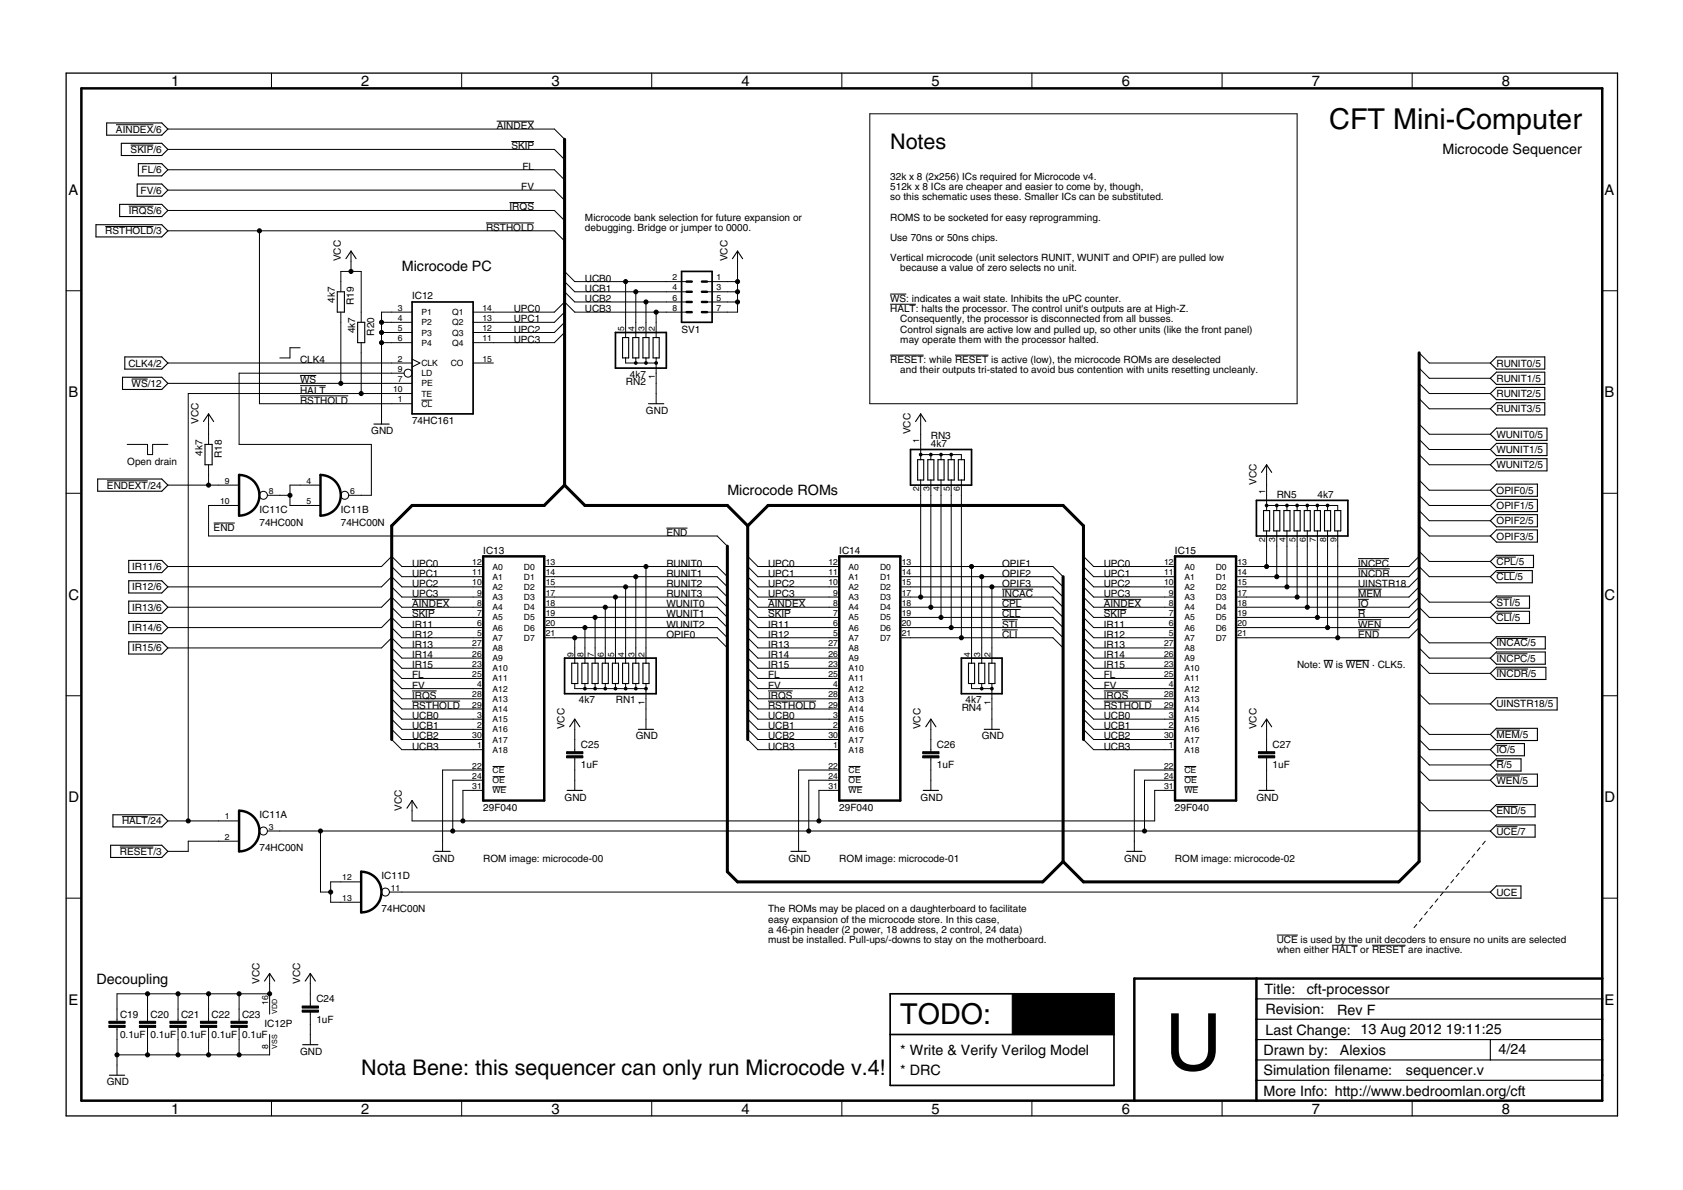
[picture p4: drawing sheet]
<svg xmlns="http://www.w3.org/2000/svg" width="420mm" height="297mm" viewBox="0 0 420 297" stroke-linecap="round" stroke-linejoin="round" font-family="sans-serif">
<defs><g id="words">
<text font-size="19.7" x="290.8" y="267.1">U</text>
<g font-size="7.2">
<text x="331.8" y="32.2">CFT Mini-Computer</text>
<text x="224.8" y="255.7">TODO:</text>
</g>
<g font-size="5.4">
<text x="222.2" y="37.3">Notes</text>
<text x="90.2" y="268.4">Nota Bene: this sequencer can only run Microcode v.4!</text>
</g>
<g font-size="3.7">
<text x="42.7" y="21.5">1</text>
<text x="90.2" y="21.5">2</text>
<text x="137.7" y="21.5">3</text>
<text x="185.1" y="21.5">4</text>
<text x="232.6" y="21.5">5</text>
<text x="280" y="21.5">6</text>
<text x="327.5" y="21.5">7</text>
<text x="375" y="21.5">8</text>
<text x="17.1" y="48.6">A</text>
<text x="400.6" y="48.6">A</text>
<text x="17.1" y="99.2">B</text>
<text x="400.6" y="99.2">B</text>
<text x="17.1" y="149.7">C</text>
<text x="400.6" y="149.7">C</text>
<text x="17.1" y="200.2">D</text>
<text x="400.6" y="200.2">D</text>
<text x="17.1" y="250.8">E</text>
<text x="400.6" y="250.8">E</text>
<text x="42.7" y="277.9">1</text>
<text x="90.2" y="277.9">2</text>
<text x="137.7" y="277.9">3</text>
<text x="185.1" y="277.9">4</text>
<text x="232.6" y="277.9">5</text>
<text x="280" y="277.9">6</text>
<text x="327.5" y="277.9">7</text>
<text x="375" y="277.9">8</text>
</g>
<g font-size="3.6">
<text x="360.1" y="38.6">Microcode Sequencer</text>
<text x="100.3" y="67.8">Microcode PC</text>
<text x="181.6" y="123.6">Microcode ROMs</text>
<text x="24.1" y="245.5">Decoupling</text>
<text x="315.7" y="248.1">Title:</text>
<text x="326.2" y="248.2">cft-processor</text>
<text x="315.9" y="253.2">Revision:</text>
<text x="333.8" y="253.3">Rev F</text>
<text x="224.8" y="263.3">* Write &amp; Verify Verilog Model</text>
<text x="315.4" y="263.3">Drawn by:</text>
<text x="315.9" y="258.2">Last Change: 13 Aug 2012</text>
<text x="334.5" y="263.3">Alexios</text>
<text x="361" y="258.1">19:11:25</text>
<text x="374.1" y="263.2">4/24</text>
<text x="224.8" y="268.4">* DRC</text>
<text x="315.4" y="268.4">Simulation filename:</text>
<text x="351" y="268.4">sequencer.v</text>
<text x="315.4" y="273.5">More Info: http://www.bedroomlan.org/cft</text>
</g>
<g font-size="2.5">
<text x="29" y="33.1">AINDEX/6</text>
<text x="124" y="32.2">AINDEX</text>
<text x="32.6" y="38.2">SKIP/6</text>
<text x="127.7" y="37.3">SKIP</text>
<text x="35.4" y="43.3">FL/6</text>
<text x="130.1" y="47.4">FV</text>
<text x="130.4" y="42.4">FL</text>
<text x="222.2" y="44.9">32k x 8 (2x256) ICs required for Microcode v4.</text>
<text x="222.2" y="47.4">512k x 8 ICs are cheaper and easier to come by, though,</text>
<text x="32.1" y="53.4">IRQS/6</text>
<text x="35.1" y="48.3">FV/6</text>
<text x="127.2" y="52.5">IRQS</text>
<text x="222.2" y="50">so this schematic uses these. Smaller ICs can be substituted.</text>
<text x="26.3" y="58.5">RSTHOLD/3</text>
<text x="121.3" y="57.6">RSTHOLD</text>
<text x="146" y="55.1">Microcode bank selection for future expansion or</text>
<text x="146" y="57.6">debugging. Bridge or jumper to 0000.</text>
<text x="222.2" y="55.1">ROMS to be socketed for easy reprogramming.</text>
<text x="85.1" y="65.2" transform="rotate(-90 85.1 65.2)">VCC</text>
<text x="181.6" y="65.2" transform="rotate(-90 181.6 65.2)">VCC</text>
<text x="222.2" y="60.1">Use 70ns or 50ns chips.</text>
<text x="222.2" y="65.2">Vertical microcode (unit selectors RUNIT, WUNIT and OPIF) are pulled low</text>
<text x="146" y="70.3">UCB0</text>
<text x="224.8" y="67.8">because a value of zero selects no unit.</text>
<text x="83.6" y="75.6" transform="rotate(-90 83.6 75.6)">4k7</text>
<text x="88.4" y="76.2" transform="rotate(-90 88.4 76.2)">R19</text>
<text x="102.9" y="74.7">IC12</text>
<text x="128.3" y="77.9">UPC0</text>
<text x="146" y="72.8">UCB1</text>
<text x="146" y="75.4">UCB2</text>
<text x="146" y="77.9">UCB3</text>
<text x="222.2" y="75.4">WS: indicates a wait state. Inhibits the uPC counter.</text>
<text x="222.2" y="77.9">HALT: halts the processor. The control unit's outputs are at High-Z.</text>
<text x="88.6" y="83.2" transform="rotate(-90 88.6 83.2)">4k7</text>
<text x="93.4" y="83.8" transform="rotate(-90 93.4 83.8)">R20</text>
<text x="128.3" y="80.5">UPC1</text>
<text x="128.3" y="83">UPC2</text>
<text x="170.2" y="83">SV1</text>
<text x="224.8" y="80.5">Consequently, the processor is disconnected from all busses.</text>
<text x="224.8" y="83">Control signals are active low and pulled up, so other units (like the front panel)</text>
<text x="128.3" y="85.5">UPC3</text>
<text x="224.8" y="85.5">may operate them with the processor halted.</text>
<text x="32" y="91.5">CLK4/2</text>
<text x="74.9" y="95.7">WS</text>
<text x="74.9" y="90.6">CLK4</text>
<text x="157.2" y="94.3">4k7</text>
<text x="222.2" y="90.6">RESET: while RESET is active (low), the microcode ROMs are deselected</text>
<text x="224.8" y="93.2">and their outputs tri-stated to avoid bus contention with units resetting uncleanly.</text>
<text x="373.6" y="91.5">RUNIT0/5</text>
<text x="373.6" y="95.3">RUNIT1/5</text>
<text x="32.9" y="96.6">WS/12</text>
<text x="74.9" y="100.8">RSTHOLD</text>
<text x="74.9" y="98.2">HALT</text>
<text x="156.3" y="96.2">RN2</text>
<text x="373.6" y="99.1">RUNIT2/5</text>
<text x="49.5" y="105.9" transform="rotate(-90 49.5 105.9)">VCC</text>
<text x="102.9" y="105.9">74HC161</text>
<text x="161.3" y="103.3">GND</text>
<text x="373.6" y="102.9">RUNIT3/5</text>
<text x="50.5" y="113.7" transform="rotate(-90 50.5 113.7)">4k7</text>
<text x="92.7" y="108.4">GND</text>
<text x="227.3" y="108.4" transform="rotate(-90 227.3 108.4)">VCC</text>
<text x="232.4" y="111.6">4k7</text>
<text x="232.4" y="109.7">RN3</text>
<text x="373.6" y="109.3">WUNIT0/5</text>
<text x="373.6" y="113.1">WUNIT1/5</text>
<text x="31.7" y="116">Open drain</text>
<text x="55.3" y="114.3" transform="rotate(-90 55.3 114.3)">R18</text>
<text x="373.6" y="116.9">WUNIT2/5</text>
<text x="26.7" y="122">ENDEXT/24</text>
<text x="313.7" y="121.1" transform="rotate(-90 313.7 121.1)">VCC</text>
<text x="318.7" y="124.3">RN5</text>
<text x="328.9" y="124.3">4k7</text>
<text x="373.6" y="123.3">OPIF0/5</text>
<text x="64.8" y="131.3">74HC00N</text>
<text x="64.8" y="128.1">IC11C</text>
<text x="85.1" y="131.3">74HC00N</text>
<text x="85.1" y="128.1">IC11B</text>
<text x="373.6" y="127.1">OPIF1/5</text>
<text x="373.6" y="130.9">OPIF2/5</text>
<text x="53.3" y="132.5">END</text>
<text x="166.4" y="133.8">END</text>
<text x="373.6" y="134.7">OPIF3/5</text>
<text x="33" y="142.3">IR11/6</text>
<text x="102.9" y="141.4">UPC0</text>
<text x="102.9" y="144">UPC1</text>
<text x="120.6" y="138.2">IC13</text>
<text x="166.4" y="141.4">RUNIT0</text>
<text x="166.4" y="144">RUNIT1</text>
<text x="191.7" y="141.4">UPC0</text>
<text x="191.7" y="144">UPC1</text>
<text x="209.5" y="138.2">IC14</text>
<text x="250.2" y="141.4">OPIF1</text>
<text x="250.2" y="144">OPIF2</text>
<text x="275.6" y="141.4">UPC0</text>
<text x="275.6" y="144">UPC1</text>
<text x="293.3" y="138.2">IC15</text>
<text x="339.1" y="144">INCDR</text>
<text x="339.1" y="141.4">INCPC</text>
<text x="373.6" y="141">CPL/5</text>
<text x="33" y="147.4">IR12/6</text>
<text x="102.9" y="146.5">UPC2</text>
<text x="102.9" y="149">UPC3</text>
<text x="166.4" y="146.5">RUNIT2</text>
<text x="166.4" y="149">RUNIT3</text>
<text x="191.7" y="146.5">UPC2</text>
<text x="191.7" y="149">UPC3</text>
<text x="250.2" y="149">INCAC</text>
<text x="250.2" y="146.5">OPIF3</text>
<text x="275.6" y="146.5">UPC2</text>
<text x="275.6" y="149">UPC3</text>
<text x="339.1" y="149">MEM</text>
<text x="339.1" y="146.5">UINSTR18</text>
<text x="373.6" y="144.8">CLL/5</text>
<text x="33" y="152.5">IR13/6</text>
<text x="102.9" y="151.6">AINDEX</text>
<text x="102.9" y="154.1">SKIP</text>
<text x="166.4" y="151.6">WUNIT0</text>
<text x="166.4" y="154.1">WUNIT1</text>
<text x="191.7" y="151.6">AINDEX</text>
<text x="191.7" y="154.1">SKIP</text>
<text x="250.2" y="154.1">CLL</text>
<text x="250.2" y="151.6">CPL</text>
<text x="275.6" y="151.6">AINDEX</text>
<text x="275.6" y="154.1">SKIP</text>
<text x="339.1" y="151.6">IO</text>
<text x="339.1" y="154.1">R</text>
<text x="373.6" y="155">CLI/5</text>
<text x="373.6" y="151.2">STI/5</text>
<text x="33" y="157.5">IR14/6</text>
<text x="102.9" y="156.6">IR11</text>
<text x="102.9" y="159.2">IR12</text>
<text x="102.9" y="161.7">IR13</text>
<text x="166.4" y="156.6">WUNIT2</text>
<text x="166.4" y="159.2">OPIF0</text>
<text x="191.7" y="156.6">IR11</text>
<text x="191.7" y="159.2">IR12</text>
<text x="191.7" y="161.7">IR13</text>
<text x="250.2" y="159.2">CLI</text>
<text x="250.2" y="156.6">STI</text>
<text x="275.6" y="156.6">IR11</text>
<text x="275.6" y="159.2">IR12</text>
<text x="275.6" y="161.7">IR13</text>
<text x="339.1" y="156.6">WEN</text>
<text x="339.1" y="159.2">END</text>
<text x="373.6" y="161.3">INCAC/5</text>
<text x="33" y="162.6">IR15/6</text>
<text x="102.9" y="164.3">IR14</text>
<text x="102.9" y="166.8">IR15</text>
<text x="191.7" y="164.3">IR14</text>
<text x="191.7" y="166.8">IR15</text>
<text x="275.6" y="164.3">IR14</text>
<text x="275.6" y="166.8">IR15</text>
<text x="323.8" y="166.8">Note: W is WEN · CLK5.</text>
<text x="373.6" y="165.2">INCPC/5</text>
<text x="102.9" y="171.9">FV</text>
<text x="102.9" y="169.3">FL</text>
<text x="191.7" y="171.9">FV</text>
<text x="191.7" y="169.3">FL</text>
<text x="275.6" y="171.9">FV</text>
<text x="275.6" y="169.3">FL</text>
<text x="373.6" y="169">INCDR/5</text>
<text x="102.9" y="177">RSTHOLD</text>
<text x="102.9" y="174.4">IRQS</text>
<text x="102.9" y="179.5">UCB0</text>
<text x="144.5" y="175.6">4k7</text>
<text x="153.7" y="175.6">RN1</text>
<text x="191.7" y="177">RSTHOLD</text>
<text x="191.7" y="174.4">IRQS</text>
<text x="191.7" y="179.5">UCB0</text>
<text x="240.1" y="177.5">RN4</text>
<text x="241" y="175.6">4k7</text>
<text x="275.6" y="177">RSTHOLD</text>
<text x="275.6" y="174.4">IRQS</text>
<text x="275.6" y="179.5">UCB0</text>
<text x="373.6" y="176.6">UINSTR18/5</text>
<text x="102.9" y="182">UCB1</text>
<text x="102.9" y="184.6">UCB2</text>
<text x="141" y="182" transform="rotate(-90 141 182)">VCC</text>
<text x="158.7" y="184.6">GND</text>
<text x="191.7" y="182">UCB1</text>
<text x="191.7" y="184.6">UCB2</text>
<text x="229.8" y="182" transform="rotate(-90 229.8 182)">VCC</text>
<text x="245.1" y="184.6">GND</text>
<text x="275.6" y="182">UCB1</text>
<text x="275.6" y="184.6">UCB2</text>
<text x="313.7" y="182" transform="rotate(-90 313.7 182)">VCC</text>
<text x="373.6" y="184.2">MEM/5</text>
<text x="102.9" y="187.1">UCB3</text>
<text x="145" y="191.8">1uF</text>
<text x="145" y="186.7">C25</text>
<text x="191.7" y="187.1">UCB3</text>
<text x="233.9" y="191.8">1uF</text>
<text x="233.9" y="186.7">C26</text>
<text x="275.6" y="187.1">UCB3</text>
<text x="317.7" y="191.8">1uF</text>
<text x="317.7" y="186.7">C27</text>
<text x="373.6" y="188">IO/5</text>
<text x="373.6" y="191.8">R/5</text>
<text x="373.6" y="195.6">WEN/5</text>
<text x="100.3" y="202.4" transform="rotate(-90 100.3 202.4)">VCC</text>
<text x="120.6" y="202.4">29F040</text>
<text x="141" y="199.8">GND</text>
<text x="209.5" y="202.4">29F040</text>
<text x="229.8" y="199.8">GND</text>
<text x="293.3" y="202.4">29F040</text>
<text x="313.7" y="199.8">GND</text>
<text x="373.6" y="203.2">END/5</text>
<text x="30.5" y="205.8">HALT/24</text>
<text x="64.8" y="204.3">IC11A</text>
<text x="373.6" y="208.3">UCE/7</text>
<text x="29.9" y="213.4">RESET/3</text>
<text x="64.8" y="212.5">74HC00N</text>
<text x="107.9" y="215.1">GND</text>
<text x="120.6" y="215.1">ROM image: microcode-00</text>
<text x="196.8" y="215.1">GND</text>
<text x="209.5" y="215.1">ROM image: microcode-01</text>
<text x="280.6" y="215.1">GND</text>
<text x="293.3" y="215.1">ROM image: microcode-02</text>
<text x="95.2" y="219.5">IC11D</text>
<text x="95.2" y="227.8">74HC00N</text>
<text x="191.7" y="227.8">The ROMs may be placed on a daughterboard to facilitate</text>
<text x="373.6" y="223.6">UCE</text>
<text x="191.7" y="230.3">easy expansion of the microcode store. In this case,</text>
<text x="191.7" y="232.8">a 46-pin header (2 power, 18 address, 2 control, 24 data)</text>
<text x="191.7" y="235.4">must be installed. Pull-ups/-downs to stay on the motherboard.</text>
<text x="318.7" y="235.4">UCE is used by the unit decoders to ensure no units are selected</text>
<text x="318.7" y="237.9">when either HALT or RESET are inactive.</text>
<text x="64.8" y="245.5" transform="rotate(-90 64.8 245.5)">VCC</text>
<text x="74.9" y="245.5" transform="rotate(-90 74.9 245.5)">VCC</text>
<text x="79" y="250.2">C24</text>
<text x="30" y="254">C19</text>
<text x="37.6" y="254">C20</text>
<text x="45.2" y="254">C21</text>
<text x="52.8" y="254">C22</text>
<text x="60.4" y="254">C23</text>
<text x="66" y="256.3">IC12P</text>
<text x="79" y="255.3">1uF</text>
<text x="30" y="259.1">0.1uF</text>
<text x="37.6" y="259.1">0.1uF</text>
<text x="45.2" y="259.1">0.1uF</text>
<text x="52.8" y="259.1">0.1uF</text>
<text x="60.4" y="259.1">0.1uF</text>
<text x="74.9" y="263.3">GND</text>
<text x="26.7" y="270.9">GND</text>
</g>
<g font-size="2.1">
<text x="167.9" y="69.9">2</text>
<text x="178.8" y="69.9">1</text>
<text x="99.3" y="77.6">3</text>
<text x="120.4" y="77.6">14</text>
<text x="167.9" y="72.5">4</text>
<text x="167.9" y="75">6</text>
<text x="167.9" y="77.6">8</text>
<text x="178.8" y="72.5">3</text>
<text x="178.8" y="75">5</text>
<text x="178.8" y="77.6">7</text>
<text x="99.3" y="80.1">4</text>
<text x="99.3" y="82.6">5</text>
<text x="105.2" y="78.7">P1</text>
<text x="105.2" y="81.2">P2</text>
<text x="105.2" y="83.8">P3</text>
<text x="112.9" y="83.8">Q3</text>
<text x="112.9" y="81.2">Q2</text>
<text x="112.9" y="78.7">Q1</text>
<text x="120.4" y="82.6">12</text>
<text x="120.4" y="80.1">13</text>
<text x="155.8" y="82.6" transform="rotate(-90 155.8 82.6)">5</text>
<text x="158.4" y="82.6" transform="rotate(-90 158.4 82.6)">4</text>
<text x="160.9" y="82.6" transform="rotate(-90 160.9 82.6)">3</text>
<text x="163.5" y="82.6" transform="rotate(-90 163.5 82.6)">2</text>
<text x="99.3" y="85.2">6</text>
<text x="105.2" y="86.3">P4</text>
<text x="112.9" y="86.3">Q4</text>
<text x="120.4" y="85.2">11</text>
<text x="99.3" y="90.3">2</text>
<text x="99.3" y="95.3">7</text>
<text x="99.3" y="92.8">9</text>
<text x="105.2" y="91.4">CLK</text>
<text x="105.2" y="93.9">LD</text>
<text x="112.6" y="91.4">CO</text>
<text x="120.4" y="90.3">15</text>
<text x="163.5" y="94.7" transform="rotate(-90 163.5 94.7)">1</text>
<text x="98.2" y="97.9">10</text>
<text x="99.3" y="100.4">1</text>
<text x="105.2" y="101.5">CL</text>
<text x="105.2" y="96.5">PE</text>
<text x="105.2" y="99">TE</text>
<text x="229.5" y="110.6" transform="rotate(-90 229.5 110.6)">1</text>
<text x="55" y="125.8">10</text>
<text x="56.2" y="120.7">9</text>
<text x="67.1" y="123.3">8</text>
<text x="76.5" y="120.7">4</text>
<text x="76.5" y="125.8">5</text>
<text x="87.4" y="123.3">6</text>
<text x="229.5" y="122.6" transform="rotate(-90 229.5 122.6)">2</text>
<text x="232" y="122.6" transform="rotate(-90 232 122.6)">3</text>
<text x="234.6" y="122.6" transform="rotate(-90 234.6 122.6)">4</text>
<text x="237.1" y="122.6" transform="rotate(-90 237.1 122.6)">5</text>
<text x="239.6" y="122.6" transform="rotate(-90 239.6 122.6)">6</text>
<text x="315.8" y="123.3" transform="rotate(-90 315.8 123.3)">1</text>
<text x="315.8" y="135.3" transform="rotate(-90 315.8 135.3)">2</text>
<text x="318.4" y="135.3" transform="rotate(-90 318.4 135.3)">3</text>
<text x="320.9" y="135.3" transform="rotate(-90 320.9 135.3)">4</text>
<text x="323.5" y="135.3" transform="rotate(-90 323.5 135.3)">5</text>
<text x="326" y="135.3" transform="rotate(-90 326 135.3)">6</text>
<text x="328.5" y="135.3" transform="rotate(-90 328.5 135.3)">7</text>
<text x="331.1" y="135.3" transform="rotate(-90 331.1 135.3)">8</text>
<text x="333.6" y="135.3" transform="rotate(-90 333.6 135.3)">9</text>
<text x="117.9" y="143.6">11</text>
<text x="117.9" y="141.1">12</text>
<text x="123" y="142.2">A0</text>
<text x="130.8" y="142.2">D0</text>
<text x="136.2" y="141.1">13</text>
<text x="136.2" y="143.6">14</text>
<text x="206.8" y="143.6">11</text>
<text x="206.8" y="141.1">12</text>
<text x="211.9" y="142.2">A0</text>
<text x="219.7" y="142.2">D0</text>
<text x="225.1" y="141.1">13</text>
<text x="225.1" y="143.6">14</text>
<text x="290.6" y="143.6">11</text>
<text x="290.6" y="141.1">12</text>
<text x="295.7" y="142.2">A0</text>
<text x="303.5" y="142.2">D0</text>
<text x="308.9" y="141.1">13</text>
<text x="308.9" y="143.6">14</text>
<text x="117.9" y="146.1">10</text>
<text x="119.1" y="148.7">9</text>
<text x="123" y="149.8">A3</text>
<text x="123" y="147.3">A2</text>
<text x="123" y="144.7">A1</text>
<text x="130.8" y="144.7">D1</text>
<text x="130.8" y="147.3">D2</text>
<text x="130.8" y="149.8">D3</text>
<text x="136.2" y="146.1">15</text>
<text x="136.2" y="148.7">17</text>
<text x="206.8" y="146.1">10</text>
<text x="208" y="148.7">9</text>
<text x="211.9" y="149.8">A3</text>
<text x="211.9" y="147.3">A2</text>
<text x="211.9" y="144.7">A1</text>
<text x="219.7" y="144.7">D1</text>
<text x="219.7" y="147.3">D2</text>
<text x="219.7" y="149.8">D3</text>
<text x="225.1" y="146.1">15</text>
<text x="225.1" y="148.7">17</text>
<text x="290.6" y="146.1">10</text>
<text x="291.8" y="148.7">9</text>
<text x="295.7" y="149.8">A3</text>
<text x="295.7" y="147.3">A2</text>
<text x="295.7" y="144.7">A1</text>
<text x="303.5" y="144.7">D1</text>
<text x="303.5" y="147.3">D2</text>
<text x="303.5" y="149.8">D3</text>
<text x="308.9" y="146.1">15</text>
<text x="308.9" y="148.7">17</text>
<text x="119.1" y="153.8">7</text>
<text x="119.1" y="151.2">8</text>
<text x="123" y="154.9">A5</text>
<text x="123" y="152.3">A4</text>
<text x="130.8" y="152.3">D4</text>
<text x="130.8" y="154.9">D5</text>
<text x="136.2" y="151.2">18</text>
<text x="136.2" y="153.8">19</text>
<text x="208" y="153.8">7</text>
<text x="208" y="151.2">8</text>
<text x="211.9" y="154.9">A5</text>
<text x="211.9" y="152.3">A4</text>
<text x="219.7" y="152.3">D4</text>
<text x="219.7" y="154.9">D5</text>
<text x="225.1" y="151.2">18</text>
<text x="225.1" y="153.8">19</text>
<text x="291.8" y="153.8">7</text>
<text x="291.8" y="151.2">8</text>
<text x="295.7" y="154.9">A5</text>
<text x="295.7" y="152.3">A4</text>
<text x="303.5" y="152.3">D4</text>
<text x="303.5" y="154.9">D5</text>
<text x="308.9" y="151.2">18</text>
<text x="308.9" y="153.8">19</text>
<text x="117.9" y="161.4">27</text>
<text x="119.1" y="158.8">5</text>
<text x="119.1" y="156.3">6</text>
<text x="123" y="159.9">A7</text>
<text x="123" y="157.4">A6</text>
<text x="130.8" y="157.4">D6</text>
<text x="130.8" y="160">D7</text>
<text x="136.2" y="156.3">20</text>
<text x="136.2" y="158.8">21</text>
<text x="206.8" y="161.4">27</text>
<text x="208" y="158.8">5</text>
<text x="208" y="156.3">6</text>
<text x="211.9" y="159.9">A7</text>
<text x="211.9" y="157.4">A6</text>
<text x="219.7" y="157.4">D6</text>
<text x="219.7" y="160">D7</text>
<text x="225.1" y="156.3">20</text>
<text x="225.1" y="158.8">21</text>
<text x="290.6" y="161.4">27</text>
<text x="291.8" y="158.8">5</text>
<text x="291.8" y="156.3">6</text>
<text x="295.7" y="159.9">A7</text>
<text x="295.7" y="157.4">A6</text>
<text x="303.5" y="157.4">D6</text>
<text x="303.5" y="160">D7</text>
<text x="308.9" y="156.3">20</text>
<text x="308.9" y="158.8">21</text>
<text x="117.9" y="166.5">23</text>
<text x="117.9" y="163.9">26</text>
<text x="123" y="167.6">A10</text>
<text x="123" y="165">A9</text>
<text x="123" y="162.5">A8</text>
<text x="143.1" y="163.9" transform="rotate(-90 143.1 163.9)">9</text>
<text x="145.7" y="163.9" transform="rotate(-90 145.7 163.9)">8</text>
<text x="148.2" y="163.9" transform="rotate(-90 148.2 163.9)">7</text>
<text x="150.8" y="163.9" transform="rotate(-90 150.8 163.9)">6</text>
<text x="153.3" y="163.9" transform="rotate(-90 153.3 163.9)">5</text>
<text x="155.8" y="163.9" transform="rotate(-90 155.8 163.9)">4</text>
<text x="158.4" y="163.9" transform="rotate(-90 158.4 163.9)">3</text>
<text x="160.9" y="163.9" transform="rotate(-90 160.9 163.9)">2</text>
<text x="206.8" y="166.5">23</text>
<text x="206.8" y="163.9">26</text>
<text x="211.9" y="167.6">A10</text>
<text x="211.9" y="165">A9</text>
<text x="211.9" y="162.5">A8</text>
<text x="242.2" y="163.9" transform="rotate(-90 242.2 163.9)">4</text>
<text x="244.7" y="163.9" transform="rotate(-90 244.7 163.9)">3</text>
<text x="247.3" y="163.9" transform="rotate(-90 247.3 163.9)">2</text>
<text x="290.6" y="166.5">23</text>
<text x="290.6" y="163.9">26</text>
<text x="295.7" y="167.6">A10</text>
<text x="295.7" y="165">A9</text>
<text x="295.7" y="162.5">A8</text>
<text x="117.9" y="169">25</text>
<text x="119.1" y="171.5">4</text>
<text x="123" y="172.6">A12</text>
<text x="123" y="170.1">A11</text>
<text x="206.8" y="169">25</text>
<text x="208" y="171.5">4</text>
<text x="211.9" y="172.6">A12</text>
<text x="211.9" y="170.1">A11</text>
<text x="290.6" y="169">25</text>
<text x="291.8" y="171.5">4</text>
<text x="295.7" y="172.6">A12</text>
<text x="295.7" y="170.1">A11</text>
<text x="117.9" y="174.1">28</text>
<text x="117.9" y="176.6">29</text>
<text x="119.1" y="179.1">3</text>
<text x="123" y="175.2">A13</text>
<text x="123" y="177.7">A14</text>
<text x="160.9" y="176" transform="rotate(-90 160.9 176)">1</text>
<text x="206.8" y="174.1">28</text>
<text x="206.8" y="176.6">29</text>
<text x="208" y="179.1">3</text>
<text x="211.9" y="175.2">A13</text>
<text x="211.9" y="177.7">A14</text>
<text x="247.3" y="176" transform="rotate(-90 247.3 176)">1</text>
<text x="290.6" y="174.1">28</text>
<text x="290.6" y="176.6">29</text>
<text x="291.8" y="179.1">3</text>
<text x="295.7" y="175.2">A13</text>
<text x="295.7" y="177.7">A14</text>
<text x="117.9" y="184.2">30</text>
<text x="119.1" y="181.7">2</text>
<text x="123" y="180.3">A15</text>
<text x="123" y="182.8">A16</text>
<text x="123" y="185.3">A17</text>
<text x="206.8" y="184.2">30</text>
<text x="208" y="181.7">2</text>
<text x="211.9" y="180.3">A15</text>
<text x="211.9" y="182.8">A16</text>
<text x="211.9" y="185.3">A17</text>
<text x="290.6" y="184.2">30</text>
<text x="291.8" y="181.7">2</text>
<text x="295.7" y="180.3">A15</text>
<text x="295.7" y="182.8">A16</text>
<text x="295.7" y="185.3">A17</text>
<text x="117.9" y="191.8">22</text>
<text x="119.1" y="186.8">1</text>
<text x="123" y="187.9">A18</text>
<text x="206.8" y="191.8">22</text>
<text x="208" y="186.8">1</text>
<text x="211.9" y="187.9">A18</text>
<text x="290.6" y="191.8">22</text>
<text x="291.8" y="186.8">1</text>
<text x="295.7" y="187.9">A18</text>
<text x="117.9" y="196.9">31</text>
<text x="117.9" y="194.4">24</text>
<text x="123" y="193">CE</text>
<text x="123" y="195.5">OE</text>
<text x="206.8" y="196.9">31</text>
<text x="206.8" y="194.4">24</text>
<text x="211.9" y="193">CE</text>
<text x="211.9" y="195.5">OE</text>
<text x="290.6" y="196.9">31</text>
<text x="290.6" y="194.4">24</text>
<text x="295.7" y="193">CE</text>
<text x="295.7" y="195.5">OE</text>
<text x="123" y="198">WE</text>
<text x="211.9" y="198">WE</text>
<text x="295.7" y="198">WE</text>
<text x="56.2" y="204.5">1</text>
<text x="56.2" y="209.6">2</text>
<text x="67.1" y="207.1">3</text>
<text x="85.5" y="219.8">12</text>
<text x="85.5" y="224.9">13</text>
<text x="97.6" y="222.3">11</text>
<text x="66.9" y="250.8" transform="rotate(-90 66.9 250.8)">16</text>
<text x="66.9" y="261.8" transform="rotate(-90 66.9 261.8)">8</text>
</g>
<g font-size="1.8">
<text x="69.2" y="253.2" transform="rotate(-90 69.2 253.2)">VDD</text>
<text x="69.2" y="261.8" transform="rotate(-90 69.2 261.8)">VSS</text>
</g>
</g></defs>
<g fill="#000" stroke="#000" stroke-width=".25">
<path d="M67.8 18.2v3.9zM115.3 18.2v3.9zM162.7 18.2v3.9zM210.2 18.2v3.9zM257.6 18.2v3.9zM305.1 18.2v3.9zM352.5 18.2v3.9zM20.3 22.1v252.6zM29 31.1h9.3zM32.6 36.2h5.7zM124 30.2h9.3zM127.7 35.3h5.6z"/>
<path d="M41.9 32.2h96.5zM41.9 37.3h96.5zM138.4 32.2l2.5 2.6zM138.4 37.3l2.5 2.5zM217.1 28.4v72.4zM217.1 28.4h106.7zM20.3 22.1h379.7zM26.3 56.5h12zM32.2 51.5h6.1zM41.9 57.6h22.9zM64.8 57.6v43.2zM121.3 55.6h12z"/>
<path d="M127.2 50.6h6.1zM64.8 57.6h73.6zM41.9 52.5h96.5zM41.9 47.5h96.5zM41.9 42.4h96.5zM138.4 52.5l2.5 2.6zM138.4 47.5l2.5 2.5zM138.4 42.4l2.5 2.5zM16.5 72.6h3.8zM85.1 70.3v2.5zM85.1 67.8v2.5zM85.1 67.8h2.5z"/>
<path d="M87.6 62.7v2.5zM87.6 67.8h2.6zM87.6 65.2v2.6zM90.2 77.9v2.6zM90.2 67.8v10.1zM95.2 77.9v2.6zM97.8 77.9h5.1zM95.2 77.9h2.6zM118.1 77.9h5.1zM123.2 77.9h15.2zM140.9 75.4l-2.5 2.5zM138.4 57.6l2.5 2.6z"/>
<path d="M140.9 67.8l2.6 2.5zM140.9 70.3l2.6 2.5zM140.9 72.8l2.6 2.6zM140.9 75.4l2.6 2.5zM143.5 70.3h12.7zM143.5 72.8h15.2zM143.5 75.4h17.8zM143.5 77.9h20.3zM156.2 70.3h10.1zM158.7 72.8h7.6zM161.3 75.4h5zM163.8 77.9h2.5z"/>
<path d="M166.3 70.3h5.1zM166.3 72.8h5.1zM166.3 75.4h5.1zM166.3 77.9h5.1zM176.5 70.3h5.1zM176.5 72.8h5.1zM176.5 75.4h5.1zM176.5 77.9h5.1zM181.6 70.3h2.5zM181.6 72.8h2.5zM181.6 75.4h2.5zM181.6 77.9h2.5z"/>
<path d="M184.1 62.7v2.5zM184.1 70.3v2.5zM184.1 72.8v2.6zM184.1 75.4v2.5zM184.1 65.2v5.1zM222.2 73.4h4zM222.2 75.9h6.4zM400 72.6h3.8zM32.9 94.6h4zM47 98.2v106.7zM69.8 89.3h2.6zM72.4 86.8v2.5z"/>
<path d="M72.4 86.8h2.5zM74.9 98.8h12zM74.9 96.3h6.4zM74.9 93.7h4.1zM85.1 77.9v2.6zM85.1 80.5v15.2zM41.9 95.7h43.2zM90.2 85.5v2.6zM90.2 88.1v10.1zM47 98.2h43.2zM95.2 80.5v2.5zM95.2 83v2.5z"/>
<path d="M95.2 85.5v17.8zM97.8 90.6h5.1zM97.8 80.5h5.1zM97.8 83h5.1zM97.8 85.5h5.1zM97.8 95.7h5.1zM97.8 93.2h3.1zM97.8 98.2h5.1zM95.2 80.5h2.6zM95.2 83h2.6zM95.2 85.5h2.6zM90.2 98.2h7.6z"/>
<path d="M85.1 95.7h12.7zM59.7 93.2h38.1zM41.9 90.6h55.9zM102.9 89.6l1.9 1zM102.9 91.6l1.9-1zM105.2 99.9h2.7zM118.1 85.5h5.1zM118.1 83h5.1zM118.1 80.5h5.1zM118.1 90.6h5.1zM123.2 80.5h15.2zM123.2 83h15.2z"/>
<path d="M123.2 85.5h15.2zM138.4 80.5l2.5-2.6zM138.4 83l2.5-2.5zM140.9 83l-2.5 2.5zM156.2 80.5v2.5zM156.2 89.3v1.3zM156.2 83v1.3zM156.2 70.3v10.2zM158.7 80.5v2.5zM158.7 89.3v1.3zM156.2 90.6h2.5zM158.7 83v1.3z"/>
<path d="M158.7 72.8v7.7zM161.3 80.5v2.5zM161.3 89.3v1.3zM158.7 90.6h2.6zM161.3 83v1.3zM161.3 75.4v5.1zM163.8 93.2v2.5zM163.8 80.5v2.5zM163.8 83v1.3zM163.8 89.3v1.3zM161.3 90.6h2.5zM163.8 90.6v2.6z"/>
<path d="M163.8 98.2v2.6zM163.8 95.7v2.5zM163.8 77.9v2.6zM222.2 88.6h8.4zM238.4 88.6h8.4zM354.3 88.1l2.5 2.5zM354.3 91.9l2.5 2.5zM354.3 95.7l2.5 2.5zM354.3 99.5l2.5 2.5zM356.8 90.6h15.3zM356.8 94.4h15.3zM356.8 98.2h15.3z"/>
<path d="M31.7 110.9h5.1zM36.8 110.9v2.6zM36.8 113.5h1.3zM38.1 110.9v2.6zM38.1 110.9h3.8zM52.1 103.3v2.6zM52.1 116v2.6zM52.1 108.4v2.5zM52.1 105.9v2.5zM52.1 118.6v2.5zM59.7 93.2v17.7zM59.7 110.9h33z"/>
<path d="M95.2 103.3v2.6zM97.8 100.8h5.1zM64.8 100.8h33zM217.1 100.8h106.7zM229.8 108.4v2.5zM229.8 119.8v1.3zM229.8 113.5v1.2zM229.8 113.5h2.6zM229.8 110.9v2.6zM229.8 103.3v2.6zM229.8 105.9v2.5zM232.4 113.5v1.2z"/>
<path d="M232.4 113.5h2.5zM234.9 113.5v1.2zM234.9 113.5h2.6zM237.5 113.5v1.2zM237.5 113.5h2.5zM240 113.5v1.2zM316.2 116v2.6zM316.2 118.6v2.5zM323.8 28.4v72.4zM354.3 105.9l2.5 2.5zM354.3 109.7l2.5 2.5zM354.3 113.5l2.5 2.5z"/>
<path d="M354.3 119.8l2.5 2.6zM356.8 102h15.3zM356.8 108.4h15.3zM356.8 112.2h15.3zM356.8 116h15.3zM16.5 123.1h3.8zM26.7 120h10.2zM52.1 133.8h126.9zM52.1 126.2v7.6zM52.1 126.2h2.5zM41.9 121.1h10.2zM53.3 130.6h5.3z"/>
<path d="M54.6 121.1h5.1zM54.6 126.2h5.1zM52.1 121.1h2.5zM66.7 123.6h3.1zM69.8 123.6h2.6zM72.4 121.1v2.5zM72.4 123.6v2.6zM72.4 126.2h2.5zM74.9 121.1h5.1zM74.9 126.2h5.1zM72.4 121.1h2.5zM87.1 123.6h3.1z"/>
<path d="M90.2 123.6h2.5zM92.7 110.9v12.7zM97.8 138.9l-2.6 2.5zM97.8 138.9l2.5 2.5zM166.3 131.8h5.3zM179 133.8l2.6 2.5zM186.7 138.9l2.5 2.5zM229.8 121.1v2.5zM229.8 123.6v25.4zM232.4 121.1v2.5zM232.4 119.8v1.3zM232.4 123.6v28z"/>
<path d="M234.9 121.1v2.5zM234.9 119.8v1.3zM234.9 123.6v30.5zM237.5 121.1v2.5zM237.5 119.8v1.3zM237.5 123.6v33.1zM240 121.1v2.5zM240 119.8v1.3zM240 123.6v35.6zM270.5 138.9l2.5 2.5zM316.2 121.1v2.5zM316.2 133.8v2.5z"/>
<path d="M316.2 132.5v1.3zM316.2 126.2v1.2zM316.2 126.2h2.5zM316.2 123.6v2.6zM316.2 136.3v5.1zM318.7 133.8v2.5zM318.7 126.2v1.2zM318.7 126.2h2.6zM318.7 132.5v1.3zM318.7 136.3v7.7zM321.3 133.8v2.5zM321.3 126.2v1.2z"/>
<path d="M321.3 126.2h2.5zM321.3 132.5v1.3zM321.3 136.3v10.2zM323.8 133.8v2.5zM323.8 126.2v1.2zM323.8 126.2h2.6zM323.8 132.5v1.3zM323.8 136.3v12.7zM326.4 133.8v2.5zM326.4 126.2v1.2zM326.4 132.5v1.3zM326.4 126.2h2.5z"/>
<path d="M326.4 136.3v15.3zM328.9 133.8v2.5zM328.9 132.5v1.3zM328.9 126.2v1.2zM328.9 126.2h2.5zM328.9 136.3v17.8zM331.4 133.8v2.5zM331.4 126.2v1.2zM331.4 126.2h2.6zM331.4 132.5v1.3zM331.4 136.3v20.4zM334 133.8v2.5z"/>
<path d="M334 126.2v1.2zM334 132.5v1.3zM334 136.3v22.9zM339 139.4h7.8zM354.3 138.9l-2.6 2.5zM354.3 137.6l2.5 2.5zM354.3 123.6l2.5 2.6zM354.3 127.4l2.5 2.6zM354.3 131.3l2.5 2.5zM356.8 122.4h15.3zM356.8 126.2h15.3zM356.8 130h15.3z"/>
<path d="M356.8 133.8h15.3zM373.6 139.1h4.8zM400 123.1h3.8zM41.9 146.5h53.3zM41.9 151.6h53.3zM41.9 156.7h53.3zM41.9 141.4h53.3zM95.2 146.5l2.6-2.5zM95.2 151.6l2.6-2.6zM97.8 154.1l-2.6 2.6zM97.8 149l2.5 2.6zM97.8 151.6l2.5 2.5z"/>
<path d="M97.8 154.1l2.5 2.6zM97.8 156.7l2.5 2.5zM97.8 159.2l2.5 2.5zM97.8 141.4l2.5 2.6zM97.8 144l2.5 2.5zM97.8 146.5l2.5 2.5zM100.3 151.6h17.8zM100.3 154.1h17.8zM100.3 156.7h17.8zM100.3 159.2h17.8zM100.3 141.4h17.8zM100.3 144h17.8z"/>
<path d="M100.3 146.5h17.8zM100.3 149h17.8zM102.9 149.6h9.3zM102.9 152.1h5.6zM118.1 159.2h2.5zM118.1 156.7h2.5zM118.1 154.1h2.5zM118.1 151.6h2.5zM118.1 149h2.5zM118.1 146.5h2.5zM118.1 144h2.5zM118.1 141.4h2.5z"/>
<path d="M135.9 141.4h2.5zM135.9 144h2.5zM135.9 146.5h2.5zM135.9 149h2.5zM135.9 151.6h2.5zM135.9 154.1h2.5zM135.9 156.7h2.5zM135.9 159.2h2.5zM138.4 141.4h22.9zM138.4 144h20.3zM138.4 146.5h17.8zM138.4 149h15.2z"/>
<path d="M138.4 151.6h12.7zM138.4 154.1h10.2zM138.4 156.7h7.6zM138.4 159.2h5.1zM143.5 159.2h35.5zM146 156.7h33zM148.6 154.1h30.4zM151.1 151.6h27.9zM158.7 144h20.3zM161.3 141.4h17.7zM156.2 146.5h22.8zM153.6 149h25.4z"/>
<path d="M179 141.4l2.6 2.6zM179 144l2.6 2.5zM179 146.5l2.6 2.5zM179 149l2.6 2.6zM179 151.6l2.6 2.5zM179 154.1l2.6 2.6zM179 156.7l2.6 2.5zM186.7 149l2.5 2.6zM186.7 151.6l2.5 2.5zM186.7 154.1l2.5 2.6zM186.7 156.7l2.5 2.5zM186.7 159.2l2.5 2.5z"/>
<path d="M186.7 141.4l2.5 2.6zM186.7 144l2.5 2.5zM186.7 146.5l2.5 2.5zM189.2 151.6h17.8zM189.2 154.1h17.8zM189.2 156.7h17.8zM189.2 159.2h17.8zM189.2 141.4h17.8zM189.2 144h17.8zM189.2 146.5h17.8zM189.2 149h17.8zM191.7 149.6h9.4z"/>
<path d="M191.7 152.1h5.7zM207 159.2h2.5zM207 156.7h2.5zM207 154.1h2.5zM207 151.6h2.5zM207 149h2.5zM207 146.5h2.5zM207 144h2.5zM207 141.4h2.5zM224.8 141.4h2.5zM224.8 144h2.5zM224.8 146.5h2.5z"/>
<path d="M224.8 149h2.5zM224.8 151.6h2.5zM224.8 154.1h2.5zM224.8 156.7h2.5zM224.8 159.2h2.5zM227.3 159.2h12.7zM227.3 149h2.5zM227.3 151.6h5.1zM227.3 154.1h7.6zM227.3 156.7h10.2zM240 159.2h22.9zM227.3 141.4h15.2z"/>
<path d="M227.3 144h17.8zM227.3 146.5h20.3zM250.2 157.2h3.9zM250.2 154.7h3.9zM250.2 152.1h4.6zM250.2 149.6h4.8zM250.2 147.1h7.7zM237.5 156.7h25.4zM234.9 154.1h28zM232.4 151.6h30.5zM229.8 149h33.1zM242.5 141.4h20.4z"/>
<path d="M245.1 144h17.8zM247.6 146.5h15.3zM262.9 156.7l2.5 2.5zM262.9 154.1l2.5 2.6zM262.9 151.6l2.5 2.5zM262.9 149l2.5 2.6zM262.9 141.4l2.5 2.6zM262.9 144l2.5 2.5zM262.9 146.5l2.5 2.5zM270.5 149l2.5 2.6zM270.5 151.6l2.5 2.5zM270.5 154.1l2.5 2.6z"/>
<path d="M270.5 156.7l2.5 2.5zM270.5 159.2l2.5 2.5zM270.5 141.4l2.5 2.6zM270.5 144l2.5 2.5zM270.5 146.5l2.5 2.5zM273 151.6h17.8zM273 154.1h17.8zM273 156.7h17.8zM273 159.2h17.8zM273 141.4h17.8zM273 144h17.8zM273 146.5h17.8z"/>
<path d="M273 149h17.8zM275.6 149.6h9.3zM275.6 152.1h5.6zM290.8 159.2h2.5zM290.8 156.7h2.5zM290.8 154.1h2.5zM290.8 151.6h2.5zM290.8 149h2.5zM290.8 146.5h2.5zM290.8 144h2.5zM290.8 141.4h2.5zM308.6 141.4h2.5z"/>
<path d="M308.6 144h2.5zM308.6 146.5h2.5zM308.6 149h2.5zM308.6 151.6h2.5zM308.6 154.1h2.5zM308.6 156.7h2.5zM308.6 159.2h2.5zM311.1 149h12.7zM311.1 151.6h15.3zM311.1 154.1h17.8zM311.1 156.7h20.3zM311.1 144h7.6z"/>
<path d="M311.1 141.4h5.1zM311.1 146.5h10.2zM311.1 159.2h22.9zM316.2 141.4h35.5zM318.7 144h33zM321.3 146.5h30.4zM339 147.1h5.9zM339 149.6h2.7zM339 152.1h1.8zM339 154.7h5.9zM339 142h8zM339 157.2h5.3z"/>
<path d="M323.8 149h27.9zM326.4 151.6h25.3zM328.9 154.1h22.8zM331.4 156.7h20.3zM334 159.2h17.7zM354.3 146.5l-2.6 2.5zM354.3 149l-2.6 2.6zM351.7 154.1l2.6-2.5zM354.3 154.1l-2.6 2.6zM354.3 141.4l-2.6 2.6zM354.3 151.6l2.5 2.5zM354.3 147.8l2.5 2.5z"/>
<path d="M354.3 141.4l2.5 2.6zM354.3 157.9l2.5 2.6zM351.7 146.5l2.6-2.5zM354.3 156.7l-2.6 2.5zM356.8 154.1h15.3zM356.8 150.3h15.3zM356.8 144h15.3zM356.8 140.1h15.3zM373.6 153h3.9zM373.6 149.2h3.9zM373.6 142.9h4.6zM373.6 159.4h7.8z"/>
<path d="M16.5 173.7h3.8zM41.9 161.7h53.3zM95.2 161.7l2.6-2.5zM97.8 174.4l2.5 2.6zM97.8 171.9l2.5 2.5zM97.8 161.7l2.5 2.6zM97.8 164.3l2.5 2.5zM97.8 169.4l2.5 2.5zM97.8 166.8l2.5 2.6zM97.8 177l2.5 2.5zM97.8 179.5l2.5 2.6zM100.3 177h17.8z"/>
<path d="M100.3 174.4h17.8zM100.3 161.7h17.8zM100.3 164.3h17.8zM100.3 166.8h17.8zM100.3 171.9h17.8zM100.3 169.4h17.8zM100.3 179.5h17.8zM102.9 175h12zM102.9 172.5h6.1zM118.1 171.9h2.5zM118.1 166.8h2.5zM118.1 169.4h2.5z"/>
<path d="M118.1 164.3h2.5zM118.1 161.7h2.5zM118.1 174.4h2.5zM118.1 177h2.5zM118.1 179.5h2.5zM143.5 161.7v2.6zM143.5 170.6v1.3zM143.5 164.3v1.2zM143.5 159.2v2.5zM146 161.7v2.6zM146 170.6v1.3zM143.5 171.9h2.5z"/>
<path d="M146 164.3v1.2zM146 156.7v5zM148.6 161.7v2.6zM148.6 164.3v1.2zM148.6 170.6v1.3zM146 171.9h2.6zM148.6 154.1v7.6zM151.1 161.7v2.6zM151.1 170.6v1.3zM151.1 164.3v1.2zM148.6 171.9h2.5zM151.1 151.6v10.1z"/>
<path d="M153.6 161.7v2.6zM153.6 170.6v1.3zM151.1 171.9h2.5zM153.6 164.3v1.2zM153.6 149v12.7zM156.2 161.7v2.6zM156.2 170.6v1.3zM153.6 171.9h2.6zM156.2 164.3v1.2zM156.2 146.5v15.2zM158.7 161.7v2.6zM158.7 170.6v1.3z"/>
<path d="M156.2 171.9h2.5zM158.7 164.3v1.2zM158.7 144v17.7zM161.3 174.4v2.6zM161.3 161.7v2.6zM161.3 164.3v1.2zM161.3 170.6v1.3zM158.7 171.9h2.6zM161.3 171.9v2.5zM161.3 179.5v2.6zM161.3 177v2.5zM161.3 141.4v20.3z"/>
<path d="M179 159.2l2.6 2.5zM186.7 174.4l2.5 2.6zM186.7 171.9l2.5 2.5zM186.7 161.7l2.5 2.6zM186.7 164.3l2.5 2.5zM186.7 169.4l2.5 2.5zM186.7 166.8l2.5 2.6zM186.7 177l2.5 2.5zM186.7 179.5l2.5 2.6zM189.2 177h17.8zM189.2 174.4h17.8zM189.2 161.7h17.8z"/>
<path d="M189.2 164.3h17.8zM189.2 166.8h17.8zM189.2 171.9h17.8zM189.2 169.4h17.8zM189.2 179.5h17.8zM191.7 175h12zM191.7 172.5h6.2zM207 171.9h2.5zM207 166.8h2.5zM207 169.4h2.5zM207 164.3h2.5zM207 161.7h2.5z"/>
<path d="M207 174.4h2.5zM207 177h2.5zM207 179.5h2.5zM242.5 161.7v2.6zM242.5 170.6v1.3zM242.5 164.3v1.2zM242.5 141.4v20.3zM245.1 161.7v2.6zM245.1 170.6v1.3zM242.5 171.9h2.6zM245.1 164.3v1.2zM245.1 144v17.7z"/>
<path d="M247.6 179.5v2.6zM247.6 174.4v2.6zM247.6 161.7v2.6zM247.6 164.3v1.2zM247.6 170.6v1.3zM245.1 171.9h2.5zM247.6 171.9v2.5zM247.6 177v2.5zM247.6 146.5v15.2zM262.9 159.2l2.5 2.5zM270.5 174.4l2.5 2.6zM270.5 171.9l2.5 2.5z"/>
<path d="M270.5 161.7l2.5 2.6zM270.5 164.3l2.5 2.5zM270.5 169.4l2.5 2.5zM270.5 166.8l2.5 2.6zM270.5 177l2.5 2.5zM270.5 179.5l2.5 2.6zM273 177h17.8zM273 174.4h17.8zM273 161.7h17.8zM273 164.3h17.8zM273 166.8h17.8zM273 171.9h17.8z"/>
<path d="M273 169.4h17.8zM273 179.5h17.8zM275.6 175h12zM275.6 172.5h6.1zM290.8 171.9h2.5zM290.8 166.8h2.5zM290.8 169.4h2.5zM290.8 164.3h2.5zM290.8 161.7h2.5zM290.8 174.4h2.5zM290.8 177h2.5zM290.8 179.5h2.5z"/>
<path d="M330.5 164.8h2.3zM336 164.8h5.9zM354.3 165.5l2.5 2.6zM354.3 161.7l2.5 2.6zM354.3 173.2l2.5 2.5zM356.8 168.1h15.3zM356.8 164.3h15.3zM356.8 160.5h15.3zM356.8 175.7h15.3zM373.6 167h7.9zM373.6 163.2h7.7zM400 173.7h3.8z"/>
<path d="M97.8 182.1l2.5 2.5zM97.8 184.6l2.5 2.5zM100.3 182.1h17.8zM100.3 184.6h17.8zM100.3 187.1h17.8zM110.5 192.2v17.8zM113 194.8v12.6zM115.6 197.3v7.6zM118.1 197.3h2.5zM118.1 192.2h2.5zM118.1 194.8h2.5zM118.1 182.1h2.5z"/>
<path d="M118.1 184.6h2.5zM118.1 187.1h2.5zM110.5 192.2h7.6zM115.6 197.3h2.5zM113 194.8h5.1zM123 196.4h3.4zM123 191.3h2.9zM123 193.9h3.1zM143.5 179.5v2.6zM143.5 184.6v2.5zM143.5 189.7v2.5zM143.5 187.1v.5z"/>
<path d="M143.5 189.2v.5zM143.5 194.8v2.5zM143.5 192.2v2.6zM143.5 182.1v2.5zM186.7 182.1l2.5 2.5zM186.7 184.6l2.5 2.5zM189.2 182.1h17.8zM189.2 184.6h17.8zM189.2 187.1h17.8zM199.4 192.2v17.8zM201.9 194.8v12.6zM204.4 197.3v7.6z"/>
<path d="M207 197.3h2.5zM207 192.2h2.5zM207 194.8h2.5zM207 182.1h2.5zM207 184.6h2.5zM207 187.1h2.5zM199.4 192.2h7.6zM204.4 197.3h2.6zM201.9 194.8h5.1zM211.9 196.4h3.4zM211.9 191.3h2.9zM211.9 193.9h3.1z"/>
<path d="M232.4 179.5v2.6zM232.4 184.6v2.5zM232.4 189.7v2.5zM232.4 187.1v.5zM232.4 189.2v.5zM232.4 194.8v2.5zM232.4 192.2v2.6zM232.4 182.1v2.5zM270.5 182.1l2.5 2.5zM270.5 184.6l2.5 2.5zM273 182.1h17.8zM273 184.6h17.8z"/>
<path d="M273 187.1h17.8zM283.2 192.2v17.8zM285.7 194.8h5.1zM288.3 197.3h2.5zM290.8 197.3h2.5zM290.8 192.2h2.5zM290.8 194.8h2.5zM290.8 182.1h2.5zM290.8 184.6h2.5zM290.8 187.1h2.5zM283.2 192.2h7.6zM295.7 196.4h3.4z"/>
<path d="M295.7 191.3h2.9zM295.7 193.9h3.1zM316.2 179.5v2.6zM316.2 184.6v2.5zM316.2 189.7v2.5zM316.2 187.1v.5zM316.2 189.2v.5zM316.2 194.8v2.5zM316.2 192.2v2.6zM316.2 182.1v2.5zM354.3 180.8l2.5 2.5zM354.3 184.6l2.5 2.5z"/>
<path d="M354.3 188.4l2.5 2.5zM354.3 192.2l2.5 2.6zM354.3 199.8l2.5 2.6zM356.8 183.3h15.3zM356.8 187.1h15.3zM356.8 190.9h15.3zM356.8 194.8h15.3zM373.6 182.2h5.8zM373.6 186.1h2.7zM373.6 189.9h1.8zM373.6 193.7h5.8zM29.9 211.4h8.4z"/>
<path d="M30.5 203.8h6.4zM47 210v2.5zM41.9 212.5h5.1zM41.9 204.9h5.1zM54.6 204.9h5.1zM54.6 210h5.1zM47 210h7.6zM47 204.9h7.6zM66.7 207.4h3.1zM69.8 207.4h10.2zM80 207.4h33zM80 207.4v15.3z"/>
<path d="M102.9 199.8v2.6zM102.9 202.4v2.5zM102.9 204.9h12.7zM110.5 210v2.5zM113 207.4h88.9zM115.6 204.9h88.8zM199.4 210v2.5zM201.9 207.4h83.8zM204.4 204.9h83.9zM283.2 210v2.5zM285.7 194.8v12.6zM285.7 207.4h86.4z"/>
<path d="M288.3 197.3v7.6zM356.8 202.4h15.3zM364.2 218l-.7 .8zM365.5 216.4l-.6 .8zM366.9 214.8l-.7 .8zM368.2 213.2l-.7 .8zM369.5 211.6l-.7 .8zM370.8 210l-.7 .8zM373.6 201.3h5.3zM373.6 206.4h5.2zM16.5 224.2h3.8zM80 222.7h2.5z"/>
<path d="M82.5 220.1v2.6zM82.5 220.1h2.6zM82.5 222.7v2.5zM82.5 225.2h2.6zM85.1 220.1h5.1zM85.1 225.2h5.1zM97.2 222.7h3.1zM100.3 222.7h271.8zM318.7 233.4h5.3zM332.5 235.9h6.4zM342.5 235.9h8.4zM353.7 230.7l-.7 .9z"/>
<path d="M355 229.1l-.7 .9zM356.3 227.5l-.6 .9zM357.6 226l-.6 .8zM359 224.4l-.7 .8zM360.3 222.8l-.7 .8zM361.6 221.2l-.7 .8zM362.9 219.6l-.7 .8zM400 224.2h3.8zM29.2 257v2.5zM29.2 251.9v2.5zM29.2 256.5v.5zM29.2 254.4v.5z"/>
<path d="M29.2 259.5v3.8zM29.2 248.1v3.8zM36.8 257v2.5zM36.8 251.9v2.5zM36.8 256.5v.5zM36.8 254.4v.5zM36.8 248.1v3.8zM29.2 248.1h7.6zM44.4 257v2.5zM44.4 251.9v2.5zM44.4 256.5v.5zM44.4 254.4v.5z"/>
<path d="M36.8 248.1h7.6zM44.4 248.1v3.8zM52.1 257v2.5zM52.1 251.9v2.5zM52.1 256.5v.5zM52.1 254.4v.5zM44.4 248.1h7.7zM52.1 248.1v3.8zM59.7 257v2.5zM59.7 251.9v2.5zM59.7 256.5v.5zM59.7 254.4v.5z"/>
<path d="M52.1 248.1h7.6zM59.7 248.1v3.8zM67.3 248.1v5zM67.3 243v2.5zM59.7 248.1h7.6zM67.3 245.5v2.6zM77.5 243v2.5zM77.5 248.1v2.5zM77.5 253.1v2.6zM77.5 250.6v.5zM77.5 252.6v.5zM77.5 258.2v2.6z"/>
<path d="M77.5 255.7v2.5zM77.5 245.5v2.6zM20.3 274.7h379.7zM29.2 265.8v2.6zM29.2 263.3h7.6zM29.2 263.3v2.5zM36.8 259.5v3.8zM36.8 263.3h7.6zM44.4 259.5v3.8zM44.4 263.3h7.7zM52.1 259.5v3.8zM52.1 263.3h7.6z"/>
<path d="M59.7 259.5v3.8zM67.3 258.2v5.1zM59.7 263.3h7.6zM67.8 274.7v3.8zM115.3 274.7v3.8zM162.7 274.7v3.8zM210.2 274.7v3.8zM257.6 274.7v3.8zM305.1 274.7v3.8zM352.5 274.7v3.8zM400 264.5v.1zM400 268.4v6.2z"/>
<path d="M400 274.6h.1zM400 22.1v252.6z"/>
<circle cx="64.8" cy="57.6" r=".51"/>
<circle cx="87.6" cy="67.8" r=".51"/>
<circle cx="156.2" cy="70.3" r=".51"/>
<circle cx="158.7" cy="72.8" r=".51"/>
<circle cx="161.3" cy="75.4" r=".51"/>
<circle cx="163.8" cy="77.9" r=".51"/>
<circle cx="184.1" cy="75.4" r=".51"/>
<circle cx="184.1" cy="72.8" r=".51"/>
<circle cx="184.1" cy="70.3" r=".51"/>
<circle cx="85.1" cy="95.7" r=".51"/>
<circle cx="90.2" cy="98.2" r=".51"/>
<circle cx="95.2" cy="83" r=".51"/>
<circle cx="95.2" cy="80.5" r=".51"/>
<circle cx="95.2" cy="85.5" r=".51"/>
<circle cx="52.1" cy="121.1" r=".51"/>
<circle cx="72.4" cy="123.6" r=".51"/>
<circle cx="143.5" cy="159.2" r=".51"/>
<circle cx="146" cy="156.7" r=".51"/>
<circle cx="148.6" cy="154.1" r=".51"/>
<circle cx="151.1" cy="151.6" r=".51"/>
<circle cx="153.6" cy="149" r=".51"/>
<circle cx="156.2" cy="146.5" r=".51"/>
<circle cx="158.7" cy="144" r=".51"/>
<circle cx="161.3" cy="141.4" r=".51"/>
<circle cx="229.8" cy="149" r=".51"/>
<circle cx="232.4" cy="151.6" r=".51"/>
<circle cx="234.9" cy="154.1" r=".51"/>
<circle cx="237.5" cy="156.7" r=".51"/>
<circle cx="240" cy="159.2" r=".51"/>
<circle cx="242.5" cy="141.4" r=".51"/>
<circle cx="245.1" cy="144" r=".51"/>
<circle cx="247.6" cy="146.5" r=".51"/>
<circle cx="316.2" cy="141.4" r=".51"/>
<circle cx="318.7" cy="144" r=".51"/>
<circle cx="321.3" cy="146.5" r=".51"/>
<circle cx="323.8" cy="149" r=".51"/>
<circle cx="326.4" cy="151.6" r=".51"/>
<circle cx="328.9" cy="154.1" r=".51"/>
<circle cx="331.4" cy="156.7" r=".51"/>
<circle cx="334" cy="159.2" r=".51"/>
<circle cx="47" cy="204.9" r=".51"/>
<circle cx="80" cy="207.4" r=".51"/>
<circle cx="113" cy="207.4" r=".51"/>
<circle cx="115.6" cy="204.9" r=".51"/>
<circle cx="201.9" cy="207.4" r=".51"/>
<circle cx="204.4" cy="204.9" r=".51"/>
<circle cx="285.7" cy="207.4" r=".51"/>
<circle cx="82.5" cy="222.7" r=".51"/>
<circle cx="36.8" cy="248.1" r=".51"/>
<circle cx="44.4" cy="248.1" r=".51"/>
<circle cx="52.1" cy="248.1" r=".51"/>
<circle cx="59.7" cy="248.1" r=".51"/>
<circle cx="67.3" cy="248.1" r=".51"/>
<circle cx="29.2" cy="263.3" r=".51"/>
<circle cx="36.8" cy="263.3" r=".51"/>
<circle cx="44.4" cy="263.3" r=".51"/>
<circle cx="52.1" cy="263.3" r=".51"/>
<circle cx="59.7" cy="263.3" r=".51"/>
</g>
<g fill="#000" stroke="#000" stroke-width=".28">
<path d="M26.6 30.7v3zM30.3 35.8v3zM26.6 30.7h13.8zM26.6 33.7h13.8zM30.3 35.8h10.1zM30.3 38.8h10.1zM40.4 30.7l1.5 1.5zM41.9 32.2l-1.5 1.5zM40.4 35.8l1.5 1.5zM41.9 37.3l-1.5 1.5zM24 56.1v3zM29.9 51v3.1z"/>
<path d="M34.2 45.9v3.1zM34.5 40.9v3zM24 56.1h16.4zM24 59.1h16.4zM29.9 51h10.5zM29.9 54.1h10.5zM34.2 45.9h6.2zM34.2 49h6.2zM34.5 40.9h5.9zM34.5 43.9h5.9zM40.4 56.1l1.5 1.5zM41.9 57.6l-1.5 1.5z"/>
<path d="M40.4 51l1.5 1.5zM41.9 52.5l-1.5 1.6zM40.4 45.9l1.5 1.6zM41.9 47.5l-1.5 1.5zM40.4 40.9l1.5 1.5zM41.9 42.4l-1.5 1.5zM84.2 72.8v5.1zM84.2 77.9h1.8zM84.2 72.8h1.8zM86 72.8v5.1zM87.6 62.7l-1.2 1.9zM87.6 62.7l1.3 1.9z"/>
<path d="M184.1 62.7l-1.2 1.9zM184.1 62.7l1.3 1.9zM30.6 94.2v3zM31.2 89.1v3zM30.6 94.2h9.8zM30.6 97.2h9.8zM31.2 89.1h9.2zM31.2 92.1h9.2zM40.4 94.2l1.5 1.5zM41.9 95.7l-1.5 1.5zM40.4 89.1l1.5 1.5zM41.9 90.6l-1.5 1.5z"/>
<path d="M89.3 80.5v5zM89.3 85.5h1.8zM89.3 80.5h1.8zM91.1 80.5v5zM155.4 84.3v5zM155.4 89.3h.8zM156.2 89.3h.7zM155.4 84.3h.8zM156.9 84.3v5zM156.2 84.3h.7zM158 84.3v5zM158 89.3h.7z"/>
<path d="M158.7 89.3h.8zM158 84.3h.7zM159.5 84.3v5zM158.7 84.3h.8zM160.5 89.3h.8zM160.5 84.3v5zM160.5 84.3h.8zM161.3 89.3h.7zM161.3 84.3h.7zM162 84.3v5zM163 84.3v5zM163 89.3h.8z"/>
<path d="M163 84.3h.8zM163.8 89.3h.8zM164.6 84.3v5zM163.8 84.3h.8zM372.1 90.6l1.5-1.5zM372.1 90.6l1.5 1.5zM372.1 94.4l1.5-1.5zM372.1 94.4l1.5 1.5zM372.1 98.2l1.5-1.5zM372.1 98.2l1.5 1.6zM373.6 89.1h12.1zM373.6 92.1h12.1z"/>
<path d="M373.6 92.9h12.1zM373.6 95.9h12.1zM373.6 96.7h12.1zM373.6 99.8h12.1zM385.7 89.1v3zM385.7 92.9v3zM385.7 96.7v3.1zM24.4 119.6h16zM51.2 110.9v5.1zM51.2 116h1.8zM51.2 110.9h1.8zM52.1 103.3l-1.3 1.9z"/>
<path d="M53 110.9v5.1zM52.1 103.3l1.2 1.9zM93.3 105.9h3.9zM161.9 100.8h3.8zM229.1 114.7v5.1zM229.1 119.8h.7zM229.8 119.8h.8zM229.1 114.7h.7zM229.8 103.3l-1.2 1.9zM230.6 114.7v5.1zM229.8 114.7h.8zM229.8 103.3l1.3 1.9z"/>
<path d="M231.6 119.8h.8zM231.6 114.7v5.1zM232.4 119.8h.7zM231.6 114.7h.8zM232.4 114.7h.7zM233.1 114.7v5.1zM234.2 114.7v5.1zM234.2 119.8h.7zM234.2 114.7h.7zM234.9 119.8h.8zM235.7 114.7v5.1zM234.9 114.7h.8z"/>
<path d="M236.7 114.7v5.1zM236.7 119.8h.8zM236.7 114.7h.8zM237.5 119.8h.7zM238.2 114.7v5.1zM237.5 114.7h.7zM239.2 114.7v5.1zM239.2 119.8h.8zM239.2 114.7h.8zM240 119.8h.8zM240.8 114.7v5.1zM240 114.7h.8z"/>
<path d="M316.2 116l-1.3 1.9zM316.2 116l1.3 1.9zM372.1 102l1.5-1.5zM372.1 102l1.5 1.6zM373.6 106.9l-1.5 1.5zM372.1 108.4l1.5 1.5zM373.6 110.7l-1.5 1.5zM372.1 112.2l1.5 1.5zM373.6 114.5l-1.5 1.5zM372.1 116l1.5 1.5zM373.6 100.5h12.1zM373.6 103.6h12.1z"/>
<path d="M373.6 106.9h12.6zM373.6 109.9h12.6zM373.6 110.7h12.6zM373.6 113.7h12.6zM373.6 114.5h12.6zM373.6 117.5h12.6zM385.7 100.5v3.1zM386.2 106.9v3zM386.2 110.7v3zM386.2 114.5v3zM24.4 119.6v3zM32.1 139.9v3z"/>
<path d="M32.1 139.9h8.3zM24.4 122.6h16zM41.9 121.1l-1.5 1.5zM40.4 119.6l1.5 1.5zM315.4 127.4v5.1zM315.4 132.5h.8zM316.2 132.5h.8zM315.4 127.4h.8zM317 127.4v5.1zM316.2 127.4h.8zM318 132.5h.7zM318 127.4v5.1z"/>
<path d="M318.7 132.5h.8zM318 127.4h.7zM318.7 127.4h.8zM319.5 127.4v5.1zM320.5 127.4v5.1zM320.5 132.5h.8zM320.5 127.4h.8zM321.3 132.5h.7zM322 127.4v5.1zM321.3 127.4h.7zM323.1 127.4v5.1zM323.1 132.5h.7z"/>
<path d="M323.1 127.4h.7zM323.8 132.5h.8zM324.6 127.4v5.1zM323.8 127.4h.8zM325.6 127.4v5.1zM325.6 132.5h.8zM325.6 127.4h.8zM326.4 132.5h.7zM327.1 127.4v5.1zM326.4 127.4h.7zM328.1 127.4v5.1zM328.1 132.5h.8z"/>
<path d="M328.9 132.5h.7zM328.1 127.4h.8zM329.6 127.4v5.1zM328.9 127.4h.7zM330.7 132.5h.7zM330.7 127.4v5.1zM331.4 132.5h.8zM330.7 127.4h.7zM331.4 127.4h.8zM332.2 127.4v5.1zM333.2 127.4v5.1zM333.2 132.5h.8z"/>
<path d="M333.2 127.4h.8zM334 132.5h.7zM334.7 127.4v5.1zM334 127.4h.7zM372.1 122.4l1.5-1.6zM372.1 122.4l1.5 1.5zM372.1 126.2l1.5-1.6zM372.1 126.2l1.5 1.5zM373.6 128.5l-1.5 1.5zM372.1 130l1.5 1.5zM373.6 132.3l-1.5 1.5zM372.1 133.8l1.5 1.5z"/>
<path d="M373.6 138.6h9.2zM373.6 120.8h10.2zM373.6 123.9h10.2zM373.6 124.6h10.2zM373.6 127.7h10.2zM373.6 128.5h10.2zM373.6 131.5h10.2zM373.6 132.3h10.2zM373.6 135.3h10.2zM382.8 138.6v3.1zM383.8 120.8v3.1zM383.8 124.6v3.1z"/>
<path d="M383.8 128.5v3zM383.8 132.3v3zM32.1 145v3zM32.1 150v3.1zM32.1 155.1v3.1zM32.1 142.9h8.3zM32.1 145h8.3zM32.1 148h8.3zM32.1 150h8.3zM32.1 153.1h8.3zM32.1 155.1h8.3zM32.1 158.2h8.3z"/>
<path d="M40.4 139.9l1.5 1.5zM41.9 141.4l-1.5 1.5zM40.4 145l1.5 1.5zM41.9 146.5l-1.5 1.5zM40.4 150l1.5 1.6zM41.9 151.6l-1.5 1.5zM40.4 155.1l1.5 1.6zM41.9 156.7l-1.5 1.5zM372.1 154.1l1.5-1.5zM372.1 154.1l1.5 1.5zM372.1 150.3l1.5-1.5zM372.1 150.3l1.5 1.5z"/>
<path d="M372.1 144l1.5-1.6zM372.1 144l1.5 1.5zM372.1 140.1l1.5-1.5zM372.1 140.1l1.5 1.6zM373.6 152.6h8.2zM373.6 155.6h8.2zM373.6 148.8h8.2zM373.6 151.8h8.2zM373.6 142.4h8.9zM373.6 145.5h8.9zM373.6 141.7h9.2zM373.6 158.9h12.2z"/>
<path d="M381.8 152.6v3zM381.8 148.8v3zM382.5 142.4v3.1zM385.8 158.9v3.1zM32.1 160.2v3.1zM32.1 160.2h8.3zM32.1 163.3h8.3zM40.4 160.2l1.5 1.5zM41.9 161.7l-1.5 1.6zM142.7 165.5v5.1zM142.7 170.6h.8zM143.5 179.5l-1.3 1.9z"/>
<path d="M143.5 170.6h.7zM142.7 165.5h.8zM144.2 165.5v5.1zM143.5 165.5h.7zM145.3 170.6h.7zM145.3 165.5v5.1zM145.3 165.5h.7zM146 170.6h.8zM146 165.5h.8zM146.8 165.5v5.1zM147.8 165.5v5.1zM147.8 170.6h.8z"/>
<path d="M147.8 165.5h.8zM148.6 170.6h.7zM149.3 165.5v5.1zM148.6 165.5h.7zM150.3 165.5v5.1zM150.3 170.6h.8zM151.1 170.6h.8zM150.3 165.5h.8zM151.9 165.5v5.1zM151.1 165.5h.8zM152.9 165.5v5.1zM152.9 170.6h.7z"/>
<path d="M153.6 170.6h.8zM152.9 165.5h.7zM154.4 165.5v5.1zM153.6 165.5h.8zM155.4 165.5v5.1zM155.4 170.6h.8zM156.2 170.6h.7zM155.4 165.5h.8zM156.9 165.5v5.1zM156.2 165.5h.7zM158 170.6h.7zM158 165.5v5.1z"/>
<path d="M158 165.5h.7zM158.7 170.6h.8zM158.7 165.5h.8zM159.5 165.5v5.1zM160.5 165.5v5.1zM160.5 170.6h.8zM160.5 165.5h.8zM161.3 170.6h.7zM162 165.5v5.1zM161.3 165.5h.7zM232.4 179.5l-1.3 1.9zM241.8 165.5v5.1z"/>
<path d="M241.8 170.6h.7zM242.5 170.6h.8zM241.8 165.5h.7zM243.3 165.5v5.1zM242.5 165.5h.8zM244.3 170.6h.8zM244.3 165.5v5.1zM244.3 165.5h.8zM245.1 170.6h.7zM245.1 165.5h.7zM245.8 165.5v5.1zM246.9 165.5v5.1z"/>
<path d="M246.9 170.6h.7zM246.9 165.5h.7zM247.6 170.6h.8zM248.4 165.5v5.1zM247.6 165.5h.8zM316.2 179.5l-1.3 1.9zM373.6 166.6l-1.5 1.5zM372.1 168.1l1.5 1.5zM373.6 162.7l-1.5 1.6zM372.1 164.3l1.5 1.5zM373.6 158.9l-1.5 1.6zM372.1 160.5l1.5 1.5z"/>
<path d="M373.6 174.2l-1.5 1.5zM372.1 175.7l1.5 1.5zM373.6 166.6h12.3zM373.6 169.6h12.3zM373.6 162.7h12.2zM373.6 165.8h12.2zM373.6 162h12.2zM373.6 174.2h15.1zM373.6 177.2h15.1zM385.8 162.7v3.1zM385.9 166.6v3zM388.7 174.2v3z"/>
<path d="M102.9 199.8l-1.3 1.9zM141.6 197.3h3.8zM143.5 179.5l1.3 1.9zM159.4 182.1h3.8zM230.5 197.3h3.8zM232.4 179.5l1.3 1.9zM245.7 182.1h3.8zM314.3 197.3h3.8zM316.2 179.5l1.3 1.9zM372.1 183.3l1.5-1.5zM372.1 183.3l1.5 1.5zM372.1 187.1l1.5-1.5z"/>
<path d="M372.1 187.1l1.5 1.6zM372.1 190.9l1.5-1.5zM372.1 190.9l1.5 1.6zM372.1 194.8l1.5-1.6zM372.1 194.8l1.5 1.5zM373.6 181.8h10.2zM373.6 184.8h10.2zM373.6 185.6h7zM373.6 188.7h7zM373.6 189.4h6.1zM373.6 192.5h6.1zM373.6 193.2h10.2z"/>
<path d="M373.6 196.3h10.2zM379.7 189.4v3.1zM380.6 185.6v3.1zM383.8 181.8v3zM383.8 193.2v3.1zM27.6 211v3zM28.2 203.4v3zM27.6 211h12.8zM27.6 214h12.8zM28.2 203.4h12.2zM28.2 206.4h12.2zM40.4 211l1.5 1.5z"/>
<path d="M41.9 212.5l-1.5 1.5zM40.4 203.4l1.5 1.5zM40.4 206.4l1.5-1.5zM102.9 199.8l1.2 1.9zM108.6 212.5h3.8zM197.5 212.5h3.8zM281.3 212.5h3.8zM372.1 202.4l1.5-1.6zM372.1 202.4l1.5 1.5zM372.1 207.4l1.5-1.5zM372.1 207.4l1.5 1.6zM373.6 200.8h9.6z"/>
<path d="M373.6 203.9h9.6zM373.6 205.9h9.6zM373.6 209h9.6zM383.2 200.8v3.1zM383.2 205.9v3.1zM372.1 222.7l1.5-1.6zM372.1 222.7l1.5 1.5zM373.6 221.1h6.1zM373.6 224.2h6.1zM379.7 221.1v3.1zM67.3 243l-1.3 1.9zM67.3 243l1.3 1.9z"/>
<path d="M77.5 243l-1.3 1.9zM77.5 243l1.2 1.9zM313.7 249.3h86.3zM313.7 254.4h86.3zM313.7 259.5h58.4zM372.1 259.5h27.9zM372.1 259.5v5.1zM27.3 268.4h3.8zM75.6 260.8h3.8zM313.7 264.6h58.4zM313.7 269.7h86.3zM372.1 264.6h27.9z"/>
<path d="M400 268.4v1.3z"/>
</g>
<g fill="#000" stroke="#000" stroke-width=".61">
<path d="M20.3 22.1v252.6zM20.3 22.1h379.7zM171.4 75.4h1.3zM171.4 72.8h1.3zM171.4 70.3h1.3zM171.4 77.9h1.3zM175.2 75.4h1.3zM175.2 72.8h1.3zM175.2 70.3h1.3zM175.2 77.9h1.3zM59.7 118.6v10.1zM80 118.6v10.1z"/>
<path d="M120.6 138.9v60.9zM120.6 138.9h15.3zM209.5 138.9v60.9zM209.5 138.9h15.3zM293.3 138.9v60.9zM293.3 138.9h15.3zM120.6 199.8h15.3zM135.9 138.9v60.9zM209.5 199.8h15.3zM224.8 138.9v60.9zM293.3 199.8h15.3zM308.6 138.9v60.9z"/>
<path d="M59.7 202.4v10.1zM90.2 217.6v10.1zM283.2 244.3v30.4zM313.7 254.4v5.1zM313.7 249.3v5.1zM313.7 244.3v5zM313.7 244.3h86.3zM283.2 244.3h30.5zM400 254.4v5.1zM400 249.3v5.1zM400 244.3v5zM400 22.1v222.2z"/>
<path d="M20.3 274.7h262.9zM283.2 274.7h30.5zM313.7 274.7h86.3zM313.7 269.7v5zM313.7 264.6v5.1zM313.7 259.5v5.1zM400 268.4v6.3zM400 264.6v3.8zM400 259.5v5.1z"/>
</g>
<g fill="none" stroke="#000" stroke-width=".25">
<circle cx="101.9" cy="93.2" r=".99"/>
<circle cx="65.8" cy="123.6" r=".99"/>
<circle cx="86.1" cy="123.6" r=".99"/>
<circle cx="65.8" cy="207.4" r=".99"/>
<circle cx="96.2" cy="222.7" r=".99"/>
</g>
<g fill="#000" stroke="#000" stroke-width=".42">
<path d="M102.9 75.4v27.9zM102.9 75.4h15.2zM170.2 67.8h7.6zM177.8 67.8v12.7zM153.6 83v8.9zM166.3 83v8.9zM153.6 91.9h12.7zM153.6 83h12.7zM170.2 67.8v12.7zM170.2 80.5h7.6zM102.9 103.3h15.2zM118.1 75.4v27.9z"/>
<path d="M227.3 112.2h15.2zM242.5 112.2v8.9zM227.3 112.2v8.9zM227.3 121.1h15.2zM313.7 124.9v8.9zM313.7 124.9h22.8zM313.7 133.8h22.8zM336.5 124.9v8.9zM140.9 164.3v8.9zM163.8 164.3v8.9zM140.9 173.2h22.9zM140.9 164.3h22.9z"/>
<path d="M240 164.3v8.9zM250.2 164.3v8.9zM240 173.2h10.2zM240 164.3h10.2zM222.2 248.1v10.1zM222.2 258.2v12.7zM222.2 258.2h55.9zM278.1 248.1v10.1zM222.2 248.1h55.9zM222.2 270.9h55.9zM278.1 258.2v12.7z"/>
</g>
<g fill="#000" stroke="#000" stroke-width=".25">
<path d="M141.5 188.7h4v.5h-4zM141.5 187.6h4v.5h-4zM230.4 188.7h4v.5h-4zM230.4 187.6h4v.5h-4zM314.2 188.7h4v.5h-4zM314.2 187.6h4v.5h-4zM27.2 254.9h4v.5h-4zM27.2 255.9h4v.6h-4zM34.8 254.9h4.1v.5h-4.1zM34.8 255.9h4.1v.6h-4.1zM42.4 254.9h4.1v.5h-4.1zM42.4 255.9h4.1v.6h-4.1z"/>
<path d="M50 254.9h4.1v.5h-4.1zM50 255.9h4.1v.6h-4.1zM57.7 254.9h4v.5h-4zM57.7 255.9h4v.6h-4zM75.4 252.1h4.1v.5h-4.1zM75.4 251.1h4.1v.5h-4.1zM252.7 248.1h25.4v10.1h-25.4z"/>
</g>
<path d="M59.7 118.6a5.1 5.1 0 0 1 5.1 5 5.1 5.1 0 0 1-5.1 5.1M80 118.6a5.1 5.1 0 0 1 5.1 5 5.1 5.1 0 0 1-5.1 5.1M59.7 202.4a5.1 5.1 0 0 1 5.1 5 5.1 5.1 0 0 1-5.1 5.1M90.2 217.6a5.1 5.1 0 0 1 5 5.1 5.1 5.1 0 0 1-5 5" fill="none" stroke="#000" stroke-width=".61"/>
<g fill="none" stroke="#000" stroke-width=".42">
<circle cx="158.7" cy="90.6" r=".25"/>
<circle cx="161.3" cy="90.6" r=".25"/>
<circle cx="163.8" cy="90.6" r=".25"/>
<circle cx="229.8" cy="113.5" r=".25"/>
<circle cx="232.4" cy="113.5" r=".25"/>
<circle cx="234.9" cy="113.5" r=".25"/>
<circle cx="237.5" cy="113.5" r=".25"/>
<circle cx="316.2" cy="126.2" r=".25"/>
<circle cx="318.7" cy="126.2" r=".25"/>
<circle cx="321.3" cy="126.2" r=".25"/>
<circle cx="323.8" cy="126.2" r=".25"/>
<circle cx="326.4" cy="126.2" r=".25"/>
<circle cx="328.9" cy="126.2" r=".25"/>
<circle cx="331.4" cy="126.2" r=".25"/>
<circle cx="146" cy="171.9" r=".25"/>
<circle cx="148.6" cy="171.9" r=".25"/>
<circle cx="151.1" cy="171.9" r=".25"/>
<circle cx="153.6" cy="171.9" r=".25"/>
<circle cx="156.2" cy="171.9" r=".25"/>
<circle cx="158.7" cy="171.9" r=".25"/>
<circle cx="161.3" cy="171.9" r=".25"/>
<circle cx="245.1" cy="171.9" r=".25"/>
<circle cx="247.6" cy="171.9" r=".25"/>
</g>
<path d="M16.5 18.2v260.3zM16.5 18.2h387.3zM16.5 278.5h387.3zM403.8 18.2v260.3z" fill="#000" stroke="#000" stroke-width=".32"/>
<g fill="#000" stroke="#000" stroke-width=".76">
<path d="M354.3 88.1v126.9zM97.8 131.3l5.1-5.1zM102.9 126.2h33zM135.9 126.2l5-5.1zM140.9 34.8v86.3zM140.9 121.1l5.1 5.1zM181.6 136.3v81.3zM146 126.2h35.6zM181.6 126.2l5.1 5.1zM191.7 126.2l-5 5.1zM191.7 126.2h73.7zM265.4 126.2l5.1 5.1z"/>
<path d="M265.4 144v71zM97.8 131.3v53.3zM186.7 131.3v53.3zM270.5 131.3v53.3zM181.6 217.6l2.5 2.5zM265.4 215l5.1 5.1zM184.1 220.1h76.2zM260.3 220.1l5.1-5.1zM270.5 220.1h78.7zM349.2 220.1l5.1-5.1z"/>
</g>
<use href="#words"/>
</svg>
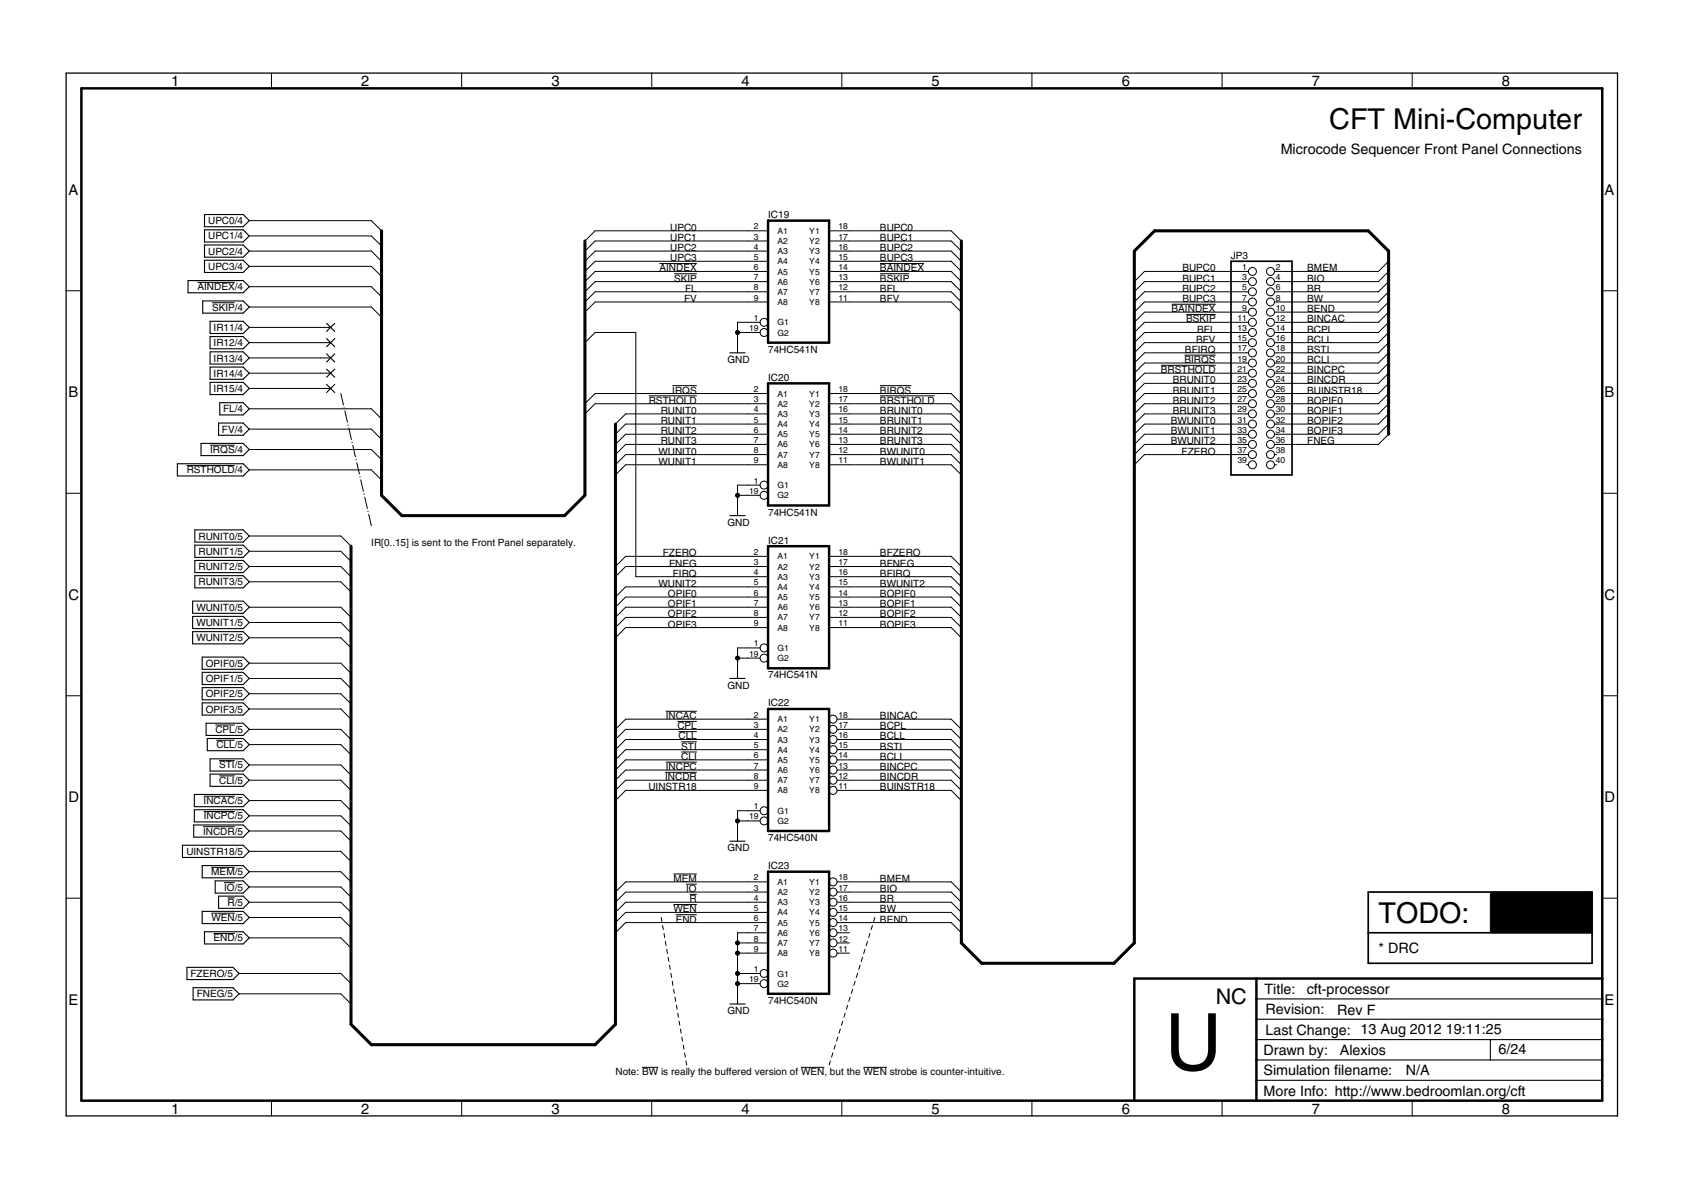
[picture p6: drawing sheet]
<svg xmlns="http://www.w3.org/2000/svg" width="420mm" height="297mm" viewBox="0 0 420 297" stroke-linecap="round" stroke-linejoin="round" font-family="sans-serif">
<defs><g id="words">
<text font-size="19.7" x="290.8" y="267.1">U</text>
<g font-size="7.2">
<text x="331.8" y="32.2">CFT Mini-Computer</text>
<text x="344.1" y="230.3">TODO:</text>
</g>
<text font-size="5.4" x="303.5" y="250.6">NC</text>
<g font-size="3.7">
<text x="42.7" y="21.5">1</text>
<text x="90.2" y="21.5">2</text>
<text x="137.7" y="21.5">3</text>
<text x="185.1" y="21.5">4</text>
<text x="232.6" y="21.5">5</text>
<text x="280" y="21.5">6</text>
<text x="327.5" y="21.5">7</text>
<text x="375" y="21.5">8</text>
<text x="17.1" y="48.6">A</text>
<text x="400.6" y="48.6">A</text>
<text x="17.1" y="99.2">B</text>
<text x="400.6" y="99.2">B</text>
<text x="17.1" y="149.7">C</text>
<text x="400.6" y="149.7">C</text>
<text x="17.1" y="200.2">D</text>
<text x="400.6" y="200.2">D</text>
<text x="17.1" y="250.8">E</text>
<text x="400.6" y="250.8">E</text>
<text x="42.7" y="277.9">1</text>
<text x="90.2" y="277.9">2</text>
<text x="137.7" y="277.9">3</text>
<text x="185.1" y="277.9">4</text>
<text x="232.6" y="277.9">5</text>
<text x="280" y="277.9">6</text>
<text x="327.5" y="277.9">7</text>
<text x="375" y="277.9">8</text>
</g>
<g font-size="3.6">
<text x="319.7" y="38.6">Microcode Sequencer Front Panel Connections</text>
<text x="344.1" y="237.9">* DRC</text>
<text x="315.7" y="248.1">Title:</text>
<text x="326.2" y="248.2">cft-processor</text>
<text x="315.9" y="253.2">Revision:</text>
<text x="333.8" y="253.3">Rev F</text>
<text x="315.4" y="263.3">Drawn by:</text>
<text x="315.9" y="258.2">Last Change: 13 Aug 2012</text>
<text x="334.5" y="263.3">Alexios</text>
<text x="361" y="258.1">19:11:25</text>
<text x="374.1" y="263.2">6/24</text>
<text x="315.4" y="268.4">Simulation filename:</text>
<text x="351" y="268.4">N/A</text>
<text x="315.4" y="273.5">More Info: http://www.bedroomlan.org/cft</text>
</g>
<g font-size="2.5">
<text x="52" y="56">UPC0/4</text>
<text x="52" y="59.8">UPC1/4</text>
<text x="167.3" y="57.6">UPC0</text>
<text x="191.7" y="54.4">IC19</text>
<text x="219.7" y="57.6">BUPC0</text>
<text x="52" y="63.6">UPC2/4</text>
<text x="167.3" y="60.1">UPC1</text>
<text x="167.3" y="62.7">UPC2</text>
<text x="167.3" y="65.2">UPC3</text>
<text x="219.7" y="60.1">BUPC1</text>
<text x="219.7" y="62.7">BUPC2</text>
<text x="219.7" y="65.2">BUPC3</text>
<text x="307.3" y="64.6">JP3</text>
<text x="52" y="67.4">UPC3/4</text>
<text x="164.6" y="67.8">AINDEX</text>
<text x="168.3" y="70.3">SKIP</text>
<text x="219.7" y="67.8">BAINDEX</text>
<text x="219.7" y="70.3">BSKIP</text>
<text x="295.2" y="67.8">BUPC0</text>
<text x="295.2" y="70.3">BUPC1</text>
<text x="326.4" y="70.3">BIO</text>
<text x="326.4" y="67.8">BMEM</text>
<text x="49.3" y="72.5">AINDEX/4</text>
<text x="52.9" y="77.5">SKIP/4</text>
<text x="170.8" y="75.4">FV</text>
<text x="171" y="72.8">FL</text>
<text x="219.7" y="72.8">BFL</text>
<text x="219.7" y="75.4">BFV</text>
<text x="292.5" y="77.9">BAINDEX</text>
<text x="295.2" y="72.8">BUPC2</text>
<text x="295.2" y="75.4">BUPC3</text>
<text x="326.4" y="72.8">BR</text>
<text x="326.4" y="75.4">BW</text>
<text x="326.4" y="77.9">BEND</text>
<text x="53.3" y="82.6">IR11/4</text>
<text x="296.2" y="80.5">BSKIP</text>
<text x="298.9" y="83">BFL</text>
<text x="326.4" y="80.5">BINCAC</text>
<text x="326.4" y="83">BCPL</text>
<text x="53.3" y="86.4">IR12/4</text>
<text x="191.7" y="88.1">74HC541N</text>
<text x="295.8" y="88.1">BFIRQ</text>
<text x="298.6" y="85.5">BFV</text>
<text x="326.4" y="85.5">BCLL</text>
<text x="326.4" y="88.1">BSTI</text>
<text x="53.3" y="90.2">IR13/4</text>
<text x="53.3" y="94">IR14/4</text>
<text x="181.6" y="90.6">GND</text>
<text x="191.7" y="95.1">IC20</text>
<text x="289.8" y="93.2">BRSTHOLD</text>
<text x="292.8" y="95.7">BRUNIT0</text>
<text x="295.7" y="90.6">BIRQS</text>
<text x="326.4" y="90.6">BCLI</text>
<text x="326.4" y="93.2">BINCPC</text>
<text x="326.4" y="95.7">BINCDR</text>
<text x="53.3" y="97.9">IR15/4</text>
<text x="162" y="100.8">RSTHOLD</text>
<text x="167.8" y="98.2">IRQS</text>
<text x="219.7" y="98.2">BIRQS</text>
<text x="219.7" y="100.8">BRSTHOLD</text>
<text x="292.8" y="98.2">BRUNIT1</text>
<text x="292.8" y="100.8">BRUNIT2</text>
<text x="326.4" y="100.8">BOPIF0</text>
<text x="326.4" y="98.2">BUINSTR18</text>
<text x="55.7" y="102.9">FL/4</text>
<text x="165" y="103.3">RUNIT0</text>
<text x="165" y="105.9">RUNIT1</text>
<text x="219.7" y="103.3">BRUNIT0</text>
<text x="219.7" y="105.9">BRUNIT1</text>
<text x="292.3" y="105.9">BWUNIT0</text>
<text x="292.8" y="103.3">BRUNIT3</text>
<text x="326.4" y="103.3">BOPIF1</text>
<text x="326.4" y="105.9">BOPIF2</text>
<text x="52.5" y="113.1">IRQS/4</text>
<text x="55.4" y="108">FV/4</text>
<text x="164.4" y="113.5">WUNIT0</text>
<text x="165" y="108.4">RUNIT2</text>
<text x="165" y="110.9">RUNIT3</text>
<text x="219.7" y="108.4">BRUNIT2</text>
<text x="219.7" y="110.9">BRUNIT3</text>
<text x="219.7" y="113.5">BWUNIT0</text>
<text x="292.3" y="108.4">BWUNIT1</text>
<text x="292.3" y="110.9">BWUNIT2</text>
<text x="295" y="113.5">FZERO</text>
<text x="326.4" y="108.4">BOPIF3</text>
<text x="326.4" y="110.9">FNEG</text>
<text x="46.6" y="118.2">RSTHOLD/4</text>
<text x="164.4" y="116">WUNIT1</text>
<text x="219.7" y="116">BWUNIT1</text>
<text x="181.6" y="131.3">GND</text>
<text x="191.7" y="128.7">74HC541N</text>
<text x="49.6" y="134.7">RUNIT0/5</text>
<text x="92.7" y="136.3">IR[0..15] is sent to the Front Panel separately.</text>
<text x="191.7" y="135.7">IC21</text>
<text x="49.6" y="138.5">RUNIT1/5</text>
<text x="49.6" y="142.3">RUNIT2/5</text>
<text x="165.5" y="138.9">FZERO</text>
<text x="167" y="141.4">FNEG</text>
<text x="168" y="144">FIRQ</text>
<text x="219.7" y="138.9">BFZERO</text>
<text x="219.7" y="141.4">BFNEG</text>
<text x="219.7" y="144">BFIRQ</text>
<text x="49.6" y="146.1">RUNIT3/5</text>
<text x="164.4" y="146.5">WUNIT2</text>
<text x="166.7" y="149">OPIF0</text>
<text x="219.7" y="146.5">BWUNIT2</text>
<text x="219.7" y="149">BOPIF0</text>
<text x="49" y="152.5">WUNIT0/5</text>
<text x="166.7" y="151.6">OPIF1</text>
<text x="166.7" y="154.1">OPIF2</text>
<text x="219.7" y="151.6">BOPIF1</text>
<text x="219.7" y="154.1">BOPIF2</text>
<text x="49" y="156.3">WUNIT1/5</text>
<text x="49" y="160.1">WUNIT2/5</text>
<text x="166.7" y="156.6">OPIF3</text>
<text x="219.7" y="156.6">BOPIF3</text>
<text x="51.4" y="166.4">OPIF0/5</text>
<text x="51.4" y="170.2">OPIF1/5</text>
<text x="181.6" y="171.9">GND</text>
<text x="191.7" y="169.3">74HC541N</text>
<text x="51.4" y="174">OPIF2/5</text>
<text x="51.4" y="177.9">OPIF3/5</text>
<text x="166.2" y="179.5">INCAC</text>
<text x="191.7" y="176.3">IC22</text>
<text x="219.7" y="179.5">BINCAC</text>
<text x="53.8" y="182.9">CPL/5</text>
<text x="169.1" y="182">CPL</text>
<text x="169.4" y="184.6">CLL</text>
<text x="219.7" y="182">BCPL</text>
<text x="219.7" y="184.6">BCLL</text>
<text x="54" y="186.7">CLL/5</text>
<text x="54.7" y="191.8">STI/5</text>
<text x="170.1" y="187.1">STI</text>
<text x="170.1" y="189.7">CLI</text>
<text x="219.7" y="187.1">BSTI</text>
<text x="219.7" y="189.7">BCLI</text>
<text x="54.7" y="195.6">CLI/5</text>
<text x="161.9" y="197.3">UINSTR18</text>
<text x="166.1" y="194.7">INCDR</text>
<text x="166.2" y="192.2">INCPC</text>
<text x="219.7" y="192.2">BINCPC</text>
<text x="219.7" y="194.7">BINCDR</text>
<text x="219.7" y="197.3">BUINSTR18</text>
<text x="50.8" y="200.7">INCAC/5</text>
<text x="50.7" y="208.3">INCDR/5</text>
<text x="50.9" y="204.5">INCPC/5</text>
<text x="191.7" y="210">74HC540N</text>
<text x="46.5" y="213.4">UINSTR18/5</text>
<text x="181.6" y="212.5">GND</text>
<text x="52.7" y="218.5">MEM/5</text>
<text x="168.1" y="220.1">MEM</text>
<text x="191.7" y="217">IC23</text>
<text x="219.7" y="220.1">BMEM</text>
<text x="55.9" y="222.3">IO/5</text>
<text x="56.8" y="226.1">R/5</text>
<text x="168.2" y="227.8">WEN</text>
<text x="171.3" y="222.7">IO</text>
<text x="172.2" y="225.2">R</text>
<text x="219.7" y="222.7">BIO</text>
<text x="219.7" y="225.2">BR</text>
<text x="219.7" y="227.8">BW</text>
<text x="52.8" y="229.9">WEN/5</text>
<text x="168.7" y="230.3">END</text>
<text x="219.7" y="230.3">BEND</text>
<text x="53.3" y="235">END/5</text>
<text x="47.6" y="243.9">FZERO/5</text>
<text x="49.1" y="249">FNEG/5</text>
<text x="191.7" y="250.6">74HC540N</text>
<text x="181.6" y="253.2">GND</text>
<text x="153.7" y="268.4">Note: BW is really the buffered version of WEN, but the WEN strobe is counter-intuitive.</text>
</g>
<g font-size="2.1">
<text x="188.2" y="57.2">2</text>
<text x="188.2" y="59.8">3</text>
<text x="194.1" y="58.4">A1</text>
<text x="202" y="58.4">Y1</text>
<text x="209.3" y="59.8">17</text>
<text x="209.3" y="57.2">18</text>
<text x="188.2" y="62.3">4</text>
<text x="188.2" y="64.9">5</text>
<text x="194.1" y="60.9">A2</text>
<text x="194.1" y="63.4">A3</text>
<text x="194.1" y="66">A4</text>
<text x="202" y="66">Y4</text>
<text x="202" y="63.4">Y3</text>
<text x="202" y="60.9">Y2</text>
<text x="209.3" y="64.9">15</text>
<text x="209.3" y="62.3">16</text>
<text x="188.2" y="67.4">6</text>
<text x="188.2" y="69.9">7</text>
<text x="194.1" y="68.5">A5</text>
<text x="194.1" y="71.1">A6</text>
<text x="202" y="71.1">Y6</text>
<text x="202" y="68.5">Y5</text>
<text x="209.3" y="69.9">13</text>
<text x="209.3" y="67.4">14</text>
<text x="310.1" y="67.4">1</text>
<text x="310.1" y="69.9">3</text>
<text x="318.5" y="67.4">2</text>
<text x="318.5" y="69.9">4</text>
<text x="188.2" y="72.5">8</text>
<text x="188.2" y="75">9</text>
<text x="194.1" y="73.6">A7</text>
<text x="194.1" y="76.1">A8</text>
<text x="202" y="76.1">Y8</text>
<text x="202" y="73.6">Y7</text>
<text x="209.3" y="75">11</text>
<text x="209.3" y="72.5">12</text>
<text x="310.1" y="72.5">5</text>
<text x="310.1" y="75">7</text>
<text x="310.1" y="77.6">9</text>
<text x="318.5" y="72.5">6</text>
<text x="318.5" y="75">8</text>
<text x="318.5" y="77.6">10</text>
<text x="187" y="82.6">19</text>
<text x="188.2" y="80.1">1</text>
<text x="194.1" y="81.2">G1</text>
<text x="194.1" y="83.8">G2</text>
<text x="308.9" y="80.1">11</text>
<text x="308.9" y="82.6">13</text>
<text x="318.5" y="80.1">12</text>
<text x="318.5" y="82.6">14</text>
<text x="308.9" y="85.2">15</text>
<text x="308.9" y="87.7">17</text>
<text x="318.5" y="85.2">16</text>
<text x="318.5" y="87.7">18</text>
<text x="308.9" y="90.3">19</text>
<text x="308.9" y="92.8">21</text>
<text x="308.9" y="95.3">23</text>
<text x="318.5" y="90.3">20</text>
<text x="318.5" y="92.8">22</text>
<text x="318.5" y="95.3">24</text>
<text x="188.2" y="97.9">2</text>
<text x="188.2" y="100.4">3</text>
<text x="194.1" y="99">A1</text>
<text x="194.1" y="101.5">A2</text>
<text x="202" y="101.5">Y2</text>
<text x="202" y="99">Y1</text>
<text x="209.3" y="100.4">17</text>
<text x="209.3" y="97.9">18</text>
<text x="308.9" y="97.9">25</text>
<text x="308.9" y="100.4">27</text>
<text x="318.5" y="97.9">26</text>
<text x="318.5" y="100.4">28</text>
<text x="188.2" y="103">4</text>
<text x="188.2" y="105.5">5</text>
<text x="194.1" y="104.1">A3</text>
<text x="194.1" y="106.6">A4</text>
<text x="202" y="106.6">Y4</text>
<text x="202" y="104.1">Y3</text>
<text x="209.3" y="105.5">15</text>
<text x="209.3" y="103">16</text>
<text x="308.9" y="103">29</text>
<text x="308.9" y="105.5">31</text>
<text x="318.5" y="103">30</text>
<text x="318.5" y="105.5">32</text>
<text x="188.2" y="108">6</text>
<text x="188.2" y="110.6">7</text>
<text x="188.2" y="113.1">8</text>
<text x="194.1" y="109.2">A5</text>
<text x="194.1" y="111.7">A6</text>
<text x="202" y="111.7">Y6</text>
<text x="202" y="109.2">Y5</text>
<text x="209.3" y="113.1">12</text>
<text x="209.3" y="110.6">13</text>
<text x="209.3" y="108">14</text>
<text x="308.9" y="108">33</text>
<text x="308.9" y="110.6">35</text>
<text x="308.9" y="113.1">37</text>
<text x="318.5" y="108">34</text>
<text x="318.5" y="110.6">36</text>
<text x="318.5" y="113.1">38</text>
<text x="188.2" y="115.7">9</text>
<text x="194.1" y="114.2">A7</text>
<text x="194.1" y="116.8">A8</text>
<text x="202" y="116.8">Y8</text>
<text x="202" y="114.2">Y7</text>
<text x="209.3" y="115.7">11</text>
<text x="308.9" y="115.7">39</text>
<text x="318.5" y="115.7">40</text>
<text x="187" y="123.3">19</text>
<text x="188.2" y="120.7">1</text>
<text x="194.1" y="121.9">G1</text>
<text x="194.1" y="124.4">G2</text>
<text x="188.2" y="138.5">2</text>
<text x="188.2" y="141.1">3</text>
<text x="188.2" y="143.6">4</text>
<text x="194.1" y="139.6">A1</text>
<text x="194.1" y="142.2">A2</text>
<text x="202" y="142.2">Y2</text>
<text x="202" y="139.6">Y1</text>
<text x="209.3" y="143.6">16</text>
<text x="209.3" y="141.1">17</text>
<text x="209.3" y="138.5">18</text>
<text x="188.2" y="146.1">5</text>
<text x="188.2" y="148.7">6</text>
<text x="194.1" y="144.7">A3</text>
<text x="194.1" y="147.3">A4</text>
<text x="194.1" y="149.8">A5</text>
<text x="202" y="149.8">Y5</text>
<text x="202" y="147.3">Y4</text>
<text x="202" y="144.7">Y3</text>
<text x="209.3" y="148.7">14</text>
<text x="209.3" y="146.1">15</text>
<text x="188.2" y="151.2">7</text>
<text x="188.2" y="153.8">8</text>
<text x="194.1" y="152.3">A6</text>
<text x="194.1" y="154.9">A7</text>
<text x="202" y="154.9">Y7</text>
<text x="202" y="152.3">Y6</text>
<text x="209.3" y="153.8">12</text>
<text x="209.3" y="151.2">13</text>
<text x="188.2" y="161.4">1</text>
<text x="188.2" y="156.3">9</text>
<text x="194.1" y="157.4">A8</text>
<text x="202" y="157.4">Y8</text>
<text x="209.3" y="156.3">11</text>
<text x="187" y="163.9">19</text>
<text x="194.1" y="162.5">G1</text>
<text x="194.1" y="165">G2</text>
<text x="188.2" y="179.1">2</text>
<text x="209.3" y="179.1">18</text>
<text x="188.2" y="181.7">3</text>
<text x="188.2" y="184.2">4</text>
<text x="194.1" y="180.3">A1</text>
<text x="194.1" y="182.8">A2</text>
<text x="194.1" y="185.3">A3</text>
<text x="202" y="185.3">Y3</text>
<text x="202" y="182.8">Y2</text>
<text x="202" y="180.3">Y1</text>
<text x="209.3" y="184.2">16</text>
<text x="209.3" y="181.7">17</text>
<text x="188.2" y="186.8">5</text>
<text x="188.2" y="189.3">6</text>
<text x="188.2" y="191.8">7</text>
<text x="194.1" y="187.9">A4</text>
<text x="194.1" y="190.4">A5</text>
<text x="202" y="190.4">Y5</text>
<text x="202" y="187.9">Y4</text>
<text x="209.3" y="191.8">13</text>
<text x="209.3" y="189.3">14</text>
<text x="209.3" y="186.8">15</text>
<text x="188.2" y="194.4">8</text>
<text x="188.2" y="196.9">9</text>
<text x="194.1" y="193">A6</text>
<text x="194.1" y="195.5">A7</text>
<text x="202" y="195.5">Y7</text>
<text x="202" y="193">Y6</text>
<text x="209.3" y="196.9">11</text>
<text x="209.3" y="194.4">12</text>
<text x="188.2" y="202">1</text>
<text x="194.1" y="203.1">G1</text>
<text x="194.1" y="198">A8</text>
<text x="202" y="198">Y8</text>
<text x="187" y="204.5">19</text>
<text x="194.1" y="205.7">G2</text>
<text x="188.2" y="219.8">2</text>
<text x="194.1" y="220.9">A1</text>
<text x="202" y="220.9">Y1</text>
<text x="209.3" y="219.8">18</text>
<text x="188.2" y="222.3">3</text>
<text x="188.2" y="224.9">4</text>
<text x="188.2" y="227.4">5</text>
<text x="194.1" y="223.4">A2</text>
<text x="194.1" y="226">A3</text>
<text x="202" y="226">Y3</text>
<text x="202" y="223.4">Y2</text>
<text x="209.3" y="227.4">15</text>
<text x="209.3" y="224.9">16</text>
<text x="209.3" y="222.3">17</text>
<text x="188.2" y="229.9">6</text>
<text x="188.2" y="232.5">7</text>
<text x="194.1" y="228.5">A4</text>
<text x="194.1" y="231.1">A5</text>
<text x="194.1" y="233.6">A6</text>
<text x="202" y="233.6">Y6</text>
<text x="202" y="231.1">Y5</text>
<text x="202" y="228.5">Y4</text>
<text x="209.3" y="232.5">13</text>
<text x="209.3" y="229.9">14</text>
<text x="188.2" y="235">8</text>
<text x="188.2" y="237.6">9</text>
<text x="194.1" y="236.1">A7</text>
<text x="194.1" y="238.7">A8</text>
<text x="202" y="238.7">Y8</text>
<text x="202" y="236.1">Y7</text>
<text x="209.3" y="237.6">11</text>
<text x="209.3" y="235">12</text>
<text x="187" y="245.2">19</text>
<text x="188.2" y="242.6">1</text>
<text x="194.1" y="243.8">G1</text>
<text x="194.1" y="246.3">G2</text>
</g>
</g></defs>
<g fill="#000" stroke="#000" stroke-width=".25">
<path d="M67.8 18.2v3.9zM115.3 18.2v3.9zM162.7 18.2v3.9zM210.2 18.2v3.9zM257.6 18.2v3.9zM305.1 18.2v3.9zM352.5 18.2v3.9zM20.3 22.1v252.6zM20.3 22.1h379.7zM62.2 55.1h30.5zM62.2 58.9h30.5zM92.7 55.1l2.5 2.5z"/>
<path d="M92.7 58.9l2.5 2.5zM148.6 57.6h38.1zM186.7 57.6h5zM207 57.6h5.1zM212.1 57.6h25.4zM16.5 72.6h3.8zM49.3 70.5h9.3zM52.9 75.6h5.7zM62.2 62.7h30.5zM62.2 66.5h30.5zM62.2 71.6h30.5zM92.7 71.6l2.5 2.5z"/>
<path d="M62.2 76.6h30.5zM92.7 76.6l2.5 2.6zM92.7 62.7l2.5 2.5zM92.7 66.5l2.5 2.5zM148.6 67.8l-2.6 2.5zM148.6 70.3l-2.6 2.5zM148.6 75.4l-2.6 2.5zM146 75.4l2.6-2.6zM148.6 57.6l-2.6 2.6zM146 62.7l2.6-2.5zM148.6 62.7l-2.6 2.5zM146 67.8l2.6-2.6z"/>
<path d="M148.6 67.8h38.1zM148.6 70.3h38.1zM148.6 75.4h38.1zM148.6 72.8h38.1zM148.6 60.2h38.1zM148.6 62.7h38.1zM148.6 65.2h38.1zM164.6 65.8h9.4zM168.3 68.3h5.7zM186.7 60.2h5zM186.7 62.7h5zM186.7 65.2h5z"/>
<path d="M186.7 67.8h5zM186.7 70.3h5zM186.7 72.8h5zM186.7 75.4h5zM207 75.4h5.1zM207 72.8h5.1zM207 70.3h5.1zM207 67.8h5.1zM207 65.2h5.1zM207 62.7h5.1zM207 60.2h5.1zM219.7 65.8h11z"/>
<path d="M219.7 68.3h7.3zM212.1 60.2h25.4zM212.1 62.7h25.4zM212.1 65.2h25.4zM212.1 67.8h25.4zM212.1 70.3h25.4zM212.1 72.8h25.4zM212.1 75.4h25.4zM237.5 57.6l2.5 2.6zM237.5 60.2l2.5 2.5zM237.5 62.7l2.5 2.5zM237.5 65.2l2.5 2.6z"/>
<path d="M237.5 67.8l2.5 2.5zM237.5 70.3l2.5 2.5zM237.5 72.8l2.5 2.6zM237.5 75.4l2.5 2.5zM285.7 67.8l-2.5 2.5zM283.2 72.8l2.5-2.5zM285.7 72.8l-2.5 2.6zM285.7 75.4l-2.5 2.5zM285.7 67.8h25.4zM285.7 70.3h25.4zM285.7 72.8h25.4zM285.7 75.4h25.4z"/>
<path d="M285.7 77.9h25.4zM292.5 75.9h11zM296.2 78.5h7.3zM311.1 67.8h.6zM311.1 70.3h.6zM311.1 72.8h.6zM311.1 75.4h.6zM311.1 77.9h.6zM318.2 67.8h.5zM318.2 70.3h.5zM318.2 72.8h.5zM318.2 75.4h.5z"/>
<path d="M318.2 77.9h.5zM318.7 70.3h25.4zM318.7 67.8h25.4zM318.7 72.8h25.4zM318.7 75.4h25.4zM318.7 77.9h25.4zM344.1 80.5l2.6-2.6zM346.7 67.8l-2.6 2.5zM346.7 65.2l-2.6 2.6zM346.7 70.3l-2.6 2.5zM346.7 72.8l-2.6 2.6zM346.7 75.4l-2.6 2.5z"/>
<path d="M400 72.6h3.8zM62.2 81.7h17.8zM62.2 85.5h17.8zM62.2 89.3h17.8zM62.2 93.2h17.8zM62.2 97h17.8zM80 81.7h2.5zM80 85.5h2.5zM80 89.3h2.5zM80 93.2h2.5zM80 97h2.5zM148.6 83l-2.6 2.5z"/>
<path d="M148.6 98.2h38.1zM148.6 83h10.1zM162 98.8h12zM167.8 96.3h6.2zM184.1 85.5v2.6zM184.1 83v2.5zM184.1 80.5v2.5zM186.7 80.5h3.1zM186.7 83h3.1zM186.7 98.2h5zM184.1 83h2.6zM184.1 80.5h2.6z"/>
<path d="M207 98.2h5.1zM219.7 96.3h7.8zM219.7 98.8h13.7zM212.1 98.2h25.4zM283.2 80.5l2.5-2.6zM285.7 80.5l-2.5 2.5zM285.7 83l-2.5 2.5zM283.2 88.1l2.5-2.6zM285.7 90.6l-2.5 2.6zM283.2 95.7l2.5-2.5zM285.7 95.7l-2.5 2.5zM285.7 80.5h25.4z"/>
<path d="M285.7 83h25.4zM285.7 85.5h25.4zM285.7 90.6h25.4zM285.7 93.2h25.4zM285.7 95.7h25.4zM285.7 98.2h25.4zM285.7 88.1l-2.5 2.5zM289.8 91.2h13.7zM295.7 88.6h7.8zM311.1 80.5h.6zM311.1 83h.6zM311.1 85.5h.6z"/>
<path d="M311.1 88.1h.6zM311.1 90.6h.6zM311.1 93.2h.6zM311.1 95.7h.6zM311.1 98.2h.6zM285.7 88.1h25.4zM318.2 80.5h.5zM318.2 83h.5zM318.2 85.5h.5zM318.2 88.1h.5zM318.2 90.6h.5zM318.2 93.2h.5z"/>
<path d="M318.2 95.7h.5zM318.2 98.2h.5zM318.7 80.5h25.4zM318.7 83h25.4zM318.7 85.5h25.4zM318.7 88.1h25.4zM318.7 90.6h25.4zM318.7 93.2h25.4zM318.7 95.7h25.4zM318.7 98.2h25.4zM346.7 98.2l-2.6 2.6zM346.7 80.5l-2.6 2.5z"/>
<path d="M346.7 83l-2.6 2.5zM344.1 88.1l2.6-2.6zM346.7 88.1l-2.6 2.5zM346.7 90.6l-2.6 2.6zM344.1 95.7l2.6-2.5zM346.7 95.7l-2.6 2.5zM46.6 116.2h12zM52.5 111.1h6.1zM85.1 98.2l.6 2.9zM85.9 101.7v.2zM86.1 102.6l.6 2.8zM86.9 106.1v.1z"/>
<path d="M87.1 106.8l.6 2.9zM87.9 110.4v.1zM88.1 111.2l.6 2.8zM88.9 114.7v.1zM89.1 115.5l.6 2.8zM89.9 119v.1zM62.2 117.3h30.5zM92.7 117.3l2.5 2.5zM62.2 112.2h30.5zM92.7 112.2l2.5 2.5zM62.2 107.1h30.5zM92.7 107.1l2.5 2.6z"/>
<path d="M62.2 102h30.5zM92.7 102l2.5 2.6zM146 103.3l2.6-2.5zM148.6 98.2l-2.6 2.6zM148.6 100.8h38.1zM153.6 105.9l2.6-2.6zM153.6 108.4l2.6-2.5zM153.6 110.9l2.6-2.5zM153.6 113.5l2.6-2.6zM153.6 116l2.6-2.5zM153.6 118.6l2.6-2.6zM156.2 103.3h30.5z"/>
<path d="M156.2 105.9h30.5zM156.2 108.4h30.5zM156.2 110.9h30.5zM156.2 113.5h30.5zM156.2 116h30.5zM186.7 100.8h5zM186.7 103.3h5zM186.7 105.9h5zM186.7 108.4h5zM186.7 110.9h5zM186.7 113.5h5zM186.7 116h5z"/>
<path d="M207 116h5.1zM207 113.5h5.1zM207 110.9h5.1zM207 108.4h5.1zM207 105.9h5.1zM207 103.3h5.1zM207 100.8h5.1zM212.1 100.8h25.4zM212.1 103.3h25.4zM212.1 105.9h25.4zM212.1 108.4h25.4zM212.1 110.9h25.4z"/>
<path d="M212.1 113.5h25.4zM212.1 116h25.4zM237.5 98.2l2.5 2.6zM237.5 100.8l2.5 2.5zM237.5 103.3l2.5 2.6zM237.5 105.9l2.5 2.5zM237.5 108.4l2.5 2.5zM237.5 110.9l2.5 2.6zM237.5 113.5l2.5 2.5zM237.5 116l2.5 2.6zM285.7 98.2l-2.5 2.6zM283.2 103.3l2.5-2.5z"/>
<path d="M285.7 103.3l-2.5 2.6zM285.7 105.9l-2.5 2.5zM283.2 110.9l2.5-2.5zM285.7 110.9l-2.5 2.6zM285.7 100.8h25.4zM285.7 103.3h25.4zM285.7 105.9h25.4zM285.7 108.4h25.4zM285.7 110.9h25.4zM285.7 113.5l-2.5 2.5zM311.1 100.8h.6zM311.1 103.3h.6z"/>
<path d="M311.1 105.9h.6zM311.1 108.4h.6zM311.1 110.9h.6zM311.1 113.5h.6zM311.1 116h.6zM285.7 113.5h25.4zM318.2 100.8h.5zM318.2 103.3h.5zM318.2 105.9h.5zM318.2 108.4h.5zM318.2 110.9h.5zM318.2 113.5h.5z"/>
<path d="M318.2 116h.5zM318.7 110.9h25.4zM318.7 100.8h25.4zM318.7 103.3h25.4zM318.7 105.9h25.4zM318.7 108.4h25.4zM344.1 110.9l2.6-2.5zM344.1 103.3l2.6-2.5zM346.7 103.3l-2.6 2.6zM346.7 105.9l-2.6 2.5zM16.5 123.1h3.8zM62.2 137.6h22.9z"/>
<path d="M62.2 133.8h22.9zM85.1 133.8l2.5 2.5zM85.1 137.6l2.5 2.5zM90.1 119.8l.6 2.8zM90.9 123.3v.1zM91.1 124.1l.6 2.8zM91.9 127.6v.1zM92.1 128.4l.6 2.9zM156.2 138.9l-2.6 2.5zM184.1 126.2v2.5zM184.1 123.6v2.6zM184.1 121.1v2.5z"/>
<path d="M186.7 121.1h3.1zM186.7 123.6h3.1zM186.7 138.9h5zM184.1 123.6h2.6zM184.1 121.1h2.6zM156.2 138.9h30.5zM207 138.9h5.1zM212.1 138.9h25.4zM237.5 138.9l2.5 2.5zM400 123.1h3.8zM62.2 151.6h22.9zM62.2 141.4h22.9z"/>
<path d="M85.1 141.4l2.5 2.6zM62.2 145.2h22.9zM85.1 145.2l2.5 2.6zM85.1 151.6l2.5 2.5zM62.2 155.4h22.9zM85.1 155.4l2.5 2.5zM62.2 159.2h22.9zM85.1 159.2l2.5 2.5zM153.6 149l2.6-2.5zM153.6 151.6l2.6-2.6zM153.6 154.1l2.6-2.5zM153.6 156.7l2.6-2.6z"/>
<path d="M153.6 159.2l2.6-2.5zM156.2 146.5h30.5zM156.2 149h30.5zM156.2 151.6h30.5zM156.2 154.1h30.5zM156.2 156.7h30.5zM156.2 141.4l-2.6 2.6zM158.7 83v61zM186.7 141.4h5zM186.7 144h5zM186.7 146.5h5zM186.7 149h5z"/>
<path d="M186.7 151.6h5zM186.7 154.1h5zM186.7 156.7h5zM156.2 141.4h30.5zM158.7 144h28zM207 156.7h5.1zM207 154.1h5.1zM207 151.6h5.1zM207 149h5.1zM207 146.5h5.1zM207 144h5.1zM207 141.4h5.1z"/>
<path d="M212.1 141.4h25.4zM212.1 144h25.4zM212.1 146.5h25.4zM212.1 149h25.4zM212.1 151.6h25.4zM212.1 154.1h25.4zM212.1 156.7h25.4zM237.5 141.4l2.5 2.6zM237.5 144l2.5 2.5zM237.5 146.5l2.5 2.5zM237.5 149l2.5 2.6zM237.5 151.6l2.5 2.5z"/>
<path d="M237.5 154.1l2.5 2.6zM237.5 156.7l2.5 2.5zM16.5 173.7h3.8zM62.2 165.5h22.9zM62.2 169.4h22.9zM62.2 173.2h22.9zM62.2 177h22.9zM85.1 165.5l2.5 2.6zM85.1 169.4l2.5 2.5zM85.1 173.2l2.5 2.5zM85.1 177l2.5 2.5zM156.2 179.5h30.5z"/>
<path d="M166.2 177.5h7.8zM184.1 166.8v2.6zM184.1 164.3v2.5zM184.1 161.7v2.6zM186.7 161.7h3.1zM186.7 164.3h3.1zM186.7 179.5h5zM184.1 164.3h2.6zM184.1 161.7h2.6zM209 179.5h3.1zM212.1 179.5h25.4zM400 173.7h3.8z"/>
<path d="M50.8 198.8h7.8zM53.8 181h4.8zM54 184.8h4.6zM54.7 189.9h3.9zM54.7 193.7h3.9zM62.2 194.8h22.9zM85.1 194.8l2.5 2.5zM62.2 190.9h22.9zM85.1 190.9l2.5 2.6zM62.2 185.9h22.9zM85.1 185.9l2.5 2.5zM62.2 182.1h22.9z"/>
<path d="M85.1 182.1l2.5 2.5zM62.2 199.8h22.9zM85.1 199.8l2.5 2.6zM156.2 194.8l-2.6 2.5zM153.6 194.8l2.6-2.6zM153.6 192.2l2.6-2.5zM156.2 187.1l-2.6 2.6zM153.6 187.1l2.6-2.5zM153.6 184.6l2.6-2.5zM156.2 179.5l-2.6 2.6zM153.6 199.8l2.6-2.5zM156.2 194.8h30.5z"/>
<path d="M156.2 192.2h30.5zM156.2 189.7h30.5zM156.2 187.1h30.5zM156.2 184.6h30.5zM156.2 182.1h30.5zM156.2 197.3h30.5zM166 192.8h8zM166.2 190.2h7.8zM169.1 180.1h4.9zM169.4 182.6h4.6zM170.1 185.2h3.9zM170.1 187.7h3.9z"/>
<path d="M186.7 182.1h5zM186.7 184.6h5zM186.7 187.1h5zM186.7 189.7h5zM186.7 192.2h5zM186.7 194.8h5zM186.7 197.3h5zM209 197.3h3.1zM209 194.8h3.1zM209 192.2h3.1zM209 189.7h3.1zM209 187.1h3.1z"/>
<path d="M209 184.6h3.1zM209 182.1h3.1zM212.1 182.1h25.4zM212.1 184.6h25.4zM212.1 187.1h25.4zM212.1 189.7h25.4zM212.1 192.2h25.4zM212.1 194.8h25.4zM212.1 197.3h25.4zM237.5 179.5l2.5 2.6zM237.5 182.1l2.5 2.5zM237.5 184.6l2.5 2.5z"/>
<path d="M237.5 187.1l2.5 2.6zM237.5 189.7l2.5 2.5zM237.5 192.2l2.5 2.6zM237.5 194.8l2.5 2.5zM237.5 197.3l2.5 2.5zM50.7 206.4h7.9zM50.9 202.6h7.7zM52.7 216.5h5.9zM62.2 217.6h22.9zM85.1 217.6l2.5 2.5zM62.2 207.4h22.9zM85.1 207.4l2.5 2.6z"/>
<path d="M62.2 203.6h22.9zM85.1 203.6l2.5 2.6zM62.2 212.5h22.9zM85.1 212.5l2.5 2.5zM168.1 218.2h5.9zM184.1 207.4v2.6zM184.1 204.9v2.5zM184.1 204.9h2.6zM184.1 202.4v2.5zM186.7 202.4h3.1zM186.7 204.9h3.1zM184.1 202.4h2.6z"/>
<path d="M16.5 224.2h3.8zM52.8 227.9h5.8zM53.3 233h5.3zM55.9 220.3h2.7zM56.8 224.1h1.8zM62.2 221.4h22.9zM85.1 221.4l2.5 2.5zM62.2 225.2h22.9zM85.1 225.2l2.5 2.5zM62.2 229h22.9zM85.1 229l2.5 2.6zM62.2 234.1h22.9z"/>
<path d="M85.1 234.1l2.5 2.5zM153.6 222.7l2.6-2.6zM153.6 225.2l2.6-2.5zM153.6 227.7l2.6-2.5zM153.6 230.3l2.6-2.6zM153.6 232.8l2.6-2.5zM156.2 220.1h30.5zM156.2 222.7h30.5zM156.2 225.2h30.5zM156.2 227.7h30.5zM156.2 230.3h30.5zM165.1 229l.1 1z"/>
<path d="M165.4 231l.2 1zM165.8 233l.1 1zM166.1 235l.2 1zM166.5 237l.1 1zM166.8 239l.2 1zM168.1 225.8h5.9zM168.7 228.3h5.3zM171.3 220.7h2.7zM172.2 223.2h1.8zM184.1 232.8v2.6zM184.1 235.4v2.5zM184.1 237.9v5.1z"/>
<path d="M186.7 220.1h5zM186.7 222.7h5zM186.7 225.2h5zM186.7 227.7h5zM186.7 230.3h5zM186.7 232.8h5zM186.7 235.4h5zM186.7 237.9h5zM184.1 232.8h2.6zM184.1 235.4h2.6zM184.1 237.9h2.6zM209 237.9h3.1z"/>
<path d="M209 235.4h3.1zM209 232.8h3.1zM209 230.3h3.1zM209 227.7h3.1zM209 225.2h3.1zM209 222.7h3.1zM209 220.1h3.1zM215.3 239l-.3 1zM215.9 237l-.3 1zM216.6 235l-.4 1zM217.2 233l-.3 1zM217.8 231l-.3 1z"/>
<path d="M218.4 229l-.3 1.1zM212.1 222.7h25.4zM212.1 220.1h25.4zM212.1 225.2h25.4zM212.1 227.7h25.4zM212.1 230.3h25.4zM237.5 222.7l2.5 2.5zM237.5 220.1l2.5 2.6zM237.5 225.2l2.5 2.5zM237.5 227.7l2.5 2.6zM237.5 230.3l2.5 2.5zM400 224.2h3.8z"/>
<path d="M59.7 243h25.4zM59.7 248.1h25.4zM85.1 243l2.5 2.5zM85.1 248.1l2.5 2.5zM167.2 241l.1 1zM167.5 242.9l.2 1.1zM167.8 244.9l.2 1.1zM168.2 246.9l.1 1zM168.5 248.9l.2 1zM168.9 250.9l.1 1zM169.2 252.9l.2 1zM169.5 254.9l.2 1z"/>
<path d="M169.9 256.9l.2 1zM170.2 258.9l.2 1zM184.1 248.1v2.5zM184.1 243v2.5zM184.1 245.5v2.6zM186.7 243h3.1zM186.7 245.5h3.1zM184.1 245.5h2.6zM184.1 243h2.6zM209.2 258.8l-.4 1.1zM209.8 256.9l-.3 1zM210.4 254.9l-.3 1z"/>
<path d="M211 252.9l-.3 1zM211.6 250.9l-.3 1zM212.2 248.9l-.3 1.1zM212.9 246.9l-.4 1.1zM213.5 244.9l-.3 1.1zM214.1 242.9l-.3 1.1zM214.7 241l-.3 1zM20.3 274.7h379.7zM67.8 274.7v3.8zM115.3 274.7v3.8zM160.3 266.4h4zM162.7 274.7v3.8z"/>
<path d="M170.6 260.9l.1 1zM170.9 262.9l.2 1zM171.3 264.9l.1 .9zM200 266.4h5.8zM207.3 264.8l-.3 1zM207.9 262.8l-.3 1.1zM208.6 260.8l-.4 1.1zM210.2 274.7v3.8zM215.6 266.4h5.8zM257.6 274.7v3.8zM305.1 274.7v3.8zM352.5 274.7v3.8z"/>
<path d="M400 264.5v.1zM400 268.4v6.2zM400 274.6h.1zM400 22.1v252.6z"/>
<circle cx="184.1" cy="83" r=".51"/>
<circle cx="184.1" cy="123.6" r=".51"/>
<circle cx="184.1" cy="164.3" r=".51"/>
<circle cx="184.1" cy="204.9" r=".51"/>
<circle cx="184.1" cy="237.9" r=".51"/>
<circle cx="184.1" cy="235.4" r=".51"/>
<circle cx="184.1" cy="243" r=".51"/>
<circle cx="184.1" cy="245.5" r=".51"/>
</g>
<g fill="#000" stroke="#000" stroke-width=".28">
<path d="M51.1 53.6v3zM51.1 57.4v3zM51.1 53.6h9.6zM51.1 56.6h9.6zM51.1 57.4h9.6zM60.7 53.6l1.5 1.5zM60.7 56.6l1.5-1.5zM60.7 57.4l1.5 1.5zM60.7 60.4l1.5-1.5zM46.9 70v3.1zM50.6 75.1v3.1zM51.1 61.1v3.1z"/>
<path d="M51.1 65v3zM46.9 70h13.8zM46.9 73.1h13.8zM50.6 75.1h10.1zM50.6 78.2h10.1zM51.1 60.4h9.6zM51.1 61.1h9.6zM51.1 64.2h9.6zM51.1 65h9.6zM51.1 68h9.6zM60.7 70l1.5 1.6zM62.2 71.6l-1.5 1.5z"/>
<path d="M60.7 75.1l1.5 1.5zM62.2 76.6l-1.5 1.6zM60.7 61.1l1.5 1.6zM62.2 62.7l-1.5 1.5zM60.7 65l1.5 1.5zM62.2 66.5l-1.5 1.5zM52.5 80.2v3zM52.5 84v3.1zM52.5 87.8v3.1zM52.5 91.6v3.1zM52.5 95.4v3.1zM52.5 80.2h8.2z"/>
<path d="M52.5 83.2h8.2zM52.5 84h8.2zM52.5 87.1h8.2zM52.5 87.8h8.2zM52.5 90.9h8.2zM52.5 91.6h8.2zM52.5 94.7h8.2zM52.5 95.4h8.2zM52.5 98.5h8.2zM60.7 80.2l1.5 1.5zM62.2 81.7l-1.5 1.5zM60.7 84l1.5 1.5z"/>
<path d="M62.2 85.5l-1.5 1.6zM60.7 87.8l1.5 1.5zM62.2 89.3l-1.5 1.6zM60.7 91.6l1.5 1.6zM62.2 93.2l-1.5 1.5zM60.7 95.4l1.5 1.6zM62.2 97l-1.5 1.5zM81.5 80.7l2.1 2zM81.5 82.7l2.1-2zM81.5 84.5l2.1 2zM81.5 86.5l2.1-2zM81.5 88.3l2.1 2.1z"/>
<path d="M81.5 90.4l2.1-2.1zM81.5 92.1l2.1 2.1zM83.6 92.1l-2.1 2.1zM81.5 95.9l2.1 2.1zM83.6 95.9l-2.1 2.1zM182.2 88.1h3.8zM44.3 115.8v3zM50.2 110.7v3zM54.6 105.6v3zM54.9 100.5v3.1zM44.3 115.8h16.4zM44.3 118.8h16.4z"/>
<path d="M50.2 110.7h10.5zM50.2 113.7h10.5zM54.6 105.6h6.1zM54.6 108.6h6.1zM54.9 100.5h5.8zM54.9 103.6h5.8zM60.7 115.8l1.5 1.5zM62.2 117.3l-1.5 1.5zM60.7 110.7l1.5 1.5zM62.2 112.2l-1.5 1.5zM60.7 105.6l1.5 1.5zM62.2 107.1l-1.5 1.5z"/>
<path d="M60.7 100.5l1.5 1.5zM62.2 102l-1.5 1.6zM48.6 132.3v3zM48.6 136.1v3zM48.6 139.9v3zM48.6 132.3h12.1zM48.6 135.3h12.1zM48.6 136.1h12.1zM48.6 139.1h12.1zM48.6 139.9h12.1zM60.7 132.3l1.5 1.5zM60.7 135.3l1.5-1.5z"/>
<path d="M60.7 136.1l1.5 1.5zM60.7 139.1l1.5-1.5zM182.2 128.7h3.8zM48.1 150v3.1zM48.1 153.9v3zM48.1 157.7v3zM48.6 143.7v3zM48.6 142.9h12.1zM48.6 143.7h12.1zM48.6 146.7h12.1zM48.1 150h12.6zM48.1 153.1h12.6z"/>
<path d="M48.1 153.9h12.6zM48.1 156.9h12.6zM48.1 157.7h12.6zM60.7 139.9l1.5 1.5zM60.7 142.9l1.5-1.5zM60.7 143.7l1.5 1.5zM60.7 146.7l1.5-1.5zM60.7 150l1.5 1.6zM62.2 151.6l-1.5 1.5zM60.7 153.9l1.5 1.5zM62.2 155.4l-1.5 1.5zM60.7 157.7l1.5 1.5z"/>
<path d="M62.2 159.2l-1.5 1.5zM50.5 164v3.1zM50.5 167.8v3.1zM50.5 171.6v3.1zM50.5 175.4v3.1zM48.1 160.7h12.6zM50.5 164h10.2zM50.5 167.1h10.2zM50.5 167.8h10.2zM50.5 170.9h10.2zM50.5 171.6h10.2zM50.5 174.7h10.2z"/>
<path d="M50.5 175.4h10.2zM50.5 178.5h10.2zM60.7 164l1.5 1.5zM60.7 167.1l1.5-1.6zM60.7 167.8l1.5 1.6zM60.7 170.9l1.5-1.5zM60.7 171.6l1.5 1.6zM60.7 174.7l1.5-1.5zM60.7 175.4l1.5 1.6zM60.7 178.5l1.5-1.5zM182.2 169.4h3.8zM48.5 198.3v3.1z"/>
<path d="M51.5 180.5v3.1zM51.8 184.3v3.1zM52.5 193.2v3.1zM52.5 189.4v3.1zM52.5 193.2h8.2zM52.5 196.3h8.2zM52.5 189.4h8.2zM52.5 192.5h8.2zM51.8 184.3h8.9zM51.8 187.4h8.9zM51.5 180.5h9.2zM51.5 183.6h9.2z"/>
<path d="M48.5 198.3h12.2zM60.7 193.2l1.5 1.6zM62.2 194.8l-1.5 1.5zM60.7 189.4l1.5 1.5zM62.2 190.9l-1.5 1.6zM60.7 184.3l1.5 1.6zM62.2 185.9l-1.5 1.5zM60.7 180.5l1.5 1.6zM62.2 182.1l-1.5 1.5zM60.7 198.3l1.5 1.5zM62.2 199.8l-1.5 1.6zM45.5 211v3z"/>
<path d="M48.4 205.9v3.1zM48.5 202.1v3.1zM50.5 216.1v3zM53.7 219.9v3zM50.5 216.1h10.2zM50.5 219.1h10.2zM53.7 219.9h7zM48.4 205.9h12.3zM48.4 209h12.3zM48.5 202.1h12.2zM48.5 205.2h12.2zM48.5 201.4h12.2z"/>
<path d="M45.5 211h15.2zM45.5 214h15.2zM60.7 216.1l1.5 1.5zM62.2 217.6l-1.5 1.5zM60.7 205.9l1.5 1.5zM62.2 207.4l-1.5 1.6zM60.7 202.1l1.5 1.5zM62.2 203.6l-1.5 1.6zM60.7 211l1.5 1.5zM62.2 212.5l-1.5 1.5zM182.2 210h3.8zM50.5 227.5v3z"/>
<path d="M51.1 232.6v3zM54.6 223.7v3zM53.7 222.9h7zM54.6 223.7h6.1zM54.6 226.7h6.1zM50.5 227.5h10.2zM50.5 230.5h10.2zM51.1 232.6h9.6zM51.1 235.6h9.6zM60.7 219.9l1.5 1.5zM62.2 221.4l-1.5 1.5zM60.7 223.7l1.5 1.5z"/>
<path d="M62.2 225.2l-1.5 1.5zM60.7 227.5l1.5 1.5zM62.2 229l-1.5 1.5zM60.7 232.6l1.5 1.5zM62.2 234.1l-1.5 1.5zM46.7 241.5v3zM48.2 246.5v3.1zM48.2 246.5h10zM48.2 249.6h10zM46.7 241.5h11.5zM46.7 244.5h11.5zM58.2 246.5l1.5 1.6z"/>
<path d="M59.7 248.1l-1.5 1.5zM58.2 241.5l1.5 1.5zM59.7 243l-1.5 1.5zM182.2 250.6h3.8zM313.7 249.3h86.3zM313.7 254.4h86.3zM313.7 259.5h58.4zM372.1 259.5h27.9zM372.1 259.5v5.1zM313.7 264.6h58.4zM313.7 269.7h86.3zM372.1 264.6h27.9z"/>
<path d="M400 268.4v1.3z"/>
</g>
<path d="M16.5 18.2v260.3zM16.5 18.2h387.3zM16.5 278.5h387.3zM403.8 18.2v260.3z" fill="#000" stroke="#000" stroke-width=".32"/>
<g fill="#000" stroke="#000" stroke-width=".61">
<path d="M20.3 22.1v252.6zM20.3 22.1h379.7zM191.7 55.1v30.4zM191.7 55.1h15.3zM191.7 85.5h15.3zM191.7 95.7v30.5zM207 55.1v30.4zM191.7 95.7h15.3zM191.7 126.2h15.3zM191.7 136.3v30.5zM207 95.7v30.5zM191.7 136.3h15.3z"/>
<path d="M191.7 166.8h15.3zM191.7 177v30.4zM207 136.3v30.5zM191.7 177h15.3zM191.7 207.4h15.3zM191.7 217.6v30.5zM207 177v30.4zM191.7 217.6h15.3zM191.7 248.1h15.3zM207 217.6v30.5zM283.2 244.3v30.4zM313.7 254.4v5.1z"/>
<path d="M313.7 249.3v5.1zM313.7 244.3v5zM313.7 244.3h86.3zM283.2 244.3h30.5zM400 254.4v5.1zM400 249.3v5.1zM400 244.3v5zM400 22.1v222.2zM20.3 274.7h262.9zM283.2 274.7h30.5zM313.7 274.7h86.3zM313.7 269.7v5z"/>
<path d="M313.7 264.6v5.1zM313.7 259.5v5.1zM400 268.4v6.3zM400 264.6v3.8zM400 259.5v5.1z"/>
</g>
<g fill="none" stroke="#000" stroke-width=".25">
<circle cx="312.7" cy="75.4" r="1"/>
<circle cx="312.7" cy="77.9" r="1"/>
<circle cx="312.7" cy="67.8" r="1"/>
<circle cx="312.7" cy="70.3" r="1"/>
<circle cx="312.7" cy="72.8" r="1"/>
<circle cx="317.2" cy="77.9" r="1"/>
<circle cx="317.2" cy="70.3" r="1"/>
<circle cx="317.2" cy="67.8" r="1"/>
<circle cx="317.2" cy="72.8" r="1"/>
<circle cx="317.2" cy="75.4" r="1"/>
<circle cx="190.8" cy="83" r=".99"/>
<circle cx="190.8" cy="80.5" r=".99"/>
<circle cx="312.7" cy="98.2" r="1"/>
<circle cx="312.7" cy="95.7" r="1"/>
<circle cx="312.7" cy="88.1" r="1"/>
<circle cx="312.7" cy="90.6" r="1"/>
<circle cx="312.7" cy="93.2" r="1"/>
<circle cx="312.7" cy="83" r="1"/>
<circle cx="312.7" cy="85.5" r="1"/>
<circle cx="312.7" cy="80.5" r="1"/>
<circle cx="317.2" cy="88.1" r="1"/>
<circle cx="317.2" cy="93.2" r="1"/>
<circle cx="317.2" cy="95.7" r="1"/>
<circle cx="317.2" cy="90.6" r="1"/>
<circle cx="317.2" cy="98.2" r="1"/>
<circle cx="317.2" cy="80.5" r="1"/>
<circle cx="317.2" cy="85.5" r="1"/>
<circle cx="317.2" cy="83" r="1"/>
<circle cx="312.7" cy="105.9" r="1"/>
<circle cx="312.7" cy="110.9" r="1"/>
<circle cx="312.7" cy="113.5" r="1"/>
<circle cx="312.7" cy="100.8" r="1"/>
<circle cx="312.7" cy="103.3" r="1"/>
<circle cx="312.7" cy="116" r="1"/>
<circle cx="312.7" cy="108.4" r="1"/>
<circle cx="317.2" cy="100.8" r="1"/>
<circle cx="317.2" cy="108.4" r="1"/>
<circle cx="317.2" cy="105.9" r="1"/>
<circle cx="317.2" cy="110.9" r="1"/>
<circle cx="317.2" cy="113.5" r="1"/>
<circle cx="317.2" cy="103.3" r="1"/>
<circle cx="317.2" cy="116" r="1"/>
<circle cx="190.8" cy="123.6" r=".99"/>
<circle cx="190.8" cy="121.1" r=".99"/>
<circle cx="190.8" cy="164.3" r=".99"/>
<circle cx="190.8" cy="161.7" r=".99"/>
<circle cx="208" cy="179.5" r=".99"/>
<circle cx="208" cy="182.1" r=".99"/>
<circle cx="208" cy="192.2" r=".99"/>
<circle cx="208" cy="197.3" r=".99"/>
<circle cx="208" cy="189.7" r=".99"/>
<circle cx="208" cy="184.6" r=".99"/>
<circle cx="208" cy="194.8" r=".99"/>
<circle cx="208" cy="187.1" r=".99"/>
<circle cx="190.8" cy="204.9" r=".99"/>
<circle cx="190.8" cy="202.4" r=".99"/>
<circle cx="208" cy="225.2" r=".99"/>
<circle cx="208" cy="222.7" r=".99"/>
<circle cx="208" cy="237.9" r=".99"/>
<circle cx="208" cy="232.8" r=".99"/>
<circle cx="208" cy="230.3" r=".99"/>
<circle cx="208" cy="235.4" r=".99"/>
<circle cx="208" cy="220.1" r=".99"/>
<circle cx="208" cy="227.7" r=".99"/>
<circle cx="190.8" cy="243" r=".99"/>
<circle cx="190.8" cy="245.5" r=".99"/>
</g>
<path d="M307.3 65.2v53.4zM307.3 65.2h15.3zM307.3 118.6h15.3zM322.6 65.2v53.4zM341.6 222.7v10.1zM341.6 232.8v7.6zM341.6 232.8h55.9zM397.5 222.7v10.1zM341.6 222.7h55.9zM341.6 240.4h55.9zM397.5 232.8v7.6z" fill="#000" stroke="#000" stroke-width=".42"/>
<g fill="#000" stroke="#000" stroke-width=".76">
<path d="M288.3 57.6h53.3zM341.6 57.6l5.1 5.1zM146 60.2v63.4zM240 60.2v175.2zM283.2 62.7l5.1-5.1zM346.7 62.7v45.7zM87.6 136.3v119.4zM95.2 57.6v66zM95.2 123.6l5.1 5.1zM100.3 128.7h40.6zM146 123.6l-5.1 5.1zM240 235.4l5.1 5z"/>
<path d="M283.2 62.7v172.7zM87.6 255.7l5.1 5.1zM153.6 105.9v149.8zM245.1 240.4h33zM278.1 240.4l5.1-5zM92.7 260.8h55.9zM148.6 260.8l5-5.1z"/>
</g>
<path d="M372.1 222.7h25.4v10.1h-25.4z" fill="#000" stroke="#000" stroke-width=".25"/>
<use href="#words"/>
</svg>
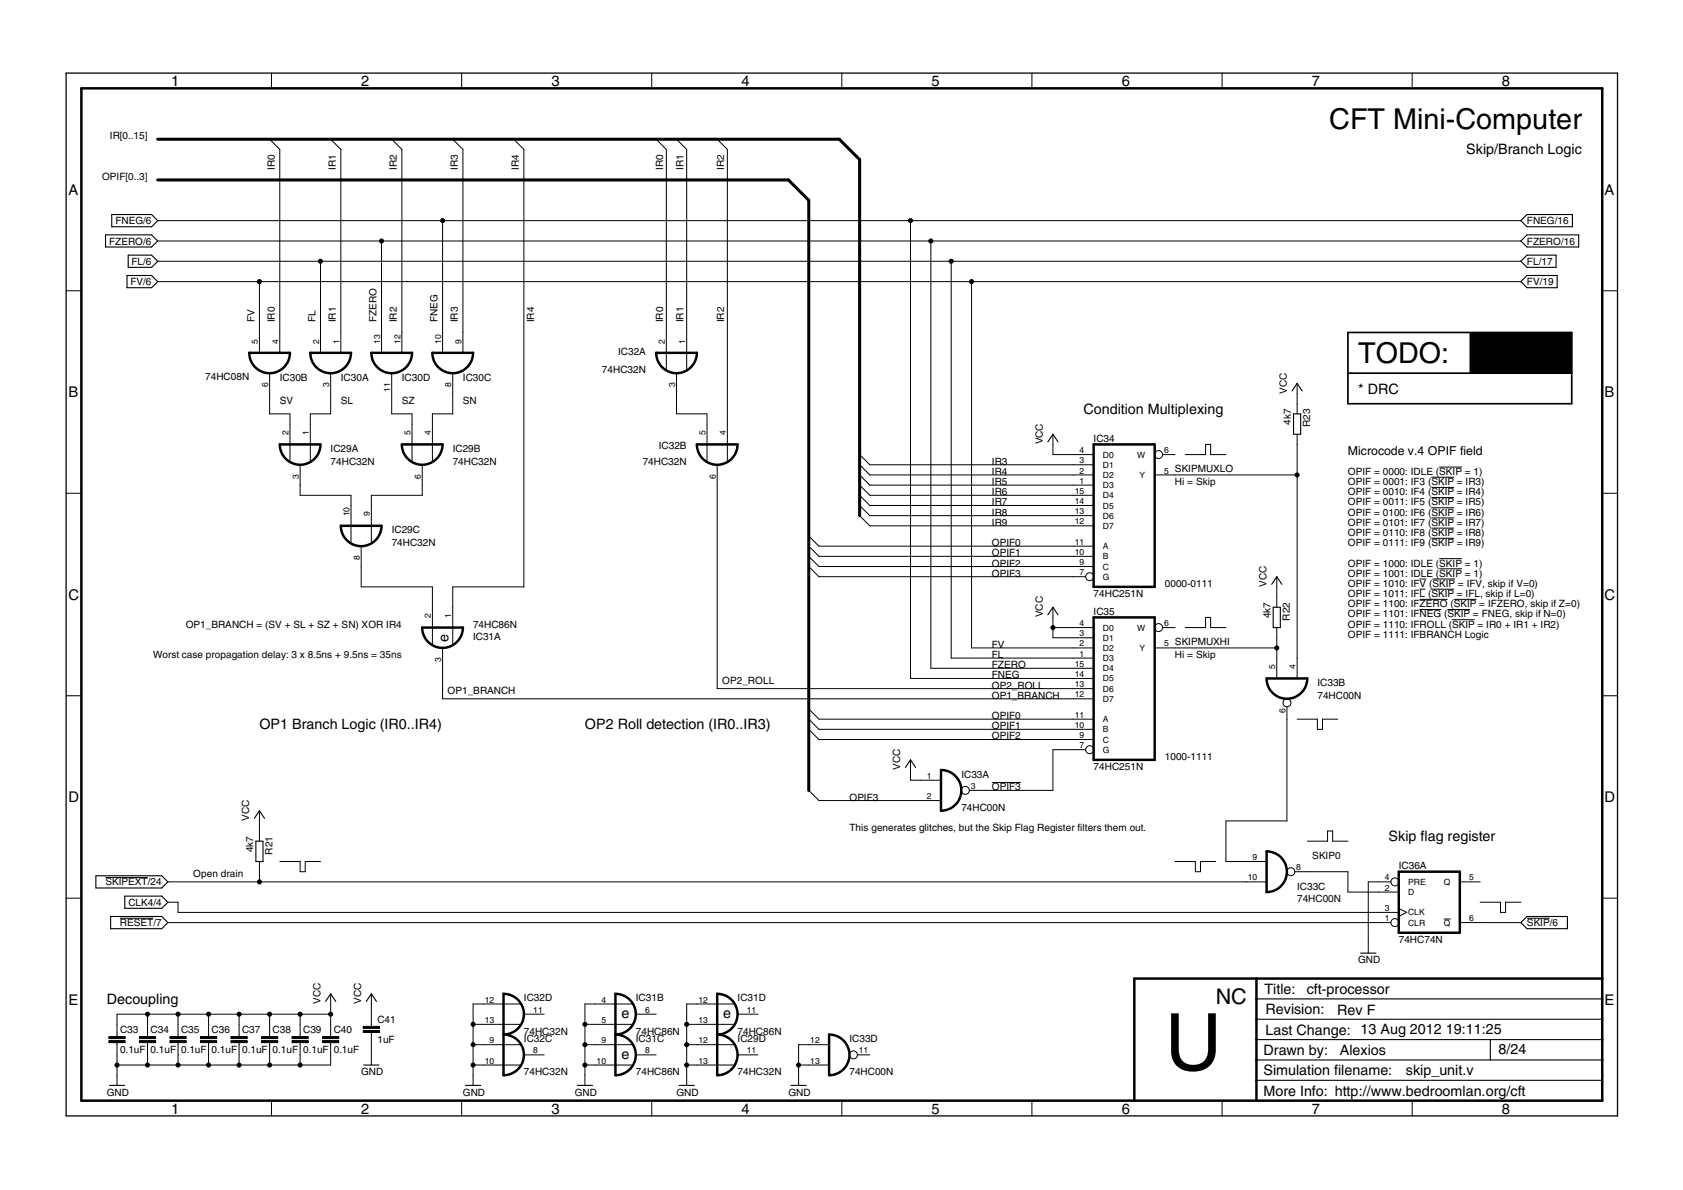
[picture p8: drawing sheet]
<svg xmlns="http://www.w3.org/2000/svg" width="420mm" height="297mm" viewBox="0 0 420 297" stroke-linecap="round" stroke-linejoin="round" font-family="sans-serif">
<defs><g id="words">
<text font-size="19.7" x="290.8" y="267.1">U</text>
<g font-size="7.2">
<text x="331.8" y="32.2">CFT Mini-Computer</text>
<text x="339.1" y="90.6">TODO:</text>
</g>
<text font-size="5.4" x="303.5" y="250.6">NC</text>
<g font-size="3.7">
<text x="42.7" y="21.5">1</text>
<text x="90.2" y="21.5">2</text>
<text x="137.7" y="21.5">3</text>
<text x="185.1" y="21.5">4</text>
<text x="232.6" y="21.5">5</text>
<text x="280" y="21.5">6</text>
<text x="327.5" y="21.5">7</text>
<text x="375" y="21.5">8</text>
<text x="17.1" y="48.6">A</text>
<text x="400.6" y="48.6">A</text>
<text x="17.1" y="99.2">B</text>
<text x="400.6" y="99.2">B</text>
<text x="17.1" y="149.7">C</text>
<text x="400.6" y="149.7">C</text>
<text x="17.1" y="200.2">D</text>
<text x="400.6" y="200.2">D</text>
<text x="17.1" y="250.8">E</text>
<text x="400.6" y="250.8">E</text>
<text x="42.7" y="277.9">1</text>
<text x="90.2" y="277.9">2</text>
<text x="137.7" y="277.9">3</text>
<text x="185.1" y="277.9">4</text>
<text x="232.6" y="277.9">5</text>
<text x="280" y="277.9">6</text>
<text x="327.5" y="277.9">7</text>
<text x="375" y="277.9">8</text>
</g>
<g font-size="3.6">
<text x="366.1" y="38.6">Skip/Branch Logic</text>
<text x="339.1" y="98.2">* DRC</text>
<text x="270.5" y="103.3">Condition Multiplexing</text>
<text x="112" y="160.2" transform="rotate(-90 112 160.2)">e</text>
<text x="64.8" y="182">OP1 Branch Logic (IR0..IR4)</text>
<text x="146" y="182">OP2 Roll detection (IR0..IR3)</text>
<text x="346.7" y="210">Skip flag register</text>
<text x="26.7" y="250.6">Decoupling</text>
<text x="315.7" y="248.1">Title:</text>
<text x="326.2" y="248.2">cft-processor</text>
<text x="155.2" y="254.2">e</text>
<text x="180.6" y="254.2">e</text>
<text x="315.9" y="253.2">Revision:</text>
<text x="333.8" y="253.3">Rev F</text>
<text x="315.4" y="263.3">Drawn by:</text>
<text x="315.9" y="258.2">Last Change: 13 Aug 2012</text>
<text x="334.5" y="263.3">Alexios</text>
<text x="361" y="258.1">19:11:25</text>
<text x="374.1" y="263.2">8/24</text>
<text x="155.2" y="264.3">e</text>
<text x="315.4" y="268.4">Simulation filename:</text>
<text x="351" y="268.4">skip_unit.v</text>
<text x="315.4" y="273.5">More Info: http://www.bedroomlan.org/cft</text>
</g>
<text font-size="3.1" x="336.5" y="113.5">Microcode v.4 OPIF field</text>
<g font-size="2.5">
<text x="27.4" y="34.7">IR[0..15]</text>
<text x="25.5" y="44.9">OPIF[0..3]</text>
<text x="68.6" y="42.4" transform="rotate(-90 68.6 42.4)">IR0</text>
<text x="83.8" y="42.4" transform="rotate(-90 83.8 42.4)">IR1</text>
<text x="99" y="42.4" transform="rotate(-90 99 42.4)">IR2</text>
<text x="114.3" y="42.4" transform="rotate(-90 114.3 42.4)">IR3</text>
<text x="129.5" y="42.4" transform="rotate(-90 129.5 42.4)">IR4</text>
<text x="165.6" y="42.4" transform="rotate(-90 165.6 42.4)">IR0</text>
<text x="170.7" y="42.4" transform="rotate(-90 170.7 42.4)">IR1</text>
<text x="180.8" y="42.4" transform="rotate(-90 180.8 42.4)">IR2</text>
<text x="28.8" y="56">FNEG/6</text>
<text x="381.2" y="56">FNEG/16</text>
<text x="27.2" y="61">FZERO/6</text>
<text x="381.2" y="61">FZERO/16</text>
<text x="32.6" y="71.2">FV/6</text>
<text x="32.8" y="66.1">FL/6</text>
<text x="381.2" y="66.1">FL/17</text>
<text x="381.2" y="71.2">FV/19</text>
<text x="63.5" y="80.5" transform="rotate(-90 63.5 80.5)">FV</text>
<text x="68.6" y="80.5" transform="rotate(-90 68.6 80.5)">IR0</text>
<text x="78.7" y="80.5" transform="rotate(-90 78.7 80.5)">FL</text>
<text x="83.8" y="80.5" transform="rotate(-90 83.8 80.5)">IR1</text>
<text x="94" y="80.5" transform="rotate(-90 94 80.5)">FZERO</text>
<text x="99" y="80.5" transform="rotate(-90 99 80.5)">IR2</text>
<text x="109.2" y="80.5" transform="rotate(-90 109.2 80.5)">FNEG</text>
<text x="114.3" y="80.5" transform="rotate(-90 114.3 80.5)">IR3</text>
<text x="133.3" y="80.5" transform="rotate(-90 133.3 80.5)">IR4</text>
<text x="165.6" y="80.5" transform="rotate(-90 165.6 80.5)">IR0</text>
<text x="170.7" y="80.5" transform="rotate(-90 170.7 80.5)">IR1</text>
<text x="180.8" y="80.5" transform="rotate(-90 180.8 80.5)">IR2</text>
<text x="154.3" y="88.7">IC32A</text>
<text x="51.2" y="94.9">74HC08N</text>
<text x="69.8" y="95.1">IC30B</text>
<text x="85.1" y="95.1">IC30A</text>
<text x="100.3" y="95.1">IC30D</text>
<text x="115.6" y="95.1">IC30C</text>
<text x="150.3" y="93.2">74HC32N</text>
<text x="69.8" y="100.8">SV</text>
<text x="85.1" y="100.8">SL</text>
<text x="100.3" y="100.8">SZ</text>
<text x="115.6" y="100.8">SN</text>
<text x="321.3" y="98.2" transform="rotate(-90 321.3 98.2)">VCC</text>
<text x="322.3" y="106.1" transform="rotate(-90 322.3 106.1)">4k7</text>
<text x="327.1" y="106.6" transform="rotate(-90 327.1 106.6)">R23</text>
<text x="82.5" y="112.8">IC29A</text>
<text x="113" y="112.8">IC29B</text>
<text x="164.5" y="112.1">IC32B</text>
<text x="260.3" y="110.9" transform="rotate(-90 260.3 110.9)">VCC</text>
<text x="273" y="110.3">IC34</text>
<text x="82.5" y="116">74HC32N</text>
<text x="113" y="116">74HC32N</text>
<text x="160.4" y="116">74HC32N</text>
<text x="247.6" y="116">IR3</text>
<text x="247.6" y="118.6">IR4</text>
<text x="293.3" y="117.8">SKIPMUXLO</text>
<text x="336.5" y="118.6">OPIF = 0000: IDLE (SKIP = 1)</text>
<text x="247.6" y="123.6">IR6</text>
<text x="247.6" y="121.1">IR5</text>
<text x="293.3" y="121.1">Hi = Skip</text>
<text x="336.5" y="121.1">OPIF = 0001: IF3 (SKIP = IR3)</text>
<text x="336.5" y="123.6">OPIF = 0010: IF4 (SKIP = IR4)</text>
<text x="247.6" y="126.2">IR7</text>
<text x="247.6" y="128.7">IR8</text>
<text x="247.6" y="131.3">IR9</text>
<text x="336.5" y="126.2">OPIF = 0011: IF5 (SKIP = IR5)</text>
<text x="336.5" y="128.7">OPIF = 0100: IF6 (SKIP = IR6)</text>
<text x="336.5" y="131.3">OPIF = 0101: IF7 (SKIP = IR7)</text>
<text x="97.8" y="136.3">74HC32N</text>
<text x="97.8" y="133.2">IC29C</text>
<text x="247.6" y="136.3">OPIF0</text>
<text x="336.5" y="133.8">OPIF = 0110: IF8 (SKIP = IR8)</text>
<text x="336.5" y="136.3">OPIF = 0111: IF9 (SKIP = IR9)</text>
<text x="247.6" y="138.9">OPIF1</text>
<text x="247.6" y="141.4">OPIF2</text>
<text x="247.6" y="144">OPIF3</text>
<text x="336.5" y="141.4">OPIF = 1000: IDLE (SKIP = 1)</text>
<text x="336.5" y="144">OPIF = 1001: IDLE (SKIP = 1)</text>
<text x="273" y="149">74HC251N</text>
<text x="290.8" y="146.5">0000-0111</text>
<text x="316.2" y="146.5" transform="rotate(-90 316.2 146.5)">VCC</text>
<text x="336.5" y="146.5">OPIF = 1010: IFV (SKIP = IFV, skip if V=0)</text>
<text x="336.5" y="149">OPIF = 1011: IFL (SKIP = IFL, skip if L=0)</text>
<text x="260.3" y="154.1" transform="rotate(-90 260.3 154.1)">VCC</text>
<text x="273" y="153.5">IC35</text>
<text x="317.2" y="154.3" transform="rotate(-90 317.2 154.3)">4k7</text>
<text x="322" y="154.9" transform="rotate(-90 322 154.9)">R22</text>
<text x="336.5" y="151.6">OPIF = 1100: IFZERO (SKIP = IFZERO, skip if Z=0)</text>
<text x="336.5" y="154.1">OPIF = 1101: IFNEG (SKIP = FNEG, skip if N=0)</text>
<text x="46.4" y="156.6">OP1_BRANCH = (SV + SL + SZ + SN) XOR IR4</text>
<text x="118.1" y="156.6">74HC86N</text>
<text x="118.1" y="159.8">IC31A</text>
<text x="247.6" y="161.7">FV</text>
<text x="293.3" y="161">SKIPMUXHI</text>
<text x="336.5" y="156.6">OPIF = 1110: IFROLL (SKIP = IR0 + IR1 + IR2)</text>
<text x="336.5" y="159.2">OPIF = 1111: IFBRANCH Logic</text>
<text x="38.2" y="164.3">Worst case propagation delay: 3 x 8.5ns + 9.5ns = 35ns</text>
<text x="247.6" y="166.8">FZERO</text>
<text x="247.6" y="164.3">FL</text>
<text x="293.3" y="164.3">Hi = Skip</text>
<text x="111.7" y="173.2">OP1_BRANCH</text>
<text x="180.3" y="170.6">OP2_ROLL</text>
<text x="247.6" y="171.9">OP2_ROLL</text>
<text x="247.6" y="169.3">FNEG</text>
<text x="328.9" y="171.3">IC33B</text>
<text x="247.6" y="179.5">OPIF0</text>
<text x="247.6" y="174.4">OP1_BRANCH</text>
<text x="328.9" y="174.4">74HC00N</text>
<text x="247.6" y="182">OPIF1</text>
<text x="247.6" y="184.6">OPIF2</text>
<text x="290.8" y="189.7">1000-1111</text>
<text x="224.8" y="192.2" transform="rotate(-90 224.8 192.2)">VCC</text>
<text x="240" y="194.1">IC33A</text>
<text x="247.6" y="197.3">OPIF3</text>
<text x="273" y="192.2">74HC251N</text>
<text x="212.1" y="199.8">OPIF3</text>
<text x="240" y="202.4">74HC00N</text>
<text x="62.2" y="204.9" transform="rotate(-90 62.2 204.9)">VCC</text>
<text x="212.1" y="207.4">This generates glitches, but the Skip Flag Register filters them out.</text>
<text x="63.2" y="212.8" transform="rotate(-90 63.2 212.8)">4k7</text>
<text x="68" y="213.3" transform="rotate(-90 68 213.3)">R21</text>
<text x="327.6" y="214.3">SKIP0</text>
<text x="26.3" y="221">SKIPEXT/24</text>
<text x="48.3" y="218.9">Open drain</text>
<text x="349.2" y="217">IC36A</text>
<text x="32" y="226.1">CLK4/4</text>
<text x="323.8" y="225.2">74HC00N</text>
<text x="323.8" y="222">IC33C</text>
<text x="29.9" y="231.2">RESET/7</text>
<text x="381.2" y="231.2">SKIP/6</text>
<text x="349.2" y="235.4">74HC74N</text>
<text x="339.1" y="240.5">GND</text>
<text x="80" y="250.6" transform="rotate(-90 80 250.6)">VCC</text>
<text x="90.2" y="250.6" transform="rotate(-90 90.2 250.6)">VCC</text>
<text x="130.8" y="250">IC32D</text>
<text x="158.7" y="250">IC31B</text>
<text x="184.1" y="250">IC31D</text>
<text x="30" y="257.9">C33</text>
<text x="37.6" y="257.9">C34</text>
<text x="45.2" y="257.9">C35</text>
<text x="52.8" y="257.9">C36</text>
<text x="60.4" y="257.9">C37</text>
<text x="68.1" y="257.9">C38</text>
<text x="75.7" y="257.9">C39</text>
<text x="83.3" y="257.9">C40</text>
<text x="94.2" y="255.3">C41</text>
<text x="30" y="262.9">0.1uF</text>
<text x="37.6" y="262.9">0.1uF</text>
<text x="45.2" y="262.9">0.1uF</text>
<text x="52.8" y="262.9">0.1uF</text>
<text x="60.4" y="262.9">0.1uF</text>
<text x="68.1" y="262.9">0.1uF</text>
<text x="75.7" y="262.9">0.1uF</text>
<text x="83.3" y="262.9">0.1uF</text>
<text x="94.2" y="260.4">1uF</text>
<text x="130.8" y="258.2">74HC32N</text>
<text x="130.8" y="260.1">IC32C</text>
<text x="158.7" y="258.2">74HC86N</text>
<text x="158.7" y="260.1">IC31C</text>
<text x="184.1" y="258.2">74HC86N</text>
<text x="184.1" y="260.1">IC29D</text>
<text x="212.1" y="260.1">IC33D</text>
<text x="90.2" y="268.4">GND</text>
<text x="130.8" y="268.4">74HC32N</text>
<text x="158.7" y="268.4">74HC86N</text>
<text x="184.1" y="268.4">74HC32N</text>
<text x="212.1" y="268.4">74HC00N</text>
<text x="26.7" y="273.5">GND</text>
<text x="115.6" y="273.5">GND</text>
<text x="143.5" y="273.5">GND</text>
<text x="168.9" y="273.5">GND</text>
<text x="196.8" y="273.5">GND</text>
</g>
<g font-size="2.1">
<text x="64.4" y="85.7" transform="rotate(-90 64.4 85.7)">5</text>
<text x="69.5" y="85.7" transform="rotate(-90 69.5 85.7)">4</text>
<text x="79.6" y="85.7" transform="rotate(-90 79.6 85.7)">2</text>
<text x="84.7" y="85.7" transform="rotate(-90 84.7 85.7)">1</text>
<text x="94.9" y="85.7" transform="rotate(-90 94.9 85.7)">13</text>
<text x="100" y="85.7" transform="rotate(-90 100 85.7)">12</text>
<text x="110.1" y="85.7" transform="rotate(-90 110.1 85.7)">10</text>
<text x="115.2" y="85.7" transform="rotate(-90 115.2 85.7)">9</text>
<text x="166" y="85.7" transform="rotate(-90 166 85.7)">2</text>
<text x="171.1" y="85.7" transform="rotate(-90 171.1 85.7)">1</text>
<text x="66.9" y="96.7" transform="rotate(-90 66.9 96.7)">6</text>
<text x="82.2" y="96.7" transform="rotate(-90 82.2 96.7)">3</text>
<text x="97.4" y="97.9" transform="rotate(-90 97.4 97.9)">11</text>
<text x="112.7" y="96.7" transform="rotate(-90 112.7 96.7)">8</text>
<text x="168.5" y="96.7" transform="rotate(-90 168.5 96.7)">3</text>
<text x="72" y="108.6" transform="rotate(-90 72 108.6)">2</text>
<text x="77.1" y="108.6" transform="rotate(-90 77.1 108.6)">1</text>
<text x="102.5" y="108.6" transform="rotate(-90 102.5 108.6)">5</text>
<text x="107.6" y="108.6" transform="rotate(-90 107.6 108.6)">4</text>
<text x="176.2" y="108.6" transform="rotate(-90 176.2 108.6)">5</text>
<text x="181.2" y="108.6" transform="rotate(-90 181.2 108.6)">4</text>
<text x="269.5" y="113.1">4</text>
<text x="290.6" y="113.1">6</text>
<text x="74.6" y="119.5" transform="rotate(-90 74.6 119.5)">3</text>
<text x="105" y="119.5" transform="rotate(-90 105 119.5)">6</text>
<text x="178.7" y="119.5" transform="rotate(-90 178.7 119.5)">6</text>
<text x="269.5" y="118.2">2</text>
<text x="269.5" y="115.7">3</text>
<text x="275.4" y="119.3">D2</text>
<text x="275.4" y="116.8">D1</text>
<text x="275.4" y="114.2">D0</text>
<text x="283.9" y="114.2">W</text>
<text x="284.5" y="119.3">Y</text>
<text x="290.6" y="118.2">5</text>
<text x="268.3" y="125.8">14</text>
<text x="268.3" y="123.3">15</text>
<text x="269.5" y="120.7">1</text>
<text x="275.4" y="121.9">D3</text>
<text x="275.4" y="124.4">D4</text>
<text x="87.3" y="128.9" transform="rotate(-90 87.3 128.9)">10</text>
<text x="92.3" y="128.9" transform="rotate(-90 92.3 128.9)">9</text>
<text x="268.3" y="130.9">12</text>
<text x="268.3" y="128.4">13</text>
<text x="275.4" y="129.5">D6</text>
<text x="275.4" y="126.9">D5</text>
<text x="268.3" y="136">11</text>
<text x="275.4" y="137.1">A</text>
<text x="275.4" y="132">D7</text>
<text x="89.8" y="139.9" transform="rotate(-90 89.8 139.9)">8</text>
<text x="268.3" y="138.5">10</text>
<text x="269.5" y="143.6">7</text>
<text x="269.5" y="141.1">9</text>
<text x="275.4" y="142.2">C</text>
<text x="275.4" y="139.6">B</text>
<text x="275.4" y="144.7">G</text>
<text x="107.6" y="154.3" transform="rotate(-90 107.6 154.3)">2</text>
<text x="112.7" y="154.3" transform="rotate(-90 112.7 154.3)">1</text>
<text x="269.5" y="161.4">2</text>
<text x="269.5" y="158.8">3</text>
<text x="269.5" y="156.3">4</text>
<text x="275.4" y="159.9">D1</text>
<text x="275.4" y="157.4">D0</text>
<text x="283.9" y="157.4">W</text>
<text x="290.6" y="161.4">5</text>
<text x="290.6" y="156.3">6</text>
<text x="110.1" y="165.2" transform="rotate(-90 110.1 165.2)">3</text>
<text x="268.3" y="166.5">15</text>
<text x="269.5" y="163.9">1</text>
<text x="275.4" y="165">D3</text>
<text x="275.4" y="162.5">D2</text>
<text x="275.4" y="167.6">D4</text>
<text x="284.5" y="162.5">Y</text>
<text x="318.4" y="167" transform="rotate(-90 318.4 167)">5</text>
<text x="323.5" y="167" transform="rotate(-90 323.5 167)">4</text>
<text x="268.3" y="171.5">13</text>
<text x="268.3" y="169">14</text>
<text x="275.4" y="172.6">D6</text>
<text x="275.4" y="170.1">D5</text>
<text x="268.3" y="179.1">11</text>
<text x="268.3" y="174.1">12</text>
<text x="275.4" y="175.2">D7</text>
<text x="320.9" y="177.9" transform="rotate(-90 320.9 177.9)">6</text>
<text x="268.3" y="181.7">10</text>
<text x="269.5" y="184.2">9</text>
<text x="275.4" y="185.3">C</text>
<text x="275.4" y="182.8">B</text>
<text x="275.4" y="180.3">A</text>
<text x="269.5" y="186.8">7</text>
<text x="275.4" y="187.9">G</text>
<text x="231.4" y="194.4">1</text>
<text x="242.3" y="196.9">3</text>
<text x="231.4" y="199.5">2</text>
<text x="312.7" y="214.7">9</text>
<text x="311.5" y="219.8">10</text>
<text x="323.6" y="217.2">8</text>
<text x="345.7" y="219.8">4</text>
<text x="351.5" y="220.9">PRE</text>
<text x="360.4" y="220.9">Q</text>
<text x="366.8" y="219.8">5</text>
<text x="345.7" y="222.3">2</text>
<text x="345.7" y="227.4">3</text>
<text x="351.5" y="223.4">D</text>
<text x="345.7" y="229.9">1</text>
<text x="351.5" y="231.1">CLR</text>
<text x="351.5" y="228.5">CLK</text>
<text x="360.4" y="231.1">Q</text>
<text x="366.8" y="229.9">6</text>
<text x="121" y="250.3">12</text>
<text x="150.1" y="250.3">4</text>
<text x="174.3" y="250.3">12</text>
<text x="121" y="255.3">13</text>
<text x="133.1" y="252.8">11</text>
<text x="150.1" y="255.3">5</text>
<text x="161.1" y="252.8">6</text>
<text x="174.3" y="255.3">13</text>
<text x="186.5" y="252.8">11</text>
<text x="122.2" y="260.4">9</text>
<text x="133.1" y="263">8</text>
<text x="150.1" y="260.4">9</text>
<text x="161.1" y="263">8</text>
<text x="174.3" y="260.4">12</text>
<text x="186.5" y="263">11</text>
<text x="202.3" y="260.4">12</text>
<text x="214.4" y="263">11</text>
<text x="121" y="265.5">10</text>
<text x="148.9" y="265.5">10</text>
<text x="174.3" y="265.5">13</text>
<text x="202.3" y="265.5">13</text>
</g>
</g></defs>
<g fill="#000" stroke="#000" stroke-width=".25">
<path d="M67.8 18.2v3.9zM115.3 18.2v3.9zM162.7 18.2v3.9zM210.2 18.2v3.9zM257.6 18.2v3.9zM305.1 18.2v3.9zM352.5 18.2v3.9zM20.3 22.1v252.6zM67.3 34.8l2.5 2.5zM69.8 37.3v45.7zM82.5 34.8l2.6 2.5zM85.1 37.3v45.7z"/>
<path d="M97.8 34.8l2.5 2.5zM100.3 37.3v45.7zM113 34.8l2.6 2.5zM115.6 37.3v45.7zM128.2 34.8l2.6 2.5zM130.8 37.3v109.2zM163.8 34.8l2.5 2.5zM166.3 37.3v45.7zM168.9 34.8l2.5 2.5zM179 34.8l2.6 2.5zM181.6 37.3v68.6zM20.3 22.1h379.7z"/>
<path d="M39.4 55.1h71.1zM110.5 55.1h116.8zM227.3 55.1h152.4zM16.5 72.6h3.8zM39.4 65.2h40.6zM39.4 70.3h25.4zM64.8 70.3h177.7zM80 65.2h157.5zM39.4 60.2h55.8zM95.2 60.2v22.8zM95.2 60.2h137.2zM232.4 60.2v106.6z"/>
<path d="M232.4 60.2h147.3zM237.5 65.2h142.2zM242.5 70.3h137.2zM400 72.6h3.8zM64.8 83v5.1zM64.8 70.3v12.7zM67.3 93.2v5zM67.3 98.2v5.1zM69.8 83v5.1zM80 83v5.1zM80 65.2v17.8zM82.5 93.2v5z"/>
<path d="M82.5 98.2v5.1zM85.1 83v5.1zM95.2 83v5.1zM97.8 93.2v5zM97.8 98.2v5.1zM100.3 83v5.1zM110.5 83v5.1zM110.5 55.1v27.9zM113 93.2v5zM113 98.2v5.1zM115.6 83v5.1zM166.3 83v5.1z"/>
<path d="M166.3 88.1v4.3zM168.9 93.2v5zM168.9 98.2v5.1zM171.4 83v5.1zM171.4 88.1v4.3zM171.4 37.3v45.7zM323.8 95.7v2.5zM323.8 98.2v2.6zM67.3 103.3h5.1zM72.4 105.9v5zM72.4 110.9v4.4zM72.4 103.3v2.6z"/>
<path d="M77.5 105.9v5zM77.5 110.9v4.4zM77.5 103.3v2.6zM77.5 103.3h5zM97.8 103.3h5.1zM102.9 105.9v5zM102.9 110.9v4.4zM102.9 103.3v2.6zM107.9 105.9v5zM107.9 110.9v4.4zM107.9 103.3v2.6zM107.9 103.3h5.1z"/>
<path d="M168.9 103.3h7.6zM176.5 105.9v5zM176.5 110.9v4.4zM176.5 103.3v2.6zM181.6 105.9v5zM181.6 110.9v4.4zM214.6 113.5l2.5 2.5zM214.6 116l2.5 2.6zM214.6 118.6l2.5 2.5zM262.9 108.4v2.5zM262.9 110.9v2.6zM267.9 118.6h5.1z"/>
<path d="M267.9 116h5.1zM267.9 113.5h5.1zM262.9 113.5h5zM217.1 116h50.8zM217.1 118.6h50.8zM288.3 118.6h5zM290.2 113.5h3.1zM293.3 118.6h30.5zM295.9 113.5h5.1zM301 110.9v2.6zM301 110.9h1.2zM302.2 110.9v2.6z"/>
<path d="M302.2 113.5h3.8zM323.8 108.4v2.5zM323.8 100.8v2.5zM323.8 110.9v7.7zM323.8 118.6v45.7zM357.3 119.1h5.7zM359.3 116.6h5.7zM16.5 123.1h3.8zM74.9 116v5.1zM74.9 121.1v2.5zM74.9 123.6h12.7zM87.6 126.2v5.1z"/>
<path d="M87.6 131.3v4.3zM87.6 123.6v2.6zM92.7 126.2v5.1zM92.7 131.3v4.3zM92.7 123.6v2.6zM92.7 123.6h12.7zM105.4 116v5.1zM105.4 121.1v2.5zM179 116v5.1zM201.9 133.8l2.5 2.5zM201.9 136.3l2.5 2.6zM201.9 138.9l2.5 2.5z"/>
<path d="M204.4 136.3h63.5zM214.6 121.1l2.5 2.5zM214.6 123.6l2.5 2.6zM214.6 126.2l2.5 2.5zM214.6 128.7l2.5 2.6zM217.1 123.6h50.8zM217.1 128.7h50.8zM267.9 121.1h5.1zM267.9 138.9h5.1zM267.9 136.3h5.1zM267.9 131.3h5.1zM267.9 128.7h5.1z"/>
<path d="M267.9 126.2h5.1zM267.9 123.6h5.1zM204.4 138.9h63.5zM217.1 126.2h50.8zM217.1 131.3h50.8zM217.1 121.1h50.8zM357.3 121.7h5.7zM357.3 124.2h5.7zM357.3 126.7h5.7zM357.3 129.3h5.7zM357.3 131.8h5.7zM357.3 134.4h5.7z"/>
<path d="M359.3 139.4h5.7zM400 123.1h3.8zM90.2 136.3v5.1zM90.2 141.4v5.1zM90.2 146.5h17.7zM107.9 151.6v5.1zM107.9 146.5v5.1zM113 151.6v5.1zM113 146.5v5.1zM113 146.5h17.8zM201.9 141.4l2.5 2.6zM204.4 141.4h63.5z"/>
<path d="M204.4 144h63.5zM262.9 151.6v2.5zM262.9 154.1v2.6zM262.9 156.7v2.5zM262.9 159.2h5zM267.9 144h3.1zM267.9 141.4h5.1zM267.9 159.2h5.1zM267.9 156.7h5.1zM262.9 156.7h5zM290.2 156.7h3.1zM295.9 156.7h5.1z"/>
<path d="M301 154.1v2.6zM301 154.1h1.2zM302.2 154.1v2.6zM302.2 156.7h3.8zM318.7 144v2.5zM318.7 156.7v2.5zM318.7 149v2.6zM318.7 146.5v2.5zM354.4 144.5h1.7zM354.4 147.1h1.4zM354.4 149.6h7zM354.4 152.1h5.4z"/>
<path d="M357.3 147.1h5.7zM357.6 144.5h5.7zM359.3 142h5.7zM361.4 152.1h5.6zM362.5 154.7h5.7zM362.9 149.6h5.7zM16.5 173.7h3.8zM107.9 156.7v4.3zM110.5 161.7v5.1zM110.5 166.8v7.6zM113 156.7v4.3zM179 121.1v50.8z"/>
<path d="M201.9 177l2.5 2.5zM201.9 179.5l2.5 2.6zM204.4 179.5h63.5zM227.3 169.4h40.6zM227.3 55.1v114.3zM237.5 65.2v99.1zM242.5 70.3v91.4zM267.9 164.3h5.1zM267.9 161.7h5.1zM267.9 179.5h5.1zM267.9 174.4h5.1zM267.9 171.9h5.1z"/>
<path d="M267.9 169.4h5.1zM267.9 166.8h5.1zM179 171.9h88.9zM232.4 166.8h35.5zM237.5 164.3h30.4zM110.5 174.4h157.4zM242.5 161.7h25.4zM288.3 161.7h5zM293.3 161.7h25.4zM318.7 164.3v5.1zM318.7 159.2v2.5zM318.7 161.7v2.6z"/>
<path d="M321.3 176.4v3.1zM321.3 179.5v25.4zM323.8 179.5h5.1zM323.8 164.3v5.1zM328.9 179.5v2.6zM330.2 179.5h3.8zM400 173.7h3.8zM201.9 182.1l2.5 2.5zM201.9 197.3l2.5 2.5zM204.4 184.6h63.5zM204.4 199.8h25.4zM227.3 189.7v2.5z"/>
<path d="M227.3 192.2v2.6zM229.8 194.8h5.1zM229.8 199.8h5.1zM227.3 194.8h2.5zM242 197.3h3.1zM245.1 197.3h17.8zM247.6 195.3h7.3zM262.9 187.1v10.2zM262.9 187.1h5zM267.9 187.1h3.1zM267.9 184.6h5.1zM267.9 182.1h5.1z"/>
<path d="M204.4 182.1h63.5zM328.9 182.1h1.3zM330.2 179.5v2.6zM26.3 219.1h10.6zM64.8 202.4v2.5zM64.8 215v2.6zM64.8 207.4v2.6zM64.8 204.9v2.5zM64.8 217.6v2.5zM69.8 215h5.1zM74.9 215v2.6zM74.9 217.6h1.3z"/>
<path d="M76.2 215v2.6zM76.2 215h3.8zM293.3 215h5.1zM298.4 215v2.6zM298.4 217.6h1.3zM299.7 215v2.6zM299.7 215h3.8zM306 204.9v10.1zM306 215h5.1zM311.1 215h5.1zM306 204.9h15.3zM326.4 210h5z"/>
<path d="M323.3 217.6h3.1zM326.4 217.6h10.1zM331.4 207.4v2.6zM331.4 207.4h1.3zM332.7 207.4v2.6zM332.7 210h3.8zM336.5 217.6v5.1zM16.5 224.2h3.8zM29.9 229.2h8.4zM41.9 220.1h22.9zM44.4 225.2v2.5zM41.9 225.2h2.5z"/>
<path d="M64.8 220.1h246.3zM311.1 220.1h5.1zM336.5 222.7h7.6zM341.6 235.4v2.5zM341.6 220.1v15.3zM344.1 230.3h3.1zM344.1 222.7h5.1zM344.1 227.7h5.1zM344.1 220.1h3.1zM341.6 220.1h2.5zM41.9 230.3h302.2zM44.4 227.7h299.7z"/>
<path d="M349.2 226.8l2 .9zM349.2 228.7l2-1zM360.4 229.4h1.7zM369.5 225.2h5.1zM364.4 220.1h5.1zM364.4 230.3h5.1zM369.5 230.3h10.2zM374.6 225.2v2.5zM374.6 227.7h1.3zM375.9 225.2v2.5zM375.9 225.2h3.8zM381.2 229.2h5.7z"/>
<path d="M400 224.2h3.8zM29.2 255.7v2.5zM29.2 258.2v.5zM29.2 253.1v2.6zM36.8 255.7v2.5zM36.8 258.2v.5zM36.8 253.1v2.6zM29.2 253.1h7.6zM44.4 255.7v2.5zM44.4 258.2v.5zM36.8 253.1h7.6zM44.4 253.1v2.6z"/>
<path d="M52.1 255.7v2.5zM52.1 258.2v.5zM44.4 253.1h7.7zM52.1 253.1v2.6zM59.7 255.7v2.5zM59.7 258.2v.5zM52.1 253.1h7.6zM59.7 253.1v2.6zM67.3 255.7v2.5zM67.3 258.2v.5zM59.7 253.1h7.6zM67.3 253.1v2.6z"/>
<path d="M74.9 255.7v2.5zM74.9 258.2v.5zM67.3 253.1h7.6zM74.9 253.1v2.6zM82.5 248.1v2.5zM82.5 255.7v2.5zM82.5 258.2v.5zM74.9 253.1h7.6zM82.5 250.6v2.5zM82.5 253.1v2.6zM92.7 248.1v2.5zM92.7 253.1v2.6z"/>
<path d="M92.7 255.7v.5zM92.7 257.7v.5zM92.7 250.6v2.5zM118.1 250.6v5.1zM118.1 255.7v5.1zM120.6 250.6h5.1zM120.6 255.7h5.1zM118.1 250.6h2.5zM118.1 255.7h2.5zM125.7 250.6h4.3zM125.7 255.7h4.3zM130.8 253.1h5.1z"/>
<path d="M146 250.6v5.1zM146 255.7v5.1zM148.6 250.6h5zM148.6 255.7h5zM146 250.6h2.6zM146 255.7h2.6zM153.6 250.6h4.4zM153.6 255.7h4.4zM158.7 253.1h5.1zM171.4 250.6v5.1zM171.4 255.7v5.1zM174 250.6h5z"/>
<path d="M174 255.7h5zM171.4 250.6h2.6zM171.4 255.7h2.6zM179 250.6h4.4zM179 255.7h4.4zM184.1 253.1h5.1zM20.3 274.7h379.7zM29.2 268.4v2.5zM29.2 260.8v2.5zM29.2 260.3v.5zM29.2 263.3v2.5zM29.2 265.8h7.6z"/>
<path d="M29.2 265.8v2.6zM36.8 260.8v2.5zM36.8 260.3v.5zM36.8 263.3v2.5zM44.4 260.8v2.5zM44.4 260.3v.5zM36.8 265.8h7.6zM44.4 263.3v2.5zM52.1 260.8v2.5zM52.1 260.3v.5zM44.4 265.8h7.7zM52.1 263.3v2.5z"/>
<path d="M59.7 260.8v2.5zM59.7 260.3v.5zM52.1 265.8h7.6zM59.7 263.3v2.5zM67.3 260.8v2.5zM67.3 260.3v.5zM59.7 265.8h7.6zM67.3 263.3v2.5zM67.8 274.7v3.8zM74.9 260.8v2.5zM74.9 260.3v.5zM67.3 265.8h7.6z"/>
<path d="M74.9 263.3v2.5zM82.5 260.8v2.5zM82.5 260.3v.5zM74.9 265.8h7.6zM82.5 263.3v2.5zM92.7 258.2v2.6zM92.7 263.3v2.5zM92.7 260.8v2.5zM115.3 274.7v3.8zM118.1 268.4v2.5zM118.1 260.8v5zM118.1 265.8v2.6z"/>
<path d="M120.6 260.8h5.1zM120.6 265.8h5.1zM118.1 265.8h2.5zM118.1 260.8h2.5zM125.7 260.8h4.3zM125.7 265.8h4.3zM130.8 263.3h5.1zM146 268.4v2.5zM146 260.8v5zM146 265.8v2.6zM148.6 260.8h5zM148.6 265.8h5z"/>
<path d="M146 260.8h2.6zM146 265.8h2.6zM153.6 260.8h4.4zM153.6 265.8h4.4zM162.7 274.7v3.8zM158.7 263.3h5.1zM171.4 268.4v2.5zM171.4 260.8v5zM171.4 265.8v2.6zM174 260.8h5zM174 265.8h5zM171.4 265.8h2.6z"/>
<path d="M171.4 260.8h2.6zM179 260.8h4.4zM179 265.8h4.4zM184.1 263.3h5.1zM199.4 268.4v2.5zM199.4 265.8v2.6zM199.4 260.8v5zM199.4 260.8h2.5zM201.9 260.8h5.1zM201.9 265.8h5.1zM199.4 265.8h2.5zM210.2 274.7v3.8z"/>
<path d="M214.1 263.3h3zM257.6 274.7v3.8zM305.1 274.7v3.8zM352.5 274.7v3.8zM400 264.5v.1zM400 268.4v6.2zM400 274.6h.1zM400 22.1v252.6z"/>
<circle cx="110.5" cy="55.1" r=".51"/>
<circle cx="227.3" cy="55.1" r=".51"/>
<circle cx="64.8" cy="70.3" r=".51"/>
<circle cx="80" cy="65.2" r=".51"/>
<circle cx="95.2" cy="60.2" r=".51"/>
<circle cx="232.4" cy="60.2" r=".51"/>
<circle cx="237.5" cy="65.2" r=".51"/>
<circle cx="242.5" cy="70.3" r=".51"/>
<circle cx="323.8" cy="118.6" r=".51"/>
<circle cx="262.9" cy="156.7" r=".51"/>
<circle cx="318.7" cy="161.7" r=".51"/>
<circle cx="64.8" cy="220.1" r=".51"/>
<circle cx="36.8" cy="253.1" r=".51"/>
<circle cx="44.4" cy="253.1" r=".51"/>
<circle cx="52.1" cy="253.1" r=".51"/>
<circle cx="59.7" cy="253.1" r=".51"/>
<circle cx="67.3" cy="253.1" r=".51"/>
<circle cx="74.9" cy="253.1" r=".51"/>
<circle cx="82.5" cy="253.1" r=".51"/>
<circle cx="118.1" cy="255.7" r=".51"/>
<circle cx="146" cy="255.7" r=".51"/>
<circle cx="171.4" cy="255.7" r=".51"/>
<circle cx="29.2" cy="265.8" r=".51"/>
<circle cx="36.8" cy="265.8" r=".51"/>
<circle cx="44.4" cy="265.8" r=".51"/>
<circle cx="52.1" cy="265.8" r=".51"/>
<circle cx="59.7" cy="265.8" r=".51"/>
<circle cx="67.3" cy="265.8" r=".51"/>
<circle cx="74.9" cy="265.8" r=".51"/>
<circle cx="118.1" cy="260.8" r=".51"/>
<circle cx="118.1" cy="265.8" r=".51"/>
<circle cx="146" cy="260.8" r=".51"/>
<circle cx="146" cy="265.8" r=".51"/>
<circle cx="171.4" cy="265.8" r=".51"/>
<circle cx="171.4" cy="260.8" r=".51"/>
<circle cx="199.4" cy="265.8" r=".51"/>
</g>
<g fill="#000" stroke="#000" stroke-width=".28">
<path d="M26.4 58.6v3.1zM27.9 53.6v3zM27.9 53.6h9.9zM27.9 56.6h9.9zM26.4 58.6h11.4zM37.8 53.6l1.6 1.5zM37.8 56.6l1.6-1.5zM379.7 55.1l1.5-1.5zM379.7 55.1l1.5 1.5zM381.2 53.6h11.4zM381.2 56.6h11.4zM381.2 58.6h12.9z"/>
<path d="M392.6 53.6v3zM394.1 58.6v3.1zM31.7 68.8v3zM32 63.7v3zM26.4 61.7h11.4zM32 63.7h5.8zM32 66.7h5.8zM31.7 68.8h6.1zM31.7 71.8h6.1zM37.8 58.6l1.6 1.6zM37.8 61.7l1.6-1.5zM37.8 63.7l1.6 1.5z"/>
<path d="M37.8 66.7l1.6-1.5zM37.8 68.8l1.6 1.5zM39.4 70.3l-1.6 1.5zM379.7 60.2l1.5-1.6zM379.7 60.2l1.5 1.5zM379.7 65.2l1.5-1.5zM379.7 65.2l1.5 1.5zM379.7 70.3l1.5-1.5zM379.7 70.3l1.5 1.5zM381.2 61.7h12.9zM381.2 63.7h7.3zM381.2 66.7h7.3z"/>
<path d="M381.2 68.8h7.5zM381.2 71.8h7.5zM388.5 63.7v3zM388.7 68.8v3zM323.8 95.7l-1.2 1.9zM323.8 95.7l1.3 1.9zM262.9 108.4l-1.3 1.9zM262.9 108.4l1.2 1.9zM322.9 103.3v5.1zM322.9 108.4h1.8zM322.9 103.3h1.8zM324.7 103.3v5.1z"/>
<path d="M262.9 151.6l-1.3 1.9zM262.9 151.6l1.2 1.9zM317.9 151.6v5.1zM317.9 156.7h1.7zM317.9 151.6h1.7zM318.7 144l-1.2 1.9zM319.6 151.6v5.1zM318.7 144l1.3 1.9zM227.3 189.7l-1.3 1.9zM227.3 189.7l1.3 1.9zM23.9 218.6h16.5zM63.9 210v5z"/>
<path d="M63.9 215h1.8zM63.9 210h1.8zM64.8 202.4l-1.3 1.9zM65.7 210v5zM64.8 202.4l1.2 1.9zM23.9 218.6v3.1zM27.6 228.8v3zM31.2 223.7v3zM27.6 228.8h12.8zM27.6 231.8h12.8zM23.9 221.7h16.5zM31.2 223.7h9.2z"/>
<path d="M31.2 226.7h9.2zM40.4 228.8l1.5 1.5zM41.9 230.3l-1.5 1.5zM40.4 221.7l1.5-1.6zM40.4 218.6l1.5 1.5zM40.4 223.7l1.5 1.5zM41.9 225.2l-1.5 1.5zM339.7 237.9h3.8zM379.7 230.3l1.5-1.5zM379.7 230.3l1.5 1.5zM381.2 228.8h10.1zM381.2 231.8h10.1z"/>
<path d="M391.3 228.8v3zM82.5 248.1l-1.2 1.9zM82.5 248.1l1.3 1.9zM92.7 248.1l-1.3 1.9zM92.7 248.1l1.3 1.9zM313.7 249.3h86.3zM313.7 254.4h86.3zM313.7 259.5h58.4zM372.1 259.5h27.9zM372.1 259.5v5.1zM27.3 270.9h3.8zM90.8 265.8h3.8z"/>
<path d="M116.2 270.9h3.8zM144.1 270.9h3.8zM169.5 270.9h3.8zM197.5 270.9h3.8zM313.7 264.6h58.4zM313.7 269.7h86.3zM372.1 264.6h27.9zM400 268.4v1.3z"/>
</g>
<g fill="none" stroke="#000" stroke-width=".61">
<path d="M62.2 88.1a5.1 5.1 0 0 0 5.1 5.1 5.1 5.1 0 0 0 5.1-5.1M77.5 88.1a5.1 5.1 0 0 0 5 5.1 5.1 5.1 0 0 0 5.1-5.1M92.7 88.1a5.1 5.1 0 0 0 5.1 5.1 5.1 5.1 0 0 0 5.1-5.1M107.9 88.1a5.1 5.1 0 0 0 5.1 5.1 5.1 5.1 0 0 0 5.1-5.1M163.8 88.1a5.1 5.1 0 0 0 5.1 5.1 5.1 5.1 0 0 0 5.1-5.1M69.8 110.9a5.1 5.1 0 0 0 5.1 5.1 5.1 5.1 0 0 0 5.1-5.1M100.3 110.9a5.1 5.1 0 0 0 5.1 5.1 5.1 5.1 0 0 0 5.1-5.1M174 110.9a5.1 5.1 0 0 0 5 5.1 5.1 5.1 0 0 0 5.1-5.1M85.1 131.3a5.1 5.1 0 0 0 5.1 5 5.1 5.1 0 0 0 5-5M105.4 156.7a5.1 5.1 0 0 0 5.1 5 5.1 5.1 0 0 0 5.1-5M316.2 169.4a5.1 5.1 0 0 0 5.1 5 5.1 5.1 0 0 0 5.1-5M234.9 192.2a5.1 5.1 0 0 1 5.1 5.1 5.1 5.1 0 0 1-5.1 5.1"/>
<path d="M316.2 212.5a5.1 5.1 0 0 1 5.1 5.1 5.1 5.1 0 0 1-5.1 5.1M125.7 248.1a5.1 5.1 0 0 1 5.1 5 5.1 5.1 0 0 1-5.1 5.1 5.1 5.1 0 0 1 5.1 5.1 5.1 5.1 0 0 1-5.1 5.1M153.6 248.1a5.1 5.1 0 0 1 5.1 5 5.1 5.1 0 0 1-5.1 5.1 5.1 5.1 0 0 1 5.1 5.1 5.1 5.1 0 0 1-5.1 5.1M179 248.1a5.1 5.1 0 0 1 5.1 5 5.1 5.1 0 0 1-5.1 5.1 5.1 5.1 0 0 1 5.1 5.1 5.1 5.1 0 0 1-5.1 5.1M207 258.2a5.1 5.1 0 0 1 5.1 5.1 5.1 5.1 0 0 1-5.1 5.1"/>
</g>
<g fill="#000" stroke="#000" stroke-width=".61">
<path d="M20.3 22.1v252.6zM20.3 22.1h379.7zM62.2 88.1h10.2zM77.5 88.1h10.1zM92.7 88.1h10.2zM107.9 88.1h10.2zM163.8 88.1h10.2zM69.8 110.9h10.2zM100.3 110.9h10.2zM174 110.9h10.1zM273 110.9v35.6zM273 110.9h15.3z"/>
<path d="M85.1 131.3h10.1zM105.4 156.7h10.2zM273 146.5h15.3zM273 154.1v35.6zM288.3 110.9v35.6zM273 154.1h15.3zM316.2 169.4h10.2zM234.9 192.2v10.2zM273 189.7h15.3zM288.3 154.1v35.6zM316.2 212.5v10.2zM349.2 217.6v15.2z"/>
<path d="M349.2 217.6h15.2zM349.2 232.8h15.2zM364.4 217.6v15.2zM125.7 258.2v10.2zM125.7 248.1v10.1zM153.6 248.1v10.1zM153.6 258.2v10.2zM179 248.1v10.1zM179 258.2v10.2zM207 258.2v10.2zM283.2 244.3v30.4zM313.7 254.4v5.1z"/>
<path d="M313.7 249.3v5.1zM313.7 244.3v5zM313.7 244.3h86.3zM283.2 244.3h30.5zM400 254.4v5.1zM400 249.3v5.1zM400 244.3v5zM400 22.1v222.2zM20.3 274.7h262.9zM283.2 274.7h30.5zM313.7 274.7h86.3zM313.7 269.7v5z"/>
<path d="M313.7 264.6v5.1zM313.7 259.5v5.1zM400 268.4v6.3zM400 264.6v3.8zM400 259.5v5.1z"/>
</g>
<g fill="none" stroke="#000" stroke-width=".25">
<circle cx="289.2" cy="113.5" r="1"/>
<circle cx="272" cy="144" r="1"/>
<circle cx="289.2" cy="156.7" r="1"/>
<circle cx="321.3" cy="175.4" r="1"/>
<circle cx="241" cy="197.3" r="1"/>
<circle cx="272" cy="187.1" r="1"/>
<circle cx="322.3" cy="217.6" r="1"/>
<circle cx="348.2" cy="230.3" r="1"/>
<circle cx="348.2" cy="220.1" r="1"/>
<circle cx="213.1" cy="263.3" r="1"/>
</g>
<g fill="#000" stroke="#000" stroke-width=".25">
<path d="M367 83h25.4v10.2h-25.4zM27.2 258.7h4v.5h-4zM27.2 259.8h4v.5h-4zM34.8 258.7h4.1v.5h-4.1zM34.8 259.8h4.1v.5h-4.1zM42.4 258.7h4.1v.5h-4.1zM42.4 259.8h4.1v.5h-4.1zM50 258.7h4.1v.5h-4.1zM50 259.8h4.1v.5h-4.1zM57.7 258.7h4v.5h-4zM57.7 259.8h4v.5h-4zM65.3 258.7h4v.5h-4z"/>
<path d="M65.3 259.8h4v.5h-4zM72.9 258.7h4.1v.5h-4.1zM72.9 259.8h4.1v.5h-4.1zM80.5 258.7h4.1v.5h-4.1zM80.5 259.8h4.1v.5h-4.1zM90.7 257.2h4v.5h-4zM90.7 256.2h4v.5h-4z"/>
</g>
<path d="M16.5 18.2v260.3zM16.5 18.2h387.3zM16.5 278.5h387.3zM403.8 18.2v260.3z" fill="#000" stroke="#000" stroke-width=".32"/>
<path d="M39.4 34.8h170.1zM209.5 34.8l5.1 5zM214.6 39.8v88.9zM39.4 44.9h157.4zM196.8 44.9l5.1 5.1zM201.9 50v147.3z" fill="#000" stroke="#000" stroke-width=".76"/>
<path d="M336.5 83v10.2zM336.5 93.2v7.6zM336.5 93.2h55.9zM392.4 83v10.2zM336.5 83h55.9zM336.5 100.8h55.9zM392.4 93.2v7.6z" fill="#000" stroke="#000" stroke-width=".42"/>
<use href="#words"/>
</svg>
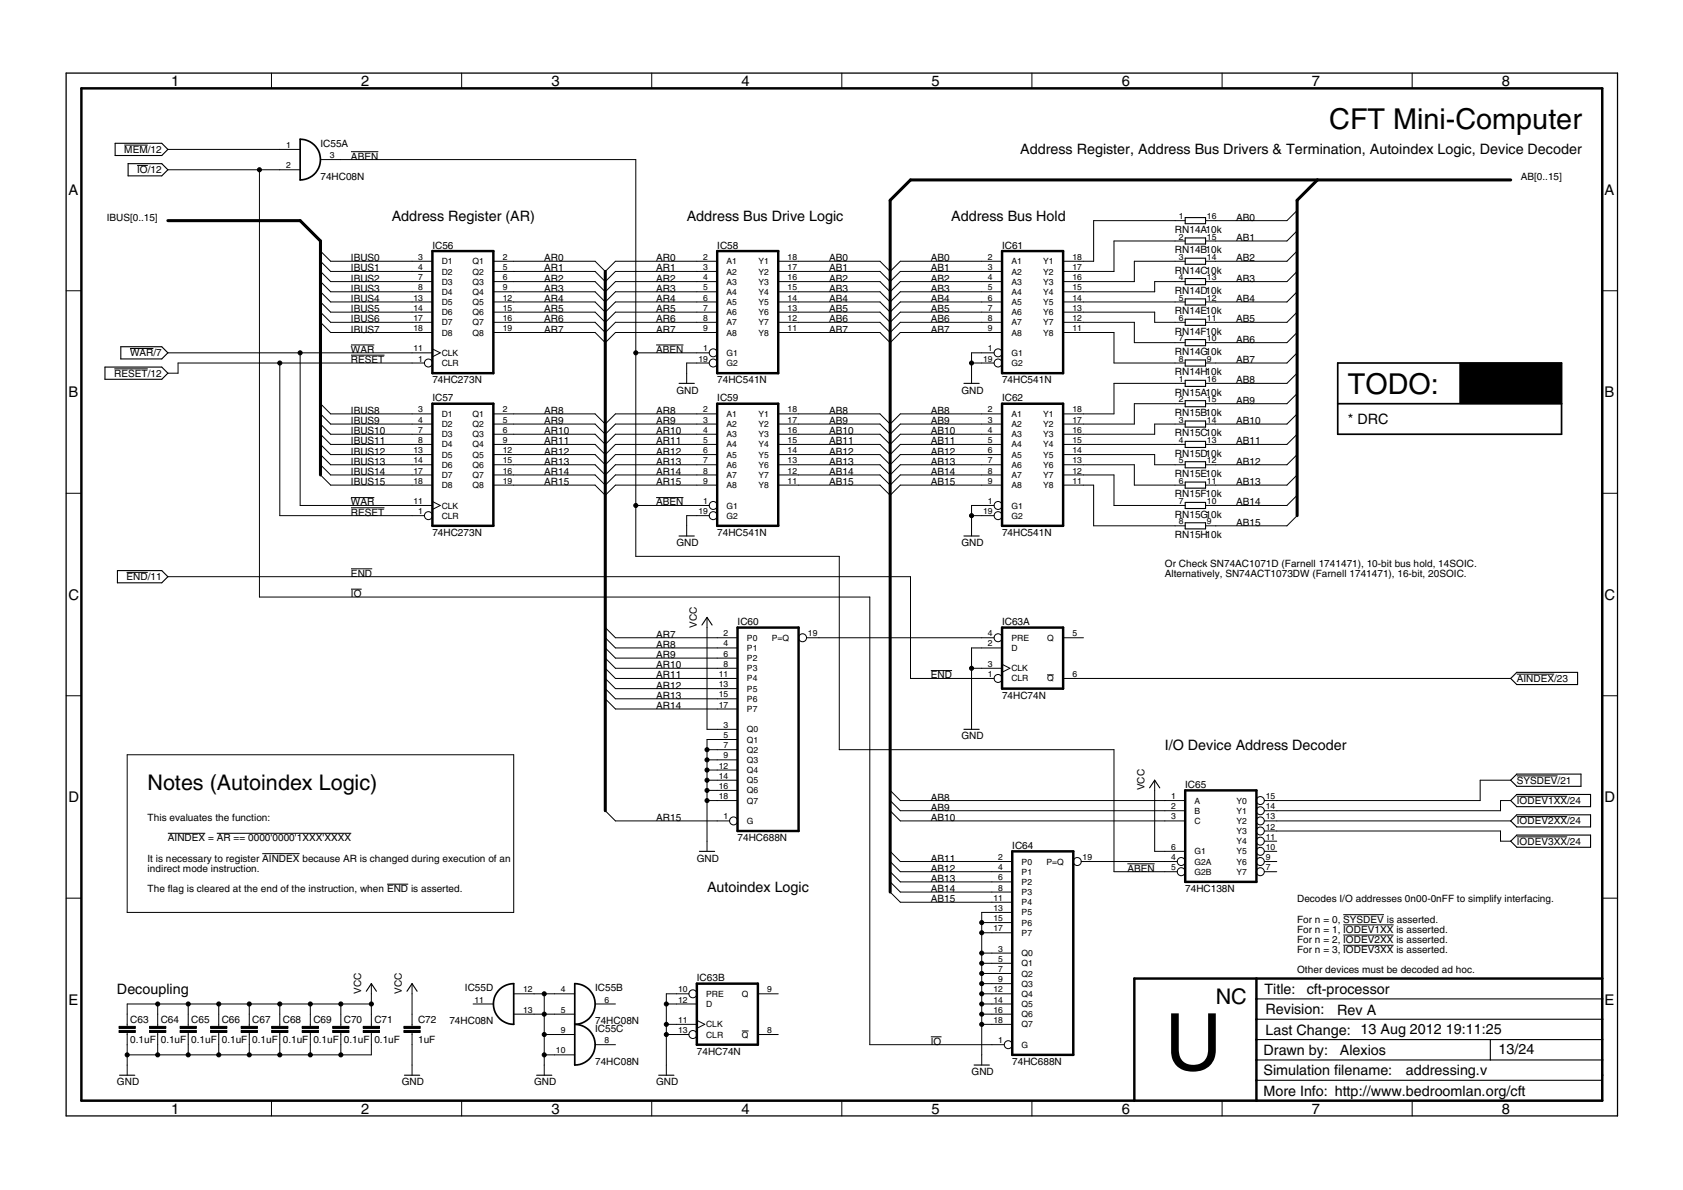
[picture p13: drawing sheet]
<svg xmlns="http://www.w3.org/2000/svg" width="420mm" height="297mm" viewBox="0 0 420 297" stroke-linecap="round" stroke-linejoin="round" font-family="sans-serif">
<defs><g id="words">
<text font-size="19.7" x="290.8" y="267.1">U</text>
<g font-size="7.2">
<text x="331.8" y="32.2">CFT Mini-Computer</text>
<text x="336.5" y="98.2">TODO:</text>
</g>
<g font-size="5.4">
<text x="36.8" y="197.3">Notes (Autoindex Logic)</text>
<text x="303.5" y="250.6">NC</text>
</g>
<g font-size="3.7">
<text x="42.7" y="21.5">1</text>
<text x="90.2" y="21.5">2</text>
<text x="137.7" y="21.5">3</text>
<text x="185.1" y="21.5">4</text>
<text x="232.6" y="21.5">5</text>
<text x="280" y="21.5">6</text>
<text x="327.5" y="21.5">7</text>
<text x="375" y="21.5">8</text>
<text x="17.1" y="48.6">A</text>
<text x="400.6" y="48.6">A</text>
<text x="17.1" y="99.2">B</text>
<text x="400.6" y="99.2">B</text>
<text x="17.1" y="149.7">C</text>
<text x="400.6" y="149.7">C</text>
<text x="17.1" y="200.2">D</text>
<text x="400.6" y="200.2">D</text>
<text x="17.1" y="250.8">E</text>
<text x="400.6" y="250.8">E</text>
<text x="42.7" y="277.9">1</text>
<text x="90.2" y="277.9">2</text>
<text x="137.7" y="277.9">3</text>
<text x="185.1" y="277.9">4</text>
<text x="232.6" y="277.9">5</text>
<text x="280" y="277.9">6</text>
<text x="327.5" y="277.9">7</text>
<text x="375" y="277.9">8</text>
</g>
<g font-size="3.6">
<text x="254.7" y="38.6">Address Register, Address Bus Drivers &amp; Termination, Autoindex Logic, Device Decoder</text>
<text x="97.8" y="55.1">Address Register (AR)</text>
<text x="171.4" y="55.1">Address Bus Drive Logic</text>
<text x="237.5" y="55.1">Address Bus Hold</text>
<text x="336.5" y="105.9">* DRC</text>
<text x="290.8" y="187.1">I/O Device Address Decoder</text>
<text x="176.5" y="222.7">Autoindex Logic</text>
<text x="29.2" y="248.1">Decoupling</text>
<text x="315.7" y="248.1">Title:</text>
<text x="326.2" y="248.2">cft-processor</text>
<text x="315.9" y="253.2">Revision:</text>
<text x="333.8" y="253.3">Rev A</text>
<text x="315.4" y="263.3">Drawn by:</text>
<text x="315.9" y="258.2">Last Change: 13 Aug 2012</text>
<text x="334.5" y="263.3">Alexios</text>
<text x="361" y="258.1">19:11:25</text>
<text x="374.1" y="263.2">13/24</text>
<text x="315.4" y="268.4">Simulation filename:</text>
<text x="351" y="268.4">addressing.v</text>
<text x="315.4" y="273.5">More Info: http://www.bedroomlan.org/cft</text>
</g>
<g font-size="2.5">
<text x="31" y="38.2">MEM/12</text>
<text x="80" y="36.7">IC55A</text>
<text x="87.6" y="39.8">ABEN</text>
<text x="34.2" y="43.3">IO/12</text>
<text x="80" y="44.9">74HC08N</text>
<text x="379.7" y="44.9">AB[0..15]</text>
<text x="26.6" y="55.1">IBUS[0..15]</text>
<text x="293.3" y="58.1">RN14A10k</text>
<text x="308.6" y="55.1">AB0</text>
<text x="87.6" y="65.2">IBUS0</text>
<text x="107.9" y="62">IC56</text>
<text x="135.9" y="65.2">AR0</text>
<text x="163.8" y="65.2">AR0</text>
<text x="179.1" y="62">IC58</text>
<text x="207" y="65.2">AB0</text>
<text x="232.4" y="65.2">AB0</text>
<text x="250.2" y="62">IC61</text>
<text x="293.3" y="63.2">RN14B10k</text>
<text x="308.6" y="60.1">AB1</text>
<text x="308.6" y="65.2">AB2</text>
<text x="87.6" y="67.8">IBUS1</text>
<text x="87.6" y="70.3">IBUS2</text>
<text x="135.9" y="70.3">AR2</text>
<text x="135.9" y="67.8">AR1</text>
<text x="163.8" y="70.3">AR2</text>
<text x="163.8" y="67.8">AR1</text>
<text x="207" y="67.8">AB1</text>
<text x="207" y="70.3">AB2</text>
<text x="232.4" y="67.8">AB1</text>
<text x="232.4" y="70.3">AB2</text>
<text x="293.3" y="68.3">RN14C10k</text>
<text x="308.6" y="70.3">AB3</text>
<text x="87.6" y="72.8">IBUS3</text>
<text x="87.6" y="75.4">IBUS4</text>
<text x="87.6" y="77.9">IBUS5</text>
<text x="135.9" y="75.4">AR4</text>
<text x="135.9" y="72.8">AR3</text>
<text x="135.9" y="77.9">AR5</text>
<text x="163.8" y="75.4">AR4</text>
<text x="163.8" y="72.8">AR3</text>
<text x="163.8" y="77.9">AR5</text>
<text x="207" y="72.8">AB3</text>
<text x="207" y="75.4">AB4</text>
<text x="207" y="77.9">AB5</text>
<text x="232.4" y="72.8">AB3</text>
<text x="232.4" y="75.4">AB4</text>
<text x="232.4" y="77.9">AB5</text>
<text x="293.3" y="73.3">RN14D10k</text>
<text x="308.6" y="75.4">AB4</text>
<text x="87.6" y="80.5">IBUS6</text>
<text x="87.6" y="83">IBUS7</text>
<text x="135.9" y="83">AR7</text>
<text x="135.9" y="80.5">AR6</text>
<text x="163.8" y="83">AR7</text>
<text x="163.8" y="80.5">AR6</text>
<text x="207" y="80.5">AB6</text>
<text x="207" y="83">AB7</text>
<text x="232.4" y="80.5">AB6</text>
<text x="232.4" y="83">AB7</text>
<text x="293.3" y="78.4">RN14E10k</text>
<text x="293.3" y="83.5">RN14F10k</text>
<text x="308.6" y="80.5">AB5</text>
<text x="32.5" y="89">WAR/7</text>
<text x="87.6" y="88.1">WAR</text>
<text x="163.8" y="88.1">ABEN</text>
<text x="293.3" y="88.6">RN14G10k</text>
<text x="308.6" y="85.5">AB6</text>
<text x="28.5" y="94">RESET/12</text>
<text x="87.6" y="90.6">RESET</text>
<text x="107.9" y="95.7">74HC273N</text>
<text x="179.1" y="95.7">74HC541N</text>
<text x="250.2" y="95.7">74HC541N</text>
<text x="293.3" y="93.7">RN14H10k</text>
<text x="308.6" y="90.6">AB7</text>
<text x="308.6" y="95.7">AB8</text>
<text x="107.9" y="100.1">IC57</text>
<text x="168.9" y="98.2">GND</text>
<text x="179.1" y="100.1">IC59</text>
<text x="240" y="98.2">GND</text>
<text x="250.2" y="100.1">IC62</text>
<text x="293.3" y="98.7">RN15A10k</text>
<text x="308.6" y="100.8">AB9</text>
<text x="87.6" y="103.3">IBUS8</text>
<text x="87.6" y="105.9">IBUS9</text>
<text x="135.9" y="103.3">AR8</text>
<text x="135.9" y="105.9">AR9</text>
<text x="163.8" y="103.3">AR8</text>
<text x="163.8" y="105.9">AR9</text>
<text x="207" y="103.3">AB8</text>
<text x="207" y="105.9">AB9</text>
<text x="232.4" y="103.3">AB8</text>
<text x="232.4" y="105.9">AB9</text>
<text x="293.3" y="103.8">RN15B10k</text>
<text x="308.6" y="105.9">AB10</text>
<text x="87.6" y="108.4">IBUS10</text>
<text x="87.6" y="110.9">IBUS11</text>
<text x="87.6" y="113.5">IBUS12</text>
<text x="135.9" y="108.4">AR10</text>
<text x="135.9" y="110.9">AR11</text>
<text x="135.9" y="113.5">AR12</text>
<text x="163.8" y="108.4">AR10</text>
<text x="163.8" y="110.9">AR11</text>
<text x="163.8" y="113.5">AR12</text>
<text x="207" y="108.4">AB10</text>
<text x="207" y="110.9">AB11</text>
<text x="207" y="113.5">AB12</text>
<text x="232.4" y="108.4">AB10</text>
<text x="232.4" y="110.9">AB11</text>
<text x="232.4" y="113.5">AB12</text>
<text x="293.3" y="108.9">RN15C10k</text>
<text x="293.3" y="114">RN15D10k</text>
<text x="308.6" y="110.9">AB11</text>
<text x="87.6" y="116">IBUS13</text>
<text x="87.6" y="118.6">IBUS14</text>
<text x="135.9" y="116">AR13</text>
<text x="135.9" y="118.6">AR14</text>
<text x="163.8" y="116">AR13</text>
<text x="163.8" y="118.6">AR14</text>
<text x="207" y="116">AB13</text>
<text x="207" y="118.6">AB14</text>
<text x="232.4" y="116">AB13</text>
<text x="232.4" y="118.6">AB14</text>
<text x="293.3" y="119.1">RN15E10k</text>
<text x="308.6" y="116">AB12</text>
<text x="87.6" y="121.1">IBUS15</text>
<text x="135.9" y="121.1">AR15</text>
<text x="163.8" y="121.1">AR15</text>
<text x="207" y="121.1">AB15</text>
<text x="232.4" y="121.1">AB15</text>
<text x="293.3" y="124.1">RN15F10k</text>
<text x="308.6" y="121.1">AB13</text>
<text x="87.6" y="128.7">RESET</text>
<text x="87.6" y="126.2">WAR</text>
<text x="163.8" y="126.2">ABEN</text>
<text x="293.3" y="129.2">RN15G10k</text>
<text x="308.6" y="126.2">AB14</text>
<text x="308.6" y="131.3">AB15</text>
<text x="107.9" y="133.8">74HC273N</text>
<text x="168.9" y="136.3">GND</text>
<text x="179.1" y="133.8">74HC541N</text>
<text x="240" y="136.3">GND</text>
<text x="250.2" y="133.8">74HC541N</text>
<text x="293.3" y="134.3">RN15H10k</text>
<text x="87.6" y="144">END</text>
<text x="290.8" y="141.4">Or Check SN74AC1071D (Farnell 1741471), 10-bit bus hold, 14SOIC.</text>
<text x="290.8" y="144">Alternatively, SN74ACT1073DW (Farnell 1741471), 16-bit, 20SOIC.</text>
<text x="31.6" y="144.8">END/11</text>
<text x="87.6" y="149">IO</text>
<text x="163.8" y="161.7">AR8</text>
<text x="163.8" y="159.2">AR7</text>
<text x="174" y="156.6" transform="rotate(-90 174 156.6)">VCC</text>
<text x="184.1" y="156">IC60</text>
<text x="250.2" y="156">IC63A</text>
<text x="163.8" y="164.3">AR9</text>
<text x="163.8" y="166.8">AR10</text>
<text x="163.8" y="169.3">AR11</text>
<text x="163.8" y="171.9">AR12</text>
<text x="232.4" y="169.3">END</text>
<text x="378.7" y="170.2">AINDEX/23</text>
<text x="163.8" y="174.4">AR13</text>
<text x="163.8" y="177">AR14</text>
<text x="250.2" y="174.4">74HC74N</text>
<text x="240" y="184.6">GND</text>
<text x="285.7" y="197.3" transform="rotate(-90 285.7 197.3)">VCC</text>
<text x="295.9" y="196.6">IC65</text>
<text x="378.7" y="195.6">SYSDEV/21</text>
<text x="232.4" y="199.8">AB8</text>
<text x="232.4" y="202.4">AB9</text>
<text x="378.7" y="200.7">IODEV1XX/24</text>
<text x="36.8" y="204.9">This evaluates the function:</text>
<text x="41.9" y="210">AINDEX = AR == 0000'0000'1XXX'XXXX</text>
<text x="163.8" y="204.9">AR15</text>
<text x="184.1" y="210">74HC688N</text>
<text x="232.4" y="204.9">AB10</text>
<text x="378.7" y="205.8">IODEV2XX/24</text>
<text x="36.8" y="215.1">It is necessary to register AINDEX because AR is changed during execution of an</text>
<text x="174" y="215.1">GND</text>
<text x="232.4" y="215.1">AB11</text>
<text x="252.7" y="211.9">IC64</text>
<text x="378.7" y="210.9">IODEV3XX/24</text>
<text x="36.8" y="217.6">indirect mode instruction.</text>
<text x="232.4" y="217.6">AB12</text>
<text x="232.4" y="220.1">AB13</text>
<text x="281.4" y="217.6">ABEN</text>
<text x="36.8" y="222.7">The flag is cleared at the end of the instruction, when END is asserted.</text>
<text x="232.4" y="222.7">AB14</text>
<text x="232.4" y="225.2">AB15</text>
<text x="295.9" y="222.7">74HC138N</text>
<text x="323.8" y="225.2">Decodes I/O addresses 0n00-0nFF to simplify interfacing.</text>
<text x="323.8" y="230.3">For n = 0, SYSDEV is asserted.</text>
<text x="323.8" y="232.8">For n = 1, IODEV1XX is asserted.</text>
<text x="323.8" y="235.4">For n = 2, IODEV2XX is asserted.</text>
<text x="323.8" y="237.9">For n = 3, IODEV3XX is asserted.</text>
<text x="174" y="244.9">IC63B</text>
<text x="323.8" y="243">Other devices must be decoded ad hoc.</text>
<text x="90.2" y="248.1" transform="rotate(-90 90.2 248.1)">VCC</text>
<text x="100.3" y="248.1" transform="rotate(-90 100.3 248.1)">VCC</text>
<text x="116.1" y="247.4">IC55D</text>
<text x="148.6" y="247.4">IC55B</text>
<text x="32.5" y="255.3">C63</text>
<text x="40.1" y="255.3">C64</text>
<text x="47.7" y="255.3">C65</text>
<text x="55.4" y="255.3">C66</text>
<text x="63" y="255.3">C67</text>
<text x="70.6" y="255.3">C68</text>
<text x="78.2" y="255.3">C69</text>
<text x="85.8" y="255.3">C70</text>
<text x="93.5" y="255.3">C71</text>
<text x="104.4" y="255.3">C72</text>
<text x="112.2" y="255.7">74HC08N</text>
<text x="148.6" y="255.7">74HC08N</text>
<text x="148.6" y="257.6">IC55C</text>
<text x="32.5" y="260.4">0.1uF</text>
<text x="40.1" y="260.4">0.1uF</text>
<text x="47.7" y="260.4">0.1uF</text>
<text x="55.4" y="260.4">0.1uF</text>
<text x="63" y="260.4">0.1uF</text>
<text x="70.6" y="260.4">0.1uF</text>
<text x="78.2" y="260.4">0.1uF</text>
<text x="85.8" y="260.4">0.1uF</text>
<text x="93.5" y="260.4">0.1uF</text>
<text x="104.4" y="260.4">1uF</text>
<text x="174" y="263.3">74HC74N</text>
<text x="232.4" y="260.8">IO</text>
<text x="148.6" y="265.8">74HC08N</text>
<text x="242.5" y="268.4">GND</text>
<text x="252.7" y="265.8">74HC688N</text>
<text x="29.2" y="270.9">GND</text>
<text x="100.3" y="270.9">GND</text>
<text x="133.3" y="270.9">GND</text>
<text x="163.8" y="270.9">GND</text>
</g>
<g font-size="2.1">
<text x="71.4" y="36.9">1</text>
<text x="82.3" y="39.5">3</text>
<text x="71.4" y="42">2</text>
<text x="294.3" y="54.7">1</text>
<text x="294.3" y="59.8">2</text>
<text x="301.3" y="54.7">16</text>
<text x="301.3" y="59.8">15</text>
<text x="104.4" y="64.9">3</text>
<text x="110.3" y="66">D1</text>
<text x="118" y="66">Q1</text>
<text x="125.5" y="64.9">2</text>
<text x="175.5" y="64.9">2</text>
<text x="181.4" y="66">A1</text>
<text x="189.3" y="66">Y1</text>
<text x="196.6" y="64.9">18</text>
<text x="246.6" y="64.9">2</text>
<text x="252.5" y="66">A1</text>
<text x="260.4" y="66">Y1</text>
<text x="267.7" y="64.9">18</text>
<text x="294.3" y="64.9">3</text>
<text x="301.3" y="64.9">14</text>
<text x="104.4" y="67.4">4</text>
<text x="104.4" y="69.9">7</text>
<text x="110.3" y="68.5">D2</text>
<text x="110.3" y="71.1">D3</text>
<text x="118" y="68.5">Q2</text>
<text x="118" y="71.1">Q3</text>
<text x="125.5" y="67.4">5</text>
<text x="125.5" y="69.9">6</text>
<text x="175.5" y="67.4">3</text>
<text x="175.5" y="69.9">4</text>
<text x="181.4" y="68.5">A2</text>
<text x="181.4" y="71.1">A3</text>
<text x="189.3" y="71.1">Y3</text>
<text x="189.3" y="68.5">Y2</text>
<text x="196.6" y="69.9">16</text>
<text x="196.6" y="67.4">17</text>
<text x="246.6" y="67.4">3</text>
<text x="246.6" y="69.9">4</text>
<text x="252.5" y="68.5">A2</text>
<text x="252.5" y="71.1">A3</text>
<text x="260.4" y="71.1">Y3</text>
<text x="260.4" y="68.5">Y2</text>
<text x="267.7" y="69.9">16</text>
<text x="267.7" y="67.4">17</text>
<text x="294.3" y="69.9">4</text>
<text x="301.3" y="69.9">13</text>
<text x="103.2" y="75">13</text>
<text x="103.2" y="77.6">14</text>
<text x="104.4" y="72.5">8</text>
<text x="110.3" y="73.6">D4</text>
<text x="110.3" y="76.1">D5</text>
<text x="118" y="73.6">Q4</text>
<text x="118" y="76.1">Q5</text>
<text x="125.5" y="72.5">9</text>
<text x="125.5" y="75">12</text>
<text x="125.5" y="77.6">15</text>
<text x="175.5" y="72.5">5</text>
<text x="175.5" y="75">6</text>
<text x="175.5" y="77.6">7</text>
<text x="181.4" y="73.6">A4</text>
<text x="181.4" y="76.1">A5</text>
<text x="189.3" y="76.1">Y5</text>
<text x="189.3" y="73.6">Y4</text>
<text x="196.6" y="77.6">13</text>
<text x="196.6" y="75">14</text>
<text x="196.6" y="72.5">15</text>
<text x="246.6" y="72.5">5</text>
<text x="246.6" y="75">6</text>
<text x="246.6" y="77.6">7</text>
<text x="252.5" y="73.6">A4</text>
<text x="252.5" y="76.1">A5</text>
<text x="260.4" y="76.1">Y5</text>
<text x="260.4" y="73.6">Y4</text>
<text x="267.7" y="77.6">13</text>
<text x="267.7" y="75">14</text>
<text x="267.7" y="72.5">15</text>
<text x="294.3" y="75">5</text>
<text x="301.3" y="75">12</text>
<text x="103.2" y="80.1">17</text>
<text x="103.2" y="82.6">18</text>
<text x="110.3" y="78.7">D6</text>
<text x="110.3" y="81.2">D7</text>
<text x="110.3" y="83.8">D8</text>
<text x="118" y="78.7">Q6</text>
<text x="118" y="81.2">Q7</text>
<text x="118" y="83.8">Q8</text>
<text x="125.5" y="80.1">16</text>
<text x="125.5" y="82.6">19</text>
<text x="175.5" y="80.1">8</text>
<text x="175.5" y="82.6">9</text>
<text x="181.4" y="78.7">A6</text>
<text x="181.4" y="81.2">A7</text>
<text x="181.4" y="83.8">A8</text>
<text x="189.3" y="83.8">Y8</text>
<text x="189.3" y="81.2">Y7</text>
<text x="189.3" y="78.7">Y6</text>
<text x="196.6" y="82.6">11</text>
<text x="196.6" y="80.1">12</text>
<text x="246.6" y="80.1">8</text>
<text x="246.6" y="82.6">9</text>
<text x="252.5" y="78.7">A6</text>
<text x="252.5" y="81.2">A7</text>
<text x="252.5" y="83.8">A8</text>
<text x="260.4" y="83.8">Y8</text>
<text x="260.4" y="81.2">Y7</text>
<text x="260.4" y="78.7">Y6</text>
<text x="267.7" y="82.6">11</text>
<text x="267.7" y="80.1">12</text>
<text x="294.3" y="80.1">6</text>
<text x="301.3" y="80.1">11</text>
<text x="103.2" y="87.7">11</text>
<text x="110.3" y="88.8">CLK</text>
<text x="175.5" y="87.7">1</text>
<text x="181.4" y="88.8">G1</text>
<text x="246.6" y="87.7">1</text>
<text x="252.5" y="88.8">G1</text>
<text x="294.3" y="85.2">7</text>
<text x="301.3" y="85.2">10</text>
<text x="104.4" y="90.3">1</text>
<text x="110.3" y="91.4">CLR</text>
<text x="174.3" y="90.3">19</text>
<text x="181.4" y="91.4">G2</text>
<text x="245.5" y="90.3">19</text>
<text x="252.5" y="91.4">G2</text>
<text x="294.3" y="90.3">8</text>
<text x="294.3" y="95.3">1</text>
<text x="301.3" y="90.3">9</text>
<text x="301.3" y="95.3">16</text>
<text x="294.3" y="100.4">2</text>
<text x="301.3" y="100.4">15</text>
<text x="104.4" y="103">3</text>
<text x="104.4" y="105.5">4</text>
<text x="110.3" y="104.1">D1</text>
<text x="110.3" y="106.6">D2</text>
<text x="118" y="104.1">Q1</text>
<text x="118" y="106.6">Q2</text>
<text x="125.5" y="103">2</text>
<text x="125.5" y="105.5">5</text>
<text x="175.5" y="103">2</text>
<text x="175.5" y="105.5">3</text>
<text x="181.4" y="104.1">A1</text>
<text x="181.4" y="106.6">A2</text>
<text x="189.3" y="106.6">Y2</text>
<text x="189.3" y="104.1">Y1</text>
<text x="196.6" y="105.5">17</text>
<text x="196.6" y="103">18</text>
<text x="246.6" y="103">2</text>
<text x="246.6" y="105.5">3</text>
<text x="252.5" y="104.1">A1</text>
<text x="252.5" y="106.6">A2</text>
<text x="260.4" y="106.6">Y2</text>
<text x="260.4" y="104.1">Y1</text>
<text x="267.7" y="105.5">17</text>
<text x="267.7" y="103">18</text>
<text x="294.3" y="105.5">3</text>
<text x="301.3" y="105.5">14</text>
<text x="103.2" y="113.1">13</text>
<text x="104.4" y="108">7</text>
<text x="104.4" y="110.6">8</text>
<text x="110.3" y="109.2">D3</text>
<text x="110.3" y="111.7">D4</text>
<text x="118" y="109.2">Q3</text>
<text x="118" y="111.7">Q4</text>
<text x="125.5" y="108">6</text>
<text x="125.5" y="110.6">9</text>
<text x="125.5" y="113.1">12</text>
<text x="175.5" y="108">4</text>
<text x="175.5" y="110.6">5</text>
<text x="175.5" y="113.1">6</text>
<text x="181.4" y="109.2">A3</text>
<text x="181.4" y="111.7">A4</text>
<text x="189.3" y="111.7">Y4</text>
<text x="189.3" y="109.2">Y3</text>
<text x="196.6" y="113.1">14</text>
<text x="196.6" y="110.6">15</text>
<text x="196.6" y="108">16</text>
<text x="246.6" y="108">4</text>
<text x="246.6" y="110.6">5</text>
<text x="246.6" y="113.1">6</text>
<text x="252.5" y="109.2">A3</text>
<text x="252.5" y="111.7">A4</text>
<text x="260.4" y="111.7">Y4</text>
<text x="260.4" y="109.2">Y3</text>
<text x="267.7" y="113.1">14</text>
<text x="267.7" y="110.6">15</text>
<text x="267.7" y="108">16</text>
<text x="294.3" y="110.6">4</text>
<text x="301.3" y="110.6">13</text>
<text x="103.2" y="115.7">14</text>
<text x="103.2" y="118.2">17</text>
<text x="110.3" y="114.2">D5</text>
<text x="110.3" y="116.8">D6</text>
<text x="110.3" y="119.3">D7</text>
<text x="118" y="114.2">Q5</text>
<text x="118" y="116.8">Q6</text>
<text x="118" y="119.3">Q7</text>
<text x="125.5" y="115.7">15</text>
<text x="125.5" y="118.2">16</text>
<text x="175.5" y="115.7">7</text>
<text x="175.5" y="118.2">8</text>
<text x="181.4" y="114.2">A5</text>
<text x="181.4" y="116.8">A6</text>
<text x="181.4" y="119.3">A7</text>
<text x="189.3" y="119.3">Y7</text>
<text x="189.3" y="116.8">Y6</text>
<text x="189.3" y="114.2">Y5</text>
<text x="196.6" y="118.2">12</text>
<text x="196.6" y="115.7">13</text>
<text x="246.6" y="115.7">7</text>
<text x="246.6" y="118.2">8</text>
<text x="252.5" y="114.2">A5</text>
<text x="252.5" y="116.8">A6</text>
<text x="252.5" y="119.3">A7</text>
<text x="260.4" y="119.3">Y7</text>
<text x="260.4" y="116.8">Y6</text>
<text x="260.4" y="114.2">Y5</text>
<text x="267.7" y="118.2">12</text>
<text x="267.7" y="115.7">13</text>
<text x="294.3" y="115.7">5</text>
<text x="301.3" y="115.7">12</text>
<text x="103.2" y="125.8">11</text>
<text x="103.2" y="120.7">18</text>
<text x="110.3" y="121.9">D8</text>
<text x="118" y="121.9">Q8</text>
<text x="125.5" y="120.7">19</text>
<text x="175.5" y="125.8">1</text>
<text x="175.5" y="120.7">9</text>
<text x="181.4" y="121.9">A8</text>
<text x="189.3" y="121.9">Y8</text>
<text x="196.6" y="120.7">11</text>
<text x="246.6" y="125.8">1</text>
<text x="246.6" y="120.7">9</text>
<text x="252.5" y="121.9">A8</text>
<text x="260.4" y="121.9">Y8</text>
<text x="267.7" y="120.7">11</text>
<text x="294.3" y="120.7">6</text>
<text x="294.3" y="125.8">7</text>
<text x="301.3" y="120.7">11</text>
<text x="301.3" y="125.8">10</text>
<text x="104.4" y="128.4">1</text>
<text x="110.3" y="129.5">CLR</text>
<text x="110.3" y="126.9">CLK</text>
<text x="174.3" y="128.4">19</text>
<text x="181.4" y="126.9">G1</text>
<text x="181.4" y="129.5">G2</text>
<text x="245.5" y="128.4">19</text>
<text x="252.5" y="126.9">G1</text>
<text x="252.5" y="129.5">G2</text>
<text x="294.3" y="130.9">8</text>
<text x="301.3" y="130.9">9</text>
<text x="180.6" y="158.8">2</text>
<text x="180.6" y="161.4">4</text>
<text x="186.5" y="159.9">P0</text>
<text x="192.7" y="160">P=Q</text>
<text x="201.7" y="158.8">19</text>
<text x="246.6" y="161.4">2</text>
<text x="246.6" y="158.8">4</text>
<text x="252.5" y="159.9">PRE</text>
<text x="261.4" y="160">Q</text>
<text x="267.7" y="158.8">5</text>
<text x="180.6" y="163.9">6</text>
<text x="180.6" y="166.5">8</text>
<text x="186.5" y="162.5">P1</text>
<text x="186.5" y="165">P2</text>
<text x="186.5" y="167.6">P3</text>
<text x="246.6" y="166.5">3</text>
<text x="252.5" y="162.5">D</text>
<text x="252.5" y="167.6">CLK</text>
<text x="179.4" y="169">11</text>
<text x="179.4" y="171.5">13</text>
<text x="186.5" y="170.1">P4</text>
<text x="186.5" y="172.6">P5</text>
<text x="246.6" y="169">1</text>
<text x="252.5" y="170.1">CLR</text>
<text x="261.4" y="170.1">Q</text>
<text x="267.7" y="169">6</text>
<text x="179.4" y="174.1">15</text>
<text x="179.4" y="176.6">17</text>
<text x="186.5" y="175.2">P6</text>
<text x="186.5" y="177.7">P7</text>
<text x="180.6" y="181.7">3</text>
<text x="180.6" y="184.2">5</text>
<text x="186.5" y="182.8">Q0</text>
<text x="186.5" y="185.3">Q1</text>
<text x="179.4" y="191.8">12</text>
<text x="180.6" y="186.8">7</text>
<text x="180.6" y="189.3">9</text>
<text x="186.5" y="187.9">Q2</text>
<text x="186.5" y="190.4">Q3</text>
<text x="179.4" y="194.4">14</text>
<text x="179.4" y="196.9">16</text>
<text x="186.5" y="193">Q4</text>
<text x="186.5" y="195.5">Q5</text>
<text x="179.4" y="199.5">18</text>
<text x="186.5" y="198">Q6</text>
<text x="186.5" y="200.6">Q7</text>
<text x="292.4" y="199.5">1</text>
<text x="292.4" y="202">2</text>
<text x="298.2" y="200.6">A</text>
<text x="298.2" y="203.1">B</text>
<text x="308.7" y="203.1">Y1</text>
<text x="308.7" y="200.6">Y0</text>
<text x="316" y="202">14</text>
<text x="316" y="199.5">15</text>
<text x="180.6" y="204.5">1</text>
<text x="186.5" y="205.7">G</text>
<text x="292.4" y="204.5">3</text>
<text x="298.2" y="205.7">C</text>
<text x="308.7" y="208.2">Y3</text>
<text x="308.7" y="205.7">Y2</text>
<text x="316" y="209.6">11</text>
<text x="316" y="207.1">12</text>
<text x="316" y="204.5">13</text>
<text x="249.2" y="214.7">2</text>
<text x="255" y="215.8">P0</text>
<text x="261.2" y="215.8">P=Q</text>
<text x="270.3" y="214.7">19</text>
<text x="292.4" y="214.7">4</text>
<text x="292.4" y="212.2">6</text>
<text x="298.2" y="215.8">G2A</text>
<text x="298.2" y="213.3">G1</text>
<text x="308.7" y="215.8">Y6</text>
<text x="308.7" y="213.3">Y5</text>
<text x="308.7" y="210.7">Y4</text>
<text x="316" y="214.7">9</text>
<text x="316" y="212.2">10</text>
<text x="249.2" y="217.2">4</text>
<text x="249.2" y="219.8">6</text>
<text x="255" y="218.4">P1</text>
<text x="255" y="220.9">P2</text>
<text x="292.4" y="217.2">5</text>
<text x="298.2" y="218.4">G2B</text>
<text x="308.7" y="218.4">Y7</text>
<text x="316" y="217.2">7</text>
<text x="248" y="224.9">11</text>
<text x="248" y="227.4">13</text>
<text x="249.2" y="222.3">8</text>
<text x="255" y="223.4">P3</text>
<text x="255" y="226">P4</text>
<text x="248" y="229.9">15</text>
<text x="248" y="232.5">17</text>
<text x="255" y="228.5">P5</text>
<text x="255" y="231.1">P6</text>
<text x="255" y="233.6">P7</text>
<text x="249.2" y="237.6">3</text>
<text x="255" y="238.7">Q0</text>
<text x="249.2" y="240.1">5</text>
<text x="249.2" y="242.6">7</text>
<text x="249.2" y="245.2">9</text>
<text x="255" y="241.2">Q1</text>
<text x="255" y="243.8">Q2</text>
<text x="118.5" y="250.3">11</text>
<text x="130.6" y="247.7">12</text>
<text x="140" y="247.7">4</text>
<text x="150.9" y="250.3">6</text>
<text x="169.3" y="250.3">12</text>
<text x="169.3" y="247.7">10</text>
<text x="176.3" y="251.4">D</text>
<text x="176.3" y="248.8">PRE</text>
<text x="185.2" y="248.8">Q</text>
<text x="191.5" y="247.7">9</text>
<text x="248" y="247.7">12</text>
<text x="248" y="250.3">14</text>
<text x="255" y="246.3">Q3</text>
<text x="255" y="248.8">Q4</text>
<text x="255" y="251.4">Q5</text>
<text x="130.6" y="252.8">13</text>
<text x="140" y="252.8">5</text>
<text x="140" y="257.9">9</text>
<text x="169.3" y="257.9">13</text>
<text x="169.3" y="255.3">11</text>
<text x="176.3" y="256.5">CLK</text>
<text x="191.5" y="257.9">8</text>
<text x="248" y="252.8">16</text>
<text x="248" y="255.3">18</text>
<text x="255" y="253.9">Q6</text>
<text x="255" y="256.5">Q7</text>
<text x="138.8" y="263">10</text>
<text x="150.9" y="260.4">8</text>
<text x="176.3" y="259">CLR</text>
<text x="185.2" y="259">Q</text>
<text x="249.2" y="260.4">1</text>
<text x="255" y="261.5">G</text>
</g>
</g></defs>
<g fill="#000" stroke="#000" stroke-width=".25">
<path d="M67.8 18.2v3.9zM115.3 18.2v3.9zM162.7 18.2v3.9zM210.2 18.2v3.9zM257.6 18.2v3.9zM305.1 18.2v3.9zM352.5 18.2v3.9zM20.3 22.1v252.6zM31 36.2h5.9zM69.8 37.3h5.1zM41.9 37.3h27.9zM80 39.8h5.1z"/>
<path d="M85.1 39.8h73.6zM87.6 37.9h6.8zM158.7 39.8v48.3zM20.3 22.1h379.7zM34.2 41.3h2.7zM41.9 42.4h22.9zM64.8 42.4v106.6zM69.8 42.4h5.1zM64.8 42.4h5zM273 55.1h20.3zM293.3 55.1h2.6zM301 55.1h2.5z"/>
<path d="M303.5 55.1h17.8zM323.8 52.5l-2.5 2.6zM16.5 72.6h3.8zM80 72.8l2.5 2.6zM80 75.4l2.5 2.5zM80 77.9l2.5 2.6zM82.5 65.2h20.4zM80 62.7l2.5 2.5zM82.5 67.8h20.4zM80 65.2l2.5 2.6zM82.5 70.3h20.4zM80 67.8l2.5 2.5z"/>
<path d="M82.5 72.8h20.4zM80 70.3l2.5 2.5zM82.5 75.4h20.4zM82.5 77.9h20.4zM102.9 65.2h5zM102.9 67.8h5zM102.9 70.3h5zM102.9 72.8h5zM102.9 75.4h5zM102.9 77.9h5zM123.2 65.2h5zM123.2 67.8h5z"/>
<path d="M123.2 70.3h5zM123.2 72.8h5zM123.2 75.4h5zM123.2 77.9h5zM128.2 65.2h20.4zM128.2 70.3h20.4zM128.2 75.4h20.4zM128.2 67.8h20.4zM128.2 72.8h20.4zM128.2 77.9h20.4zM148.6 65.2l2.5 2.6zM148.6 70.3l2.5 2.5z"/>
<path d="M148.6 75.4l2.5 2.5zM148.6 67.8l2.5 2.5zM148.6 72.8l2.5 2.6zM148.6 77.9l2.5 2.6zM151.1 67.8l2.5-2.6zM151.1 72.8l2.5-2.5zM153.6 75.4l-2.5 2.5zM153.6 67.8l-2.5 2.5zM151.1 75.4l2.5-2.6zM151.1 80.5l2.5-2.6zM174 65.2h5zM174 67.8h5z"/>
<path d="M174 70.3h5zM174 72.8h5zM174 75.4h5zM174 77.9h5zM153.6 65.2h20.4zM153.6 70.3h20.4zM153.6 75.4h20.4zM153.6 67.8h20.4zM153.6 72.8h20.4zM153.6 77.9h20.4zM194.3 77.9h5.1zM194.3 75.4h5.1z"/>
<path d="M194.3 72.8h5.1zM194.3 70.3h5.1zM194.3 67.8h5.1zM194.3 65.2h5.1zM199.4 65.2h20.3zM199.4 67.8h20.3zM199.4 70.3h20.3zM199.4 72.8h20.3zM199.4 75.4h20.3zM199.4 77.9h20.3zM219.7 65.2l2.5 2.6zM219.7 67.8l2.5 2.5z"/>
<path d="M219.7 70.3l2.5 2.5zM219.7 72.8l2.5 2.6zM219.7 75.4l2.5 2.5zM219.7 77.9l2.5 2.6zM222.2 67.8l2.6-2.6zM222.2 70.3l2.6-2.5zM224.8 70.3l-2.6 2.5zM222.2 75.4l2.6-2.6zM222.2 77.9l2.6-2.5zM224.8 77.9l-2.6 2.6zM245.1 65.2h5.1zM245.1 67.8h5.1z"/>
<path d="M245.1 70.3h5.1zM245.1 72.8h5.1zM245.1 75.4h5.1zM245.1 77.9h5.1zM224.8 65.2h20.3zM224.8 67.8h20.3zM224.8 70.3h20.3zM224.8 72.8h20.3zM224.8 75.4h20.3zM224.8 77.9h20.3zM265.4 77.9h5.1zM265.4 75.4h5.1z"/>
<path d="M265.4 72.8h5.1zM265.4 70.3h5.1zM265.4 67.8h5.1zM265.4 65.2h5.1zM270.5 72.8h17.8zM270.5 75.4h22.8zM270.5 77.9h17.8zM270.5 70.3h12.7zM270.5 67.8h7.6zM270.5 65.2h2.5zM273 55.1v10.1zM278.1 60.2v7.6z"/>
<path d="M278.1 60.2h15.2zM283.2 65.2v5.1zM283.2 65.2h10.1zM288.3 70.3v2.5zM288.3 70.3h5zM288.3 77.9v2.6zM293.3 60.2h2.6zM293.3 65.2h2.6zM293.3 70.3h2.6zM293.3 75.4h2.6zM301 60.2h2.5zM301 65.2h2.5z"/>
<path d="M301 70.3h2.5zM301 75.4h2.5zM303.5 60.2h17.8zM303.5 65.2h17.8zM303.5 70.3h17.8zM303.5 75.4h17.8zM321.3 60.2l2.5-2.6zM321.3 65.2l2.5-2.5zM323.8 67.8l-2.5 2.5zM323.8 72.8l-2.5 2.6zM400 72.6h3.8zM28.5 92.1h8.4z"/>
<path d="M32.5 87h5.8zM44.4 90.6v2.6zM41.9 93.2h2.5zM44.4 90.6h25.4zM41.9 88.1h33zM74.9 88.1v38.1zM80 80.5l2.5 2.5zM82.5 80.5h20.4zM82.5 83h20.4zM87.6 88.6h8.4zM87.6 86.1h5.8zM102.9 90.6h3.1z"/>
<path d="M102.9 88.1h5zM102.9 80.5h5zM102.9 83h5zM69.8 90.6h33.1zM74.9 88.1h28zM107.9 87.1l2 1zM107.9 89.1l2-1zM123.2 80.5h5zM123.2 83h5zM128.2 83h20.4zM128.2 80.5h20.4zM148.6 83l2.5 2.5z"/>
<path d="M148.6 80.5l2.5 2.5zM153.6 83l-2.5 2.5zM153.6 80.5l-2.5 2.5zM158.7 88.1h15.3zM158.7 88.1v38.1zM163.8 86.1h6.8zM171.4 93.2v2.5zM171.4 90.6v2.6zM174 88.1h3.1zM174 80.5h5zM174 83h5zM174 90.6h3.1z"/>
<path d="M171.4 90.6h2.6zM153.6 83h20.4zM153.6 80.5h20.4zM194.3 83h5.1zM194.3 80.5h5.1zM199.4 80.5h20.3zM199.4 83h20.3zM219.7 80.5l2.5 2.5zM219.7 83l2.5 2.5zM222.2 83l2.6-2.5zM222.2 85.5l2.6-2.5zM242.5 93.2v2.5z"/>
<path d="M242.5 88.1v2.5zM242.5 90.6v2.6zM245.1 88.1h3.1zM245.1 80.5h5.1zM245.1 83h5.1zM245.1 90.6h3.1zM242.5 88.1h2.6zM242.5 90.6h2.6zM224.8 80.5h20.3zM224.8 83h20.3zM265.4 83h5.1zM265.4 80.5h5.1z"/>
<path d="M270.5 80.5h12.7zM270.5 83h7.6zM278.1 83v7.6zM278.1 90.6h15.2zM278.1 95.7h15.2zM283.2 80.5v5zM283.2 85.5h10.1zM288.3 80.5h5zM293.3 80.5h2.6zM293.3 85.5h2.6zM293.3 90.6h2.6zM293.3 95.7h2.6z"/>
<path d="M301 80.5h2.5zM301 85.5h2.5zM301 90.6h2.5zM301 95.7h2.5zM303.5 80.5h17.8zM303.5 85.5h17.8zM303.5 90.6h17.8zM303.5 95.7h17.8zM321.3 80.5l2.5-2.6zM323.8 83l-2.5 2.5zM323.8 88.1l-2.5 2.5zM321.3 95.7l2.5-2.5z"/>
<path d="M80 100.8l2.5 2.5zM80 103.3l2.5 2.6zM80 105.9l2.5 2.5zM80 108.4l2.5 2.5zM80 110.9l2.5 2.6zM80 113.5l2.5 2.5zM80 116l2.5 2.6zM80 118.6l2.5 2.5zM82.5 103.3h20.4zM82.5 105.9h20.4zM82.5 108.4h20.4zM82.5 110.9h20.4z"/>
<path d="M82.5 113.5h20.4zM82.5 116h20.4zM82.5 118.6h20.4zM102.9 103.3h5zM102.9 105.9h5zM102.9 108.4h5zM102.9 110.9h5zM102.9 113.5h5zM102.9 116h5zM102.9 118.6h5zM123.2 103.3h5zM123.2 105.9h5z"/>
<path d="M123.2 108.4h5zM123.2 110.9h5zM123.2 113.5h5zM123.2 116h5zM123.2 118.6h5zM128.2 103.3h20.4zM128.2 105.9h20.4zM128.2 108.4h20.4zM128.2 110.9h20.4zM128.2 113.5h20.4zM128.2 116h20.4zM128.2 118.6h20.4z"/>
<path d="M148.6 103.3l2.5 2.6zM148.6 105.9l2.5 2.5zM148.6 108.4l2.5 2.5zM148.6 110.9l2.5 2.6zM148.6 113.5l2.5 2.5zM148.6 116l2.5 2.6zM148.6 118.6l2.5 2.5zM153.6 103.3l-2.5 2.6zM153.6 105.9l-2.5 2.5zM151.1 110.9l2.5-2.5zM153.6 110.9l-2.5 2.6zM153.6 113.5l-2.5 2.5z"/>
<path d="M151.1 118.6l2.5-2.6zM153.6 118.6l-2.5 2.5zM174 103.3h5zM174 105.9h5zM174 108.4h5zM174 110.9h5zM174 113.5h5zM174 116h5zM174 118.6h5zM153.6 103.3h20.4zM153.6 105.9h20.4zM153.6 108.4h20.4z"/>
<path d="M153.6 110.9h20.4zM153.6 113.5h20.4zM153.6 116h20.4zM153.6 118.6h20.4zM194.3 118.6h5.1zM194.3 116h5.1zM194.3 113.5h5.1zM194.3 110.9h5.1zM194.3 108.4h5.1zM194.3 105.9h5.1zM194.3 103.3h5.1zM199.4 103.3h20.3z"/>
<path d="M199.4 105.9h20.3zM199.4 108.4h20.3zM199.4 110.9h20.3zM199.4 113.5h20.3zM199.4 116h20.3zM199.4 118.6h20.3zM219.7 103.3l2.5 2.6zM219.7 105.9l2.5 2.5zM219.7 108.4l2.5 2.5zM219.7 110.9l2.5 2.6zM219.7 113.5l2.5 2.5zM219.7 116l2.5 2.6z"/>
<path d="M219.7 118.6l2.5 2.5zM222.2 105.9l2.6-2.6zM222.2 108.4l2.6-2.5zM224.8 108.4l-2.6 2.5zM222.2 113.5l2.6-2.6zM222.2 116l2.6-2.5zM224.8 116l-2.6 2.6zM222.2 121.1l2.6-2.5zM245.1 103.3h5.1zM245.1 105.9h5.1zM245.1 108.4h5.1zM245.1 110.9h5.1z"/>
<path d="M245.1 113.5h5.1zM245.1 116h5.1zM245.1 118.6h5.1zM224.8 103.3h20.3zM224.8 105.9h20.3zM224.8 108.4h20.3zM224.8 110.9h20.3zM224.8 113.5h20.3zM224.8 116h20.3zM224.8 118.6h20.3zM265.4 118.6h5.1zM265.4 116h5.1z"/>
<path d="M265.4 113.5h5.1zM265.4 110.9h5.1zM265.4 108.4h5.1zM265.4 105.9h5.1zM265.4 103.3h5.1zM270.5 110.9h22.8zM270.5 108.4h17.8zM270.5 105.9h12.7zM270.5 103.3h7.6zM270.5 113.5h17.8zM270.5 116h12.7zM270.5 118.6h7.6z"/>
<path d="M278.1 95.7v7.6zM278.1 118.6v7.6zM283.2 100.8v5.1zM283.2 100.8h10.1zM283.2 116v5.1zM288.3 105.9v2.5zM288.3 105.9h5zM288.3 113.5v2.5zM288.3 116h5zM293.3 100.8h2.6zM293.3 105.9h2.6zM293.3 110.9h2.6z"/>
<path d="M293.3 116h2.6zM301 100.8h2.5zM301 105.9h2.5zM301 110.9h2.5zM301 116h2.5zM303.5 100.8h17.8zM303.5 105.9h17.8zM303.5 110.9h17.8zM303.5 116h17.8zM323.8 98.2l-2.5 2.6zM323.8 103.3l-2.5 2.6zM321.3 110.9l2.5-2.5z"/>
<path d="M323.8 113.5l-2.5 2.5zM16.5 123.1h3.8zM69.8 90.6v38.1zM74.9 126.2h28zM82.5 121.1h20.4zM87.6 126.7h8.4zM87.6 124.2h5.8zM102.9 128.7h3.1zM102.9 126.2h5zM102.9 121.1h5zM69.8 128.7h33.1zM107.9 125.2l2 1z"/>
<path d="M107.9 127.2l2-1zM123.2 121.1h5zM128.2 121.1h20.4zM148.6 121.1l2.5 2.5zM153.6 121.1l-2.5 2.5zM158.7 126.2v12.7zM163.8 124.2h6.8zM171.4 131.3v2.5zM171.4 128.7v2.6zM174 126.2h3.1zM174 121.1h5zM174 128.7h3.1z"/>
<path d="M171.4 128.7h2.6zM153.6 121.1h20.4zM158.7 126.2h15.3zM194.3 121.1h5.1zM199.4 121.1h20.3zM158.7 138.9h50.8zM219.7 121.1l2.5 2.5zM222.2 123.6l2.6-2.5zM242.5 131.3v2.5zM242.5 126.2v2.5zM242.5 128.7v2.6zM245.1 126.2h3.1z"/>
<path d="M245.1 121.1h5.1zM245.1 128.7h3.1zM242.5 126.2h2.6zM242.5 128.7h2.6zM224.8 121.1h20.3zM265.4 121.1h5.1zM270.5 121.1h2.5zM273 121.1v10.2zM273 131.3h20.3zM278.1 126.2h15.2zM283.2 121.1h10.1zM293.3 121.1h2.6z"/>
<path d="M293.3 126.2h2.6zM293.3 131.3h2.6zM301 121.1h2.5zM301 126.2h2.5zM301 131.3h2.5zM303.5 121.1h17.8zM303.5 126.2h17.8zM303.5 131.3h17.8zM323.8 118.6l-2.5 2.5zM321.3 126.2l2.5-2.6zM323.8 128.7l-2.5 2.6zM400 123.1h3.8z"/>
<path d="M31.6 142.9h5.3zM87.6 147.1h2.7zM87.6 142h5.3zM151.1 159.2l2.5 2.5zM151.1 156.7l2.5 2.5zM153.6 159.2h25.4zM176.5 154.1v2.6zM179 159.2h5.1zM201.4 159.2h3zM204.4 159.2h40.7zM64.8 149h152.3zM41.9 144h185.4z"/>
<path d="M245.1 159.2h3.1zM265.4 159.2h5.1zM16.5 173.7h3.8zM151.1 161.7l2.5 2.6zM151.1 164.3l2.5 2.5zM151.1 166.8l2.5 2.6zM151.1 169.4l2.5 2.5zM151.1 171.9l2.5 2.5zM151.1 174.4l2.5 2.6zM153.6 161.7h25.4zM153.6 164.3h25.4zM153.6 166.8h25.4z"/>
<path d="M153.6 169.4h25.4zM153.6 171.9h25.4zM153.6 174.4h25.4zM153.6 177h25.4zM179 161.7h5.1zM179 164.3h5.1zM179 166.8h5.1zM179 169.4h5.1zM179 171.9h5.1zM179 174.4h5.1zM179 177h5.1zM227.3 169.4h17.8z"/>
<path d="M227.3 144v25.4zM232.4 167.4h5.3zM242.5 179.5v2.6zM242.5 166.8v12.7zM242.5 161.7v5.1zM245.1 169.4h3.1zM245.1 161.7h5.1zM245.1 166.8h5.1zM242.5 166.8h2.6zM242.5 161.7h2.6zM250.2 165.8l1.9 1zM250.2 167.8l1.9-1z"/>
<path d="M261.4 168.5h1.7zM265.4 169.4h5.1zM270.5 169.4h106.6zM378.7 168.3h9.3zM400 173.7h3.8zM31.7 188.4v39.3zM31.7 188.4h96.5zM176.5 184.6v2.5zM176.5 187.1v2.6zM176.5 189.7v2.5zM176.5 192.2v2.6zM176.5 194.8v2.5z"/>
<path d="M176.5 197.3v2.5zM176.5 199.8v10.2zM176.5 156.7v25.4zM179 182.1h5.1zM179 184.6h5.1zM179 187.1h5.1zM179 189.7h5.1zM179 192.2h5.1zM179 194.8h5.1zM179 197.3h5.1zM179 199.8h5.1zM176.5 184.6h2.5z"/>
<path d="M176.5 187.1h2.5zM176.5 189.7h2.5zM176.5 192.2h2.5zM176.5 194.8h2.5zM176.5 197.3h2.5zM176.5 199.8h2.5zM176.5 182.1h2.5zM209.5 138.9v48.2zM222.2 197.3l2.6 2.5zM209.5 187.1h68.6zM288.3 194.8v2.5zM290.8 199.8h5.1z"/>
<path d="M224.8 199.8h66zM315.6 199.8h3.1zM318.7 199.8h50.8zM369.5 194.8v5zM369.5 194.8h7.6zM374.6 199.8h2.5zM378.7 193.7h10.1zM378.7 198.8h12.5zM41.9 208h9.3zM54.1 208h33.6zM65.5 213.1h9.3zM151.1 202.4l2.5 2.5z"/>
<path d="M153.6 204.9h25.4zM176.5 210v2.5zM179 204.9h3.2zM222.2 199.8l2.6 2.6zM222.2 202.4l2.6 2.5zM222.2 212.5l2.6 2.5zM222.2 215l2.6 2.6zM247.6 215h5.1zM247.6 217.6h5.1zM224.8 215h22.8zM224.8 217.6h22.8zM269.9 215h3.1z"/>
<path d="M273 215h17.8zM278.1 187.1v30.5zM281.4 215.6h6.9zM288.3 197.3v15.2zM290.8 202.4h5.1zM290.8 204.9h5.1zM290.8 215h3.1zM290.8 217.6h3.1zM290.8 212.5h5.1zM278.1 217.6h12.7zM224.8 202.4h66zM224.8 204.9h66z"/>
<path d="M288.3 212.5h2.5zM315.6 217.6h3.1zM315.6 215h3.1zM315.6 212.5h3.1zM315.6 210h3.1zM315.6 207.4h3.1zM315.6 204.9h3.1zM315.6 202.4h3.1zM318.7 202.4h55.9zM318.7 204.9h58.4zM318.7 207.4h55.9zM374.6 199.8v2.6z"/>
<path d="M374.6 207.4v2.6zM374.6 210h2.5zM378.7 203.8h12.5zM378.7 208.9h12.5zM16.5 224.2h3.8zM31.7 227.7h96.5zM96.6 220.7h5.3zM128.2 188.4v39.3zM222.2 217.6l2.6 2.5zM222.2 220.1l2.6 2.6zM222.2 222.7l2.6 2.5zM245.1 237.9v2.5z"/>
<path d="M245.1 227.7v2.6zM245.1 230.3v2.5zM245.1 232.8v5.1zM247.6 237.9h5.1zM247.6 220.1h5.1zM247.6 222.7h5.1zM247.6 225.2h5.1zM247.6 227.7h5.1zM247.6 230.3h5.1zM247.6 232.8h5.1zM245.1 237.9h2.5zM245.1 227.7h2.5z"/>
<path d="M245.1 230.3h2.5zM245.1 232.8h2.5zM224.8 220.1h22.8zM224.8 222.7h22.8zM224.8 225.2h22.8zM335.3 228.3h10.2zM335.3 230.9h12.6zM335.3 233.4h12.6zM335.3 235.9h12.6zM400 224.2h3.8zM31.7 253.1v2.6zM31.7 257.7v.5z"/>
<path d="M31.7 255.7v.5zM31.7 250.6v2.5zM39.4 253.1v2.6zM39.4 257.7v.5zM39.4 255.7v.5zM39.4 250.6v2.5zM31.7 250.6h7.7zM47 253.1v2.6zM47 257.7v.5zM47 255.7v.5zM47 250.6v2.5zM39.4 250.6h7.6z"/>
<path d="M54.6 253.1v2.6zM54.6 257.7v.5zM54.6 255.7v.5zM54.6 250.6v2.5zM47 250.6h7.6zM62.2 253.1v2.6zM62.2 257.7v.5zM62.2 255.7v.5zM62.2 250.6v2.5zM54.6 250.6h7.6zM69.8 253.1v2.6zM69.8 257.7v.5z"/>
<path d="M69.8 255.7v.5zM69.8 250.6v2.5zM62.2 250.6h7.6zM69.8 250.6h7.7zM77.5 253.1v2.6zM77.5 257.7v.5zM77.5 255.7v.5zM77.5 250.6h7.6zM77.5 250.6v2.5zM85.1 253.1v2.6zM85.1 257.7v.5zM85.1 255.7v.5z"/>
<path d="M85.1 250.6h7.6zM85.1 250.6v2.5zM92.7 245.5v2.6zM92.7 253.1v2.6zM92.7 257.7v.5zM92.7 255.7v.5zM92.7 248.1v2.5zM92.7 250.6v2.5zM102.9 245.5v2.6zM102.9 253.1v2.6zM102.9 255.7v.5zM102.9 257.7v.5z"/>
<path d="M102.9 248.1v5zM118.1 250.6h5.1zM128.2 248.1h5.1zM128.2 253.1h5.1zM133.3 253.1h2.6zM133.3 248.1h2.6zM135.9 253.1h2.5zM135.9 248.1h2.5zM135.9 248.1v5zM135.9 253.1v5.1zM135.9 258.2v5.1zM138.4 248.1h5.1z"/>
<path d="M138.4 253.1h5.1zM138.4 258.2h5.1zM135.9 258.2h2.5zM148.6 250.6h5zM166.3 248.1v2.5zM166.3 250.6v5.1zM166.3 255.7v2.5zM166.3 258.2v7.6zM168.9 258.2h3.1zM168.9 250.6h5.1zM168.9 255.7h5.1zM168.9 248.1h3.1z"/>
<path d="M166.3 248.1h2.6zM166.3 250.6h2.6zM166.3 255.7h2.6zM166.3 258.2h2.6zM174 254.7l2 1zM174 256.7l2-1zM185.2 257.3h1.7zM189.2 248.1h5.1zM189.2 258.2h5.1zM232.4 258.8h2.7zM245.1 240.4v2.6zM245.1 243v2.5z"/>
<path d="M245.1 245.5v2.6zM245.1 248.1v2.5zM245.1 250.6v2.5zM245.1 253.1v2.6zM245.1 255.7v7.6zM247.6 240.4h5.1zM247.6 243h5.1zM247.6 245.5h5.1zM247.6 248.1h5.1zM247.6 250.6h5.1zM247.6 253.1h5.1zM247.6 255.7h5.1z"/>
<path d="M245.1 240.4h2.5zM245.1 243h2.5zM245.1 245.5h2.5zM245.1 248.1h2.5zM245.1 250.6h2.5zM245.1 253.1h2.5zM245.1 255.7h2.5zM20.3 274.7h379.7zM31.7 265.8v2.6zM31.7 258.2v2.6zM31.7 260.8v2.5zM31.7 263.3h7.7z"/>
<path d="M31.7 263.3v2.5zM39.4 258.2v2.6zM39.4 260.8v2.5zM47 258.2v2.6zM39.4 263.3h7.6zM47 260.8v2.5zM54.6 258.2v2.6zM47 263.3h7.6zM54.6 260.8v2.5zM62.2 258.2v2.6zM54.6 263.3h7.6zM62.2 260.8v2.5z"/>
<path d="M67.8 274.7v3.8zM69.8 258.2v2.6zM62.2 263.3h7.6zM69.8 260.8v2.5zM77.5 258.2v2.6zM69.8 263.3h7.7zM77.5 260.8v2.5zM85.1 258.2v2.6zM77.5 263.3h7.6zM85.1 260.8v2.5zM92.7 258.2v2.6zM85.1 263.3h7.6z"/>
<path d="M92.7 260.8v2.5zM102.9 258.2v2.6zM102.9 265.8v2.6zM102.9 260.8v5zM115.3 274.7v3.8zM135.9 265.8v2.6zM135.9 263.3v2.5zM138.4 263.3h5.1zM135.9 263.3h2.5zM148.6 260.8h5zM162.7 274.7v3.8zM166.3 265.8v2.6z"/>
<path d="M210.2 274.7v3.8zM217.1 149v111.8zM245.1 263.3v2.5zM247.6 260.8h3.1zM217.1 260.8h30.5zM257.6 274.7v3.8zM305.1 274.7v3.8zM352.5 274.7v3.8zM400 264.5v.1zM400 268.4v6.2zM400 274.6h.1zM400 22.1v252.6z"/>
<circle cx="64.8" cy="42.4" r=".51"/>
<circle cx="69.8" cy="90.6" r=".51"/>
<circle cx="74.9" cy="88.1" r=".51"/>
<circle cx="158.7" cy="88.1" r=".51"/>
<circle cx="242.5" cy="90.6" r=".51"/>
<circle cx="158.7" cy="126.2" r=".51"/>
<circle cx="242.5" cy="128.7" r=".51"/>
<circle cx="242.5" cy="166.8" r=".51"/>
<circle cx="176.5" cy="194.8" r=".51"/>
<circle cx="176.5" cy="192.2" r=".51"/>
<circle cx="176.5" cy="187.1" r=".51"/>
<circle cx="176.5" cy="197.3" r=".51"/>
<circle cx="176.5" cy="199.8" r=".51"/>
<circle cx="176.5" cy="189.7" r=".51"/>
<circle cx="245.1" cy="230.3" r=".51"/>
<circle cx="245.1" cy="232.8" r=".51"/>
<circle cx="245.1" cy="237.9" r=".51"/>
<circle cx="39.4" cy="250.6" r=".51"/>
<circle cx="47" cy="250.6" r=".51"/>
<circle cx="54.6" cy="250.6" r=".51"/>
<circle cx="62.2" cy="250.6" r=".51"/>
<circle cx="69.8" cy="250.6" r=".51"/>
<circle cx="77.5" cy="250.6" r=".51"/>
<circle cx="85.1" cy="250.6" r=".51"/>
<circle cx="92.7" cy="250.6" r=".51"/>
<circle cx="135.9" cy="258.2" r=".51"/>
<circle cx="135.9" cy="253.1" r=".51"/>
<circle cx="135.9" cy="248.1" r=".51"/>
<circle cx="166.3" cy="255.7" r=".51"/>
<circle cx="166.3" cy="250.6" r=".51"/>
<circle cx="166.3" cy="258.2" r=".51"/>
<circle cx="245.1" cy="255.7" r=".51"/>
<circle cx="245.1" cy="248.1" r=".51"/>
<circle cx="245.1" cy="243" r=".51"/>
<circle cx="245.1" cy="245.5" r=".51"/>
<circle cx="245.1" cy="250.6" r=".51"/>
<circle cx="245.1" cy="253.1" r=".51"/>
<circle cx="245.1" cy="240.4" r=".51"/>
<circle cx="31.7" cy="263.3" r=".51"/>
<circle cx="39.4" cy="263.3" r=".51"/>
<circle cx="47" cy="263.3" r=".51"/>
<circle cx="54.6" cy="263.3" r=".51"/>
<circle cx="62.2" cy="263.3" r=".51"/>
<circle cx="69.8" cy="263.3" r=".51"/>
<circle cx="77.5" cy="263.3" r=".51"/>
<circle cx="85.1" cy="263.3" r=".51"/>
<circle cx="135.9" cy="263.3" r=".51"/>
</g>
<g fill="#000" stroke="#000" stroke-width=".28">
<path d="M28.7 35.8v3zM28.7 35.8h11.7zM28.7 38.8h11.7zM40.4 35.8l1.5 1.5zM41.9 37.3l-1.5 1.5zM32 40.9v3zM32 40.9h8.4zM32 43.9h8.4zM40.4 40.9l1.5 1.5zM41.9 42.4l-1.5 1.5zM295.9 55.8h5.1zM295.9 54.3v1.5z"/>
<path d="M295.9 59.4v1.5zM295.9 54.3h5.1zM301 54.3v1.5zM295.9 59.4h5.1zM295.9 60.9h5.1zM295.9 66h5.1zM295.9 64.5v1.5zM295.9 71.1h5.1zM295.9 69.5v1.6zM295.9 76.1h5.1zM295.9 74.6v1.5zM295.9 79.7v1.5z"/>
<path d="M301 59.4v1.5zM295.9 64.5h5.1zM301 64.5v1.5zM295.9 69.5h5.1zM301 69.5v1.6zM295.9 74.6h5.1zM301 74.6v1.5zM295.9 79.7h5.1zM26.2 91.6v3.1zM30.2 86.5v3.1zM26.2 91.6h14.2zM26.2 94.7h14.2z"/>
<path d="M30.2 86.5h10.2zM30.2 89.6h10.2zM40.4 91.6l1.5 1.6zM40.4 94.7l1.5-1.5zM40.4 86.5l1.5 1.6zM41.9 88.1l-1.5 1.5zM169.5 95.7h3.8zM240.6 95.7h3.8zM295.9 81.2h5.1zM295.9 86.3h5.1zM295.9 84.8v1.5zM295.9 91.4h5.1z"/>
<path d="M295.9 89.9v1.5zM295.9 96.5h5.1zM295.9 94.9v1.6zM301 79.7v1.5zM295.9 84.8h5.1zM301 84.8v1.5zM295.9 89.9h5.1zM301 89.9v1.5zM295.9 94.9h5.1zM301 94.9v1.6zM295.9 101.5h5.1zM295.9 100v1.5z"/>
<path d="M295.9 106.6h5.1zM295.9 105.1v1.5zM295.9 111.7h5.1zM295.9 110.2v1.5zM295.9 116.8h5.1zM295.9 115.3v1.5zM295.9 100h5.1zM301 100v1.5zM295.9 105.1h5.1zM301 105.1v1.5zM295.9 110.2h5.1zM301 110.2v1.5z"/>
<path d="M295.9 115.3h5.1zM301 115.3v1.5zM169.5 133.8h3.8zM240.6 133.8h3.8zM295.9 121.9h5.1zM295.9 120.3v1.6zM295.9 126.9h5.1zM295.9 125.4v1.5zM295.9 132h5.1zM295.9 130.5v1.5zM295.9 120.3h5.1zM301 120.3v1.6z"/>
<path d="M295.9 125.4h5.1zM301 125.4v1.5zM295.9 130.5h5.1zM301 130.5v1.5zM29.3 142.4v3.1zM29.3 142.4h11.1zM29.3 145.5h11.1zM40.4 142.4l1.5 1.6zM41.9 144l-1.5 1.5zM176.5 154.1l-1.3 1.9zM176.5 154.1l1.3 1.9zM377.1 169.4l1.6-1.6z"/>
<path d="M377.1 169.4l1.6 1.5zM378.7 167.8h15.1zM378.7 170.9h15.1zM393.8 167.8v3.1zM240.6 182.1h3.8zM288.3 194.8l-1.3 1.9zM288.3 194.8l1.2 1.9zM377.1 194.8l1.6-1.6zM377.1 194.8l1.6 1.5zM377.1 199.8l1.6-1.5zM377.1 199.8l1.6 1.6zM378.7 193.2h16z"/>
<path d="M378.7 196.3h16zM378.7 198.3h18.4zM394.7 193.2v3.1zM397.1 198.3v3.1zM174.6 212.5h3.8zM377.1 204.9l1.6-1.5zM377.1 204.9l1.6 1.5zM377.1 210l1.6-1.6zM377.1 210l1.6 1.5zM378.7 201.4h18.4zM378.7 203.4h18.4zM378.7 206.4h18.4z"/>
<path d="M378.7 208.4h18.4zM378.7 211.5h18.4zM397.1 203.4v3zM397.1 208.4v3.1zM92.7 245.5l-1.3 1.9zM92.7 245.5l1.3 1.9zM102.9 245.5l-1.3 1.9zM102.9 245.5l1.2 1.9zM313.7 249.3h86.3zM313.7 254.4h86.3zM313.7 259.5h58.4zM372.1 259.5h27.9z"/>
<path d="M372.1 259.5v5.1zM29.8 268.4h3.9zM101 268.4h3.8zM134 268.4h3.8zM164.4 268.4h3.9zM243.2 265.8h3.8zM313.7 264.6h58.4zM313.7 269.7h86.3zM372.1 264.6h27.9zM400 268.4v1.3z"/>
</g>
<g fill="none" stroke="#000" stroke-width=".25">
<circle cx="107" cy="90.6" r=".99"/>
<circle cx="178.1" cy="88.1" r=".99"/>
<circle cx="178.1" cy="90.6" r=".99"/>
<circle cx="249.2" cy="88.1" r="1"/>
<circle cx="249.2" cy="90.6" r="1"/>
<circle cx="107" cy="128.7" r=".99"/>
<circle cx="178.1" cy="126.2" r=".99"/>
<circle cx="178.1" cy="128.7" r=".99"/>
<circle cx="249.2" cy="128.7" r="1"/>
<circle cx="249.2" cy="126.2" r="1"/>
<circle cx="200.4" cy="159.2" r=".99"/>
<circle cx="249.2" cy="159.2" r="1"/>
<circle cx="249.2" cy="169.4" r="1"/>
<circle cx="314.6" cy="199.8" r="1"/>
<circle cx="183.1" cy="204.9" r=".99"/>
<circle cx="268.9" cy="215" r="1"/>
<circle cx="294.9" cy="215" r="1"/>
<circle cx="294.9" cy="217.6" r="1"/>
<circle cx="314.6" cy="217.6" r="1"/>
<circle cx="314.6" cy="215" r="1"/>
<circle cx="314.6" cy="212.5" r="1"/>
<circle cx="314.6" cy="204.9" r="1"/>
<circle cx="314.6" cy="202.4" r="1"/>
<circle cx="314.6" cy="210" r="1"/>
<circle cx="314.6" cy="207.4" r="1"/>
<circle cx="173" cy="248.1" r=".99"/>
<circle cx="173" cy="258.2" r=".99"/>
<circle cx="251.7" cy="260.8" r="1"/>
</g>
<g fill="#000" stroke="#000" stroke-width=".61">
<path d="M20.3 22.1v252.6zM20.3 22.1h379.7zM107.9 62.7v30.5zM107.9 62.7h15.3zM179 62.7v30.5zM179 62.7h15.3zM250.2 62.7v30.5zM250.2 62.7h15.2zM107.9 93.2h15.3zM123.2 62.7v30.5zM179 93.2h15.3zM194.3 62.7v30.5z"/>
<path d="M250.2 93.2h15.2zM265.4 62.7v30.5zM107.9 100.8v30.5zM107.9 100.8h15.3zM179 100.8v30.5zM179 100.8h15.3zM250.2 100.8v30.5zM250.2 100.8h15.2zM107.9 131.3h15.3zM123.2 100.8v30.5zM179 131.3h15.3zM194.3 100.8v30.5z"/>
<path d="M250.2 131.3h15.2zM265.4 100.8v30.5zM184.1 156.7v50.7zM184.1 156.7h15.3zM250.2 156.7v15.2zM250.2 156.7h15.2zM250.2 171.9h15.2zM265.4 156.7v15.2zM295.9 197.3v22.8zM295.9 197.3h17.8zM184.1 207.4h15.3zM199.4 156.7v50.7z"/>
<path d="M252.7 212.5v50.8zM252.7 212.5h15.2zM295.9 220.1h17.8zM313.7 197.3v22.8zM174 245.5v15.3zM174 245.5h15.2zM283.2 244.3v30.4zM313.7 254.4v5.1zM313.7 249.3v5.1zM313.7 244.3v5zM313.7 244.3h86.3zM283.2 244.3h30.5z"/>
<path d="M400 254.4v5.1zM400 249.3v5.1zM400 244.3v5zM400 22.1v222.2zM20.3 274.7h262.9zM174 260.8h15.2zM189.2 245.5v15.3zM252.7 263.3h15.2zM267.9 212.5v50.8zM283.2 274.7h30.5zM313.7 274.7h86.3zM313.7 269.7v5z"/>
<path d="M313.7 264.6v5.1zM313.7 259.5v5.1zM400 268.4v6.3zM400 264.6v3.8zM400 259.5v5.1z"/>
</g>
<path d="M74.9 34.8v10.1zM334 90.6v10.2zM334 90.6h55.8zM334 100.8v7.6zM334 108.4h55.8zM334 100.8h55.8zM389.8 100.8v7.6zM389.8 90.6v10.2zM128.2 245.5v10.2zM143.5 245.5v10.2zM143.5 255.7v10.1z" fill="#000" stroke="#000" stroke-width=".42"/>
<path d="M74.9 34.8a5.1 5.1 0 0 1 5.1 5 5.1 5.1 0 0 1-5.1 5.1M128.2 245.5a5.1 5.1 0 0 0-5 5.1 5.1 5.1 0 0 0 5 5.1M143.5 245.5a5.1 5.1 0 0 1 5.1 5.1 5.1 5.1 0 0 1-5.1 5.1 5.1 5.1 0 0 1 5.1 5.1 5.1 5.1 0 0 1-5.1 5" fill="none" stroke="#000" stroke-width=".42"/>
<g fill="#000" stroke="#000" stroke-width=".25">
<path d="M364.4 90.6h25.4v10.2h-25.4zM29.7 256.2h4.1v.5h-4.1zM29.7 257.2h4.1v.5h-4.1zM37.3 256.2h4.1v.5h-4.1zM37.3 257.2h4.1v.5h-4.1zM45 256.2h4v.5h-4zM45 257.2h4v.5h-4zM52.6 256.2h4v.5h-4zM52.6 257.2h4v.5h-4zM60.2 256.2h4.1v.5h-4.1zM60.2 257.2h4.1v.5h-4.1zM67.8 256.2h4.1v.5h-4.1z"/>
<path d="M67.8 257.2h4.1v.5h-4.1zM75.4 256.2h4.1v.5h-4.1zM75.4 257.2h4.1v.5h-4.1zM83.1 256.2h4v.5h-4zM83.1 257.2h4v.5h-4zM90.7 256.2h4v.5h-4zM90.7 257.2h4v.5h-4zM100.8 257.2h4.1v.5h-4.1zM100.8 256.2h4.1v.5h-4.1z"/>
</g>
<path d="M16.5 18.2v260.3zM16.5 18.2h387.3zM16.5 278.5h387.3zM403.8 18.2v260.3z" fill="#000" stroke="#000" stroke-width=".32"/>
<path d="M41.9 55.1h33zM74.9 55.1l5.1 5.1zM222.2 50v172.7zM222.2 50l5.1-5.1zM227.3 44.9h101.6zM323.8 50v78.7zM328.9 44.9l-5.1 5.1zM328.9 44.9h48.2zM80 60.2v58.4zM151.1 67.8v134.6z" fill="#000" stroke="#000" stroke-width=".76"/>
<use href="#words"/>
</svg>
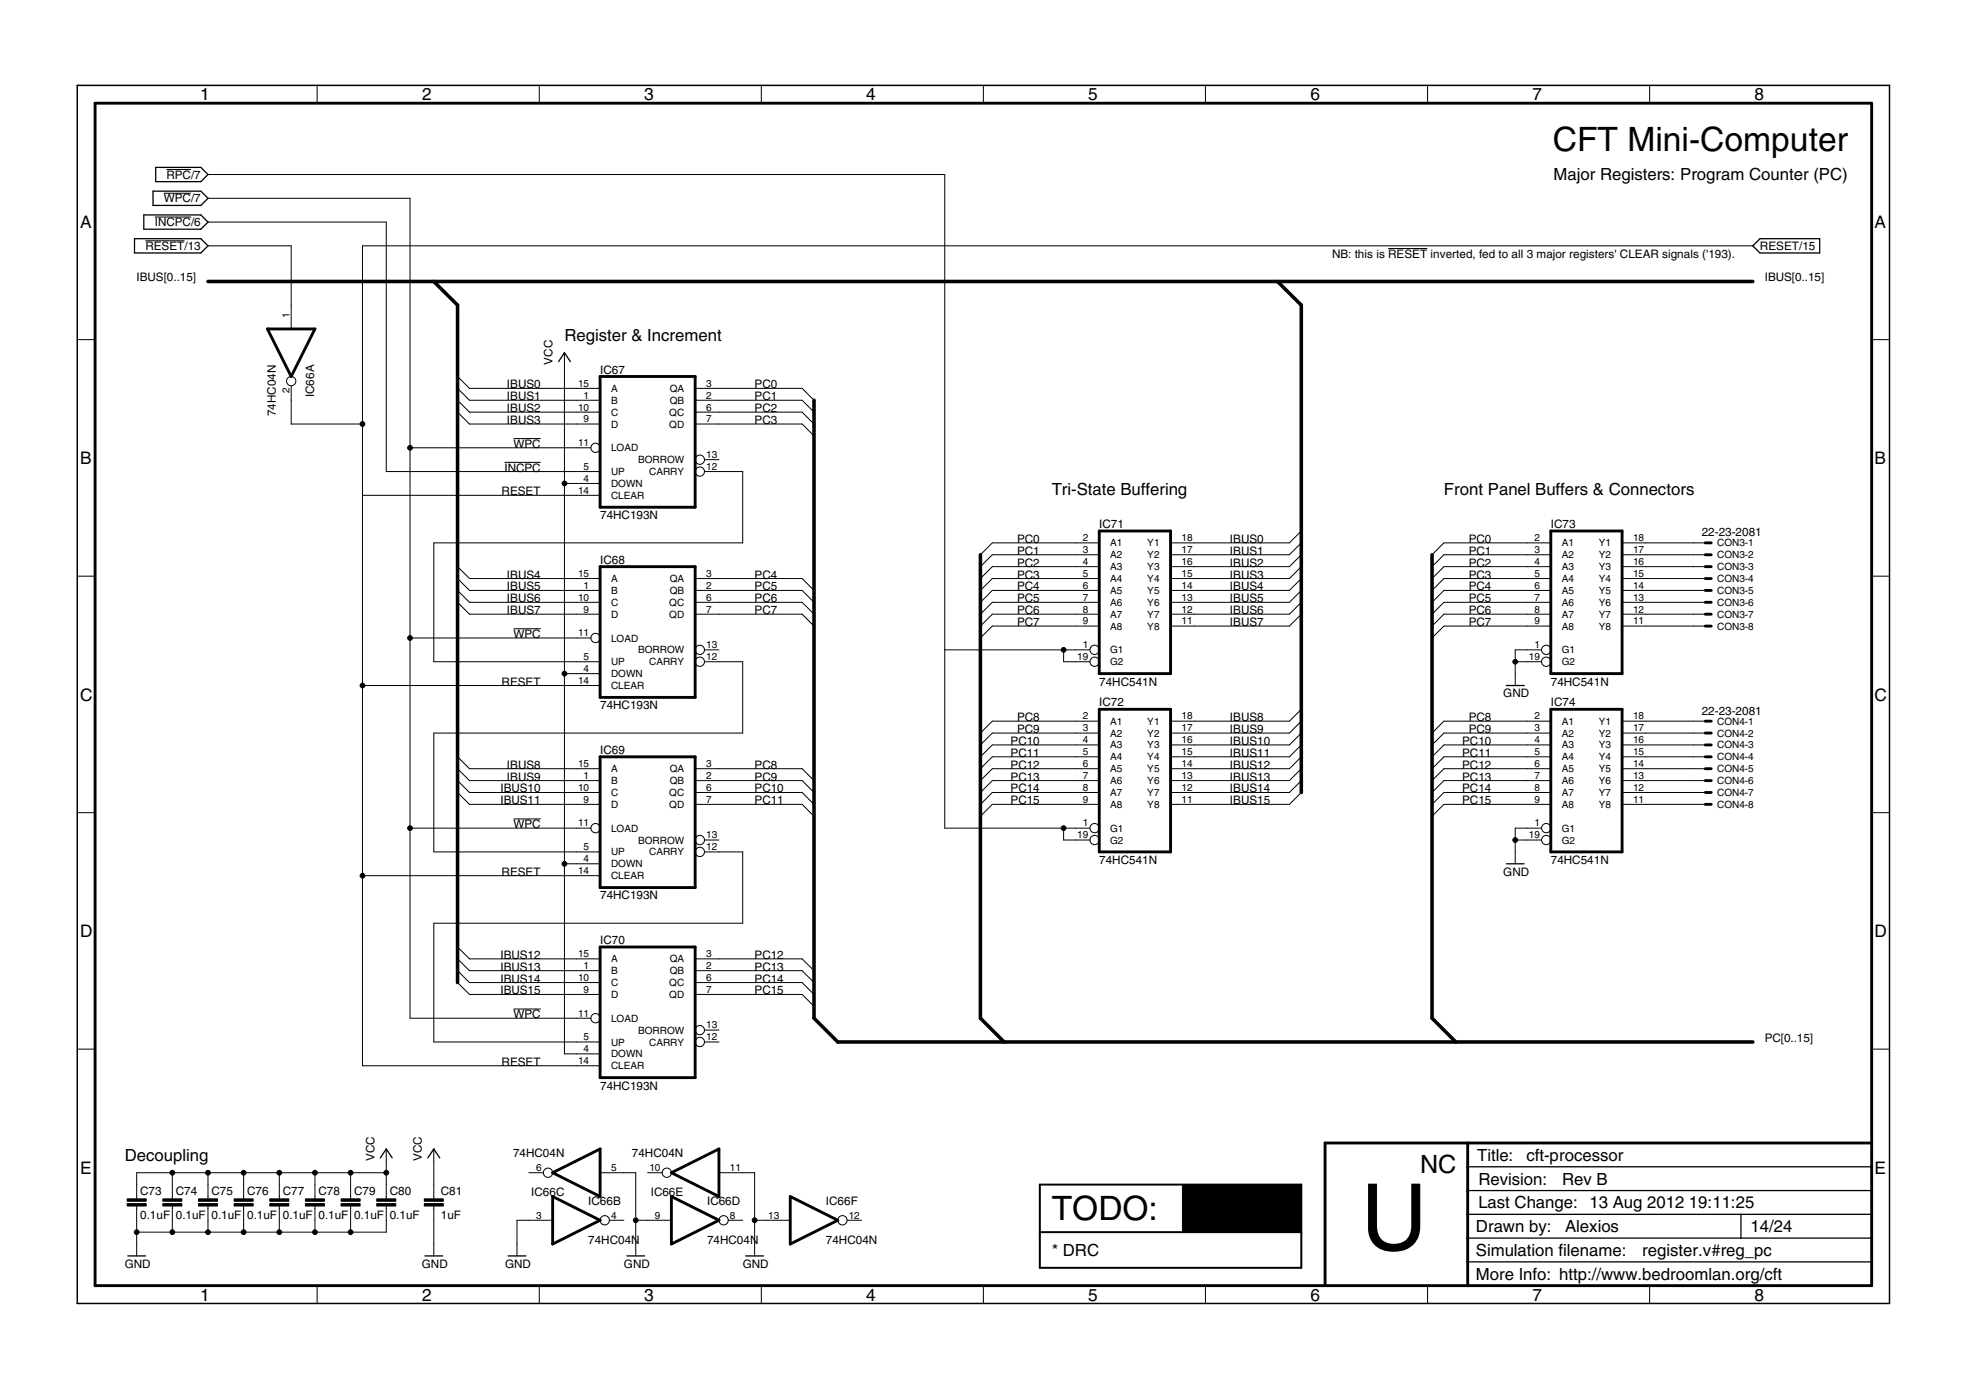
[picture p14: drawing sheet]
<svg xmlns="http://www.w3.org/2000/svg" width="420mm" height="297mm" viewBox="0 0 420 297" stroke-linecap="round" stroke-linejoin="round" font-family="sans-serif">
<defs><g id="words">
<text font-size="19.7" x="290.8" y="267.1">U</text>
<g font-size="7.2">
<text x="331.8" y="32.2">CFT Mini-Computer</text>
<text x="224.8" y="260.8">TODO:</text>
</g>
<text font-size="5.4" x="303.5" y="250.6">NC</text>
<g font-size="3.7">
<text x="42.7" y="21.5">1</text>
<text x="90.2" y="21.5">2</text>
<text x="137.7" y="21.5">3</text>
<text x="185.1" y="21.5">4</text>
<text x="232.6" y="21.5">5</text>
<text x="280" y="21.5">6</text>
<text x="327.5" y="21.5">7</text>
<text x="375" y="21.5">8</text>
<text x="17.1" y="48.6">A</text>
<text x="400.6" y="48.6">A</text>
<text x="17.1" y="99.2">B</text>
<text x="400.6" y="99.2">B</text>
<text x="17.1" y="149.7">C</text>
<text x="400.6" y="149.7">C</text>
<text x="17.1" y="200.2">D</text>
<text x="400.6" y="200.2">D</text>
<text x="17.1" y="250.8">E</text>
<text x="400.6" y="250.8">E</text>
<text x="42.7" y="277.9">1</text>
<text x="90.2" y="277.9">2</text>
<text x="137.7" y="277.9">3</text>
<text x="185.1" y="277.9">4</text>
<text x="232.6" y="277.9">5</text>
<text x="280" y="277.9">6</text>
<text x="327.5" y="277.9">7</text>
<text x="375" y="277.9">8</text>
</g>
<g font-size="3.6">
<text x="332" y="38.6">Major Registers: Program Counter (PC)</text>
<text x="120.6" y="72.8">Register &amp; Increment</text>
<text x="224.8" y="105.9">Tri-State Buffering</text>
<text x="308.6" y="105.9">Front Panel Buffers &amp; Connectors</text>
<text x="26.7" y="248.1">Decoupling</text>
<text x="315.7" y="248.1">Title:</text>
<text x="326.2" y="248.2">cft-processor</text>
<text x="315.9" y="253.2">Revision:</text>
<text x="333.8" y="253.3">Rev B</text>
<text x="315.4" y="263.3">Drawn by:</text>
<text x="315.9" y="258.2">Last Change: 13 Aug 2012</text>
<text x="334.5" y="263.3">Alexios</text>
<text x="361" y="258.1">19:11:25</text>
<text x="374.1" y="263.2">14/24</text>
<text x="224.8" y="268.4">* DRC</text>
<text x="315.4" y="268.4">Simulation filename:</text>
<text x="351" y="268.4">register.v#reg_pc</text>
<text x="315.4" y="273.5">More Info: http://www.bedroomlan.org/cft</text>
</g>
<g font-size="2.5">
<text x="35.6" y="38.2">RPC/7</text>
<text x="35" y="43.3">WPC/7</text>
<text x="31.1" y="53.4">RESET/13</text>
<text x="33.1" y="48.3">INCPC/6</text>
<text x="376.1" y="53.4">RESET/15</text>
<text x="284.7" y="55.1">NB: this is RESET inverted, fed to all 3 major registers' CLEAR signals ('193).</text>
<text x="29.2" y="60.1">IBUS[0..15]</text>
<text x="377.1" y="60.1">IBUS[0..15]</text>
<text x="118.1" y="77.9" transform="rotate(-90 118.1 77.9)">VCC</text>
<text x="108.3" y="83">IBUS0</text>
<text x="128.3" y="79.8">IC67</text>
<text x="161.3" y="83">PC0</text>
<text x="58.9" y="88.9" transform="rotate(-90 58.9 88.9)">74HC04N</text>
<text x="67.2" y="84.9" transform="rotate(-90 67.2 84.9)">IC66A</text>
<text x="108.3" y="85.5">IBUS1</text>
<text x="108.3" y="88.1">IBUS2</text>
<text x="161.3" y="85.5">PC1</text>
<text x="161.3" y="88.1">PC2</text>
<text x="108.3" y="90.6">IBUS3</text>
<text x="109.8" y="95.7">WPC</text>
<text x="161.3" y="90.6">PC3</text>
<text x="107.8" y="100.8">INCPC</text>
<text x="107.2" y="105.9">RESET</text>
<text x="128.3" y="110.9">74HC193N</text>
<text x="234.9" y="112.8">IC71</text>
<text x="331.4" y="112.8">IC73</text>
<text x="217.4" y="116">PC0</text>
<text x="217.4" y="118.6">PC1</text>
<text x="262.9" y="116">IBUS0</text>
<text x="262.9" y="118.6">IBUS1</text>
<text x="313.9" y="116">PC0</text>
<text x="313.9" y="118.6">PC1</text>
<text x="363.7" y="114.6">22-23-2081</text>
<text x="108.3" y="123.6">IBUS4</text>
<text x="128.3" y="120.5">IC68</text>
<text x="161.3" y="123.6">PC4</text>
<text x="217.4" y="121.1">PC2</text>
<text x="217.4" y="123.6">PC3</text>
<text x="262.9" y="121.1">IBUS2</text>
<text x="262.9" y="123.6">IBUS3</text>
<text x="313.9" y="121.1">PC2</text>
<text x="313.9" y="123.6">PC3</text>
<text x="108.3" y="126.2">IBUS5</text>
<text x="108.3" y="128.7">IBUS6</text>
<text x="108.3" y="131.3">IBUS7</text>
<text x="161.3" y="126.2">PC5</text>
<text x="161.3" y="128.7">PC6</text>
<text x="161.3" y="131.3">PC7</text>
<text x="217.4" y="126.2">PC4</text>
<text x="217.4" y="128.7">PC5</text>
<text x="217.4" y="131.3">PC6</text>
<text x="262.9" y="126.2">IBUS4</text>
<text x="262.9" y="128.7">IBUS5</text>
<text x="262.9" y="131.3">IBUS6</text>
<text x="313.9" y="126.2">PC4</text>
<text x="313.9" y="128.7">PC5</text>
<text x="313.9" y="131.3">PC6</text>
<text x="109.8" y="136.3">WPC</text>
<text x="217.4" y="133.8">PC7</text>
<text x="262.9" y="133.8">IBUS7</text>
<text x="313.9" y="133.8">PC7</text>
<text x="107.2" y="146.5">RESET</text>
<text x="234.9" y="146.5">74HC541N</text>
<text x="321.3" y="149">GND</text>
<text x="331.4" y="146.5">74HC541N</text>
<text x="128.3" y="151.6">74HC193N</text>
<text x="217.4" y="154.1">PC8</text>
<text x="234.9" y="150.9">IC72</text>
<text x="262.9" y="154.1">IBUS8</text>
<text x="313.9" y="154.1">PC8</text>
<text x="331.4" y="150.9">IC74</text>
<text x="363.7" y="152.7">22-23-2081</text>
<text x="128.3" y="161.1">IC69</text>
<text x="216" y="159.2">PC10</text>
<text x="216" y="161.7">PC11</text>
<text x="217.4" y="156.6">PC9</text>
<text x="262.9" y="156.6">IBUS9</text>
<text x="262.9" y="159.2">IBUS10</text>
<text x="262.9" y="161.7">IBUS11</text>
<text x="312.5" y="159.2">PC10</text>
<text x="312.5" y="161.7">PC11</text>
<text x="313.9" y="156.6">PC9</text>
<text x="108.3" y="164.3">IBUS8</text>
<text x="108.3" y="166.8">IBUS9</text>
<text x="161.3" y="164.3">PC8</text>
<text x="161.3" y="166.8">PC9</text>
<text x="216" y="164.3">PC12</text>
<text x="216" y="166.8">PC13</text>
<text x="262.9" y="164.3">IBUS12</text>
<text x="262.9" y="166.8">IBUS13</text>
<text x="312.5" y="164.3">PC12</text>
<text x="312.5" y="166.8">PC13</text>
<text x="106.9" y="169.3">IBUS10</text>
<text x="106.9" y="171.9">IBUS11</text>
<text x="161.3" y="169.3">PC10</text>
<text x="161.3" y="171.9">PC11</text>
<text x="216" y="169.3">PC14</text>
<text x="216" y="171.9">PC15</text>
<text x="262.9" y="169.3">IBUS14</text>
<text x="262.9" y="171.9">IBUS15</text>
<text x="312.5" y="169.3">PC14</text>
<text x="312.5" y="171.9">PC15</text>
<text x="109.8" y="177">WPC</text>
<text x="234.9" y="184.6">74HC541N</text>
<text x="331.4" y="184.6">74HC541N</text>
<text x="107.2" y="187.1">RESET</text>
<text x="321.3" y="187.1">GND</text>
<text x="128.3" y="192.2">74HC193N</text>
<text x="128.3" y="201.7">IC70</text>
<text x="106.9" y="204.9">IBUS12</text>
<text x="106.9" y="207.4">IBUS13</text>
<text x="106.9" y="210">IBUS14</text>
<text x="161.3" y="204.9">PC12</text>
<text x="161.3" y="207.4">PC13</text>
<text x="161.3" y="210">PC14</text>
<text x="106.9" y="212.5">IBUS15</text>
<text x="161.3" y="212.5">PC15</text>
<text x="109.8" y="217.6">WPC</text>
<text x="107.2" y="227.8">RESET</text>
<text x="377.1" y="222.7">PC[0..15]</text>
<text x="128.3" y="232.8">74HC193N</text>
<text x="80" y="248.1" transform="rotate(-90 80 248.1)">VCC</text>
<text x="90.2" y="248.1" transform="rotate(-90 90.2 248.1)">VCC</text>
<text x="109.7" y="247.3">74HC04N</text>
<text x="135" y="247.3">74HC04N</text>
<text x="30" y="255.3">C73</text>
<text x="37.6" y="255.3">C74</text>
<text x="45.2" y="255.3">C75</text>
<text x="52.8" y="255.3">C76</text>
<text x="60.4" y="255.3">C77</text>
<text x="68.1" y="255.3">C78</text>
<text x="75.7" y="255.3">C79</text>
<text x="83.3" y="255.3">C80</text>
<text x="94.2" y="255.3">C81</text>
<text x="113.5" y="255.6">IC66C</text>
<text x="125.7" y="257.6">IC66B</text>
<text x="139.1" y="255.6">IC66E</text>
<text x="151.1" y="257.6">IC66D</text>
<text x="176.5" y="257.6">IC66F</text>
<text x="30" y="260.4">0.1uF</text>
<text x="37.6" y="260.4">0.1uF</text>
<text x="45.2" y="260.4">0.1uF</text>
<text x="52.8" y="260.4">0.1uF</text>
<text x="60.4" y="260.4">0.1uF</text>
<text x="68.1" y="260.4">0.1uF</text>
<text x="75.7" y="260.4">0.1uF</text>
<text x="83.3" y="260.4">0.1uF</text>
<text x="94.2" y="260.4">1uF</text>
<text x="125.7" y="265.8">74HC04N</text>
<text x="151.1" y="265.8">74HC04N</text>
<text x="176.5" y="265.8">74HC04N</text>
<text x="26.7" y="270.9">GND</text>
<text x="90.2" y="270.9">GND</text>
<text x="107.9" y="270.9">GND</text>
<text x="133.3" y="270.9">GND</text>
<text x="158.7" y="270.9">GND</text>
</g>
<g font-size="2.1">
<text x="61.9" y="68" transform="rotate(-90 61.9 68)">1</text>
<text x="61.9" y="84" transform="rotate(-90 61.9 84)">2</text>
<text x="123.5" y="82.6">15</text>
<text x="130.6" y="83.8">A</text>
<text x="143.1" y="83.8">QA</text>
<text x="150.9" y="82.6">3</text>
<text x="123.5" y="87.7">10</text>
<text x="124.7" y="85.2">1</text>
<text x="130.6" y="86.3">B</text>
<text x="130.6" y="88.8">C</text>
<text x="143" y="88.8">QC</text>
<text x="143.1" y="86.3">QB</text>
<text x="150.9" y="87.7">6</text>
<text x="150.9" y="85.2">2</text>
<text x="123.5" y="95.3">11</text>
<text x="124.7" y="90.3">9</text>
<text x="130.6" y="91.4">D</text>
<text x="143" y="91.4">QD</text>
<text x="150.9" y="90.3">7</text>
<text x="124.7" y="100.4">5</text>
<text x="130.6" y="101.5">UP</text>
<text x="130.6" y="96.5">LOAD</text>
<text x="136.4" y="99">BORROW</text>
<text x="138.8" y="101.5">CARRY</text>
<text x="150.9" y="97.9">13</text>
<text x="150.9" y="100.4">12</text>
<text x="123.5" y="105.5">14</text>
<text x="124.7" y="103">4</text>
<text x="130.6" y="104.1">DOWN</text>
<text x="130.6" y="106.6">CLEAR</text>
<text x="231.4" y="115.7">2</text>
<text x="231.4" y="118.2">3</text>
<text x="237.3" y="116.8">A1</text>
<text x="237.3" y="119.3">A2</text>
<text x="245.2" y="119.3">Y2</text>
<text x="245.2" y="116.8">Y1</text>
<text x="252.5" y="118.2">17</text>
<text x="252.5" y="115.7">18</text>
<text x="327.9" y="115.7">2</text>
<text x="327.9" y="118.2">3</text>
<text x="333.8" y="116.8">A1</text>
<text x="333.8" y="119.3">A2</text>
<text x="341.7" y="119.3">Y2</text>
<text x="341.7" y="116.8">Y1</text>
<text x="349" y="118.2">17</text>
<text x="349" y="115.7">18</text>
<text x="367" y="116.8">CON3-1</text>
<text x="367" y="119.3">CON3-2</text>
<text x="123.5" y="123.3">15</text>
<text x="124.7" y="125.8">1</text>
<text x="130.6" y="124.4">A</text>
<text x="143.1" y="124.4">QA</text>
<text x="150.9" y="125.8">2</text>
<text x="150.9" y="123.3">3</text>
<text x="231.4" y="120.7">4</text>
<text x="231.4" y="123.3">5</text>
<text x="231.4" y="125.8">6</text>
<text x="237.3" y="121.9">A3</text>
<text x="237.3" y="124.4">A4</text>
<text x="245.2" y="124.4">Y4</text>
<text x="245.2" y="121.9">Y3</text>
<text x="252.5" y="125.8">14</text>
<text x="252.5" y="123.3">15</text>
<text x="252.5" y="120.7">16</text>
<text x="327.9" y="120.7">4</text>
<text x="327.9" y="123.3">5</text>
<text x="327.9" y="125.8">6</text>
<text x="333.8" y="121.9">A3</text>
<text x="333.8" y="124.4">A4</text>
<text x="341.7" y="124.4">Y4</text>
<text x="341.7" y="121.9">Y3</text>
<text x="349" y="125.8">14</text>
<text x="349" y="123.3">15</text>
<text x="349" y="120.7">16</text>
<text x="367" y="121.9">CON3-3</text>
<text x="367" y="124.4">CON3-4</text>
<text x="123.5" y="128.4">10</text>
<text x="124.7" y="130.9">9</text>
<text x="130.6" y="126.9">B</text>
<text x="130.6" y="129.5">C</text>
<text x="143" y="129.5">QC</text>
<text x="143.1" y="126.9">QB</text>
<text x="150.9" y="130.9">7</text>
<text x="150.9" y="128.4">6</text>
<text x="231.4" y="128.4">7</text>
<text x="231.4" y="130.9">8</text>
<text x="237.3" y="126.9">A5</text>
<text x="237.3" y="129.5">A6</text>
<text x="245.2" y="129.5">Y6</text>
<text x="245.2" y="126.9">Y5</text>
<text x="252.5" y="130.9">12</text>
<text x="252.5" y="128.4">13</text>
<text x="327.9" y="128.4">7</text>
<text x="327.9" y="130.9">8</text>
<text x="333.8" y="126.9">A5</text>
<text x="333.8" y="129.5">A6</text>
<text x="341.7" y="129.5">Y6</text>
<text x="341.7" y="126.9">Y5</text>
<text x="349" y="130.9">12</text>
<text x="349" y="128.4">13</text>
<text x="367" y="126.9">CON3-5</text>
<text x="367" y="129.5">CON3-6</text>
<text x="123.5" y="136">11</text>
<text x="130.6" y="132">D</text>
<text x="130.6" y="137.1">LOAD</text>
<text x="143" y="132">QD</text>
<text x="231.4" y="133.4">9</text>
<text x="237.3" y="132">A7</text>
<text x="237.3" y="134.6">A8</text>
<text x="245.2" y="134.6">Y8</text>
<text x="245.2" y="132">Y7</text>
<text x="252.5" y="133.4">11</text>
<text x="327.9" y="133.4">9</text>
<text x="333.8" y="132">A7</text>
<text x="333.8" y="134.6">A8</text>
<text x="341.7" y="134.6">Y8</text>
<text x="341.7" y="132">Y7</text>
<text x="349" y="133.4">11</text>
<text x="367" y="132">CON3-7</text>
<text x="367" y="134.6">CON3-8</text>
<text x="124.7" y="141.1">5</text>
<text x="124.7" y="143.6">4</text>
<text x="130.6" y="142.2">UP</text>
<text x="136.4" y="139.6">BORROW</text>
<text x="138.8" y="142.2">CARRY</text>
<text x="150.9" y="138.5">13</text>
<text x="150.9" y="141.1">12</text>
<text x="230.2" y="141.1">19</text>
<text x="231.4" y="138.5">1</text>
<text x="237.3" y="139.6">G1</text>
<text x="237.3" y="142.2">G2</text>
<text x="326.7" y="141.1">19</text>
<text x="327.9" y="138.5">1</text>
<text x="333.8" y="139.6">G1</text>
<text x="333.8" y="142.2">G2</text>
<text x="123.5" y="146.1">14</text>
<text x="130.6" y="144.7">DOWN</text>
<text x="130.6" y="147.3">CLEAR</text>
<text x="231.4" y="153.8">2</text>
<text x="237.3" y="154.9">A1</text>
<text x="245.2" y="154.9">Y1</text>
<text x="252.5" y="153.8">18</text>
<text x="327.9" y="153.8">2</text>
<text x="333.8" y="154.9">A1</text>
<text x="341.7" y="154.9">Y1</text>
<text x="349" y="153.8">18</text>
<text x="367" y="154.9">CON4-1</text>
<text x="231.4" y="156.3">3</text>
<text x="231.4" y="158.8">4</text>
<text x="231.4" y="161.4">5</text>
<text x="237.3" y="157.4">A2</text>
<text x="237.3" y="159.9">A3</text>
<text x="245.2" y="160">Y3</text>
<text x="245.2" y="157.4">Y2</text>
<text x="252.5" y="161.4">15</text>
<text x="252.5" y="158.8">16</text>
<text x="252.5" y="156.3">17</text>
<text x="327.9" y="156.3">3</text>
<text x="327.9" y="158.8">4</text>
<text x="327.9" y="161.4">5</text>
<text x="333.8" y="157.4">A2</text>
<text x="333.8" y="159.9">A3</text>
<text x="341.7" y="160">Y3</text>
<text x="341.7" y="157.4">Y2</text>
<text x="349" y="161.4">15</text>
<text x="349" y="158.8">16</text>
<text x="349" y="156.3">17</text>
<text x="367" y="157.4">CON4-2</text>
<text x="367" y="159.9">CON4-3</text>
<text x="123.5" y="163.9">15</text>
<text x="124.7" y="166.5">1</text>
<text x="130.6" y="165">A</text>
<text x="130.6" y="167.6">B</text>
<text x="143.1" y="167.6">QB</text>
<text x="143.1" y="165">QA</text>
<text x="150.9" y="166.5">2</text>
<text x="150.9" y="163.9">3</text>
<text x="231.4" y="163.9">6</text>
<text x="231.4" y="166.5">7</text>
<text x="237.3" y="162.5">A4</text>
<text x="237.3" y="165">A5</text>
<text x="237.3" y="167.6">A6</text>
<text x="245.2" y="167.6">Y6</text>
<text x="245.2" y="165">Y5</text>
<text x="245.2" y="162.5">Y4</text>
<text x="252.5" y="166.5">13</text>
<text x="252.5" y="163.9">14</text>
<text x="327.9" y="163.9">6</text>
<text x="327.9" y="166.5">7</text>
<text x="333.8" y="162.5">A4</text>
<text x="333.8" y="165">A5</text>
<text x="333.8" y="167.6">A6</text>
<text x="341.7" y="167.6">Y6</text>
<text x="341.7" y="165">Y5</text>
<text x="341.7" y="162.5">Y4</text>
<text x="349" y="166.5">13</text>
<text x="349" y="163.9">14</text>
<text x="367" y="162.5">CON4-4</text>
<text x="367" y="165">CON4-5</text>
<text x="367" y="167.6">CON4-6</text>
<text x="123.5" y="169">10</text>
<text x="124.7" y="171.5">9</text>
<text x="130.6" y="170.1">C</text>
<text x="130.6" y="172.6">D</text>
<text x="143" y="172.6">QD</text>
<text x="143" y="170.1">QC</text>
<text x="150.9" y="171.5">7</text>
<text x="150.9" y="169">6</text>
<text x="231.4" y="169">8</text>
<text x="231.4" y="171.5">9</text>
<text x="237.3" y="170.1">A7</text>
<text x="237.3" y="172.6">A8</text>
<text x="245.2" y="172.6">Y8</text>
<text x="245.2" y="170.1">Y7</text>
<text x="252.5" y="171.5">11</text>
<text x="252.5" y="169">12</text>
<text x="327.9" y="169">8</text>
<text x="327.9" y="171.5">9</text>
<text x="333.8" y="170.1">A7</text>
<text x="333.8" y="172.6">A8</text>
<text x="341.7" y="172.6">Y8</text>
<text x="341.7" y="170.1">Y7</text>
<text x="349" y="171.5">11</text>
<text x="349" y="169">12</text>
<text x="367" y="170.1">CON4-7</text>
<text x="367" y="172.6">CON4-8</text>
<text x="123.5" y="176.6">11</text>
<text x="130.6" y="177.7">LOAD</text>
<text x="150.9" y="179.1">13</text>
<text x="230.2" y="179.1">19</text>
<text x="231.4" y="176.6">1</text>
<text x="237.3" y="177.7">G1</text>
<text x="326.7" y="179.1">19</text>
<text x="327.9" y="176.6">1</text>
<text x="333.8" y="177.7">G1</text>
<text x="124.7" y="181.7">5</text>
<text x="124.7" y="184.2">4</text>
<text x="130.6" y="182.8">UP</text>
<text x="130.6" y="185.3">DOWN</text>
<text x="136.4" y="180.3">BORROW</text>
<text x="138.8" y="182.8">CARRY</text>
<text x="150.9" y="181.7">12</text>
<text x="237.3" y="180.3">G2</text>
<text x="333.8" y="180.3">G2</text>
<text x="123.5" y="186.8">14</text>
<text x="130.6" y="187.9">CLEAR</text>
<text x="123.5" y="204.5">15</text>
<text x="123.5" y="209.6">10</text>
<text x="124.7" y="207.1">1</text>
<text x="130.6" y="205.7">A</text>
<text x="130.6" y="208.2">B</text>
<text x="143.1" y="208.2">QB</text>
<text x="143.1" y="205.7">QA</text>
<text x="150.9" y="209.6">6</text>
<text x="150.9" y="207.1">2</text>
<text x="150.9" y="204.5">3</text>
<text x="124.7" y="212.2">9</text>
<text x="130.6" y="210.7">C</text>
<text x="130.6" y="213.3">D</text>
<text x="143" y="213.3">QD</text>
<text x="143" y="210.7">QC</text>
<text x="150.9" y="212.2">7</text>
<text x="123.5" y="217.2">11</text>
<text x="130.6" y="218.4">LOAD</text>
<text x="136.4" y="220.9">BORROW</text>
<text x="150.9" y="219.8">13</text>
<text x="123.5" y="227.4">14</text>
<text x="124.7" y="222.3">5</text>
<text x="124.7" y="224.9">4</text>
<text x="130.6" y="223.4">UP</text>
<text x="130.6" y="226">DOWN</text>
<text x="138.8" y="223.4">CARRY</text>
<text x="150.9" y="222.3">12</text>
<text x="130.6" y="228.5">CLEAR</text>
<text x="114.6" y="250.3">6</text>
<text x="130.6" y="250.3">5</text>
<text x="138.8" y="250.3">10</text>
<text x="156" y="250.3">11</text>
<text x="114.6" y="260.4">3</text>
<text x="130.6" y="260.4">4</text>
<text x="140" y="260.4">9</text>
<text x="156" y="260.4">8</text>
<text x="164.2" y="260.4">13</text>
<text x="181.4" y="260.4">12</text>
</g>
</g></defs>
<g fill="#000" stroke="#000" stroke-width=".21">
<path d="M67.8 18.2v3.9zM115.3 18.2v3.9zM162.7 18.2v3.9zM210.2 18.2v3.9zM257.6 18.2v3.9zM305.1 18.2v3.9zM352.5 18.2v3.9zM20.3 22.1v252.6zM35.6 36.2h5.2zM44.4 37.3h157.5zM20.3 22.1h379.7zM31.1 51.5h8.3z"/>
<path d="M33.1 46.4h7.7zM35 41.3h5.8zM44.4 42.4h43.2zM44.4 52.5h17.8zM77.5 52.5h297.1zM44.4 47.5h38.1zM82.5 47.5v53.3zM296.7 53.1h8.3zM16.5 72.6h3.8zM62.2 65.2v5.1zM62.2 52.5v12.7zM120.6 75.4v2.5z"/>
<path d="M400 72.6h3.8zM62.2 82.4v3.1zM62.2 85.5v5.1zM62.2 90.6h15.3zM77.5 52.5v38.1zM87.6 42.4v53.3zM87.6 95.7v40.6zM97.8 80.5l2.5 2.5zM97.8 83l2.5 2.5zM97.8 85.5l2.5 2.6zM97.8 88.1l2.5 2.5zM100.3 83h22.9z"/>
<path d="M100.3 85.5h22.9zM100.3 88.1h22.9zM100.3 90.6h22.9zM107.8 98.8h7.8zM109.8 93.7h5.8zM123.2 83h5zM123.2 85.5h5zM123.2 88.1h5zM123.2 90.6h5zM123.2 95.7h3.1zM87.6 95.7h35.6zM148.6 90.6h5z"/>
<path d="M148.6 88.1h5zM148.6 85.5h5zM148.6 83h5zM150.6 98.2h3zM153.6 83h17.8zM153.6 85.5h17.8zM153.6 88.1h17.8zM153.6 90.6h17.8zM171.4 83l2.6 2.5zM171.4 85.5l2.6 2.6zM171.4 88.1l2.6 2.5zM171.4 90.6l2.6 2.6z"/>
<path d="M77.5 105.9v40.6zM77.5 105.9h45.7zM77.5 90.6v15.3zM82.5 100.8h40.7zM92.7 116v25.4zM120.6 77.9v25.4zM120.6 103.3v40.7zM123.2 100.8h5zM123.2 103.3h5zM123.2 105.9h5zM120.6 103.3h2.6zM150.6 100.8h3z"/>
<path d="M153.6 100.8h5.1zM158.7 100.8v15.2zM92.7 116h66zM212.1 116l-2.6 2.6zM212.1 118.6l-2.6 2.5zM229.8 116h5.1zM229.8 118.6h5.1zM212.1 116h17.7zM212.1 118.6h17.7zM250.2 118.6h5zM250.2 116h5zM255.2 116h20.4z"/>
<path d="M278.1 113.5l-2.5 2.5zM255.2 118.6h20.4zM275.6 118.6l2.5-2.6zM308.6 116l-2.6 2.6zM308.6 118.6l-2.6 2.5zM326.4 116h5zM326.4 118.6h5zM308.6 116h17.8zM308.6 118.6h17.8zM346.7 118.6h5zM346.7 116h5zM361.9 116h2.5z"/>
<path d="M361.9 118.6h2.5zM351.7 116h10.2zM351.7 118.6h10.2zM16.5 123.1h3.8zM87.6 136.3h35.6zM87.6 136.3v40.7zM97.8 121.1l2.5 2.5zM97.8 123.6l2.5 2.6zM97.8 126.2l2.5 2.5zM97.8 128.7l2.5 2.6zM100.3 123.6h22.9zM100.3 126.2h22.9z"/>
<path d="M100.3 128.7h22.9zM100.3 131.3h22.9zM109.8 134.4h5.8zM123.2 123.6h5zM123.2 126.2h5zM123.2 128.7h5zM123.2 131.3h5zM123.2 136.3h3.1zM148.6 131.3h5zM148.6 128.7h5zM148.6 126.2h5zM148.6 123.6h5z"/>
<path d="M150.6 138.9h3zM153.6 123.6h17.8zM153.6 126.2h17.8zM153.6 128.7h17.8zM153.6 131.3h17.8zM171.4 123.6l2.6 2.6zM171.4 126.2l2.6 2.5zM171.4 128.7l2.6 2.6zM171.4 131.3l2.6 2.5zM201.9 37.3v101.6zM201.9 138.9v38.1zM212.1 121.1l-2.6 2.5z"/>
<path d="M212.1 123.6l-2.6 2.6zM212.1 126.2l-2.6 2.5zM212.1 128.7l-2.6 2.6zM212.1 131.3l-2.6 2.5zM212.1 133.8l-2.6 2.5zM201.9 138.9h25.4zM229.8 138.9h3.1zM229.8 121.1h5.1zM229.8 123.6h5.1zM229.8 126.2h5.1zM229.8 128.7h5.1zM229.8 131.3h5.1z"/>
<path d="M229.8 133.8h5.1zM227.3 138.9h2.5zM212.1 121.1h17.7zM212.1 123.6h17.7zM212.1 126.2h17.7zM212.1 128.7h17.7zM212.1 131.3h17.7zM212.1 133.8h17.7zM250.2 133.8h5zM250.2 131.3h5zM250.2 128.7h5zM250.2 126.2h5z"/>
<path d="M250.2 123.6h5zM250.2 121.1h5zM255.2 121.1h20.4zM278.1 118.6l-2.5 2.5zM255.2 123.6h20.4zM278.1 121.1l-2.5 2.5zM255.2 126.2h20.4zM255.2 128.7h20.4zM255.2 131.3h20.4zM255.2 133.8h20.4zM278.1 123.6l-2.5 2.6zM278.1 126.2l-2.5 2.5z"/>
<path d="M278.1 128.7l-2.5 2.6zM278.1 131.3l-2.5 2.5zM308.6 121.1l-2.6 2.5zM308.6 123.6l-2.6 2.6zM308.6 126.2l-2.6 2.5zM308.6 128.7l-2.6 2.6zM308.6 131.3l-2.6 2.5zM308.6 133.8l-2.6 2.5zM326.4 138.9h3.1zM326.4 121.1h5zM326.4 123.6h5zM326.4 126.2h5z"/>
<path d="M326.4 128.7h5zM326.4 131.3h5zM326.4 133.8h5zM323.8 138.9h2.6zM308.6 121.1h17.8zM308.6 123.6h17.8zM308.6 126.2h17.8zM308.6 128.7h17.8zM308.6 131.3h17.8zM308.6 133.8h17.8zM346.7 133.8h5zM346.7 131.3h5z"/>
<path d="M346.7 128.7h5zM346.7 126.2h5zM346.7 123.6h5zM346.7 121.1h5zM361.9 121.1h2.5zM361.9 123.6h2.5zM361.9 126.2h2.5zM361.9 128.7h2.5zM361.9 131.3h2.5zM361.9 133.8h2.5zM351.7 121.1h10.2zM351.7 123.6h10.2z"/>
<path d="M351.7 126.2h10.2zM351.7 128.7h10.2zM351.7 131.3h10.2zM351.7 133.8h10.2zM400 123.1h3.8zM77.5 146.5h45.7zM77.5 146.5v40.6zM92.7 141.4h30.5zM92.7 156.7v25.4zM120.6 144h2.6zM120.6 144v40.6zM123.2 141.4h5z"/>
<path d="M123.2 144h5zM123.2 146.5h5zM123.2 146.5h2.5zM150.6 141.4h3zM153.6 141.4h5.1zM158.7 141.4v15.3zM92.7 156.7h66zM212.1 154.1l-2.6 2.6zM212.1 156.7l-2.6 2.5zM212.1 159.2l-2.6 2.5zM227.3 138.9v2.5zM229.8 141.4h3.1z"/>
<path d="M229.8 154.1h5.1zM229.8 156.7h5.1zM229.8 159.2h5.1zM227.3 141.4h2.5zM212.1 154.1h17.7zM212.1 156.7h17.7zM212.1 159.2h17.7zM250.2 159.2h5zM250.2 156.7h5zM250.2 154.1h5zM255.2 154.1h20.4zM255.2 156.7h20.4z"/>
<path d="M255.2 159.2h20.4zM278.1 151.6l-2.5 2.5zM278.1 154.1l-2.5 2.6zM278.1 156.7l-2.5 2.5zM278.1 159.2l-2.5 2.5zM308.6 154.1l-2.6 2.6zM308.6 156.7l-2.6 2.5zM308.6 159.2l-2.6 2.5zM323.8 144v2.5zM323.8 138.9v2.5zM323.8 141.4v2.6zM326.4 141.4h3.1z"/>
<path d="M326.4 154.1h5zM326.4 156.7h5zM326.4 159.2h5zM323.8 141.4h2.6zM308.6 154.1h17.8zM308.6 156.7h17.8zM308.6 159.2h17.8zM346.7 159.2h5zM346.7 156.7h5zM346.7 154.1h5zM361.9 154.1h2.5zM361.9 156.7h2.5z"/>
<path d="M361.9 159.2h2.5zM351.7 154.1h10.2zM351.7 156.7h10.2zM351.7 159.2h10.2zM16.5 173.7h3.8zM87.6 177h35.6zM87.6 177v40.6zM97.8 161.7l2.5 2.6zM97.8 164.3l2.5 2.5zM97.8 166.8l2.5 2.6zM97.8 169.4l2.5 2.5zM100.3 164.3h22.9z"/>
<path d="M100.3 166.8h22.9zM100.3 169.4h22.9zM100.3 171.9h22.9zM109.8 175h5.8zM123.2 164.3h5zM123.2 166.8h5zM123.2 169.4h5zM123.2 171.9h5zM123.2 177h3.1zM148.6 171.9h5zM148.6 169.4h5zM148.6 166.8h5z"/>
<path d="M148.6 164.3h5zM150.6 179.5h3zM153.6 164.3h17.8zM153.6 166.8h17.8zM153.6 169.4h17.8zM153.6 171.9h17.8zM171.4 164.3l2.6 2.5zM171.4 166.8l2.6 2.6zM171.4 169.4l2.6 2.5zM171.4 171.9l2.6 2.5zM201.9 177h25.4zM212.1 161.7l-2.6 2.6z"/>
<path d="M212.1 164.3l-2.6 2.5zM212.1 166.8l-2.6 2.6zM212.1 169.4l-2.6 2.5zM212.1 171.9l-2.6 2.5zM227.3 177h2.5zM227.3 177v2.5zM229.8 177h3.1zM229.8 161.7h5.1zM229.8 164.3h5.1zM229.8 166.8h5.1zM229.8 169.4h5.1zM229.8 171.9h5.1z"/>
<path d="M229.8 179.5h3.1zM227.3 179.5h2.5zM212.1 161.7h17.7zM212.1 164.3h17.7zM212.1 166.8h17.7zM212.1 169.4h17.7zM212.1 171.9h17.7zM250.2 171.9h5zM250.2 169.4h5zM250.2 166.8h5zM250.2 164.3h5zM250.2 161.7h5z"/>
<path d="M255.2 161.7h20.4zM255.2 164.3h20.4zM255.2 166.8h20.4zM255.2 169.4h20.4zM255.2 171.9h20.4zM278.1 161.7l-2.5 2.6zM278.1 164.3l-2.5 2.5zM278.1 166.8l-2.5 2.6zM278.1 169.4l-2.5 2.5zM308.6 161.7l-2.6 2.6zM308.6 164.3l-2.6 2.5zM308.6 166.8l-2.6 2.6z"/>
<path d="M308.6 169.4l-2.6 2.5zM308.6 171.9l-2.6 2.5zM323.8 177h2.6zM323.8 177v2.5zM323.8 179.5v2.6zM326.4 177h3.1zM326.4 161.7h5zM326.4 164.3h5zM326.4 166.8h5zM326.4 169.4h5zM326.4 171.9h5zM326.4 179.5h3.1z"/>
<path d="M323.8 179.5h2.6zM308.6 161.7h17.8zM308.6 164.3h17.8zM308.6 166.8h17.8zM308.6 169.4h17.8zM308.6 171.9h17.8zM346.7 171.9h5zM346.7 169.4h5zM346.7 166.8h5zM346.7 164.3h5zM346.7 161.7h5zM361.9 161.7h2.5z"/>
<path d="M361.9 164.3h2.5zM361.9 166.8h2.5zM361.9 169.4h2.5zM361.9 171.9h2.5zM351.7 161.7h10.2zM351.7 164.3h10.2zM351.7 166.8h10.2zM351.7 169.4h10.2zM351.7 171.9h10.2zM400 173.7h3.8zM77.5 187.1h45.7zM77.5 187.1v40.6z"/>
<path d="M92.7 182.1h30.5zM92.7 197.3v25.4zM120.6 184.6v40.6zM123.2 182.1h5zM123.2 184.6h5zM123.2 187.1h5zM120.6 184.6h2.6zM150.6 182.1h3zM153.6 182.1h5.1zM158.7 182.1v15.2zM92.7 197.3h66zM323.8 182.1v2.5z"/>
<path d="M87.6 217.6h35.6zM97.8 202.4l2.5 2.5zM97.8 204.9l2.5 2.5zM97.8 207.4l2.5 2.6zM97.8 210l2.5 2.5zM100.3 204.9h22.9zM100.3 207.4h22.9zM100.3 210h22.9zM100.3 212.5h22.9zM109.8 215.6h5.8zM123.2 204.9h5zM123.2 207.4h5z"/>
<path d="M123.2 210h5zM123.2 212.5h5zM123.2 217.6h3.1zM148.6 212.5h5zM148.6 210h5zM148.6 207.4h5zM148.6 204.9h5zM153.6 204.9h17.8zM153.6 207.4h17.8zM153.6 210h17.8zM153.6 212.5h17.8zM171.4 204.9l2.6 2.5z"/>
<path d="M171.4 207.4l2.6 2.6zM171.4 210l2.6 2.5zM171.4 212.5l2.6 2.5zM16.5 224.2h3.8zM77.5 227.7h45.7zM92.7 222.7h30.5zM123.2 222.7h5zM123.2 225.2h5zM123.2 227.7h5zM120.6 225.2h2.6zM150.6 220.1h3zM150.6 222.7h3z"/>
<path d="M400 224.2h3.8zM29.2 253.1v2.6zM29.2 257.7v.5zM29.2 255.7v.5zM29.2 250.6v2.5zM36.8 253.1v2.6zM36.8 257.7v.5zM36.8 255.7v.5zM36.8 250.6v2.5zM29.2 250.6h7.6zM44.4 253.1v2.6zM44.4 257.7v.5z"/>
<path d="M44.4 255.7v.5zM36.8 250.6h7.6zM44.4 250.6v2.5zM52.1 253.1v2.6zM52.1 257.7v.5zM52.1 255.7v.5zM44.4 250.6h7.7zM52.1 250.6v2.5zM59.7 253.1v2.6zM59.7 257.7v.5zM59.7 255.7v.5zM52.1 250.6h7.6z"/>
<path d="M59.7 250.6v2.5zM67.3 253.1v2.6zM67.3 257.7v.5zM67.3 255.7v.5zM59.7 250.6h7.6zM67.3 250.6v2.5zM74.9 253.1v2.6zM74.9 257.7v.5zM74.9 255.7v.5zM67.3 250.6h7.6zM74.9 250.6v2.5zM82.5 245.5v2.6z"/>
<path d="M82.5 253.1v2.6zM82.5 257.7v.5zM82.5 255.7v.5zM74.9 250.6h7.6zM82.5 248.1v2.5zM82.5 250.6v2.5zM92.7 245.5v2.6zM92.7 253.1v2.6zM92.7 255.7v.5zM92.7 257.7v.5zM92.7 248.1v5zM113 250.6h3.1z"/>
<path d="M128.2 250.6h5.1zM133.3 250.6h2.6zM135.9 250.6v10.2zM138.4 250.6h3.1zM153.6 250.6h5.1zM158.7 250.6h2.6zM161.3 250.6v10.2zM20.3 274.7h379.7zM29.2 265.8v2.6zM29.2 258.2v2.6zM29.2 260.8v2.5zM29.2 263.3h7.6z"/>
<path d="M29.2 263.3v2.5zM36.8 258.2v2.6zM36.8 260.8v2.5zM44.4 258.2v2.6zM36.8 263.3h7.6zM44.4 260.8v2.5zM52.1 258.2v2.6zM44.4 263.3h7.7zM52.1 260.8v2.5zM59.7 258.2v2.6zM52.1 263.3h7.6zM59.7 260.8v2.5z"/>
<path d="M67.3 258.2v2.6zM59.7 263.3h7.6zM67.3 260.8v2.5zM67.8 274.7v3.8zM74.9 258.2v2.6zM67.3 263.3h7.6zM74.9 260.8v2.5zM82.5 258.2v2.6zM74.9 263.3h7.6zM82.5 260.8v2.5zM92.7 258.2v2.6zM92.7 265.8v2.6z"/>
<path d="M92.7 260.8v5zM110.5 265.8v2.6zM110.5 260.8v5zM113 260.8h5.1zM110.5 260.8h2.5zM115.3 274.7v3.8zM130.2 260.8h3.1zM135.9 265.8v2.6zM135.9 260.8v5zM138.4 260.8h5.1zM135.9 260.8h2.5zM155.6 260.8h3.1z"/>
<path d="M161.3 265.8v2.6zM161.3 260.8v5zM162.7 274.7v3.8zM163.8 260.8h5.1zM161.3 260.8h2.5zM181 260.8h3.1zM210.2 274.7v3.8zM257.6 274.7v3.8zM305.1 274.7v3.8zM352.5 274.7v3.8zM400 264.5v.1zM400 268.4v6.2z"/>
<path d="M400 274.6h.1zM400 22.1v252.6z"/>
<circle cx="77.5" cy="90.6" r=".51"/>
<circle cx="87.6" cy="95.7" r=".51"/>
<circle cx="120.6" cy="103.3" r=".51"/>
<circle cx="87.6" cy="136.3" r=".51"/>
<circle cx="227.3" cy="138.9" r=".51"/>
<circle cx="77.5" cy="146.5" r=".51"/>
<circle cx="120.6" cy="144" r=".51"/>
<circle cx="323.8" cy="141.4" r=".51"/>
<circle cx="87.6" cy="177" r=".51"/>
<circle cx="227.3" cy="177" r=".51"/>
<circle cx="323.8" cy="179.5" r=".51"/>
<circle cx="77.5" cy="187.1" r=".51"/>
<circle cx="120.6" cy="184.6" r=".51"/>
<circle cx="36.8" cy="250.6" r=".51"/>
<circle cx="44.4" cy="250.6" r=".51"/>
<circle cx="52.1" cy="250.6" r=".51"/>
<circle cx="59.7" cy="250.6" r=".51"/>
<circle cx="67.3" cy="250.6" r=".51"/>
<circle cx="74.9" cy="250.6" r=".51"/>
<circle cx="82.5" cy="250.6" r=".51"/>
<circle cx="29.2" cy="263.3" r=".51"/>
<circle cx="36.8" cy="263.3" r=".51"/>
<circle cx="44.4" cy="263.3" r=".51"/>
<circle cx="52.1" cy="263.3" r=".51"/>
<circle cx="59.7" cy="263.3" r=".51"/>
<circle cx="67.3" cy="263.3" r=".51"/>
<circle cx="74.9" cy="263.3" r=".51"/>
<circle cx="135.9" cy="260.8" r=".51"/>
<circle cx="161.3" cy="260.8" r=".51"/>
</g>
<g fill="#000" stroke="#000" stroke-width=".28">
<path d="M33.3 35.8v3zM33.3 35.8h9.6zM33.3 38.8h9.6zM42.9 35.8l1.5 1.5zM44.4 37.3l-1.5 1.5zM28.7 51v3.1zM30.7 45.9v3.1zM32.7 40.9v3zM30.7 45.9h12.2zM30.7 49h12.2zM32.7 40.9h10.2zM32.7 43.9h10.2z"/>
<path d="M28.7 51h14.2zM28.7 54.1h14.2zM42.9 45.9l1.5 1.6zM44.4 47.5l-1.5 1.5zM42.9 40.9l1.5 1.5zM44.4 42.4l-1.5 1.5zM42.9 51l1.5 1.5zM44.4 52.5l-1.5 1.6zM374.6 52.5l1.5-1.5zM374.6 52.5l1.5 1.6zM376.1 51h12.8zM376.1 54.1h12.8z"/>
<path d="M388.9 51v3.1zM120.6 75.4l-1.2 1.9zM120.6 75.4l1.3 1.9zM321.9 146.5h3.8zM321.9 184.6h3.8zM82.5 245.5l-1.2 1.9zM82.5 245.5l1.3 1.9zM92.7 245.5l-1.3 1.9zM92.7 245.5l1.3 1.9zM313.7 249.3h86.3zM313.7 254.4h86.3zM313.7 259.5h58.4z"/>
<path d="M372.1 259.5h27.9zM372.1 259.5v5.1zM27.3 268.4h3.8zM90.8 268.4h3.8zM108.6 268.4h3.8zM134 268.4h3.8zM159.4 268.4h3.8zM313.7 264.6h58.4zM313.7 269.7h86.3zM372.1 264.6h27.9zM400 268.4v1.3z"/>
</g>
<g fill="none" stroke="#000" stroke-width=".21">
<circle cx="62.2" cy="81.4" r=".99"/>
<circle cx="127.3" cy="95.7" r=".99"/>
<circle cx="149.6" cy="98.2" r=".99"/>
<circle cx="149.6" cy="100.8" r=".99"/>
<circle cx="127.3" cy="136.3" r=".99"/>
<circle cx="149.6" cy="138.9" r=".99"/>
<circle cx="233.9" cy="138.9" r="1"/>
<circle cx="330.4" cy="138.9" r="1"/>
<circle cx="149.6" cy="141.4" r=".99"/>
<circle cx="233.9" cy="141.4" r="1"/>
<circle cx="330.4" cy="141.4" r="1"/>
<circle cx="127.3" cy="177" r=".99"/>
<circle cx="149.6" cy="179.5" r=".99"/>
<circle cx="233.9" cy="177" r="1"/>
<circle cx="233.9" cy="179.5" r="1"/>
<circle cx="330.4" cy="179.5" r="1"/>
<circle cx="330.4" cy="177" r="1"/>
<circle cx="149.6" cy="182.1" r=".99"/>
<circle cx="127.3" cy="217.6" r=".99"/>
<circle cx="149.6" cy="222.7" r=".99"/>
<circle cx="149.6" cy="220.1" r=".99"/>
<circle cx="117.1" cy="250.6" r=".99"/>
<circle cx="142.5" cy="250.6" r=".99"/>
<circle cx="129.2" cy="260.8" r=".99"/>
<circle cx="154.6" cy="260.8" r=".99"/>
<circle cx="180" cy="260.8" r=".99"/>
</g>
<g fill="#000" stroke="#000" stroke-width=".61">
<path d="M20.3 22.1v252.6zM20.3 22.1h379.7zM57.1 70.3h10.2zM67.3 70.3l-5.1 10.2zM57.1 70.3l5.1 10.2zM128.2 80.5v27.9zM128.2 80.5h20.4zM128.2 108.4h20.4zM148.6 80.5v27.9zM234.9 113.5v30.5zM234.9 113.5h15.3zM331.4 113.5v30.5z"/>
<path d="M331.4 113.5h15.3zM364.4 116h1.3zM364.4 118.6h1.3zM128.2 121.1v27.9zM128.2 121.1h20.4zM364.4 121.1h1.3zM364.4 123.6h1.3zM364.4 126.2h1.3zM364.4 128.7h1.3zM364.4 131.3h1.3zM364.4 133.8h1.3zM128.2 149h20.4z"/>
<path d="M148.6 121.1v27.9zM234.9 144h15.3zM234.9 151.6v30.5zM250.2 113.5v30.5zM234.9 151.6h15.3zM331.4 144h15.3zM331.4 151.6v30.5zM346.7 113.5v30.5zM331.4 151.6h15.3zM364.4 154.1h1.3zM364.4 156.7h1.3zM364.4 159.2h1.3z"/>
<path d="M128.2 161.7v28zM128.2 161.7h20.4zM364.4 161.7h1.3zM364.4 164.3h1.3zM364.4 166.8h1.3zM364.4 169.4h1.3zM364.4 171.9h1.3zM128.2 189.7h20.4zM148.6 161.7v28zM234.9 182.1h15.3zM250.2 151.6v30.5zM331.4 182.1h15.3z"/>
<path d="M346.7 151.6v30.5zM128.2 202.4v27.9zM128.2 202.4h20.4zM128.2 230.3h20.4zM148.6 202.4v27.9zM118.1 255.7l10.1 5.1zM118.1 250.6l10.1-5.1zM118.1 250.6l10.1 5.1zM128.2 245.5v10.2zM143.5 255.7l10.1 5.1zM143.5 250.6l10.1-5.1zM143.5 250.6l10.1 5.1z"/>
<path d="M153.6 245.5v10.2zM168.9 255.7l10.1 5.1zM283.2 244.3v30.4zM313.7 254.4v5.1zM313.7 249.3v5.1zM313.7 244.3v5zM313.7 244.3h86.3zM283.2 244.3h30.5zM400 254.4v5.1zM400 249.3v5.1zM400 244.3v5zM400 22.1v222.2z"/>
<path d="M20.3 274.7h262.9zM118.1 255.7v10.1zM118.1 265.8l10.1-5zM143.5 255.7v10.1zM143.5 265.8l10.1-5zM168.9 255.7v10.1zM168.9 265.8l10.1-5zM283.2 274.7h30.5zM313.7 274.7h86.3zM313.7 269.7v5zM313.7 264.6v5.1zM313.7 259.5v5.1z"/>
<path d="M400 268.4v6.3zM400 264.6v3.8zM400 259.5v5.1z"/>
</g>
<g fill="#000" stroke="#000" stroke-width=".21">
<path d="M27.2 256.2h4v.5h-4zM27.2 257.2h4v.5h-4zM34.8 256.2h4.1v.5h-4.1zM34.8 257.2h4.1v.5h-4.1zM42.4 256.2h4.1v.5h-4.1zM42.4 257.2h4.1v.5h-4.1zM50 256.2h4.1v.5h-4.1zM50 257.2h4.1v.5h-4.1zM57.7 256.2h4v.5h-4zM57.7 257.2h4v.5h-4zM65.3 256.2h4v.5h-4zM65.3 257.2h4v.5h-4z"/>
<path d="M72.9 256.2h4.1v.5h-4.1zM72.9 257.2h4.1v.5h-4.1zM80.5 256.2h4.1v.5h-4.1zM80.5 257.2h4.1v.5h-4.1zM90.7 257.2h4v.5h-4zM90.7 256.2h4v.5h-4zM252.7 253.1h25.4v10.2h-25.4z"/>
</g>
<path d="M16.5 18.2v260.3zM16.5 18.2h387.3zM16.5 278.5h387.3zM403.8 18.2v260.3z" fill="#000" stroke="#000" stroke-width=".32"/>
<g fill="#000" stroke="#000" stroke-width=".76">
<path d="M44.4 60.2h48.3zM92.7 60.2h281.9zM92.7 60.2l5.1 5zM273 60.2l5.1 5zM278.1 65.2v104.2zM97.8 65.2v144.8zM174 85.5v132.1zM209.5 118.6v99zM306 118.6v99zM179 222.7h195.6zM174 217.6l5 5.1zM209.5 217.6l5.1 5.1z"/>
<path d="M306 217.6l5.1 5.1z"/>
</g>
<path d="M222.2 253.1v10.2zM222.2 253.1h55.9zM222.2 263.3v7.6zM222.2 270.9h55.9zM222.2 263.3h55.9zM278.1 263.3v7.6zM278.1 253.1v10.2z" fill="#000" stroke="#000" stroke-width=".42"/>
<use href="#words"/>
</svg>
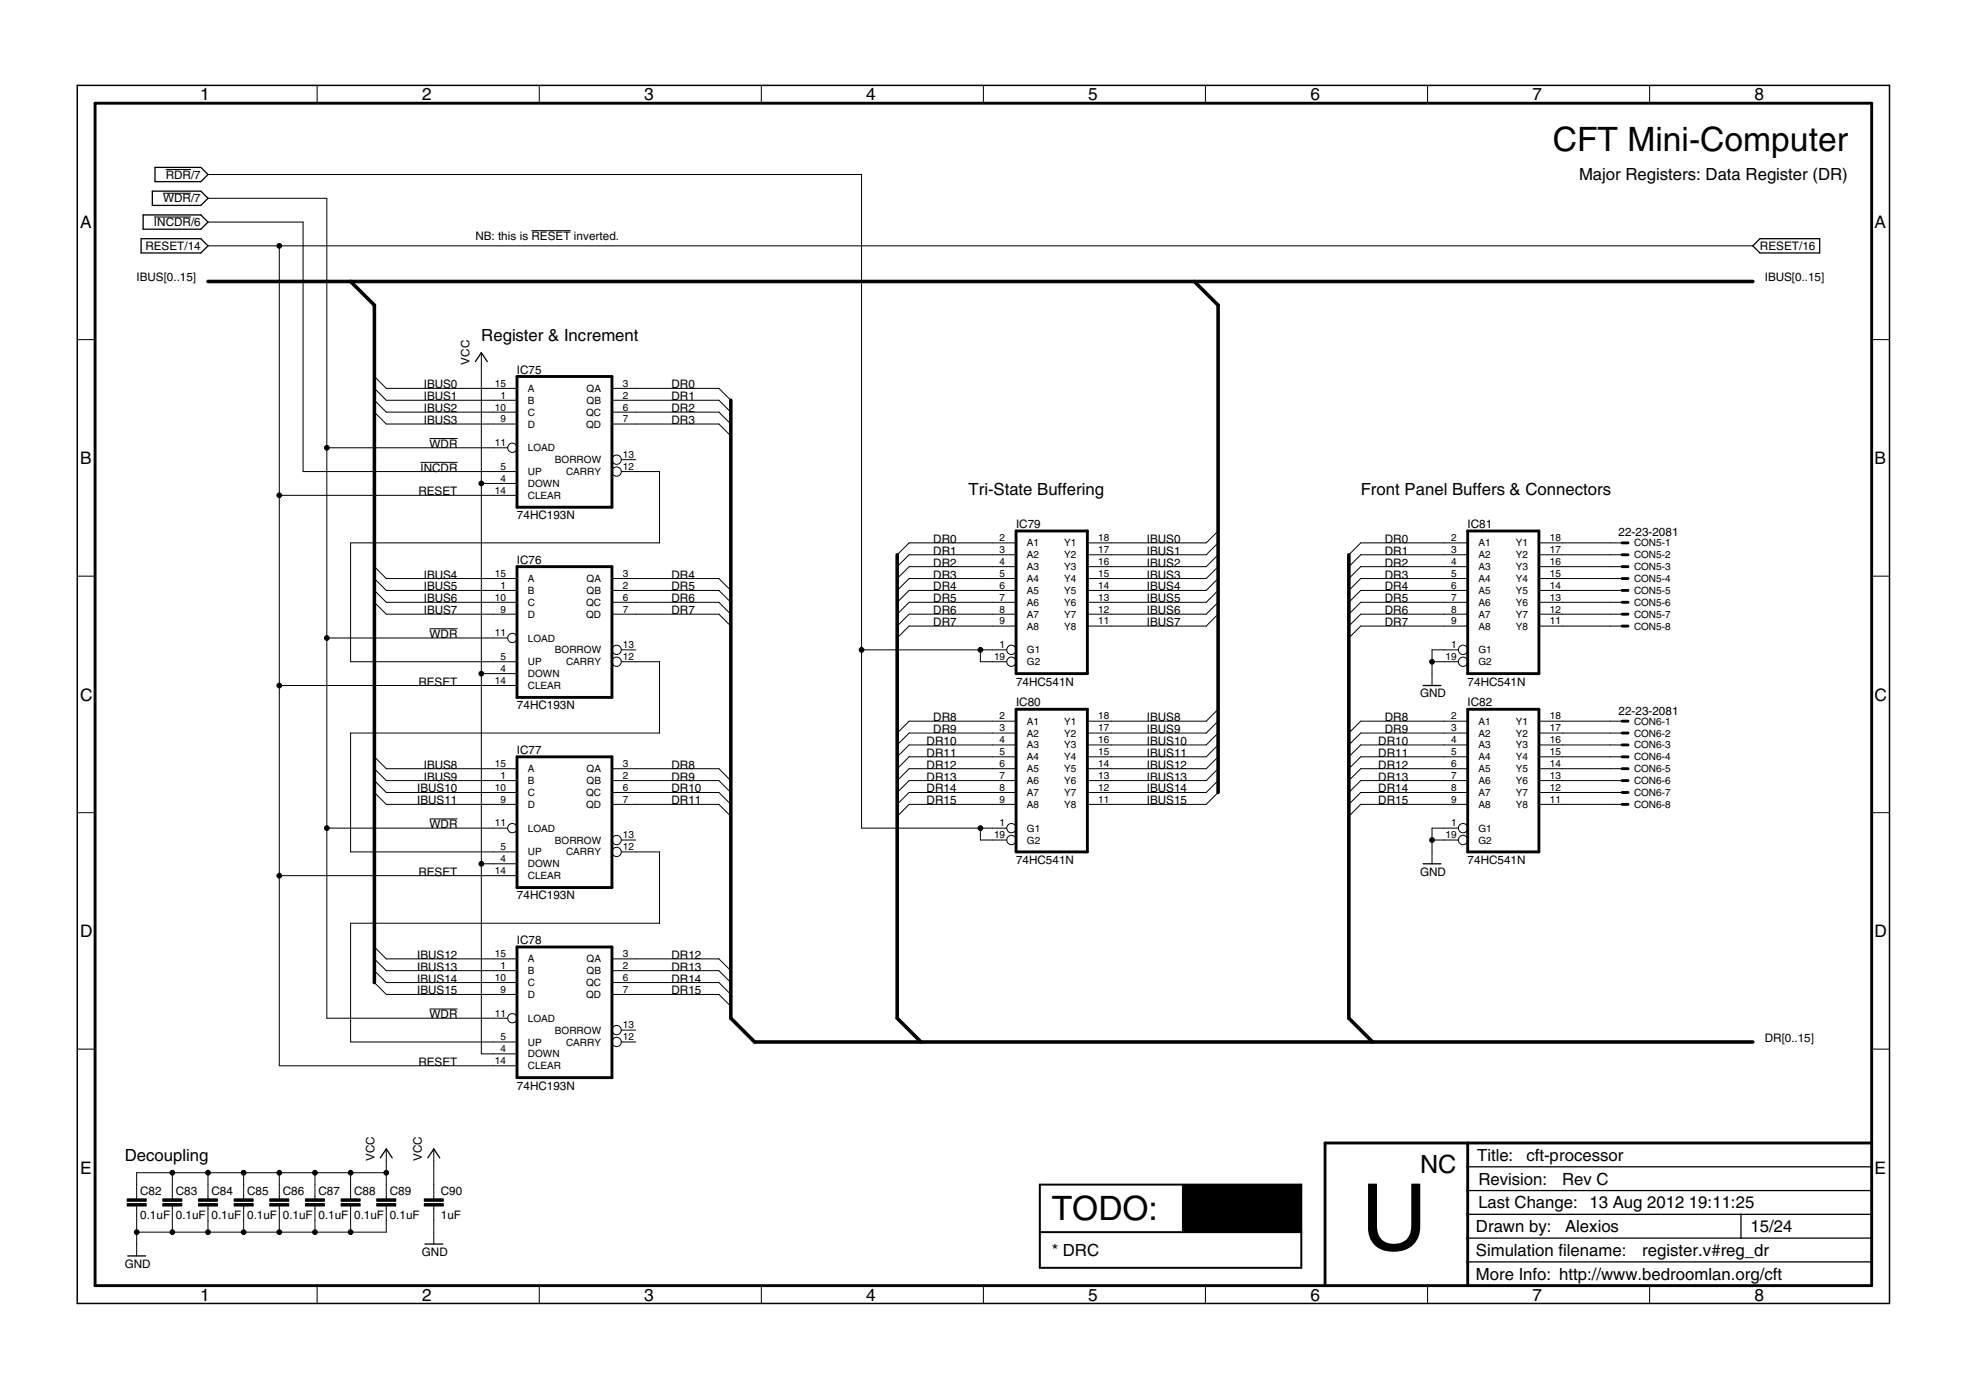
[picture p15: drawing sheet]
<svg xmlns="http://www.w3.org/2000/svg" width="420mm" height="297mm" viewBox="0 0 420 297" stroke-linecap="round" stroke-linejoin="round" font-family="sans-serif">
<defs><g id="words">
<text font-size="19.7" x="290.8" y="267.1">U</text>
<g font-size="7.2">
<text x="331.8" y="32.2">CFT Mini-Computer</text>
<text x="224.8" y="260.8">TODO:</text>
</g>
<text font-size="5.4" x="303.5" y="250.6">NC</text>
<g font-size="3.7">
<text x="42.7" y="21.5">1</text>
<text x="90.2" y="21.5">2</text>
<text x="137.7" y="21.5">3</text>
<text x="185.1" y="21.5">4</text>
<text x="232.6" y="21.5">5</text>
<text x="280" y="21.5">6</text>
<text x="327.5" y="21.5">7</text>
<text x="375" y="21.5">8</text>
<text x="17.1" y="48.6">A</text>
<text x="400.6" y="48.6">A</text>
<text x="17.1" y="99.2">B</text>
<text x="400.6" y="99.2">B</text>
<text x="17.1" y="149.7">C</text>
<text x="400.6" y="149.7">C</text>
<text x="17.1" y="200.2">D</text>
<text x="400.6" y="200.2">D</text>
<text x="17.1" y="250.8">E</text>
<text x="400.6" y="250.8">E</text>
<text x="42.7" y="277.9">1</text>
<text x="90.2" y="277.9">2</text>
<text x="137.7" y="277.9">3</text>
<text x="185.1" y="277.9">4</text>
<text x="232.6" y="277.9">5</text>
<text x="280" y="277.9">6</text>
<text x="327.5" y="277.9">7</text>
<text x="375" y="277.9">8</text>
</g>
<g font-size="3.6">
<text x="337.5" y="38.6">Major Registers: Data Register (DR)</text>
<text x="102.9" y="72.8">Register &amp; Increment</text>
<text x="207" y="105.9">Tri-State Buffering</text>
<text x="290.8" y="105.9">Front Panel Buffers &amp; Connectors</text>
<text x="26.7" y="248.1">Decoupling</text>
<text x="315.7" y="248.1">Title:</text>
<text x="326.2" y="248.2">cft-processor</text>
<text x="315.9" y="253.2">Revision:</text>
<text x="333.8" y="253.3">Rev C</text>
<text x="315.4" y="263.3">Drawn by:</text>
<text x="315.9" y="258.2">Last Change: 13 Aug 2012</text>
<text x="334.5" y="263.3">Alexios</text>
<text x="361" y="258.1">19:11:25</text>
<text x="374.1" y="263.2">15/24</text>
<text x="224.8" y="268.4">* DRC</text>
<text x="315.4" y="268.4">Simulation filename:</text>
<text x="351" y="268.4">register.v#reg_dr</text>
<text x="315.4" y="273.5">More Info: http://www.bedroomlan.org/cft</text>
</g>
<g font-size="2.5">
<text x="35.4" y="38.2">RDR/7</text>
<text x="34.9" y="43.3">WDR/7</text>
<text x="31.1" y="53.4">RESET/14</text>
<text x="32.9" y="48.3">INCDR/6</text>
<text x="101.6" y="51.3">NB: this is RESET inverted.</text>
<text x="376.1" y="53.4">RESET/16</text>
<text x="29.2" y="60.1">IBUS[0..15]</text>
<text x="377.1" y="60.1">IBUS[0..15]</text>
<text x="100.3" y="77.9" transform="rotate(-90 100.3 77.9)">VCC</text>
<text x="90.6" y="83">IBUS0</text>
<text x="110.5" y="79.8">IC75</text>
<text x="143.5" y="83">DR0</text>
<text x="90.6" y="85.5">IBUS1</text>
<text x="90.6" y="88.1">IBUS2</text>
<text x="143.5" y="85.5">DR1</text>
<text x="143.5" y="88.1">DR2</text>
<text x="90.6" y="90.6">IBUS3</text>
<text x="91.8" y="95.7">WDR</text>
<text x="143.5" y="90.6">DR3</text>
<text x="89.9" y="100.8">INCDR</text>
<text x="89.4" y="105.9">RESET</text>
<text x="110.5" y="110.9">74HC193N</text>
<text x="217.1" y="112.8">IC79</text>
<text x="313.7" y="112.8">IC81</text>
<text x="199.4" y="116">DR0</text>
<text x="199.4" y="118.6">DR1</text>
<text x="245.1" y="116">IBUS0</text>
<text x="245.1" y="118.6">IBUS1</text>
<text x="295.9" y="116">DR0</text>
<text x="295.9" y="118.6">DR1</text>
<text x="345.9" y="114.6">22-23-2081</text>
<text x="90.6" y="123.6">IBUS4</text>
<text x="110.5" y="120.5">IC76</text>
<text x="143.5" y="123.6">DR4</text>
<text x="199.4" y="121.1">DR2</text>
<text x="199.4" y="123.6">DR3</text>
<text x="245.1" y="121.1">IBUS2</text>
<text x="245.1" y="123.6">IBUS3</text>
<text x="295.9" y="121.1">DR2</text>
<text x="295.9" y="123.6">DR3</text>
<text x="90.6" y="126.2">IBUS5</text>
<text x="90.6" y="128.7">IBUS6</text>
<text x="90.6" y="131.3">IBUS7</text>
<text x="143.5" y="126.2">DR5</text>
<text x="143.5" y="128.7">DR6</text>
<text x="143.5" y="131.3">DR7</text>
<text x="199.4" y="126.2">DR4</text>
<text x="199.4" y="128.7">DR5</text>
<text x="199.4" y="131.3">DR6</text>
<text x="245.1" y="126.2">IBUS4</text>
<text x="245.1" y="128.7">IBUS5</text>
<text x="245.1" y="131.3">IBUS6</text>
<text x="295.9" y="126.2">DR4</text>
<text x="295.9" y="128.7">DR5</text>
<text x="295.9" y="131.3">DR6</text>
<text x="91.8" y="136.3">WDR</text>
<text x="199.4" y="133.8">DR7</text>
<text x="245.1" y="133.8">IBUS7</text>
<text x="295.9" y="133.8">DR7</text>
<text x="89.4" y="146.5">RESET</text>
<text x="217.1" y="146.5">74HC541N</text>
<text x="303.5" y="149">GND</text>
<text x="313.7" y="146.5">74HC541N</text>
<text x="110.5" y="151.6">74HC193N</text>
<text x="199.4" y="154.1">DR8</text>
<text x="217.1" y="150.9">IC80</text>
<text x="245.1" y="154.1">IBUS8</text>
<text x="295.9" y="154.1">DR8</text>
<text x="313.7" y="150.9">IC82</text>
<text x="345.9" y="152.7">22-23-2081</text>
<text x="110.5" y="161.1">IC77</text>
<text x="198" y="159.2">DR10</text>
<text x="198" y="161.7">DR11</text>
<text x="199.4" y="156.6">DR9</text>
<text x="245.1" y="156.6">IBUS9</text>
<text x="245.1" y="159.2">IBUS10</text>
<text x="245.1" y="161.7">IBUS11</text>
<text x="294.5" y="159.2">DR10</text>
<text x="294.5" y="161.7">DR11</text>
<text x="295.9" y="156.6">DR9</text>
<text x="90.6" y="164.3">IBUS8</text>
<text x="90.6" y="166.8">IBUS9</text>
<text x="143.5" y="164.3">DR8</text>
<text x="143.5" y="166.8">DR9</text>
<text x="198" y="164.3">DR12</text>
<text x="198" y="166.8">DR13</text>
<text x="245.1" y="164.3">IBUS12</text>
<text x="245.1" y="166.8">IBUS13</text>
<text x="294.5" y="164.3">DR12</text>
<text x="294.5" y="166.8">DR13</text>
<text x="89.2" y="169.3">IBUS10</text>
<text x="89.2" y="171.9">IBUS11</text>
<text x="143.5" y="169.3">DR10</text>
<text x="143.5" y="171.9">DR11</text>
<text x="198" y="169.3">DR14</text>
<text x="198" y="171.9">DR15</text>
<text x="245.1" y="169.3">IBUS14</text>
<text x="245.1" y="171.9">IBUS15</text>
<text x="294.5" y="169.3">DR14</text>
<text x="294.5" y="171.9">DR15</text>
<text x="91.8" y="177">WDR</text>
<text x="217.1" y="184.6">74HC541N</text>
<text x="313.7" y="184.6">74HC541N</text>
<text x="89.4" y="187.1">RESET</text>
<text x="303.5" y="187.1">GND</text>
<text x="110.5" y="192.2">74HC193N</text>
<text x="110.5" y="201.7">IC78</text>
<text x="89.2" y="204.9">IBUS12</text>
<text x="89.2" y="207.4">IBUS13</text>
<text x="89.2" y="210">IBUS14</text>
<text x="143.5" y="204.9">DR12</text>
<text x="143.5" y="207.4">DR13</text>
<text x="143.5" y="210">DR14</text>
<text x="89.2" y="212.5">IBUS15</text>
<text x="143.5" y="212.5">DR15</text>
<text x="91.8" y="217.6">WDR</text>
<text x="89.4" y="227.8">RESET</text>
<text x="377.1" y="222.7">DR[0..15]</text>
<text x="110.5" y="232.8">74HC193N</text>
<text x="80" y="248.1" transform="rotate(-90 80 248.1)">VCC</text>
<text x="90.2" y="248.1" transform="rotate(-90 90.2 248.1)">VCC</text>
<text x="30" y="255.3">C82</text>
<text x="37.6" y="255.3">C83</text>
<text x="45.2" y="255.3">C84</text>
<text x="52.8" y="255.3">C85</text>
<text x="60.4" y="255.3">C86</text>
<text x="68.1" y="255.3">C87</text>
<text x="75.7" y="255.3">C88</text>
<text x="83.3" y="255.3">C89</text>
<text x="94.2" y="255.3">C90</text>
<text x="30" y="260.4">0.1uF</text>
<text x="37.6" y="260.4">0.1uF</text>
<text x="45.2" y="260.4">0.1uF</text>
<text x="52.8" y="260.4">0.1uF</text>
<text x="60.4" y="260.4">0.1uF</text>
<text x="68.1" y="260.4">0.1uF</text>
<text x="75.7" y="260.4">0.1uF</text>
<text x="83.3" y="260.4">0.1uF</text>
<text x="94.2" y="260.4">1uF</text>
<text x="90.2" y="268.4">GND</text>
<text x="26.7" y="270.9">GND</text>
</g>
<g font-size="2.1">
<text x="105.8" y="82.6">15</text>
<text x="112.8" y="83.8">A</text>
<text x="125.4" y="83.8">QA</text>
<text x="133.1" y="82.6">3</text>
<text x="105.8" y="87.7">10</text>
<text x="107" y="85.2">1</text>
<text x="112.8" y="86.3">B</text>
<text x="112.8" y="88.8">C</text>
<text x="125.3" y="88.8">QC</text>
<text x="125.4" y="86.3">QB</text>
<text x="133.1" y="87.7">6</text>
<text x="133.1" y="85.2">2</text>
<text x="105.8" y="95.3">11</text>
<text x="107" y="90.3">9</text>
<text x="112.8" y="91.4">D</text>
<text x="125.2" y="91.4">QD</text>
<text x="133.1" y="90.3">7</text>
<text x="107" y="100.4">5</text>
<text x="112.8" y="101.5">UP</text>
<text x="112.8" y="96.5">LOAD</text>
<text x="118.6" y="99">BORROW</text>
<text x="121" y="101.5">CARRY</text>
<text x="133.1" y="97.9">13</text>
<text x="133.1" y="100.4">12</text>
<text x="105.8" y="105.5">14</text>
<text x="107" y="103">4</text>
<text x="112.8" y="104.1">DOWN</text>
<text x="112.8" y="106.6">CLEAR</text>
<text x="213.6" y="115.7">2</text>
<text x="213.6" y="118.2">3</text>
<text x="219.5" y="116.8">A1</text>
<text x="219.5" y="119.3">A2</text>
<text x="227.4" y="119.3">Y2</text>
<text x="227.4" y="116.8">Y1</text>
<text x="234.7" y="118.2">17</text>
<text x="234.7" y="115.7">18</text>
<text x="310.1" y="115.7">2</text>
<text x="310.1" y="118.2">3</text>
<text x="316" y="116.8">A1</text>
<text x="316" y="119.3">A2</text>
<text x="323.9" y="119.3">Y2</text>
<text x="323.9" y="116.8">Y1</text>
<text x="331.2" y="118.2">17</text>
<text x="331.2" y="115.7">18</text>
<text x="349.2" y="116.8">CON5-1</text>
<text x="349.2" y="119.3">CON5-2</text>
<text x="105.8" y="123.3">15</text>
<text x="107" y="125.8">1</text>
<text x="112.8" y="124.4">A</text>
<text x="125.4" y="124.4">QA</text>
<text x="133.1" y="125.8">2</text>
<text x="133.1" y="123.3">3</text>
<text x="213.6" y="120.7">4</text>
<text x="213.6" y="123.3">5</text>
<text x="213.6" y="125.8">6</text>
<text x="219.5" y="121.9">A3</text>
<text x="219.5" y="124.4">A4</text>
<text x="227.4" y="124.4">Y4</text>
<text x="227.4" y="121.9">Y3</text>
<text x="234.7" y="125.8">14</text>
<text x="234.7" y="123.3">15</text>
<text x="234.7" y="120.7">16</text>
<text x="310.1" y="120.7">4</text>
<text x="310.1" y="123.3">5</text>
<text x="310.1" y="125.8">6</text>
<text x="316" y="121.9">A3</text>
<text x="316" y="124.4">A4</text>
<text x="323.9" y="124.4">Y4</text>
<text x="323.9" y="121.9">Y3</text>
<text x="331.2" y="125.8">14</text>
<text x="331.2" y="123.3">15</text>
<text x="331.2" y="120.7">16</text>
<text x="349.2" y="121.9">CON5-3</text>
<text x="349.2" y="124.4">CON5-4</text>
<text x="105.8" y="128.4">10</text>
<text x="107" y="130.9">9</text>
<text x="112.8" y="126.9">B</text>
<text x="112.8" y="129.5">C</text>
<text x="125.3" y="129.5">QC</text>
<text x="125.4" y="126.9">QB</text>
<text x="133.1" y="130.9">7</text>
<text x="133.1" y="128.4">6</text>
<text x="213.6" y="128.4">7</text>
<text x="213.6" y="130.9">8</text>
<text x="219.5" y="126.9">A5</text>
<text x="219.5" y="129.5">A6</text>
<text x="227.4" y="129.5">Y6</text>
<text x="227.4" y="126.9">Y5</text>
<text x="234.7" y="130.9">12</text>
<text x="234.7" y="128.4">13</text>
<text x="310.1" y="128.4">7</text>
<text x="310.1" y="130.9">8</text>
<text x="316" y="126.9">A5</text>
<text x="316" y="129.5">A6</text>
<text x="323.9" y="129.5">Y6</text>
<text x="323.9" y="126.9">Y5</text>
<text x="331.2" y="130.9">12</text>
<text x="331.2" y="128.4">13</text>
<text x="349.2" y="126.9">CON5-5</text>
<text x="349.2" y="129.5">CON5-6</text>
<text x="105.8" y="136">11</text>
<text x="112.8" y="132">D</text>
<text x="112.8" y="137.1">LOAD</text>
<text x="125.2" y="132">QD</text>
<text x="213.6" y="133.4">9</text>
<text x="219.5" y="132">A7</text>
<text x="219.5" y="134.6">A8</text>
<text x="227.4" y="134.6">Y8</text>
<text x="227.4" y="132">Y7</text>
<text x="234.7" y="133.4">11</text>
<text x="310.1" y="133.4">9</text>
<text x="316" y="132">A7</text>
<text x="316" y="134.6">A8</text>
<text x="323.9" y="134.6">Y8</text>
<text x="323.9" y="132">Y7</text>
<text x="331.2" y="133.4">11</text>
<text x="349.2" y="132">CON5-7</text>
<text x="349.2" y="134.6">CON5-8</text>
<text x="107" y="141.1">5</text>
<text x="107" y="143.6">4</text>
<text x="112.8" y="142.2">UP</text>
<text x="118.6" y="139.6">BORROW</text>
<text x="121" y="142.2">CARRY</text>
<text x="133.1" y="138.5">13</text>
<text x="133.1" y="141.1">12</text>
<text x="212.4" y="141.1">19</text>
<text x="213.6" y="138.5">1</text>
<text x="219.5" y="139.6">G1</text>
<text x="219.5" y="142.2">G2</text>
<text x="308.9" y="141.1">19</text>
<text x="310.1" y="138.5">1</text>
<text x="316" y="139.6">G1</text>
<text x="316" y="142.2">G2</text>
<text x="105.8" y="146.1">14</text>
<text x="112.8" y="144.7">DOWN</text>
<text x="112.8" y="147.3">CLEAR</text>
<text x="213.6" y="153.8">2</text>
<text x="219.5" y="154.9">A1</text>
<text x="227.4" y="154.9">Y1</text>
<text x="234.7" y="153.8">18</text>
<text x="310.1" y="153.8">2</text>
<text x="316" y="154.9">A1</text>
<text x="323.9" y="154.9">Y1</text>
<text x="331.2" y="153.8">18</text>
<text x="349.2" y="154.9">CON6-1</text>
<text x="213.6" y="156.3">3</text>
<text x="213.6" y="158.8">4</text>
<text x="213.6" y="161.4">5</text>
<text x="219.5" y="157.4">A2</text>
<text x="219.5" y="159.9">A3</text>
<text x="227.4" y="160">Y3</text>
<text x="227.4" y="157.4">Y2</text>
<text x="234.7" y="161.4">15</text>
<text x="234.7" y="158.8">16</text>
<text x="234.7" y="156.3">17</text>
<text x="310.1" y="156.3">3</text>
<text x="310.1" y="158.8">4</text>
<text x="310.1" y="161.4">5</text>
<text x="316" y="157.4">A2</text>
<text x="316" y="159.9">A3</text>
<text x="323.9" y="160">Y3</text>
<text x="323.9" y="157.4">Y2</text>
<text x="331.2" y="161.4">15</text>
<text x="331.2" y="158.8">16</text>
<text x="331.2" y="156.3">17</text>
<text x="349.2" y="157.4">CON6-2</text>
<text x="349.2" y="159.9">CON6-3</text>
<text x="105.8" y="163.9">15</text>
<text x="107" y="166.5">1</text>
<text x="112.8" y="165">A</text>
<text x="112.8" y="167.6">B</text>
<text x="125.4" y="167.6">QB</text>
<text x="125.4" y="165">QA</text>
<text x="133.1" y="166.5">2</text>
<text x="133.1" y="163.9">3</text>
<text x="213.6" y="163.9">6</text>
<text x="213.6" y="166.5">7</text>
<text x="219.5" y="162.5">A4</text>
<text x="219.5" y="165">A5</text>
<text x="219.5" y="167.6">A6</text>
<text x="227.4" y="167.6">Y6</text>
<text x="227.4" y="165">Y5</text>
<text x="227.4" y="162.5">Y4</text>
<text x="234.7" y="166.5">13</text>
<text x="234.7" y="163.9">14</text>
<text x="310.1" y="163.9">6</text>
<text x="310.1" y="166.5">7</text>
<text x="316" y="162.5">A4</text>
<text x="316" y="165">A5</text>
<text x="316" y="167.6">A6</text>
<text x="323.9" y="167.6">Y6</text>
<text x="323.9" y="165">Y5</text>
<text x="323.9" y="162.5">Y4</text>
<text x="331.2" y="166.5">13</text>
<text x="331.2" y="163.9">14</text>
<text x="349.2" y="162.5">CON6-4</text>
<text x="349.2" y="165">CON6-5</text>
<text x="349.2" y="167.6">CON6-6</text>
<text x="105.8" y="169">10</text>
<text x="107" y="171.5">9</text>
<text x="112.8" y="170.1">C</text>
<text x="112.8" y="172.6">D</text>
<text x="125.2" y="172.6">QD</text>
<text x="125.3" y="170.1">QC</text>
<text x="133.1" y="171.5">7</text>
<text x="133.1" y="169">6</text>
<text x="213.6" y="169">8</text>
<text x="213.6" y="171.5">9</text>
<text x="219.5" y="170.1">A7</text>
<text x="219.5" y="172.6">A8</text>
<text x="227.4" y="172.6">Y8</text>
<text x="227.4" y="170.1">Y7</text>
<text x="234.7" y="171.5">11</text>
<text x="234.7" y="169">12</text>
<text x="310.1" y="169">8</text>
<text x="310.1" y="171.5">9</text>
<text x="316" y="170.1">A7</text>
<text x="316" y="172.6">A8</text>
<text x="323.9" y="172.6">Y8</text>
<text x="323.9" y="170.1">Y7</text>
<text x="331.2" y="171.5">11</text>
<text x="331.2" y="169">12</text>
<text x="349.2" y="170.1">CON6-7</text>
<text x="349.2" y="172.6">CON6-8</text>
<text x="105.8" y="176.6">11</text>
<text x="112.8" y="177.7">LOAD</text>
<text x="133.1" y="179.1">13</text>
<text x="212.4" y="179.1">19</text>
<text x="213.6" y="176.6">1</text>
<text x="219.5" y="177.7">G1</text>
<text x="308.9" y="179.1">19</text>
<text x="310.1" y="176.6">1</text>
<text x="316" y="177.7">G1</text>
<text x="107" y="181.7">5</text>
<text x="107" y="184.2">4</text>
<text x="112.8" y="182.8">UP</text>
<text x="112.8" y="185.3">DOWN</text>
<text x="118.6" y="180.3">BORROW</text>
<text x="121" y="182.8">CARRY</text>
<text x="133.1" y="181.7">12</text>
<text x="219.5" y="180.3">G2</text>
<text x="316" y="180.3">G2</text>
<text x="105.8" y="186.8">14</text>
<text x="112.8" y="187.9">CLEAR</text>
<text x="105.8" y="204.5">15</text>
<text x="105.8" y="209.6">10</text>
<text x="107" y="207.1">1</text>
<text x="112.8" y="205.7">A</text>
<text x="112.8" y="208.2">B</text>
<text x="125.4" y="208.2">QB</text>
<text x="125.4" y="205.7">QA</text>
<text x="133.1" y="209.6">6</text>
<text x="133.1" y="207.1">2</text>
<text x="133.1" y="204.5">3</text>
<text x="107" y="212.2">9</text>
<text x="112.8" y="210.7">C</text>
<text x="112.8" y="213.3">D</text>
<text x="125.2" y="213.3">QD</text>
<text x="125.3" y="210.7">QC</text>
<text x="133.1" y="212.2">7</text>
<text x="105.8" y="217.2">11</text>
<text x="112.8" y="218.4">LOAD</text>
<text x="118.6" y="220.9">BORROW</text>
<text x="133.1" y="219.8">13</text>
<text x="105.8" y="227.4">14</text>
<text x="107" y="222.3">5</text>
<text x="107" y="224.9">4</text>
<text x="112.8" y="223.4">UP</text>
<text x="112.8" y="226">DOWN</text>
<text x="121" y="223.4">CARRY</text>
<text x="133.1" y="222.3">12</text>
<text x="112.8" y="228.5">CLEAR</text>
</g>
</g></defs>
<g fill="#000" stroke="#000" stroke-width=".21">
<path d="M67.8 18.2v3.9zM115.3 18.2v3.9zM162.7 18.2v3.9zM210.2 18.2v3.9zM257.6 18.2v3.9zM305.1 18.2v3.9zM352.5 18.2v3.9zM20.3 22.1v252.6zM35.4 36.2h5.4zM44.4 37.3h139.7zM20.3 22.1h379.7zM32.9 46.4h7.9z"/>
<path d="M34.9 41.3h5.9zM44.4 42.4h25.4zM44.4 52.5h15.3zM59.7 52.5v53.4zM59.7 52.5h314.9zM44.4 47.5h20.4zM64.8 47.5v53.3zM113.6 49.3h8.4zM16.5 72.6h3.8zM102.9 75.4v2.5zM400 72.6h3.8zM69.8 42.4v53.3z"/>
<path d="M69.8 95.7v40.6zM80 80.5l2.5 2.5zM80 83l2.5 2.5zM80 85.5l2.5 2.6zM80 88.1l2.5 2.5zM82.5 83h22.9zM82.5 85.5h22.9zM82.5 88.1h22.9zM82.5 90.6h22.9zM89.9 98.8h7.9zM91.8 93.7h6zM105.4 83h5.1z"/>
<path d="M105.4 85.5h5.1zM105.4 88.1h5.1zM105.4 90.6h5.1zM105.4 95.7h3.1zM69.8 95.7h35.6zM130.8 90.6h5.1zM130.8 88.1h5.1zM130.8 85.5h5.1zM130.8 83h5.1zM132.8 98.2h3.1zM135.9 83h17.7zM135.9 85.5h17.7z"/>
<path d="M135.9 88.1h17.7zM135.9 90.6h17.7zM153.6 83l2.6 2.5zM153.6 85.5l2.6 2.6zM153.6 88.1l2.6 2.5zM153.6 90.6l2.6 2.6zM59.7 105.9h45.7zM59.7 105.9v40.6zM64.8 100.8h40.6zM74.9 116v25.4zM102.9 77.9v25.4zM105.4 100.8h5.1z"/>
<path d="M105.4 103.3h5.1zM105.4 105.9h5.1zM102.9 103.3h2.5zM132.8 100.8h3.1zM135.9 100.8h5zM140.9 100.8v15.2zM74.9 116h66zM194.3 116l-2.6 2.6zM191.7 121.1l2.6-2.5zM212.1 116h5zM212.1 118.6h5zM194.3 116h17.8z"/>
<path d="M194.3 118.6h17.8zM232.4 118.6h5.1zM232.4 116h5.1zM237.5 116h20.3zM257.8 116l2.5-2.5zM237.5 118.6h20.3zM257.8 118.6l2.5-2.6zM288.3 118.6l2.5-2.6zM290.8 118.6l-2.5 2.5zM308.6 116h5.1zM308.6 118.6h5.1zM290.8 116h17.8z"/>
<path d="M290.8 118.6h17.8zM328.9 118.6h5.1zM328.9 116h5.1zM344.1 116h2.6zM344.1 118.6h2.6zM334 116h10.1zM334 118.6h10.1zM16.5 123.1h3.8zM69.8 136.3h35.6zM69.8 136.3v40.7zM80 121.1l2.5 2.5zM80 123.6l2.5 2.6z"/>
<path d="M80 126.2l2.5 2.5zM80 128.7l2.5 2.6zM82.5 123.6h22.9zM82.5 126.2h22.9zM82.5 128.7h22.9zM82.5 131.3h22.9zM91.8 134.4h6zM105.4 123.6h5.1zM105.4 126.2h5.1zM105.4 128.7h5.1zM105.4 131.3h5.1zM105.4 136.3h3.1z"/>
<path d="M130.8 131.3h5.1zM130.8 128.7h5.1zM130.8 126.2h5.1zM130.8 123.6h5.1zM132.8 138.9h3.1zM135.9 123.6h17.7zM135.9 126.2h17.7zM135.9 128.7h17.7zM135.9 131.3h17.7zM153.6 123.6l2.6 2.6zM153.6 126.2l2.6 2.5zM153.6 128.7l2.6 2.6z"/>
<path d="M153.6 131.3l2.6 2.5zM184.1 37.3v101.6zM184.1 138.9v38.1zM191.7 123.6l2.6-2.5zM194.3 123.6l-2.6 2.6zM191.7 128.7l2.6-2.5zM191.7 131.3l2.6-2.6zM194.3 131.3l-2.6 2.5zM191.7 136.3l2.6-2.5zM184.1 138.9h25.4zM212.1 138.9h3.1zM212.1 121.1h5z"/>
<path d="M212.1 123.6h5zM212.1 126.2h5zM212.1 128.7h5zM212.1 131.3h5zM212.1 133.8h5zM194.3 121.1h17.8zM194.3 123.6h17.8zM194.3 126.2h17.8zM194.3 128.7h17.8zM194.3 131.3h17.8zM194.3 133.8h17.8zM209.5 138.9h2.6z"/>
<path d="M232.4 133.8h5.1zM232.4 131.3h5.1zM232.4 128.7h5.1zM232.4 126.2h5.1zM232.4 123.6h5.1zM232.4 121.1h5.1zM237.5 121.1h20.3zM257.8 121.1l2.5-2.5zM237.5 123.6h20.3zM257.8 123.6l2.5-2.5zM237.5 126.2h20.3zM237.5 128.7h20.3z"/>
<path d="M237.5 131.3h20.3zM237.5 133.8h20.3zM257.8 126.2l2.5-2.6zM260.3 126.2l-2.5 2.5zM257.8 131.3l2.5-2.6zM260.3 131.3l-2.5 2.5zM290.8 121.1l-2.5 2.5zM288.3 126.2l2.5-2.6zM290.8 126.2l-2.5 2.5zM288.3 131.3l2.5-2.6zM290.8 131.3l-2.5 2.5zM290.8 133.8l-2.5 2.5z"/>
<path d="M308.6 138.9h3.1zM308.6 121.1h5.1zM308.6 123.6h5.1zM308.6 126.2h5.1zM308.6 128.7h5.1zM308.6 131.3h5.1zM308.6 133.8h5.1zM306 138.9h2.6zM290.8 121.1h17.8zM290.8 123.6h17.8zM290.8 126.2h17.8zM290.8 128.7h17.8z"/>
<path d="M290.8 131.3h17.8zM290.8 133.8h17.8zM328.9 133.8h5.1zM328.9 131.3h5.1zM328.9 128.7h5.1zM328.9 126.2h5.1zM328.9 123.6h5.1zM328.9 121.1h5.1zM344.1 121.1h2.6zM344.1 123.6h2.6zM344.1 126.2h2.6zM344.1 128.7h2.6z"/>
<path d="M344.1 131.3h2.6zM344.1 133.8h2.6zM334 121.1h10.1zM334 123.6h10.1zM334 126.2h10.1zM334 128.7h10.1zM334 131.3h10.1zM334 133.8h10.1zM400 123.1h3.8zM59.7 146.5h45.7zM59.7 146.5v40.6zM74.9 141.4h30.5z"/>
<path d="M74.9 156.7v25.4zM102.9 103.3v40.7zM105.4 141.4h5.1zM105.4 144h5.1zM105.4 146.5h5.1zM102.9 144h2.5zM105.4 146.5h2.5zM132.8 141.4h3.1zM135.9 141.4h5zM140.9 141.4v15.3zM74.9 156.7h66zM194.3 154.1l-2.6 2.6z"/>
<path d="M191.7 159.2l2.6-2.5zM191.7 161.7l2.6-2.5zM209.5 138.9v2.5zM212.1 141.4h3.1zM212.1 154.1h5zM212.1 156.7h5zM212.1 159.2h5zM194.3 154.1h17.8zM194.3 156.7h17.8zM194.3 159.2h17.8zM209.5 141.4h2.6zM232.4 159.2h5.1z"/>
<path d="M232.4 156.7h5.1zM232.4 154.1h5.1zM237.5 154.1h20.3zM237.5 156.7h20.3zM237.5 159.2h20.3zM257.8 154.1l2.5-2.5zM260.3 154.1l-2.5 2.6zM260.3 156.7l-2.5 2.5zM257.8 161.7l2.5-2.5zM290.8 154.1l-2.5 2.6zM290.8 156.7l-2.5 2.5zM288.3 161.7l2.5-2.5z"/>
<path d="M306 144v2.5zM306 138.9v2.5zM306 141.4v2.6zM308.6 141.4h3.1zM308.6 154.1h5.1zM308.6 156.7h5.1zM308.6 159.2h5.1zM306 141.4h2.6zM290.8 154.1h17.8zM290.8 156.7h17.8zM290.8 159.2h17.8zM328.9 159.2h5.1z"/>
<path d="M328.9 156.7h5.1zM328.9 154.1h5.1zM344.1 154.1h2.6zM344.1 156.7h2.6zM344.1 159.2h2.6zM334 154.1h10.1zM334 156.7h10.1zM334 159.2h10.1zM16.5 173.7h3.8zM69.8 177h35.6zM69.8 177v40.6zM80 161.7l2.5 2.6z"/>
<path d="M80 164.3l2.5 2.5zM80 166.8l2.5 2.6zM80 169.4l2.5 2.5zM82.5 164.3h22.9zM82.5 166.8h22.9zM82.5 169.4h22.9zM82.5 171.9h22.9zM91.8 175h6zM105.4 164.3h5.1zM105.4 166.8h5.1zM105.4 169.4h5.1zM105.4 171.9h5.1z"/>
<path d="M105.4 177h3.1zM130.8 171.9h5.1zM130.8 169.4h5.1zM130.8 166.8h5.1zM130.8 164.3h5.1zM132.8 179.5h3.1zM135.9 164.3h17.7zM135.9 166.8h17.7zM135.9 169.4h17.7zM135.9 171.9h17.7zM153.6 164.3l2.6 2.5zM153.6 166.8l2.6 2.6z"/>
<path d="M153.6 169.4l2.6 2.5zM153.6 171.9l2.6 2.5zM184.1 177h25.4zM194.3 161.7l-2.6 2.6zM191.7 166.8l2.6-2.5zM191.7 169.4l2.6-2.6zM194.3 169.4l-2.6 2.5zM191.7 174.4l2.6-2.5zM209.5 177h2.6zM209.5 177v2.5zM212.1 177h3.1zM212.1 161.7h5z"/>
<path d="M212.1 164.3h5zM212.1 166.8h5zM212.1 169.4h5zM212.1 171.9h5zM212.1 179.5h3.1zM194.3 161.7h17.8zM194.3 164.3h17.8zM194.3 166.8h17.8zM194.3 169.4h17.8zM194.3 171.9h17.8zM209.5 179.5h2.6zM232.4 171.9h5.1z"/>
<path d="M232.4 169.4h5.1zM232.4 166.8h5.1zM232.4 164.3h5.1zM232.4 161.7h5.1zM237.5 161.7h20.3zM237.5 164.3h20.3zM237.5 166.8h20.3zM237.5 169.4h20.3zM237.5 171.9h20.3zM260.3 161.7l-2.5 2.6zM260.3 164.3l-2.5 2.5zM257.8 169.4l2.5-2.6z"/>
<path d="M260.3 169.4l-2.5 2.5zM290.8 161.7l-2.5 2.6zM290.8 164.3l-2.5 2.5zM288.3 169.4l2.5-2.6zM290.8 169.4l-2.5 2.5zM290.8 171.9l-2.5 2.5zM306 177h2.6zM306 177v2.5zM306 179.5v2.6zM308.6 177h3.1zM308.6 161.7h5.1zM308.6 164.3h5.1z"/>
<path d="M308.6 166.8h5.1zM308.6 169.4h5.1zM308.6 171.9h5.1zM308.6 179.5h3.1zM306 179.5h2.6zM290.8 161.7h17.8zM290.8 164.3h17.8zM290.8 166.8h17.8zM290.8 169.4h17.8zM290.8 171.9h17.8zM328.9 171.9h5.1zM328.9 169.4h5.1z"/>
<path d="M328.9 166.8h5.1zM328.9 164.3h5.1zM328.9 161.7h5.1zM344.1 161.7h2.6zM344.1 164.3h2.6zM344.1 166.8h2.6zM344.1 169.4h2.6zM344.1 171.9h2.6zM334 161.7h10.1zM334 164.3h10.1zM334 166.8h10.1zM334 169.4h10.1z"/>
<path d="M334 171.9h10.1zM400 173.7h3.8zM59.7 187.1h45.7zM59.7 187.1v40.6zM74.9 182.1h30.5zM74.9 197.3v25.4zM102.9 144v40.6zM105.4 182.1h5.1zM105.4 184.6h5.1zM105.4 187.1h5.1zM102.9 184.6h2.5zM132.8 182.1h3.1z"/>
<path d="M135.9 182.1h5zM140.9 182.1v15.2zM74.9 197.3h66zM306 182.1v2.5zM69.8 217.6h35.6zM80 202.4l2.5 2.5zM80 204.9l2.5 2.5zM80 207.4l2.5 2.6zM80 210l2.5 2.5zM82.5 204.9h22.9zM82.5 207.4h22.9zM82.5 210h22.9z"/>
<path d="M82.5 212.5h22.9zM91.8 215.6h6zM105.4 204.9h5.1zM105.4 207.4h5.1zM105.4 210h5.1zM105.4 212.5h5.1zM105.4 217.6h3.1zM130.8 212.5h5.1zM130.8 210h5.1zM130.8 207.4h5.1zM130.8 204.9h5.1zM135.9 204.9h17.7z"/>
<path d="M135.9 207.4h17.7zM135.9 210h17.7zM135.9 212.5h17.7zM153.6 204.9l2.6 2.5zM153.6 207.4l2.6 2.6zM153.6 210l2.6 2.5zM153.6 212.5l2.6 2.5zM16.5 224.2h3.8zM59.7 227.7h45.7zM74.9 222.7h30.5zM102.9 184.6v40.6zM105.4 222.7h5.1z"/>
<path d="M105.4 225.2h5.1zM105.4 227.7h5.1zM102.9 225.2h2.5zM132.8 220.1h3.1zM132.8 222.7h3.1zM400 224.2h3.8zM29.2 253.1v2.6zM29.2 257.7v.5zM29.2 255.7v.5zM29.2 250.6v2.5zM36.8 253.1v2.6zM36.8 257.7v.5z"/>
<path d="M36.8 255.7v.5zM36.8 250.6v2.5zM29.2 250.6h7.6zM44.4 253.1v2.6zM44.4 257.7v.5zM44.4 255.7v.5zM36.8 250.6h7.6zM44.4 250.6v2.5zM52.1 253.1v2.6zM52.1 257.7v.5zM52.1 255.7v.5zM44.4 250.6h7.7z"/>
<path d="M52.1 250.6v2.5zM59.7 253.1v2.6zM59.7 257.7v.5zM59.7 255.7v.5zM52.1 250.6h7.6zM59.7 250.6v2.5zM67.3 253.1v2.6zM67.3 257.7v.5zM67.3 255.7v.5zM59.7 250.6h7.6zM67.3 250.6v2.5zM74.9 253.1v2.6z"/>
<path d="M74.9 257.7v.5zM74.9 255.7v.5zM67.3 250.6h7.6zM74.9 250.6v2.5zM82.5 245.5v2.6zM82.5 253.1v2.6zM82.5 257.7v.5zM82.5 255.7v.5zM74.9 250.6h7.6zM82.5 248.1v2.5zM82.5 250.6v2.5zM92.7 245.5v2.6z"/>
<path d="M92.7 253.1v2.6zM92.7 255.7v.5zM92.7 257.7v.5zM92.7 248.1v5zM20.3 274.7h379.7zM29.2 265.8v2.6zM29.2 258.2v2.6zM29.2 260.8v2.5zM29.2 263.3h7.6zM29.2 263.3v2.5zM36.8 258.2v2.6zM36.8 260.8v2.5z"/>
<path d="M44.4 258.2v2.6zM36.8 263.3h7.6zM44.4 260.8v2.5zM52.1 258.2v2.6zM44.4 263.3h7.7zM52.1 260.8v2.5zM59.7 258.2v2.6zM52.1 263.3h7.6zM59.7 260.8v2.5zM67.3 258.2v2.6zM59.7 263.3h7.6zM67.3 260.8v2.5z"/>
<path d="M67.8 274.7v3.8zM74.9 258.2v2.6zM67.3 263.3h7.6zM74.9 260.8v2.5zM82.5 258.2v2.6zM74.9 263.3h7.6zM82.5 260.8v2.5zM92.7 258.2v2.6zM92.7 263.3v2.5zM92.7 260.8v2.5zM115.3 274.7v3.8zM162.7 274.7v3.8z"/>
<path d="M210.2 274.7v3.8zM257.6 274.7v3.8zM305.1 274.7v3.8zM352.5 274.7v3.8zM400 264.5v.1zM400 268.4v6.2zM400 274.6h.1zM400 22.1v252.6z"/>
<circle cx="59.7" cy="52.5" r=".51"/>
<circle cx="69.8" cy="95.7" r=".51"/>
<circle cx="59.7" cy="105.9" r=".51"/>
<circle cx="102.9" cy="103.3" r=".51"/>
<circle cx="69.8" cy="136.3" r=".51"/>
<circle cx="184.1" cy="138.9" r=".51"/>
<circle cx="209.5" cy="138.9" r=".51"/>
<circle cx="59.7" cy="146.5" r=".51"/>
<circle cx="102.9" cy="144" r=".51"/>
<circle cx="306" cy="141.4" r=".51"/>
<circle cx="69.8" cy="177" r=".51"/>
<circle cx="209.5" cy="177" r=".51"/>
<circle cx="306" cy="179.5" r=".51"/>
<circle cx="59.7" cy="187.1" r=".51"/>
<circle cx="102.9" cy="184.6" r=".51"/>
<circle cx="36.8" cy="250.6" r=".51"/>
<circle cx="44.4" cy="250.6" r=".51"/>
<circle cx="52.1" cy="250.6" r=".51"/>
<circle cx="59.7" cy="250.6" r=".51"/>
<circle cx="67.3" cy="250.6" r=".51"/>
<circle cx="74.9" cy="250.6" r=".51"/>
<circle cx="82.5" cy="250.6" r=".51"/>
<circle cx="29.2" cy="263.3" r=".51"/>
<circle cx="36.8" cy="263.3" r=".51"/>
<circle cx="44.4" cy="263.3" r=".51"/>
<circle cx="52.1" cy="263.3" r=".51"/>
<circle cx="59.7" cy="263.3" r=".51"/>
<circle cx="67.3" cy="263.3" r=".51"/>
<circle cx="74.9" cy="263.3" r=".51"/>
</g>
<g fill="#000" stroke="#000" stroke-width=".28">
<path d="M33.1 35.8v3zM33.1 35.8h9.8zM33.1 38.8h9.8zM42.9 35.8l1.5 1.5zM44.4 37.3l-1.5 1.5zM30.2 51v3.1zM30.6 45.9v3.1zM32.6 40.9v3zM32.6 40.9h10.3zM32.6 43.9h10.3zM30.6 45.9h12.3zM30.6 49h12.3z"/>
<path d="M30.2 51h12.7zM30.2 54.1h12.7zM42.9 40.9l1.5 1.5zM44.4 42.4l-1.5 1.5zM42.9 45.9l1.5 1.6zM44.4 47.5l-1.5 1.5zM42.9 51l1.5 1.5zM44.4 52.5l-1.5 1.6zM374.6 52.5l1.5-1.5zM374.6 52.5l1.5 1.6zM376.1 51h12.8zM376.1 54.1h12.8z"/>
<path d="M388.9 51v3.1zM102.9 75.4l-1.3 1.9zM102.9 75.4l1.2 1.9zM304.1 146.5h3.8zM304.1 184.6h3.8zM82.5 245.5l-1.2 1.9zM82.5 245.5l1.3 1.9zM92.7 245.5l-1.3 1.9zM92.7 245.5l1.3 1.9zM313.7 249.3h86.3zM313.7 254.4h86.3zM313.7 259.5h58.4z"/>
<path d="M372.1 259.5h27.9zM372.1 259.5v5.1zM27.3 268.4h3.8zM90.8 265.8h3.8zM313.7 264.6h58.4zM313.7 269.7h86.3zM372.1 264.6h27.9zM400 268.4v1.3z"/>
</g>
<g fill="none" stroke="#000" stroke-width=".21">
<circle cx="109.5" cy="95.7" r=".99"/>
<circle cx="131.8" cy="98.2" r=".99"/>
<circle cx="131.8" cy="100.8" r=".99"/>
<circle cx="109.5" cy="136.3" r=".99"/>
<circle cx="131.8" cy="138.9" r=".99"/>
<circle cx="216.2" cy="138.9" r="1"/>
<circle cx="312.7" cy="138.9" r="1"/>
<circle cx="131.8" cy="141.4" r=".99"/>
<circle cx="216.2" cy="141.4" r="1"/>
<circle cx="312.7" cy="141.4" r="1"/>
<circle cx="109.5" cy="177" r=".99"/>
<circle cx="131.8" cy="179.5" r=".99"/>
<circle cx="216.2" cy="177" r="1"/>
<circle cx="216.2" cy="179.5" r="1"/>
<circle cx="312.7" cy="179.5" r="1"/>
<circle cx="312.7" cy="177" r="1"/>
<circle cx="131.8" cy="182.1" r=".99"/>
<circle cx="109.5" cy="217.6" r=".99"/>
<circle cx="131.8" cy="222.7" r=".99"/>
<circle cx="131.8" cy="220.1" r=".99"/>
</g>
<g fill="#000" stroke="#000" stroke-width=".61">
<path d="M20.3 22.1v252.6zM20.3 22.1h379.7zM110.5 80.5v27.9zM110.5 80.5h20.3zM110.5 108.4h20.3zM130.8 80.5v27.9zM217.1 113.5v30.5zM217.1 113.5h15.3zM313.7 113.5v30.5zM313.7 113.5h15.2zM346.7 116h1.2zM346.7 118.6h1.2z"/>
<path d="M110.5 121.1v27.9zM110.5 121.1h20.3zM346.7 121.1h1.2zM346.7 123.6h1.2zM346.7 126.2h1.2zM346.7 128.7h1.2zM346.7 131.3h1.2zM346.7 133.8h1.2zM110.5 149h20.3zM130.8 121.1v27.9zM217.1 144h15.3zM217.1 151.6v30.5z"/>
<path d="M232.4 113.5v30.5zM217.1 151.6h15.3zM313.7 144h15.2zM313.7 151.6v30.5zM328.9 113.5v30.5zM313.7 151.6h15.2zM346.7 154.1h1.2zM346.7 156.7h1.2zM346.7 159.2h1.2zM110.5 161.7v28zM110.5 161.7h20.3zM346.7 161.7h1.2z"/>
<path d="M346.7 164.3h1.2zM346.7 166.8h1.2zM346.7 169.4h1.2zM346.7 171.9h1.2zM110.5 189.7h20.3zM130.8 161.7v28zM217.1 182.1h15.3zM232.4 151.6v30.5zM313.7 182.1h15.2zM328.9 151.6v30.5zM110.5 202.4v27.9zM110.5 202.4h20.3z"/>
<path d="M110.5 230.3h20.3zM130.8 202.4v27.9zM283.2 244.3v30.4zM313.7 254.4v5.1zM313.7 249.3v5.1zM313.7 244.3v5zM313.7 244.3h86.3zM283.2 244.3h30.5zM400 254.4v5.1zM400 249.3v5.1zM400 244.3v5zM400 22.1v222.2z"/>
<path d="M20.3 274.7h262.9zM283.2 274.7h30.5zM313.7 274.7h86.3zM313.7 269.7v5zM313.7 264.6v5.1zM313.7 259.5v5.1zM400 268.4v6.3zM400 264.6v3.8zM400 259.5v5.1z"/>
</g>
<g fill="#000" stroke="#000" stroke-width=".21">
<path d="M27.2 256.2h4v.5h-4zM27.2 257.2h4v.5h-4zM34.8 256.2h4.1v.5h-4.1zM34.8 257.2h4.1v.5h-4.1zM42.4 256.2h4.1v.5h-4.1zM42.4 257.2h4.1v.5h-4.1zM50 256.2h4.1v.5h-4.1zM50 257.2h4.1v.5h-4.1zM57.7 256.2h4v.5h-4zM57.7 257.2h4v.5h-4zM65.3 256.2h4v.5h-4zM65.3 257.2h4v.5h-4z"/>
<path d="M72.9 256.2h4.1v.5h-4.1zM72.9 257.2h4.1v.5h-4.1zM80.5 256.2h4.1v.5h-4.1zM80.5 257.2h4.1v.5h-4.1zM90.7 257.2h4v.5h-4zM90.7 256.2h4v.5h-4zM252.7 253.1h25.4v10.2h-25.4z"/>
</g>
<path d="M16.5 18.2v260.3zM16.5 18.2h387.3zM16.5 278.5h387.3zM403.8 18.2v260.3z" fill="#000" stroke="#000" stroke-width=".32"/>
<g fill="#000" stroke="#000" stroke-width=".76">
<path d="M44.4 60.2h30.5zM74.9 60.2h299.7zM74.9 60.2l5.1 5zM255.2 60.2l5.1 5zM260.3 65.2v104.2zM80 65.2v144.8zM156.2 85.5v132.1zM191.7 118.6v99zM288.3 118.6v99zM161.3 222.7h213.3zM156.2 217.6l5.1 5.1zM191.7 217.6l5.1 5.1z"/>
<path d="M288.3 217.6l5 5.1z"/>
</g>
<path d="M222.2 253.1v10.2zM222.2 253.1h55.9zM222.2 263.3v7.6zM222.2 270.9h55.9zM222.2 263.3h55.9zM278.1 263.3v7.6zM278.1 253.1v10.2z" fill="#000" stroke="#000" stroke-width=".42"/>
<use href="#words"/>
</svg>
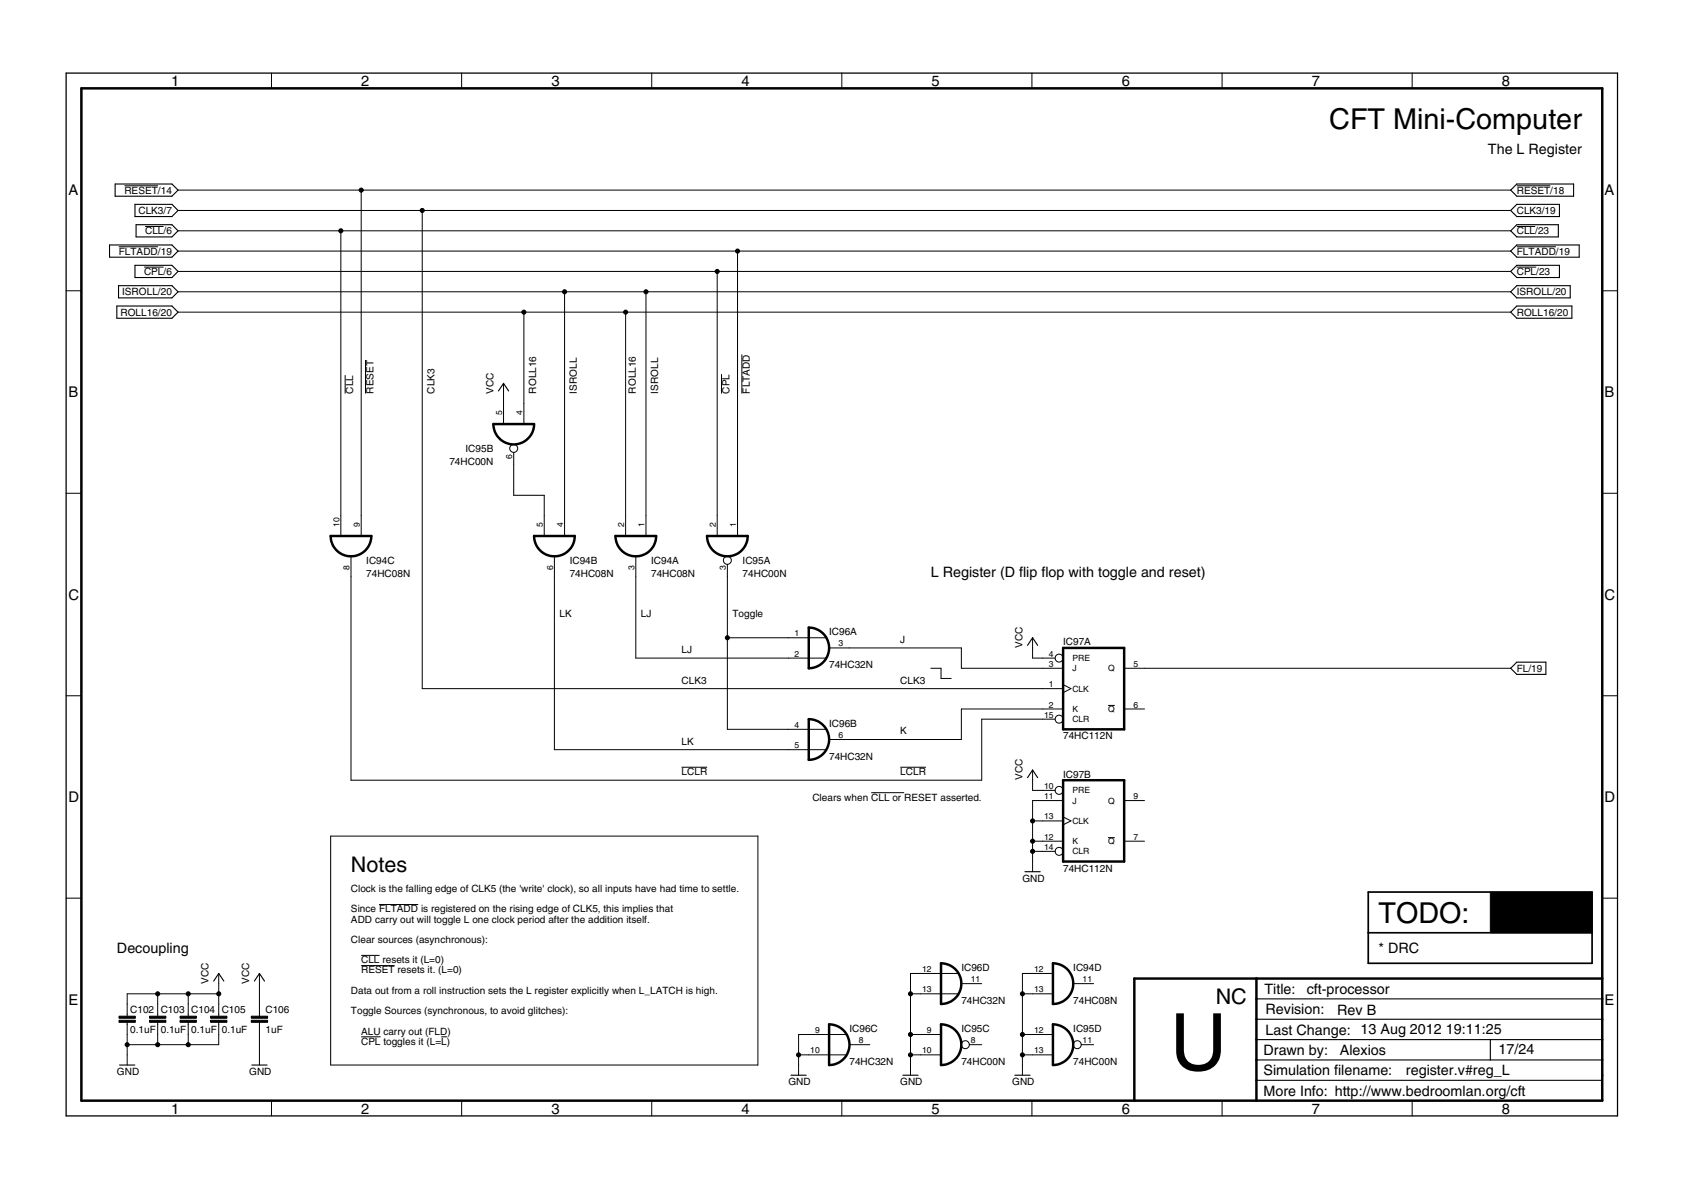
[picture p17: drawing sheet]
<svg xmlns="http://www.w3.org/2000/svg" width="420mm" height="297mm" viewBox="0 0 420 297" stroke-linecap="round" stroke-linejoin="round" font-family="sans-serif">
<defs><g id="words">
<text font-size="19.7" x="292.1" y="267.1">U</text>
<g font-size="7.2">
<text x="331.8" y="32.2">CFT Mini-Computer</text>
<text x="344.1" y="230.3">TODO:</text>
</g>
<g font-size="5.4">
<text x="87.6" y="217.6">Notes</text>
<text x="303.5" y="250.6">NC</text>
</g>
<g font-size="3.7">
<text x="42.7" y="21.5">1</text>
<text x="90.2" y="21.5">2</text>
<text x="137.7" y="21.5">3</text>
<text x="185.1" y="21.5">4</text>
<text x="232.6" y="21.5">5</text>
<text x="280" y="21.5">6</text>
<text x="327.5" y="21.5">7</text>
<text x="375" y="21.5">8</text>
<text x="17.1" y="48.6">A</text>
<text x="400.6" y="48.6">A</text>
<text x="17.1" y="99.2">B</text>
<text x="400.6" y="99.2">B</text>
<text x="17.1" y="149.7">C</text>
<text x="400.6" y="149.7">C</text>
<text x="17.1" y="200.2">D</text>
<text x="400.6" y="200.2">D</text>
<text x="17.1" y="250.8">E</text>
<text x="400.6" y="250.8">E</text>
<text x="42.7" y="277.9">1</text>
<text x="90.2" y="277.9">2</text>
<text x="137.7" y="277.9">3</text>
<text x="185.1" y="277.9">4</text>
<text x="232.6" y="277.9">5</text>
<text x="280" y="277.9">6</text>
<text x="327.5" y="277.9">7</text>
<text x="375" y="277.9">8</text>
</g>
<g font-size="3.6">
<text x="371.5" y="38.6">The L Register</text>
<text x="232.4" y="144">L Register (D flip flop with toggle and reset)</text>
<text x="29.2" y="237.9">Decoupling</text>
<text x="344.1" y="237.9">* DRC</text>
<text x="315.7" y="248.1">Title:</text>
<text x="326.2" y="248.2">cft-processor</text>
<text x="315.9" y="253.2">Revision:</text>
<text x="333.8" y="253.3">Rev B</text>
<text x="315.4" y="263.3">Drawn by:</text>
<text x="315.9" y="258.2">Last Change: 13 Aug 2012</text>
<text x="334.5" y="263.3">Alexios</text>
<text x="361" y="258.1">19:11:25</text>
<text x="374.1" y="263.2">17/24</text>
<text x="315.4" y="268.4">Simulation filename:</text>
<text x="351" y="268.4">register.v#reg_L</text>
<text x="315.4" y="273.5">More Info: http://www.bedroomlan.org/cft</text>
</g>
<g font-size="2.5">
<text x="31.1" y="48.3">RESET/14</text>
<text x="34.6" y="53.4">CLK3/7</text>
<text x="378.7" y="48.3">RESET/18</text>
<text x="378.7" y="53.4">CLK3/19</text>
<text x="36.2" y="58.5">CLL/6</text>
<text x="378.7" y="58.5">CLL/23</text>
<text x="29.7" y="63.6">FLTADD/19</text>
<text x="378.7" y="63.6">FLTADD/19</text>
<text x="36" y="68.7">CPL/6</text>
<text x="378.7" y="68.7">CPL/23</text>
<text x="30.5" y="73.7">ISROLL/20</text>
<text x="378.7" y="73.7">ISROLL/20</text>
<text x="30.1" y="78.8">ROLL16/20</text>
<text x="378.7" y="78.8">ROLL16/20</text>
<text x="88.1" y="98.2" transform="rotate(-90 88.1 98.2)">CLL</text>
<text x="93.2" y="98.2" transform="rotate(-90 93.2 98.2)">RESET</text>
<text x="108.4" y="98.2" transform="rotate(-90 108.4 98.2)">CLK3</text>
<text x="123.2" y="98.2" transform="rotate(-90 123.2 98.2)">VCC</text>
<text x="133.8" y="98.2" transform="rotate(-90 133.8 98.2)">ROLL16</text>
<text x="144" y="98.2" transform="rotate(-90 144 98.2)">ISROLL</text>
<text x="158.7" y="98.2" transform="rotate(-90 158.7 98.2)">ROLL16</text>
<text x="164.3" y="98.2" transform="rotate(-90 164.3 98.2)">ISROLL</text>
<text x="182.1" y="98.2" transform="rotate(-90 182.1 98.2)">CPL</text>
<text x="187.2" y="98.2" transform="rotate(-90 187.2 98.2)">FLTADD</text>
<text x="116.2" y="112.8">IC95B</text>
<text x="112.2" y="116">74HC00N</text>
<text x="91.4" y="144">74HC08N</text>
<text x="91.4" y="140.8">IC94C</text>
<text x="142.2" y="144">74HC08N</text>
<text x="142.2" y="140.8">IC94B</text>
<text x="162.5" y="144">74HC08N</text>
<text x="162.5" y="140.8">IC94A</text>
<text x="185.4" y="144">74HC00N</text>
<text x="185.4" y="140.8">IC95A</text>
<text x="139.7" y="154.1">LK</text>
<text x="160" y="154.1">LJ</text>
<text x="182.9" y="154.1">Toggle</text>
<text x="207" y="158.6">IC96A</text>
<text x="224.8" y="160.5">J</text>
<text x="255.2" y="161.7" transform="rotate(-90 255.2 161.7)">VCC</text>
<text x="265.4" y="161.1">IC97A</text>
<text x="170.2" y="163">LJ</text>
<text x="207" y="166.8">74HC32N</text>
<text x="378.7" y="167.7">FL/19</text>
<text x="170.2" y="170.6">CLK3</text>
<text x="224.8" y="170.6">CLK3</text>
<text x="170.2" y="185.9">LK</text>
<text x="207" y="181.4">IC96B</text>
<text x="224.8" y="183.3">K</text>
<text x="265.4" y="184.6">74HC112N</text>
<text x="207" y="189.7">74HC32N</text>
<text x="170.2" y="193.5">LCLR</text>
<text x="224.8" y="193.5">LCLR</text>
<text x="255.2" y="194.7" transform="rotate(-90 255.2 194.7)">VCC</text>
<text x="265.4" y="194.1">IC97B</text>
<text x="202.8" y="199.8">Clears when CLL or RESET asserted.</text>
<text x="255.2" y="220.1">GND</text>
<text x="265.4" y="217.6">74HC112N</text>
<text x="87.6" y="222.7">Clock is the falling edge of CLK5 (the 'write' clock), so all inputs have had time to settle.</text>
<text x="87.6" y="227.8">Since FLTADD is registered on the rising edge of CLK5, this implies that</text>
<text x="87.6" y="230.3">ADD carry out will toggle L one clock period after the addition itself.</text>
<text x="87.6" y="235.4">Clear sources (asynchronous):</text>
<text x="52.1" y="245.5" transform="rotate(-90 52.1 245.5)">VCC</text>
<text x="62.2" y="245.5" transform="rotate(-90 62.2 245.5)">VCC</text>
<text x="90.2" y="240.5">CLL resets it (L=0)</text>
<text x="90.2" y="243">RESET resets it. (L=0)</text>
<text x="240" y="242.4">IC96D</text>
<text x="267.9" y="242.4">IC94D</text>
<text x="87.6" y="248.1">Data out from a roll instruction sets the L register explicitly when L_LATCH is high.</text>
<text x="240" y="250.6">74HC32N</text>
<text x="267.9" y="250.6">74HC08N</text>
<text x="32.5" y="257.9">0.1uF</text>
<text x="32.5" y="252.8">C102</text>
<text x="40.1" y="257.9">0.1uF</text>
<text x="40.1" y="252.8">C103</text>
<text x="47.7" y="257.9">0.1uF</text>
<text x="47.7" y="252.8">C104</text>
<text x="55.4" y="257.9">0.1uF</text>
<text x="55.4" y="252.8">C105</text>
<text x="66.3" y="257.9">1uF</text>
<text x="66.3" y="252.8">C106</text>
<text x="87.6" y="253.2">Toggle Sources (synchronous, to avoid glitches):</text>
<text x="212.1" y="257.6">IC96C</text>
<text x="240" y="257.6">IC95C</text>
<text x="267.9" y="257.6">IC95D</text>
<text x="90.2" y="258.2">ALU carry out (FLD)</text>
<text x="90.2" y="260.8">CPL toggles it (L=L)</text>
<text x="29.2" y="268.4">GND</text>
<text x="62.2" y="268.4">GND</text>
<text x="212.1" y="265.8">74HC32N</text>
<text x="240" y="265.8">74HC00N</text>
<text x="267.9" y="265.8">74HC00N</text>
<text x="196.8" y="270.9">GND</text>
<text x="224.8" y="270.9">GND</text>
<text x="252.7" y="270.9">GND</text>
</g>
<g font-size="2.1">
<text x="125.4" y="103.5" transform="rotate(-90 125.4 103.5)">5</text>
<text x="130.4" y="103.5" transform="rotate(-90 130.4 103.5)">4</text>
<text x="127.9" y="114.5" transform="rotate(-90 127.9 114.5)">6</text>
<text x="84.7" y="131.5" transform="rotate(-90 84.7 131.5)">10</text>
<text x="89.8" y="131.5" transform="rotate(-90 89.8 131.5)">9</text>
<text x="135.5" y="131.5" transform="rotate(-90 135.5 131.5)">5</text>
<text x="140.6" y="131.5" transform="rotate(-90 140.6 131.5)">4</text>
<text x="155.8" y="131.5" transform="rotate(-90 155.8 131.5)">2</text>
<text x="160.9" y="131.5" transform="rotate(-90 160.9 131.5)">1</text>
<text x="178.7" y="131.5" transform="rotate(-90 178.7 131.5)">2</text>
<text x="183.8" y="131.5" transform="rotate(-90 183.8 131.5)">1</text>
<text x="87.3" y="142.4" transform="rotate(-90 87.3 142.4)">8</text>
<text x="138.1" y="142.4" transform="rotate(-90 138.1 142.4)">6</text>
<text x="158.4" y="142.4" transform="rotate(-90 158.4 142.4)">3</text>
<text x="181.2" y="142.4" transform="rotate(-90 181.2 142.4)">3</text>
<text x="198.4" y="158.8">1</text>
<text x="209.3" y="161.4">3</text>
<text x="198.4" y="163.9">2</text>
<text x="261.9" y="166.5">3</text>
<text x="261.9" y="163.9">4</text>
<text x="267.7" y="167.6">J</text>
<text x="267.7" y="165">PRE</text>
<text x="276.6" y="167.6">Q</text>
<text x="283" y="166.5">5</text>
<text x="261.9" y="171.5">1</text>
<text x="267.7" y="172.6">CLK</text>
<text x="260.7" y="179.1">15</text>
<text x="261.9" y="176.6">2</text>
<text x="267.7" y="177.7">K</text>
<text x="276.6" y="177.7">Q</text>
<text x="283" y="176.6">6</text>
<text x="198.4" y="181.7">4</text>
<text x="209.3" y="184.2">6</text>
<text x="267.7" y="180.3">CLR</text>
<text x="198.4" y="186.8">5</text>
<text x="260.7" y="196.9">10</text>
<text x="260.7" y="199.5">11</text>
<text x="267.7" y="200.6">J</text>
<text x="267.7" y="198">PRE</text>
<text x="276.6" y="200.6">Q</text>
<text x="283" y="199.5">9</text>
<text x="260.7" y="204.5">13</text>
<text x="260.7" y="209.6">12</text>
<text x="267.7" y="205.7">CLK</text>
<text x="283" y="209.6">7</text>
<text x="260.7" y="212.2">14</text>
<text x="267.7" y="210.7">K</text>
<text x="267.7" y="213.3">CLR</text>
<text x="276.6" y="210.7">Q</text>
<text x="230.2" y="242.6">12</text>
<text x="242.3" y="245.2">11</text>
<text x="258.2" y="242.6">12</text>
<text x="270.3" y="245.2">11</text>
<text x="230.2" y="247.7">13</text>
<text x="258.2" y="247.7">13</text>
<text x="203.5" y="257.9">9</text>
<text x="231.4" y="257.9">9</text>
<text x="258.2" y="257.9">12</text>
<text x="202.3" y="263">10</text>
<text x="214.4" y="260.4">8</text>
<text x="230.2" y="263">10</text>
<text x="242.3" y="260.4">8</text>
<text x="258.2" y="263">13</text>
<text x="270.3" y="260.4">11</text>
</g>
</g></defs>
<g fill="#000" stroke="#000" stroke-width=".25">
<path d="M67.8 18.2v3.9zM115.3 18.2v3.9zM162.7 18.2v3.9zM210.2 18.2v3.9zM257.6 18.2v3.9zM305.1 18.2v3.9zM352.5 18.2v3.9zM20.3 22.1v252.6zM20.3 22.1h379.7zM31.1 46.4h8.3zM36.2 56.5h4.6zM44.4 52.5h61z"/>
<path d="M44.4 57.6h40.7zM85.1 57.6v71.1zM44.4 47.5h45.8zM90.2 47.5v81.2zM105.4 52.5h271.7zM105.4 52.5v119.4zM90.2 47.5h286.9zM85.1 57.6h292zM378.7 46.4h8.3zM378.7 56.5h4.6zM16.5 72.6h3.8zM29.7 61.6h9.7z"/>
<path d="M36 66.7h4.8zM44.4 77.9h86.4zM44.4 72.8h96.5zM130.8 77.9h25.4zM140.9 72.8h20.4zM140.9 72.8v55.9zM156.2 77.9h220.9zM161.3 72.8h215.8zM44.4 67.8h134.6zM44.4 62.7h139.7zM184.1 62.7v66zM179 67.8h198.1z"/>
<path d="M184.1 62.7h193zM378.7 66.7h4.8zM378.7 61.6h9.7zM400 72.6h3.8zM86.2 93.6v4.6zM91.2 89.9v8.3zM125.7 95.7v2.5zM180.1 93.4v4.8zM185.2 88.5v9.7zM125.7 100.8v5.1zM125.7 98.2v2.6zM128.2 112.9v3.1z"/>
<path d="M128.2 116v7.6zM130.8 100.8v5.1zM130.8 77.9v22.9zM16.5 123.1h3.8zM85.1 128.7v5.1zM90.2 128.7v5.1zM128.2 123.6h7.7zM135.9 128.7v5.1zM135.9 123.6v5.1zM140.9 128.7v5.1zM156.2 128.7v5.1zM156.2 77.9v50.8z"/>
<path d="M161.3 128.7v5.1zM161.3 72.8v55.9zM179 128.7v5.1zM179 67.8v60.9zM184.1 128.7v5.1zM400 123.1h3.8zM87.6 138.9v5.1zM87.6 144v50.8zM138.4 138.9v5.1zM138.4 144v43.1zM158.7 138.9v5.1zM158.7 144v20.3z"/>
<path d="M181.6 140.9v3.1zM181.6 159.2h15.2zM181.6 159.2v22.9zM181.6 144v15.2zM196.8 159.2h5.1zM201.9 159.2h4.3zM16.5 173.7h3.8zM105.4 171.9h154.9zM158.7 164.3h38.1zM196.8 164.3h5.1zM201.9 164.3h4.3zM207 161.7h5.1z"/>
<path d="M212.1 161.7h27.9zM232.4 166.8h2.5zM234.9 166.8v2.6zM234.9 169.4h2.6zM240 161.7v5.1zM240 166.8h20.3zM240 177h20.3zM245.1 179.5h15.2zM257.8 159.2v2.5zM257.8 161.7v2.6zM260.3 171.9h5.1zM260.3 177h5.1z"/>
<path d="M260.3 166.8h5.1zM260.3 164.3h3.1zM260.3 179.5h3.1zM257.8 164.3h2.5zM265.4 170.9l2 1zM265.4 172.9l2-1zM276.6 176.1h1.7zM280.6 166.8h5.1zM280.6 177h5.1zM285.7 166.8h91.4zM400 173.7h3.8zM87.6 194.8h157.5z"/>
<path d="M138.4 187.1h58.4zM170.2 191.5h6.3zM181.6 182.1h15.2zM196.8 182.1h5.1zM196.8 187.1h5.1zM201.9 182.1h4.3zM201.9 187.1h4.3zM207 184.6h5.1zM212.1 184.6h27.9zM217.5 197.9h8.2zM224.8 191.5h6.4zM240 177v7.6z"/>
<path d="M245.1 179.5v15.3zM257.8 192.2v2.6zM257.8 194.8v2.5zM257.8 199.8v5.1zM260.3 199.8h5.1zM260.3 197.3h3.1zM257.8 197.3h2.5zM257.8 199.8h2.5zM280.6 199.8h5.1zM82.5 208.7v57.1zM82.5 208.7h106.7zM257.8 215v2.6z"/>
<path d="M257.8 204.9v5.1zM257.8 210v2.5zM257.8 212.5v2.5zM260.3 204.9h5.1zM260.3 210h5.1zM260.3 212.5h3.1zM257.8 204.9h2.5zM257.8 210h2.5zM257.8 212.5h2.5zM265.4 203.9l2 1zM265.4 205.9l2-1zM276.6 209.1h1.7z"/>
<path d="M280.6 210h5.1zM16.5 224.2h3.8zM90.2 238.5h4.6zM94.6 225.8h9.8zM400 224.2h3.8zM31.7 255.7v2.5zM31.7 250.6v2.5zM31.7 255.2v.5zM31.7 253.1v.6zM31.7 248.1v2.5zM31.7 258.2v2.6zM39.4 255.7v2.5z"/>
<path d="M39.4 250.6v2.5zM39.4 255.2v.5zM39.4 253.1v.6zM39.4 248.1v2.5zM31.7 248.1h7.7zM47 255.7v2.5zM47 250.6v2.5zM47 255.2v.5zM47 253.1v.6zM39.4 248.1h7.6zM47 248.1v2.5zM54.6 243v2.5z"/>
<path d="M54.6 255.7v2.5zM54.6 250.6v2.5zM54.6 255.2v.5zM54.6 253.1v.6zM47 248.1h7.6zM54.6 245.5v2.6zM54.6 248.1v2.5zM64.8 243v2.5zM64.8 250.6v2.5zM64.8 255.7v2.5zM64.8 253.1v.6zM64.8 255.2v.5z"/>
<path d="M64.8 245.5v5.1zM90.2 258.8h4.8zM90.2 241h8.3zM110.2 258.8h1.4zM199.4 258.2v5.1zM201.9 258.2h5.1zM199.4 258.2h2.5zM207 258.2h4.3zM227.3 243v5.1zM227.3 248.1v10.1zM227.3 258.2v5.1zM229.8 243h5.1z"/>
<path d="M229.8 248.1h5.1zM229.8 258.2h5.1zM227.3 243h2.5zM227.3 248.1h2.5zM227.3 258.2h2.5zM234.9 243h4.3zM234.9 248.1h4.3zM240 245.5h5.1zM255.2 243v5.1zM255.2 248.1v10.1zM255.2 258.2v5.1zM257.8 243h5.1z"/>
<path d="M257.8 248.1h5.1zM257.8 258.2h5.1zM255.2 243h2.6zM255.2 248.1h2.6zM255.2 258.2h2.6zM267.9 245.5h5.1zM20.3 274.7h379.7zM31.7 263.3v2.5zM31.7 260.8h7.7zM31.7 260.8v2.5zM39.4 258.2v2.6zM39.4 260.8h7.6z"/>
<path d="M47 258.2v2.6zM47 260.8h7.6zM54.6 258.2v2.6zM64.8 263.3v2.5zM64.8 258.2v5.1zM67.8 274.7v3.8zM82.5 265.8h106.7zM115.3 274.7v3.8zM162.7 274.7v3.8zM189.2 208.7v57.1zM199.4 265.8v2.6zM199.4 263.3v2.5z"/>
<path d="M201.9 263.3h5.1zM199.4 263.3h2.5zM210.2 274.7v3.8zM207 263.3h4.3zM212.1 260.8h5zM227.3 265.8v2.6zM227.3 263.3v2.5zM229.8 263.3h5.1zM227.3 263.3h2.5zM242 260.8h3.1zM255.2 265.8v2.6zM255.2 263.3v2.5z"/>
<path d="M257.6 274.7v3.8zM257.8 263.3h5.1zM255.2 263.3h2.6zM269.9 260.8h3.1zM305.1 274.7v3.8zM352.5 274.7v3.8zM400 264.5v.1zM400 268.4v6.2zM400 274.6h.1zM400 22.1v252.6z"/>
<circle cx="85.1" cy="57.6" r=".51"/>
<circle cx="90.2" cy="47.5" r=".51"/>
<circle cx="105.4" cy="52.5" r=".51"/>
<circle cx="130.8" cy="77.9" r=".51"/>
<circle cx="140.9" cy="72.8" r=".51"/>
<circle cx="156.2" cy="77.9" r=".51"/>
<circle cx="161.3" cy="72.8" r=".51"/>
<circle cx="179" cy="67.8" r=".51"/>
<circle cx="184.1" cy="62.7" r=".51"/>
<circle cx="181.6" cy="159.2" r=".51"/>
<circle cx="257.8" cy="204.9" r=".51"/>
<circle cx="257.8" cy="210" r=".51"/>
<circle cx="257.8" cy="212.5" r=".51"/>
<circle cx="39.4" cy="248.1" r=".51"/>
<circle cx="47" cy="248.1" r=".51"/>
<circle cx="54.6" cy="248.1" r=".51"/>
<circle cx="227.3" cy="258.2" r=".51"/>
<circle cx="227.3" cy="248.1" r=".51"/>
<circle cx="255.2" cy="258.2" r=".51"/>
<circle cx="255.2" cy="248.1" r=".51"/>
<circle cx="31.7" cy="260.8" r=".51"/>
<circle cx="39.4" cy="260.8" r=".51"/>
<circle cx="47" cy="260.8" r=".51"/>
<circle cx="199.4" cy="263.3" r=".51"/>
<circle cx="227.3" cy="263.3" r=".51"/>
<circle cx="255.2" cy="263.3" r=".51"/>
</g>
<g fill="#000" stroke="#000" stroke-width=".28">
<path d="M28.7 45.9v3.1zM33.7 51v3.1zM34 56.1v3zM28.7 45.9h14.2zM28.7 49h14.2zM34 56.1h8.9zM34 59.1h8.9zM33.7 51h9.2zM33.7 54.1h9.2zM42.9 45.9l1.5 1.6zM44.4 47.5l-1.5 1.5zM42.9 56.1l1.5 1.5z"/>
<path d="M44.4 57.6l-1.5 1.5zM42.9 51l1.5 1.5zM44.4 52.5l-1.5 1.6zM377.1 47.5l1.6 1.5zM377.1 47.5l1.6-1.6zM377.1 57.6l1.6 1.5zM378.7 56.1l-1.6 1.5zM377.1 52.5l1.6 1.6zM377.1 52.5l1.6-1.5zM378.7 49h14.1zM378.7 45.9h14.1zM378.7 59.1h10.3z"/>
<path d="M378.7 56.1h10.3zM378.7 54.1h10.6zM378.7 51h10.6zM389 56.1v3zM389.3 51v3.1zM392.8 45.9v3.1zM27.3 61.1v3.1zM29.2 76.4v3zM29.6 71.3v3.1zM33.7 66.2v3.1zM33.7 66.2h9.2zM33.7 69.3h9.2z"/>
<path d="M29.2 76.4h13.7zM29.2 79.4h13.7zM29.6 71.3h13.3zM29.6 74.4h13.3zM27.3 61.1h15.6zM27.3 64.2h15.6zM42.9 66.2l1.5 1.6zM44.4 67.8l-1.5 1.5zM42.9 76.4l1.5 1.5zM42.9 79.4l1.5-1.5zM42.9 71.3l1.5 1.5zM44.4 72.8l-1.5 1.6z"/>
<path d="M42.9 61.1l1.5 1.6zM42.9 64.2l1.5-1.5zM377.1 67.8l1.6 1.5zM378.7 66.2l-1.6 1.6zM377.1 77.9l1.6 1.5zM378.7 76.4l-1.6 1.5zM377.1 72.8l1.6 1.6zM377.1 72.8l1.6-1.5zM377.1 62.7l1.6 1.5zM378.7 61.1l-1.6 1.6zM378.7 69.3h10.6zM378.7 66.2h10.6z"/>
<path d="M378.7 79.4h13.7zM378.7 76.4h13.7zM378.7 74.4h13.3zM378.7 71.3h13.3zM378.7 64.2h15.5zM378.7 61.1h15.5zM389.3 66.2v3.1zM392 71.3v3.1zM392.4 76.4v3zM394.2 61.1v3.1zM125.7 95.7l-1.3 1.9zM125.7 95.7l1.3 1.9z"/>
<path d="M257.8 159.2l-1.3 1.9zM257.8 159.2l1.3 1.9zM377.1 166.8l1.6-1.5zM377.1 166.8l1.6 1.5zM378.7 165.3h7.2zM378.7 168.3h7.2zM385.9 165.3v3zM257.8 192.2l-1.3 1.9zM257.8 192.2l1.3 1.9zM255.9 217.6h3.8zM54.6 243l-1.3 1.9zM54.6 243l1.3 1.9z"/>
<path d="M64.8 243l-1.3 1.9zM64.8 243l1.2 1.9zM313.7 249.3h86.3zM313.7 254.4h86.3zM313.7 259.5h58.4zM372.1 259.5h27.9zM372.1 259.5v5.1zM29.8 265.8h3.9zM62.9 265.8h3.8zM197.5 268.4h3.8zM225.4 268.4h3.8zM253.3 268.4h3.8z"/>
<path d="M313.7 264.6h58.4zM313.7 269.7h86.3zM372.1 264.6h27.9zM400 268.4v1.3z"/>
</g>
<g fill="#000" stroke="#000" stroke-width=".61">
<path d="M20.3 22.1v252.6zM20.3 22.1h379.7zM123.2 105.9h10.1zM82.5 133.8h10.2zM133.3 133.8h10.2zM153.6 133.8h10.2zM176.5 133.8h10.2zM201.9 156.7v10.1zM201.9 179.5v10.2zM265.4 161.7v20.4zM265.4 161.7h15.2zM265.4 182.1h15.2z"/>
<path d="M265.4 194.8v20.2zM280.6 161.7v20.4zM265.4 194.8h15.2zM265.4 215h15.2zM280.6 194.8v20.2zM207 255.7v10.1zM234.9 240.4v10.2zM234.9 255.7v10.1zM262.9 240.4v10.2zM262.9 255.7v10.1zM283.2 244.3v30.4zM313.7 254.4v5.1z"/>
<path d="M313.7 249.3v5.1zM313.7 244.3v5zM313.7 244.3h86.3zM283.2 244.3h30.5zM400 254.4v5.1zM400 249.3v5.1zM400 244.3v5zM400 22.1v222.2zM20.3 274.7h262.9zM283.2 274.7h30.5zM313.7 274.7h86.3zM313.7 269.7v5z"/>
<path d="M313.7 264.6v5.1zM313.7 259.5v5.1zM400 268.4v6.3zM400 264.6v3.8zM400 259.5v5.1z"/>
</g>
<path d="M123.2 105.9a5.1 5.1 0 0 0 5 5 5.1 5.1 0 0 0 5.1-5M82.5 133.8a5.1 5.1 0 0 0 5.1 5.1 5.1 5.1 0 0 0 5.1-5.1M133.3 133.8a5.1 5.1 0 0 0 5.1 5.1 5.1 5.1 0 0 0 5.1-5.1M153.6 133.8a5.1 5.1 0 0 0 5.1 5.1 5.1 5.1 0 0 0 5.1-5.1M176.5 133.8a5.1 5.1 0 0 0 5.1 5.1 5.1 5.1 0 0 0 5.1-5.1M201.9 156.7a5.1 5.1 0 0 1 5.1 5 5.1 5.1 0 0 1-5.1 5.1M201.9 179.5a5.1 5.1 0 0 1 5.1 5.1 5.1 5.1 0 0 1-5.1 5.1M207 255.7a5.1 5.1 0 0 1 5.1 5.1 5.1 5.1 0 0 1-5.1 5M234.9 240.4a5.1 5.1 0 0 1 5.1 5.1 5.1 5.1 0 0 1-5.1 5.1M234.9 255.7a5.1 5.1 0 0 1 5.1 5.1 5.1 5.1 0 0 1-5.1 5M262.9 240.4a5.1 5.1 0 0 1 5 5.1 5.1 5.1 0 0 1-5 5.1M262.9 255.7a5.1 5.1 0 0 1 5 5.1 5.1 5.1 0 0 1-5 5" fill="none" stroke="#000" stroke-width=".61"/>
<g fill="none" stroke="#000" stroke-width=".25">
<circle cx="128.2" cy="111.9" r=".99"/>
<circle cx="181.6" cy="139.9" r=".99"/>
<circle cx="264.4" cy="179.5" r="1"/>
<circle cx="264.4" cy="164.3" r="1"/>
<circle cx="264.4" cy="197.3" r="1"/>
<circle cx="264.4" cy="212.5" r="1"/>
<circle cx="241" cy="260.8" r="1"/>
<circle cx="268.9" cy="260.8" r="1"/>
</g>
<path d="M16.5 18.2v260.3zM16.5 18.2h387.3zM16.5 278.5h387.3zM403.8 18.2v260.3z" fill="#000" stroke="#000" stroke-width=".32"/>
<path d="M372.1 222.7h25.4v10.1h-25.4zM29.7 253.7h4.1v.5h-4.1zM29.7 254.7h4.1v.5h-4.1zM37.3 253.7h4.1v.5h-4.1zM37.3 254.7h4.1v.5h-4.1zM45 253.7h4v.5h-4zM45 254.7h4v.5h-4zM52.6 253.7h4v.5h-4zM52.6 254.7h4v.5h-4zM62.7 254.7h4.1v.5h-4.1zM62.7 253.7h4.1v.5h-4.1z" fill="#000" stroke="#000" stroke-width=".25"/>
<path d="M341.6 222.7v10.1zM341.6 232.8v7.6zM341.6 232.8h55.9zM397.5 222.7v10.1zM341.6 222.7h55.9zM341.6 240.4h55.9zM397.5 232.8v7.6z" fill="#000" stroke="#000" stroke-width=".42"/>
<use href="#words"/>
</svg>
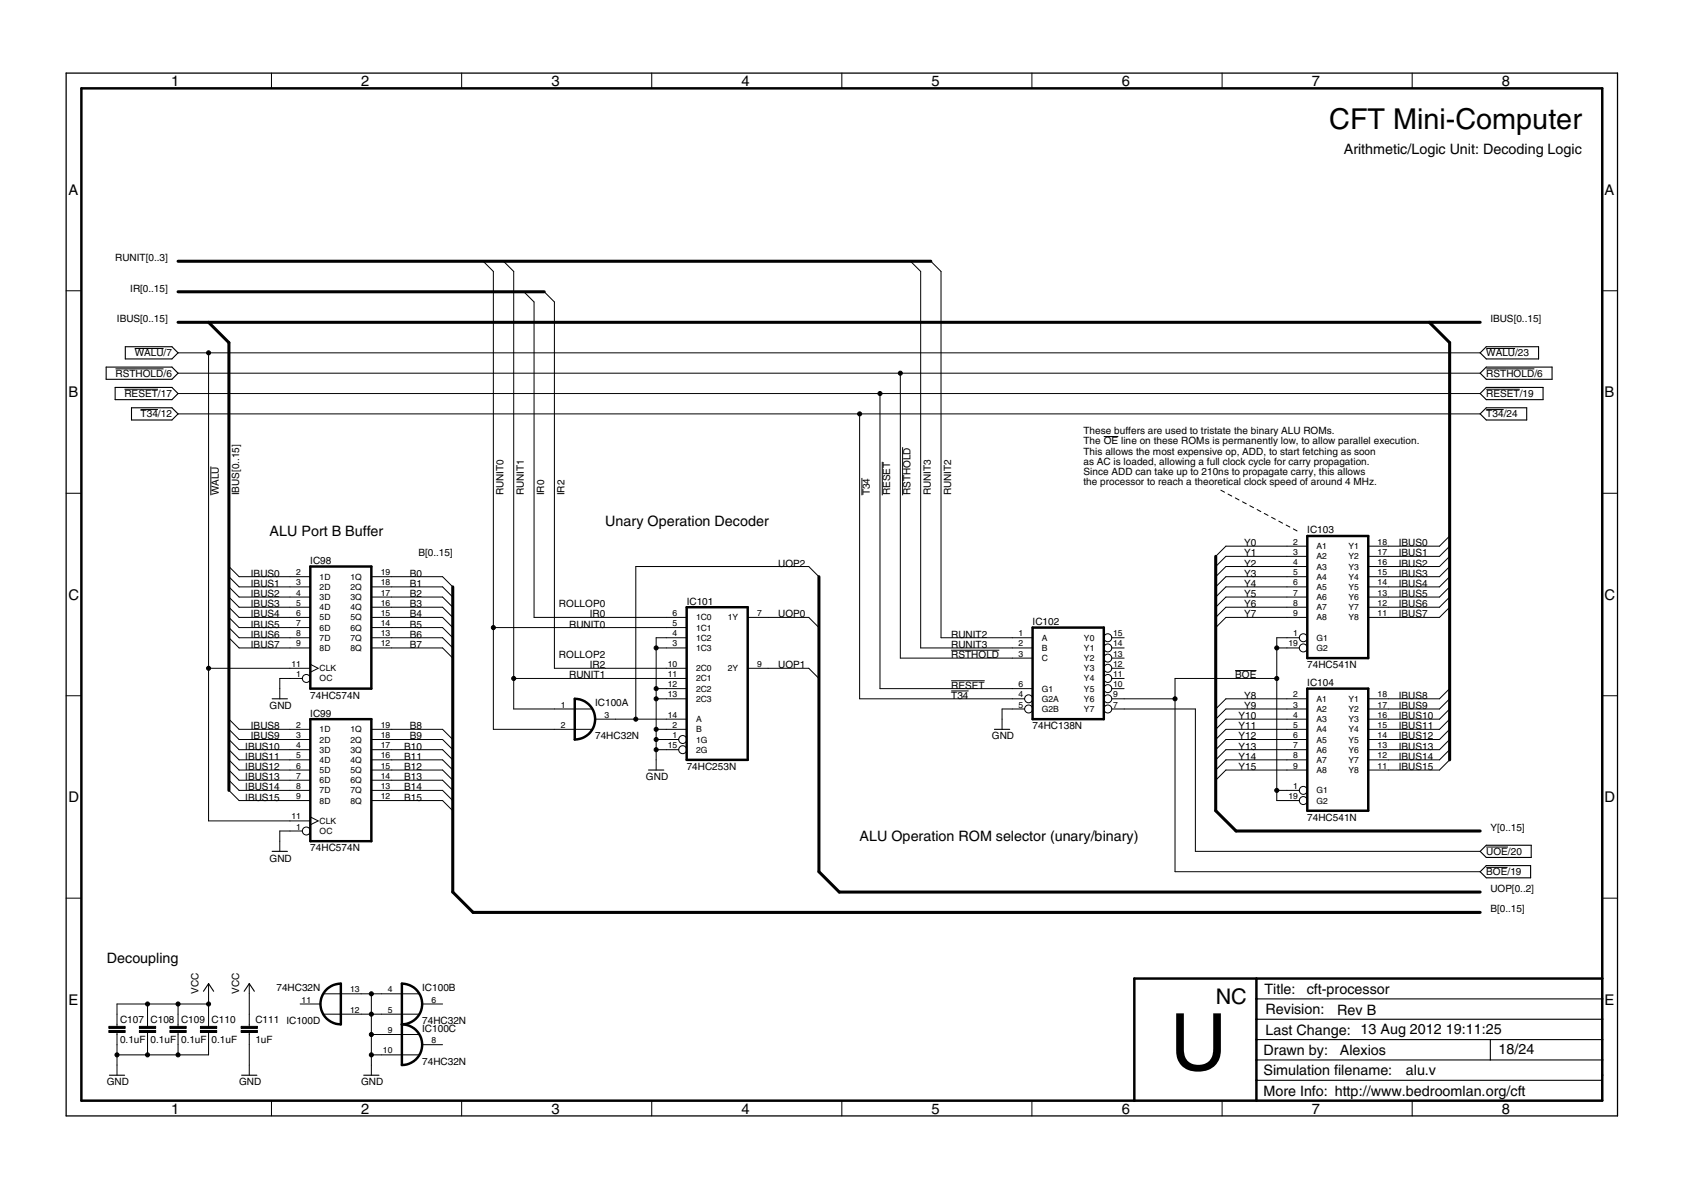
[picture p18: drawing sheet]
<svg xmlns="http://www.w3.org/2000/svg" width="420mm" height="297mm" viewBox="0 0 420 297" stroke-linecap="round" stroke-linejoin="round" font-family="sans-serif">
<defs><g id="words">
<text font-size="19.7" x="292.1" y="267.1">U</text>
<text font-size="7.2" x="331.8" y="32.2">CFT Mini-Computer</text>
<text font-size="5.4" x="303.5" y="250.6">NC</text>
<g font-size="3.7">
<text x="42.7" y="21.5">1</text>
<text x="90.2" y="21.5">2</text>
<text x="137.7" y="21.5">3</text>
<text x="185.1" y="21.5">4</text>
<text x="232.6" y="21.5">5</text>
<text x="280" y="21.5">6</text>
<text x="327.5" y="21.5">7</text>
<text x="375" y="21.5">8</text>
<text x="17.1" y="48.6">A</text>
<text x="400.6" y="48.6">A</text>
<text x="17.1" y="99.2">B</text>
<text x="400.6" y="99.2">B</text>
<text x="17.1" y="149.7">C</text>
<text x="400.6" y="149.7">C</text>
<text x="17.1" y="200.2">D</text>
<text x="400.6" y="200.2">D</text>
<text x="17.1" y="250.8">E</text>
<text x="400.6" y="250.8">E</text>
<text x="42.7" y="277.9">1</text>
<text x="90.2" y="277.9">2</text>
<text x="137.7" y="277.9">3</text>
<text x="185.1" y="277.9">4</text>
<text x="232.6" y="277.9">5</text>
<text x="280" y="277.9">6</text>
<text x="327.5" y="277.9">7</text>
<text x="375" y="277.9">8</text>
</g>
<g font-size="3.6">
<text x="335.5" y="38.6">Arithmetic/Logic Unit: Decoding Logic</text>
<text x="151.1" y="131.3">Unary Operation Decoder</text>
<text x="67.3" y="133.8">ALU Port B Buffer</text>
<text x="214.6" y="210">ALU Operation ROM selector (unary/binary)</text>
<text x="26.7" y="240.5">Decoupling</text>
<text x="315.7" y="248.1">Title:</text>
<text x="326.2" y="248.2">cft-processor</text>
<text x="315.9" y="253.2">Revision:</text>
<text x="333.8" y="253.3">Rev B</text>
<text x="315.4" y="263.3">Drawn by:</text>
<text x="315.9" y="258.2">Last Change: 13 Aug 2012</text>
<text x="334.5" y="263.3">Alexios</text>
<text x="361" y="258.1">19:11:25</text>
<text x="374.1" y="263.2">18/24</text>
<text x="315.4" y="268.4">Simulation filename:</text>
<text x="351" y="268.4">alu.v</text>
<text x="315.4" y="273.5">More Info: http://www.bedroomlan.org/cft</text>
</g>
<g font-size="2.5">
<text x="28.8" y="65.2">RUNIT[0..3]</text>
<text x="32.5" y="72.8">IR[0..15]</text>
<text x="29.2" y="80.5">IBUS[0..15]</text>
<text x="372.1" y="80.5">IBUS[0..15]</text>
<text x="33.6" y="89">WALU/7</text>
<text x="371" y="89">WALU/23</text>
<text x="28.8" y="94">RSTHOLD/6</text>
<text x="371" y="94">RSTHOLD/6</text>
<text x="31.1" y="99.1">RESET/17</text>
<text x="371" y="99.1">RESET/19</text>
<text x="35.1" y="104.2">T34/12</text>
<text x="371" y="104.2">T34/24</text>
<text x="270.5" y="108.4">These buffers are used to tristate the binary ALU ROMs.</text>
<text x="270.5" y="110.9">The OE line on these ROMs is permanently low, to allow parallel execution.</text>
<text x="270.5" y="113.5">This allows the most expensive op, ADD, to start fetching as soon</text>
<text x="270.5" y="118.6">Since ADD can take up to 210ns to propagate carry, this allows</text>
<text x="270.5" y="116">as AC is loaded, allowing a full clock cycle for carry propagation.</text>
<text x="54.6" y="123.6" transform="rotate(-90 54.6 123.6)">WALU</text>
<text x="59.7" y="123.6" transform="rotate(-90 59.7 123.6)">IBUS[0..15]</text>
<text x="125.7" y="123.6" transform="rotate(-90 125.7 123.6)">RUNIT0</text>
<text x="130.8" y="123.6" transform="rotate(-90 130.8 123.6)">RUNIT1</text>
<text x="135.9" y="123.6" transform="rotate(-90 135.9 123.6)">IR0</text>
<text x="141" y="123.6" transform="rotate(-90 141 123.6)">IR2</text>
<text x="217.1" y="123.6" transform="rotate(-90 217.1 123.6)">T34</text>
<text x="222.2" y="123.6" transform="rotate(-90 222.2 123.6)">RESET</text>
<text x="227.3" y="123.6" transform="rotate(-90 227.3 123.6)">RSTHOLD</text>
<text x="232.4" y="123.6" transform="rotate(-90 232.4 123.6)">RUNIT3</text>
<text x="237.5" y="123.6" transform="rotate(-90 237.5 123.6)">RUNIT2</text>
<text x="270.5" y="121.1">the processor to reach a theoretical clock speed of around 4 MHz.</text>
<text x="310.6" y="136.3">Y0</text>
<text x="326.4" y="133.2">IC103</text>
<text x="349.2" y="136.3">IBUS0</text>
<text x="62.6" y="144">IBUS0</text>
<text x="77.5" y="140.8">IC98</text>
<text x="102.3" y="144">B0</text>
<text x="104.4" y="138.9">B[0..15]</text>
<text x="194.3" y="141.4">UOP2</text>
<text x="310.6" y="138.9">Y1</text>
<text x="310.6" y="141.4">Y2</text>
<text x="310.6" y="144">Y3</text>
<text x="349.2" y="138.9">IBUS1</text>
<text x="349.2" y="141.4">IBUS2</text>
<text x="349.2" y="144">IBUS3</text>
<text x="62.6" y="146.5">IBUS1</text>
<text x="62.6" y="149">IBUS2</text>
<text x="102.3" y="146.5">B1</text>
<text x="102.3" y="149">B2</text>
<text x="310.6" y="146.5">Y4</text>
<text x="310.6" y="149">Y5</text>
<text x="349.2" y="146.5">IBUS4</text>
<text x="349.2" y="149">IBUS5</text>
<text x="62.6" y="151.6">IBUS3</text>
<text x="62.6" y="154.1">IBUS4</text>
<text x="102.3" y="151.6">B3</text>
<text x="102.3" y="154.1">B4</text>
<text x="139.5" y="151.6">ROLLOP0</text>
<text x="147.2" y="154.1">IR0</text>
<text x="171.4" y="150.9">IC101</text>
<text x="194.3" y="154.1">UOP0</text>
<text x="310.6" y="151.6">Y6</text>
<text x="310.6" y="154.1">Y7</text>
<text x="349.2" y="151.6">IBUS6</text>
<text x="349.2" y="154.1">IBUS7</text>
<text x="62.6" y="156.6">IBUS5</text>
<text x="62.6" y="159.2">IBUS6</text>
<text x="62.6" y="161.7">IBUS7</text>
<text x="102.3" y="156.6">B5</text>
<text x="102.3" y="159.2">B6</text>
<text x="102.3" y="161.7">B7</text>
<text x="142.1" y="156.6">RUNIT0</text>
<text x="237.5" y="161.7">RUNIT3</text>
<text x="237.5" y="159.2">RUNIT2</text>
<text x="257.8" y="156">IC102</text>
<text x="139.5" y="164.3">ROLLOP2</text>
<text x="147.2" y="166.8">IR2</text>
<text x="194.3" y="166.8">UOP1</text>
<text x="237.5" y="164.3">RSTHOLD</text>
<text x="326.4" y="166.8">74HC541N</text>
<text x="142.1" y="169.3">RUNIT1</text>
<text x="237.5" y="171.9">RESET</text>
<text x="308.3" y="169.3">BOE</text>
<text x="326.4" y="171.3">IC104</text>
<text x="67.3" y="177">GND</text>
<text x="77.5" y="174.4">74HC574N</text>
<text x="77.5" y="178.9">IC99</text>
<text x="148.6" y="176.3">IC100A</text>
<text x="237.5" y="174.4">T34</text>
<text x="309.2" y="179.5">Y10</text>
<text x="310.6" y="174.4">Y8</text>
<text x="310.6" y="177">Y9</text>
<text x="349.2" y="174.4">IBUS8</text>
<text x="349.2" y="177">IBUS9</text>
<text x="349.2" y="179.5">IBUS10</text>
<text x="62.6" y="182">IBUS8</text>
<text x="62.6" y="184.6">IBUS9</text>
<text x="102.3" y="182">B8</text>
<text x="102.3" y="184.6">B9</text>
<text x="148.6" y="184.6">74HC32N</text>
<text x="247.6" y="184.6">GND</text>
<text x="257.8" y="182">74HC138N</text>
<text x="309.2" y="182">Y11</text>
<text x="309.2" y="184.6">Y12</text>
<text x="349.2" y="182">IBUS11</text>
<text x="349.2" y="184.6">IBUS12</text>
<text x="61.2" y="187.1">IBUS10</text>
<text x="61.2" y="189.7">IBUS11</text>
<text x="100.9" y="187.1">B10</text>
<text x="100.9" y="189.7">B11</text>
<text x="309.2" y="187.1">Y13</text>
<text x="309.2" y="189.7">Y14</text>
<text x="349.2" y="187.1">IBUS13</text>
<text x="349.2" y="189.7">IBUS14</text>
<text x="61.2" y="192.2">IBUS12</text>
<text x="61.2" y="194.7">IBUS13</text>
<text x="61.2" y="197.3">IBUS14</text>
<text x="100.9" y="192.2">B12</text>
<text x="100.9" y="194.7">B13</text>
<text x="100.9" y="197.3">B14</text>
<text x="161.3" y="194.7">GND</text>
<text x="171.4" y="192.2">74HC253N</text>
<text x="309.2" y="192.2">Y15</text>
<text x="349.2" y="192.2">IBUS15</text>
<text x="61.2" y="199.8">IBUS15</text>
<text x="100.9" y="199.8">B15</text>
<text x="326.4" y="204.9">74HC541N</text>
<text x="372.1" y="207.4">Y[0..15]</text>
<text x="67.3" y="215.1">GND</text>
<text x="77.5" y="212.5">74HC574N</text>
<text x="371" y="213.4">UOE/20</text>
<text x="371" y="218.5">BOE/19</text>
<text x="372.1" y="227.8">B[0..15]</text>
<text x="372.1" y="222.7">UOP[0..2]</text>
<text x="49.5" y="248.1" transform="rotate(-90 49.5 248.1)">VCC</text>
<text x="59.7" y="248.1" transform="rotate(-90 59.7 248.1)">VCC</text>
<text x="69" y="247.3">74HC32N</text>
<text x="105.4" y="247.4">IC100B</text>
<text x="30" y="255.3">C107</text>
<text x="37.6" y="255.3">C108</text>
<text x="45.2" y="255.3">C109</text>
<text x="52.8" y="255.3">C110</text>
<text x="63.7" y="255.3">C111</text>
<text x="71.5" y="255.6">IC100D</text>
<text x="105.4" y="255.7">74HC32N</text>
<text x="105.4" y="257.6">IC100C</text>
<text x="30" y="260.4">0.1uF</text>
<text x="37.6" y="260.4">0.1uF</text>
<text x="45.2" y="260.4">0.1uF</text>
<text x="52.8" y="260.4">0.1uF</text>
<text x="63.7" y="260.4">1uF</text>
<text x="105.4" y="265.8">74HC32N</text>
<text x="26.7" y="270.9">GND</text>
<text x="59.7" y="270.9">GND</text>
<text x="90.2" y="270.9">GND</text>
</g>
<g font-size="2.1">
<text x="322.8" y="136">2</text>
<text x="328.7" y="137.1">A1</text>
<text x="336.6" y="137.1">Y1</text>
<text x="343.9" y="136">18</text>
<text x="73.9" y="143.6">2</text>
<text x="95" y="143.6">19</text>
<text x="322.8" y="138.5">3</text>
<text x="322.8" y="141.1">4</text>
<text x="322.8" y="143.6">5</text>
<text x="328.7" y="139.6">A2</text>
<text x="328.7" y="142.2">A3</text>
<text x="336.6" y="142.2">Y3</text>
<text x="336.6" y="139.6">Y2</text>
<text x="343.9" y="143.6">15</text>
<text x="343.9" y="141.1">16</text>
<text x="343.9" y="138.5">17</text>
<text x="73.9" y="146.1">3</text>
<text x="73.9" y="148.7">4</text>
<text x="79.8" y="144.7">1D</text>
<text x="79.8" y="147.3">2D</text>
<text x="79.8" y="149.8">3D</text>
<text x="87.5" y="149.8">3Q</text>
<text x="87.5" y="147.3">2Q</text>
<text x="87.5" y="144.7">1Q</text>
<text x="95" y="148.7">17</text>
<text x="95" y="146.1">18</text>
<text x="322.8" y="146.1">6</text>
<text x="322.8" y="148.7">7</text>
<text x="328.7" y="144.7">A4</text>
<text x="328.7" y="147.3">A5</text>
<text x="328.7" y="149.8">A6</text>
<text x="336.6" y="149.8">Y6</text>
<text x="336.6" y="147.3">Y5</text>
<text x="336.6" y="144.7">Y4</text>
<text x="343.9" y="148.7">13</text>
<text x="343.9" y="146.1">14</text>
<text x="73.9" y="151.2">5</text>
<text x="73.9" y="153.8">6</text>
<text x="79.8" y="152.3">4D</text>
<text x="79.8" y="154.9">5D</text>
<text x="87.5" y="154.9">5Q</text>
<text x="87.5" y="152.3">4Q</text>
<text x="95" y="153.8">15</text>
<text x="95" y="151.2">16</text>
<text x="167.9" y="153.8">6</text>
<text x="173.8" y="154.9">1C0</text>
<text x="181.7" y="154.9">1Y</text>
<text x="189" y="153.8">7</text>
<text x="322.8" y="151.2">8</text>
<text x="322.8" y="153.8">9</text>
<text x="328.7" y="152.3">A7</text>
<text x="328.7" y="154.9">A8</text>
<text x="336.6" y="154.9">Y8</text>
<text x="336.6" y="152.3">Y7</text>
<text x="343.9" y="153.8">11</text>
<text x="343.9" y="151.2">12</text>
<text x="73.9" y="156.3">7</text>
<text x="73.9" y="158.8">8</text>
<text x="73.9" y="161.4">9</text>
<text x="79.8" y="157.4">6D</text>
<text x="79.8" y="159.9">7D</text>
<text x="87.5" y="160">7Q</text>
<text x="87.5" y="157.4">6Q</text>
<text x="95" y="161.4">12</text>
<text x="95" y="158.8">13</text>
<text x="95" y="156.3">14</text>
<text x="167.9" y="161.4">3</text>
<text x="167.9" y="158.8">4</text>
<text x="167.9" y="156.3">5</text>
<text x="173.8" y="159.9">1C2</text>
<text x="173.8" y="157.4">1C1</text>
<text x="254.3" y="158.8">1</text>
<text x="254.3" y="161.4">2</text>
<text x="260.1" y="159.9">A</text>
<text x="270.6" y="160">Y0</text>
<text x="277.9" y="161.4">14</text>
<text x="277.9" y="158.8">15</text>
<text x="321.6" y="161.4">19</text>
<text x="322.8" y="158.8">1</text>
<text x="328.7" y="159.9">G1</text>
<text x="72.8" y="166.5">11</text>
<text x="79.8" y="162.5">8D</text>
<text x="79.8" y="167.6">CLK</text>
<text x="87.5" y="162.5">8Q</text>
<text x="166.7" y="166.5">10</text>
<text x="173.8" y="162.5">1C3</text>
<text x="173.8" y="167.6">2C0</text>
<text x="181.7" y="167.6">2Y</text>
<text x="189" y="166.5">9</text>
<text x="254.3" y="163.9">3</text>
<text x="260.1" y="162.5">B</text>
<text x="260.1" y="165">C</text>
<text x="270.6" y="167.6">Y3</text>
<text x="270.6" y="165">Y2</text>
<text x="270.6" y="162.5">Y1</text>
<text x="277.9" y="166.5">12</text>
<text x="277.9" y="163.9">13</text>
<text x="328.7" y="162.5">G2</text>
<text x="73.9" y="169">1</text>
<text x="79.8" y="170.1">OC</text>
<text x="166.7" y="169">11</text>
<text x="166.7" y="171.5">12</text>
<text x="173.8" y="170.1">2C1</text>
<text x="173.8" y="172.6">2C2</text>
<text x="254.3" y="171.5">6</text>
<text x="260.1" y="172.6">G1</text>
<text x="270.6" y="172.6">Y5</text>
<text x="270.6" y="170.1">Y4</text>
<text x="277.9" y="171.5">10</text>
<text x="277.9" y="169">11</text>
<text x="140" y="176.6">1</text>
<text x="150.9" y="179.1">3</text>
<text x="166.7" y="174.1">13</text>
<text x="166.7" y="179.1">14</text>
<text x="173.8" y="175.2">2C3</text>
<text x="254.3" y="174.1">4</text>
<text x="254.3" y="176.6">5</text>
<text x="260.1" y="175.2">G2A</text>
<text x="260.1" y="177.7">G2B</text>
<text x="270.6" y="177.7">Y7</text>
<text x="270.6" y="175.2">Y6</text>
<text x="277.9" y="176.6">7</text>
<text x="277.9" y="174.1">9</text>
<text x="322.8" y="174.1">2</text>
<text x="322.8" y="176.6">3</text>
<text x="322.8" y="179.1">4</text>
<text x="328.7" y="175.2">A1</text>
<text x="328.7" y="177.7">A2</text>
<text x="336.6" y="177.7">Y2</text>
<text x="336.6" y="175.2">Y1</text>
<text x="343.9" y="179.1">16</text>
<text x="343.9" y="176.6">17</text>
<text x="343.9" y="174.1">18</text>
<text x="73.9" y="181.7">2</text>
<text x="73.9" y="184.2">3</text>
<text x="79.8" y="182.8">1D</text>
<text x="79.8" y="185.3">2D</text>
<text x="87.5" y="185.3">2Q</text>
<text x="87.5" y="182.8">1Q</text>
<text x="95" y="184.2">18</text>
<text x="95" y="181.7">19</text>
<text x="140" y="181.7">2</text>
<text x="167.9" y="184.2">1</text>
<text x="167.9" y="181.7">2</text>
<text x="173.8" y="185.3">1G</text>
<text x="173.8" y="182.8">B</text>
<text x="173.8" y="180.3">A</text>
<text x="322.8" y="181.7">5</text>
<text x="322.8" y="184.2">6</text>
<text x="328.7" y="180.3">A3</text>
<text x="328.7" y="182.8">A4</text>
<text x="328.7" y="185.3">A5</text>
<text x="336.6" y="185.3">Y5</text>
<text x="336.6" y="182.8">Y4</text>
<text x="336.6" y="180.3">Y3</text>
<text x="343.9" y="184.2">14</text>
<text x="343.9" y="181.7">15</text>
<text x="73.9" y="186.8">4</text>
<text x="73.9" y="189.3">5</text>
<text x="73.9" y="191.8">6</text>
<text x="79.8" y="187.9">3D</text>
<text x="79.8" y="190.4">4D</text>
<text x="87.5" y="190.4">4Q</text>
<text x="87.5" y="187.9">3Q</text>
<text x="95" y="191.8">15</text>
<text x="95" y="189.3">16</text>
<text x="95" y="186.8">17</text>
<text x="166.7" y="186.8">15</text>
<text x="173.8" y="187.9">2G</text>
<text x="322.8" y="186.8">7</text>
<text x="322.8" y="189.3">8</text>
<text x="322.8" y="191.8">9</text>
<text x="328.7" y="187.9">A6</text>
<text x="328.7" y="190.4">A7</text>
<text x="336.6" y="190.4">Y7</text>
<text x="336.6" y="187.9">Y6</text>
<text x="343.9" y="191.8">11</text>
<text x="343.9" y="189.3">12</text>
<text x="343.9" y="186.8">13</text>
<text x="73.9" y="194.4">7</text>
<text x="73.9" y="196.9">8</text>
<text x="79.8" y="193">5D</text>
<text x="79.8" y="195.5">6D</text>
<text x="87.5" y="195.5">6Q</text>
<text x="87.5" y="193">5Q</text>
<text x="95" y="196.9">13</text>
<text x="95" y="194.4">14</text>
<text x="322.8" y="196.9">1</text>
<text x="328.7" y="193">A8</text>
<text x="336.6" y="193">Y8</text>
<text x="73.9" y="199.5">9</text>
<text x="79.8" y="198">7D</text>
<text x="79.8" y="200.6">8D</text>
<text x="87.5" y="200.6">8Q</text>
<text x="87.5" y="198">7Q</text>
<text x="95" y="199.5">12</text>
<text x="321.6" y="199.5">19</text>
<text x="328.7" y="198">G1</text>
<text x="328.7" y="200.6">G2</text>
<text x="72.8" y="204.5">11</text>
<text x="73.9" y="207.1">1</text>
<text x="79.8" y="208.2">OC</text>
<text x="79.8" y="205.7">CLK</text>
<text x="75.3" y="250.3">11</text>
<text x="87.4" y="247.7">13</text>
<text x="96.8" y="247.7">4</text>
<text x="107.7" y="250.3">6</text>
<text x="87.4" y="252.8">12</text>
<text x="96.8" y="252.8">5</text>
<text x="96.8" y="257.9">9</text>
<text x="95.6" y="263">10</text>
<text x="107.7" y="260.4">8</text>
</g>
</g></defs>
<g fill="#000" stroke="#000" stroke-width=".25">
<path d="M67.8 18.2v3.9zM115.3 18.2v3.9zM162.7 18.2v3.9zM210.2 18.2v3.9zM257.6 18.2v3.9zM305.1 18.2v3.9zM352.5 18.2v3.9zM20.3 22.1v252.6zM20.3 22.1h379.7zM16.5 72.6h3.8zM120.6 65.2l2.6 2.6zM123.2 67.8v88.9z"/>
<path d="M125.7 65.2l2.5 2.6zM128.2 67.8v101.6zM130.8 72.8l2.5 2.6zM133.3 75.4v78.7zM135.9 72.8l2.5 2.6zM138.4 75.4v91.4zM227.3 65.2l2.5 2.6zM229.8 67.8v93.9zM232.4 65.2l2.5 2.6zM400 72.6h3.8zM28.8 92.1h12zM31.1 97.2h8.3z"/>
<path d="M33.6 87h7.2zM44.4 93.2h180.4zM44.4 88.1h7.7zM52.1 88.1h317.4zM44.4 98.2h175.3zM219.7 98.2h149.8zM224.8 93.2h144.7zM371 97.2h8.4zM371 92.1h12zM371 87h7.2zM35.1 102.2h4.3zM44.4 103.3h170.2z"/>
<path d="M214.6 103.3h154.9zM275.5 109h3.7zM371 102.2h4.4zM16.5 123.1h3.8zM52.6 116.4v7.2zM215.2 119.3v4.3zM220.3 115.3v8.3zM225.3 111.6v12zM304.8 122.4l.9 .4zM303.5 138.9l2.5-2.6zM306 138.9l-2.5 2.5zM306.6 123.3l.9 .5z"/>
<path d="M308.4 124.3l.9 .5zM310.2 125.3l.9 .4zM312 126.2l.9 .5zM313.8 127.2l1 .5zM315.6 128.2l1 .4zM317.5 129.1l.9 .5zM319.3 130.1l.9 .5zM321.1 131.1l.9 .4zM321.3 136.3h5.1zM321.3 138.9h5.1zM306 136.3h15.3zM306 138.9h15.3z"/>
<path d="M322.9 132l.9 .5zM341.6 138.9h5.1zM341.6 136.3h5.1zM346.7 136.3h12.7zM346.7 138.9h12.7zM361.9 133.8l-2.5 2.5zM359.4 138.9l2.5-2.6zM361.9 138.9l-2.5 2.5zM400 123.1h3.8zM57.1 141.4l2.6 2.6zM57.1 144l2.6 2.5zM57.1 146.5l2.6 2.5z"/>
<path d="M57.1 149l2.6 2.6zM57.1 151.6l2.6 2.5zM57.1 154.1l2.6 2.6zM57.1 156.7l2.6 2.5zM57.1 159.2l2.6 2.5zM59.7 144h12.7zM59.7 146.5h12.7zM59.7 149h12.7zM59.7 151.6h12.7zM59.7 154.1h12.7zM59.7 156.7h12.7zM59.7 159.2h12.7z"/>
<path d="M72.4 144h5.1zM72.4 146.5h5.1zM72.4 149h5.1zM72.4 151.6h5.1zM72.4 154.1h5.1zM72.4 156.7h5.1zM72.4 159.2h5.1zM92.7 159.2h5.1zM92.7 156.7h5.1zM92.7 154.1h5.1zM92.7 151.6h5.1zM92.7 149h5.1z"/>
<path d="M92.7 146.5h5.1zM92.7 144h5.1zM97.8 144h12.7zM97.8 146.5h12.7zM97.8 149h12.7zM97.8 151.6h12.7zM97.8 154.1h12.7zM97.8 156.7h12.7zM97.8 159.2h12.7zM110.5 144l2.5 2.5zM110.5 146.5l2.5 2.5zM110.5 149l2.5 2.6z"/>
<path d="M110.5 151.6l2.5 2.5zM110.5 154.1l2.5 2.6zM110.5 156.7l2.5 2.5zM110.5 159.2l2.5 2.5zM123.2 156.7h43.1zM158.7 141.4v38.1zM163.8 159.2v2.5zM166.3 159.2h5.1zM166.3 156.7h5.1zM166.3 154.1h5.1zM163.8 159.2h2.5zM133.3 154.1h33z"/>
<path d="M186.7 154.1h5zM191.7 154.1h10.2zM201.9 154.1l2.5 2.6zM158.7 141.4h43.2zM201.9 141.4l2.5 2.6zM234.9 67.8v91.4zM252.7 159.2h5.1zM234.9 159.2h17.8zM277.5 159.2h3.1zM306 141.4l-2.5 2.6zM303.5 146.5l2.5-2.5zM306 146.5l-2.5 2.5z"/>
<path d="M306 149l-2.5 2.6zM303.5 154.1l2.5-2.5zM306 154.1l-2.5 2.6zM318.7 159.2h2.6zM318.7 159.2v2.5zM321.3 159.2h3.1zM321.3 141.4h5.1zM321.3 144h5.1zM321.3 146.5h5.1zM321.3 149h5.1zM321.3 151.6h5.1zM321.3 154.1h5.1z"/>
<path d="M306 141.4h15.3zM306 144h15.3zM306 146.5h15.3zM306 149h15.3zM306 151.6h15.3zM306 154.1h15.3zM341.6 154.1h5.1zM341.6 151.6h5.1zM341.6 149h5.1zM341.6 146.5h5.1zM341.6 144h5.1zM341.6 141.4h5.1z"/>
<path d="M346.7 141.4h12.7zM346.7 144h12.7zM346.7 146.5h12.7zM346.7 149h12.7zM346.7 151.6h12.7zM346.7 154.1h12.7zM361.9 141.4l-2.5 2.6zM359.4 146.5l2.5-2.5zM361.9 146.5l-2.5 2.5zM361.9 149l-2.5 2.6zM361.9 151.6l-2.5 2.5zM16.5 173.7h3.8z"/>
<path d="M52.1 166.8v38.1zM52.1 88.1v78.7zM57.1 179.5l2.6 2.6zM59.7 161.7h12.7zM69.8 171.9v2.5zM69.8 169.4v2.5zM72.4 169.4h3.1zM72.4 161.7h5.1zM72.4 166.8h5.1zM69.8 169.4h2.6zM52.1 166.8h20.3zM77.5 165.8l1.9 1z"/>
<path d="M77.5 167.8l1.9-1zM92.7 161.7h5.1zM97.8 161.7h12.7zM110.5 161.7l2.5 2.6zM128.2 169.4v7.6zM138.4 177h5.1zM128.2 177h10.2zM138.4 166.8h12.7zM143.5 177h4.3zM148.6 179.5h5zM153.6 179.5h5.1zM158.7 179.5h7.6z"/>
<path d="M163.8 161.7v10.2zM163.8 171.9v2.5zM163.8 174.4v7.7zM166.3 161.7h5.1zM166.3 166.8h5.1zM166.3 169.4h5.1zM166.3 171.9h5.1zM166.3 174.4h5.1zM166.3 179.5h5.1zM163.8 161.7h2.5zM163.8 171.9h2.5zM163.8 174.4h2.5z"/>
<path d="M128.2 169.4h38.1zM151.1 166.8h15.2zM186.7 166.8h5zM191.7 166.8h10.2zM201.9 166.8l2.5 2.6zM214.6 103.3v71.1zM214.6 174.4h38.1zM219.7 98.2v73.7zM224.8 93.2v71.1zM237.5 169.9h8.3zM237.5 162.3h12zM237.5 172.5h4.3z"/>
<path d="M250.2 179.5v2.6zM250.2 177v2.5zM252.7 161.7h5.1zM252.7 164.3h5.1zM252.7 174.4h3.1zM252.7 177h3.1zM252.7 171.9h5.1zM250.2 177h2.5zM219.7 171.9h33zM224.8 164.3h27.9zM229.8 161.7h22.9zM277.5 177h3.1z"/>
<path d="M277.5 174.4h3.1zM277.5 171.9h3.1zM277.5 169.4h3.1zM277.5 166.8h3.1zM277.5 164.3h3.1zM277.5 161.7h3.1zM280.6 177h17.8zM280.6 174.4h12.7zM293.3 169.4v5zM293.3 169.4h25.4zM293.3 174.4v43.2zM298.4 177v35.5z"/>
<path d="M303.5 177l2.5-2.6zM303.5 179.5l2.5-2.5zM306 179.5l-2.5 2.6zM308.4 167.4h5.3zM318.7 161.7v7.7zM318.7 169.4v27.9zM321.3 161.7h3.1zM321.3 174.4h5.1zM321.3 177h5.1zM321.3 179.5h5.1zM318.7 161.7h2.6zM306 174.4h15.3z"/>
<path d="M306 177h15.3zM306 179.5h15.3zM341.6 179.5h5.1zM341.6 177h5.1zM341.6 174.4h5.1zM346.7 174.4h12.7zM346.7 177h12.7zM346.7 179.5h12.7zM361.9 171.9l-2.5 2.5zM361.9 174.4l-2.5 2.6zM361.9 177l-2.5 2.5zM361.9 179.5l-2.5 2.6z"/>
<path d="M400 173.7h3.8zM57.1 182.1l2.6 2.5zM57.1 184.6l2.6 2.5zM57.1 187.1l2.6 2.6zM57.1 189.7l2.6 2.5zM57.1 192.2l2.6 2.6zM57.1 194.8l2.6 2.5zM57.1 197.3l2.6 2.5zM59.7 182.1h12.7zM59.7 184.6h12.7zM59.7 187.1h12.7zM59.7 189.7h12.7z"/>
<path d="M59.7 192.2h12.7zM59.7 194.8h12.7zM59.7 197.3h12.7zM59.7 199.8h12.7zM72.4 182.1h5.1zM72.4 184.6h5.1zM72.4 187.1h5.1zM72.4 189.7h5.1zM72.4 192.2h5.1zM72.4 194.8h5.1zM72.4 197.3h5.1zM72.4 199.8h5.1z"/>
<path d="M92.7 199.8h5.1zM92.7 197.3h5.1zM92.7 194.8h5.1zM92.7 192.2h5.1zM92.7 189.7h5.1zM92.7 187.1h5.1zM92.7 184.6h5.1zM92.7 182.1h5.1zM97.8 182.1h12.7zM97.8 184.6h12.7zM97.8 187.1h12.7zM97.8 189.7h12.7z"/>
<path d="M97.8 192.2h12.7zM97.8 194.8h12.7zM97.8 197.3h12.7zM97.8 199.8h12.7zM110.5 182.1l2.5 2.5zM110.5 184.6l2.5 2.5zM110.5 187.1l2.5 2.6zM110.5 189.7l2.5 2.5zM110.5 192.2l2.5 2.6zM110.5 194.8l2.5 2.5zM110.5 197.3l2.5 2.5zM110.5 199.8l2.5 2.6z"/>
<path d="M123.2 156.7v25.4zM138.4 182.1h5.1zM123.2 182.1h15.2zM143.5 182.1h4.3zM163.8 189.7v2.5zM163.8 182.1v2.5zM163.8 184.6v2.5zM163.8 187.1v2.6zM166.3 184.6h3.2zM166.3 182.1h5.1zM166.3 187.1h3.2zM163.8 182.1h2.5z"/>
<path d="M163.8 184.6h2.5zM163.8 187.1h2.5zM303.5 184.6l2.5-2.5zM303.5 187.1l2.5-2.5zM306 187.1l-2.5 2.6zM303.5 192.2l2.5-2.5zM303.5 194.8l2.5-2.6zM318.7 197.3v2.5zM318.7 199.8h2.6zM321.3 197.3h3.1zM321.3 182.1h5.1zM321.3 184.6h5.1z"/>
<path d="M321.3 187.1h5.1zM321.3 189.7h5.1zM321.3 192.2h5.1zM321.3 199.8h3.1zM318.7 197.3h2.6zM306 182.1h15.3zM306 184.6h15.3zM306 187.1h15.3zM306 189.7h15.3zM306 192.2h15.3zM341.6 192.2h5.1zM341.6 189.7h5.1z"/>
<path d="M341.6 187.1h5.1zM341.6 184.6h5.1zM341.6 182.1h5.1zM346.7 182.1h12.7zM346.7 184.6h12.7zM346.7 187.1h12.7zM346.7 189.7h12.7zM346.7 192.2h12.7zM361.9 182.1l-2.5 2.5zM361.9 184.6l-2.5 2.5zM361.9 187.1l-2.5 2.6zM361.9 189.7l-2.5 2.5z"/>
<path d="M69.8 210v2.5zM69.8 207.4v2.6zM72.4 207.4h3.1zM72.4 204.9h5.1zM69.8 207.4h2.6zM52.1 204.9h20.3zM77.5 203.9l1.9 1zM77.5 205.9l1.9-1zM293.3 217.6h76.2zM298.4 212.5h71.1zM371 211.4h5.5zM371 216.5h5.4z"/>
<path d="M16.5 224.2h3.8zM400 224.2h3.8zM29.2 253.1v2.6zM29.2 257.7v.5zM29.2 255.7v.5zM29.2 250.6v2.5zM36.8 253.1v2.6zM36.8 257.7v.5zM36.8 255.7v.5zM36.8 250.6v2.5zM29.2 250.6h7.6zM44.4 253.1v2.6z"/>
<path d="M44.4 257.7v.5zM44.4 255.7v.5zM36.8 250.6h7.6zM44.4 250.6v2.5zM52.1 245.5v2.6zM52.1 253.1v2.6zM52.1 257.7v.5zM52.1 255.7v.5zM44.4 250.6h7.7zM52.1 248.1v2.5zM52.1 250.6v2.5zM62.2 245.5v2.6z"/>
<path d="M62.2 253.1v2.6zM62.2 255.7v.5zM62.2 257.7v.5zM62.2 248.1v5zM74.9 250.6h5.1zM80.8 253.1h4.3zM80.8 248.1h4.3zM85.1 253.1h5.1zM85.1 248.1h5.1zM90.2 248.1h2.5zM90.2 253.1h2.5zM92.7 248.1h2.5z"/>
<path d="M92.7 248.1v5zM92.7 253.1v5.1zM92.7 258.2v5.1zM95.2 248.1h5.1zM95.2 253.1h5.1zM95.2 258.2h5.1zM92.7 258.2h2.5zM92.7 253.1h2.5zM100.3 248.1h4.3zM100.3 253.1h4.3zM100.3 258.2h4.3zM105.4 250.6h5.1z"/>
<path d="M20.3 274.7h379.7zM29.2 265.8v2.6zM29.2 258.2v2.6zM29.2 260.8v2.5zM29.2 263.3h7.6zM29.2 263.3v2.5zM36.8 258.2v2.6zM36.8 260.8v2.5zM44.4 258.2v2.6zM36.8 263.3h7.6zM44.4 260.8v2.5zM52.1 258.2v2.6z"/>
<path d="M44.4 263.3h7.7zM52.1 260.8v2.5zM62.2 265.8v2.6zM62.2 258.2v2.6zM62.2 260.8v5zM67.8 274.7v3.8zM92.7 265.8v2.6zM92.7 263.3v2.5zM95.2 263.3h5.1zM92.7 263.3h2.5zM100.3 263.3h4.3zM105.4 260.8h5.1z"/>
<path d="M115.3 274.7v3.8zM162.7 274.7v3.8zM210.2 274.7v3.8zM257.6 274.7v3.8zM305.1 274.7v3.8zM352.5 274.7v3.8zM400 264.5v.1zM400 268.4v6.2zM400 274.6h.1zM400 22.1v252.6z"/>
<circle cx="52.1" cy="88.1" r=".51"/>
<circle cx="219.7" cy="98.2" r=".51"/>
<circle cx="224.8" cy="93.2" r=".51"/>
<circle cx="214.6" cy="103.3" r=".51"/>
<circle cx="123.2" cy="156.7" r=".51"/>
<circle cx="52.1" cy="166.8" r=".51"/>
<circle cx="128.2" cy="169.4" r=".51"/>
<circle cx="158.7" cy="179.5" r=".51"/>
<circle cx="163.8" cy="174.4" r=".51"/>
<circle cx="163.8" cy="171.9" r=".51"/>
<circle cx="163.8" cy="161.7" r=".51"/>
<circle cx="293.3" cy="174.4" r=".51"/>
<circle cx="318.7" cy="161.7" r=".51"/>
<circle cx="318.7" cy="169.4" r=".51"/>
<circle cx="163.8" cy="184.6" r=".51"/>
<circle cx="163.8" cy="182.1" r=".51"/>
<circle cx="163.8" cy="187.1" r=".51"/>
<circle cx="318.7" cy="197.3" r=".51"/>
<circle cx="36.8" cy="250.6" r=".51"/>
<circle cx="44.4" cy="250.6" r=".51"/>
<circle cx="52.1" cy="250.6" r=".51"/>
<circle cx="92.7" cy="258.2" r=".51"/>
<circle cx="92.7" cy="248.1" r=".51"/>
<circle cx="92.7" cy="253.1" r=".51"/>
<circle cx="29.2" cy="263.3" r=".51"/>
<circle cx="36.8" cy="263.3" r=".51"/>
<circle cx="44.4" cy="263.3" r=".51"/>
<circle cx="92.7" cy="263.3" r=".51"/>
</g>
<g fill="#000" stroke="#000" stroke-width=".28">
<path d="M26.5 91.6v3.1zM28.7 96.7v3.1zM31.3 86.5v3.1zM28.7 99.8h14.2zM28.7 96.7h14.2zM26.5 91.6h16.4zM26.5 94.7h16.4zM31.3 86.5h11.6zM31.3 89.6h11.6zM44.4 98.2l-1.5 1.6zM42.9 96.7l1.5 1.5zM42.9 91.6l1.5 1.6z"/>
<path d="M42.9 94.7l1.5-1.5zM42.9 86.5l1.5 1.6zM44.4 88.1l-1.5 1.5zM371 96.7l-1.5 1.5zM369.5 98.2l1.5 1.6zM371 91.6l-1.5 1.6zM369.5 93.2l1.5 1.5zM369.5 88.1l1.5-1.6zM369.5 88.1l1.5 1.5zM371 96.7h14.2zM371 99.8h14.2zM371 91.6h16.5z"/>
<path d="M371 94.7h16.5zM371 86.5h13.1zM371 89.6h13.1zM384.1 86.5v3.1zM385.2 96.7v3.1zM387.5 91.6v3.1zM32.8 101.8v3zM32.8 104.8h10.1zM32.8 101.8h10.1zM44.4 103.3l-1.5 1.5zM42.9 101.8l1.5 1.5zM369.5 103.3l1.5-1.5z"/>
<path d="M369.5 103.3l1.5 1.5zM371 101.8h10.1zM371 104.8h10.1zM381.1 101.8v3zM67.9 174.4h3.9zM161.9 192.2h3.8zM248.3 182.1h3.8zM67.9 212.5h3.9zM369.5 212.5l1.5-1.5zM369.5 212.5l1.5 1.5zM371 216.1l-1.5 1.5zM369.5 217.6l1.5 1.5z"/>
<path d="M371 211h11.3zM371 214h11.3zM371 216.1h11.1zM371 219.1h11.1zM382.1 216.1v3zM382.3 211v3zM52.1 245.5l-1.3 1.9zM52.1 245.5l1.2 1.9zM62.2 245.5l-1.2 1.9zM62.2 245.5l1.3 1.9zM313.7 249.3h86.3zM313.7 254.4h86.3z"/>
<path d="M313.7 259.5h58.4zM372.1 259.5h27.9zM372.1 259.5v5.1zM27.3 268.4h3.8zM60.3 268.4h3.8zM90.8 268.4h3.8zM313.7 264.6h58.4zM313.7 269.7h86.3zM372.1 264.6h27.9zM400 268.4v1.3z"/>
</g>
<path d="M16.5 18.2v260.3zM16.5 18.2h387.3zM16.5 278.5h387.3zM403.8 18.2v260.3z" fill="#000" stroke="#000" stroke-width=".32"/>
<g fill="#000" stroke="#000" stroke-width=".61">
<path d="M20.3 22.1v252.6zM20.3 22.1h379.7zM326.4 133.8v30.5zM326.4 133.8h15.2zM77.5 141.4v30.5zM77.5 141.4h15.2zM171.4 151.6v38.1zM171.4 151.6h15.3zM257.8 156.7v22.8zM257.8 156.7h17.8zM77.5 171.9h15.2zM77.5 179.5v30.5z"/>
<path d="M92.7 141.4v30.5zM77.5 179.5h15.2zM143.5 174.4v10.2zM257.8 179.5h17.8zM275.6 156.7v22.8zM326.4 164.3h15.2zM326.4 171.9v30.5zM341.6 133.8v30.5zM326.4 171.9h15.2zM171.4 189.7h15.3zM186.7 151.6v38.1zM77.5 210h15.2z"/>
<path d="M92.7 179.5v30.5zM326.4 202.4h15.2zM341.6 171.9v30.5zM85.1 245.5v10.2zM100.3 245.5v10.2zM100.3 255.7v10.1zM283.2 244.3v30.4zM313.7 254.4v5.1zM313.7 249.3v5.1zM313.7 244.3v5zM313.7 244.3h86.3zM283.2 244.3h30.5z"/>
<path d="M400 254.4v5.1zM400 249.3v5.1zM400 244.3v5zM400 22.1v222.2zM20.3 274.7h262.9zM283.2 274.7h30.5zM313.7 274.7h86.3zM313.7 269.7v5zM313.7 264.6v5.1zM313.7 259.5v5.1zM400 268.4v6.3zM400 264.6v3.8z"/>
<path d="M400 259.5v5.1z"/>
</g>
<g fill="none" stroke="#000" stroke-width=".25">
<circle cx="276.6" cy="159.2" r="1"/>
<circle cx="325.4" cy="159.2" r="1"/>
<circle cx="76.5" cy="169.4" r=".99"/>
<circle cx="256.8" cy="177" r="1"/>
<circle cx="256.8" cy="174.4" r="1"/>
<circle cx="276.6" cy="177" r="1"/>
<circle cx="276.6" cy="161.7" r="1"/>
<circle cx="276.6" cy="174.4" r="1"/>
<circle cx="276.6" cy="166.8" r="1"/>
<circle cx="276.6" cy="164.3" r="1"/>
<circle cx="276.6" cy="169.4" r="1"/>
<circle cx="276.6" cy="171.9" r="1"/>
<circle cx="325.4" cy="161.7" r="1"/>
<circle cx="170.4" cy="184.6" r=".99"/>
<circle cx="170.4" cy="187.1" r=".99"/>
<circle cx="325.4" cy="197.3" r="1"/>
<circle cx="325.4" cy="199.8" r="1"/>
<circle cx="76.5" cy="207.4" r=".99"/>
</g>
<path d="M143.5 174.4a5.1 5.1 0 0 1 5.1 5.1 5.1 5.1 0 0 1-5.1 5.1M85.1 245.5a5.1 5.1 0 0 0-5.1 5.1 5.1 5.1 0 0 0 5.1 5.1M100.3 245.5a5.1 5.1 0 0 1 5.1 5.1 5.1 5.1 0 0 1-5.1 5.1 5.1 5.1 0 0 1 5.1 5.1 5.1 5.1 0 0 1-5.1 5" fill="none" stroke="#000" stroke-width=".61"/>
<path d="M27.2 256.2h4v.5h-4zM27.2 257.2h4v.5h-4zM34.8 256.2h4.1v.5h-4.1zM34.8 257.2h4.1v.5h-4.1zM42.4 256.2h4.1v.5h-4.1zM42.4 257.2h4.1v.5h-4.1zM50 256.2h4.1v.5h-4.1zM50 257.2h4.1v.5h-4.1zM60.2 257.2h4.1v.5h-4.1zM60.2 256.2h4.1v.5h-4.1z" fill="#000" stroke="#000" stroke-width=".25"/>
<g fill="#000" stroke="#000" stroke-width=".76">
<path d="M44.4 72.8h91.5zM44.4 65.2h188zM52.1 80.5l5 5zM356.8 80.5l5.1 5zM44.4 80.5h325.1zM113 146.5v76.2zM57.1 85.5v111.8zM361.9 85.5v104.2zM204.4 144v73.6zM303.5 138.9v63.5zM303.5 202.4l5.1 5zM308.6 207.4h60.9z"/>
<path d="M113 222.7l5.1 5zM118.1 227.7h251.4zM204.4 217.6l5.1 5.1zM209.5 222.7h160z"/>
</g>
<use href="#words"/>
</svg>
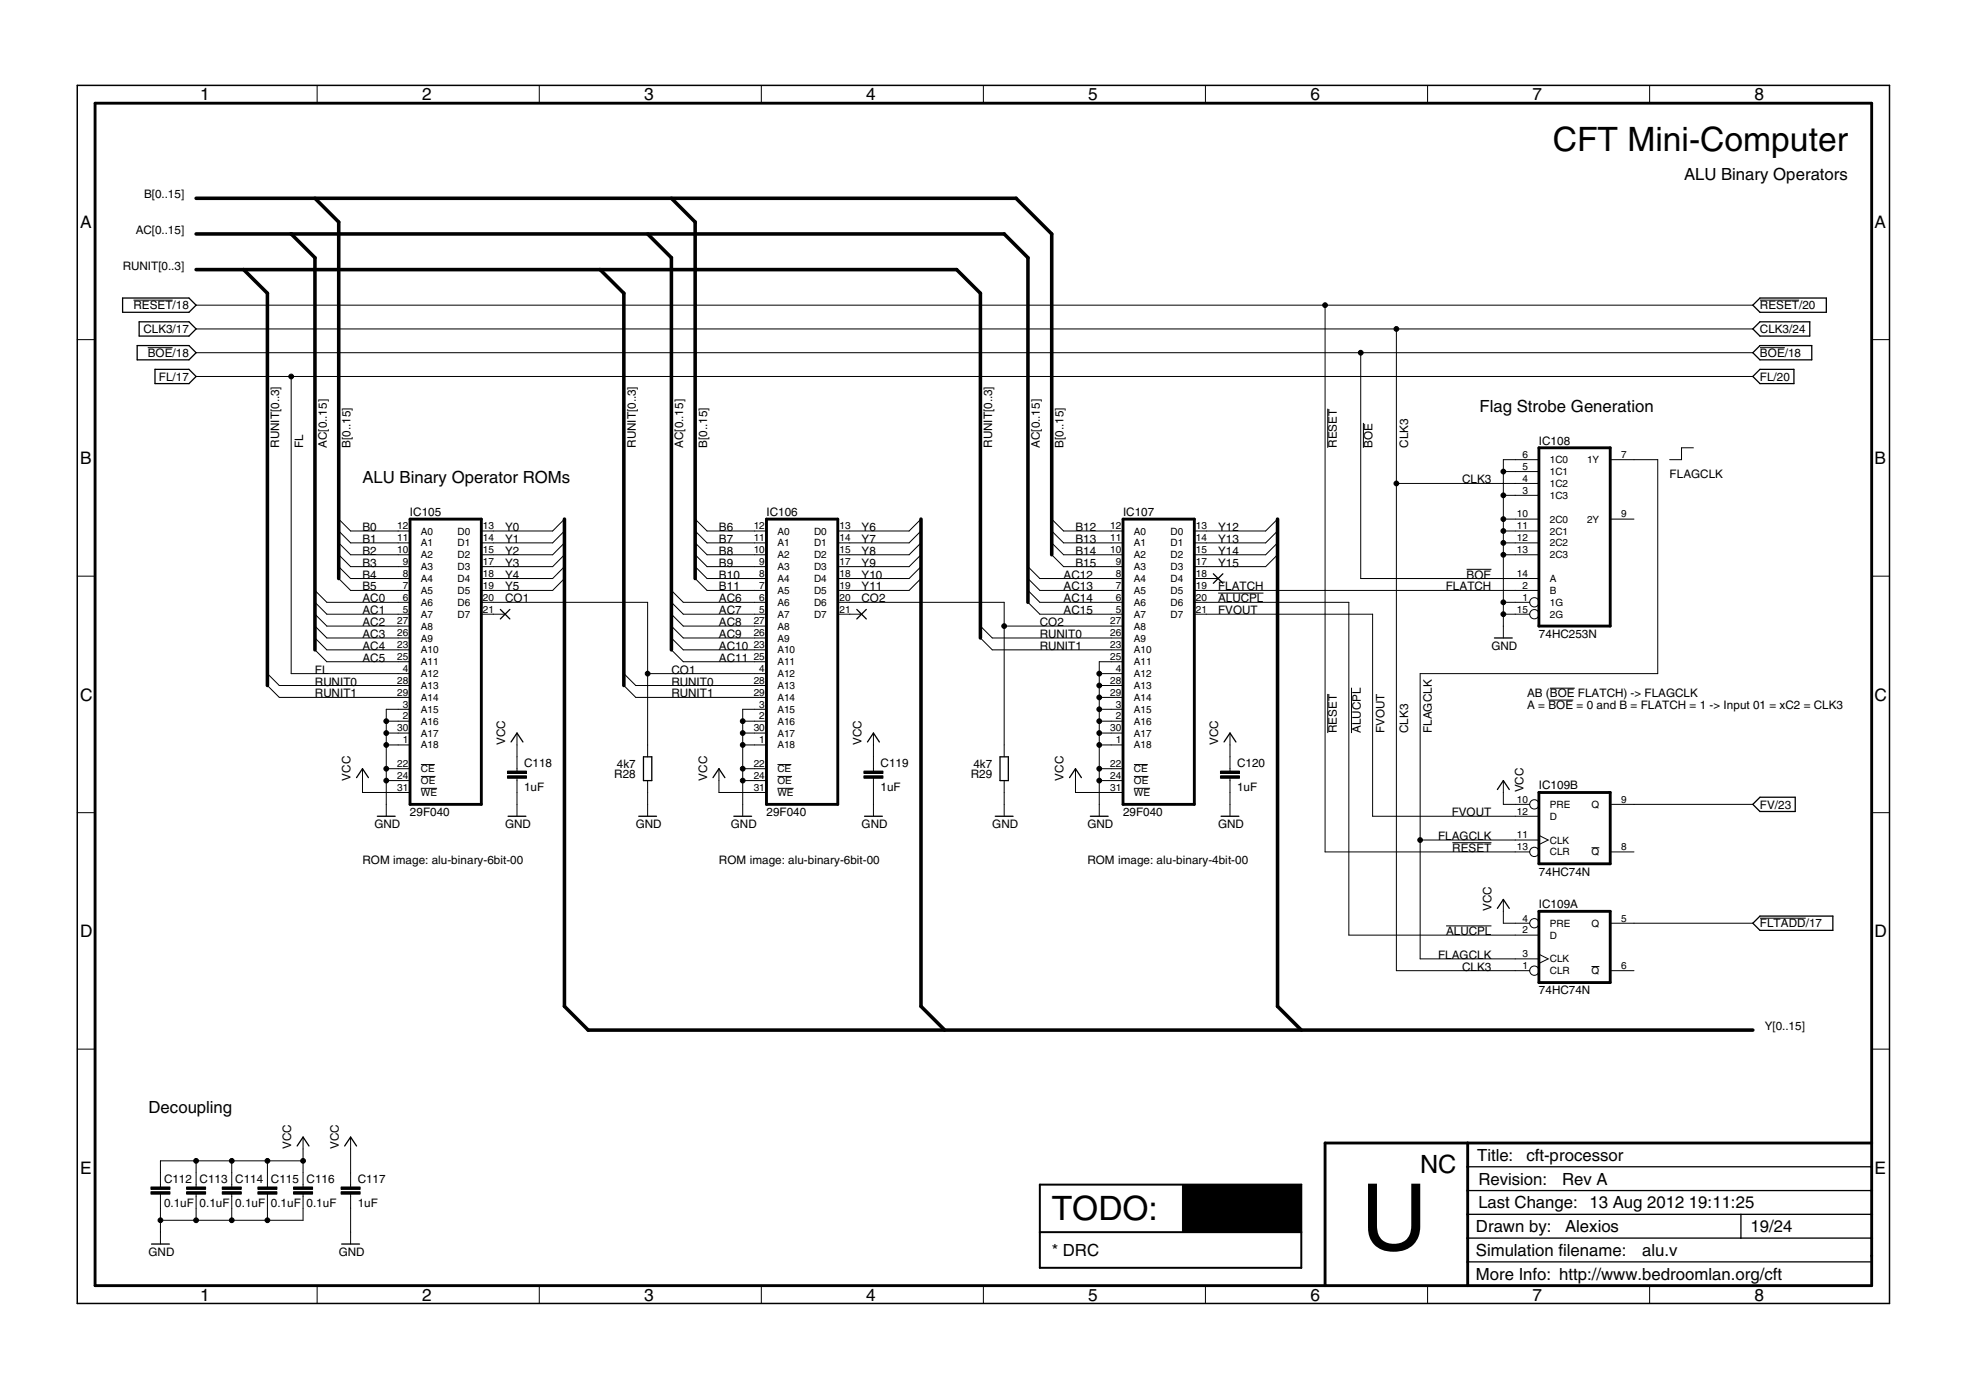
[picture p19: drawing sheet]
<svg xmlns="http://www.w3.org/2000/svg" width="420mm" height="297mm" viewBox="0 0 420 297" stroke-linecap="round" stroke-linejoin="round" font-family="sans-serif">
<defs><g id="words">
<text font-size="19.7" x="290.8" y="267.1">U</text>
<g font-size="7.2">
<text x="331.8" y="32.2">CFT Mini-Computer</text>
<text x="224.8" y="260.8">TODO:</text>
</g>
<text font-size="5.4" x="303.5" y="250.6">NC</text>
<g font-size="3.7">
<text x="42.7" y="21.5">1</text>
<text x="90.2" y="21.5">2</text>
<text x="137.7" y="21.5">3</text>
<text x="185.1" y="21.5">4</text>
<text x="232.6" y="21.5">5</text>
<text x="280" y="21.5">6</text>
<text x="327.5" y="21.5">7</text>
<text x="375" y="21.5">8</text>
<text x="17.1" y="48.6">A</text>
<text x="400.6" y="48.6">A</text>
<text x="17.1" y="99.2">B</text>
<text x="400.6" y="99.2">B</text>
<text x="17.1" y="149.7">C</text>
<text x="400.6" y="149.7">C</text>
<text x="17.1" y="200.2">D</text>
<text x="400.6" y="200.2">D</text>
<text x="17.1" y="250.8">E</text>
<text x="400.6" y="250.8">E</text>
<text x="42.7" y="277.9">1</text>
<text x="90.2" y="277.9">2</text>
<text x="137.7" y="277.9">3</text>
<text x="185.1" y="277.9">4</text>
<text x="232.6" y="277.9">5</text>
<text x="280" y="277.9">6</text>
<text x="327.5" y="277.9">7</text>
<text x="375" y="277.9">8</text>
</g>
<g font-size="3.6">
<text x="359.9" y="38.6">ALU Binary Operators</text>
<text x="316.2" y="88.1">Flag Strobe Generation</text>
<text x="77.5" y="103.3">ALU Binary Operator ROMs</text>
<text x="31.7" y="237.9">Decoupling</text>
<text x="315.7" y="248.1">Title:</text>
<text x="326.2" y="248.2">cft-processor</text>
<text x="315.9" y="253.2">Revision:</text>
<text x="333.8" y="253.3">Rev A</text>
<text x="315.4" y="263.3">Drawn by:</text>
<text x="315.9" y="258.2">Last Change: 13 Aug 2012</text>
<text x="334.5" y="263.3">Alexios</text>
<text x="361" y="258.1">19:11:25</text>
<text x="374.1" y="263.2">19/24</text>
<text x="224.8" y="268.4">* DRC</text>
<text x="315.4" y="268.4">Simulation filename:</text>
<text x="351" y="268.4">alu.v</text>
<text x="315.4" y="273.5">More Info: http://www.bedroomlan.org/cft</text>
</g>
<g font-size="2.5">
<text x="30.8" y="42.4">B[0..15]</text>
<text x="29" y="50">AC[0..15]</text>
<text x="26.2" y="57.6">RUNIT[0..3]</text>
<text x="28.5" y="66.1">RESET/18</text>
<text x="30.6" y="71.2">CLK3/17</text>
<text x="376.1" y="66.1">RESET/20</text>
<text x="376.1" y="71.2">CLK3/24</text>
<text x="31.6" y="76.3">BOE/18</text>
<text x="376.1" y="76.3">BOE/18</text>
<text x="34" y="81.3">FL/17</text>
<text x="376.1" y="81.3">FL/20</text>
<text x="59.7" y="95.7" transform="rotate(-90 59.7 95.7)">RUNIT[0..3]</text>
<text x="64.8" y="95.7" transform="rotate(-90 64.8 95.7)">FL</text>
<text x="69.8" y="95.7" transform="rotate(-90 69.8 95.7)">AC[0..15]</text>
<text x="74.9" y="95.7" transform="rotate(-90 74.9 95.7)">B[0..15]</text>
<text x="135.9" y="95.7" transform="rotate(-90 135.9 95.7)">RUNIT[0..3]</text>
<text x="146" y="95.7" transform="rotate(-90 146 95.7)">AC[0..15]</text>
<text x="151.1" y="95.7" transform="rotate(-90 151.1 95.7)">B[0..15]</text>
<text x="212.1" y="95.7" transform="rotate(-90 212.1 95.7)">RUNIT[0..3]</text>
<text x="222.2" y="95.7" transform="rotate(-90 222.2 95.7)">AC[0..15]</text>
<text x="227.3" y="95.7" transform="rotate(-90 227.3 95.7)">B[0..15]</text>
<text x="285.7" y="95.7" transform="rotate(-90 285.7 95.7)">RESET</text>
<text x="293.3" y="95.7" transform="rotate(-90 293.3 95.7)">BOE</text>
<text x="301" y="95.7" transform="rotate(-90 301 95.7)">CLK3</text>
<text x="328.9" y="95.1">IC108</text>
<text x="312.5" y="103.3">CLK3</text>
<text x="356.8" y="102">FLAGCLK</text>
<text x="77.5" y="113.5">B0</text>
<text x="87.6" y="110.3">IC105</text>
<text x="107.9" y="113.5">Y0</text>
<text x="153.7" y="113.5">B6</text>
<text x="163.8" y="110.3">IC106</text>
<text x="184.1" y="113.5">Y6</text>
<text x="229.8" y="113.5">B12</text>
<text x="240" y="110.3">IC107</text>
<text x="260.3" y="113.5">Y12</text>
<text x="77.5" y="116">B1</text>
<text x="77.5" y="118.6">B2</text>
<text x="107.9" y="116">Y1</text>
<text x="107.9" y="118.6">Y2</text>
<text x="153.7" y="116">B7</text>
<text x="153.7" y="118.6">B8</text>
<text x="184.1" y="116">Y7</text>
<text x="184.1" y="118.6">Y8</text>
<text x="229.8" y="116">B13</text>
<text x="229.8" y="118.6">B14</text>
<text x="260.3" y="116">Y13</text>
<text x="260.3" y="118.6">Y14</text>
<text x="77.5" y="121.1">B3</text>
<text x="77.5" y="123.6">B4</text>
<text x="107.9" y="121.1">Y3</text>
<text x="107.9" y="123.6">Y4</text>
<text x="153.7" y="121.1">B9</text>
<text x="153.7" y="123.6">B10</text>
<text x="184.1" y="121.1">Y9</text>
<text x="184.1" y="123.6">Y10</text>
<text x="227.3" y="123.6">AC12</text>
<text x="229.8" y="121.1">B15</text>
<text x="260.3" y="121.1">Y15</text>
<text x="313.4" y="123.6">BOE</text>
<text x="77.5" y="126.2">B5</text>
<text x="77.5" y="128.7">AC0</text>
<text x="77.5" y="131.3">AC1</text>
<text x="107.9" y="128.7">CO1</text>
<text x="107.9" y="126.2">Y5</text>
<text x="153.7" y="126.2">B11</text>
<text x="153.7" y="128.7">AC6</text>
<text x="153.7" y="131.3">AC7</text>
<text x="184.1" y="128.7">CO2</text>
<text x="184.1" y="126.2">Y11</text>
<text x="227.3" y="126.2">AC13</text>
<text x="227.3" y="128.7">AC14</text>
<text x="227.3" y="131.3">AC15</text>
<text x="260.3" y="131.3">FVOUT</text>
<text x="260.3" y="126.2">FLATCH</text>
<text x="260.3" y="128.7">ALUCPL</text>
<text x="309" y="126.2">FLATCH</text>
<text x="77.5" y="133.8">AC2</text>
<text x="77.5" y="136.3">AC3</text>
<text x="153.7" y="133.8">AC8</text>
<text x="153.7" y="136.3">AC9</text>
<text x="222.2" y="136.3">RUNIT0</text>
<text x="222.2" y="133.8">CO2</text>
<text x="328.9" y="136.3">74HC253N</text>
<text x="67.3" y="144">FL</text>
<text x="77.5" y="138.9">AC4</text>
<text x="77.5" y="141.4">AC5</text>
<text x="143.5" y="144">CO1</text>
<text x="153.7" y="138.9">AC10</text>
<text x="153.7" y="141.4">AC11</text>
<text x="222.2" y="138.9">RUNIT1</text>
<text x="318.7" y="138.9">GND</text>
<text x="67.3" y="146.5">RUNIT0</text>
<text x="67.3" y="149">RUNIT1</text>
<text x="143.5" y="146.5">RUNIT0</text>
<text x="143.5" y="149">RUNIT1</text>
<text x="326.4" y="149">AB (BOE FLATCH) -&gt; FLAGCLK</text>
<text x="326.4" y="151.6">A = BOE = 0 and B = FLATCH = 1 -&gt; Input 01 = xC2 = CLK3</text>
<text x="107.9" y="159.2" transform="rotate(-90 107.9 159.2)">VCC</text>
<text x="184.1" y="159.2" transform="rotate(-90 184.1 159.2)">VCC</text>
<text x="260.3" y="159.2" transform="rotate(-90 260.3 159.2)">VCC</text>
<text x="285.7" y="156.6" transform="rotate(-90 285.7 156.6)">RESET</text>
<text x="290.8" y="156.6" transform="rotate(-90 290.8 156.6)">ALUCPL</text>
<text x="295.9" y="156.6" transform="rotate(-90 295.9 156.6)">FVOUT</text>
<text x="301" y="156.6" transform="rotate(-90 301 156.6)">CLK3</text>
<text x="306" y="156.6" transform="rotate(-90 306 156.6)">FLAGCLK</text>
<text x="74.9" y="166.8" transform="rotate(-90 74.9 166.8)">VCC</text>
<text x="112" y="163.9">C118</text>
<text x="131.3" y="166.3">R28</text>
<text x="131.8" y="164">4k7</text>
<text x="151.1" y="166.8" transform="rotate(-90 151.1 166.8)">VCC</text>
<text x="188.2" y="163.9">C119</text>
<text x="207.5" y="166.3">R29</text>
<text x="208" y="164">4k7</text>
<text x="227.3" y="166.8" transform="rotate(-90 227.3 166.8)">VCC</text>
<text x="264.4" y="163.9">C120</text>
<text x="112" y="169">1uF</text>
<text x="188.2" y="169">1uF</text>
<text x="264.4" y="169">1uF</text>
<text x="325.6" y="169.3" transform="rotate(-90 325.6 169.3)">VCC</text>
<text x="328.9" y="168.7">IC109B</text>
<text x="376.1" y="172.8">FV/23</text>
<text x="80" y="177">GND</text>
<text x="87.6" y="174.4">29F040</text>
<text x="107.9" y="177">GND</text>
<text x="135.9" y="177">GND</text>
<text x="156.2" y="177">GND</text>
<text x="163.8" y="174.4">29F040</text>
<text x="184.1" y="177">GND</text>
<text x="212.1" y="177">GND</text>
<text x="232.4" y="177">GND</text>
<text x="240" y="174.4">29F040</text>
<text x="260.3" y="177">GND</text>
<text x="307.3" y="179.5">FLAGCLK</text>
<text x="310.2" y="174.4">FVOUT</text>
<text x="77.5" y="184.6">ROM image: alu-binary-6bit-00</text>
<text x="153.7" y="184.6">ROM image: alu-binary-6bit-00</text>
<text x="232.4" y="184.6">ROM image: alu-binary-4bit-00</text>
<text x="310.4" y="182">RESET</text>
<text x="328.9" y="187.1">74HC74N</text>
<text x="318.7" y="194.7" transform="rotate(-90 318.7 194.7)">VCC</text>
<text x="328.9" y="194.1">IC109A</text>
<text x="309" y="199.8">ALUCPL</text>
<text x="376.1" y="198.2">FLTADD/17</text>
<text x="307.3" y="204.9">FLAGCLK</text>
<text x="312.5" y="207.4">CLK3</text>
<text x="328.9" y="212.5">74HC74N</text>
<text x="377.1" y="220.1">Y[0..15]</text>
<text x="62.2" y="245.5" transform="rotate(-90 62.2 245.5)">VCC</text>
<text x="72.4" y="245.5" transform="rotate(-90 72.4 245.5)">VCC</text>
<text x="35" y="257.9">0.1uF</text>
<text x="35" y="252.8">C112</text>
<text x="42.7" y="257.9">0.1uF</text>
<text x="42.7" y="252.8">C113</text>
<text x="50.3" y="257.9">0.1uF</text>
<text x="50.3" y="252.8">C114</text>
<text x="57.9" y="257.9">0.1uF</text>
<text x="57.9" y="252.8">C115</text>
<text x="65.5" y="257.9">0.1uF</text>
<text x="65.5" y="252.8">C116</text>
<text x="76.4" y="257.9">1uF</text>
<text x="76.4" y="252.8">C117</text>
<text x="31.7" y="268.4">GND</text>
<text x="72.4" y="268.4">GND</text>
</g>
<g font-size="2.1">
<text x="325.4" y="100.4">5</text>
<text x="325.4" y="97.9">6</text>
<text x="331.2" y="101.5">1C1</text>
<text x="331.2" y="99">1C0</text>
<text x="339.2" y="99">1Y</text>
<text x="346.5" y="97.9">7</text>
<text x="325.4" y="105.5">3</text>
<text x="325.4" y="103">4</text>
<text x="331.2" y="106.6">1C3</text>
<text x="331.2" y="104.1">1C2</text>
<text x="84.9" y="113.1">12</text>
<text x="103.2" y="113.1">13</text>
<text x="161.1" y="113.1">12</text>
<text x="179.4" y="113.1">13</text>
<text x="237.3" y="113.1">12</text>
<text x="255.6" y="113.1">13</text>
<text x="324.2" y="110.6">10</text>
<text x="324.2" y="113.1">11</text>
<text x="331.2" y="111.7">2C0</text>
<text x="339.2" y="111.7">2Y</text>
<text x="346.5" y="110.6">9</text>
<text x="84.9" y="118.2">10</text>
<text x="84.9" y="115.7">11</text>
<text x="90" y="119.3">A2</text>
<text x="90" y="116.8">A1</text>
<text x="90" y="114.2">A0</text>
<text x="97.8" y="114.2">D0</text>
<text x="97.8" y="116.8">D1</text>
<text x="97.8" y="119.3">D2</text>
<text x="103.2" y="115.7">14</text>
<text x="103.2" y="118.2">15</text>
<text x="161.1" y="118.2">10</text>
<text x="161.1" y="115.7">11</text>
<text x="166.1" y="119.3">A2</text>
<text x="166.1" y="116.8">A1</text>
<text x="166.1" y="114.2">A0</text>
<text x="174" y="114.2">D0</text>
<text x="174" y="116.8">D1</text>
<text x="174" y="119.3">D2</text>
<text x="179.4" y="115.7">14</text>
<text x="179.4" y="118.2">15</text>
<text x="237.3" y="118.2">10</text>
<text x="237.3" y="115.7">11</text>
<text x="242.3" y="119.3">A2</text>
<text x="242.3" y="116.8">A1</text>
<text x="242.3" y="114.2">A0</text>
<text x="250.2" y="114.2">D0</text>
<text x="250.2" y="116.8">D1</text>
<text x="250.2" y="119.3">D2</text>
<text x="255.6" y="115.7">14</text>
<text x="255.6" y="118.2">15</text>
<text x="324.2" y="115.7">12</text>
<text x="324.2" y="118.2">13</text>
<text x="331.2" y="114.2">2C1</text>
<text x="331.2" y="116.8">2C2</text>
<text x="331.2" y="119.3">2C3</text>
<text x="86.1" y="125.8">7</text>
<text x="86.1" y="123.3">8</text>
<text x="86.1" y="120.7">9</text>
<text x="90" y="124.4">A4</text>
<text x="90" y="121.9">A3</text>
<text x="97.8" y="121.9">D3</text>
<text x="97.8" y="124.4">D4</text>
<text x="103.2" y="120.7">17</text>
<text x="103.2" y="123.3">18</text>
<text x="103.2" y="125.8">19</text>
<text x="162.3" y="125.8">7</text>
<text x="162.3" y="123.3">8</text>
<text x="162.3" y="120.7">9</text>
<text x="166.1" y="124.4">A4</text>
<text x="166.1" y="121.9">A3</text>
<text x="174" y="121.9">D3</text>
<text x="174" y="124.4">D4</text>
<text x="179.4" y="120.7">17</text>
<text x="179.4" y="123.3">18</text>
<text x="179.4" y="125.8">19</text>
<text x="238.5" y="125.8">7</text>
<text x="238.5" y="123.3">8</text>
<text x="238.5" y="120.7">9</text>
<text x="242.3" y="124.4">A4</text>
<text x="242.3" y="121.9">A3</text>
<text x="250.2" y="121.9">D3</text>
<text x="250.2" y="124.4">D4</text>
<text x="255.6" y="120.7">17</text>
<text x="255.6" y="123.3">18</text>
<text x="255.6" y="125.8">19</text>
<text x="324.2" y="123.3">14</text>
<text x="325.4" y="125.8">2</text>
<text x="331.2" y="124.4">A</text>
<text x="86.1" y="130.9">5</text>
<text x="86.1" y="128.4">6</text>
<text x="90" y="129.5">A6</text>
<text x="90" y="126.9">A5</text>
<text x="97.8" y="126.9">D5</text>
<text x="97.8" y="129.5">D6</text>
<text x="103.2" y="128.4">20</text>
<text x="103.2" y="130.9">21</text>
<text x="162.3" y="130.9">5</text>
<text x="162.3" y="128.4">6</text>
<text x="166.1" y="129.5">A6</text>
<text x="166.1" y="126.9">A5</text>
<text x="174" y="126.9">D5</text>
<text x="174" y="129.5">D6</text>
<text x="179.4" y="128.4">20</text>
<text x="179.4" y="130.9">21</text>
<text x="238.5" y="130.9">5</text>
<text x="238.5" y="128.4">6</text>
<text x="242.3" y="129.5">A6</text>
<text x="242.3" y="126.9">A5</text>
<text x="250.2" y="126.9">D5</text>
<text x="250.2" y="129.5">D6</text>
<text x="255.6" y="128.4">20</text>
<text x="255.6" y="130.9">21</text>
<text x="324.2" y="130.9">15</text>
<text x="325.4" y="128.4">1</text>
<text x="331.2" y="129.5">1G</text>
<text x="331.2" y="126.9">B</text>
<text x="84.9" y="136">26</text>
<text x="84.9" y="133.4">27</text>
<text x="90" y="132">A7</text>
<text x="90" y="137.1">A9</text>
<text x="90" y="134.6">A8</text>
<text x="97.8" y="132">D7</text>
<text x="161.1" y="136">26</text>
<text x="161.1" y="133.4">27</text>
<text x="166.1" y="132">A7</text>
<text x="166.1" y="137.1">A9</text>
<text x="166.1" y="134.6">A8</text>
<text x="174" y="132">D7</text>
<text x="237.3" y="136">26</text>
<text x="237.3" y="133.4">27</text>
<text x="242.3" y="132">A7</text>
<text x="242.3" y="137.1">A9</text>
<text x="242.3" y="134.6">A8</text>
<text x="250.2" y="132">D7</text>
<text x="331.2" y="132">2G</text>
<text x="84.9" y="138.5">23</text>
<text x="84.9" y="141.1">25</text>
<text x="86.1" y="143.6">4</text>
<text x="90" y="139.6">A10</text>
<text x="90" y="142.2">A11</text>
<text x="161.1" y="138.5">23</text>
<text x="161.1" y="141.1">25</text>
<text x="162.3" y="143.6">4</text>
<text x="166.1" y="139.6">A10</text>
<text x="166.1" y="142.2">A11</text>
<text x="237.3" y="138.5">23</text>
<text x="237.3" y="141.1">25</text>
<text x="238.5" y="143.6">4</text>
<text x="242.3" y="139.6">A10</text>
<text x="242.3" y="142.2">A11</text>
<text x="84.9" y="146.1">28</text>
<text x="84.9" y="148.7">29</text>
<text x="90" y="144.7">A12</text>
<text x="90" y="147.3">A13</text>
<text x="90" y="149.8">A14</text>
<text x="161.1" y="146.1">28</text>
<text x="161.1" y="148.7">29</text>
<text x="166.1" y="144.7">A12</text>
<text x="166.1" y="147.3">A13</text>
<text x="166.1" y="149.8">A14</text>
<text x="237.3" y="146.1">28</text>
<text x="237.3" y="148.7">29</text>
<text x="242.3" y="144.7">A12</text>
<text x="242.3" y="147.3">A13</text>
<text x="242.3" y="149.8">A14</text>
<text x="86.1" y="151.2">3</text>
<text x="86.1" y="153.8">2</text>
<text x="90" y="152.3">A15</text>
<text x="90" y="154.9">A16</text>
<text x="162.3" y="151.2">3</text>
<text x="162.3" y="153.8">2</text>
<text x="166.1" y="152.3">A15</text>
<text x="166.1" y="154.9">A16</text>
<text x="238.5" y="151.2">3</text>
<text x="238.5" y="153.8">2</text>
<text x="242.3" y="152.3">A15</text>
<text x="242.3" y="154.9">A16</text>
<text x="84.9" y="156.3">30</text>
<text x="86.1" y="158.8">1</text>
<text x="90" y="157.4">A17</text>
<text x="90" y="159.9">A18</text>
<text x="161.1" y="156.3">30</text>
<text x="162.3" y="158.8">1</text>
<text x="166.1" y="157.4">A17</text>
<text x="166.1" y="159.9">A18</text>
<text x="237.3" y="156.3">30</text>
<text x="238.5" y="158.8">1</text>
<text x="242.3" y="157.4">A17</text>
<text x="242.3" y="159.9">A18</text>
<text x="84.9" y="163.9">22</text>
<text x="84.9" y="166.5">24</text>
<text x="90" y="165">CE</text>
<text x="90" y="167.6">OE</text>
<text x="161.1" y="163.9">22</text>
<text x="161.1" y="166.5">24</text>
<text x="166.1" y="165">CE</text>
<text x="166.1" y="167.6">OE</text>
<text x="237.3" y="163.9">22</text>
<text x="237.3" y="166.5">24</text>
<text x="242.3" y="165">CE</text>
<text x="242.3" y="167.6">OE</text>
<text x="84.9" y="169">31</text>
<text x="90" y="170.1">WE</text>
<text x="161.1" y="169">31</text>
<text x="166.1" y="170.1">WE</text>
<text x="237.3" y="169">31</text>
<text x="242.3" y="170.1">WE</text>
<text x="324.2" y="171.5">10</text>
<text x="331.2" y="172.6">PRE</text>
<text x="340.1" y="172.6">Q</text>
<text x="346.5" y="171.5">9</text>
<text x="324.2" y="174.1">12</text>
<text x="324.2" y="179.1">11</text>
<text x="331.2" y="175.2">D</text>
<text x="324.2" y="181.7">13</text>
<text x="331.2" y="182.8">CLR</text>
<text x="331.2" y="180.3">CLK</text>
<text x="340.1" y="182.8">Q</text>
<text x="346.5" y="181.7">8</text>
<text x="325.4" y="196.9">4</text>
<text x="346.5" y="196.9">5</text>
<text x="325.4" y="199.5">2</text>
<text x="331.2" y="200.6">D</text>
<text x="331.2" y="198">PRE</text>
<text x="340.1" y="198">Q</text>
<text x="325.4" y="207.1">1</text>
<text x="325.4" y="204.5">3</text>
<text x="331.2" y="208.2">CLR</text>
<text x="331.2" y="205.7">CLK</text>
<text x="340.1" y="208.2">Q</text>
<text x="346.5" y="207.1">6</text>
</g>
</g></defs>
<g fill="#000" stroke="#000" stroke-width=".21">
<path d="M67.8 18.2v3.9zM115.3 18.2v3.9zM162.7 18.2v3.9zM210.2 18.2v3.9zM257.6 18.2v3.9zM305.1 18.2v3.9zM352.5 18.2v3.9zM20.3 22.1v252.6zM20.3 22.1h379.7zM16.5 72.6h3.8zM28.5 64.1h8.4zM31.6 74.3h5.3z"/>
<path d="M41.9 70.3h256.5zM41.9 65.2h241.3zM283.2 65.2v116.9zM41.9 75.4h248.9zM298.4 70.3h76.2zM283.2 65.2h91.4zM290.8 75.4h83.8zM376.1 64.1h8.4zM376.1 74.3h5.3zM400 72.6h3.8zM41.9 80.5h20.3zM62.2 80.5h312.4z"/>
<path d="M283.8 87.3v8.4zM291.4 90.4v5.3zM321.3 98.2v2.6zM323.8 98.2h5.1zM321.3 98.2h2.5zM344.1 98.2h5.1zM349.2 98.2h5.1zM354.3 98.2v45.8zM356.8 98.2h2.6zM359.4 95.7v2.5zM359.4 95.7h2.5zM72.4 110.9l2.5 2.6z"/>
<path d="M72.4 113.5l2.5 2.5zM72.4 116l2.5 2.6zM72.4 118.6l2.5 2.5zM74.9 113.5h10.2zM74.9 116h10.2zM74.9 118.6h10.2zM85.1 118.6h2.5zM85.1 116h2.5zM85.1 113.5h2.5zM102.9 113.5h2.5zM102.9 116h2.5zM102.9 118.6h2.5z"/>
<path d="M105.4 113.5h12.7zM105.4 116h12.7zM105.4 118.6h12.7zM120.6 110.9l-2.5 2.6zM120.6 113.5l-2.5 2.5zM120.6 116l-2.5 2.6zM120.6 118.6l-2.5 2.5zM148.6 110.9l2.5 2.6zM148.6 113.5l2.5 2.5zM148.6 116l2.5 2.6zM148.6 118.6l2.5 2.5zM151.1 113.5h10.2z"/>
<path d="M151.1 116h10.2zM151.1 118.6h10.2zM161.3 118.6h2.5zM161.3 116h2.5zM161.3 113.5h2.5zM179 113.5h2.6zM179 116h2.6zM179 118.6h2.6zM181.6 113.5h12.7zM181.6 116h12.7zM181.6 118.6h12.7zM196.8 110.9l-2.5 2.6z"/>
<path d="M196.8 113.5l-2.5 2.5zM196.8 116l-2.5 2.6zM196.8 118.6l-2.5 2.5zM224.8 110.9l2.5 2.6zM224.8 113.5l2.5 2.5zM224.8 116l2.5 2.6zM224.8 118.6l2.5 2.5zM227.3 113.5h10.2zM227.3 116h10.2zM227.3 118.6h10.2zM237.5 118.6h2.5zM237.5 116h2.5z"/>
<path d="M237.5 113.5h2.5zM255.2 113.5h2.6zM255.2 116h2.6zM255.2 118.6h2.6zM257.8 113.5h12.7zM257.8 116h12.7zM257.8 118.6h12.7zM273 110.9l-2.5 2.6zM273 113.5l-2.5 2.5zM270.5 118.6l2.5-2.6zM273 118.6l-2.5 2.5zM298.4 70.3v33z"/>
<path d="M298.4 103.3v104.1zM321.3 100.8v5.1zM321.3 105.9v5zM321.3 110.9v2.6zM321.3 113.5v2.5zM321.3 116v2.6zM321.3 118.6v10.1zM323.8 105.9h5.1zM323.8 103.3h5.1zM323.8 100.8h5.1zM323.8 110.9h5.1zM323.8 113.5h5.1z"/>
<path d="M323.8 116h5.1zM323.8 118.6h5.1zM321.3 105.9h2.5zM321.3 110.9h2.5zM321.3 116h2.5zM321.3 118.6h2.5zM321.3 113.5h2.5zM321.3 100.8h2.5zM298.4 103.3h25.4zM344.1 110.9h5.1zM16.5 123.1h3.8zM67.3 138.9l2.5 2.5z"/>
<path d="M67.3 126.2l2.5 2.5zM67.3 128.7l2.5 2.6zM67.3 131.3l2.5 2.5zM67.3 133.8l2.5 2.5zM67.3 136.3l2.5 2.6zM72.4 121.1l2.5 2.5zM74.9 121.1h10.2zM74.9 123.6h10.2zM72.4 123.6l2.5 2.6zM85.1 131.3h2.5zM85.1 128.7h2.5zM85.1 126.2h2.5z"/>
<path d="M85.1 123.6h2.5zM85.1 121.1h2.5zM85.1 138.9h2.5zM85.1 136.3h2.5zM85.1 133.8h2.5zM74.9 126.2h10.2zM69.8 128.7h15.3zM69.8 131.3h15.3zM69.8 133.8h15.3zM69.8 136.3h15.3zM69.8 138.9h15.3zM102.9 121.1h2.5z"/>
<path d="M102.9 123.6h2.5zM102.9 126.2h2.5zM102.9 128.7h2.5zM102.9 131.3h2.5zM105.4 131.3h2.5zM105.4 128.7h33zM105.4 121.1h12.7zM105.4 123.6h12.7zM105.4 126.2h12.7zM120.6 121.1l-2.5 2.5zM120.6 123.6l-2.5 2.6zM138.4 128.7v15.3z"/>
<path d="M143.5 126.2l2.5 2.5zM143.5 128.7l2.5 2.6zM143.5 131.3l2.5 2.5zM143.5 133.8l2.5 2.5zM143.5 136.3l2.5 2.6zM148.6 121.1l2.5 2.5zM148.6 123.6l2.5 2.6zM151.1 121.1h10.2zM151.1 123.6h10.2zM151.1 126.2h10.2zM161.3 131.3h2.5zM161.3 128.7h2.5z"/>
<path d="M161.3 126.2h2.5zM161.3 123.6h2.5zM161.3 121.1h2.5zM161.3 138.9h2.5zM161.3 136.3h2.5zM161.3 133.8h2.5zM146 128.7h15.3zM146 131.3h15.3zM146 133.8h15.3zM146 136.3h15.3zM146 138.9h15.3zM179 121.1h2.6z"/>
<path d="M179 123.6h2.6zM179 126.2h2.6zM179 128.7h2.6zM179 131.3h2.6zM181.6 131.3h2.5zM181.6 128.7h33zM181.6 121.1h12.7zM181.6 123.6h12.7zM181.6 126.2h12.7zM196.8 121.1l-2.5 2.5zM196.8 123.6l-2.5 2.6zM209.5 133.8l2.6 2.5z"/>
<path d="M209.5 136.3l2.6 2.6zM214.6 128.7v5.1zM214.6 133.8h22.9zM219.7 121.1l2.5 2.5zM219.7 123.6l2.5 2.6zM219.7 126.2l2.5 2.5zM219.7 128.7l2.5 2.6zM227.3 121.1h10.2zM237.5 131.3h2.5zM237.5 128.7h2.5zM237.5 126.2h2.5zM237.5 123.6h2.5z"/>
<path d="M237.5 121.1h2.5zM237.5 138.9h2.5zM237.5 136.3h2.5zM237.5 133.8h2.5zM212.1 136.3h25.4zM212.1 138.9h25.4zM222.2 123.6h15.3zM222.2 126.2h15.3zM222.2 128.7h15.3zM222.2 131.3h15.3zM255.2 121.1h2.6zM255.2 123.6h2.6z"/>
<path d="M255.2 126.2h2.6zM255.2 128.7h2.6zM255.2 131.3h2.6zM257.8 123.6h2.5zM257.8 131.3h35.5zM257.8 126.2h66zM257.8 128.7h30.5zM260.3 126.7h9.7zM257.8 121.1h12.7zM288.3 128.7v71.1zM290.8 75.4v48.2zM293.3 131.3v43.1z"/>
<path d="M313.4 121.7h5.3zM321.3 133.8v2.5zM321.3 128.7v2.6zM321.3 131.3v2.5zM323.8 128.7h3.1zM323.8 126.2h5.1zM323.8 123.6h5.1zM323.8 131.3h3.1zM321.3 128.7h2.5zM321.3 131.3h2.5zM290.8 123.6h33zM400 123.1h3.8z"/>
<path d="M57.1 144l2.6 2.5zM57.1 146.5l2.6 2.5zM62.2 80.5v63.5zM69.8 141.4h15.3zM82.5 151.6v2.5zM82.5 154.1v2.6zM82.5 156.7v2.5zM82.5 159.2v5.1zM85.1 144h2.5zM85.1 141.4h2.5zM85.1 146.5h2.5zM85.1 149h2.5z"/>
<path d="M85.1 151.6h2.5zM85.1 154.1h2.5zM85.1 156.7h2.5zM85.1 159.2h2.5zM82.5 151.6h2.6zM82.5 154.1h2.6zM82.5 156.7h2.6zM82.5 159.2h2.6zM59.7 146.5h25.4zM59.7 149h25.4zM62.2 144h22.9zM110.5 156.7v2.5z"/>
<path d="M133.3 144l2.6 2.5zM133.3 146.5l2.6 2.5zM138.4 159.2v2.5zM138.4 144h22.9zM138.4 144v15.2zM143.5 138.9l2.5 2.5zM158.7 151.6v2.5zM158.7 154.1v2.6zM158.7 156.7v2.5zM158.7 159.2v5.1zM161.3 144h2.5zM161.3 141.4h2.5z"/>
<path d="M161.3 146.5h2.5zM161.3 149h2.5zM161.3 151.6h2.5zM161.3 154.1h2.5zM161.3 156.7h2.5zM161.3 159.2h2.5zM158.7 151.6h2.6zM158.7 154.1h2.6zM158.7 156.7h2.6zM158.7 159.2h2.6zM135.9 146.5h25.4zM135.9 149h25.4z"/>
<path d="M146 141.4h15.3zM186.7 156.7v2.5zM214.6 159.2v2.5zM214.6 133.8v25.4zM234.9 151.6v2.5zM234.9 154.1v2.6zM234.9 156.7v2.5zM234.9 159.2v5.1zM234.9 141.4v2.6zM234.9 144v2.5zM234.9 146.5v2.5zM234.9 149v2.6z"/>
<path d="M237.5 144h2.5zM237.5 141.4h2.5zM237.5 146.5h2.5zM237.5 149h2.5zM237.5 151.6h2.5zM237.5 154.1h2.5zM237.5 156.7h2.5zM237.5 159.2h2.5zM234.9 151.6h2.6zM234.9 154.1h2.6zM234.9 141.4h2.6zM234.9 144h2.6z"/>
<path d="M234.9 146.5h2.6zM234.9 149h2.6zM234.9 156.7h2.6zM234.9 159.2h2.6zM262.9 156.7v2.5zM283.8 148.3v8.4zM288.8 147v9.7zM303.5 144v35.5zM330.9 149.6h5.3zM331.2 147.1h5.3zM303.5 144h50.8zM16.5 173.7h3.8z"/>
<path d="M77.5 164.3v2.5zM77.5 166.8v2.6zM82.5 171.9v2.5zM82.5 164.3v2.5zM82.5 166.8v5.1zM85.1 169.4h2.5zM85.1 164.3h2.5zM85.1 166.8h2.5zM82.5 164.3h2.6zM82.5 166.8h2.6zM77.5 169.4h7.6zM90 168.5h3.4z"/>
<path d="M90 163.4h2.9zM90 165.9h3.1zM110.5 171.9v2.5zM110.5 161.7v2.6zM110.5 166.8v2.6zM110.5 164.3v.5zM110.5 166.3v.5zM110.5 169.4v2.5zM110.5 159.2v2.5zM138.4 166.8v2.6zM138.4 171.9v2.5zM138.4 169.4v2.5z"/>
<path d="M153.6 164.3v2.5zM153.6 166.8v2.6zM158.7 171.9v2.5zM158.7 164.3v2.5zM158.7 166.8v5.1zM161.3 169.4h2.5zM161.3 164.3h2.5zM161.3 166.8h2.5zM158.7 164.3h2.6zM158.7 166.8h2.6zM153.6 169.4h7.7zM166.2 168.5h3.4z"/>
<path d="M166.2 163.4h2.9zM166.2 165.9h3.1zM186.7 171.9v2.5zM186.7 161.7v2.6zM186.7 166.8v2.6zM186.7 164.3v.5zM186.7 166.3v.5zM186.7 169.4v2.5zM186.7 159.2v2.5zM214.6 166.8v2.6zM214.6 171.9v2.5zM214.6 169.4v2.5z"/>
<path d="M229.8 164.3v2.5zM229.8 166.8v2.6zM234.9 171.9v2.5zM234.9 164.3v2.5zM234.9 166.8v5.1zM237.5 169.4h2.5zM237.5 164.3h2.5zM237.5 166.8h2.5zM234.9 164.3h2.6zM234.9 166.8h2.6zM229.8 169.4h7.7zM242.3 168.5h3.5z"/>
<path d="M242.3 163.4h3zM242.3 165.9h3.1zM262.9 171.9v2.5zM262.9 161.7v2.6zM262.9 166.8v2.6zM262.9 164.3v.5zM262.9 166.3v.5zM262.9 169.4v2.5zM262.9 159.2v2.5zM293.3 174.4h30.5zM303.5 179.5v25.4zM321.3 166.8v2.6z"/>
<path d="M321.3 169.4v2.5zM323.8 174.4h5.1zM323.8 179.5h5.1zM323.8 171.9h3.1zM321.3 171.9h2.5zM303.5 179.5h20.3zM328.9 178.5l2 1zM328.9 180.5l2-1zM344.1 171.9h5.1zM349.2 171.9h25.4zM400 173.7h3.8zM288.3 199.8h35.5z"/>
<path d="M309 197.9h9.7zM310.4 180.1h8.3zM321.3 192.2v2.6zM321.3 194.8v2.5zM323.8 199.8h5.1zM323.8 197.3h3.1zM323.8 182.1h3.1zM321.3 197.3h2.5zM283.2 182.1h40.6zM340.1 181.2h1.7zM344.1 197.3h5.1zM344.1 182.1h5.1z"/>
<path d="M349.2 197.3h25.4zM376.1 196.2h9.8zM298.4 207.4h25.4zM323.8 207.4h3.1zM323.8 204.9h5.1zM303.5 204.9h20.3zM328.9 203.9l2 1zM328.9 205.9l2-1zM340.1 206.5h1.7zM344.1 207.4h5.1zM16.5 224.2h3.8zM400 224.2h3.8z"/>
<path d="M34.3 255.7v2.5zM34.3 250.6v2.5zM34.3 255.2v.5zM34.3 253.1v.6zM34.3 258.2v2.6zM34.3 248.1v2.5zM41.9 255.7v2.5zM41.9 250.6v2.5zM41.9 255.2v.5zM41.9 253.1v.6zM41.9 248.1v2.5zM34.3 248.1h7.6z"/>
<path d="M49.5 255.7v2.5zM49.5 250.6v2.5zM49.5 255.2v.5zM49.5 253.1v.6zM41.9 248.1h7.6zM49.5 248.1v2.5zM57.1 255.7v2.5zM57.1 250.6v2.5zM57.1 255.2v.5zM57.1 253.1v.6zM49.5 248.1h7.6zM57.1 248.1v2.5z"/>
<path d="M64.8 243v2.5zM64.8 255.7v2.5zM64.8 250.6v2.5zM64.8 255.2v.5zM64.8 253.1v.6zM57.1 248.1h7.7zM64.8 245.5v2.6zM64.8 248.1v2.5zM74.9 243v2.5zM74.9 250.6v2.5zM74.9 255.7v2.5zM74.9 253.1v.6z"/>
<path d="M74.9 255.2v.5zM74.9 245.5v5.1zM20.3 274.7h379.7zM34.3 263.3v2.5zM34.3 260.8h7.6zM34.3 260.8v2.5zM41.9 258.2v2.6zM41.9 260.8h7.6zM49.5 258.2v2.6zM49.5 260.8h7.6zM57.1 258.2v2.6zM57.1 260.8h7.7z"/>
<path d="M64.8 258.2v2.6zM67.8 274.7v3.8zM74.9 263.3v2.5zM74.9 258.2v5.1zM115.3 274.7v3.8zM162.7 274.7v3.8zM210.2 274.7v3.8zM257.6 274.7v3.8zM305.1 274.7v3.8zM352.5 274.7v3.8zM400 264.5v.1zM400 268.4v6.2z"/>
<path d="M400 274.6h.1zM400 22.1v252.6z"/>
<circle cx="283.2" cy="65.2" r=".51"/>
<circle cx="290.8" cy="75.4" r=".51"/>
<circle cx="298.4" cy="70.3" r=".51"/>
<circle cx="62.2" cy="80.5" r=".51"/>
<circle cx="298.4" cy="103.3" r=".51"/>
<circle cx="321.3" cy="100.8" r=".51"/>
<circle cx="321.3" cy="118.6" r=".51"/>
<circle cx="321.3" cy="105.9" r=".51"/>
<circle cx="321.3" cy="113.5" r=".51"/>
<circle cx="321.3" cy="116" r=".51"/>
<circle cx="321.3" cy="110.9" r=".51"/>
<circle cx="214.6" cy="133.8" r=".51"/>
<circle cx="321.3" cy="131.3" r=".51"/>
<circle cx="321.3" cy="128.7" r=".51"/>
<circle cx="82.5" cy="159.2" r=".51"/>
<circle cx="82.5" cy="154.1" r=".51"/>
<circle cx="82.5" cy="156.7" r=".51"/>
<circle cx="138.4" cy="144" r=".51"/>
<circle cx="158.7" cy="154.1" r=".51"/>
<circle cx="158.7" cy="159.2" r=".51"/>
<circle cx="158.7" cy="156.7" r=".51"/>
<circle cx="234.9" cy="159.2" r=".51"/>
<circle cx="234.9" cy="154.1" r=".51"/>
<circle cx="234.9" cy="146.5" r=".51"/>
<circle cx="234.9" cy="156.7" r=".51"/>
<circle cx="234.9" cy="151.6" r=".51"/>
<circle cx="234.9" cy="149" r=".51"/>
<circle cx="234.9" cy="144" r=".51"/>
<circle cx="82.5" cy="164.3" r=".51"/>
<circle cx="82.5" cy="166.8" r=".51"/>
<circle cx="158.7" cy="166.8" r=".51"/>
<circle cx="158.7" cy="164.3" r=".51"/>
<circle cx="234.9" cy="166.8" r=".51"/>
<circle cx="234.9" cy="164.3" r=".51"/>
<circle cx="303.5" cy="179.5" r=".51"/>
<circle cx="41.9" cy="248.1" r=".51"/>
<circle cx="49.5" cy="248.1" r=".51"/>
<circle cx="57.1" cy="248.1" r=".51"/>
<circle cx="64.8" cy="248.1" r=".51"/>
<circle cx="34.3" cy="260.8" r=".51"/>
<circle cx="41.9" cy="260.8" r=".51"/>
<circle cx="49.5" cy="260.8" r=".51"/>
<circle cx="57.1" cy="260.8" r=".51"/>
</g>
<g fill="#000" stroke="#000" stroke-width=".28">
<path d="M26.2 63.7v3zM29.3 73.8v3.1zM29.7 68.8v3zM33.1 78.9v3.1zM33.1 78.9h7.3zM26.2 66.7h14.2zM26.2 63.7h14.2zM29.7 68.8h10.7zM29.7 71.8h10.7zM29.3 76.9h11.1zM29.3 73.8h11.1zM41.9 65.2l-1.5 1.5z"/>
<path d="M40.4 63.7l1.5 1.5zM40.4 68.8l1.5 1.5zM40.4 71.8l1.5-1.5zM41.9 75.4l-1.5 1.5zM40.4 73.8l1.5 1.6zM374.6 65.2l1.5-1.5zM374.6 65.2l1.5 1.5zM374.6 70.3l1.5-1.5zM374.6 70.3l1.5 1.5zM374.6 75.4l1.5-1.6zM374.6 75.4l1.5 1.5zM376.1 78.9h7.3z"/>
<path d="M376.1 63.7h14.2zM376.1 66.7h14.2zM376.1 68.8h10.7zM376.1 71.8h10.7zM376.1 73.8h11.1zM376.1 76.9h11.1zM383.4 78.9v3.1zM386.8 68.8v3zM387.2 73.8v3.1zM390.3 63.7v3zM33.1 82h7.3zM40.4 78.9l1.5 1.6z"/>
<path d="M41.9 80.5l-1.5 1.5zM374.6 80.5l1.5-1.6zM374.6 80.5l1.5 1.5zM376.1 82h7.3zM106.9 130.2l2.1 2.1zM109 130.2l-2.1 2.1zM183.1 130.2l2 2.1zM183.1 132.3l2-2.1zM259.3 122.6l2 2zM261.3 122.6l-2 2zM319.4 136.3h3.8zM110.5 156.7l-1.3 1.9z"/>
<path d="M110.5 156.7l1.3 1.9zM186.7 156.7l-1.3 1.9zM186.7 156.7l1.2 1.9zM262.9 156.7l-1.3 1.9zM262.9 156.7l1.2 1.9zM77.5 164.3l-1.3 1.9zM77.5 164.3l1.2 1.9zM80.6 174.4h3.9zM108.6 174.4h3.8zM136.5 174.4h3.8zM137.5 161.7v5.1zM137.5 166.8h1.8z"/>
<path d="M137.5 161.7h1.8zM139.3 161.7v5.1zM153.6 164.3l-1.2 1.9zM153.6 164.3l1.3 1.9zM156.8 174.4h3.8zM184.8 174.4h3.8zM212.7 174.4h3.8zM213.7 161.7v5.1zM213.7 166.8h1.8zM213.7 161.7h1.8zM215.5 161.7v5.1zM229.8 164.3l-1.2 1.9z"/>
<path d="M229.8 164.3l1.3 1.9zM233 174.4h3.8zM261 174.4h3.8zM321.3 166.8l-1.3 1.9zM321.3 166.8l1.3 1.9zM374.6 171.9l1.5 1.5zM374.6 171.9l1.5-1.5zM376.1 173.4h7.6zM376.1 170.4h7.6zM383.7 170.4v3zM321.3 192.2l-1.3 1.9zM321.3 192.2l1.3 1.9z"/>
<path d="M374.6 197.3l1.5-1.5zM374.6 197.3l1.5 1.5zM376.1 195.8h15.6zM376.1 198.8h15.6zM391.7 195.8v3zM64.8 243l-1.3 1.9zM64.8 243l1.2 1.9zM74.9 243l-1.2 1.9zM74.9 243l1.3 1.9zM313.7 249.3h86.3zM313.7 254.4h86.3zM313.7 259.5h58.4z"/>
<path d="M372.1 259.5h27.9zM372.1 259.5v5.1zM32.4 265.8h3.8zM73 265.8h3.8zM313.7 264.6h58.4zM313.7 269.7h86.3zM372.1 264.6h27.9zM400 268.4v1.3z"/>
</g>
<g fill="#000" stroke="#000" stroke-width=".61">
<path d="M20.3 22.1v252.6zM20.3 22.1h379.7zM328.9 95.7v38.1zM328.9 95.7h15.2zM87.6 110.9v61zM87.6 110.9h15.3zM163.8 110.9v61zM163.8 110.9h15.2zM240 110.9v61zM240 110.9h15.2zM328.9 133.8h15.2zM344.1 95.7v38.1z"/>
<path d="M87.6 171.9h15.3zM102.9 110.9v61zM163.8 171.9h15.2zM179 110.9v61zM240 171.9h15.2zM255.2 110.9v61zM328.9 169.4v15.2zM328.9 169.4h15.2zM328.9 194.8v15.2zM328.9 184.6h15.2zM328.9 194.8h15.2zM344.1 169.4v15.2z"/>
<path d="M328.9 210h15.2zM344.1 194.8v15.2zM283.2 244.3v30.4zM313.7 254.4v5.1zM313.7 249.3v5.1zM313.7 244.3v5zM313.7 244.3h86.3zM283.2 244.3h30.5zM400 254.4v5.1zM400 249.3v5.1zM400 244.3v5zM400 22.1v222.2z"/>
<path d="M20.3 274.7h262.9zM283.2 274.7h30.5zM313.7 274.7h86.3zM313.7 269.7v5zM313.7 264.6v5.1zM313.7 259.5v5.1zM400 268.4v6.3zM400 264.6v3.8zM400 259.5v5.1z"/>
</g>
<g fill="none" stroke="#000" stroke-width=".21">
<circle cx="327.9" cy="131.3" r="1"/>
<circle cx="327.9" cy="128.7" r="1"/>
<circle cx="327.9" cy="171.9" r="1"/>
<circle cx="327.9" cy="182.1" r="1"/>
<circle cx="327.9" cy="197.3" r="1"/>
<circle cx="327.9" cy="207.4" r="1"/>
</g>
<path d="M16.5 18.2v260.3zM16.5 18.2h387.3zM16.5 278.5h387.3zM403.8 18.2v260.3z" fill="#000" stroke="#000" stroke-width=".32"/>
<g fill="#000" stroke="#000" stroke-width=".21">
<path d="M108.5 165.8h4v.5h-4zM108.5 164.8h4v.5h-4zM184.6 165.8h4.1v.5h-4.1zM184.6 164.8h4.1v.5h-4.1zM260.8 165.8h4.1v.5h-4.1zM260.8 164.8h4.1v.5h-4.1zM32.3 253.7h4v.5h-4zM32.3 254.7h4v.5h-4zM39.9 253.7h4v.5h-4zM39.9 254.7h4v.5h-4zM47.5 253.7h4.1v.5h-4.1zM47.5 254.7h4.1v.5h-4.1z"/>
<path d="M55.1 253.7h4.1v.5h-4.1zM55.1 254.7h4.1v.5h-4.1zM62.7 253.7h4.1v.5h-4.1zM62.7 254.7h4.1v.5h-4.1zM72.9 254.7h4.1v.5h-4.1zM72.9 253.7h4.1v.5h-4.1zM252.7 253.1h25.4v10.2h-25.4z"/>
</g>
<g fill="#000" stroke="#000" stroke-width=".76">
<path d="M41.9 42.4h175.2zM41.9 50h20.3zM41.9 57.6h10.2zM52.1 57.6h76.1zM52.1 57.6l5 5.1zM62.2 50h152.4zM62.2 50l5.1 5.1zM67.3 42.4l5.1 5.1zM67.3 55.1v83.8zM72.4 47.5v76.1zM128.2 57.6h76.2zM128.2 57.6l5.1 5.1z"/>
<path d="M138.4 50l5.1 5.1zM143.5 42.4l5.1 5.1zM143.5 55.1v83.8zM148.6 47.5v76.1zM204.4 57.6l5.1 5.1zM214.6 50l5.1 5.1zM217.1 42.4l7.7 7.6zM219.7 55.1v73.6zM224.8 50v68.6zM57.1 62.7v83.8zM133.3 62.7v83.8zM209.5 62.7v73.6z"/>
<path d="M120.6 110.9v104.1zM120.6 215l5.1 5.1zM196.8 110.9v104.1zM196.8 215l5.1 5.1zM273 110.9v104.1zM273 215l5.1 5.1zM125.7 220.1h248.9z"/>
</g>
<path d="M222.2 253.1v10.2zM222.2 253.1h55.9zM222.2 263.3v7.6zM222.2 270.9h55.9zM222.2 263.3h55.9zM278.1 263.3v7.6zM278.1 253.1v10.2z" fill="#000" stroke="#000" stroke-width=".42"/>
<use href="#words"/>
</svg>
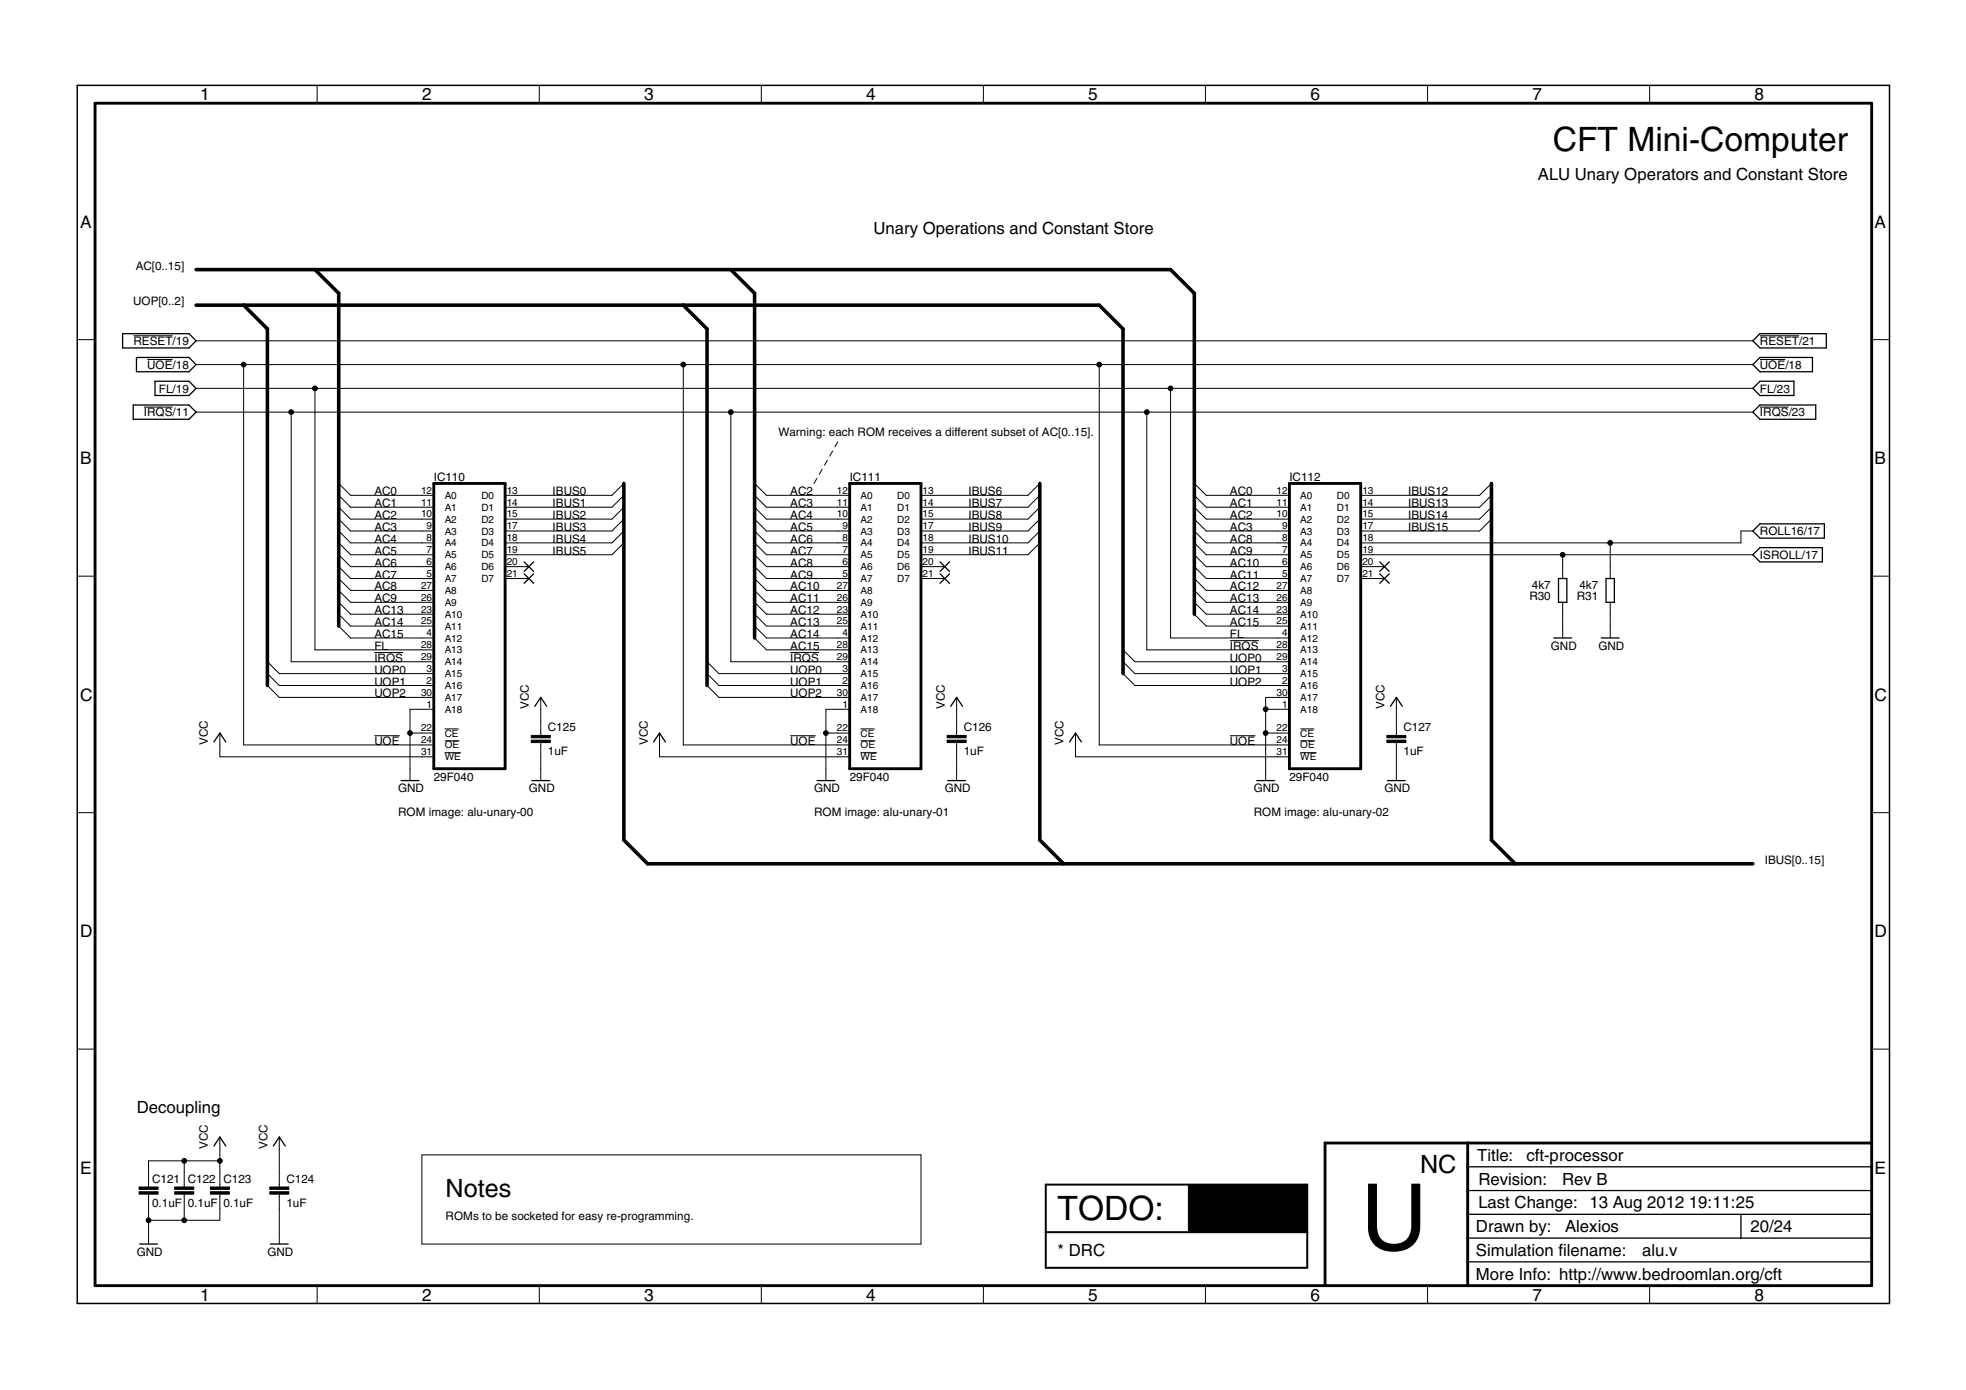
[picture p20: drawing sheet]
<svg xmlns="http://www.w3.org/2000/svg" width="420mm" height="297mm" viewBox="0 0 420 297" stroke-linecap="round" stroke-linejoin="round" font-family="sans-serif">
<defs><g id="words">
<text font-size="19.7" x="290.8" y="267.1">U</text>
<g font-size="7.2">
<text x="331.8" y="32.2">CFT Mini-Computer</text>
<text x="226" y="260.8">TODO:</text>
</g>
<g font-size="5.4">
<text x="303.5" y="250.6">NC</text>
<text x="95.2" y="255.7">Notes</text>
</g>
<g font-size="3.7">
<text x="42.7" y="21.5">1</text>
<text x="90.2" y="21.5">2</text>
<text x="137.7" y="21.5">3</text>
<text x="185.1" y="21.5">4</text>
<text x="232.6" y="21.5">5</text>
<text x="280" y="21.5">6</text>
<text x="327.5" y="21.5">7</text>
<text x="375" y="21.5">8</text>
<text x="17.1" y="48.6">A</text>
<text x="400.6" y="48.6">A</text>
<text x="17.1" y="99.2">B</text>
<text x="400.6" y="99.2">B</text>
<text x="17.1" y="149.7">C</text>
<text x="400.6" y="149.7">C</text>
<text x="17.1" y="200.2">D</text>
<text x="400.6" y="200.2">D</text>
<text x="17.1" y="250.8">E</text>
<text x="400.6" y="250.8">E</text>
<text x="42.7" y="277.9">1</text>
<text x="90.2" y="277.9">2</text>
<text x="137.7" y="277.9">3</text>
<text x="185.1" y="277.9">4</text>
<text x="232.6" y="277.9">5</text>
<text x="280" y="277.9">6</text>
<text x="327.5" y="277.9">7</text>
<text x="375" y="277.9">8</text>
</g>
<g font-size="3.6">
<text x="328.7" y="38.6">ALU Unary Operators and Constant Store</text>
<text x="186.7" y="50">Unary Operations and Constant Store</text>
<text x="29.2" y="237.9">Decoupling</text>
<text x="315.7" y="248.1">Title:</text>
<text x="326.2" y="248.2">cft-processor</text>
<text x="315.9" y="253.2">Revision:</text>
<text x="333.8" y="253.3">Rev B</text>
<text x="315.4" y="263.3">Drawn by:</text>
<text x="315.9" y="258.2">Last Change: 13 Aug 2012</text>
<text x="334.5" y="263.3">Alexios</text>
<text x="361" y="258.1">19:11:25</text>
<text x="374.1" y="263.2">20/24</text>
<text x="226" y="268.4">* DRC</text>
<text x="315.4" y="268.4">Simulation filename:</text>
<text x="351" y="268.4">alu.v</text>
<text x="315.4" y="273.5">More Info: http://www.bedroomlan.org/cft</text>
</g>
<g font-size="2.5">
<text x="29" y="57.6">AC[0..15]</text>
<text x="28.5" y="65.2">UOP[0..2]</text>
<text x="28.5" y="73.7">RESET/19</text>
<text x="376.1" y="73.7">RESET/21</text>
<text x="31.5" y="78.8">UOE/18</text>
<text x="34" y="83.9">FL/19</text>
<text x="376.1" y="78.8">UOE/18</text>
<text x="376.1" y="83.9">FL/23</text>
<text x="30.8" y="89">IRQS/11</text>
<text x="376.1" y="89">IRQS/23</text>
<text x="166.4" y="93.2">Warning: each ROM receives a different subset of AC[0..15].</text>
<text x="80" y="105.9">AC0</text>
<text x="92.7" y="102.7">IC110</text>
<text x="118.1" y="105.9">IBUS0</text>
<text x="168.9" y="105.9">AC2</text>
<text x="181.6" y="102.7">IC111</text>
<text x="207" y="105.9">IBUS6</text>
<text x="262.9" y="105.9">AC0</text>
<text x="275.6" y="102.7">IC112</text>
<text x="301" y="105.9">IBUS12</text>
<text x="80" y="108.4">AC1</text>
<text x="80" y="110.9">AC2</text>
<text x="80" y="113.5">AC3</text>
<text x="118.1" y="108.4">IBUS1</text>
<text x="118.1" y="110.9">IBUS2</text>
<text x="118.1" y="113.5">IBUS3</text>
<text x="168.9" y="108.4">AC3</text>
<text x="168.9" y="110.9">AC4</text>
<text x="168.9" y="113.5">AC5</text>
<text x="207" y="108.4">IBUS7</text>
<text x="207" y="110.9">IBUS8</text>
<text x="207" y="113.5">IBUS9</text>
<text x="262.9" y="108.4">AC1</text>
<text x="262.9" y="110.9">AC2</text>
<text x="262.9" y="113.5">AC3</text>
<text x="301" y="108.4">IBUS13</text>
<text x="301" y="110.9">IBUS14</text>
<text x="301" y="113.5">IBUS15</text>
<text x="80" y="116">AC4</text>
<text x="80" y="118.6">AC5</text>
<text x="118.1" y="116">IBUS4</text>
<text x="118.1" y="118.6">IBUS5</text>
<text x="168.9" y="116">AC6</text>
<text x="168.9" y="118.6">AC7</text>
<text x="207" y="116">IBUS10</text>
<text x="207" y="118.6">IBUS11</text>
<text x="262.9" y="116">AC8</text>
<text x="262.9" y="118.6">AC9</text>
<text x="376.1" y="114.4">ROLL16/17</text>
<text x="376.1" y="119.4">ISROLL/17</text>
<text x="80" y="121.1">AC6</text>
<text x="80" y="123.6">AC7</text>
<text x="168.9" y="121.1">AC8</text>
<text x="168.9" y="123.6">AC9</text>
<text x="262.9" y="121.1">AC10</text>
<text x="262.9" y="123.6">AC11</text>
<text x="327.4" y="125.9">4k7</text>
<text x="337.5" y="125.9">4k7</text>
<text x="80" y="126.2">AC8</text>
<text x="80" y="128.7">AC9</text>
<text x="80" y="131.3">AC13</text>
<text x="168.9" y="126.2">AC10</text>
<text x="168.9" y="131.3">AC12</text>
<text x="168.9" y="128.7">AC11</text>
<text x="262.9" y="126.2">AC12</text>
<text x="262.9" y="128.7">AC13</text>
<text x="262.9" y="131.3">AC14</text>
<text x="326.8" y="128.2">R30</text>
<text x="337" y="128.2">R31</text>
<text x="80" y="133.8">AC14</text>
<text x="80" y="136.3">AC15</text>
<text x="168.9" y="133.8">AC13</text>
<text x="168.9" y="136.3">AC14</text>
<text x="262.9" y="133.8">AC15</text>
<text x="262.9" y="136.3">FL</text>
<text x="80" y="144">UOP0</text>
<text x="80" y="138.9">FL</text>
<text x="80" y="141.4">IRQS</text>
<text x="168.9" y="144">UOP0</text>
<text x="168.9" y="138.9">AC15</text>
<text x="168.9" y="141.4">IRQS</text>
<text x="262.9" y="141.4">UOP0</text>
<text x="262.9" y="144">UOP1</text>
<text x="262.9" y="138.9">IRQS</text>
<text x="331.4" y="138.9">GND</text>
<text x="341.6" y="138.9">GND</text>
<text x="80" y="146.5">UOP1</text>
<text x="80" y="149">UOP2</text>
<text x="168.9" y="146.5">UOP1</text>
<text x="168.9" y="149">UOP2</text>
<text x="262.9" y="146.5">UOP2</text>
<text x="113" y="151.6" transform="rotate(-90 113 151.6)">VCC</text>
<text x="201.9" y="151.6" transform="rotate(-90 201.9 151.6)">VCC</text>
<text x="295.9" y="151.6" transform="rotate(-90 295.9 151.6)">VCC</text>
<text x="44.4" y="159.2" transform="rotate(-90 44.4 159.2)">VCC</text>
<text x="80" y="159.2">UOE</text>
<text x="117.1" y="161.3">1uF</text>
<text x="117.1" y="156.3">C125</text>
<text x="138.4" y="159.2" transform="rotate(-90 138.4 159.2)">VCC</text>
<text x="168.9" y="159.2">UOE</text>
<text x="206" y="161.3">1uF</text>
<text x="206" y="156.3">C126</text>
<text x="227.3" y="159.2" transform="rotate(-90 227.3 159.2)">VCC</text>
<text x="262.9" y="159.2">UOE</text>
<text x="299.9" y="161.3">1uF</text>
<text x="299.9" y="156.3">C127</text>
<text x="92.7" y="166.8">29F040</text>
<text x="181.6" y="166.8">29F040</text>
<text x="275.6" y="166.8">29F040</text>
<text x="85.1" y="169.3">GND</text>
<text x="113" y="169.3">GND</text>
<text x="174" y="169.3">GND</text>
<text x="201.9" y="169.3">GND</text>
<text x="267.9" y="169.3">GND</text>
<text x="295.9" y="169.3">GND</text>
<text x="85.1" y="174.4">ROM image: alu-unary-00</text>
<text x="174" y="174.4">ROM image: alu-unary-01</text>
<text x="267.9" y="174.4">ROM image: alu-unary-02</text>
<text x="377.1" y="184.6">IBUS[0..15]</text>
<text x="44.4" y="245.5" transform="rotate(-90 44.4 245.5)">VCC</text>
<text x="57.1" y="245.5" transform="rotate(-90 57.1 245.5)">VCC</text>
<text x="32.5" y="257.9">0.1uF</text>
<text x="32.5" y="252.8">C121</text>
<text x="40.1" y="257.9">0.1uF</text>
<text x="40.1" y="252.8">C122</text>
<text x="47.7" y="257.9">0.1uF</text>
<text x="47.7" y="252.8">C123</text>
<text x="61.2" y="257.9">1uF</text>
<text x="61.2" y="252.8">C124</text>
<text x="95.2" y="260.8">ROMs to be socketed for easy re-programming.</text>
<text x="29.2" y="268.4">GND</text>
<text x="57.1" y="268.4">GND</text>
</g>
<g font-size="2.1">
<text x="90" y="105.5">12</text>
<text x="95" y="106.6">A0</text>
<text x="102.9" y="106.6">D0</text>
<text x="108.3" y="105.5">13</text>
<text x="178.9" y="105.5">12</text>
<text x="183.9" y="106.6">A0</text>
<text x="191.8" y="106.6">D0</text>
<text x="197.2" y="105.5">13</text>
<text x="272.8" y="105.5">12</text>
<text x="277.9" y="106.6">A0</text>
<text x="285.7" y="106.6">D0</text>
<text x="291.2" y="105.5">13</text>
<text x="90" y="110.6">10</text>
<text x="90" y="108">11</text>
<text x="91.2" y="113.1">9</text>
<text x="95" y="111.7">A2</text>
<text x="95" y="109.2">A1</text>
<text x="102.9" y="109.2">D1</text>
<text x="102.9" y="111.7">D2</text>
<text x="108.3" y="108">14</text>
<text x="108.3" y="110.6">15</text>
<text x="108.3" y="113.1">17</text>
<text x="178.9" y="110.6">10</text>
<text x="178.9" y="108">11</text>
<text x="180" y="113.1">9</text>
<text x="183.9" y="111.7">A2</text>
<text x="183.9" y="109.2">A1</text>
<text x="191.8" y="109.2">D1</text>
<text x="191.8" y="111.7">D2</text>
<text x="197.2" y="108">14</text>
<text x="197.2" y="110.6">15</text>
<text x="197.2" y="113.1">17</text>
<text x="272.8" y="110.6">10</text>
<text x="272.8" y="108">11</text>
<text x="274" y="113.1">9</text>
<text x="277.9" y="111.7">A2</text>
<text x="277.9" y="109.2">A1</text>
<text x="285.7" y="109.2">D1</text>
<text x="285.7" y="111.7">D2</text>
<text x="291.2" y="108">14</text>
<text x="291.2" y="110.6">15</text>
<text x="291.2" y="113.1">17</text>
<text x="91.2" y="118.2">7</text>
<text x="91.2" y="115.7">8</text>
<text x="95" y="119.3">A5</text>
<text x="95" y="116.8">A4</text>
<text x="95" y="114.2">A3</text>
<text x="102.9" y="114.2">D3</text>
<text x="102.9" y="116.8">D4</text>
<text x="102.9" y="119.3">D5</text>
<text x="108.3" y="115.7">18</text>
<text x="108.3" y="118.2">19</text>
<text x="180" y="118.2">7</text>
<text x="180" y="115.7">8</text>
<text x="183.9" y="119.3">A5</text>
<text x="183.9" y="116.8">A4</text>
<text x="183.9" y="114.2">A3</text>
<text x="191.8" y="114.2">D3</text>
<text x="191.8" y="116.8">D4</text>
<text x="191.8" y="119.3">D5</text>
<text x="197.2" y="115.7">18</text>
<text x="197.2" y="118.2">19</text>
<text x="274" y="118.2">7</text>
<text x="274" y="115.7">8</text>
<text x="277.9" y="119.3">A5</text>
<text x="277.9" y="116.8">A4</text>
<text x="277.9" y="114.2">A3</text>
<text x="285.7" y="114.2">D3</text>
<text x="285.7" y="116.8">D4</text>
<text x="285.7" y="119.3">D5</text>
<text x="291.2" y="115.7">18</text>
<text x="291.2" y="118.2">19</text>
<text x="90" y="125.8">27</text>
<text x="91.2" y="123.3">5</text>
<text x="91.2" y="120.7">6</text>
<text x="95" y="124.4">A7</text>
<text x="95" y="121.9">A6</text>
<text x="102.9" y="121.9">D6</text>
<text x="102.9" y="124.4">D7</text>
<text x="108.3" y="120.7">20</text>
<text x="108.3" y="123.3">21</text>
<text x="178.9" y="125.8">27</text>
<text x="180" y="123.3">5</text>
<text x="180" y="120.7">6</text>
<text x="183.9" y="124.4">A7</text>
<text x="183.9" y="121.9">A6</text>
<text x="191.8" y="121.9">D6</text>
<text x="191.8" y="124.4">D7</text>
<text x="197.2" y="120.7">20</text>
<text x="197.2" y="123.3">21</text>
<text x="272.8" y="125.8">27</text>
<text x="274" y="123.3">5</text>
<text x="274" y="120.7">6</text>
<text x="277.9" y="124.4">A7</text>
<text x="277.9" y="121.9">A6</text>
<text x="285.7" y="121.9">D6</text>
<text x="285.7" y="124.4">D7</text>
<text x="291.2" y="120.7">20</text>
<text x="291.2" y="123.3">21</text>
<text x="90" y="130.9">23</text>
<text x="90" y="128.4">26</text>
<text x="95" y="129.5">A9</text>
<text x="95" y="126.9">A8</text>
<text x="178.9" y="130.9">23</text>
<text x="178.9" y="128.4">26</text>
<text x="183.9" y="129.5">A9</text>
<text x="183.9" y="126.9">A8</text>
<text x="272.8" y="130.9">23</text>
<text x="272.8" y="128.4">26</text>
<text x="277.9" y="129.5">A9</text>
<text x="277.9" y="126.9">A8</text>
<text x="90" y="133.4">25</text>
<text x="91.2" y="136">4</text>
<text x="95" y="137.1">A12</text>
<text x="95" y="132">A10</text>
<text x="95" y="134.6">A11</text>
<text x="178.9" y="133.4">25</text>
<text x="180" y="136">4</text>
<text x="183.9" y="137.1">A12</text>
<text x="183.9" y="132">A10</text>
<text x="183.9" y="134.6">A11</text>
<text x="272.8" y="133.4">25</text>
<text x="274" y="136">4</text>
<text x="277.9" y="137.1">A12</text>
<text x="277.9" y="132">A10</text>
<text x="277.9" y="134.6">A11</text>
<text x="90" y="138.5">28</text>
<text x="90" y="141.1">29</text>
<text x="91.2" y="143.6">3</text>
<text x="95" y="139.6">A13</text>
<text x="95" y="142.2">A14</text>
<text x="178.9" y="138.5">28</text>
<text x="178.9" y="141.1">29</text>
<text x="180" y="143.6">3</text>
<text x="183.9" y="139.6">A13</text>
<text x="183.9" y="142.2">A14</text>
<text x="272.8" y="138.5">28</text>
<text x="272.8" y="141.1">29</text>
<text x="274" y="143.6">3</text>
<text x="277.9" y="139.6">A13</text>
<text x="277.9" y="142.2">A14</text>
<text x="90" y="148.7">30</text>
<text x="91.2" y="146.1">2</text>
<text x="95" y="144.7">A15</text>
<text x="95" y="147.3">A16</text>
<text x="95" y="149.8">A17</text>
<text x="178.9" y="148.7">30</text>
<text x="180" y="146.1">2</text>
<text x="183.9" y="144.7">A15</text>
<text x="183.9" y="147.3">A16</text>
<text x="183.9" y="149.8">A17</text>
<text x="272.8" y="148.7">30</text>
<text x="274" y="146.1">2</text>
<text x="277.9" y="144.7">A15</text>
<text x="277.9" y="147.3">A16</text>
<text x="277.9" y="149.8">A17</text>
<text x="91.2" y="151.2">1</text>
<text x="95" y="152.3">A18</text>
<text x="180" y="151.2">1</text>
<text x="183.9" y="152.3">A18</text>
<text x="274" y="151.2">1</text>
<text x="277.9" y="152.3">A18</text>
<text x="90" y="161.4">31</text>
<text x="90" y="156.3">22</text>
<text x="90" y="158.8">24</text>
<text x="95" y="157.4">CE</text>
<text x="95" y="159.9">OE</text>
<text x="178.9" y="161.4">31</text>
<text x="178.9" y="156.3">22</text>
<text x="178.9" y="158.8">24</text>
<text x="183.9" y="157.4">CE</text>
<text x="183.9" y="159.9">OE</text>
<text x="272.8" y="161.4">31</text>
<text x="272.8" y="156.3">22</text>
<text x="272.8" y="158.8">24</text>
<text x="277.9" y="157.4">CE</text>
<text x="277.9" y="159.9">OE</text>
<text x="95" y="162.5">WE</text>
<text x="183.9" y="162.5">WE</text>
<text x="277.9" y="162.5">WE</text>
</g>
</g></defs>
<g fill="#000" stroke="#000" stroke-width=".21">
<path d="M67.8 18.2v3.9zM115.3 18.2v3.9zM162.7 18.2v3.9zM210.2 18.2v3.9zM257.6 18.2v3.9zM305.1 18.2v3.9zM352.5 18.2v3.9zM20.3 22.1v252.6zM20.3 22.1h379.7zM16.5 72.6h3.8zM28.5 71.8h8.4zM31.5 76.8h5.4z"/>
<path d="M41.9 77.9h10.2zM52.1 77.9h93.9zM146 77.9h88.9zM234.9 77.9h139.7zM41.9 72.8h332.7zM376.1 76.8h5.4zM376.1 71.8h8.4zM400 72.6h3.8zM30.8 87h6.1zM41.9 83h25.4zM41.9 88.1h20.3zM62.2 88.1h94z"/>
<path d="M67.3 83h182.9zM156.2 88.1h88.9zM176.8 98.3l-.6 1.1zM177.9 96.4l-.6 1.1zM179 94.4l-.6 1.1zM245.1 88.1h129.5zM250.2 83h124.4zM376.1 87h6.2zM72.4 103.3l2.5 2.6zM72.4 105.9l2.5 2.5zM72.4 108.4l2.5 2.5zM72.4 110.9l2.5 2.6z"/>
<path d="M72.4 113.5l2.5 2.5zM72.4 116l2.5 2.6zM72.4 118.6l2.5 2.5zM74.9 105.9h15.3zM74.9 108.4h15.3zM74.9 110.9h15.3zM74.9 113.5h15.3zM74.9 116h15.3zM74.9 118.6h15.3zM90.2 118.6h2.5zM90.2 116h2.5zM90.2 113.5h2.5z"/>
<path d="M90.2 110.9h2.5zM90.2 108.4h2.5zM90.2 105.9h2.5zM107.9 105.9h2.6zM107.9 108.4h2.6zM107.9 110.9h2.6zM107.9 113.5h2.6zM107.9 116h2.6zM107.9 118.6h2.6zM110.5 105.9h20.3zM110.5 108.4h20.3zM110.5 110.9h20.3z"/>
<path d="M110.5 113.5h20.3zM110.5 116h20.3zM110.5 118.6h20.3zM133.3 103.3l-2.5 2.6zM133.3 105.9l-2.5 2.5zM133.3 108.4l-2.5 2.5zM133.3 110.9l-2.5 2.6zM133.3 113.5l-2.5 2.5zM133.3 116l-2.5 2.6zM161.3 103.3l2.5 2.6zM161.3 105.9l2.5 2.5zM161.3 108.4l2.5 2.5z"/>
<path d="M161.3 110.9l2.5 2.6zM161.3 113.5l2.5 2.5zM161.3 116l2.5 2.6zM161.3 118.6l2.5 2.5zM163.8 105.9h15.2zM163.8 108.4h15.2zM163.8 110.9h15.2zM163.8 113.5h15.2zM163.8 116h15.2zM163.8 118.6h15.2zM174.6 102.2l-.6 1.1zM175.7 100.3l-.6 1.1z"/>
<path d="M179 118.6h2.6zM179 116h2.6zM179 113.5h2.6zM179 110.9h2.6zM179 108.4h2.6zM179 105.9h2.6zM196.8 105.9h2.6zM196.8 108.4h2.6zM196.8 110.9h2.6zM196.8 113.5h2.6zM196.8 116h2.6zM196.8 118.6h2.6z"/>
<path d="M199.4 105.9h20.3zM199.4 108.4h20.3zM199.4 110.9h20.3zM199.4 113.5h20.3zM199.4 116h20.3zM199.4 118.6h20.3zM222.2 103.3l-2.5 2.6zM222.2 105.9l-2.5 2.5zM222.2 108.4l-2.5 2.5zM222.2 110.9l-2.5 2.6zM222.2 113.5l-2.5 2.5zM222.2 116l-2.5 2.6z"/>
<path d="M255.2 103.3l2.6 2.6zM255.2 105.9l2.6 2.5zM255.2 108.4l2.6 2.5zM255.2 110.9l2.6 2.6zM255.2 113.5l2.6 2.5zM255.2 116l2.6 2.6zM255.2 118.6l2.6 2.5zM257.8 105.9h15.2zM257.8 108.4h15.2zM257.8 110.9h15.2zM257.8 113.5h15.2zM257.8 116h15.2z"/>
<path d="M257.8 118.6h15.2zM273 118.6h2.6zM273 116h2.6zM273 113.5h2.6zM273 110.9h2.6zM273 108.4h2.6zM273 105.9h2.6zM290.8 105.9h2.5zM290.8 108.4h2.5zM290.8 110.9h2.5zM290.8 113.5h2.5zM290.8 116h2.5z"/>
<path d="M290.8 118.6h2.5zM293.3 116h50.8zM293.3 118.6h40.7zM293.3 105.9h22.9zM293.3 108.4h22.9zM293.3 110.9h22.9zM293.3 113.5h22.9zM318.7 103.3l-2.5 2.6zM318.7 105.9l-2.5 2.5zM316.2 110.9l2.5-2.5zM318.7 110.9l-2.5 2.6zM334 118.6h40.6z"/>
<path d="M344.1 116h28zM344.1 116v5.1zM372.1 113.5v2.5zM372.1 113.5h2.5zM16.5 123.1h3.8zM67.3 83v55.9zM72.4 121.1l2.5 2.5zM72.4 123.6l2.5 2.6zM72.4 126.2l2.5 2.5zM72.4 128.7l2.5 2.6zM72.4 131.3l2.5 2.5zM72.4 133.8l2.5 2.5z"/>
<path d="M74.9 121.1h15.3zM74.9 123.6h15.3zM74.9 126.2h15.3zM74.9 128.7h15.3zM74.9 131.3h15.3zM74.9 133.8h15.3zM74.9 136.3h15.3zM80 139.4h6.1zM90.2 136.3h2.5zM90.2 123.6h2.5zM90.2 121.1h2.5zM90.2 131.3h2.5z"/>
<path d="M90.2 133.8h2.5zM90.2 128.7h2.5zM90.2 126.2h2.5zM90.2 138.9h2.5zM67.3 138.9h22.9zM107.9 121.1h2.6zM107.9 123.6h2.6zM110.5 121.1h2.5zM110.5 123.6h2.5zM161.3 121.1l2.5 2.5zM161.3 123.6l2.5 2.6zM161.3 128.7l2.5 2.6z"/>
<path d="M161.3 131.3l2.5 2.5zM161.3 133.8l2.5 2.5zM161.3 136.3l2.5 2.6zM161.3 126.2l2.5 2.5zM163.8 121.1h15.2zM163.8 123.6h15.2zM163.8 126.2h15.2zM163.8 131.3h15.2zM163.8 133.8h15.2zM163.8 136.3h15.2zM163.8 138.9h15.2zM163.8 128.7h15.2z"/>
<path d="M168.9 139.4h6.1zM179 136.3h2.6zM179 123.6h2.6zM179 121.1h2.6zM179 131.3h2.6zM179 133.8h2.6zM179 128.7h2.6zM179 126.2h2.6zM179 138.9h2.6zM196.8 121.1h2.6zM196.8 123.6h2.6zM199.4 121.1h2.5z"/>
<path d="M199.4 123.6h2.5zM245.1 88.1v50.8zM250.2 83v53.3zM255.2 123.6l2.6 2.6zM255.2 126.2l2.6 2.5zM255.2 128.7l2.6 2.6zM255.2 131.3l2.6 2.5zM255.2 121.1l2.6 2.5zM257.8 121.1h15.2zM257.8 126.2h15.2zM257.8 128.7h15.2zM257.8 131.3h15.2z"/>
<path d="M257.8 133.8h15.2zM257.8 123.6h15.2zM262.9 136.9h6.1zM273 136.3h2.6zM273 123.6h2.6zM273 121.1h2.6zM273 131.3h2.6zM273 133.8h2.6zM273 128.7h2.6zM273 126.2h2.6zM273 138.9h2.6zM250.2 136.3h22.8z"/>
<path d="M245.1 138.9h27.9zM290.8 121.1h2.5zM290.8 123.6h2.5zM293.3 121.1h2.6zM293.3 123.6h2.6zM334 128.7v2.6zM334 121.1v2.5zM334 133.8v2.5zM334 131.3v2.5zM334 118.6v2.5zM344.1 128.7v2.6zM344.1 121.1v2.5z"/>
<path d="M344.1 133.8v2.5zM344.1 131.3v2.5zM400 123.1h3.8zM47 156.7v2.5zM52.1 77.9v81.3zM57.1 141.4l2.6 2.6zM57.1 144l2.6 2.5zM57.1 146.5l2.6 2.5zM62.2 88.1v53.3zM80 157.2h5.4zM87.6 156.7v7.6zM87.6 151.6v5.1z"/>
<path d="M90.2 156.7h2.5zM90.2 159.2h2.5zM90.2 141.4h2.5zM90.2 144h2.5zM90.2 146.5h2.5zM90.2 149h2.5zM90.2 151.6h2.5zM87.6 156.7h2.6zM87.6 151.6h2.6zM52.1 159.2h38.1zM59.7 144h30.5zM59.7 146.5h30.5z"/>
<path d="M59.7 149h30.5zM62.2 141.4h28zM95 155.8h3zM95 158.3h3.1zM115.6 149v2.6zM115.6 154.1v2.6zM115.6 156.7v.5zM115.6 158.7v.5zM115.6 151.6v2.5zM140.9 156.7v2.5zM146 77.9v81.3zM151.1 141.4l2.5 2.6z"/>
<path d="M151.1 144l2.5 2.5zM151.1 146.5l2.5 2.5zM156.2 88.1v53.3zM168.9 157.2h5.4zM176.5 156.7v7.6zM176.5 151.6v5.1zM179 156.7h2.6zM179 159.2h2.6zM179 141.4h2.6zM179 144h2.6zM179 146.5h2.6zM179 149h2.6z"/>
<path d="M179 151.6h2.6zM176.5 156.7h2.5zM176.5 151.6h2.5zM146 159.2h33zM153.6 144h25.4zM153.6 146.5h25.4zM153.6 149h25.4zM156.2 141.4h22.8zM183.9 155.8h3zM183.9 158.3h3.1zM204.4 149v2.6zM204.4 154.1v2.6z"/>
<path d="M204.4 156.7v.5zM204.4 158.7v.5zM204.4 151.6v2.5zM229.8 156.7v2.5zM234.9 77.9v81.3zM240 138.9l2.5 2.5zM240 141.4l2.5 2.6zM240 144l2.5 2.5zM262.9 157.2h5.4zM270.5 156.7v7.6zM270.5 149v2.6zM270.5 151.6v5.1z"/>
<path d="M273 156.7h2.6zM273 159.2h2.6zM273 141.4h2.6zM273 144h2.6zM273 146.5h2.6zM273 149h2.6zM273 151.6h2.6zM270.5 156.7h2.5zM270.5 149h2.5zM270.5 151.6h2.5zM234.9 159.2h38.1zM242.5 141.4h30.5z"/>
<path d="M242.5 144h30.5zM242.5 146.5h30.5zM277.9 155.8h3zM277.9 158.3h3.1zM298.4 149v2.6zM298.4 154.1v2.6zM298.4 156.7v.5zM298.4 158.7v.5zM298.4 151.6v2.5zM16.5 173.7h3.8zM47 159.2v2.5zM87.6 164.3v2.5z"/>
<path d="M90.2 161.7h2.5zM47 161.7h43.2zM95 160.8h3.5zM115.6 164.3v2.5zM115.6 159.2v2.5zM115.6 161.7v2.6zM140.9 159.2v2.5zM176.5 164.3v2.5zM179 161.7h2.6zM140.9 161.7h38.1zM183.9 160.8h3.5zM204.4 164.3v2.5z"/>
<path d="M204.4 159.2v2.5zM204.4 161.7v2.6zM229.8 159.2v2.5zM270.5 164.3v2.5zM273 161.7h2.6zM229.8 161.7h43.2zM277.9 160.8h3.4zM298.4 164.3v2.5zM298.4 159.2v2.5zM298.4 161.7v2.6zM400 173.7h3.8zM16.5 224.2h3.8z"/>
<path d="M400 224.2h3.8zM31.7 255.7v2.5zM31.7 250.6v2.5zM31.7 255.2v.5zM31.7 253.1v.6zM31.7 258.2v2.6zM31.7 248.1v2.5zM39.4 255.7v2.5zM39.4 250.6v2.5zM39.4 255.2v.5zM39.4 253.1v.6zM39.4 248.1v2.5z"/>
<path d="M31.7 248.1h7.7zM47 243v2.5zM47 255.7v2.5zM47 250.6v2.5zM47 255.2v.5zM47 253.1v.6zM39.4 248.1h7.6zM47 245.5v2.6zM47 248.1v2.5zM59.7 243v2.5zM59.7 250.6v2.5zM59.7 255.7v2.5z"/>
<path d="M59.7 253.1v.6zM59.7 255.2v.5zM59.7 245.5v5.1zM90.2 246.8v19zM90.2 246.8h106.6zM20.3 274.7h379.7zM31.7 263.3v2.5zM31.7 260.8h7.7zM31.7 260.8v2.5zM39.4 258.2v2.6zM39.4 260.8h7.6zM47 258.2v2.6z"/>
<path d="M59.7 263.3v2.5zM59.7 258.2v5.1zM67.8 274.7v3.8zM90.2 265.8h106.6zM115.3 274.7v3.8zM162.7 274.7v3.8zM196.8 246.8v19zM210.2 274.7v3.8zM257.6 274.7v3.8zM305.1 274.7v3.8zM352.5 274.7v3.8zM400 264.5v.1z"/>
<path d="M400 268.4v6.2zM400 274.6h.1zM400 22.1v252.6z"/>
<circle cx="52.1" cy="77.9" r=".51"/>
<circle cx="146" cy="77.9" r=".51"/>
<circle cx="234.9" cy="77.9" r=".51"/>
<circle cx="62.2" cy="88.1" r=".51"/>
<circle cx="67.3" cy="83" r=".51"/>
<circle cx="156.2" cy="88.1" r=".51"/>
<circle cx="245.1" cy="88.1" r=".51"/>
<circle cx="250.2" cy="83" r=".51"/>
<circle cx="334" cy="118.6" r=".51"/>
<circle cx="344.1" cy="116" r=".51"/>
<circle cx="87.6" cy="156.7" r=".51"/>
<circle cx="176.5" cy="156.7" r=".51"/>
<circle cx="270.5" cy="151.6" r=".51"/>
<circle cx="270.5" cy="156.7" r=".51"/>
<circle cx="39.4" cy="248.1" r=".51"/>
<circle cx="47" cy="248.1" r=".51"/>
<circle cx="31.7" cy="260.8" r=".51"/>
<circle cx="39.4" cy="260.8" r=".51"/>
</g>
<g fill="#000" stroke="#000" stroke-width=".28">
<path d="M26.2 71.3v3.1zM29.2 76.4v3zM29.2 76.4h11.2zM29.2 79.4h11.2zM26.2 74.4h14.2zM26.2 71.3h14.2zM40.4 76.4l1.5 1.5zM40.4 79.4l1.5-1.5zM41.9 72.8l-1.5 1.6zM40.4 71.3l1.5 1.5zM374.6 77.9l1.5-1.5zM374.6 77.9l1.5 1.5z"/>
<path d="M374.6 72.8l1.5-1.5zM374.6 72.8l1.5 1.6zM376.1 76.4h11.2zM376.1 79.4h11.2zM376.1 71.3h14.2zM376.1 74.4h14.2zM387.3 76.4v3zM390.3 71.3v3.1zM28.5 86.5v3.1zM33.1 81.5v3zM33.1 81.5h7.3zM33.1 84.5h7.3z"/>
<path d="M28.5 86.5h11.9zM28.5 89.6h11.9zM40.4 81.5l1.5 1.5zM41.9 83l-1.5 1.5zM40.4 86.5l1.5 1.6zM41.9 88.1l-1.5 1.5zM374.6 83l1.5-1.5zM374.6 83l1.5 1.5zM374.6 88.1l1.5-1.6zM374.6 88.1l1.5 1.5zM376.1 81.5h7.3zM376.1 84.5h7.3z"/>
<path d="M376.1 86.5h11.9zM376.1 89.6h11.9zM383.4 81.5v3zM388 86.5v3.1zM374.6 113.5l1.5-1.6zM374.6 113.5l1.5 1.5zM374.6 118.6l1.5-1.6zM374.6 118.6l1.5 1.5zM376.1 111.9h13.8zM376.1 115h13.8zM376.1 117h13.4zM389.5 117v3.1z"/>
<path d="M389.9 111.9v3.1zM112 120.1l2 2zM114 120.1l-2 2zM112 122.6l2 2zM114 122.6l-2 2zM200.9 120.1l2 2zM202.9 120.1l-2 2zM200.9 122.6l2 2zM202.9 122.6l-2 2zM294.9 120.1l2 2zM296.9 120.1l-2 2zM294.9 122.6l2 2z"/>
<path d="M296.9 122.6l-2 2zM332.1 136.3h3.8zM333.1 123.6v5.1zM333.1 128.7h1.8zM333.1 123.6h1.8zM334.9 123.6v5.1zM342.2 136.3h3.8zM343.2 123.6v5.1zM343.2 128.7h1.8zM343.2 123.6h1.8zM345 123.6v5.1zM376.1 120.1h13.4z"/>
<path d="M47 156.7l-1.3 1.9zM47 156.7l1.3 1.9zM115.6 149l-1.3 1.9zM115.6 149l1.2 1.9zM140.9 156.7l-1.2 1.9zM140.9 156.7l1.3 1.9zM204.4 149l-1.2 1.9zM204.4 149l1.3 1.9zM229.8 156.7l-1.2 1.9zM229.8 156.7l1.3 1.9zM298.4 149l-1.2 1.9zM298.4 149l1.3 1.9z"/>
<path d="M85.7 166.8h3.8zM113.7 166.8h3.8zM174.6 166.8h3.8zM202.5 166.8h3.9zM268.6 166.8h3.8zM296.5 166.8h3.8zM47 243l-1.3 1.9zM47 243l1.3 1.9zM59.7 243l-1.3 1.9zM59.7 243l1.3 1.9zM313.7 249.3h86.3zM313.7 254.4h86.3z"/>
<path d="M313.7 259.5h58.4zM372.1 259.5h27.9zM372.1 259.5v5.1zM29.8 265.8h3.9zM57.8 265.8h3.8zM313.7 264.6h58.4zM313.7 269.7h86.3zM372.1 264.6h27.9zM400 268.4v1.3z"/>
</g>
<path d="M16.5 18.2v260.3zM16.5 18.2h387.3zM16.5 278.5h387.3zM403.8 18.2v260.3z" fill="#000" stroke="#000" stroke-width=".32"/>
<g fill="#000" stroke="#000" stroke-width=".61">
<path d="M20.3 22.1v252.6zM20.3 22.1h379.7zM92.7 103.3v61zM92.7 103.3h15.2zM181.6 103.3v61zM181.6 103.3h15.2zM275.6 103.3v61zM275.6 103.3h15.2zM92.7 164.3h15.2zM107.9 103.3v61zM181.6 164.3h15.2zM196.8 103.3v61z"/>
<path d="M275.6 164.3h15.2zM290.8 103.3v61zM283.2 244.3v30.4zM313.7 254.4v5.1zM313.7 249.3v5.1zM313.7 244.3v5zM313.7 244.3h86.3zM283.2 244.3h30.5zM400 254.4v5.1zM400 249.3v5.1zM400 244.3v5zM400 22.1v222.2z"/>
<path d="M20.3 274.7h262.9zM283.2 274.7h30.5zM313.7 274.7h86.3zM313.7 269.7v5zM313.7 264.6v5.1zM313.7 259.5v5.1zM400 268.4v6.3zM400 264.6v3.8zM400 259.5v5.1z"/>
</g>
<g fill="#000" stroke="#000" stroke-width=".21">
<path d="M113.5 158.2h4.1v.5h-4.1zM113.5 157.2h4.1v.5h-4.1zM202.4 158.2h4.1v.5h-4.1zM202.4 157.2h4.1v.5h-4.1zM296.4 158.2h4.1v.5h-4.1zM296.4 157.2h4.1v.5h-4.1zM29.7 253.7h4.1v.5h-4.1zM29.7 254.7h4.1v.5h-4.1zM37.3 253.7h4.1v.5h-4.1zM37.3 254.7h4.1v.5h-4.1zM45 253.7h4v.5h-4zM45 254.7h4v.5h-4z"/>
<path d="M57.7 254.7h4v.5h-4zM57.7 253.7h4v.5h-4zM254 253.1h25.4v10.2h-25.4z"/>
</g>
<g fill="#000" stroke="#000" stroke-width=".76">
<path d="M41.9 57.6h25.4zM67.3 57.6h182.9zM67.3 57.6l5.1 5.1zM156.2 57.6l5.1 5.1zM250.2 57.6l5 5.1zM41.9 65.2h10.2zM52.1 65.2h93.9zM52.1 65.2l5 5.1zM57.1 70.3v76.2zM72.4 62.7v71.1zM146 65.2h88.9zM146 65.2l5.1 5.1z"/>
<path d="M151.1 70.3v76.2zM161.3 62.7v73.6zM234.9 65.2l5.1 5.1zM240 70.3v73.7zM255.2 62.7v68.6zM133.3 103.3v76.2zM133.3 179.5l5.1 5.1zM222.2 103.3v76.2zM222.2 179.5l5.1 5.1zM318.7 103.3v76.2zM318.7 179.5l5.1 5.1zM138.4 184.6h236.2z"/>
</g>
<path d="M223.5 253.1v10.2zM223.5 253.1h55.9zM223.5 263.3v7.6zM223.5 270.9h55.9zM223.5 263.3h55.9zM279.4 263.3v7.6zM279.4 253.1v10.2z" fill="#000" stroke="#000" stroke-width=".42"/>
<use href="#words"/>
</svg>
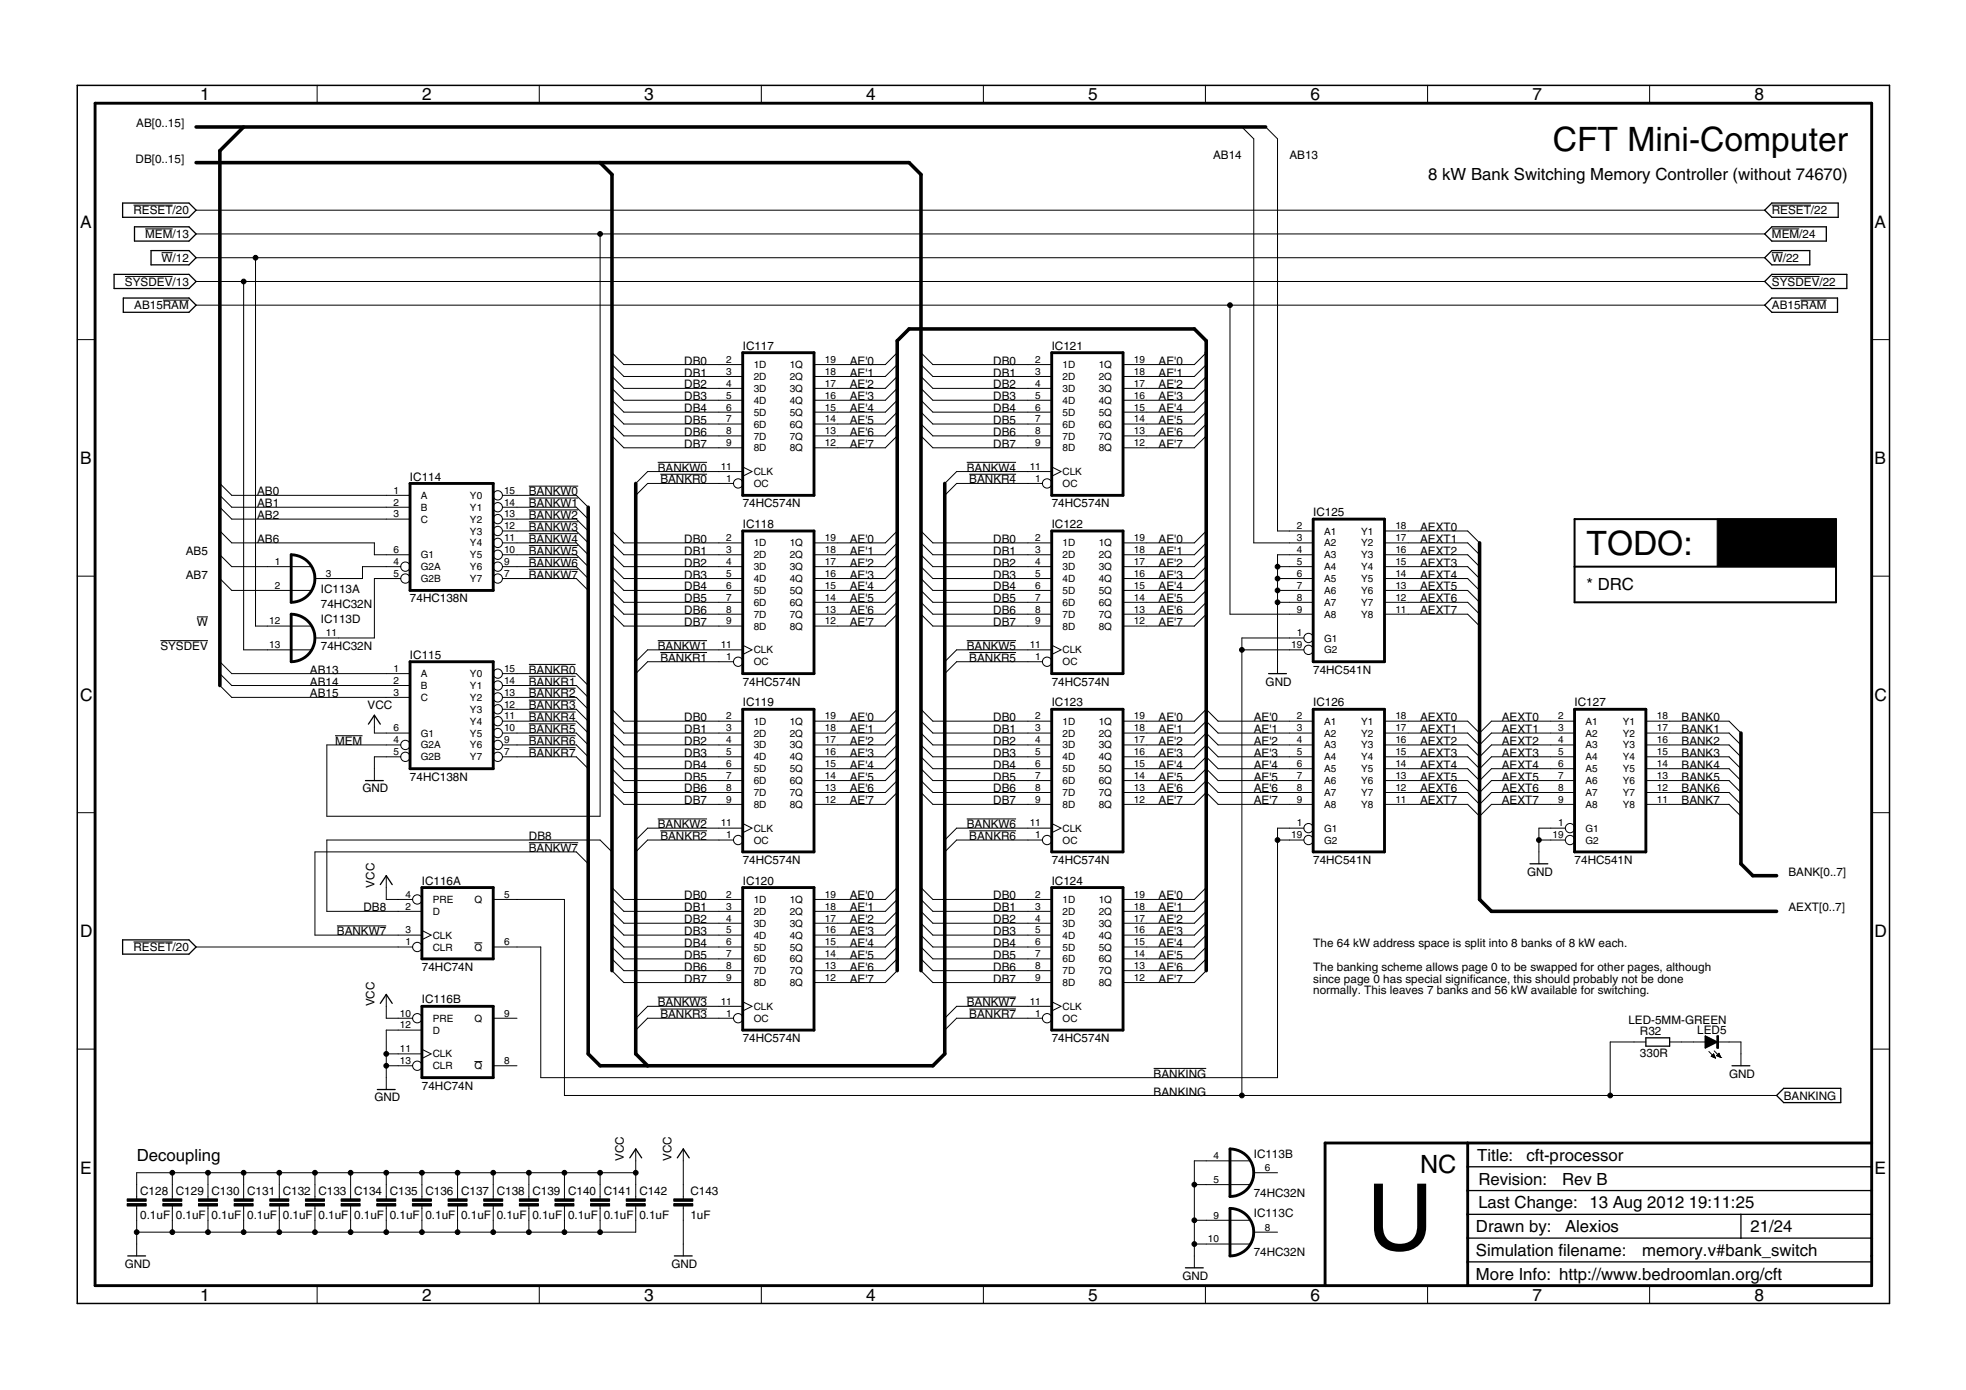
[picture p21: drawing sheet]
<svg xmlns="http://www.w3.org/2000/svg" width="420mm" height="297mm" viewBox="0 0 420 297" stroke-linecap="round" stroke-linejoin="round" font-family="sans-serif">
<defs><g id="words">
<text font-size="19.7" x="292.1" y="267.1">U</text>
<g font-size="7.2">
<text x="331.8" y="32.2">CFT Mini-Computer</text>
<text x="339.1" y="118.6">TODO:</text>
</g>
<text font-size="5.4" x="303.5" y="250.6">NC</text>
<g font-size="3.7">
<text x="42.7" y="21.5">1</text>
<text x="90.2" y="21.5">2</text>
<text x="137.7" y="21.5">3</text>
<text x="185.1" y="21.5">4</text>
<text x="232.6" y="21.5">5</text>
<text x="280" y="21.5">6</text>
<text x="327.5" y="21.5">7</text>
<text x="375" y="21.5">8</text>
<text x="17.1" y="48.6">A</text>
<text x="400.6" y="48.6">A</text>
<text x="17.1" y="99.2">B</text>
<text x="400.6" y="99.2">B</text>
<text x="17.1" y="149.7">C</text>
<text x="400.6" y="149.7">C</text>
<text x="17.1" y="200.2">D</text>
<text x="400.6" y="200.2">D</text>
<text x="17.1" y="250.8">E</text>
<text x="400.6" y="250.8">E</text>
<text x="42.7" y="277.9">1</text>
<text x="90.2" y="277.9">2</text>
<text x="137.7" y="277.9">3</text>
<text x="185.1" y="277.9">4</text>
<text x="232.6" y="277.9">5</text>
<text x="280" y="277.9">6</text>
<text x="327.5" y="277.9">7</text>
<text x="375" y="277.9">8</text>
</g>
<g font-size="3.6">
<text x="305.2" y="38.6">8 kW Bank Switching Memory Controller (without 74670)</text>
<text x="339.1" y="126.2">* DRC</text>
<text x="29.2" y="248.1">Decoupling</text>
<text x="315.7" y="248.1">Title:</text>
<text x="326.2" y="248.2">cft-processor</text>
<text x="315.9" y="253.2">Revision:</text>
<text x="333.8" y="253.3">Rev B</text>
<text x="315.4" y="263.3">Drawn by:</text>
<text x="315.9" y="258.2">Last Change: 13 Aug 2012</text>
<text x="334.5" y="263.3">Alexios</text>
<text x="361" y="258.1">19:11:25</text>
<text x="374.1" y="263.2">21/24</text>
<text x="315.4" y="268.4">Simulation filename:</text>
<text x="351" y="268.4">memory.v#bank_switch</text>
<text x="315.4" y="273.5">More Info: http://www.bedroomlan.org/cft</text>
</g>
<g font-size="2.5">
<text x="29.1" y="27.1">AB[0..15]</text>
<text x="29" y="34.7">DB[0..15]</text>
<text x="259.3" y="34">AB14</text>
<text x="275.6" y="34">AB13</text>
<text x="28.5" y="45.8">RESET/20</text>
<text x="378.7" y="45.8">RESET/22</text>
<text x="31" y="50.9">MEM/13</text>
<text x="378.7" y="50.9">MEM/24</text>
<text x="34.5" y="56">W/12</text>
<text x="378.7" y="56">W/22</text>
<text x="26.7" y="61">SYSDEV/13</text>
<text x="378.7" y="61">SYSDEV/22</text>
<text x="28.7" y="66.1">AB15RAM</text>
<text x="378.7" y="66.1">AB15RAM</text>
<text x="146.2" y="77.9">DB0</text>
<text x="158.7" y="74.7">IC117</text>
<text x="181.6" y="77.9">AE'0</text>
<text x="212.3" y="77.9">DB0</text>
<text x="224.8" y="74.7">IC121</text>
<text x="247.6" y="77.9">AE'0</text>
<text x="146.2" y="80.5">DB1</text>
<text x="146.2" y="83">DB2</text>
<text x="181.6" y="80.5">AE'1</text>
<text x="181.6" y="83">AE'2</text>
<text x="212.3" y="80.5">DB1</text>
<text x="212.3" y="83">DB2</text>
<text x="247.6" y="80.5">AE'1</text>
<text x="247.6" y="83">AE'2</text>
<text x="146.2" y="85.5">DB3</text>
<text x="146.2" y="88.1">DB4</text>
<text x="181.6" y="85.5">AE'3</text>
<text x="181.6" y="88.1">AE'4</text>
<text x="212.3" y="85.5">DB3</text>
<text x="212.3" y="88.1">DB4</text>
<text x="247.6" y="85.5">AE'3</text>
<text x="247.6" y="88.1">AE'4</text>
<text x="146.2" y="90.6">DB5</text>
<text x="146.2" y="93.2">DB6</text>
<text x="146.2" y="95.7">DB7</text>
<text x="181.6" y="90.6">AE'5</text>
<text x="181.6" y="93.2">AE'6</text>
<text x="181.6" y="95.7">AE'7</text>
<text x="212.3" y="90.6">DB5</text>
<text x="212.3" y="93.2">DB6</text>
<text x="212.3" y="95.7">DB7</text>
<text x="247.6" y="90.6">AE'5</text>
<text x="247.6" y="93.2">AE'6</text>
<text x="247.6" y="95.7">AE'7</text>
<text x="140.6" y="100.8">BANKW0</text>
<text x="206.6" y="100.8">BANKW4</text>
<text x="54.9" y="105.9">AB0</text>
<text x="87.6" y="102.7">IC114</text>
<text x="113" y="105.9">BANKW0</text>
<text x="141.1" y="103.3">BANKR0</text>
<text x="207.2" y="103.3">BANKR4</text>
<text x="54.9" y="110.9">AB2</text>
<text x="54.9" y="108.4">AB1</text>
<text x="113" y="108.4">BANKW1</text>
<text x="113" y="110.9">BANKW2</text>
<text x="113" y="113.5">BANKW3</text>
<text x="158.7" y="108.4">74HC574N</text>
<text x="158.7" y="112.8">IC118</text>
<text x="224.8" y="108.4">74HC574N</text>
<text x="224.8" y="112.8">IC122</text>
<text x="280.6" y="110.3">IC125</text>
<text x="303.5" y="113.5">AEXT0</text>
<text x="39.7" y="118.6">AB5</text>
<text x="54.9" y="116">AB6</text>
<text x="113" y="116">BANKW4</text>
<text x="113" y="118.6">BANKW5</text>
<text x="146.2" y="116">DB0</text>
<text x="146.2" y="118.6">DB1</text>
<text x="181.6" y="116">AE'0</text>
<text x="181.6" y="118.6">AE'1</text>
<text x="212.3" y="116">DB0</text>
<text x="212.3" y="118.6">DB1</text>
<text x="247.6" y="116">AE'0</text>
<text x="247.6" y="118.6">AE'1</text>
<text x="303.5" y="116">AEXT1</text>
<text x="303.5" y="118.6">AEXT2</text>
<text x="39.7" y="123.6">AB7</text>
<text x="113" y="121.1">BANKW6</text>
<text x="113" y="123.6">BANKW7</text>
<text x="146.2" y="121.1">DB2</text>
<text x="146.2" y="123.6">DB3</text>
<text x="181.6" y="121.1">AE'2</text>
<text x="181.6" y="123.6">AE'3</text>
<text x="212.3" y="121.1">DB2</text>
<text x="212.3" y="123.6">DB3</text>
<text x="247.6" y="121.1">AE'2</text>
<text x="247.6" y="123.6">AE'3</text>
<text x="303.5" y="121.1">AEXT3</text>
<text x="303.5" y="123.6">AEXT4</text>
<text x="68.6" y="130">74HC32N</text>
<text x="68.6" y="126.8">IC113A</text>
<text x="87.6" y="128.7">74HC138N</text>
<text x="146.2" y="126.2">DB4</text>
<text x="146.2" y="128.7">DB5</text>
<text x="146.2" y="131.3">DB6</text>
<text x="181.6" y="126.2">AE'4</text>
<text x="181.6" y="128.7">AE'5</text>
<text x="181.6" y="131.3">AE'6</text>
<text x="212.3" y="126.2">DB4</text>
<text x="212.3" y="128.7">DB5</text>
<text x="212.3" y="131.3">DB6</text>
<text x="247.6" y="126.2">AE'4</text>
<text x="247.6" y="128.7">AE'5</text>
<text x="247.6" y="131.3">AE'6</text>
<text x="303.5" y="126.2">AEXT5</text>
<text x="303.5" y="128.7">AEXT6</text>
<text x="303.5" y="131.3">AEXT7</text>
<text x="42.1" y="133.8">W</text>
<text x="68.6" y="133.2">IC113D</text>
<text x="146.2" y="133.8">DB7</text>
<text x="181.6" y="133.8">AE'7</text>
<text x="212.3" y="133.8">DB7</text>
<text x="247.6" y="133.8">AE'7</text>
<text x="34.3" y="138.9">SYSDEV</text>
<text x="66.2" y="144">AB13</text>
<text x="68.6" y="138.9">74HC32N</text>
<text x="87.6" y="140.8">IC115</text>
<text x="113" y="144">BANKR0</text>
<text x="140.6" y="138.9">BANKW1</text>
<text x="141.1" y="141.4">BANKR1</text>
<text x="206.6" y="138.9">BANKW5</text>
<text x="207.2" y="141.4">BANKR5</text>
<text x="280.6" y="144">74HC541N</text>
<text x="66.2" y="146.5">AB14</text>
<text x="66.2" y="149">AB15</text>
<text x="113" y="146.5">BANKR1</text>
<text x="113" y="149">BANKR2</text>
<text x="158.7" y="146.5">74HC574N</text>
<text x="224.8" y="146.5">74HC574N</text>
<text x="270.5" y="146.5">GND</text>
<text x="78.5" y="151.6">VCC</text>
<text x="113" y="151.6">BANKR3</text>
<text x="113" y="154.1">BANKR4</text>
<text x="146.2" y="154.1">DB0</text>
<text x="158.7" y="150.9">IC119</text>
<text x="181.6" y="154.1">AE'0</text>
<text x="212.3" y="154.1">DB0</text>
<text x="224.8" y="150.9">IC123</text>
<text x="247.6" y="154.1">AE'0</text>
<text x="267.9" y="154.1">AE'0</text>
<text x="280.6" y="150.9">IC126</text>
<text x="303.5" y="154.1">AEXT0</text>
<text x="320.9" y="154.1">AEXT0</text>
<text x="336.5" y="150.9">IC127</text>
<text x="359.4" y="154.1">BANK0</text>
<text x="71.6" y="159.2">MEM</text>
<text x="113" y="156.6">BANKR5</text>
<text x="113" y="159.2">BANKR6</text>
<text x="113" y="161.7">BANKR7</text>
<text x="146.2" y="156.6">DB1</text>
<text x="146.2" y="159.2">DB2</text>
<text x="146.2" y="161.7">DB3</text>
<text x="181.6" y="156.6">AE'1</text>
<text x="181.6" y="159.2">AE'2</text>
<text x="181.6" y="161.7">AE'3</text>
<text x="212.3" y="156.6">DB1</text>
<text x="212.3" y="159.2">DB2</text>
<text x="212.3" y="161.7">DB3</text>
<text x="247.6" y="156.6">AE'1</text>
<text x="247.6" y="159.2">AE'2</text>
<text x="247.6" y="161.7">AE'3</text>
<text x="267.9" y="156.6">AE'1</text>
<text x="267.9" y="159.2">AE'2</text>
<text x="267.9" y="161.7">AE'3</text>
<text x="303.5" y="156.6">AEXT1</text>
<text x="303.5" y="159.2">AEXT2</text>
<text x="303.5" y="161.7">AEXT3</text>
<text x="320.9" y="156.6">AEXT1</text>
<text x="320.9" y="159.2">AEXT2</text>
<text x="320.9" y="161.7">AEXT3</text>
<text x="359.4" y="156.6">BANK1</text>
<text x="359.4" y="159.2">BANK2</text>
<text x="359.4" y="161.7">BANK3</text>
<text x="87.6" y="166.8">74HC138N</text>
<text x="146.2" y="164.3">DB4</text>
<text x="146.2" y="166.8">DB5</text>
<text x="181.6" y="164.3">AE'4</text>
<text x="181.6" y="166.8">AE'5</text>
<text x="212.3" y="164.3">DB4</text>
<text x="212.3" y="166.8">DB5</text>
<text x="247.6" y="164.3">AE'4</text>
<text x="247.6" y="166.8">AE'5</text>
<text x="267.9" y="164.3">AE'4</text>
<text x="267.9" y="166.8">AE'5</text>
<text x="303.5" y="164.3">AEXT4</text>
<text x="303.5" y="166.8">AEXT5</text>
<text x="320.9" y="164.3">AEXT4</text>
<text x="320.9" y="166.8">AEXT5</text>
<text x="359.4" y="164.3">BANK4</text>
<text x="359.4" y="166.8">BANK5</text>
<text x="77.5" y="169.3">GND</text>
<text x="146.2" y="169.3">DB6</text>
<text x="146.2" y="171.9">DB7</text>
<text x="181.6" y="169.3">AE'6</text>
<text x="181.6" y="171.9">AE'7</text>
<text x="212.3" y="169.3">DB6</text>
<text x="212.3" y="171.9">DB7</text>
<text x="247.6" y="169.3">AE'6</text>
<text x="247.6" y="171.9">AE'7</text>
<text x="267.9" y="169.3">AE'6</text>
<text x="267.9" y="171.9">AE'7</text>
<text x="303.5" y="169.3">AEXT6</text>
<text x="303.5" y="171.9">AEXT7</text>
<text x="320.9" y="169.3">AEXT6</text>
<text x="320.9" y="171.9">AEXT7</text>
<text x="359.4" y="169.3">BANK6</text>
<text x="359.4" y="171.9">BANK7</text>
<text x="113" y="179.5">DB8</text>
<text x="140.6" y="177">BANKW2</text>
<text x="141.1" y="179.5">BANKR2</text>
<text x="206.6" y="177">BANKW6</text>
<text x="207.2" y="179.5">BANKR6</text>
<text x="113" y="182">BANKW7</text>
<text x="158.7" y="184.6">74HC574N</text>
<text x="224.8" y="184.6">74HC574N</text>
<text x="280.6" y="184.6">74HC541N</text>
<text x="336.5" y="184.6">74HC541N</text>
<text x="80" y="189.7" transform="rotate(-90 80 189.7)">VCC</text>
<text x="90.2" y="189">IC116A</text>
<text x="158.7" y="189">IC120</text>
<text x="224.8" y="189">IC124</text>
<text x="326.4" y="187.1">GND</text>
<text x="382.2" y="187.1">BANK[0..7]</text>
<text x="77.7" y="194.7">DB8</text>
<text x="146.2" y="192.2">DB0</text>
<text x="146.2" y="194.7">DB1</text>
<text x="146.2" y="197.3">DB2</text>
<text x="181.6" y="192.2">AE'0</text>
<text x="181.6" y="194.7">AE'1</text>
<text x="181.6" y="197.3">AE'2</text>
<text x="212.3" y="192.2">DB0</text>
<text x="212.3" y="194.7">DB1</text>
<text x="212.3" y="197.3">DB2</text>
<text x="247.6" y="192.2">AE'0</text>
<text x="247.6" y="194.7">AE'1</text>
<text x="247.6" y="197.3">AE'2</text>
<text x="382.2" y="194.7">AEXT[0..7]</text>
<text x="28.5" y="203.2">RESET/20</text>
<text x="72" y="199.8">BANKW7</text>
<text x="146.2" y="199.8">DB3</text>
<text x="146.2" y="202.4">DB4</text>
<text x="181.6" y="199.8">AE'3</text>
<text x="181.6" y="202.4">AE'4</text>
<text x="212.3" y="199.8">DB3</text>
<text x="212.3" y="202.4">DB4</text>
<text x="247.6" y="199.8">AE'3</text>
<text x="247.6" y="202.4">AE'4</text>
<text x="280.6" y="202.4">The 64 kW address space is split into 8 banks of 8 kW each.</text>
<text x="90.2" y="207.4">74HC74N</text>
<text x="146.2" y="204.9">DB5</text>
<text x="146.2" y="207.4">DB6</text>
<text x="146.2" y="210">DB7</text>
<text x="181.6" y="204.9">AE'5</text>
<text x="181.6" y="207.4">AE'6</text>
<text x="181.6" y="210">AE'7</text>
<text x="212.3" y="204.9">DB5</text>
<text x="212.3" y="207.4">DB6</text>
<text x="212.3" y="210">DB7</text>
<text x="247.6" y="204.9">AE'5</text>
<text x="247.6" y="207.4">AE'6</text>
<text x="247.6" y="210">AE'7</text>
<text x="280.6" y="207.4">The banking scheme allows page 0 to be swapped for other pages, although</text>
<text x="280.6" y="210">since page 0 has special significance, this should probably not be done</text>
<text x="80" y="215.1" transform="rotate(-90 80 215.1)">VCC</text>
<text x="90.2" y="214.4">IC116B</text>
<text x="140.6" y="215.1">BANKW3</text>
<text x="206.6" y="215.1">BANKW7</text>
<text x="280.6" y="212.5">normally. This leaves 7 banks and 56 kW available for switching.</text>
<text x="141.1" y="217.6">BANKR3</text>
<text x="207.2" y="217.6">BANKR7</text>
<text x="348" y="218.7">LED-5MM-GREEN</text>
<text x="350.5" y="221.2">R32</text>
<text x="362.7" y="220.9">LED5</text>
<text x="158.7" y="222.7">74HC574N</text>
<text x="224.8" y="222.7">74HC574N</text>
<text x="350.5" y="226">330R</text>
<text x="90.2" y="232.8">74HC74N</text>
<text x="246.5" y="230.3">BANKING</text>
<text x="369.5" y="230.3">GND</text>
<text x="80" y="235.4">GND</text>
<text x="246.5" y="234.1">BANKING</text>
<text x="381.2" y="235">BANKING</text>
<text x="133.3" y="248.1" transform="rotate(-90 133.3 248.1)">VCC</text>
<text x="143.5" y="248.1" transform="rotate(-90 143.5 248.1)">VCC</text>
<text x="267.9" y="247.4">IC113B</text>
<text x="30" y="255.3">C128</text>
<text x="37.6" y="255.3">C129</text>
<text x="45.2" y="255.3">C130</text>
<text x="52.8" y="255.3">C131</text>
<text x="60.4" y="255.3">C132</text>
<text x="68.1" y="255.3">C133</text>
<text x="75.7" y="255.3">C134</text>
<text x="83.3" y="255.3">C135</text>
<text x="90.9" y="255.3">C136</text>
<text x="98.5" y="255.3">C137</text>
<text x="106.2" y="255.3">C138</text>
<text x="113.8" y="255.3">C139</text>
<text x="121.4" y="255.3">C140</text>
<text x="129" y="255.3">C141</text>
<text x="136.6" y="255.3">C142</text>
<text x="147.6" y="255.3">C143</text>
<text x="267.9" y="255.7">74HC32N</text>
<text x="30" y="260.4">0.1uF</text>
<text x="37.6" y="260.4">0.1uF</text>
<text x="45.2" y="260.4">0.1uF</text>
<text x="52.8" y="260.4">0.1uF</text>
<text x="60.4" y="260.4">0.1uF</text>
<text x="68.1" y="260.4">0.1uF</text>
<text x="75.7" y="260.4">0.1uF</text>
<text x="83.3" y="260.4">0.1uF</text>
<text x="90.9" y="260.4">0.1uF</text>
<text x="98.5" y="260.4">0.1uF</text>
<text x="106.2" y="260.4">0.1uF</text>
<text x="113.8" y="260.4">0.1uF</text>
<text x="121.4" y="260.4">0.1uF</text>
<text x="129" y="260.4">0.1uF</text>
<text x="136.6" y="260.4">0.1uF</text>
<text x="147.6" y="260.4">1uF</text>
<text x="267.9" y="260.1">IC113C</text>
<text x="267.9" y="268.4">74HC32N</text>
<text x="26.7" y="270.9">GND</text>
<text x="143.5" y="270.9">GND</text>
<text x="252.7" y="273.5">GND</text>
</g>
<g font-size="2.1">
<text x="155.2" y="77.6">2</text>
<text x="176.3" y="77.6">19</text>
<text x="221.2" y="77.6">2</text>
<text x="242.3" y="77.6">19</text>
<text x="155.2" y="80.1">3</text>
<text x="155.2" y="82.6">4</text>
<text x="161.1" y="78.7">1D</text>
<text x="161.1" y="81.2">2D</text>
<text x="161.1" y="83.8">3D</text>
<text x="168.8" y="83.8">3Q</text>
<text x="168.8" y="81.2">2Q</text>
<text x="168.8" y="78.7">1Q</text>
<text x="176.3" y="82.6">17</text>
<text x="176.3" y="80.1">18</text>
<text x="221.2" y="80.1">3</text>
<text x="221.2" y="82.6">4</text>
<text x="227.1" y="78.7">1D</text>
<text x="227.1" y="81.2">2D</text>
<text x="227.1" y="83.8">3D</text>
<text x="234.8" y="83.8">3Q</text>
<text x="234.8" y="81.2">2Q</text>
<text x="234.8" y="78.7">1Q</text>
<text x="242.3" y="82.6">17</text>
<text x="242.3" y="80.1">18</text>
<text x="155.2" y="85.2">5</text>
<text x="155.2" y="87.7">6</text>
<text x="161.1" y="86.3">4D</text>
<text x="161.1" y="88.8">5D</text>
<text x="168.8" y="88.8">5Q</text>
<text x="168.8" y="86.3">4Q</text>
<text x="176.3" y="87.7">15</text>
<text x="176.3" y="85.2">16</text>
<text x="221.2" y="85.2">5</text>
<text x="221.2" y="87.7">6</text>
<text x="227.1" y="86.3">4D</text>
<text x="227.1" y="88.8">5D</text>
<text x="234.8" y="88.8">5Q</text>
<text x="234.8" y="86.3">4Q</text>
<text x="242.3" y="87.7">15</text>
<text x="242.3" y="85.2">16</text>
<text x="155.2" y="90.3">7</text>
<text x="155.2" y="92.8">8</text>
<text x="155.2" y="95.3">9</text>
<text x="161.1" y="91.4">6D</text>
<text x="161.1" y="93.9">7D</text>
<text x="168.8" y="93.9">7Q</text>
<text x="168.8" y="91.4">6Q</text>
<text x="176.3" y="95.3">12</text>
<text x="176.3" y="92.8">13</text>
<text x="176.3" y="90.3">14</text>
<text x="221.2" y="90.3">7</text>
<text x="221.2" y="92.8">8</text>
<text x="221.2" y="95.3">9</text>
<text x="227.1" y="91.4">6D</text>
<text x="227.1" y="93.9">7D</text>
<text x="234.8" y="93.9">7Q</text>
<text x="234.8" y="91.4">6Q</text>
<text x="242.3" y="95.3">12</text>
<text x="242.3" y="92.8">13</text>
<text x="242.3" y="90.3">14</text>
<text x="154" y="100.4">11</text>
<text x="161.1" y="96.5">8D</text>
<text x="161.1" y="101.5">CLK</text>
<text x="168.8" y="96.5">8Q</text>
<text x="220.1" y="100.4">11</text>
<text x="227.1" y="96.5">8D</text>
<text x="227.1" y="101.5">CLK</text>
<text x="234.8" y="96.5">8Q</text>
<text x="84.1" y="105.5">1</text>
<text x="90" y="106.6">A</text>
<text x="100.4" y="106.6">Y0</text>
<text x="107.7" y="105.5">15</text>
<text x="155.2" y="103">1</text>
<text x="161.1" y="104.1">OC</text>
<text x="221.2" y="103">1</text>
<text x="227.1" y="104.1">OC</text>
<text x="84.1" y="108">2</text>
<text x="84.1" y="110.6">3</text>
<text x="90" y="109.2">B</text>
<text x="90" y="111.7">C</text>
<text x="100.4" y="111.7">Y2</text>
<text x="100.4" y="109.2">Y1</text>
<text x="107.7" y="113.1">12</text>
<text x="107.7" y="110.6">13</text>
<text x="107.7" y="108">14</text>
<text x="277.1" y="113.1">2</text>
<text x="298.2" y="113.1">18</text>
<text x="84.1" y="118.2">6</text>
<text x="90" y="119.3">G1</text>
<text x="100.4" y="119.3">Y5</text>
<text x="100.4" y="116.8">Y4</text>
<text x="100.4" y="114.2">Y3</text>
<text x="107.7" y="118.2">10</text>
<text x="107.7" y="115.7">11</text>
<text x="155.2" y="115.7">2</text>
<text x="155.2" y="118.2">3</text>
<text x="161.1" y="116.8">1D</text>
<text x="161.1" y="119.3">2D</text>
<text x="168.8" y="119.3">2Q</text>
<text x="168.8" y="116.8">1Q</text>
<text x="176.3" y="118.2">18</text>
<text x="176.3" y="115.7">19</text>
<text x="221.2" y="115.7">2</text>
<text x="221.2" y="118.2">3</text>
<text x="227.1" y="116.8">1D</text>
<text x="227.1" y="119.3">2D</text>
<text x="234.8" y="119.3">2Q</text>
<text x="234.8" y="116.8">1Q</text>
<text x="242.3" y="118.2">18</text>
<text x="242.3" y="115.7">19</text>
<text x="277.1" y="115.7">3</text>
<text x="277.1" y="118.2">4</text>
<text x="283" y="114.2">A1</text>
<text x="283" y="116.8">A2</text>
<text x="283" y="119.3">A3</text>
<text x="290.9" y="119.3">Y3</text>
<text x="290.9" y="116.8">Y2</text>
<text x="290.9" y="114.2">Y1</text>
<text x="298.2" y="118.2">16</text>
<text x="298.2" y="115.7">17</text>
<text x="58.7" y="120.7">1</text>
<text x="58.7" y="125.8">2</text>
<text x="69.6" y="123.3">3</text>
<text x="84.1" y="120.7">4</text>
<text x="84.1" y="123.3">5</text>
<text x="90" y="121.9">G2A</text>
<text x="90" y="124.4">G2B</text>
<text x="100.4" y="124.4">Y7</text>
<text x="100.4" y="121.9">Y6</text>
<text x="107.7" y="123.3">7</text>
<text x="107.7" y="120.7">9</text>
<text x="155.2" y="120.7">4</text>
<text x="155.2" y="123.3">5</text>
<text x="155.2" y="125.8">6</text>
<text x="161.1" y="121.9">3D</text>
<text x="161.1" y="124.4">4D</text>
<text x="168.8" y="124.4">4Q</text>
<text x="168.8" y="121.9">3Q</text>
<text x="176.3" y="125.8">15</text>
<text x="176.3" y="123.3">16</text>
<text x="176.3" y="120.7">17</text>
<text x="221.2" y="120.7">4</text>
<text x="221.2" y="123.3">5</text>
<text x="221.2" y="125.8">6</text>
<text x="227.1" y="121.9">3D</text>
<text x="227.1" y="124.4">4D</text>
<text x="234.8" y="124.4">4Q</text>
<text x="234.8" y="121.9">3Q</text>
<text x="242.3" y="125.8">15</text>
<text x="242.3" y="123.3">16</text>
<text x="242.3" y="120.7">17</text>
<text x="277.1" y="120.7">5</text>
<text x="277.1" y="123.3">6</text>
<text x="277.1" y="125.8">7</text>
<text x="283" y="121.9">A4</text>
<text x="283" y="124.4">A5</text>
<text x="290.9" y="124.4">Y5</text>
<text x="290.9" y="121.9">Y4</text>
<text x="298.2" y="125.8">13</text>
<text x="298.2" y="123.3">14</text>
<text x="298.2" y="120.7">15</text>
<text x="155.2" y="128.4">7</text>
<text x="155.2" y="130.9">8</text>
<text x="161.1" y="126.9">5D</text>
<text x="161.1" y="129.5">6D</text>
<text x="168.8" y="129.5">6Q</text>
<text x="168.8" y="126.9">5Q</text>
<text x="176.3" y="130.9">13</text>
<text x="176.3" y="128.4">14</text>
<text x="221.2" y="128.4">7</text>
<text x="221.2" y="130.9">8</text>
<text x="227.1" y="126.9">5D</text>
<text x="227.1" y="129.5">6D</text>
<text x="234.8" y="129.5">6Q</text>
<text x="234.8" y="126.9">5Q</text>
<text x="242.3" y="130.9">13</text>
<text x="242.3" y="128.4">14</text>
<text x="277.1" y="128.4">8</text>
<text x="277.1" y="130.9">9</text>
<text x="283" y="126.9">A6</text>
<text x="283" y="129.5">A7</text>
<text x="290.9" y="129.5">Y7</text>
<text x="290.9" y="126.9">Y6</text>
<text x="298.2" y="130.9">11</text>
<text x="298.2" y="128.4">12</text>
<text x="57.5" y="133.4">12</text>
<text x="69.6" y="136">11</text>
<text x="155.2" y="133.4">9</text>
<text x="161.1" y="132">7D</text>
<text x="161.1" y="134.6">8D</text>
<text x="168.8" y="134.6">8Q</text>
<text x="168.8" y="132">7Q</text>
<text x="176.3" y="133.4">12</text>
<text x="221.2" y="133.4">9</text>
<text x="227.1" y="132">7D</text>
<text x="227.1" y="134.6">8D</text>
<text x="234.8" y="134.6">8Q</text>
<text x="234.8" y="132">7Q</text>
<text x="242.3" y="133.4">12</text>
<text x="277.1" y="136">1</text>
<text x="283" y="137.1">G1</text>
<text x="283" y="132">A8</text>
<text x="290.9" y="132">Y8</text>
<text x="57.5" y="138.5">13</text>
<text x="84.1" y="143.6">1</text>
<text x="107.7" y="143.6">15</text>
<text x="154" y="138.5">11</text>
<text x="155.2" y="141.1">1</text>
<text x="161.1" y="142.2">OC</text>
<text x="161.1" y="139.6">CLK</text>
<text x="220.1" y="138.5">11</text>
<text x="221.2" y="141.1">1</text>
<text x="227.1" y="142.2">OC</text>
<text x="227.1" y="139.6">CLK</text>
<text x="275.9" y="138.5">19</text>
<text x="283" y="139.6">G2</text>
<text x="84.1" y="146.1">2</text>
<text x="84.1" y="148.7">3</text>
<text x="90" y="144.7">A</text>
<text x="90" y="147.3">B</text>
<text x="90" y="149.8">C</text>
<text x="100.4" y="149.8">Y2</text>
<text x="100.4" y="147.3">Y1</text>
<text x="100.4" y="144.7">Y0</text>
<text x="107.7" y="148.7">13</text>
<text x="107.7" y="146.1">14</text>
<text x="100.4" y="154.9">Y4</text>
<text x="100.4" y="152.3">Y3</text>
<text x="107.7" y="153.8">11</text>
<text x="107.7" y="151.2">12</text>
<text x="155.2" y="153.8">2</text>
<text x="161.1" y="154.9">1D</text>
<text x="168.8" y="154.9">1Q</text>
<text x="176.3" y="153.8">19</text>
<text x="221.2" y="153.8">2</text>
<text x="227.1" y="154.9">1D</text>
<text x="234.8" y="154.9">1Q</text>
<text x="242.3" y="153.8">19</text>
<text x="277.1" y="153.8">2</text>
<text x="283" y="154.9">A1</text>
<text x="290.9" y="154.9">Y1</text>
<text x="298.2" y="153.8">18</text>
<text x="333" y="153.8">2</text>
<text x="338.8" y="154.9">A1</text>
<text x="346.8" y="154.9">Y1</text>
<text x="354.1" y="153.8">18</text>
<text x="84.1" y="158.8">4</text>
<text x="84.1" y="161.4">5</text>
<text x="84.1" y="156.3">6</text>
<text x="90" y="159.9">G2A</text>
<text x="90" y="157.4">G1</text>
<text x="100.4" y="160">Y6</text>
<text x="100.4" y="157.4">Y5</text>
<text x="107.7" y="161.4">7</text>
<text x="107.7" y="158.8">9</text>
<text x="107.7" y="156.3">10</text>
<text x="155.2" y="156.3">3</text>
<text x="155.2" y="158.8">4</text>
<text x="155.2" y="161.4">5</text>
<text x="161.1" y="157.4">2D</text>
<text x="161.1" y="159.9">3D</text>
<text x="168.8" y="160">3Q</text>
<text x="168.8" y="157.4">2Q</text>
<text x="176.3" y="161.4">16</text>
<text x="176.3" y="158.8">17</text>
<text x="176.3" y="156.3">18</text>
<text x="221.2" y="156.3">3</text>
<text x="221.2" y="158.8">4</text>
<text x="221.2" y="161.4">5</text>
<text x="227.1" y="157.4">2D</text>
<text x="227.1" y="159.9">3D</text>
<text x="234.8" y="160">3Q</text>
<text x="234.8" y="157.4">2Q</text>
<text x="242.3" y="161.4">16</text>
<text x="242.3" y="158.8">17</text>
<text x="242.3" y="156.3">18</text>
<text x="277.1" y="156.3">3</text>
<text x="277.1" y="158.8">4</text>
<text x="277.1" y="161.4">5</text>
<text x="283" y="157.4">A2</text>
<text x="283" y="159.9">A3</text>
<text x="290.9" y="160">Y3</text>
<text x="290.9" y="157.4">Y2</text>
<text x="298.2" y="161.4">15</text>
<text x="298.2" y="158.8">16</text>
<text x="298.2" y="156.3">17</text>
<text x="333" y="156.3">3</text>
<text x="333" y="158.8">4</text>
<text x="333" y="161.4">5</text>
<text x="338.8" y="157.4">A2</text>
<text x="338.8" y="159.9">A3</text>
<text x="346.8" y="160">Y3</text>
<text x="346.8" y="157.4">Y2</text>
<text x="354.1" y="161.4">15</text>
<text x="354.1" y="158.8">16</text>
<text x="354.1" y="156.3">17</text>
<text x="90" y="162.5">G2B</text>
<text x="100.4" y="162.5">Y7</text>
<text x="155.2" y="163.9">6</text>
<text x="155.2" y="166.5">7</text>
<text x="161.1" y="162.5">4D</text>
<text x="161.1" y="165">5D</text>
<text x="161.1" y="167.6">6D</text>
<text x="168.8" y="167.6">6Q</text>
<text x="168.8" y="165">5Q</text>
<text x="168.8" y="162.5">4Q</text>
<text x="176.3" y="166.5">14</text>
<text x="176.3" y="163.9">15</text>
<text x="221.2" y="163.9">6</text>
<text x="221.2" y="166.5">7</text>
<text x="227.1" y="162.5">4D</text>
<text x="227.1" y="165">5D</text>
<text x="227.1" y="167.6">6D</text>
<text x="234.8" y="167.6">6Q</text>
<text x="234.8" y="165">5Q</text>
<text x="234.8" y="162.5">4Q</text>
<text x="242.3" y="166.5">14</text>
<text x="242.3" y="163.9">15</text>
<text x="277.1" y="163.9">6</text>
<text x="277.1" y="166.5">7</text>
<text x="283" y="162.5">A4</text>
<text x="283" y="165">A5</text>
<text x="283" y="167.6">A6</text>
<text x="290.9" y="167.6">Y6</text>
<text x="290.9" y="165">Y5</text>
<text x="290.9" y="162.5">Y4</text>
<text x="298.2" y="166.5">13</text>
<text x="298.2" y="163.9">14</text>
<text x="333" y="163.9">6</text>
<text x="333" y="166.5">7</text>
<text x="338.8" y="162.5">A4</text>
<text x="338.8" y="165">A5</text>
<text x="338.8" y="167.6">A6</text>
<text x="346.8" y="167.6">Y6</text>
<text x="346.8" y="165">Y5</text>
<text x="346.8" y="162.5">Y4</text>
<text x="354.1" y="166.5">13</text>
<text x="354.1" y="163.9">14</text>
<text x="155.2" y="169">8</text>
<text x="155.2" y="171.5">9</text>
<text x="161.1" y="170.1">7D</text>
<text x="161.1" y="172.6">8D</text>
<text x="168.8" y="172.6">8Q</text>
<text x="168.8" y="170.1">7Q</text>
<text x="176.3" y="171.5">12</text>
<text x="176.3" y="169">13</text>
<text x="221.2" y="169">8</text>
<text x="221.2" y="171.5">9</text>
<text x="227.1" y="170.1">7D</text>
<text x="227.1" y="172.6">8D</text>
<text x="234.8" y="172.6">8Q</text>
<text x="234.8" y="170.1">7Q</text>
<text x="242.3" y="171.5">12</text>
<text x="242.3" y="169">13</text>
<text x="277.1" y="169">8</text>
<text x="277.1" y="171.5">9</text>
<text x="283" y="170.1">A7</text>
<text x="283" y="172.6">A8</text>
<text x="290.9" y="172.6">Y8</text>
<text x="290.9" y="170.1">Y7</text>
<text x="298.2" y="171.5">11</text>
<text x="298.2" y="169">12</text>
<text x="333" y="169">8</text>
<text x="333" y="171.5">9</text>
<text x="338.8" y="170.1">A7</text>
<text x="338.8" y="172.6">A8</text>
<text x="346.8" y="172.6">Y8</text>
<text x="346.8" y="170.1">Y7</text>
<text x="354.1" y="171.5">11</text>
<text x="354.1" y="169">12</text>
<text x="154" y="176.6">11</text>
<text x="155.2" y="179.1">1</text>
<text x="161.1" y="177.7">CLK</text>
<text x="220.1" y="176.6">11</text>
<text x="221.2" y="179.1">1</text>
<text x="227.1" y="177.7">CLK</text>
<text x="275.9" y="179.1">19</text>
<text x="277.1" y="176.6">1</text>
<text x="283" y="177.7">G1</text>
<text x="331.8" y="179.1">19</text>
<text x="333" y="176.6">1</text>
<text x="338.8" y="177.7">G1</text>
<text x="161.1" y="180.3">OC</text>
<text x="227.1" y="180.3">OC</text>
<text x="283" y="180.3">G2</text>
<text x="338.8" y="180.3">G2</text>
<text x="86.6" y="191.8">4</text>
<text x="107.7" y="191.8">5</text>
<text x="155.2" y="191.8">2</text>
<text x="176.3" y="191.8">19</text>
<text x="221.2" y="191.8">2</text>
<text x="242.3" y="191.8">19</text>
<text x="86.6" y="194.4">2</text>
<text x="92.5" y="195.5">D</text>
<text x="92.5" y="193">PRE</text>
<text x="101.4" y="193">Q</text>
<text x="155.2" y="194.4">3</text>
<text x="155.2" y="196.9">4</text>
<text x="161.1" y="193">1D</text>
<text x="161.1" y="195.5">2D</text>
<text x="168.8" y="195.5">2Q</text>
<text x="168.8" y="193">1Q</text>
<text x="176.3" y="196.9">17</text>
<text x="176.3" y="194.4">18</text>
<text x="221.2" y="194.4">3</text>
<text x="221.2" y="196.9">4</text>
<text x="227.1" y="193">1D</text>
<text x="227.1" y="195.5">2D</text>
<text x="234.8" y="195.5">2Q</text>
<text x="234.8" y="193">1Q</text>
<text x="242.3" y="196.9">17</text>
<text x="242.3" y="194.4">18</text>
<text x="86.6" y="202">1</text>
<text x="86.6" y="199.5">3</text>
<text x="92.5" y="203.1">CLR</text>
<text x="92.5" y="200.6">CLK</text>
<text x="101.4" y="203.1">Q</text>
<text x="107.7" y="202">6</text>
<text x="155.2" y="199.5">5</text>
<text x="155.2" y="202">6</text>
<text x="161.1" y="198">3D</text>
<text x="161.1" y="200.6">4D</text>
<text x="161.1" y="203.1">5D</text>
<text x="168.8" y="203.1">5Q</text>
<text x="168.8" y="200.6">4Q</text>
<text x="168.8" y="198">3Q</text>
<text x="176.3" y="202">15</text>
<text x="176.3" y="199.5">16</text>
<text x="221.2" y="199.5">5</text>
<text x="221.2" y="202">6</text>
<text x="227.1" y="198">3D</text>
<text x="227.1" y="200.6">4D</text>
<text x="227.1" y="203.1">5D</text>
<text x="234.8" y="203.1">5Q</text>
<text x="234.8" y="200.6">4Q</text>
<text x="234.8" y="198">3Q</text>
<text x="242.3" y="202">15</text>
<text x="242.3" y="199.5">16</text>
<text x="155.2" y="204.5">7</text>
<text x="155.2" y="207.1">8</text>
<text x="155.2" y="209.6">9</text>
<text x="161.1" y="205.7">6D</text>
<text x="161.1" y="208.2">7D</text>
<text x="168.8" y="208.2">7Q</text>
<text x="168.8" y="205.7">6Q</text>
<text x="176.3" y="209.6">12</text>
<text x="176.3" y="207.1">13</text>
<text x="176.3" y="204.5">14</text>
<text x="221.2" y="204.5">7</text>
<text x="221.2" y="207.1">8</text>
<text x="221.2" y="209.6">9</text>
<text x="227.1" y="205.7">6D</text>
<text x="227.1" y="208.2">7D</text>
<text x="234.8" y="208.2">7Q</text>
<text x="234.8" y="205.7">6Q</text>
<text x="242.3" y="209.6">12</text>
<text x="242.3" y="207.1">13</text>
<text x="242.3" y="204.5">14</text>
<text x="154" y="214.7">11</text>
<text x="161.1" y="210.7">8D</text>
<text x="161.1" y="215.8">CLK</text>
<text x="168.8" y="210.7">8Q</text>
<text x="220.1" y="214.7">11</text>
<text x="227.1" y="210.7">8D</text>
<text x="227.1" y="215.8">CLK</text>
<text x="234.8" y="210.7">8Q</text>
<text x="85.5" y="219.8">12</text>
<text x="85.5" y="217.2">10</text>
<text x="92.5" y="220.9">D</text>
<text x="92.5" y="218.4">PRE</text>
<text x="101.4" y="218.4">Q</text>
<text x="107.7" y="217.2">9</text>
<text x="155.2" y="217.2">1</text>
<text x="161.1" y="218.4">OC</text>
<text x="221.2" y="217.2">1</text>
<text x="227.1" y="218.4">OC</text>
<text x="85.5" y="227.4">13</text>
<text x="85.5" y="224.9">11</text>
<text x="92.5" y="226">CLK</text>
<text x="107.7" y="227.4">8</text>
<text x="92.5" y="228.5">CLR</text>
<text x="101.4" y="228.5">Q</text>
<text x="259.3" y="247.7">4</text>
<text x="270.3" y="250.3">6</text>
<text x="259.3" y="252.8">5</text>
<text x="259.3" y="260.4">9</text>
<text x="270.3" y="263">8</text>
<text x="258.2" y="265.5">10</text>
</g>
</g></defs>
<g fill="#000" stroke="#000" stroke-width=".21">
<path d="M67.8 18.2v3.9zM115.3 18.2v3.9zM162.7 18.2v3.9zM210.2 18.2v3.9zM257.6 18.2v3.9zM305.1 18.2v3.9zM352.5 18.2v3.9zM20.3 22.1v252.6zM265.4 27.1l2.5 2.6zM270.5 27.1l2.5 2.6zM20.3 22.1h379.7zM26.7 59.1h10.2z"/>
<path d="M28.5 43.8h8.4zM31 48.9h5.9zM34.5 54h2.4zM41.9 44.9h335.2zM41.9 55.1h12.7zM54.6 55.1v78.7zM41.9 50h86.3zM54.6 55.1h322.5zM128.2 50h248.9zM378.7 54h2.3zM378.7 43.8h8.3zM378.7 59.1h10.1z"/>
<path d="M378.7 48.9h5.8zM16.5 72.6h3.8zM34.8 64.1h5.6zM41.9 60.2h10.2zM52.1 60.2h325zM130.8 75.4l2.5 2.5zM153.6 77.9h5.1zM133.3 77.9h20.3zM174 77.9h5zM179 77.9h10.2zM191.7 75.4l-2.5 2.5zM196.8 75.4l2.6 2.5z"/>
<path d="M219.7 77.9h5.1zM199.4 77.9h20.3zM240 77.9h5.1zM245.1 77.9h10.1zM255.2 77.9l2.6-2.5zM41.9 65.2h221zM262.9 65.2h114.2zM384.8 64.1h5.6zM400 72.6h3.8zM130.8 77.9l2.5 2.6zM130.8 80.5l2.5 2.5zM130.8 83l2.5 2.5z"/>
<path d="M130.8 85.5l2.5 2.6zM130.8 88.1l2.5 2.5zM130.8 90.6l2.5 2.6zM130.8 93.2l2.5 2.5zM140.6 98.8h10.5zM153.6 80.5h5.1zM153.6 83h5.1zM153.6 85.5h5.1zM153.6 88.1h5.1zM153.6 90.6h5.1zM153.6 93.2h5.1zM153.6 95.7h5.1z"/>
<path d="M133.3 80.5h20.3zM133.3 83h20.3zM133.3 85.5h20.3zM133.3 88.1h20.3zM133.3 90.6h20.3zM133.3 93.2h20.3zM133.3 95.7h20.3zM158.7 99.8l2 1zM174 95.7h5zM174 93.2h5zM174 90.6h5zM174 88.1h5z"/>
<path d="M174 85.5h5zM174 83h5zM174 80.5h5zM179 80.5h10.2zM179 83h10.2zM179 85.5h10.2zM179 88.1h10.2zM179 90.6h10.2zM179 93.2h10.2zM179 95.7h10.2zM189.2 80.5l2.5-2.6zM189.2 83l2.5-2.5z"/>
<path d="M191.7 83l-2.5 2.5zM189.2 88.1l2.5-2.6zM189.2 90.6l2.5-2.5zM191.7 90.6l-2.5 2.6zM189.2 95.7l2.5-2.5zM196.8 77.9l2.6 2.6zM196.8 80.5l2.6 2.5zM196.8 83l2.6 2.5zM196.8 85.5l2.6 2.6zM196.8 88.1l2.6 2.5zM196.8 90.6l2.6 2.6zM196.8 93.2l2.6 2.5z"/>
<path d="M206.6 98.8h10.5zM219.7 80.5h5.1zM219.7 83h5.1zM219.7 85.5h5.1zM219.7 88.1h5.1zM219.7 90.6h5.1zM219.7 93.2h5.1zM219.7 95.7h5.1zM199.4 80.5h20.3zM199.4 83h20.3zM199.4 85.5h20.3zM199.4 88.1h20.3z"/>
<path d="M199.4 90.6h20.3zM199.4 93.2h20.3zM199.4 95.7h20.3zM224.8 99.8l2 1zM240 95.7h5.1zM240 93.2h5.1zM240 90.6h5.1zM240 88.1h5.1zM240 85.5h5.1zM240 83h5.1zM240 80.5h5.1zM245.1 80.5h10.1z"/>
<path d="M245.1 83h10.1zM245.1 85.5h10.1zM245.1 88.1h10.1zM245.1 90.6h10.1zM245.1 93.2h10.1zM245.1 95.7h10.1zM255.2 80.5l2.6-2.6zM257.8 80.5l-2.6 2.5zM255.2 85.5l2.6-2.5zM255.2 88.1l2.6-2.6zM257.8 88.1l-2.6 2.5zM255.2 93.2l2.6-2.6z"/>
<path d="M255.2 95.7l2.6-2.5zM47 108.4l2.5 2.5zM47 103.3l2.5 2.6zM47 105.9l2.5 2.5zM47 113.5l2.5 2.5zM80 116v2.6zM49.5 116h30.5zM82.5 105.9h5.1zM82.5 108.4h5.1zM82.5 110.9h5.1zM82.5 118.6h5.1zM49.5 110.9h33z"/>
<path d="M49.5 105.9h33zM49.5 108.4h33zM80 118.6h2.5zM107.4 118.6h3.1zM107.4 116h3.1zM107.4 113.5h3.1zM107.4 110.9h3.1zM107.4 108.4h3.1zM107.4 105.9h3.1zM110.5 105.9h12.7zM110.5 108.4h12.7zM110.5 110.9h12.7z"/>
<path d="M110.5 113.5h12.7zM110.5 116h12.7zM110.5 118.6h12.7zM113 103.9h10.6zM113 106.4h10.6zM113 109h10.6zM113 111.5h10.6zM113 114h10.6zM113 116.6h10.6zM113 119.1h10.6zM123.2 105.9l2.5 2.5zM123.2 108.4l2.5 2.5z"/>
<path d="M123.2 110.9l2.5 2.6zM123.2 113.5l2.5 2.5zM123.2 116l2.5 2.6zM123.2 118.6l2.5 2.5zM130.8 113.5l2.5 2.5zM130.8 116l2.5 2.6zM135.9 103.3l2.5-2.5zM138.4 103.3l-2.5 2.6zM141.1 101.3h10zM153.6 103.3h3.2zM153.6 100.8h5.1zM153.6 116h5.1z"/>
<path d="M153.6 118.6h5.1zM133.3 116h20.3zM133.3 118.6h20.3zM138.4 100.8h15.2zM138.4 103.3h15.2zM158.7 101.8l2-1zM174 118.6h5zM174 116h5zM179 116h10.2zM179 118.6h10.2zM191.7 113.5l-2.5 2.5zM189.2 118.6l2.5-2.6z"/>
<path d="M196.8 113.5l2.6 2.5zM196.8 116l2.6 2.6zM204.4 103.3l-2.5 2.6zM204.4 100.8l-2.5 2.5zM207.2 101.3h9.9zM219.7 103.3h3.1zM219.7 100.8h5.1zM219.7 116h5.1zM219.7 118.6h5.1zM199.4 116h20.3zM199.4 118.6h20.3zM204.4 103.3h15.3z"/>
<path d="M204.4 100.8h15.3zM224.8 101.8l2-1zM240 118.6h5.1zM240 116h5.1zM245.1 116h10.1zM245.1 118.6h10.1zM255.2 116l2.6-2.5zM255.2 118.6l2.6-2.6zM267.9 29.7v86.3zM273 29.7v83.8zM273 118.6h2.6zM275.6 113.5h5z"/>
<path d="M275.6 116h5zM275.6 118.6h5zM273 113.5h2.6zM267.9 116h7.7zM295.9 118.6h5.1zM295.9 116h5.1zM295.9 113.5h5.1zM301 113.5h12.7zM301 116h12.7zM301 118.6h12.7zM313.7 113.5l2.5 2.5zM313.7 116l2.5 2.6z"/>
<path d="M313.7 118.6l2.5 2.5zM16.5 123.1h3.8zM34.3 136.9h10.1zM42.1 131.8h2.3zM47 123.6l2.5 2.6zM47 118.6l2.5 2.5zM52.1 60.2v78.7zM54.6 133.8h2.5zM57.1 121.1h5.1zM57.1 126.2h5.1zM57.1 133.8h5.1zM57.1 138.9h5.1z"/>
<path d="M52.1 138.9h5zM49.5 126.2h7.6zM49.5 121.1h7.6zM62.2 121.1h4.3zM62.2 126.2h4.3zM62.2 133.8h4.3zM62.2 138.9h4.3zM67.3 123.6h5.1zM67.3 136.3h5.1zM72.4 123.6h5.1zM72.4 136.3h7.6zM77.5 121.1v2.5z"/>
<path d="M77.5 121.1h5zM80 123.6v12.7zM80 123.6h2.5zM82.5 121.1h3.1zM82.5 123.6h3.1zM107.4 123.6h3.1zM107.4 121.1h3.1zM110.5 121.1h12.7zM110.5 123.6h12.7zM113 121.7h10.6zM123.2 121.1l2.5 2.5zM123.2 123.6l2.5 2.6z"/>
<path d="M130.8 118.6l2.5 2.5zM130.8 121.1l2.5 2.5zM130.8 123.6l2.5 2.6zM130.8 126.2l2.5 2.5zM130.8 128.7l2.5 2.6zM130.8 131.3l2.5 2.5zM138.4 138.9l-2.5 2.5zM140.6 136.9h10.5zM141.1 139.4h10zM153.6 121.1h5.1zM153.6 123.6h5.1zM153.6 126.2h5.1z"/>
<path d="M153.6 128.7h5.1zM153.6 131.3h5.1zM153.6 133.8h5.1zM153.6 138.9h5.1zM133.3 121.1h20.3zM133.3 123.6h20.3zM133.3 126.2h20.3zM133.3 128.7h20.3zM133.3 131.3h20.3zM133.3 133.8h20.3zM138.4 138.9h15.2zM158.7 137.9l2 1z"/>
<path d="M158.7 139.9l2-1zM174 133.8h5zM174 131.3h5zM174 128.7h5zM174 126.2h5zM174 123.6h5zM174 121.1h5zM179 121.1h10.2zM179 123.6h10.2zM179 126.2h10.2zM179 128.7h10.2zM179 131.3h10.2z"/>
<path d="M179 133.8h10.2zM189.2 121.1l2.5-2.5zM191.7 121.1l-2.5 2.5zM189.2 126.2l2.5-2.6zM189.2 128.7l2.5-2.5zM189.2 131.3l2.5-2.6zM191.7 131.3l-2.5 2.5zM196.8 118.6l2.6 2.5zM196.8 121.1l2.6 2.5zM196.8 123.6l2.6 2.6zM196.8 126.2l2.6 2.5zM196.8 128.7l2.6 2.6z"/>
<path d="M196.8 131.3l2.6 2.5zM204.4 138.9l-2.5 2.5zM206.6 136.9h10.5zM207.2 139.4h9.9zM219.7 121.1h5.1zM219.7 123.6h5.1zM219.7 126.2h5.1zM219.7 128.7h5.1zM219.7 131.3h5.1zM219.7 133.8h5.1zM219.7 138.9h5.1zM199.4 121.1h20.3z"/>
<path d="M199.4 123.6h20.3zM199.4 126.2h20.3zM199.4 128.7h20.3zM199.4 131.3h20.3zM199.4 133.8h20.3zM204.4 138.9h15.3zM224.8 137.9l2 1zM224.8 139.9l2-1zM240 133.8h5.1zM240 131.3h5.1zM240 128.7h5.1zM240 126.2h5.1z"/>
<path d="M240 123.6h5.1zM240 121.1h5.1zM245.1 121.1h10.1zM245.1 123.6h10.1zM245.1 126.2h10.1zM245.1 128.7h10.1zM245.1 131.3h10.1zM245.1 133.8h10.1zM257.8 118.6l-2.6 2.5zM255.2 123.6l2.6-2.5zM255.2 126.2l2.6-2.6zM257.8 126.2l-2.6 2.5z"/>
<path d="M255.2 131.3l2.6-2.6zM257.8 131.3l-2.6 2.5zM262.9 65.2v66.1zM265.4 136.3v2.6zM265.4 138.9v95.2zM273 126.2v2.5zM273 123.6v2.6zM273 121.1v2.5zM273 118.6v2.5zM273 126.2h2.6zM275.6 136.3h3.1zM275.6 121.1h5z"/>
<path d="M275.6 123.6h5zM275.6 126.2h5zM275.6 128.7h5zM275.6 131.3h5zM275.6 138.9h3.1zM273 121.1h2.6zM273 123.6h2.6zM273 128.7h2.6zM262.9 131.3h12.7zM265.4 136.3h10.2zM265.4 138.9h10.2zM295.9 131.3h5.1z"/>
<path d="M295.9 128.7h5.1zM295.9 126.2h5.1zM295.9 123.6h5.1zM295.9 121.1h5.1zM301 121.1h12.7zM301 123.6h12.7zM301 126.2h12.7zM301 128.7h12.7zM301 131.3h12.7zM313.7 121.1l2.5 2.5zM313.7 123.6l2.5 2.6zM313.7 126.2l2.5 2.5z"/>
<path d="M313.7 128.7l2.5 2.6zM313.7 131.3l2.5 2.5zM400 123.1h3.8zM47 141.4l2.5 2.6zM47 144l2.5 2.5zM47 146.5l2.5 2.5zM69.8 159.2v15.2zM71.6 157.2h5.9zM80 152.8v2.6zM80 155.4v1.3zM82.5 144h5.1zM82.5 146.5h5.1z"/>
<path d="M82.5 149h5.1zM82.5 159.2h3.1zM82.5 156.7h5.1zM49.5 144h33zM49.5 146.5h33zM80 156.7h2.5zM69.8 159.2h12.7zM49.5 149h33zM107.4 159.2h3.1zM107.4 156.7h3.1zM107.4 154.1h3.1zM107.4 151.6h3.1z"/>
<path d="M107.4 149h3.1zM107.4 146.5h3.1zM107.4 144h3.1zM110.5 144h12.7zM110.5 146.5h12.7zM110.5 149h12.7zM110.5 151.6h12.7zM110.5 154.1h12.7zM110.5 156.7h12.7zM110.5 159.2h12.7zM113 142h10zM113 144.5h10z"/>
<path d="M113 147.1h10zM113 149.6h10zM113 152.1h10zM113 154.7h10zM113 157.2h10zM113 159.8h10zM123.2 144l2.5 2.5zM123.2 146.5l2.5 2.5zM123.2 149l2.5 2.6zM123.2 151.6l2.5 2.5zM123.2 154.1l2.5 2.6zM123.2 156.7l2.5 2.5z"/>
<path d="M123.2 159.2l2.5 2.5zM130.8 151.6l2.5 2.5zM130.8 154.1l2.5 2.6zM130.8 156.7l2.5 2.5zM138.4 141.4l-2.5 2.6zM153.6 141.4h3.2zM153.6 154.1h5.1zM153.6 156.7h5.1zM153.6 159.2h5.1zM133.3 154.1h20.3zM133.3 156.7h20.3zM133.3 159.2h20.3z"/>
<path d="M138.4 141.4h15.2zM174 159.2h5zM174 156.7h5zM174 154.1h5zM179 154.1h10.2zM179 156.7h10.2zM179 159.2h10.2zM189.2 154.1l2.5-2.5zM191.7 154.1l-2.5 2.6zM189.2 159.2l2.5-2.5zM196.8 151.6l2.6 2.5zM196.8 154.1l2.6 2.6z"/>
<path d="M196.8 156.7l2.6 2.5zM204.4 141.4l-2.5 2.6zM219.7 141.4h3.1zM219.7 154.1h5.1zM219.7 156.7h5.1zM219.7 159.2h5.1zM199.4 154.1h20.3zM199.4 156.7h20.3zM199.4 159.2h20.3zM204.4 141.4h15.3zM240 159.2h5.1zM240 156.7h5.1z"/>
<path d="M240 154.1h5.1zM245.1 154.1h10.1zM245.1 156.7h10.1zM245.1 159.2h10.1zM255.2 154.1l2.6-2.5zM257.8 154.1l-2.6 2.6zM255.2 159.2l2.6-2.5zM257.8 151.6l2.5 2.5zM257.8 154.1l2.5 2.6zM257.8 156.7l2.5 2.5zM257.8 159.2l2.5 2.5zM260.3 154.1h15.3z"/>
<path d="M260.3 156.7h15.3zM260.3 159.2h15.3zM273 141.4v2.6zM273 128.7v12.7zM275.6 154.1h5zM275.6 156.7h5zM275.6 159.2h5zM295.9 159.2h5.1zM295.9 156.7h5.1zM295.9 154.1h5.1zM301 154.1h12.7zM301 156.7h12.7z"/>
<path d="M301 159.2h12.7zM313.7 154.1l2.5 2.6zM313.7 156.7l2.5 2.5zM313.7 159.2l2.5 2.5zM318.7 154.1l-2.5 2.6zM316.2 159.2l2.5-2.5zM318.7 159.2l-2.5 2.5zM331.4 154.1h5.1zM331.4 156.7h5.1zM331.4 159.2h5.1zM318.7 154.1h12.7zM318.7 156.7h12.7z"/>
<path d="M318.7 159.2h12.7zM351.7 159.2h5.1zM351.7 156.7h5.1zM351.7 154.1h5.1zM356.8 154.1h12.7zM356.8 156.7h12.7zM356.8 159.2h12.7zM369.5 154.1l2.6 2.6zM369.5 156.7l2.6 2.5zM369.5 159.2l2.6 2.5zM16.5 173.7h3.8zM69.8 174.4h58.4z"/>
<path d="M69.8 179.5h58.4zM80 164.3v2.5zM80 161.7v2.6zM82.5 161.7h3.1zM80 161.7h2.5zM107.4 161.7h3.1zM110.5 161.7h12.7zM123.2 161.7l2.5 2.6zM128.2 50v124.4zM128.2 179.5l2.6 2.6zM130.8 159.2l2.5 2.5zM130.8 161.7l2.5 2.6z"/>
<path d="M130.8 164.3l2.5 2.5zM130.8 166.8l2.5 2.6zM130.8 169.4l2.5 2.5zM138.4 179.5l-2.5 2.6zM135.9 179.5l2.5-2.5zM140.6 175h10.5zM141.1 177.5h10zM153.6 179.5h3.2zM153.6 161.7h5.1zM153.6 164.3h5.1zM153.6 166.8h5.1zM153.6 169.4h5.1z"/>
<path d="M153.6 171.9h5.1zM153.6 177h5.1zM133.3 161.7h20.3zM133.3 164.3h20.3zM133.3 166.8h20.3zM133.3 169.4h20.3zM133.3 171.9h20.3zM138.4 179.5h15.2zM138.4 177h15.2zM158.7 176l2 1zM158.7 177.9l2-.9zM174 171.9h5z"/>
<path d="M174 169.4h5zM174 166.8h5zM174 164.3h5zM174 161.7h5zM179 161.7h10.2zM179 164.3h10.2zM179 166.8h10.2zM179 169.4h10.2zM179 171.9h10.2zM189.2 161.7l2.5-2.5zM191.7 161.7l-2.5 2.6zM189.2 166.8l2.5-2.5z"/>
<path d="M189.2 169.4l2.5-2.6zM191.7 169.4l-2.5 2.5zM196.8 159.2l2.6 2.5zM196.8 161.7l2.6 2.6zM196.8 164.3l2.6 2.5zM196.8 166.8l2.6 2.6zM196.8 169.4l2.6 2.5zM204.4 179.5l-2.5 2.6zM204.4 177l-2.5 2.5zM206.6 175h10.5zM207.2 177.5h9.9zM219.7 179.5h3.1z"/>
<path d="M219.7 161.7h5.1zM219.7 164.3h5.1zM219.7 166.8h5.1zM219.7 169.4h5.1zM219.7 171.9h5.1zM219.7 177h5.1zM199.4 161.7h20.3zM199.4 164.3h20.3zM199.4 166.8h20.3zM199.4 169.4h20.3zM199.4 171.9h20.3zM204.4 179.5h15.3z"/>
<path d="M204.4 177h15.3zM224.8 176l2 1zM224.8 177.9l2-.9zM240 171.9h5.1zM240 169.4h5.1zM240 166.8h5.1zM240 164.3h5.1zM240 161.7h5.1zM245.1 161.7h10.1zM245.1 164.3h10.1zM245.1 166.8h10.1zM245.1 169.4h10.1z"/>
<path d="M245.1 171.9h10.1zM255.2 161.7l2.6-2.5zM257.8 161.7l-2.6 2.6zM255.2 166.8l2.6-2.5zM255.2 169.4l2.6-2.6zM257.8 169.4l-2.6 2.5zM257.8 161.7l2.5 2.6zM257.8 164.3l2.5 2.5zM257.8 166.8l2.5 2.6zM257.8 169.4l2.5 2.5zM260.3 161.7h15.3zM260.3 164.3h15.3z"/>
<path d="M260.3 166.8h15.3zM260.3 169.4h15.3zM260.3 171.9h15.3zM273 177v2.5zM275.6 177h3.1zM275.6 161.7h5zM275.6 164.3h5zM275.6 166.8h5zM275.6 169.4h5zM275.6 171.9h5zM275.6 179.5h3.1zM273 179.5h2.6z"/>
<path d="M273 177h2.6zM295.9 171.9h5.1zM295.9 169.4h5.1zM295.9 166.8h5.1zM295.9 164.3h5.1zM295.9 161.7h5.1zM301 161.7h12.7zM301 164.3h12.7zM301 166.8h12.7zM301 169.4h12.7zM301 171.9h12.7zM313.7 161.7l2.5 2.6z"/>
<path d="M313.7 164.3l2.5 2.5zM313.7 166.8l2.5 2.6zM313.7 169.4l2.5 2.5zM313.7 171.9l2.5 2.5zM318.7 161.7l-2.5 2.6zM316.2 166.8l2.5-2.5zM318.7 166.8l-2.5 2.6zM318.7 169.4l-2.5 2.5zM316.2 174.4l2.5-2.5zM328.9 177v2.5zM328.9 179.5v2.6zM331.4 177h3.1z"/>
<path d="M331.4 161.7h5.1zM331.4 164.3h5.1zM331.4 166.8h5.1zM331.4 169.4h5.1zM331.4 171.9h5.1zM331.4 179.5h3.1zM318.7 161.7h12.7zM318.7 164.3h12.7zM318.7 166.8h12.7zM318.7 169.4h12.7zM318.7 171.9h12.7zM328.9 177h2.5z"/>
<path d="M328.9 179.5h2.5zM351.7 171.9h5.1zM351.7 169.4h5.1zM351.7 166.8h5.1zM351.7 164.3h5.1zM351.7 161.7h5.1zM356.8 161.7h12.7zM356.8 164.3h12.7zM356.8 166.8h12.7zM356.8 169.4h12.7zM356.8 171.9h12.7zM369.5 161.7l2.6 2.6z"/>
<path d="M369.5 164.3l2.6 2.5zM369.5 166.8l2.6 2.6zM369.5 169.4l2.6 2.5zM369.5 171.9l2.6 2.5zM400 173.7h3.8zM67.3 182.1h55.9zM67.3 182.1v17.7zM67.3 199.8h17.8zM69.8 179.5v15.3zM72 197.9h10.5zM82.5 187.1v2.6zM82.5 189.7v2.5z"/>
<path d="M85.1 194.8h5.1zM85.1 199.8h5.1zM85.1 192.2h3.1zM82.5 192.2h2.6zM69.8 194.8h15.3zM90.2 198.8l1.9 1zM90.2 200.8l1.9-1zM105.4 192.2h5.1zM110.5 192.2h10.1zM113 180.1h10.6zM120.6 192.2v41.9zM123.2 182.1l2.5 2.5z"/>
<path d="M130.8 189.7l2.5 2.5zM130.8 192.2l2.5 2.6zM130.8 194.8l2.5 2.5zM130.8 197.3l2.5 2.5zM153.6 192.2h5.1zM153.6 194.8h5.1zM153.6 197.3h5.1zM153.6 199.8h5.1zM133.3 192.2h20.3zM133.3 194.8h20.3zM133.3 197.3h20.3zM133.3 199.8h20.3z"/>
<path d="M174 199.8h5zM174 197.3h5zM174 194.8h5zM174 192.2h5zM179 192.2h10.2zM179 194.8h10.2zM179 197.3h10.2zM179 199.8h10.2zM189.2 192.2l2.5-2.5zM189.2 194.8l2.5-2.6zM189.2 197.3l2.5-2.5zM189.2 199.8l2.5-2.5z"/>
<path d="M196.8 189.7l2.6 2.5zM196.8 192.2l2.6 2.6zM196.8 194.8l2.6 2.5zM196.8 197.3l2.6 2.5zM219.7 192.2h5.1zM219.7 194.8h5.1zM219.7 197.3h5.1zM219.7 199.8h5.1zM199.4 192.2h20.3zM199.4 194.8h20.3zM199.4 197.3h20.3zM199.4 199.8h20.3z"/>
<path d="M240 199.8h5.1zM240 197.3h5.1zM240 194.8h5.1zM240 192.2h5.1zM245.1 192.2h10.1zM245.1 194.8h10.1zM245.1 197.3h10.1zM245.1 199.8h10.1zM255.2 192.2l2.6-2.5zM255.2 194.8l2.6-2.6zM257.8 194.8l-2.6 2.5zM255.2 199.8l2.6-2.5z"/>
<path d="M328.9 182.1v2.5zM28.5 201.3h8.4zM82.5 212.5v2.5zM82.5 215v2.6zM85.1 202.4h3.1zM85.1 217.6h3.1zM41.9 202.4h43.2zM82.5 217.6h2.6zM101.4 201.5h1.7zM105.4 202.4h5.1zM105.4 217.6h5.1zM110.5 202.4h5.1z"/>
<path d="M115.6 202.4v27.9zM130.8 199.8l2.5 2.6zM130.8 202.4l2.5 2.5zM130.8 204.9l2.5 2.5zM130.8 207.4l2.5 2.6zM138.4 217.6l-2.5 2.5zM138.4 215l-2.5 2.6zM140.6 213.1h10.5zM141.1 215.6h10zM153.6 217.6h3.2zM153.6 202.4h5.1zM153.6 204.9h5.1z"/>
<path d="M153.6 207.4h5.1zM153.6 210h5.1zM153.6 215h5.1zM133.3 202.4h20.3zM133.3 204.9h20.3zM133.3 207.4h20.3zM133.3 210h20.3zM138.4 217.6h15.2zM138.4 215h15.2zM158.7 214.1l2 .9zM158.7 216l2-1zM174 210h5z"/>
<path d="M174 207.4h5zM174 204.9h5zM174 202.4h5zM179 202.4h10.2zM179 204.9h10.2zM179 207.4h10.2zM179 210h10.2zM189.2 202.4l2.5-2.6zM189.2 204.9l2.5-2.5zM189.2 207.4l2.5-2.5zM191.7 207.4l-2.5 2.6zM196.8 199.8l2.6 2.6z"/>
<path d="M196.8 202.4l2.6 2.5zM196.8 204.9l2.6 2.5zM196.8 207.4l2.6 2.6zM204.4 217.6l-2.5 2.5zM204.4 215l-2.5 2.6zM206.6 213.1h10.5zM207.2 215.6h9.9zM219.7 217.6h3.1zM219.7 202.4h5.1zM219.7 204.9h5.1zM219.7 207.4h5.1zM219.7 210h5.1z"/>
<path d="M219.7 215h5.1zM199.4 202.4h20.3zM199.4 204.9h20.3zM199.4 207.4h20.3zM199.4 210h20.3zM204.4 217.6h15.3zM204.4 215h15.3zM224.8 214.1l2 .9zM224.8 216l2-1zM240 210h5.1zM240 207.4h5.1zM240 204.9h5.1z"/>
<path d="M240 202.4h5.1zM245.1 202.4h10.1zM245.1 204.9h10.1zM245.1 207.4h10.1zM245.1 210h10.1zM255.2 202.4l2.6-2.6zM257.8 202.4l-2.6 2.5zM255.2 207.4l2.6-2.5zM255.2 210l2.6-2.6zM16.5 224.2h3.8zM82.5 230.3v2.5zM82.5 227.7v2.6z"/>
<path d="M82.5 220.1v5.1zM82.5 225.2v2.5zM85.1 227.7h3.1zM85.1 220.1h5.1zM85.1 225.2h5.1zM82.5 227.7h2.6zM82.5 220.1h2.6zM82.5 225.2h2.6zM90.2 224.2l1.9 1zM90.2 226.2l1.9-1zM101.4 226.9h1.7zM105.4 227.7h5.1z"/>
<path d="M120.6 234.1h144.8zM246.5 228.3h11.3zM265.4 234.1h78.7zM115.6 230.3h157.4zM273 179.5v50.8zM344.1 222.7v11.4zM344.1 234.1h35.6zM349.2 222.7h2.5zM344.1 222.7h5.1zM356.8 222.7h2.6zM361.9 222.7h2.5zM359.4 222.7h2.5z"/>
<path d="M364.4 222.7h2.6zM365.2 224.7l1.4 1.4zM365.7 225.7l.5-.5zM365.7 225.7h.8zM365.8 225.6h.6zM365.9 225.5h.4zM366 225.8h.5zM366.1 225.4h.2zM366.2 225.2l.4 .9zM366.3 226h.3zM366.3 224.6l1.4 1.4zM365.7 225.7l.9 .4z"/>
<path d="M366.9 225.6l.5-.5zM366.9 225.6h.7zM367 225.5h.5zM367.1 225.4h.4zM367.2 225.7h.4zM367.2 225.3h.2zM367.4 225.1l.3 .9zM367.5 225.8h.2zM366.9 225.6l.8 .4zM367 222.7h2.5zM369.5 222.7h2.6zM372.1 225.2v2.5z"/>
<path d="M372.1 222.7v2.5zM400 224.2h3.8zM29.2 253.1v2.6zM29.2 257.7v.5zM29.2 255.7v.5zM29.2 250.6v2.5zM36.8 253.1v2.6zM36.8 257.7v.5zM36.8 255.7v.5zM36.8 250.6v2.5zM29.2 250.6h7.6zM44.4 253.1v2.6z"/>
<path d="M44.4 257.7v.5zM44.4 255.7v.5zM36.8 250.6h7.6zM44.4 250.6v2.5zM52.1 253.1v2.6zM52.1 257.7v.5zM52.1 255.7v.5zM44.4 250.6h7.7zM52.1 250.6v2.5zM59.7 253.1v2.6zM59.7 257.7v.5zM59.7 255.7v.5z"/>
<path d="M52.1 250.6h7.6zM59.7 250.6v2.5zM67.3 253.1v2.6zM67.3 257.7v.5zM67.3 255.7v.5zM59.7 250.6h7.6zM67.3 250.6v2.5zM74.9 253.1v2.6zM74.9 257.7v.5zM74.9 255.7v.5zM67.3 250.6h7.6zM74.9 250.6v2.5z"/>
<path d="M82.5 253.1v2.6zM82.5 257.7v.5zM82.5 255.7v.5zM74.9 250.6h7.6zM82.5 250.6v2.5zM90.2 253.1v2.6zM90.2 257.7v.5zM90.2 255.7v.5zM82.5 250.6h7.7zM90.2 250.6v2.5zM97.8 253.1v2.6zM97.8 257.7v.5z"/>
<path d="M97.8 255.7v.5zM90.2 250.6h7.6zM97.8 250.6v2.5zM105.4 253.1v2.6zM105.4 257.7v.5zM105.4 255.7v.5zM97.8 250.6h7.6zM105.4 250.6v2.5zM113 253.1v2.6zM113 257.7v.5zM113 255.7v.5zM105.4 250.6h7.6z"/>
<path d="M113 250.6v2.5zM120.6 253.1v2.6zM120.6 257.7v.5zM120.6 255.7v.5zM113 250.6h7.6zM120.6 250.6v2.5zM128.2 253.1v2.6zM128.2 257.7v.5zM128.2 255.7v.5zM120.6 250.6h7.6zM128.2 250.6v2.5zM135.9 245.5v2.6z"/>
<path d="M135.9 253.1v2.6zM135.9 257.7v.5zM135.9 255.7v.5zM128.2 250.6h7.7zM135.9 248.1v2.5zM135.9 250.6v2.5zM146 245.5v2.6zM146 253.1v2.6zM146 255.7v.5zM146 257.7v.5zM146 248.1v5zM255.2 248.1v5z"/>
<path d="M255.2 248.1h2.6zM257.8 248.1h5.1zM257.8 253.1h5.1zM255.2 253.1h2.6zM262.9 248.1h4.3zM262.9 253.1h4.3zM267.9 250.6h5.1zM20.3 274.7h379.7zM29.2 265.8v2.6zM29.2 258.2v2.6zM29.2 260.8v2.5zM29.2 263.3h7.6z"/>
<path d="M29.2 263.3v2.5zM36.8 258.2v2.6zM36.8 260.8v2.5zM44.4 258.2v2.6zM36.8 263.3h7.6zM44.4 260.8v2.5zM52.1 258.2v2.6zM44.4 263.3h7.7zM52.1 260.8v2.5zM59.7 258.2v2.6zM52.1 263.3h7.6zM59.7 260.8v2.5z"/>
<path d="M67.3 258.2v2.6zM59.7 263.3h7.6zM67.3 260.8v2.5zM67.8 274.7v3.8zM74.9 258.2v2.6zM67.3 263.3h7.6zM74.9 260.8v2.5zM82.5 258.2v2.6zM74.9 263.3h7.6zM82.5 260.8v2.5zM90.2 258.2v2.6zM82.5 263.3h7.7z"/>
<path d="M90.2 260.8v2.5zM97.8 258.2v2.6zM90.2 263.3h7.6zM97.8 260.8v2.5zM105.4 258.2v2.6zM97.8 263.3h7.6zM105.4 260.8v2.5zM113 258.2v2.6zM105.4 263.3h7.6zM113 260.8v2.5zM115.3 274.7v3.8zM120.6 258.2v2.6z"/>
<path d="M113 263.3h7.6zM120.6 260.8v2.5zM128.2 258.2v2.6zM120.6 263.3h7.6zM128.2 260.8v2.5zM135.9 258.2v2.6zM128.2 263.3h7.7zM135.9 260.8v2.5zM146 265.8v2.6zM146 258.2v2.6zM146 260.8v5zM162.7 274.7v3.8z"/>
<path d="M210.2 274.7v3.8zM255.2 268.4v2.5zM255.2 265.8v2.6zM255.2 260.8v5zM255.2 253.1v7.7zM257.6 274.7v3.8zM257.8 260.8h5.1zM257.8 265.8h5.1zM255.2 260.8h2.6zM255.2 265.8h2.6zM262.9 260.8h4.3zM262.9 265.8h4.3z"/>
<path d="M267.9 263.3h5.1zM305.1 274.7v3.8zM352.5 274.7v3.8zM400 264.5v.1zM400 268.4v6.2zM400 274.6h.1zM400 22.1v252.6z"/>
<circle cx="54.6" cy="55.1" r=".51"/>
<circle cx="128.2" cy="50" r=".51"/>
<circle cx="52.1" cy="60.2" r=".51"/>
<circle cx="262.9" cy="65.2" r=".51"/>
<circle cx="265.4" cy="138.9" r=".51"/>
<circle cx="273" cy="123.6" r=".51"/>
<circle cx="273" cy="126.2" r=".51"/>
<circle cx="273" cy="128.7" r=".51"/>
<circle cx="273" cy="121.1" r=".51"/>
<circle cx="273" cy="179.5" r=".51"/>
<circle cx="328.9" cy="179.5" r=".51"/>
<circle cx="82.5" cy="225.2" r=".51"/>
<circle cx="82.5" cy="227.7" r=".51"/>
<circle cx="265.4" cy="234.1" r=".51"/>
<circle cx="344.1" cy="234.1" r=".51"/>
<circle cx="36.8" cy="250.6" r=".51"/>
<circle cx="44.4" cy="250.6" r=".51"/>
<circle cx="52.1" cy="250.6" r=".51"/>
<circle cx="59.7" cy="250.6" r=".51"/>
<circle cx="67.3" cy="250.6" r=".51"/>
<circle cx="74.9" cy="250.6" r=".51"/>
<circle cx="82.5" cy="250.6" r=".51"/>
<circle cx="90.2" cy="250.6" r=".51"/>
<circle cx="97.8" cy="250.6" r=".51"/>
<circle cx="105.4" cy="250.6" r=".51"/>
<circle cx="113" cy="250.6" r=".51"/>
<circle cx="120.6" cy="250.6" r=".51"/>
<circle cx="128.2" cy="250.6" r=".51"/>
<circle cx="135.9" cy="250.6" r=".51"/>
<circle cx="255.2" cy="253.1" r=".51"/>
<circle cx="29.2" cy="263.3" r=".51"/>
<circle cx="36.8" cy="263.3" r=".51"/>
<circle cx="44.4" cy="263.3" r=".51"/>
<circle cx="52.1" cy="263.3" r=".51"/>
<circle cx="59.7" cy="263.3" r=".51"/>
<circle cx="67.3" cy="263.3" r=".51"/>
<circle cx="74.9" cy="263.3" r=".51"/>
<circle cx="82.5" cy="263.3" r=".51"/>
<circle cx="90.2" cy="263.3" r=".51"/>
<circle cx="97.8" cy="263.3" r=".51"/>
<circle cx="105.4" cy="263.3" r=".51"/>
<circle cx="113" cy="263.3" r=".51"/>
<circle cx="120.6" cy="263.3" r=".51"/>
<circle cx="128.2" cy="263.3" r=".51"/>
<circle cx="255.2" cy="260.8" r=".51"/>
<circle cx="255.2" cy="265.8" r=".51"/>
</g>
<g fill="#000" stroke="#000" stroke-width=".28">
<path d="M26.2 43.4v3zM28.7 48.5v3zM32.3 53.6v3zM32.3 53.6h8.1zM32.3 56.6h8.1zM26.2 46.4h14.2zM26.2 43.4h14.2zM24.4 58.6h16zM28.7 48.5h11.7zM28.7 51.5h11.7zM40.4 53.6l1.5 1.5zM41.9 55.1l-1.5 1.5z"/>
<path d="M41.9 44.9l-1.5 1.5zM40.4 43.4l1.5 1.5zM40.4 48.5l1.5 1.5zM41.9 50l-1.5 1.5zM377.1 55.1l1.6-1.5zM377.1 55.1l1.6 1.5zM377.1 44.9l1.6-1.5zM377.1 44.9l1.6 1.5zM378.7 48.5l-1.6 1.5zM377.1 50l1.6 1.5zM378.7 53.6h8.1zM378.7 56.6h8.1z"/>
<path d="M378.7 43.4h14.1zM378.7 46.4h14.1zM378.7 58.6h16zM378.7 48.5h11.6zM378.7 51.5h11.6zM386.8 53.6v3zM390.3 48.5v3zM392.8 43.4v3zM394.7 58.6v3.1zM24.4 58.6v3.1zM26.4 63.7v3zM24.4 61.7h16z"/>
<path d="M26.4 63.7h14zM26.4 66.7h14zM40.4 61.7l1.5-1.5zM40.4 58.6l1.5 1.6zM40.4 63.7l1.5 1.5zM41.9 65.2l-1.5 1.5zM377.1 60.2l1.6-1.6zM377.1 60.2l1.6 1.5zM377.1 65.2l1.6-1.5zM377.1 65.2l1.6 1.5zM378.7 61.7h16zM378.7 63.7h14z"/>
<path d="M378.7 66.7h14zM392.7 63.7v3zM80 152.8l-1.3 1.9zM80 152.8l1.3 1.9zM271.1 144h3.8zM78.1 166.8h3.8zM82.5 187.1l-1.2 1.9zM82.5 187.1l1.3 1.9zM327 184.6h3.8zM26.2 200.8v3.1zM26.2 200.8h14.2zM26.2 203.9h14.2z"/>
<path d="M40.4 200.8l1.5 1.6zM41.9 202.4l-1.5 1.5zM82.5 212.5l-1.2 1.9zM82.5 212.5l1.3 1.9zM80.6 232.8h3.9zM351.7 223.6h5.1zM351.7 221.8v1.8zM351.7 221.8h5.1zM356.8 221.8v1.8zM364.4 221.4v2.5zM364.4 221.4l2.6 1.3zM364.4 223.7h.6z"/>
<path d="M364.4 223.5h1zM364.4 223.2h1.5zM364.4 223h1.9zM364.4 222.8h2.4zM364.4 222.6h2.3zM364.4 222.3h1.9zM364.4 222.1h1.5zM364.4 221.9h1zM364.4 221.7h.6zM367 222.7v1.2zM364.4 223.9l2.6-1.2zM367 221.4v2.5z"/>
<path d="M367 221.4h.2zM367 223.9h.2zM367 223.7h.2zM367 223.5h.2zM367 223.2h.2zM367 223h.2zM367 222.8h.2zM367 222.6h.2zM367 222.3h.2zM367 222.1h.2zM367 221.9h.2zM367 221.7h.2z"/>
<path d="M367 221.5h.2zM367.2 221.4v2.5zM370.2 227.7h3.8zM379.7 234.1l1.5-1.5zM379.7 234.1l1.5 1.5zM381.2 232.6h12.2zM381.2 235.6h12.2zM393.4 232.6v3zM135.9 245.5l-1.3 1.9zM135.9 245.5l1.2 1.9zM146 245.5l-1.2 1.9zM146 245.5l1.3 1.9z"/>
<path d="M313.7 249.3h86.3zM313.7 254.4h86.3zM313.7 259.5h58.4zM372.1 259.5h27.9zM372.1 259.5v5.1zM27.3 268.4h3.8zM144.1 268.4h3.8zM253.3 270.9h3.8zM313.7 264.6h58.4zM313.7 269.7h86.3zM372.1 264.6h27.9zM400 268.4v1.3z"/>
</g>
<path d="M16.5 18.2v260.3zM16.5 18.2h387.3zM16.5 278.5h387.3zM403.8 18.2v260.3z" fill="#000" stroke="#000" stroke-width=".32"/>
<g fill="#000" stroke="#000" stroke-width=".61">
<path d="M20.3 22.1v252.6zM20.3 22.1h379.7zM158.7 75.4v30.5zM158.7 75.4h15.3zM224.8 75.4v30.5zM224.8 75.4h15.2zM62.2 118.6v10.1zM87.6 103.3v22.9zM87.6 103.3h17.8zM158.7 105.9h15.3zM158.7 113.5v30.5zM174 75.4v30.5z"/>
<path d="M158.7 113.5h15.3zM224.8 105.9h15.2zM224.8 113.5v30.5zM240 75.4v30.5zM224.8 113.5h15.2zM280.6 110.9v30.5zM280.6 110.9h15.3zM62.2 131.3v10.1zM87.6 126.2h17.8zM105.4 103.3v22.9zM87.6 141.4v22.9zM87.6 141.4h17.8z"/>
<path d="M158.7 144h15.3zM158.7 151.6v30.5zM174 113.5v30.5zM158.7 151.6h15.3zM224.8 144h15.2zM224.8 151.6v30.5zM240 113.5v30.5zM224.8 151.6h15.2zM280.6 141.4h15.3zM280.6 151.6v30.5zM295.9 110.9v30.5zM280.6 151.6h15.3z"/>
<path d="M336.5 151.6v30.5zM336.5 151.6h15.2zM87.6 164.3h17.8zM105.4 141.4v22.9zM90.2 189.7v15.2zM90.2 189.7h15.2zM158.7 182.1h15.3zM158.7 189.7v30.4zM174 151.6v30.5zM158.7 189.7h15.3zM224.8 182.1h15.2zM224.8 189.7v30.4z"/>
<path d="M240 151.6v30.5zM224.8 189.7h15.2zM280.6 182.1h15.3zM295.9 151.6v30.5zM336.5 182.1h15.2zM351.7 151.6v30.5zM90.2 204.9h15.2zM90.2 215v15.3zM105.4 189.7v15.2zM90.2 215h15.2zM90.2 230.3h15.2zM105.4 215v15.3z"/>
<path d="M158.7 220.1h15.3zM174 189.7v30.4zM224.8 220.1h15.2zM240 189.7v30.4zM262.9 245.5v10.2zM262.9 258.2v10.2zM283.2 244.3v30.4zM313.7 254.4v5.1zM313.7 249.3v5.1zM313.7 244.3v5zM313.7 244.3h86.3zM283.2 244.3h30.5z"/>
<path d="M400 254.4v5.1zM400 249.3v5.1zM400 244.3v5zM400 22.1v222.2zM20.3 274.7h262.9zM283.2 274.7h30.5zM313.7 274.7h86.3zM313.7 269.7v5zM313.7 264.6v5.1zM313.7 259.5v5.1zM400 268.4v6.3zM400 264.6v3.8z"/>
<path d="M400 259.5v5.1z"/>
</g>
<path d="M62.2 118.6a5.1 5.1 0 0 1 5.1 5 5.1 5.1 0 0 1-5.1 5.1M62.2 131.3a5.1 5.1 0 0 1 5.1 5 5.1 5.1 0 0 1-5.1 5.1M262.9 245.5a5.1 5.1 0 0 1 5 5.1 5.1 5.1 0 0 1-5 5.1M262.9 258.2a5.1 5.1 0 0 1 5 5.1 5.1 5.1 0 0 1-5 5.1" fill="none" stroke="#000" stroke-width=".61"/>
<g fill="#000" stroke="#000" stroke-width=".21">
<path d="M367 110.9h25.4v10.2h-25.4zM27.2 256.2h4v.5h-4zM27.2 257.2h4v.5h-4zM34.8 256.2h4.1v.5h-4.1zM34.8 257.2h4.1v.5h-4.1zM42.4 256.2h4.1v.5h-4.1zM42.4 257.2h4.1v.5h-4.1zM50 256.2h4.1v.5h-4.1zM50 257.2h4.1v.5h-4.1zM57.7 256.2h4v.5h-4zM57.7 257.2h4v.5h-4zM65.3 256.2h4v.5h-4z"/>
<path d="M65.3 257.2h4v.5h-4zM72.9 256.2h4.1v.5h-4.1zM72.9 257.2h4.1v.5h-4.1zM80.5 256.2h4.1v.5h-4.1zM80.5 257.2h4.1v.5h-4.1zM88.1 256.2h4.1v.5h-4.1zM88.1 257.2h4.1v.5h-4.1zM95.8 256.2h4v.5h-4zM95.8 257.2h4v.5h-4zM103.4 256.2h4v.5h-4zM103.4 257.2h4v.5h-4zM111 256.2h4.1v.5h-4.1z"/>
<path d="M111 257.2h4.1v.5h-4.1zM118.6 256.2h4.1v.5h-4.1zM118.6 257.2h4.1v.5h-4.1zM126.2 256.2h4.1v.5h-4.1zM126.2 257.2h4.1v.5h-4.1zM133.8 256.2h4.1v.5h-4.1zM133.8 257.2h4.1v.5h-4.1zM144 257.2h4.1v.5h-4.1zM144 256.2h4.1v.5h-4.1z"/>
</g>
<g fill="none" stroke="#000" stroke-width=".21">
<circle cx="106.4" cy="116" r=".99"/>
<circle cx="106.4" cy="110.9" r=".99"/>
<circle cx="106.4" cy="108.4" r=".99"/>
<circle cx="106.4" cy="105.9" r=".99"/>
<circle cx="106.4" cy="118.6" r=".99"/>
<circle cx="106.4" cy="113.5" r=".99"/>
<circle cx="157.8" cy="103.3" r=".99"/>
<circle cx="223.8" cy="103.3" r="1"/>
<circle cx="86.6" cy="121.1" r=".99"/>
<circle cx="86.6" cy="123.6" r=".99"/>
<circle cx="106.4" cy="123.6" r=".99"/>
<circle cx="106.4" cy="121.1" r=".99"/>
<circle cx="279.6" cy="136.3" r="1"/>
<circle cx="279.6" cy="138.9" r="1"/>
<circle cx="86.6" cy="159.2" r=".99"/>
<circle cx="106.4" cy="154.1" r=".99"/>
<circle cx="106.4" cy="146.5" r=".99"/>
<circle cx="106.4" cy="159.2" r=".99"/>
<circle cx="106.4" cy="149" r=".99"/>
<circle cx="106.4" cy="156.7" r=".99"/>
<circle cx="106.4" cy="144" r=".99"/>
<circle cx="106.4" cy="151.6" r=".99"/>
<circle cx="157.8" cy="141.4" r=".99"/>
<circle cx="223.8" cy="141.4" r="1"/>
<circle cx="86.6" cy="161.7" r=".99"/>
<circle cx="106.4" cy="161.7" r=".99"/>
<circle cx="157.8" cy="179.5" r=".99"/>
<circle cx="223.8" cy="179.5" r="1"/>
<circle cx="279.6" cy="179.5" r="1"/>
<circle cx="279.6" cy="177" r="1"/>
<circle cx="335.5" cy="177" r="1"/>
<circle cx="335.5" cy="179.5" r="1"/>
<circle cx="89.2" cy="192.2" r=".99"/>
<circle cx="89.2" cy="217.6" r=".99"/>
<circle cx="89.2" cy="202.4" r=".99"/>
<circle cx="157.8" cy="217.6" r=".99"/>
<circle cx="223.8" cy="217.6" r="1"/>
<circle cx="89.2" cy="227.7" r=".99"/>
</g>
<g fill="#000" stroke="#000" stroke-width=".76">
<path d="M41.9 27.1h228.6zM41.9 34.8h86.3zM52.1 27.1l-5.1 5.1zM128.2 34.8h66.1zM128.2 34.8l2.6 2.5zM194.3 34.8l2.5 2.5zM191.7 72.8v134.6zM194.3 70.3l-2.6 2.5zM194.3 70.3h60.9zM255.2 70.3l2.6 2.5zM257.8 72.8v2.6zM257.8 75.4v132z"/>
<path d="M125.7 108.4v116.8zM135.9 103.3v121.9zM201.9 103.3v121.9zM316.2 116v76.2zM47 32.2v114.3zM372.1 156.7v27.9zM318.7 194.8h61zM316.2 192.2l2.5 2.6zM372.1 184.6l2.5 2.5zM374.6 187.1h5.1zM130.8 37.3v170.1zM196.8 37.3v170.1z"/>
<path d="M125.7 225.2l2.5 2.5zM128.2 227.7h10.2zM135.9 225.2l2.5 2.5zM138.4 227.7h61zM199.4 227.7l2.5-2.5z"/>
</g>
<path d="M336.5 110.9v10.2zM336.5 110.9h55.9zM336.5 121.1v7.6zM336.5 128.7h55.9zM336.5 121.1h55.9zM392.4 121.1v7.6zM392.4 110.9v10.2z" fill="#000" stroke="#000" stroke-width=".42"/>
<use href="#words"/>
</svg>
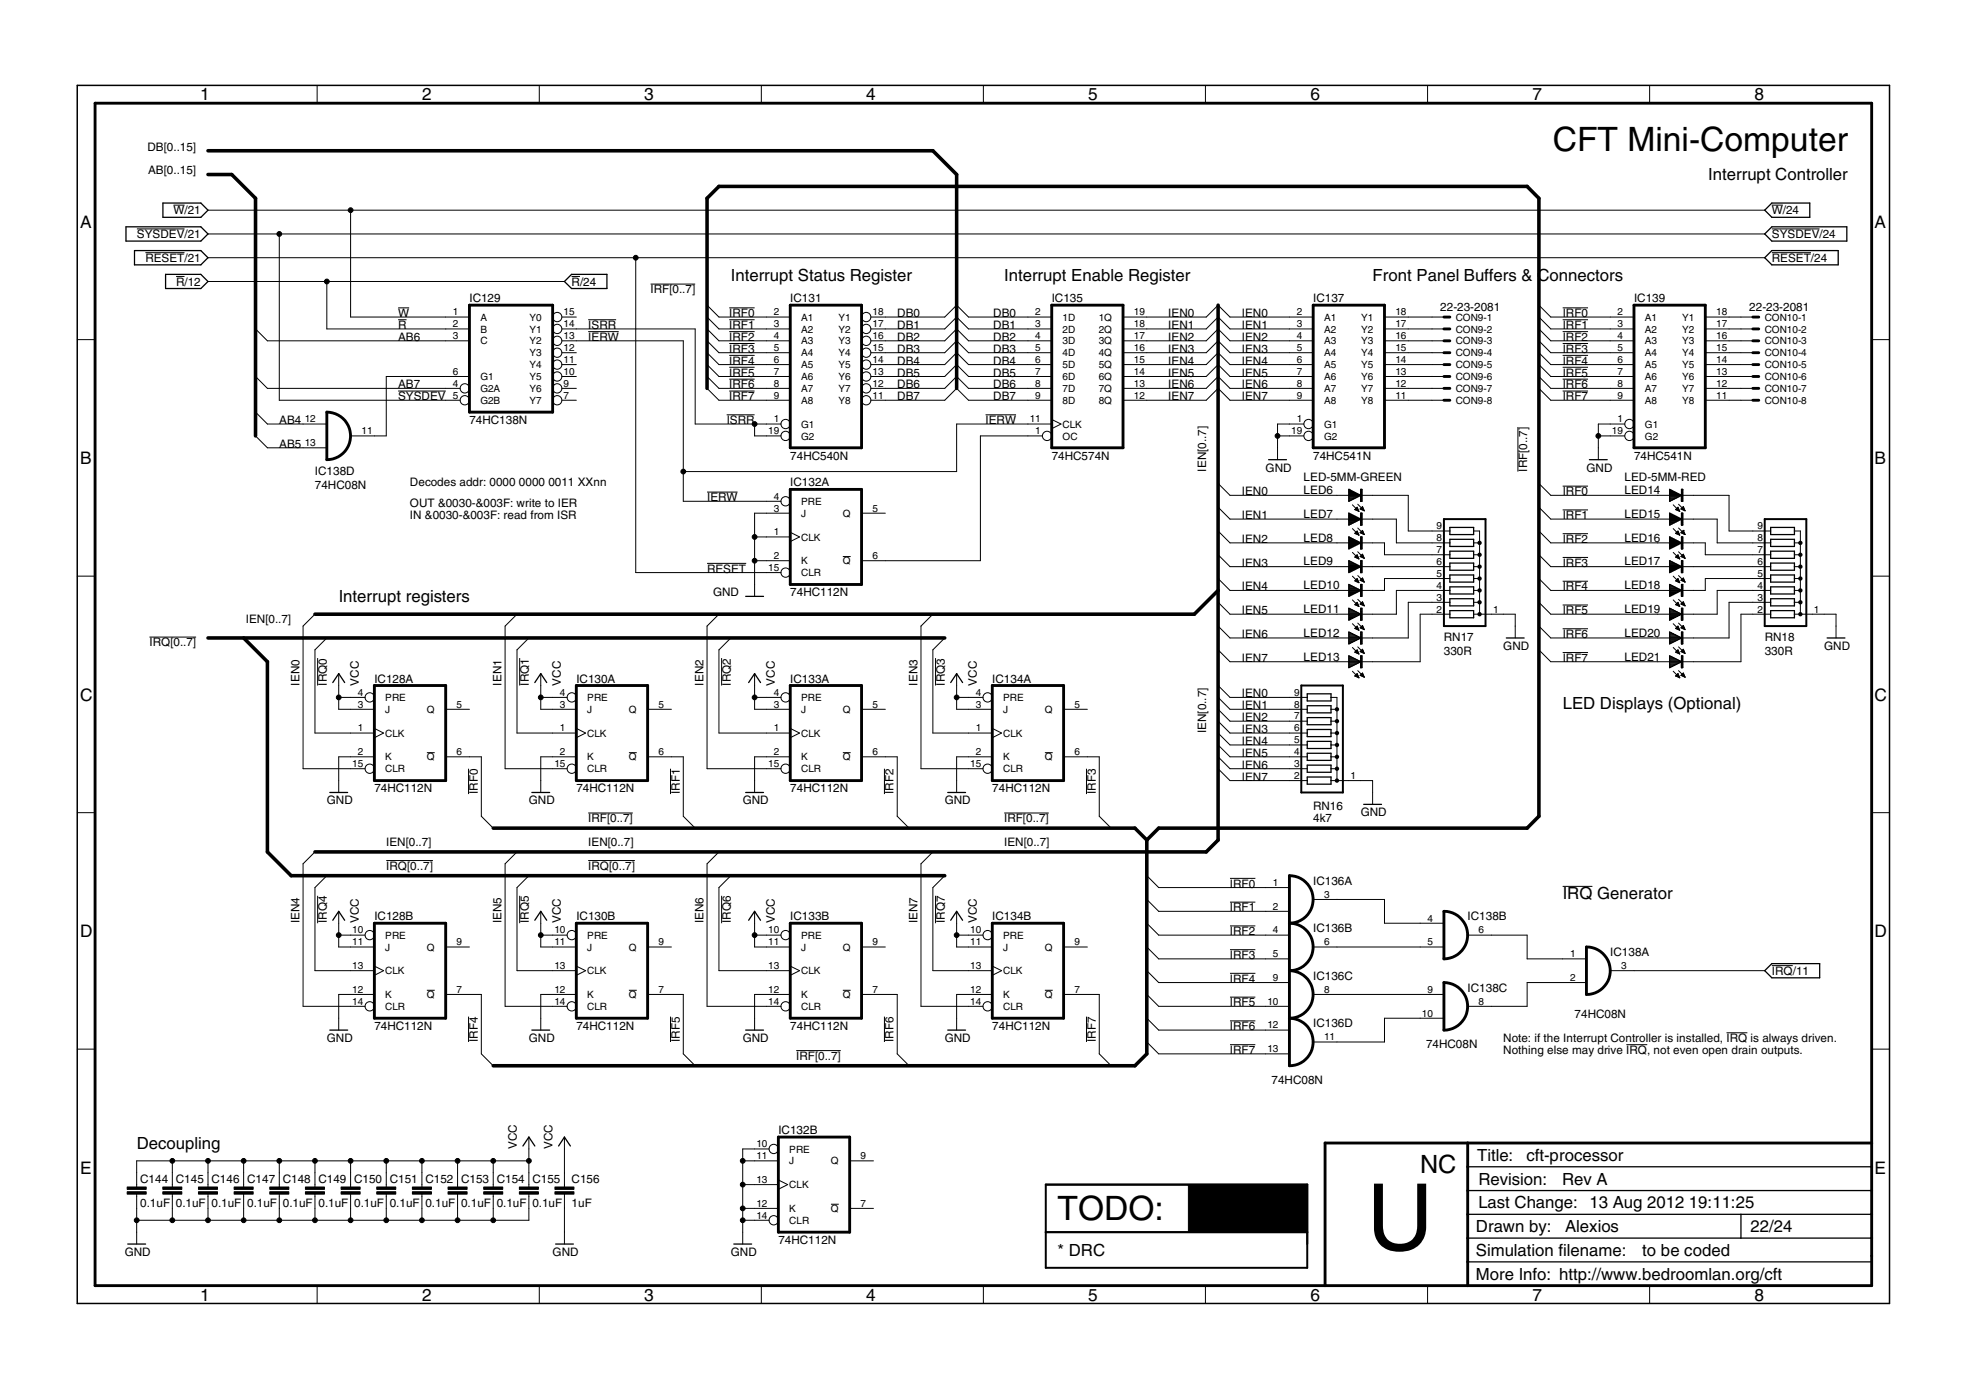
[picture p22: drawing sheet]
<svg xmlns="http://www.w3.org/2000/svg" width="420mm" height="297mm" viewBox="0 0 420 297" stroke-linecap="round" stroke-linejoin="round" font-family="sans-serif">
<defs><g id="words">
<text font-size="19.7" x="292.1" y="267.1">U</text>
<g font-size="7.2">
<text x="331.8" y="32.2">CFT Mini-Computer</text>
<text x="226" y="260.8">TODO:</text>
</g>
<text font-size="5.4" x="303.5" y="250.6">NC</text>
<g font-size="3.7">
<text x="42.7" y="21.5">1</text>
<text x="90.2" y="21.5">2</text>
<text x="137.7" y="21.5">3</text>
<text x="185.1" y="21.5">4</text>
<text x="232.6" y="21.5">5</text>
<text x="280" y="21.5">6</text>
<text x="327.5" y="21.5">7</text>
<text x="375" y="21.5">8</text>
<text x="17.1" y="48.6">A</text>
<text x="400.6" y="48.6">A</text>
<text x="17.1" y="99.2">B</text>
<text x="400.6" y="99.2">B</text>
<text x="17.1" y="149.7">C</text>
<text x="400.6" y="149.7">C</text>
<text x="17.1" y="200.2">D</text>
<text x="400.6" y="200.2">D</text>
<text x="17.1" y="250.8">E</text>
<text x="400.6" y="250.8">E</text>
<text x="42.7" y="277.9">1</text>
<text x="90.2" y="277.9">2</text>
<text x="137.7" y="277.9">3</text>
<text x="185.1" y="277.9">4</text>
<text x="232.6" y="277.9">5</text>
<text x="280" y="277.9">6</text>
<text x="327.5" y="277.9">7</text>
<text x="375" y="277.9">8</text>
</g>
<g font-size="3.6">
<text x="365.1" y="38.6">Interrupt Controller</text>
<text x="156.2" y="60.1">Interrupt Status Register</text>
<text x="214.6" y="60.1">Interrupt Enable Register</text>
<text x="293.3" y="60.1">Front Panel Buffers &amp; Connectors</text>
<text x="72.4" y="128.7">Interrupt registers</text>
<text x="334" y="151.6">LED Displays (Optional)</text>
<text x="334" y="192.2">IRQ Generator</text>
<text x="29.2" y="245.5">Decoupling</text>
<text x="315.7" y="248.1">Title:</text>
<text x="326.2" y="248.2">cft-processor</text>
<text x="315.9" y="253.2">Revision:</text>
<text x="333.8" y="253.3">Rev A</text>
<text x="315.4" y="263.3">Drawn by:</text>
<text x="315.9" y="258.2">Last Change: 13 Aug 2012</text>
<text x="334.5" y="263.3">Alexios</text>
<text x="361" y="258.1">19:11:25</text>
<text x="374.1" y="263.2">22/24</text>
<text x="226" y="268.4">* DRC</text>
<text x="315.4" y="268.4">Simulation filename:</text>
<text x="351" y="268.4">to be coded</text>
<text x="315.4" y="273.5">More Info: http://www.bedroomlan.org/cft</text>
</g>
<g font-size="2.5">
<text x="31.5" y="32.2">DB[0..15]</text>
<text x="31.7" y="37.3">AB[0..15]</text>
<text x="37.1" y="45.8">W/21</text>
<text x="378.7" y="45.8">W/24</text>
<text x="29.2" y="50.9">SYSDEV/21</text>
<text x="378.7" y="50.9">SYSDEV/24</text>
<text x="31.1" y="56">RESET/21</text>
<text x="378.7" y="56">RESET/24</text>
<text x="37.6" y="61">R/12</text>
<text x="100.3" y="64.6">IC129</text>
<text x="122.2" y="61">R/24</text>
<text x="139" y="62.7">IRF[0..7]</text>
<text x="168.9" y="64.6">IC131</text>
<text x="224.8" y="64.6">IC135</text>
<text x="280.6" y="64.6">IC137</text>
<text x="349.2" y="64.6">IC139</text>
<text x="85.1" y="67.8">W</text>
<text x="85.1" y="70.3">R</text>
<text x="125.7" y="70.3">ISRR</text>
<text x="155.9" y="67.8">IRF0</text>
<text x="155.9" y="70.3">IRF1</text>
<text x="191.7" y="67.8">DB0</text>
<text x="191.7" y="70.3">DB1</text>
<text x="212.3" y="67.8">DB0</text>
<text x="212.3" y="70.3">DB1</text>
<text x="249.7" y="70.3">IEN1</text>
<text x="249.7" y="67.8">IEN0</text>
<text x="265.4" y="70.3">IEN1</text>
<text x="265.4" y="67.8">IEN0</text>
<text x="307.8" y="66.4">22-23-2081</text>
<text x="334" y="67.8">IRF0</text>
<text x="334" y="70.3">IRF1</text>
<text x="373.8" y="66.4">22-23-2081</text>
<text x="85.1" y="72.8">AB6</text>
<text x="125.7" y="72.8">IERW</text>
<text x="155.9" y="72.8">IRF2</text>
<text x="155.9" y="75.4">IRF3</text>
<text x="155.9" y="77.9">IRF4</text>
<text x="191.7" y="72.8">DB2</text>
<text x="191.7" y="75.4">DB3</text>
<text x="191.7" y="77.9">DB4</text>
<text x="212.3" y="72.8">DB2</text>
<text x="212.3" y="75.4">DB3</text>
<text x="212.3" y="77.9">DB4</text>
<text x="249.7" y="77.9">IEN4</text>
<text x="249.7" y="72.8">IEN2</text>
<text x="249.7" y="75.4">IEN3</text>
<text x="265.4" y="77.9">IEN4</text>
<text x="265.4" y="72.8">IEN2</text>
<text x="265.4" y="75.4">IEN3</text>
<text x="334" y="72.8">IRF2</text>
<text x="334" y="75.4">IRF3</text>
<text x="334" y="77.9">IRF4</text>
<text x="85.1" y="83">AB7</text>
<text x="155.9" y="80.5">IRF5</text>
<text x="155.9" y="83">IRF6</text>
<text x="191.7" y="80.5">DB5</text>
<text x="191.7" y="83">DB6</text>
<text x="212.3" y="80.5">DB5</text>
<text x="212.3" y="83">DB6</text>
<text x="249.7" y="80.5">IEN5</text>
<text x="249.7" y="83">IEN6</text>
<text x="265.4" y="80.5">IEN5</text>
<text x="265.4" y="83">IEN6</text>
<text x="334" y="80.5">IRF5</text>
<text x="334" y="83">IRF6</text>
<text x="85.1" y="85.5">SYSDEV</text>
<text x="155.9" y="85.5">IRF7</text>
<text x="191.7" y="85.5">DB7</text>
<text x="212.3" y="85.5">DB7</text>
<text x="249.7" y="85.5">IEN7</text>
<text x="265.4" y="85.5">IEN7</text>
<text x="334" y="85.5">IRF7</text>
<text x="59.7" y="90.6">AB4</text>
<text x="59.7" y="95.7">AB5</text>
<text x="100.3" y="90.6">74HC138N</text>
<text x="155.3" y="90.6">ISRR</text>
<text x="210.6" y="90.6">IERW</text>
<text x="67.3" y="101.4">IC138D</text>
<text x="168.9" y="98.2">74HC540N</text>
<text x="224.8" y="98.2">74HC574N</text>
<text x="257.8" y="100.8" transform="rotate(-90 257.8 100.8)">IEN[0..7]</text>
<text x="270.5" y="100.8">GND</text>
<text x="280.6" y="98.2">74HC541N</text>
<text x="326.4" y="100.8" transform="rotate(-90 326.4 100.8)">IRF[0..7]</text>
<text x="339.1" y="100.8">GND</text>
<text x="349.2" y="98.2">74HC541N</text>
<text x="67.3" y="104.6">74HC08N</text>
<text x="87.6" y="103.8">Decodes addr: 0000</text>
<text x="110.9" y="103.8">0000</text>
<text x="117.2" y="103.8">0011 XXnn</text>
<text x="151.1" y="107.1">IERW</text>
<text x="168.9" y="104">IC132A</text>
<text x="265.4" y="105.9">IEN0</text>
<text x="278.6" y="102.7">LED-5MM-GREEN</text>
<text x="278.6" y="105.6">LED6</text>
<text x="334" y="105.9">IRF0</text>
<text x="347.2" y="102.7">LED-5MM-RED</text>
<text x="347.2" y="105.6">LED14</text>
<text x="87.6" y="108.4">OUT &amp;0030-&amp;003F: write to IER</text>
<text x="87.6" y="110.9">IN &amp;0030-&amp;003F: read from ISR</text>
<text x="265.4" y="110.9">IEN1</text>
<text x="278.6" y="110.7">LED7</text>
<text x="334" y="110.9">IRF1</text>
<text x="347.2" y="110.7">LED15</text>
<text x="265.4" y="116">IEN2</text>
<text x="278.6" y="115.8">LED8</text>
<text x="334" y="116">IRF2</text>
<text x="347.2" y="115.8">LED16</text>
<text x="151.1" y="122.4">RESET</text>
<text x="265.4" y="121.1">IEN3</text>
<text x="278.6" y="120.8">LED9</text>
<text x="278.6" y="125.9">LED10</text>
<text x="334" y="121.1">IRF3</text>
<text x="347.2" y="120.8">LED17</text>
<text x="347.2" y="125.9">LED18</text>
<text x="152.4" y="127.4">GND</text>
<text x="168.9" y="127.4">74HC112N</text>
<text x="265.4" y="126.2">IEN4</text>
<text x="265.4" y="131.3">IEN5</text>
<text x="278.6" y="131">LED11</text>
<text x="334" y="126.2">IRF4</text>
<text x="334" y="131.3">IRF5</text>
<text x="347.2" y="131">LED19</text>
<text x="52.6" y="133">IEN[0..7]</text>
<text x="265.4" y="136.3">IEN6</text>
<text x="278.6" y="136.1">LED12</text>
<text x="308.6" y="137">RN17</text>
<text x="334" y="136.3">IRF6</text>
<text x="347.2" y="136.1">LED20</text>
<text x="377.1" y="137">RN18</text>
<text x="31.9" y="138.1">IRQ[0..7]</text>
<text x="265.4" y="141.4">IEN7</text>
<text x="278.6" y="141.2">LED13</text>
<text x="308.6" y="140">330R</text>
<text x="321.3" y="138.9">GND</text>
<text x="334" y="141.4">IRF7</text>
<text x="347.2" y="141.2">LED21</text>
<text x="377.1" y="140">330R</text>
<text x="389.8" y="138.9">GND</text>
<text x="64" y="146.5" transform="rotate(-90 64 146.5)">IEN0</text>
<text x="69.8" y="146.5" transform="rotate(-90 69.8 146.5)">IRQ0</text>
<text x="76.7" y="146.5" transform="rotate(-90 76.7 146.5)">VCC</text>
<text x="80" y="145.9">IC128A</text>
<text x="107.2" y="146.5" transform="rotate(-90 107.2 146.5)">IEN1</text>
<text x="113" y="146.5" transform="rotate(-90 113 146.5)">IRQ1</text>
<text x="119.9" y="146.5" transform="rotate(-90 119.9 146.5)">VCC</text>
<text x="123.2" y="145.9">IC130A</text>
<text x="150.4" y="146.5" transform="rotate(-90 150.4 146.5)">IEN2</text>
<text x="156.2" y="146.5" transform="rotate(-90 156.2 146.5)">IRQ2</text>
<text x="165.6" y="146.5" transform="rotate(-90 165.6 146.5)">VCC</text>
<text x="168.9" y="145.9">IC133A</text>
<text x="196.1" y="146.5" transform="rotate(-90 196.1 146.5)">IEN3</text>
<text x="201.9" y="146.5" transform="rotate(-90 201.9 146.5)">IRQ3</text>
<text x="208.8" y="146.5" transform="rotate(-90 208.8 146.5)">VCC</text>
<text x="212.1" y="145.9">IC134A</text>
<text x="265.4" y="149">IEN0</text>
<text x="265.4" y="151.6">IEN1</text>
<text x="265.4" y="154.1">IEN2</text>
<text x="257.8" y="156.6" transform="rotate(-90 257.8 156.6)">IEN[0..7]</text>
<text x="265.4" y="159.2">IEN4</text>
<text x="265.4" y="161.7">IEN5</text>
<text x="265.4" y="156.6">IEN3</text>
<text x="265.4" y="164.3">IEN6</text>
<text x="265.4" y="166.8">IEN7</text>
<text x="69.8" y="171.9">GND</text>
<text x="80" y="169.3">74HC112N</text>
<text x="102.1" y="169.7" transform="rotate(-90 102.1 169.7)">IRF0</text>
<text x="113" y="171.9">GND</text>
<text x="123.2" y="169.3">74HC112N</text>
<text x="145.3" y="169.7" transform="rotate(-90 145.3 169.7)">IRF1</text>
<text x="158.7" y="171.9">GND</text>
<text x="168.9" y="169.3">74HC112N</text>
<text x="191" y="169.7" transform="rotate(-90 191 169.7)">IRF2</text>
<text x="201.9" y="171.9">GND</text>
<text x="212.1" y="169.3">74HC112N</text>
<text x="234.2" y="169.7" transform="rotate(-90 234.2 169.7)">IRF3</text>
<text x="280.6" y="173">RN16</text>
<text x="125.7" y="175.7">IRF[0..7]</text>
<text x="214.6" y="175.7">IRF[0..7]</text>
<text x="280.6" y="175.6">4k7</text>
<text x="290.8" y="174.4">GND</text>
<text x="82.5" y="185.9">IRQ[0..7]</text>
<text x="82.5" y="180.8">IEN[0..7]</text>
<text x="125.7" y="185.9">IRQ[0..7]</text>
<text x="125.7" y="180.8">IEN[0..7]</text>
<text x="214.6" y="180.8">IEN[0..7]</text>
<text x="262.9" y="189.7">IRF0</text>
<text x="280.6" y="189">IC136A</text>
<text x="64" y="197.3" transform="rotate(-90 64 197.3)">IEN4</text>
<text x="69.8" y="197.3" transform="rotate(-90 69.8 197.3)">IRQ4</text>
<text x="76.7" y="197.3" transform="rotate(-90 76.7 197.3)">VCC</text>
<text x="80" y="196.6">IC128B</text>
<text x="107.2" y="197.3" transform="rotate(-90 107.2 197.3)">IEN5</text>
<text x="113" y="197.3" transform="rotate(-90 113 197.3)">IRQ5</text>
<text x="119.9" y="197.3" transform="rotate(-90 119.9 197.3)">VCC</text>
<text x="123.2" y="196.6">IC130B</text>
<text x="150.4" y="197.3" transform="rotate(-90 150.4 197.3)">IEN6</text>
<text x="156.2" y="197.3" transform="rotate(-90 156.2 197.3)">IRQ6</text>
<text x="165.6" y="197.3" transform="rotate(-90 165.6 197.3)">VCC</text>
<text x="168.9" y="196.6">IC133B</text>
<text x="196.1" y="197.3" transform="rotate(-90 196.1 197.3)">IEN7</text>
<text x="201.9" y="197.3" transform="rotate(-90 201.9 197.3)">IRQ7</text>
<text x="208.8" y="197.3" transform="rotate(-90 208.8 197.3)">VCC</text>
<text x="212.1" y="196.6">IC134B</text>
<text x="262.9" y="194.7">IRF1</text>
<text x="313.7" y="196.6">IC138B</text>
<text x="262.9" y="199.8">IRF2</text>
<text x="280.6" y="199.2">IC136B</text>
<text x="262.9" y="204.9">IRF3</text>
<text x="262.9" y="210">IRF4</text>
<text x="280.6" y="209.3">IC136C</text>
<text x="344.1" y="204.3">IC138A</text>
<text x="378.7" y="208.3">IRQ/11</text>
<text x="262.9" y="215.1">IRF5</text>
<text x="313.7" y="211.9">IC138C</text>
<text x="80" y="220.1">74HC112N</text>
<text x="123.2" y="220.1">74HC112N</text>
<text x="168.9" y="220.1">74HC112N</text>
<text x="212.1" y="220.1">74HC112N</text>
<text x="262.9" y="220.1">IRF6</text>
<text x="280.6" y="219.5">IC136D</text>
<text x="336.5" y="217.6">74HC08N</text>
<text x="69.8" y="222.7">GND</text>
<text x="102.1" y="222.7" transform="rotate(-90 102.1 222.7)">IRF4</text>
<text x="113" y="222.7">GND</text>
<text x="145.3" y="222.7" transform="rotate(-90 145.3 222.7)">IRF5</text>
<text x="158.7" y="222.7">GND</text>
<text x="170.2" y="226.5">IRF[0..7]</text>
<text x="191" y="222.7" transform="rotate(-90 191 222.7)">IRF6</text>
<text x="201.9" y="222.7">GND</text>
<text x="234.2" y="222.7" transform="rotate(-90 234.2 222.7)">IRF7</text>
<text x="262.9" y="225.2">IRF7</text>
<text x="304.8" y="223.9">74HC08N</text>
<text x="321.3" y="222.7">Note: if the Interrupt Controller is installed, IRQ is always driven.</text>
<text x="321.3" y="225.2">Nothing else may drive IRQ, not even open drain outputs.</text>
<text x="271.7" y="231.6">74HC08N</text>
<text x="110.5" y="245.5" transform="rotate(-90 110.5 245.5)">VCC</text>
<text x="118.1" y="245.5" transform="rotate(-90 118.1 245.5)">VCC</text>
<text x="166.4" y="242.4">IC132B</text>
<text x="30" y="257.9">0.1uF</text>
<text x="30" y="252.8">C144</text>
<text x="37.6" y="257.9">0.1uF</text>
<text x="37.6" y="252.8">C145</text>
<text x="45.2" y="257.9">0.1uF</text>
<text x="45.2" y="252.8">C146</text>
<text x="52.8" y="257.9">0.1uF</text>
<text x="52.8" y="252.8">C147</text>
<text x="60.4" y="257.9">0.1uF</text>
<text x="60.4" y="252.8">C148</text>
<text x="68.1" y="257.9">0.1uF</text>
<text x="68.1" y="252.8">C149</text>
<text x="75.7" y="257.9">0.1uF</text>
<text x="75.7" y="252.8">C150</text>
<text x="83.3" y="257.9">0.1uF</text>
<text x="83.3" y="252.8">C151</text>
<text x="90.9" y="257.9">0.1uF</text>
<text x="90.9" y="252.8">C152</text>
<text x="98.5" y="257.9">0.1uF</text>
<text x="98.5" y="252.8">C153</text>
<text x="106.2" y="257.9">0.1uF</text>
<text x="106.2" y="252.8">C154</text>
<text x="113.8" y="257.9">0.1uF</text>
<text x="113.8" y="252.8">C155</text>
<text x="122.2" y="257.9">1uF</text>
<text x="122.2" y="252.8">C156</text>
<text x="26.7" y="268.4">GND</text>
<text x="118.1" y="268.4">GND</text>
<text x="156.2" y="268.4">GND</text>
<text x="166.4" y="265.8">74HC112N</text>
</g>
<g font-size="2.1">
<text x="96.8" y="67.4">1</text>
<text x="96.8" y="69.9">2</text>
<text x="102.7" y="68.5">A</text>
<text x="102.7" y="71.1">B</text>
<text x="113.1" y="71.1">Y1</text>
<text x="113.1" y="68.5">Y0</text>
<text x="120.4" y="69.9">14</text>
<text x="120.4" y="67.4">15</text>
<text x="165.4" y="67.4">2</text>
<text x="165.4" y="69.9">3</text>
<text x="171.2" y="68.5">A1</text>
<text x="171.2" y="71.1">A2</text>
<text x="179.2" y="71.1">Y2</text>
<text x="179.2" y="68.5">Y1</text>
<text x="186.5" y="69.9">17</text>
<text x="186.5" y="67.4">18</text>
<text x="221.2" y="67.4">2</text>
<text x="221.2" y="69.9">3</text>
<text x="227.1" y="68.5">1D</text>
<text x="227.1" y="71.1">2D</text>
<text x="234.8" y="71.1">2Q</text>
<text x="234.8" y="68.5">1Q</text>
<text x="242.3" y="69.9">18</text>
<text x="242.3" y="67.4">19</text>
<text x="277.1" y="67.4">2</text>
<text x="277.1" y="69.9">3</text>
<text x="283" y="68.5">A1</text>
<text x="283" y="71.1">A2</text>
<text x="290.9" y="71.1">Y2</text>
<text x="290.9" y="68.5">Y1</text>
<text x="298.2" y="69.9">17</text>
<text x="298.2" y="67.4">18</text>
<text x="311.1" y="68.5">CON9-1</text>
<text x="311.1" y="71.1">CON9-2</text>
<text x="345.7" y="67.4">2</text>
<text x="345.7" y="69.9">3</text>
<text x="351.5" y="68.5">A1</text>
<text x="351.5" y="71.1">A2</text>
<text x="359.5" y="71.1">Y2</text>
<text x="359.5" y="68.5">Y1</text>
<text x="366.8" y="69.9">17</text>
<text x="366.8" y="67.4">18</text>
<text x="377.1" y="68.5">CON10-1</text>
<text x="377.1" y="71.1">CON10-2</text>
<text x="96.8" y="72.5">3</text>
<text x="102.7" y="73.6">C</text>
<text x="113.1" y="76.1">Y3</text>
<text x="113.1" y="73.6">Y2</text>
<text x="120.4" y="77.6">11</text>
<text x="120.4" y="75">12</text>
<text x="120.4" y="72.5">13</text>
<text x="165.4" y="72.5">4</text>
<text x="165.4" y="75">5</text>
<text x="165.4" y="77.6">6</text>
<text x="171.2" y="73.6">A3</text>
<text x="171.2" y="76.1">A4</text>
<text x="179.2" y="76.1">Y4</text>
<text x="179.2" y="73.6">Y3</text>
<text x="186.5" y="77.6">14</text>
<text x="186.5" y="75">15</text>
<text x="186.5" y="72.5">16</text>
<text x="221.2" y="72.5">4</text>
<text x="221.2" y="75">5</text>
<text x="221.2" y="77.6">6</text>
<text x="227.1" y="73.6">3D</text>
<text x="227.1" y="76.1">4D</text>
<text x="234.8" y="76.1">4Q</text>
<text x="234.8" y="73.6">3Q</text>
<text x="242.3" y="77.6">15</text>
<text x="242.3" y="75">16</text>
<text x="242.3" y="72.5">17</text>
<text x="277.1" y="72.5">4</text>
<text x="277.1" y="75">5</text>
<text x="277.1" y="77.6">6</text>
<text x="283" y="73.6">A3</text>
<text x="283" y="76.1">A4</text>
<text x="290.9" y="76.1">Y4</text>
<text x="290.9" y="73.6">Y3</text>
<text x="298.2" y="77.6">14</text>
<text x="298.2" y="75">15</text>
<text x="298.2" y="72.5">16</text>
<text x="311.1" y="73.6">CON9-3</text>
<text x="311.1" y="76.1">CON9-4</text>
<text x="345.7" y="72.5">4</text>
<text x="345.7" y="75">5</text>
<text x="345.7" y="77.6">6</text>
<text x="351.5" y="73.6">A3</text>
<text x="351.5" y="76.1">A4</text>
<text x="359.5" y="76.1">Y4</text>
<text x="359.5" y="73.6">Y3</text>
<text x="366.8" y="77.6">14</text>
<text x="366.8" y="75">15</text>
<text x="366.8" y="72.5">16</text>
<text x="377.1" y="73.6">CON10-3</text>
<text x="377.1" y="76.1">CON10-4</text>
<text x="96.8" y="82.6">4</text>
<text x="96.8" y="80.1">6</text>
<text x="102.7" y="83.8">G2A</text>
<text x="102.7" y="81.2">G1</text>
<text x="113.1" y="83.8">Y6</text>
<text x="113.1" y="81.2">Y5</text>
<text x="113.1" y="78.7">Y4</text>
<text x="120.4" y="82.6">9</text>
<text x="120.4" y="80.1">10</text>
<text x="165.4" y="80.1">7</text>
<text x="165.4" y="82.6">8</text>
<text x="171.2" y="78.7">A5</text>
<text x="171.2" y="81.2">A6</text>
<text x="171.2" y="83.8">A7</text>
<text x="179.2" y="83.8">Y7</text>
<text x="179.2" y="81.2">Y6</text>
<text x="179.2" y="78.7">Y5</text>
<text x="186.5" y="82.6">12</text>
<text x="186.5" y="80.1">13</text>
<text x="221.2" y="80.1">7</text>
<text x="221.2" y="82.6">8</text>
<text x="227.1" y="78.7">5D</text>
<text x="227.1" y="81.2">6D</text>
<text x="227.1" y="83.8">7D</text>
<text x="234.8" y="83.8">7Q</text>
<text x="234.8" y="81.2">6Q</text>
<text x="234.8" y="78.7">5Q</text>
<text x="242.3" y="82.6">13</text>
<text x="242.3" y="80.1">14</text>
<text x="277.1" y="80.1">7</text>
<text x="277.1" y="82.6">8</text>
<text x="283" y="78.7">A5</text>
<text x="283" y="81.2">A6</text>
<text x="283" y="83.8">A7</text>
<text x="290.9" y="83.8">Y7</text>
<text x="290.9" y="81.2">Y6</text>
<text x="290.9" y="78.7">Y5</text>
<text x="298.2" y="82.6">12</text>
<text x="298.2" y="80.1">13</text>
<text x="311.1" y="78.7">CON9-5</text>
<text x="311.1" y="81.2">CON9-6</text>
<text x="311.1" y="83.8">CON9-7</text>
<text x="345.7" y="80.1">7</text>
<text x="345.7" y="82.6">8</text>
<text x="351.5" y="78.7">A5</text>
<text x="351.5" y="81.2">A6</text>
<text x="351.5" y="83.8">A7</text>
<text x="359.5" y="83.8">Y7</text>
<text x="359.5" y="81.2">Y6</text>
<text x="359.5" y="78.7">Y5</text>
<text x="366.8" y="82.6">12</text>
<text x="366.8" y="80.1">13</text>
<text x="377.1" y="78.7">CON10-5</text>
<text x="377.1" y="81.2">CON10-6</text>
<text x="377.1" y="83.8">CON10-7</text>
<text x="96.8" y="85.2">5</text>
<text x="102.7" y="86.3">G2B</text>
<text x="113.1" y="86.3">Y7</text>
<text x="120.4" y="85.2">7</text>
<text x="165.4" y="85.2">9</text>
<text x="171.2" y="86.3">A8</text>
<text x="179.2" y="86.3">Y8</text>
<text x="186.5" y="85.2">11</text>
<text x="221.2" y="85.2">9</text>
<text x="227.1" y="86.3">8D</text>
<text x="234.8" y="86.3">8Q</text>
<text x="242.3" y="85.2">12</text>
<text x="277.1" y="85.2">9</text>
<text x="283" y="86.3">A8</text>
<text x="290.9" y="86.3">Y8</text>
<text x="298.2" y="85.2">11</text>
<text x="311.1" y="86.3">CON9-8</text>
<text x="345.7" y="85.2">9</text>
<text x="351.5" y="86.3">A8</text>
<text x="359.5" y="86.3">Y8</text>
<text x="366.8" y="85.2">11</text>
<text x="377.1" y="86.3">CON10-8</text>
<text x="65.1" y="90.3">12</text>
<text x="65.1" y="95.3">13</text>
<text x="77.3" y="92.8">11</text>
<text x="164.2" y="92.8">19</text>
<text x="165.4" y="90.3">1</text>
<text x="171.2" y="91.4">G1</text>
<text x="171.2" y="93.9">G2</text>
<text x="220.1" y="90.3">11</text>
<text x="221.2" y="92.8">1</text>
<text x="227.1" y="93.9">OC</text>
<text x="227.1" y="91.4">CLK</text>
<text x="275.9" y="92.8">19</text>
<text x="277.1" y="90.3">1</text>
<text x="283" y="91.4">G1</text>
<text x="283" y="93.9">G2</text>
<text x="344.5" y="92.8">19</text>
<text x="345.7" y="90.3">1</text>
<text x="351.5" y="91.4">G1</text>
<text x="351.5" y="93.9">G2</text>
<text x="165.4" y="106.8">4</text>
<text x="171.2" y="107.9">PRE</text>
<text x="165.4" y="109.3">3</text>
<text x="171.2" y="110.4">J</text>
<text x="180.1" y="110.4">Q</text>
<text x="186.5" y="109.3">5</text>
<text x="307" y="113.1">9</text>
<text x="375.6" y="113.1">9</text>
<text x="165.4" y="114.4">1</text>
<text x="165.4" y="119.5">2</text>
<text x="171.2" y="115.5">CLK</text>
<text x="186.5" y="119.5">6</text>
<text x="307" y="118.2">7</text>
<text x="307" y="115.7">8</text>
<text x="375.6" y="118.2">7</text>
<text x="375.6" y="115.7">8</text>
<text x="164.2" y="122">15</text>
<text x="171.2" y="120.6">K</text>
<text x="171.2" y="123.1">CLR</text>
<text x="180.1" y="120.6">Q</text>
<text x="307" y="125.8">4</text>
<text x="307" y="123.3">5</text>
<text x="307" y="120.7">6</text>
<text x="375.6" y="125.8">4</text>
<text x="375.6" y="123.3">5</text>
<text x="375.6" y="120.7">6</text>
<text x="307" y="130.9">2</text>
<text x="307" y="128.4">3</text>
<text x="319.1" y="130.9">1</text>
<text x="375.6" y="130.9">2</text>
<text x="375.6" y="128.4">3</text>
<text x="387.7" y="130.9">1</text>
<text x="76.5" y="148.7">4</text>
<text x="82.3" y="149.8">PRE</text>
<text x="119.7" y="148.7">4</text>
<text x="125.5" y="149.8">PRE</text>
<text x="165.4" y="148.7">4</text>
<text x="171.2" y="149.8">PRE</text>
<text x="208.5" y="148.7">4</text>
<text x="214.4" y="149.8">PRE</text>
<text x="276.6" y="148.7">9</text>
<text x="76.5" y="151.2">3</text>
<text x="82.3" y="152.3">J</text>
<text x="91.2" y="152.3">Q</text>
<text x="97.6" y="151.2">5</text>
<text x="119.7" y="151.2">3</text>
<text x="125.5" y="152.3">J</text>
<text x="134.4" y="152.3">Q</text>
<text x="140.8" y="151.2">5</text>
<text x="165.4" y="151.2">3</text>
<text x="171.2" y="152.3">J</text>
<text x="180.1" y="152.3">Q</text>
<text x="186.5" y="151.2">5</text>
<text x="208.5" y="151.2">3</text>
<text x="214.4" y="152.3">J</text>
<text x="223.3" y="152.3">Q</text>
<text x="229.6" y="151.2">5</text>
<text x="276.6" y="153.8">7</text>
<text x="276.6" y="151.2">8</text>
<text x="76.5" y="156.3">1</text>
<text x="76.5" y="161.4">2</text>
<text x="82.3" y="157.4">CLK</text>
<text x="97.6" y="161.4">6</text>
<text x="119.7" y="156.3">1</text>
<text x="119.7" y="161.4">2</text>
<text x="125.5" y="157.4">CLK</text>
<text x="140.8" y="161.4">6</text>
<text x="165.4" y="156.3">1</text>
<text x="165.4" y="161.4">2</text>
<text x="171.2" y="157.4">CLK</text>
<text x="186.5" y="161.4">6</text>
<text x="208.5" y="156.3">1</text>
<text x="208.5" y="161.4">2</text>
<text x="214.4" y="157.4">CLK</text>
<text x="229.6" y="161.4">6</text>
<text x="276.6" y="161.4">4</text>
<text x="276.6" y="158.8">5</text>
<text x="276.6" y="156.3">6</text>
<text x="75.3" y="163.9">15</text>
<text x="82.3" y="162.5">K</text>
<text x="82.3" y="165">CLR</text>
<text x="91.2" y="162.5">Q</text>
<text x="118.5" y="163.9">15</text>
<text x="125.5" y="162.5">K</text>
<text x="125.5" y="165">CLR</text>
<text x="134.4" y="162.5">Q</text>
<text x="164.2" y="163.9">15</text>
<text x="171.2" y="162.5">K</text>
<text x="171.2" y="165">CLR</text>
<text x="180.1" y="162.5">Q</text>
<text x="207.4" y="163.9">15</text>
<text x="214.4" y="162.5">K</text>
<text x="214.4" y="165">CLR</text>
<text x="223.3" y="162.5">Q</text>
<text x="276.6" y="166.5">2</text>
<text x="276.6" y="163.9">3</text>
<text x="288.6" y="166.5">1</text>
<text x="272" y="189.3">1</text>
<text x="283" y="191.8">3</text>
<text x="272" y="194.4">2</text>
<text x="305.1" y="196.9">4</text>
<text x="75.3" y="202">11</text>
<text x="75.3" y="199.5">10</text>
<text x="82.3" y="203.1">J</text>
<text x="82.3" y="200.6">PRE</text>
<text x="91.2" y="203.1">Q</text>
<text x="97.6" y="202">9</text>
<text x="118.5" y="202">11</text>
<text x="118.5" y="199.5">10</text>
<text x="125.5" y="203.1">J</text>
<text x="125.5" y="200.6">PRE</text>
<text x="134.4" y="203.1">Q</text>
<text x="140.8" y="202">9</text>
<text x="164.2" y="202">11</text>
<text x="164.2" y="199.5">10</text>
<text x="171.2" y="203.1">J</text>
<text x="171.2" y="200.6">PRE</text>
<text x="180.1" y="203.1">Q</text>
<text x="186.5" y="202">9</text>
<text x="207.4" y="202">11</text>
<text x="207.4" y="199.5">10</text>
<text x="214.4" y="203.1">J</text>
<text x="214.4" y="200.6">PRE</text>
<text x="223.3" y="203.1">Q</text>
<text x="229.6" y="202">9</text>
<text x="272" y="199.5">4</text>
<text x="283" y="202">6</text>
<text x="305.1" y="202">5</text>
<text x="316" y="199.5">6</text>
<text x="75.3" y="207.1">13</text>
<text x="82.3" y="208.2">CLK</text>
<text x="118.5" y="207.1">13</text>
<text x="125.5" y="208.2">CLK</text>
<text x="164.2" y="207.1">13</text>
<text x="171.2" y="208.2">CLK</text>
<text x="207.4" y="207.1">13</text>
<text x="214.4" y="208.2">CLK</text>
<text x="272" y="204.5">5</text>
<text x="272" y="209.6">9</text>
<text x="335.5" y="204.5">1</text>
<text x="335.5" y="209.6">2</text>
<text x="346.5" y="207.1">3</text>
<text x="75.3" y="212.2">12</text>
<text x="75.3" y="214.7">14</text>
<text x="82.3" y="213.3">K</text>
<text x="82.3" y="215.8">CLR</text>
<text x="91.2" y="213.3">Q</text>
<text x="97.6" y="212.2">7</text>
<text x="118.5" y="212.2">12</text>
<text x="118.5" y="214.7">14</text>
<text x="125.5" y="213.3">K</text>
<text x="125.5" y="215.8">CLR</text>
<text x="134.4" y="213.3">Q</text>
<text x="140.8" y="212.2">7</text>
<text x="164.2" y="212.2">12</text>
<text x="164.2" y="214.7">14</text>
<text x="171.2" y="213.3">K</text>
<text x="171.2" y="215.8">CLR</text>
<text x="180.1" y="213.3">Q</text>
<text x="186.5" y="212.2">7</text>
<text x="207.4" y="212.2">12</text>
<text x="207.4" y="214.7">14</text>
<text x="214.4" y="213.3">K</text>
<text x="214.4" y="215.8">CLR</text>
<text x="223.3" y="213.3">Q</text>
<text x="229.6" y="212.2">7</text>
<text x="270.9" y="214.7">10</text>
<text x="283" y="212.2">8</text>
<text x="305.1" y="212.2">9</text>
<text x="316" y="214.7">8</text>
<text x="270.9" y="219.8">12</text>
<text x="303.9" y="217.2">10</text>
<text x="270.9" y="224.9">13</text>
<text x="283" y="222.3">11</text>
<text x="161.6" y="245.2">10</text>
<text x="161.6" y="247.7">11</text>
<text x="168.7" y="248.8">J</text>
<text x="168.7" y="246.3">PRE</text>
<text x="177.6" y="248.8">Q</text>
<text x="183.9" y="247.7">9</text>
<text x="161.6" y="252.8">13</text>
<text x="161.6" y="257.9">12</text>
<text x="168.7" y="253.9">CLK</text>
<text x="183.9" y="257.9">7</text>
<text x="161.6" y="260.4">14</text>
<text x="168.7" y="259">K</text>
<text x="168.7" y="261.5">CLR</text>
<text x="177.6" y="259">Q</text>
</g>
</g></defs>
<g fill="#000" stroke="#000" stroke-width=".21">
<path d="M67.8 18.2v3.9zM115.3 18.2v3.9zM162.7 18.2v3.9zM210.2 18.2v3.9zM257.6 18.2v3.9zM305.1 18.2v3.9zM352.5 18.2v3.9zM20.3 22.1v252.6zM20.3 22.1h379.7zM29.3 48.9h10.1zM31.1 54h8.3zM37.1 43.8h2.3z"/>
<path d="M37.6 59.1h1.8zM44.4 50h15.3zM59.7 50h317.4zM44.4 44.9h30.5zM122.2 59.1h1.7zM44.4 55.1h91.5zM135.9 55.1h241.2zM74.9 44.9h302.2zM378.7 54h8.3zM378.7 43.8h2.3zM378.7 48.9h10.1zM16.5 72.6h3.8z"/>
<path d="M44.4 60.2h25.4zM54.6 70.3l2.5 2.5zM69.8 60.2v10.1zM69.8 60.2h50.8zM74.9 44.9v22.9zM85.1 65.8h2.3zM85.1 68.3h1.8zM95.2 67.8h5.1zM95.2 70.3h5.1zM95.2 72.8h5.1zM74.9 67.8h20.3zM69.8 70.3h25.4z"/>
<path d="M57.1 72.8h38.1zM120.1 77.9h3.1zM120.1 75.4h3.1zM120.1 72.8h3.1zM120.1 70.3h3.1zM120.1 67.8h3.1zM125.7 70.9h6.5zM125.7 68.3h6zM139 60.7h9.6zM146 72.8v28zM123.2 72.8h22.8zM123.2 70.3h25.4z"/>
<path d="M151.1 65.2l2.5 2.6zM151.1 67.8l2.5 2.5zM151.1 70.3l2.5 2.5zM151.1 72.8l2.5 2.6zM151.1 75.4l2.5 2.5zM151.1 77.9l2.5 2.6zM153.6 67.8h10.2zM153.6 70.3h10.2zM153.6 72.8h10.2zM153.6 75.4h10.2zM153.6 77.9h10.2zM155.8 65.8h5.5z"/>
<path d="M155.8 68.3h5.5zM155.8 70.9h5.5zM155.8 73.4h5.5zM155.8 75.9h5.5zM155.8 78.5h5.5zM163.8 67.8h5.1zM163.8 70.3h5.1zM163.8 72.8h5.1zM163.8 75.4h5.1zM163.8 77.9h5.1zM186.1 77.9h3.1zM186.1 75.4h3.1z"/>
<path d="M186.1 72.8h3.1zM186.1 70.3h3.1zM186.1 67.8h3.1zM189.2 67.8h12.7zM189.2 70.3h12.7zM189.2 72.8h12.7zM189.2 75.4h12.7zM189.2 77.9h12.7zM204.4 65.2l2.6 2.6zM204.4 65.2l-2.5 2.6zM204.4 67.8l2.6 2.5zM204.4 67.8l-2.5 2.5z"/>
<path d="M204.4 70.3l2.6 2.5zM204.4 70.3l-2.5 2.5zM204.4 72.8l2.6 2.6zM204.4 72.8l-2.5 2.6zM204.4 75.4l2.6 2.5zM204.4 75.4l-2.5 2.5zM204.4 77.9l2.6 2.6zM204.4 77.9l-2.5 2.6zM207 67.8h12.7zM207 70.3h12.7zM207 72.8h12.7zM207 75.4h12.7z"/>
<path d="M207 77.9h12.7zM219.7 67.8h5.1zM219.7 70.3h5.1zM219.7 72.8h5.1zM219.7 75.4h5.1zM219.7 77.9h5.1zM240 77.9h5.1zM240 75.4h5.1zM240 72.8h5.1zM240 70.3h5.1zM240 67.8h5.1zM245.1 70.3h12.7z"/>
<path d="M245.1 77.9h12.7zM245.1 67.8h12.7zM245.1 72.8h12.7zM245.1 75.4h12.7zM260.3 67.8l-2.5 2.5zM260.3 67.8l2.6 2.5zM260.3 75.4l-2.5 2.5zM260.3 75.4l2.6 2.5zM257.8 80.5l2.5-2.6zM260.3 77.9l2.6 2.6zM260.3 65.2l-2.5 2.6zM260.3 65.2l2.6 2.6z"/>
<path d="M260.3 70.3l-2.5 2.5zM260.3 70.3l2.6 2.5zM260.3 72.8l-2.5 2.6zM260.3 72.8l2.6 2.6zM262.9 70.3h12.7zM262.9 77.9h12.7zM262.9 67.8h12.7zM262.9 72.8h12.7zM262.9 75.4h12.7zM275.6 67.8h5zM275.6 70.3h5zM275.6 72.8h5z"/>
<path d="M275.6 75.4h5zM275.6 77.9h5zM295.9 77.9h5.1zM295.9 75.4h5.1zM295.9 72.8h5.1zM295.9 70.3h5.1zM295.9 67.8h5.1zM306 67.8h2.6zM306 70.3h2.6zM306 72.8h2.6zM306 75.4h2.6zM306 77.9h2.6z"/>
<path d="M301 67.8h5zM301 70.3h5zM301 72.8h5zM301 75.4h5zM301 77.9h5zM328.9 65.2l2.5 2.6zM328.9 67.8l2.5 2.5zM328.9 70.3l2.5 2.5zM328.9 72.8l2.5 2.6zM328.9 75.4l2.5 2.5zM328.9 77.9l2.5 2.6zM331.4 67.8h12.7z"/>
<path d="M331.4 70.3h12.7zM331.4 72.8h12.7zM331.4 75.4h12.7zM331.4 77.9h12.7zM334 65.8h5.4zM334 68.3h5.4zM334 70.9h5.4zM334 73.4h5.4zM334 75.9h5.4zM334 78.5h5.4zM344.1 67.8h5.1zM344.1 70.3h5.1z"/>
<path d="M344.1 72.8h5.1zM344.1 75.4h5.1zM344.1 77.9h5.1zM364.4 77.9h5.1zM364.4 75.4h5.1zM364.4 72.8h5.1zM364.4 70.3h5.1zM364.4 67.8h5.1zM372.1 67.8h2.5zM372.1 70.3h2.5zM372.1 72.8h2.5zM372.1 75.4h2.5z"/>
<path d="M372.1 77.9h2.5zM369.5 67.8h2.6zM369.5 70.3h2.6zM369.5 72.8h2.6zM369.5 75.4h2.6zM369.5 77.9h2.6zM400 72.6h3.8zM54.6 80.5l2.5 2.5zM54.6 88.1l2.5 2.5zM54.6 93.2l2.5 2.5zM59.7 50v35.5zM64.8 90.6h5z"/>
<path d="M64.8 95.7h5zM57.1 90.6h7.7zM57.1 95.7h7.7zM74.9 93.2h5.1zM80 93.2h2.5zM82.5 80.5v12.7zM82.5 80.5h12.7zM85.1 83.6h10.2zM95.2 83h3.1zM95.2 85.5h3.1zM95.2 80.5h5.1zM59.7 85.5h35.5z"/>
<path d="M57.1 83h38.1zM120.1 85.5h3.1zM120.1 83h3.1zM120.1 80.5h3.1zM148.6 90.6h12.7zM148.6 70.3v20.3zM151.1 80.5l2.5 2.5zM151.1 83l2.5 2.5zM153.6 80.5h10.2zM153.6 83h10.2zM153.6 85.5h10.2zM155.3 88.6h6z"/>
<path d="M155.8 81h5.5zM155.8 83.6h5.5zM161.3 90.6v2.6zM161.3 93.2h2.5zM163.8 90.6h3.1zM163.8 80.5h5.1zM163.8 83h5.1zM163.8 85.5h5.1zM163.8 93.2h3.1zM161.3 90.6h2.5zM186.1 85.5h3.1zM186.1 83h3.1z"/>
<path d="M186.1 80.5h3.1zM189.2 80.5h12.7zM189.2 83h12.7zM189.2 85.5h12.7zM204.4 90.6h15.3zM204.4 80.5l2.6 2.5zM204.4 80.5l-2.5 2.5zM204.4 83l2.6 2.5zM204.4 83l-2.5 2.5zM207 80.5h12.7zM207 83h12.7zM207 85.5h12.7z"/>
<path d="M209.5 93.2h10.2zM210.6 88.6h6.5zM219.7 93.2h3.1zM219.7 80.5h5.1zM219.7 83h5.1zM219.7 85.5h5.1zM219.7 90.6h5.1zM224.8 89.6l2 1zM224.8 91.6l2-1zM240 85.5h5.1zM240 83h5.1zM240 80.5h5.1z"/>
<path d="M245.1 80.5h12.7zM245.1 83h12.7zM245.1 85.5h12.7zM260.3 80.5l-2.5 2.5zM260.3 80.5l2.6 2.5zM260.3 83l-2.5 2.5zM260.3 83l2.6 2.5zM262.9 80.5h12.7zM262.9 83h12.7zM262.9 85.5h12.7zM273 95.7v2.5zM273 90.6v2.6z"/>
<path d="M273 93.2v2.5zM275.6 90.6h3.1zM275.6 80.5h5zM275.6 83h5zM275.6 85.5h5zM275.6 93.2h3.1zM273 90.6h2.6zM273 93.2h2.6zM295.9 85.5h5.1zM295.9 83h5.1zM295.9 80.5h5.1zM306 80.5h2.6z"/>
<path d="M306 83h2.6zM306 85.5h2.6zM301 80.5h5zM301 83h5zM301 85.5h5zM328.9 80.5l2.5 2.5zM328.9 83l2.5 2.5zM331.4 80.5h12.7zM331.4 83h12.7zM331.4 85.5h12.7zM334 81h5.4zM334 83.6h5.4z"/>
<path d="M341.6 95.7v2.5zM341.6 90.6v2.6zM341.6 93.2v2.5zM344.1 90.6h3.1zM344.1 80.5h5.1zM344.1 83h5.1zM344.1 85.5h5.1zM344.1 93.2h3.1zM341.6 90.6h2.5zM341.6 93.2h2.5zM364.4 85.5h5.1zM364.4 83h5.1z"/>
<path d="M364.4 80.5h5.1zM372.1 80.5h2.5zM372.1 83h2.5zM372.1 85.5h2.5zM369.5 80.5h2.6zM369.5 83h2.6zM369.5 85.5h2.6zM146 100.8h58.4zM146 100.8v6.3zM151.1 105.2h6.5zM161.3 109.7v5zM161.3 114.7v5.1z"/>
<path d="M161.3 119.8v5.1zM163.8 114.7h5.1zM163.8 119.8h5.1zM163.8 109.7h5.1zM163.8 107.1h3.1zM146 107.1h17.8zM161.3 109.7h2.5zM161.3 114.7h2.5zM161.3 119.8h2.5zM168.9 113.7l2 1zM168.9 115.7l2-1zM180.1 118.9h1.7z"/>
<path d="M184.1 109.7h5.1zM184.1 119.8h5.1zM189.2 119.8h20.3zM204.4 90.6v10.2zM209.5 93.2v26.6zM260.3 108.4l2.6 2.5zM260.3 103.3l2.6 2.6zM260.3 113.5l2.6 2.5zM260.3 118.6l2.6 2.5zM262.9 110.9h22.8zM262.9 105.9h22.8zM262.9 116h22.8z"/>
<path d="M285.7 105.9h2.6zM285.7 110.9h2.6zM285.7 116h2.6zM288.3 105.9h2.5zM288.3 110.9h2.5zM288.3 116h2.5zM289 107.9l1.4 1.4zM289 113l1.4 1.4zM289 118l1.4 1.4zM289.5 108.9l.5-.5zM289.5 108.9h.8zM289.5 114l.5-.5z"/>
<path d="M289.5 119.1l.5-.5zM289.6 114h.6zM289.6 119h.6zM289.7 108.8h.5zM289.7 113.8h.5zM289.7 118.9h.5zM289.7 119.1h.6zM289.7 114.1h.6zM289.8 109h.5zM289.8 108.6h.3zM289.8 113.7h.3zM289.8 118.8h.3z"/>
<path d="M289.9 108.5h.2zM289.9 113.6h.2zM289.9 118.7h.2zM290 119.3h.3zM290 114.2h.3zM290 108.4l.4 .9zM290 113.5l.4 .9zM290 118.6l.4 .8zM290.1 109.1h.3zM290.2 107.8l1.4 1.4zM290.2 112.8l1.4 1.4zM290.2 117.9l1.4 1.4z"/>
<path d="M289.5 108.9l.9 .4zM289.5 114l.9 .4zM289.5 119.1l.9 .3zM290.7 108.8l.5-.5zM290.7 108.8h.7zM290.7 113.9l.5-.6zM290.7 118.9l.5-.5zM290.7 113.8h.7zM290.7 118.9h.7zM290.8 108.6h.5zM290.8 113.7h.5zM290.8 118.8h.5z"/>
<path d="M290.9 119h.5zM290.9 108.5h.4zM290.9 114h.5zM290.9 108.9h.5zM290.9 113.6h.4zM291 118.7h.3zM291 108.4h.2zM291.1 113.5h.1zM291.1 118.5h.1zM291.1 119.1h.4zM291.2 108.3l.4 .9zM291.2 113.3l.4 .9z"/>
<path d="M291.2 114.1h.3zM291.2 118.4l.4 .9zM291.2 109h.3zM290.7 108.8l.9 .4zM290.7 113.9l.9 .3zM290.7 118.9l.9 .4zM290.8 105.9h2.5zM290.8 110.9h2.5zM290.8 116h2.5zM293.3 110.9h5.1zM295.9 116v2.6zM293.3 116h2.6z"/>
<path d="M298.4 110.9v5.1zM298.4 116h7.6zM301 105.9v7.6zM293.3 105.9h7.7zM306 118.6h2.6zM306 116h2.6zM306 113.5h2.6zM295.9 118.6h10.1zM301 113.5h5zM308.6 113.5h1.3zM308.6 116h1.3zM308.6 118.6h1.3z"/>
<path d="M314.9 118.6h1.3zM316.2 116v2.6zM314.9 116h1.3zM316.2 113.5v2.5zM314.9 113.5h1.3zM324.4 91.2v9.6zM328.9 103.3l2.5 2.6zM328.9 108.4l2.5 2.5zM328.9 113.5l2.5 2.5zM334 103.9h5.4zM334 109h5.4zM334 114h5.4z"/>
<path d="M334 119.1h5.4zM354.3 105.9h2.5zM354.3 110.9h2.5zM354.3 116h2.5zM331.4 105.9h22.9zM331.4 110.9h22.9zM331.4 116h22.9zM356.8 105.9h2.6zM356.8 110.9h2.6zM356.8 116h2.6zM357.6 107.9l1.4 1.4zM357.6 113l1.4 1.4z"/>
<path d="M357.6 118l1.4 1.4zM358.1 108.9l.5-.5zM358.6 113.5l-.5 .5zM358.6 118.6l-.5 .5zM358.1 108.9h.7zM358.1 114h.7zM358.1 119h.7zM358.2 108.8h.6zM358.2 113.8h.6zM358.3 118.9h.4zM358.3 119.1h.6zM358.3 114.1h.6z"/>
<path d="M358.3 109h.6zM358.3 108.6h.4zM358.4 113.7h.3zM358.4 118.8h.3zM358.5 108.5h.2zM358.5 113.6h.2zM358.5 118.7h.1zM358.6 119.3h.3zM358.6 108.4l.4 .9zM358.6 113.5l.4 .9zM358.6 114.2h.3zM358.6 118.6l.4 .8z"/>
<path d="M358.6 109.1h.3zM358.7 107.8l1.4 1.4zM358.7 112.8l1.4 1.4zM358.7 117.9l1.4 1.4zM358.1 108.9l.9 .4zM358.1 114l.9 .4zM358.1 119.1l.9 .3zM359.2 108.8l.5-.5zM359.2 113.9l.5-.6zM359.2 118.9l.5-.5zM359.3 108.8h.7zM359.3 113.8h.7z"/>
<path d="M359.3 118.9h.7zM359.4 108.6h.5zM359.4 113.7h.5zM359.4 118.8h.5zM359.4 119h.6zM359.5 114h.5zM359.5 108.5h.4zM359.5 108.9h.5zM359.5 113.6h.3zM359.5 118.7h.3zM359.6 108.4h.2zM359.6 113.5h.2z"/>
<path d="M359.6 118.5h.2zM359.7 119.1h.4zM359.7 108.3l.4 .9zM359.7 113.3l.4 .9zM359.7 118.4l.4 .9zM359.8 114.1h.3zM359.8 109h.3zM359.2 108.8l.9 .4zM359.2 113.9l.9 .3zM359.2 118.9l.9 .4zM359.4 105.9h2.5zM359.4 110.9h2.5z"/>
<path d="M359.4 116h2.5zM361.9 110.9h5.1zM364.4 116v2.6zM361.9 116h2.5zM367 110.9v5.1zM367 116h7.6zM369.5 105.9v7.6zM361.9 105.9h7.6zM374.6 118.6h2.5zM374.6 116h2.5zM374.6 113.5h2.5zM364.4 118.6h10.2z"/>
<path d="M369.5 113.5h5.1zM377.1 113.5h1.3zM377.1 116h1.3zM377.1 118.6h1.3zM383.5 118.6h1.3zM384.8 116v2.6zM383.5 116h1.3zM384.8 113.5v2.5zM383.5 113.5h1.3zM16.5 123.1h3.8zM31.9 136.1h10zM64.8 133.8v30.5z"/>
<path d="M67.3 131.3l-2.5 2.5zM67.3 138.9v17.8zM69.8 136.3l-2.5 2.6zM107.9 133.8v30.5zM110.5 131.3l-2.6 2.5zM110.5 138.9v17.8zM110.5 138.9l2.5-2.6zM135.9 55.1v67.3zM151.1 120.4h8.4zM151.1 133.8v30.5zM153.6 131.3l-2.5 2.5zM153.6 138.9v17.8z"/>
<path d="M156.2 136.3l-2.6 2.6zM161.3 124.9v2.5zM163.8 122.4h3.1zM135.9 122.4h27.9zM196.8 133.8v30.5zM199.4 131.3l-2.6 2.5zM199.4 138.9v17.8zM199.4 138.9l2.5-2.6zM260.3 123.6l2.6 2.6zM260.3 128.7l2.6 2.6zM260.3 133.8l2.6 2.5zM260.3 138.9l2.6 2.5z"/>
<path d="M262.9 126.2h22.8zM262.9 131.3h22.8zM262.9 136.3h22.8zM262.9 121.1h22.8zM285.7 121.1h2.6zM285.7 126.2h2.6zM285.7 131.3h2.6zM285.7 136.3h2.6zM288.3 121.1h2.5zM288.3 126.2h2.5zM288.3 131.3h2.5zM288.3 136.3h2.5z"/>
<path d="M289 123.1l1.4 1.4zM289 128.2l1.4 1.4zM289 133.3l1.4 1.4zM289 138.4l1.4 1.4zM289.5 124.1l.5-.5zM289.5 129.2l.5-.5zM289.5 134.3l.5-.5zM289.5 139.4l.5-.5zM289.6 124.1h.6zM289.6 139.4h.7zM289.6 129.2h.6zM289.6 134.3h.7z"/>
<path d="M289.6 134.2h.6zM289.6 139.3h.6zM289.6 129.3h.7zM289.7 124.2h.6zM289.7 124h.5zM289.7 129h.5zM289.7 134.1h.5zM289.7 139.1h.4zM289.8 123.8h.3zM289.8 128.9h.3zM289.9 134h.2zM289.9 139.5h.4z"/>
<path d="M289.9 139h.2zM289.9 134.4h.4zM289.9 129.4h.4zM289.9 123.7h.2zM290 124.3h.3zM290 123.6l.4 .9zM290 128.7l.4 .9zM290 133.8l.4 .9zM290 138.9l.4 .9zM290.1 139.6h.3zM290.2 123l1.4 1.4zM290.2 128.1l1.4 1.4z"/>
<path d="M290.2 133.2l1.4 1.4zM290.2 134.6h.2zM290.2 138.2l1.4 1.4zM290.2 129.5h.2zM290.2 124.4h.2zM289.5 124.1l.9 .4zM289.5 129.2l.9 .4zM289.5 134.3l.9 .4zM289.5 139.4l.9 .4zM290.7 124l.5-.5zM290.7 129.1l.5-.5zM290.7 134.2l.5-.5z"/>
<path d="M290.7 139.3l.5-.6zM290.7 124h.7zM290.7 129h.7zM290.7 134.1h.7zM290.7 139.3h.7zM290.8 134.2h.6zM290.8 139.1h.6zM290.8 129.2h.6zM290.8 124.1h.6zM290.8 123.8h.5zM290.8 128.9h.5zM290.9 134h.4z"/>
<path d="M290.9 139h.4zM291 123.7h.3zM291 128.8h.3zM291 133.9h.2zM291 139.4h.5zM291 138.9h.2zM291 134.3h.5zM291.1 123.6h.1zM291.1 129.3h.4zM291.1 124.2h.4zM291.2 123.5l.4 .9zM291.2 128.6l.4 .9z"/>
<path d="M291.2 133.7l.4 .9zM291.2 138.7l.4 .9zM291.3 139.5h.2zM291.3 134.4h.2zM291.4 129.4h.1zM291.4 124.3h.1zM290.7 124l.9 .4zM290.7 129.1l.9 .4zM290.7 134.2l.9 .4zM290.7 139.3l.9 .3zM290.8 121.1h2.5zM290.8 126.2h2.5z"/>
<path d="M290.8 131.3h2.5zM290.8 136.3h2.5zM293.3 121.1h12.7zM293.3 126.2h2.6zM293.3 131.3h5.1zM293.3 136.3h7.7zM295.9 123.6v2.6zM295.9 123.6h10.1zM298.4 126.2v5.1zM298.4 126.2h7.6zM301 128.7v7.6zM301 128.7h5z"/>
<path d="M303.5 131.3h2.5zM306 131.3h2.6zM306 128.7h2.6zM306 126.2h2.6zM306 123.6h2.6zM306 121.1h2.6zM308.6 121.1h1.3zM308.6 123.6h1.3zM308.6 126.2h1.3zM308.6 128.7h1.3zM308.6 131.3h1.3zM314.9 131.3h1.3z"/>
<path d="M316.2 128.7v2.6zM314.9 128.7h1.3zM316.2 126.2v2.5zM314.9 126.2h1.3zM316.2 123.6v2.6zM314.9 123.6h1.3zM316.2 121.1v2.5zM314.9 121.1h1.3zM316.2 118.6v2.5zM316.2 131.3h2.5zM318.7 131.3h2.6zM321.3 131.3h2.5z"/>
<path d="M323.8 133.8v2.5zM323.8 131.3v2.5zM328.9 118.6l2.5 2.5zM328.9 123.6l2.5 2.6zM328.9 128.7l2.5 2.6zM328.9 133.8l2.5 2.5zM334 124.2h5.4zM334 129.3h5.4zM334 134.4h5.4zM334 139.4h5.4zM354.3 121.1h2.5zM354.3 126.2h2.5z"/>
<path d="M354.3 131.3h2.5zM354.3 136.3h2.5zM331.4 121.1h22.9zM331.4 126.2h22.9zM331.4 131.3h22.9zM331.4 136.3h22.9zM356.8 121.1h2.6zM356.8 126.2h2.6zM356.8 131.3h2.6zM356.8 136.3h2.6zM357.6 123.1l1.4 1.4zM357.6 128.2l1.4 1.4z"/>
<path d="M357.6 133.3l1.4 1.4zM357.6 138.4l1.4 1.4zM358.1 124.1l.5-.5zM358.6 128.7l-.5 .5zM358.6 133.8l-.5 .5zM358.1 139.4l.5-.5zM358.2 124.1h.6zM358.2 139.4h.6zM358.2 129.2h.6zM358.2 134.3h.6zM358.2 134.2h.6zM358.2 139.3h.6z"/>
<path d="M358.2 129.3h.7zM358.2 124.2h.7zM358.3 124h.4zM358.3 129h.4zM358.3 134.1h.4zM358.3 139.1h.4zM358.4 123.8h.3zM358.4 128.9h.3zM358.4 134h.3zM358.4 139.5h.5zM358.5 134.4h.4zM358.5 139h.2z"/>
<path d="M358.5 129.4h.4zM358.5 123.7h.1zM358.5 124.3h.4zM358.6 123.6l.4 .9zM358.6 128.7l.4 .9zM358.6 133.8l.4 .9zM358.6 138.9l.4 .9zM358.7 139.6h.2zM358.7 123l1.4 1.4zM358.7 128.1l1.4 1.4zM358.7 133.2l1.4 1.4zM358.7 138.2l1.4 1.4z"/>
<path d="M358.7 134.6h.2zM358.8 129.5h.2zM358.8 124.4h.2zM358.1 124.1l.9 .4zM358.1 129.2l.9 .4zM358.1 134.3l.9 .4zM358.1 139.4l.9 .4zM359.2 124l.5-.5zM359.2 129.1l.5-.5zM359.2 134.2l.5-.5zM359.2 139.3l.5-.6zM359.3 124h.7z"/>
<path d="M359.3 129h.6zM359.3 139.3h.7zM359.3 134.1h.6zM359.3 134.2h.7zM359.3 139.1h.6zM359.4 129.2h.6zM359.4 124.1h.6zM359.4 123.8h.5zM359.4 128.9h.5zM359.4 134h.5zM359.5 139h.4zM359.5 123.7h.3z"/>
<path d="M359.6 128.8h.2zM359.6 133.9h.2zM359.6 138.9h.2zM359.6 139.4h.4zM359.6 134.3h.4zM359.7 123.6h.1zM359.7 129.3h.3zM359.7 124.2h.3zM359.7 123.5l.4 .9zM359.7 128.6l.4 .9zM359.7 133.7l.4 .9zM359.7 138.7l.4 .9z"/>
<path d="M359.9 139.5h.2zM359.9 134.4h.2zM359.9 129.4h.2zM360 124.3h.1zM359.2 124l.9 .4zM359.2 129.1l.9 .4zM359.2 134.2l.9 .4zM359.2 139.3l.9 .3zM359.4 121.1h2.5zM359.4 126.2h2.5zM359.4 131.3h2.5zM359.4 136.3h2.5z"/>
<path d="M361.9 121.1h12.7zM361.9 126.2h2.5zM361.9 131.3h5.1zM361.9 136.3h7.6zM364.4 123.6v2.6zM364.4 123.6h10.2zM367 126.2v5.1zM367 126.2h7.6zM369.5 128.7v7.6zM369.5 128.7h5.1zM372.1 131.3h2.5zM374.6 131.3h2.5z"/>
<path d="M374.6 128.7h2.5zM374.6 126.2h2.5zM374.6 123.6h2.5zM374.6 121.1h2.5zM377.1 121.1h1.3zM377.1 123.6h1.3zM377.1 126.2h1.3zM377.1 128.7h1.3zM377.1 131.3h1.3zM383.5 131.3h1.3zM384.8 128.7v2.6zM383.5 128.7h1.3z"/>
<path d="M384.8 126.2v2.5zM383.5 126.2h1.3zM384.8 123.6v2.6zM383.5 123.6h1.3zM384.8 121.1v2.5zM383.5 121.1h1.3zM384.8 118.6v2.5zM384.8 131.3h2.5zM387.3 131.3h2.5zM389.8 131.3h2.6zM392.4 133.8v2.5zM392.4 131.3v2.5z"/>
<path d="M400 123.1h3.8zM67.3 156.7h7.6zM67.9 140.6v5.9zM72.4 144v2.5zM72.4 146.5v2.5zM72.4 149v2.6zM74.9 156.7h5.1zM74.9 151.6h5.1zM74.9 149h3.1zM72.4 149h2.5zM72.4 151.6h2.5zM80 155.7l2 1z"/>
<path d="M80 157.6l2-.9zM95.2 151.6h5.1zM110.5 156.7h7.6zM111.1 140.6v5.9zM115.6 144v2.5zM115.6 146.5v2.5zM115.6 149v2.6zM118.1 156.7h5.1zM118.1 151.6h5.1zM118.1 149h3.1zM115.6 149h2.5zM115.6 151.6h2.5z"/>
<path d="M123.2 155.7l2 1zM123.2 157.6l2-.9zM138.4 151.6h5.1zM153.6 156.7h10.2zM154.2 140.6v5.9zM161.3 144v2.5zM161.3 146.5v2.5zM161.3 149v2.6zM163.8 156.7h5.1zM163.8 151.6h5.1zM163.8 149h3.1zM161.3 149h2.5z"/>
<path d="M161.3 151.6h2.5zM168.9 155.7l2 1zM168.9 157.6l2-.9zM184.1 151.6h5.1zM199.4 156.7h7.6zM199.9 140.6v5.9zM204.4 144v2.5zM204.4 146.5v2.5zM204.4 149v2.6zM207 156.7h5.1zM207 151.6h5.1zM207 149h3.1z"/>
<path d="M204.4 149h2.6zM204.4 151.6h2.6zM212.1 155.7l2 1zM212.1 157.6l2-.9zM227.3 151.6h5.1zM260.3 149l2.6 2.6zM260.3 156.7l2.6 2.5zM260.3 159.2l2.6 2.5zM260.3 146.5l2.6 2.5zM260.3 151.6l2.6 2.5zM260.3 154.1l2.6 2.6zM262.9 151.6h12.7z"/>
<path d="M262.9 159.2h12.7zM262.9 141.4h22.8zM262.9 149h12.7zM262.9 154.1h12.7zM262.9 156.7h12.7zM275.6 159.2h2.5zM275.6 156.7h2.5zM275.6 154.1h2.5zM275.6 151.6h2.5zM275.6 149h2.5zM278.1 156.7h1.3zM278.1 159.2h1.3z"/>
<path d="M278.1 149h1.3zM278.1 151.6h1.3zM278.1 154.1h1.3zM285.7 141.4h2.6zM284.5 159.2h1.2zM285.7 156.7v2.5zM284.5 156.7h1.2zM284.5 154.1h1.2zM285.7 151.6v2.5zM284.5 151.6h1.2zM285.7 149v2.6zM284.5 149h1.2z"/>
<path d="M285.7 154.1v2.6zM288.3 141.4h2.5zM289 143.4l1.4 1.4zM289.5 144.5l.5-.5zM289.5 144.5h.8zM289.6 144.3h.6zM289.8 144.2h.3zM289.8 144.6h.5zM289.9 144.1h.2zM290 144l.4 .8zM290.1 144.7h.3zM290.2 143.3l1.4 1.4z"/>
<path d="M289.5 144.5l.9 .3zM290.7 144.3l.5-.5zM290.7 144.3h.7zM290.8 144.2h.6zM290.9 144.1h.4zM291 144.5h.5zM291 144h.2zM291.2 143.8l.4 .9zM291.2 144.6h.3zM290.7 144.3l.9 .4zM290.8 141.4h2.5zM293.3 141.4h10.2z"/>
<path d="M303.5 131.3v10.1zM328.9 138.9l2.5 2.5zM354.3 141.4h2.5zM331.4 141.4h22.9zM356.8 141.4h2.6zM357.6 143.4l1.4 1.4zM358.6 144l-.5 .5zM358.1 144.5h.7zM358.2 144.3h.6zM358.3 144.2h.4zM358.4 144.6h.5zM358.5 144.1h.2z"/>
<path d="M358.6 144l.4 .8zM358.7 144.7h.2zM358.7 143.3l1.4 1.4zM358.1 144.5l.9 .3zM359.2 144.3l.5-.5zM359.3 144.3h.7zM359.4 144.2h.5zM359.5 144.1h.4zM359.6 144.5h.4zM359.6 144h.2zM359.7 143.8l.4 .9zM359.8 144.6h.3z"/>
<path d="M359.2 144.3l.9 .4zM359.4 141.4h2.5zM361.9 141.4h10.2zM372.1 131.3v10.1zM16.5 173.7h3.8zM64.8 164.3h10.1zM72.4 166.8v2.6zM72.4 161.7v5.1zM72.4 161.7h2.5zM74.9 161.7h5.1zM74.9 164.3h3.1zM91.2 160.8h1.7z"/>
<path d="M100.1 164.3v5.4zM95.2 161.7h5.1zM102.9 161.7v12.7zM100.3 161.7h2.6zM102.9 174.4l2.5 2.6zM107.9 164.3h10.2zM115.6 166.8v2.6zM115.6 161.7v5.1zM118.1 161.7h5.1zM118.1 164.3h3.1zM115.6 161.7h2.5zM125.7 173.7h9.5z"/>
<path d="M134.4 160.8h1.7zM143.3 164.3v5.4zM138.4 161.7h5.1zM146 161.7v12.7zM143.5 161.7h2.5zM146 174.4l2.6 2.6zM151.1 164.3h12.7zM161.3 166.8v2.6zM161.3 161.7v5.1zM163.8 161.7h5.1zM163.8 164.3h3.1zM161.3 161.7h2.5z"/>
<path d="M180.1 160.8h1.7zM189 164.3v5.4zM184.1 161.7h5.1zM191.7 161.7v12.7zM189.2 161.7h2.5zM191.7 174.4l2.6 2.6zM196.8 164.3h10.2zM204.4 166.8v2.6zM204.4 161.7v5.1zM204.4 161.7h2.6zM207 161.7h5.1zM207 164.3h3.1z"/>
<path d="M214.6 173.7h9.5zM223.3 160.8h1.7zM232.2 164.3v5.4zM227.3 161.7h5.1zM234.9 161.7v12.7zM232.4 161.7h2.5zM234.9 174.4l2.6 2.6zM260.3 161.7l2.6 2.6zM260.3 164.3l2.6 2.5zM262.9 161.7h12.7zM262.9 164.3h12.7zM262.9 166.8h12.7z"/>
<path d="M275.6 166.8h2.5zM275.6 164.3h2.5zM275.6 161.7h2.5zM278.1 161.7h1.3zM278.1 164.3h1.3zM278.1 166.8h1.3zM284.5 166.8h1.2zM285.7 164.3v2.5zM284.5 164.3h1.2zM285.7 161.7v2.6zM284.5 161.7h1.2zM285.7 159.2v2.5z"/>
<path d="M285.7 166.8h2.6zM288.3 166.8h2.5zM290.8 166.8h2.5zM293.3 169.4v2.5zM293.3 166.8v2.6zM400 173.7h3.8zM64.8 184.6v30.4zM67.3 182.1l-2.5 2.5zM67.3 189.7v17.7zM67.9 191.4v5.9zM69.8 187.1l-2.5 2.6zM72.4 194.8v2.5z"/>
<path d="M72.4 197.3v2.5zM74.9 199.8h3.1zM72.4 199.8h2.5zM82.5 183.9h10zM107.9 184.6v30.4zM110.5 182.1l-2.6 2.5zM110.5 189.7v17.7zM111.1 191.4v5.9zM113 187.1l-2.5 2.6zM115.6 194.8v2.5zM115.6 197.3v2.5zM118.1 199.8h3.1z"/>
<path d="M115.6 199.8h2.5zM125.7 183.9h10zM151.1 184.6v30.4zM151.1 184.6l2.5-2.5zM153.6 189.7v17.7zM154.2 191.4v5.9zM156.2 187.1l-2.6 2.6zM161.3 194.8v2.5zM161.3 197.3v2.5zM163.8 199.8h3.1zM161.3 199.8h2.5zM196.8 184.6v30.4z"/>
<path d="M199.4 182.1l-2.6 2.5zM199.4 189.7v17.7zM199.9 191.4v5.9zM201.9 187.1l-2.5 2.6zM204.4 194.8v2.5zM204.4 197.3v2.5zM207 199.8h3.1zM204.4 199.8h2.6zM245.1 187.1l2.5 2.6zM245.1 192.2l2.5 2.6zM245.1 197.3l2.5 2.5zM247.6 189.7h22.9z"/>
<path d="M247.6 194.8h22.9zM247.6 199.8h22.9zM262.9 187.7h5.4zM262.9 192.8h5.4zM262.9 197.9h5.4zM270.5 189.7h5.1zM270.5 194.8h5.1zM270.5 199.8h5.1zM280.6 192.2h5.1zM295.9 192.2v5.1zM285.7 192.2h10.2zM303.5 197.3h5.1z"/>
<path d="M295.9 197.3h7.6zM313.7 199.8h5zM318.7 199.8h7.7zM326.4 199.8v5.1zM334 189.4h6.3zM64.8 215h10.1zM67.3 207.4h7.6zM72.4 217.6v2.5zM72.4 212.5v5.1zM72.4 212.5h2.5zM72.4 199.8v2.6zM74.9 207.4h5.1z"/>
<path d="M74.9 212.5h5.1zM74.9 202.4h5.1zM74.9 215h3.1zM72.4 202.4h2.5zM80 206.5l2 .9zM80 208.4l2-1zM91.2 211.6h1.7zM95.2 202.4h5.1zM95.2 212.5h5.1zM100.3 212.5h2.6zM107.9 215h10.2zM110.5 207.4h7.6z"/>
<path d="M115.6 217.6v2.5zM115.6 212.5v5.1zM115.6 199.8v2.6zM118.1 207.4h5.1zM118.1 212.5h5.1zM118.1 202.4h5.1zM118.1 215h3.1zM115.6 212.5h2.5zM115.6 202.4h2.5zM123.2 206.5l2 .9zM123.2 208.4l2-1zM134.4 211.6h1.7z"/>
<path d="M138.4 202.4h5.1zM138.4 212.5h5.1zM143.5 212.5h2.5zM151.1 215h12.7zM153.6 207.4h10.2zM161.3 217.6v2.5zM161.3 212.5v5.1zM161.3 199.8v2.6zM163.8 207.4h5.1zM163.8 212.5h5.1zM163.8 202.4h5.1zM163.8 215h3.1z"/>
<path d="M161.3 212.5h2.5zM161.3 202.4h2.5zM168.9 206.5l2 .9zM168.9 208.4l2-1zM180.1 211.6h1.7zM184.1 202.4h5.1zM184.1 212.5h5.1zM189.2 212.5h2.5zM196.8 215h10.2zM199.4 207.4h7.6zM204.4 217.6v2.5zM204.4 212.5v5.1z"/>
<path d="M204.4 212.5h2.6zM204.4 199.8v2.6zM207 207.4h5.1zM207 212.5h5.1zM207 202.4h5.1zM207 215h3.1zM204.4 202.4h2.6zM212.1 206.5l2 .9zM212.1 208.4l2-1zM223.3 211.6h1.7zM227.3 202.4h5.1zM227.3 212.5h5.1z"/>
<path d="M232.4 212.5h2.5zM245.1 202.4l2.5 2.5zM245.1 207.4l2.5 2.6zM245.1 212.5l2.5 2.5zM245.1 217.6l2.5 2.5zM247.6 204.9h22.9zM247.6 210h22.9zM247.6 215h22.9zM262.9 202.9h5.4zM262.9 208h5.4zM262.9 213.1h5.4zM262.9 218.2h5.4z"/>
<path d="M270.5 204.9h5.1zM270.5 210h5.1zM270.5 215h5.1zM280.6 202.4h5.1zM280.6 212.5h5.1zM285.7 202.4h17.8zM285.7 212.5h17.8zM295.9 217.6h7.6zM303.5 202.4h5.1zM303.5 212.5h5.1zM303.5 217.6h5.1zM313.7 215h5z"/>
<path d="M318.7 215h7.7zM326.4 204.9h7.6zM326.4 210v5zM326.4 210h7.6zM334 204.9h5zM334 210h5zM344.1 207.4h5.1zM349.2 207.4h27.9zM378.7 206.4h4.4zM16.5 224.2h3.8zM100.1 217.3v5.4zM102.9 212.5v12.7z"/>
<path d="M102.9 225.2l2.5 2.5zM143.3 217.3v5.4zM146 212.5v12.7zM146 225.2l2.6 2.5zM170.2 224.5h9.5zM189 217.3v5.4zM191.7 212.5v12.7zM191.7 225.2l2.6 2.5zM232.2 217.3v5.4zM234.9 212.5v12.7zM234.9 225.2l2.6 2.5zM245.1 222.7l2.5 2.5z"/>
<path d="M247.6 220.1h22.9zM247.6 225.2h22.9zM262.9 223.2h5.4zM270.5 220.1h5.1zM270.5 225.2h5.1zM280.6 222.7h5.1zM285.7 222.7h10.2zM295.9 217.6v5.1zM347.6 223.2h4.4zM369 220.7h4.4zM400 224.2h3.8zM29.2 255.7v2.5z"/>
<path d="M29.2 250.6v2.5zM29.2 255.2v.5zM29.2 253.1v.6zM29.2 258.2v2.6zM29.2 248.1v2.5zM36.8 255.7v2.5zM36.8 250.6v2.5zM36.8 255.2v.5zM36.8 253.1v.6zM36.8 248.1v2.5zM29.2 248.1h7.6zM44.4 255.7v2.5z"/>
<path d="M44.4 250.6v2.5zM44.4 255.2v.5zM44.4 253.1v.6zM36.8 248.1h7.6zM44.4 248.1v2.5zM52.1 255.7v2.5zM52.1 250.6v2.5zM52.1 255.2v.5zM52.1 253.1v.6zM44.4 248.1h7.7zM52.1 248.1v2.5zM59.7 255.7v2.5z"/>
<path d="M59.7 250.6v2.5zM59.7 255.2v.5zM59.7 253.1v.6zM52.1 248.1h7.6zM59.7 248.1v2.5zM67.3 255.7v2.5zM67.3 250.6v2.5zM67.3 255.2v.5zM67.3 253.1v.6zM59.7 248.1h7.6zM67.3 248.1v2.5zM74.9 255.7v2.5z"/>
<path d="M74.9 250.6v2.5zM74.9 255.2v.5zM74.9 253.1v.6zM67.3 248.1h7.6zM74.9 248.1v2.5zM82.5 255.7v2.5zM82.5 250.6v2.5zM82.5 255.2v.5zM82.5 253.1v.6zM74.9 248.1h7.6zM82.5 248.1v2.5zM90.2 255.7v2.5z"/>
<path d="M90.2 250.6v2.5zM90.2 255.2v.5zM90.2 253.1v.6zM82.5 248.1h7.7zM90.2 248.1v2.5zM97.8 255.7v2.5zM97.8 250.6v2.5zM97.8 255.2v.5zM97.8 253.1v.6zM97.8 258.2v2.6zM90.2 248.1h7.6zM97.8 248.1v2.5z"/>
<path d="M105.4 255.7v2.5zM105.4 250.6v2.5zM105.4 255.2v.5zM105.4 253.1v.6zM105.4 258.2v2.6zM97.8 248.1h7.6zM105.4 248.1v2.5zM113 243v2.5zM113 255.7v2.5zM113 250.6v2.5zM113 255.2v.5zM113 253.1v.6z"/>
<path d="M105.4 248.1h7.6zM113 245.5v2.6zM113 248.1v2.5zM120.6 243v2.5zM120.6 250.6v2.5zM120.6 255.7v2.5zM120.6 253.1v.6zM120.6 255.2v.5zM120.6 245.5v5.1zM158.7 245.5v2.6zM158.7 248.1v5zM158.7 253.1v5.1z"/>
<path d="M158.7 258.2v2.6zM161.3 253.1h5zM161.3 258.2h5zM161.3 248.1h5zM161.3 245.5h3.1zM158.7 245.5h2.6zM158.7 258.2h2.6zM158.7 253.1h2.6zM158.7 248.1h2.6zM166.3 252.2l2 .9zM166.3 254.1l2-1zM177.6 257.3h1.7z"/>
<path d="M181.6 248.1h5.1zM181.6 258.2h5.1zM20.3 274.7h379.7zM29.2 263.3v2.5zM29.2 260.8h7.6zM29.2 260.8v2.5zM36.8 258.2v2.6zM36.8 260.8h7.6zM44.4 258.2v2.6zM44.4 260.8h7.7zM52.1 258.2v2.6zM52.1 260.8h7.6z"/>
<path d="M59.7 258.2v2.6zM59.7 260.8h7.6zM67.3 258.2v2.6zM67.8 274.7v3.8zM67.3 260.8h7.6zM74.9 258.2v2.6zM74.9 260.8h7.6zM82.5 258.2v2.6zM82.5 260.8h7.7zM90.2 258.2v2.6zM90.2 260.8h7.6zM97.8 260.8h7.6z"/>
<path d="M105.4 260.8h7.6zM113 258.2v2.6zM115.3 274.7v3.8zM120.6 263.3v2.5zM120.6 258.2v5.1zM158.7 263.3v2.5zM158.7 260.8v2.5zM161.3 260.8h3.1zM158.7 260.8h2.6zM162.7 274.7v3.8zM210.2 274.7v3.8zM257.6 274.7v3.8z"/>
<path d="M305.1 274.7v3.8zM352.5 274.7v3.8zM400 264.5v.1zM400 268.4v6.2zM400 274.6h.1zM400 22.1v252.6z"/>
<circle cx="59.7" cy="50" r=".51"/>
<circle cx="74.9" cy="44.9" r=".51"/>
<circle cx="135.9" cy="55.1" r=".51"/>
<circle cx="69.8" cy="60.2" r=".51"/>
<circle cx="161.3" cy="90.6" r=".51"/>
<circle cx="273" cy="93.2" r=".51"/>
<circle cx="341.6" cy="93.2" r=".51"/>
<circle cx="146" cy="100.8" r=".51"/>
<circle cx="161.3" cy="114.7" r=".51"/>
<circle cx="161.3" cy="119.8" r=".51"/>
<circle cx="72.4" cy="149" r=".51"/>
<circle cx="115.6" cy="149" r=".51"/>
<circle cx="161.3" cy="149" r=".51"/>
<circle cx="204.4" cy="149" r=".51"/>
<circle cx="72.4" cy="199.8" r=".51"/>
<circle cx="115.6" cy="199.8" r=".51"/>
<circle cx="161.3" cy="199.8" r=".51"/>
<circle cx="204.4" cy="199.8" r=".51"/>
<circle cx="36.8" cy="248.1" r=".51"/>
<circle cx="44.4" cy="248.1" r=".51"/>
<circle cx="52.1" cy="248.1" r=".51"/>
<circle cx="59.7" cy="248.1" r=".51"/>
<circle cx="67.3" cy="248.1" r=".51"/>
<circle cx="74.9" cy="248.1" r=".51"/>
<circle cx="82.5" cy="248.1" r=".51"/>
<circle cx="90.2" cy="248.1" r=".51"/>
<circle cx="97.8" cy="248.1" r=".51"/>
<circle cx="105.4" cy="248.1" r=".51"/>
<circle cx="113" cy="248.1" r=".51"/>
<circle cx="158.7" cy="253.1" r=".51"/>
<circle cx="158.7" cy="248.1" r=".51"/>
<circle cx="158.7" cy="258.2" r=".51"/>
<circle cx="29.2" cy="260.8" r=".51"/>
<circle cx="36.8" cy="260.8" r=".51"/>
<circle cx="44.4" cy="260.8" r=".51"/>
<circle cx="52.1" cy="260.8" r=".51"/>
<circle cx="59.7" cy="260.8" r=".51"/>
<circle cx="67.3" cy="260.8" r=".51"/>
<circle cx="74.9" cy="260.8" r=".51"/>
<circle cx="82.5" cy="260.8" r=".51"/>
<circle cx="90.2" cy="260.8" r=".51"/>
<circle cx="97.8" cy="260.8" r=".51"/>
<circle cx="105.4" cy="260.8" r=".51"/>
<circle cx="158.7" cy="260.8" r=".51"/>
</g>
<g fill="#000" stroke="#000" stroke-width=".28">
<path d="M26.9 48.5v3zM28.7 53.6v3zM34.8 43.4v3zM28.7 53.6h14.2zM28.7 56.6h14.2zM34.8 43.4h8.1zM34.8 46.4h8.1zM26.9 51.5h16zM26.9 48.5h16zM35.4 58.6h7.5zM42.9 53.6l1.5 1.5zM42.9 56.6l1.5-1.5z"/>
<path d="M42.9 43.4l1.5 1.5zM44.4 44.9l-1.5 1.5zM44.4 50l-1.5 1.5zM42.9 48.5l1.5 1.5zM122.2 58.6h7.5zM129.7 58.6v3.1zM377.1 55.1l1.6-1.5zM377.1 55.1l1.6 1.5zM377.1 44.9l1.6-1.5zM377.1 44.9l1.6 1.5zM378.7 48.5l-1.6 1.5zM377.1 50l1.6 1.5z"/>
<path d="M378.7 53.6h14.1zM378.7 56.6h14.1zM378.7 43.4h8.1zM378.7 46.4h8.1zM378.7 48.5h16zM378.7 51.5h16zM386.8 43.4v3zM392.8 53.6v3zM394.7 48.5v3zM35.4 58.6v3.1zM35.4 61.7h7.5zM42.9 61.7l1.5-1.5z"/>
<path d="M42.9 58.6l1.5 1.6zM120.6 60.2l1.6-1.6zM120.6 60.2l1.6 1.5zM122.2 61.7h7.5zM271.1 98.2h3.8zM339.7 98.2h3.8zM288.3 104.6v2.5zM288.3 104.6l2.5 1.3zM288.3 107h.1zM288.3 106.8h.6zM288.3 106.6h1zM288.3 106.4h1.5z"/>
<path d="M288.3 106.1h1.9zM288.3 105.9h2.4zM288.3 105.7h2.2zM288.3 105.5h1.7zM288.3 105.3h1.3zM288.3 105h.9zM288.3 104.8h.4zM288.3 109.7v2.5zM288.3 109.7l2.5 1.2zM288.3 111.9h.5zM288.3 111.7h1zM288.3 111.5h1.4z"/>
<path d="M288.3 111.3h1.8zM288.3 111h2.3zM288.3 110.8h2.2zM288.3 110.6h1.8zM288.3 110.4h1.4zM288.3 110.1h.9zM288.3 109.9h.5zM288.3 114.7v2.6zM288.3 114.7l2.5 1.3zM288.3 117h.5zM288.3 116.8h.9zM288.3 116.6h1.3z"/>
<path d="M288.3 116.4h1.8zM288.3 116.1h2.2zM288.3 115.9h2.3zM288.3 115.7h1.9zM288.3 115.5h1.4zM288.3 115.3h1zM288.3 115h.5zM288.3 114.8h.1zM288.3 119.8l2.5 1.3zM288.3 119.9h.2zM290.8 105.9v1.2zM288.3 107.1l2.5-1.2z"/>
<path d="M290.8 104.6v2.5zM290.8 104.6h.3zM290.8 107h.3zM290.8 106.8h.3zM290.8 106.6h.3zM290.8 106.4h.3zM290.8 106.1h.3zM290.8 105.9h.3zM290.8 105.7h.3zM290.8 105.5h.3zM290.8 105.3h.3zM290.8 105h.3z"/>
<path d="M290.8 104.8h.3zM290.8 110.9v1.3zM288.3 112.2l2.5-1.3zM290.8 109.7v2.5zM290.8 109.7h.3zM290.8 112.1h.3zM290.8 111.9h.3zM290.8 111.7h.3zM290.8 111.5h.3zM290.8 111.3h.3zM290.8 111h.3zM290.8 110.8h.3z"/>
<path d="M290.8 110.6h.3zM290.8 110.4h.3zM290.8 110.1h.3zM290.8 109.9h.3zM290.8 116v1.3zM288.3 117.3l2.5-1.3zM290.8 114.7v2.6zM290.8 114.7h.3zM290.8 117.3h.3zM290.8 117h.3zM290.8 116.8h.3zM290.8 116.6h.3z"/>
<path d="M290.8 116.4h.3zM290.8 116.1h.3zM290.8 115.9h.3zM290.8 115.7h.3zM290.8 115.5h.3zM290.8 115.3h.3zM290.8 115h.3zM290.8 114.8h.3zM290.8 119.8h.3zM290.8 119.9h.3zM291.1 104.6v2.5zM290.8 107.1h.3z"/>
<path d="M291.1 109.7v2.5zM290.8 112.2h.3zM291.1 114.7v2.6zM291.1 119.8v2.6zM309.9 117.8h5zM309.9 118.6v.7zM309.9 117.8v.8zM309.9 115.3v.7zM309.9 116v.8zM309.9 115.3h5zM309.9 112.7h5zM309.9 112.7v.8z"/>
<path d="M309.9 113.5v.7zM309.9 119.3h5zM314.9 117.8v.8zM314.9 118.6v.7zM314.9 115.3v.7zM314.9 116v.8zM309.9 116.8h5zM309.9 114.2h5zM314.9 112.7v.8zM314.9 113.5v.7zM356.8 104.6v2.5zM356.8 104.6l2.6 1.3z"/>
<path d="M356.8 107h.2zM356.8 106.8h.7zM356.8 106.6h1.1zM356.8 106.4h1.5zM356.8 106.1h2zM356.8 105.9h2.4zM356.8 105.7h2.3zM356.8 105.5h1.8zM356.8 105.3h1.4zM356.8 105h.9zM356.8 104.8h.5zM356.8 109.7v2.5z"/>
<path d="M356.8 109.7l2.6 1.2zM356.8 112.1h.1zM356.8 111.9h.6zM356.8 111.7h1zM356.8 111.5h1.5zM356.8 111.3h1.9zM356.8 111h2.4zM356.8 110.8h2.3zM356.8 110.6h1.9zM356.8 110.4h1.4zM356.8 110.1h1zM356.8 109.9h.6z"/>
<path d="M356.8 114.7v2.6zM356.8 114.7l2.6 1.3zM356.8 117h.5zM356.8 116.8h1zM356.8 116.6h1.4zM356.8 116.4h1.9zM356.8 116.1h2.3zM356.8 115.9h2.4zM356.8 115.7h1.9zM356.8 115.5h1.5zM356.8 115.3h1.1zM356.8 115h.6z"/>
<path d="M356.8 114.8h.2zM356.8 119.8l2.6 1.3zM356.8 119.9h.2zM359.4 105.9v1.2zM356.8 107.1l2.6-1.2zM359.4 104.6v2.5zM359.4 104.6h.2zM359.4 107h.2zM359.4 106.8h.2zM359.4 106.6h.2zM359.4 106.4h.2zM359.4 106.1h.2z"/>
<path d="M359.4 105.9h.2zM359.4 105.7h.2zM359.4 105.5h.2zM359.4 105.3h.2zM359.4 105h.2zM359.4 104.8h.2zM359.4 110.9v1.3zM356.8 112.2l2.6-1.3zM359.4 109.7v2.5zM359.4 109.7h.2zM359.4 112.1h.2zM359.4 111.9h.2z"/>
<path d="M359.4 111.7h.2zM359.4 111.5h.2zM359.4 111.3h.2zM359.4 111h.2zM359.4 110.8h.2zM359.4 110.6h.2zM359.4 110.4h.2zM359.4 110.1h.2zM359.4 109.9h.2zM359.4 116v1.3zM356.8 117.3l2.6-1.3zM359.4 114.7v2.6z"/>
<path d="M359.4 114.7h.2zM359.4 117.3h.2zM359.4 117h.2zM359.4 116.8h.2zM359.4 116.6h.2zM359.4 116.4h.2zM359.4 116.1h.2zM359.4 115.9h.2zM359.4 115.7h.2zM359.4 115.5h.2zM359.4 115.3h.2zM359.4 115h.2z"/>
<path d="M359.4 114.8h.2zM359.4 119.8h.2zM359.4 119.9h.2zM359.6 104.6v2.5zM359.4 107.1h.2zM359.6 109.7v2.5zM359.4 112.2h.2zM359.6 114.7v2.6zM359.6 119.8v2.6zM378.4 117.8h5.1zM378.4 118.6v.7zM378.4 117.8v.8z"/>
<path d="M378.4 115.3v.7zM378.4 116v.8zM378.4 115.3h5.1zM378.4 112.7h5.1zM378.4 112.7v.8zM378.4 113.5v.7zM378.4 119.3h5.1zM383.5 117.8v.8zM383.5 118.6v.7zM383.5 115.3v.7zM383.5 116v.8zM378.4 116.8h5.1z"/>
<path d="M378.4 114.2h5.1zM383.5 112.7v.8zM383.5 113.5v.7zM159.4 127.4h3.8zM288.3 119.8v2.6zM288.3 122.2h.4zM288.3 121.9h.8zM288.3 121.7h1.3zM288.3 121.5h1.7zM288.3 121.3h2.2zM288.3 121h2.4zM288.3 120.8h1.9z"/>
<path d="M288.3 120.6h1.5zM288.3 120.4h1zM288.3 120.1h.6zM288.3 124.9v2.5zM288.3 124.9l2.5 1.3zM288.3 127.3h.3zM288.3 127h.8zM288.3 126.8h1.2zM288.3 126.6h1.7zM288.3 126.4h2.1zM288.3 126.2h2.4zM288.3 125.9h2z"/>
<path d="M288.3 125.7h1.6zM288.3 125.5h1.1zM288.3 125.3h.7zM288.3 125h.2zM288.3 130v2.5zM288.3 130l2.5 1.3zM288.3 132.4h.3zM288.3 132.1h.7zM288.3 131.9h1.2zM288.3 131.7h1.6zM288.3 131.5h2.1zM288.3 131.3h2.5z"/>
<path d="M288.3 131h2.1zM288.3 130.8h1.6zM288.3 130.6h1.2zM288.3 130.4h.7zM288.3 130.2h.3zM288.3 135.1v2.5zM288.3 135.1l2.5 1.2zM288.3 137.5h.2zM288.3 137.2h.7zM288.3 137h1.1zM288.3 136.8h1.6zM288.3 136.6h2z"/>
<path d="M288.3 136.4h2.4zM288.3 136.1h2.1zM288.3 135.9h1.7zM288.3 135.7h1.2zM288.3 135.5h.8zM288.3 135.3h.3zM290.8 121.1v1.3zM288.3 122.4l2.5-1.3zM290.8 119.8v2.6zM290.8 122.2h.3zM290.8 121.9h.3zM290.8 121.7h.3z"/>
<path d="M290.8 121.5h.3zM290.8 121.3h.3zM290.8 121h.3zM290.8 120.8h.3zM290.8 120.6h.3zM290.8 120.4h.3zM290.8 120.1h.3zM290.8 126.2v1.2zM288.3 127.4l2.5-1.2zM290.8 124.9v2.5zM290.8 124.9h.3zM290.8 127.3h.3z"/>
<path d="M290.8 127h.3zM290.8 126.8h.3zM290.8 126.6h.3zM290.8 126.4h.3zM290.8 126.2h.3zM290.8 125.9h.3zM290.8 125.7h.3zM290.8 125.5h.3zM290.8 125.3h.3zM290.8 125h.3zM290.8 131.3v1.2zM288.3 132.5l2.5-1.2z"/>
<path d="M290.8 130v2.5zM290.8 130h.3zM290.8 132.4h.3zM290.8 132.1h.3zM290.8 131.9h.3zM290.8 131.7h.3zM290.8 131.5h.3zM290.8 131.3h.3zM290.8 131h.3zM290.8 130.8h.3zM290.8 130.6h.3zM290.8 130.4h.3z"/>
<path d="M290.8 130.2h.3zM290.8 136.3v1.3zM288.3 137.6l2.5-1.3zM290.8 135.1v2.5zM290.8 135.1h.3zM290.8 137.5h.3zM290.8 137.2h.3zM290.8 137h.3zM290.8 136.8h.3zM290.8 136.6h.3zM290.8 136.4h.3zM290.8 136.1h.3z"/>
<path d="M290.8 135.9h.3zM290.8 135.7h.3zM290.8 135.5h.3zM290.8 135.3h.3zM290.8 122.4h.3zM291.1 124.9v2.5zM290.8 127.4h.3zM291.1 130v2.5zM290.8 132.5h.3zM291.1 135.1v2.5zM290.8 137.6h.3zM309.9 130.5h5z"/>
<path d="M309.9 131.3v.7zM309.9 130.5v.8zM309.9 128v.7zM309.9 128.7v.8zM309.9 128h5zM309.9 125.4h5zM309.9 122.9h5zM309.9 120.3h5zM309.9 125.4v.8zM309.9 122.9v.7zM309.9 120.3v.8zM309.9 126.2v.7z"/>
<path d="M309.9 123.6v.8zM309.9 121.1v.8zM309.9 132h5zM314.9 130.5v.8zM314.9 131.3v.7zM314.9 128v.7zM314.9 128.7v.8zM309.9 129.5h5zM309.9 126.9h5zM309.9 124.4h5zM309.9 121.9h5zM314.9 125.4v.8z"/>
<path d="M314.9 122.9v.7zM314.9 120.3v.8zM314.9 126.2v.7zM314.9 123.6v.8zM314.9 121.1v.8zM321.9 136.3h3.8zM356.8 119.8v2.6zM356.8 122.2h.5zM356.8 121.9h.9zM356.8 121.7h1.4zM356.8 121.5h1.8zM356.8 121.3h2.2z"/>
<path d="M356.8 121h2.5zM356.8 120.8h2zM356.8 120.6h1.6zM356.8 120.4h1.1zM356.8 120.1h.7zM356.8 124.9v2.5zM356.8 124.9l2.6 1.3zM356.8 127.3h.4zM356.8 127h.8zM356.8 126.8h1.3zM356.8 126.6h1.7zM356.8 126.4h2.2z"/>
<path d="M356.8 126.2h2.5zM356.8 125.9h2.1zM356.8 125.7h1.6zM356.8 125.5h1.2zM356.8 125.3h.7zM356.8 125h.3zM356.8 130v2.5zM356.8 130l2.6 1.3zM356.8 132.4h.3zM356.8 132.1h.8zM356.8 131.9h1.2zM356.8 131.7h1.7z"/>
<path d="M356.8 131.5h2.1zM356.8 131.3h2.6zM356.8 131h2.1zM356.8 130.8h1.7zM356.8 130.6h1.2zM356.8 130.4h.8zM356.8 130.2h.4zM356.8 135.1v2.5zM356.8 135.1l2.6 1.2zM356.8 137.5h.3zM356.8 137.2h.7zM356.8 137h1.2z"/>
<path d="M356.8 136.8h1.6zM356.8 136.6h2.1zM356.8 136.4h2.5zM356.8 136.1h2.2zM356.8 135.9h1.7zM356.8 135.7h1.3zM356.8 135.5h.8zM356.8 135.3h.4zM359.4 121.1v1.3zM356.8 122.4l2.6-1.3zM359.4 119.8v2.6zM359.4 122.2h.2z"/>
<path d="M359.4 121.9h.2zM359.4 121.7h.2zM359.4 121.5h.2zM359.4 121.3h.2zM359.4 121h.2zM359.4 120.8h.2zM359.4 120.6h.2zM359.4 120.4h.2zM359.4 120.1h.2zM359.4 126.2v1.2zM356.8 127.4l2.6-1.2zM359.4 124.9v2.5z"/>
<path d="M359.4 124.9h.2zM359.4 127.3h.2zM359.4 127h.2zM359.4 126.8h.2zM359.4 126.6h.2zM359.4 126.4h.2zM359.4 126.2h.2zM359.4 125.9h.2zM359.4 125.7h.2zM359.4 125.5h.2zM359.4 125.3h.2zM359.4 125h.2z"/>
<path d="M359.4 131.3v1.2zM356.8 132.5l2.6-1.2zM359.4 130v2.5zM359.4 130h.2zM359.4 132.4h.2zM359.4 132.1h.2zM359.4 131.9h.2zM359.4 131.7h.2zM359.4 131.5h.2zM359.4 131.3h.2zM359.4 131h.2zM359.4 130.8h.2z"/>
<path d="M359.4 130.6h.2zM359.4 130.4h.2zM359.4 130.2h.2zM359.4 136.3v1.3zM356.8 137.6l2.6-1.3zM359.4 135.1v2.5zM359.4 135.1h.2zM359.4 137.5h.2zM359.4 137.2h.2zM359.4 137h.2zM359.4 136.8h.2zM359.4 136.6h.2z"/>
<path d="M359.4 136.4h.2zM359.4 136.1h.2zM359.4 135.9h.2zM359.4 135.7h.2zM359.4 135.5h.2zM359.4 135.3h.2zM359.4 122.4h.2zM359.6 124.9v2.5zM359.4 127.4h.2zM359.6 130v2.5zM359.4 132.5h.2zM359.6 135.1v2.5z"/>
<path d="M359.4 137.6h.2zM378.4 130.5h5.1zM378.4 131.3v.7zM378.4 130.5v.8zM378.4 128v.7zM378.4 128.7v.8zM378.4 128h5.1zM378.4 125.4h5.1zM378.4 122.9h5.1zM378.4 120.3h5.1zM378.4 125.4v.8zM378.4 122.9v.7z"/>
<path d="M378.4 120.3v.8zM378.4 126.2v.7zM378.4 123.6v.8zM378.4 121.1v.8zM378.4 132h5.1zM383.5 130.5v.8zM383.5 131.3v.7zM383.5 128v.7zM383.5 128.7v.8zM378.4 129.5h5.1zM378.4 126.9h5.1zM378.4 124.4h5.1z"/>
<path d="M378.4 121.9h5.1zM383.5 125.4v.8zM383.5 122.9v.7zM383.5 120.3v.8zM383.5 126.2v.7zM383.5 123.6v.8zM383.5 121.1v.8zM390.5 136.3h3.8zM72.4 144l-1.3 1.9zM72.4 144l1.3 1.9zM115.6 144l-1.3 1.9zM115.6 144l1.2 1.9z"/>
<path d="M161.3 144l-1.3 1.9zM161.3 144l1.2 1.9zM204.4 144l-1.2 1.9zM204.4 144l1.3 1.9zM279.4 158.4h5.1zM279.4 155.9h5.1zM279.4 158.4v.8zM279.4 155.9v.8zM279.4 159.2v.8zM279.4 156.7v.7zM279.4 153.3h5.1zM279.4 154.1v.8z"/>
<path d="M279.4 153.3v.8zM279.4 150.8v.8zM279.4 151.6v.7zM279.4 150.8h5.1zM279.4 148.3h5.1zM279.4 148.3v.7zM279.4 149v.8zM279.4 160h5.1zM279.4 157.4h5.1zM284.5 158.4v.8zM284.5 155.9v.8zM284.5 159.2v.8z"/>
<path d="M284.5 156.7v.7zM279.4 154.9h5.1zM284.5 153.3v.8zM284.5 154.1v.8zM284.5 150.8v.8zM284.5 151.6v.7zM279.4 152.3h5.1zM279.4 149.8h5.1zM284.5 148.3v.7zM284.5 149v.8zM288.3 140.1v2.6zM288.3 140.1l2.5 1.3z"/>
<path d="M288.3 142.6h.2zM288.3 142.4h.6zM288.3 142.1h1zM288.3 141.9h1.5zM288.3 141.7h1.9zM288.3 141.5h2.4zM288.3 141.2h2.2zM288.3 141h1.7zM288.3 140.8h1.3zM288.3 140.6h.9zM288.3 140.4h.4zM290.8 141.4v1.3z"/>
<path d="M288.3 142.7l2.5-1.3zM290.8 140.1v2.6zM290.8 140.1h.3zM290.8 142.6h.3zM290.8 142.4h.3zM290.8 142.1h.3zM290.8 141.9h.3zM290.8 141.7h.3zM290.8 141.5h.3zM290.8 141.2h.3zM290.8 141h.3zM290.8 140.8h.3z"/>
<path d="M290.8 140.6h.3zM290.8 140.4h.3zM291.1 140.1v2.6zM290.8 142.7h.3zM356.8 140.1v2.6zM356.8 140.1l2.6 1.3zM356.8 142.6h.2zM356.8 142.4h.7zM356.8 142.1h1.1zM356.8 141.9h1.5zM356.8 141.7h2zM356.8 141.5h2.4z"/>
<path d="M356.8 141.2h2.2zM356.8 141h1.8zM356.8 140.8h1.4zM356.8 140.6h.9zM356.8 140.4h.5zM359.4 141.4v1.3zM356.8 142.7l2.6-1.3zM359.4 140.1v2.6zM359.4 140.1h.2zM359.4 142.6h.2zM359.4 142.4h.2zM359.4 142.1h.2z"/>
<path d="M359.4 141.9h.2zM359.4 141.7h.2zM359.4 141.5h.2zM359.4 141.2h.2zM359.4 141h.2zM359.4 140.8h.2zM359.4 140.6h.2zM359.4 140.4h.2zM359.6 140.1v2.6zM359.4 142.7h.2zM70.5 169.4h3.8zM113.7 169.4h3.8z"/>
<path d="M159.4 169.4h3.8zM202.5 169.4h3.9zM279.4 166h5.1zM279.4 166.8v.8zM279.4 166v.8zM279.4 163.5v.8zM279.4 164.3v.7zM279.4 163.5h5.1zM279.4 161h5.1zM279.4 161v.7zM279.4 161.7v.8zM279.4 167.6h5.1z"/>
<path d="M284.5 166v.8zM284.5 166.8v.8zM284.5 163.5v.8zM284.5 164.3v.7zM279.4 165h5.1zM279.4 162.5h5.1zM284.5 161v.7zM284.5 161.7v.8zM291.4 171.9h3.8zM72.4 194.8l-1.3 1.9zM72.4 194.8l1.3 1.9zM115.6 194.8l-1.3 1.9z"/>
<path d="M115.6 194.8l1.2 1.9zM161.3 194.8l-1.3 1.9zM161.3 194.8l1.2 1.9zM204.4 194.8l-1.2 1.9zM204.4 194.8l1.3 1.9zM377.1 207.4l1.6-1.5zM377.1 207.4l1.6 1.6zM378.7 205.9h10.2zM378.7 209h10.2zM388.9 205.9v3.1zM70.5 220.1h3.8zM113.7 220.1h3.8z"/>
<path d="M159.4 220.1h3.8zM202.5 220.1h3.9zM113 243l-1.2 1.9zM113 243l1.3 1.9zM120.6 243l-1.2 1.9zM120.6 243l1.3 1.9zM313.7 249.3h86.3zM313.7 254.4h86.3zM313.7 259.5h58.4zM372.1 259.5h27.9zM372.1 259.5v5.1zM27.3 265.8h3.8z"/>
<path d="M118.7 265.8h3.8zM156.8 265.8h3.8zM313.7 264.6h58.4zM313.7 269.7h86.3zM372.1 264.6h27.9zM400 268.4v1.3z"/>
</g>
<path d="M16.5 18.2v260.3zM16.5 18.2h387.3zM16.5 278.5h387.3zM403.8 18.2v260.3z" fill="#000" stroke="#000" stroke-width=".32"/>
<g fill="#000" stroke="#000" stroke-width=".61">
<path d="M20.3 22.1v252.6zM20.3 22.1h379.7zM100.3 65.2v22.9zM100.3 65.2h17.8zM168.9 65.2v30.5zM168.9 65.2h15.2zM224.8 65.2v30.5zM224.8 65.2h15.2zM280.6 65.2v30.5zM280.6 65.2h15.3zM308.6 67.8h1.3zM308.6 70.3h1.3z"/>
<path d="M308.6 72.8h1.3zM308.6 75.4h1.3zM308.6 77.9h1.3zM349.2 65.2v30.5zM349.2 65.2h15.2zM374.6 67.8h1.3zM374.6 70.3h1.3zM374.6 72.8h1.3zM374.6 75.4h1.3zM374.6 77.9h1.3zM69.8 88.1v10.1zM100.3 88.1h17.8z"/>
<path d="M118.1 65.2v22.9zM168.9 95.7h15.2zM184.1 65.2v30.5zM224.8 95.7h15.2zM240 65.2v30.5zM280.6 95.7h15.3zM295.9 65.2v30.5zM308.6 80.5h1.3zM308.6 83h1.3zM308.6 85.5h1.3zM349.2 95.7h15.2zM364.4 65.2v30.5z"/>
<path d="M374.6 80.5h1.3zM374.6 83h1.3zM374.6 85.5h1.3zM168.9 104.6v20.3zM168.9 104.6h15.2zM168.9 124.9h15.2zM184.1 104.6v20.3zM80 146.5v20.3zM80 146.5h15.2zM123.2 146.5v20.3zM123.2 146.5h15.2zM168.9 146.5v20.3z"/>
<path d="M168.9 146.5h15.2zM212.1 146.5v20.3zM212.1 146.5h15.2zM80 166.8h15.2zM95.2 146.5v20.3zM123.2 166.8h15.2zM138.4 146.5v20.3zM168.9 166.8h15.2zM184.1 146.5v20.3zM212.1 166.8h15.2zM227.3 146.5v20.3zM80 197.3v20.3z"/>
<path d="M80 197.3h15.2zM123.2 197.3v20.3zM123.2 197.3h15.2zM168.9 197.3v20.3zM168.9 197.3h15.2zM212.1 197.3v20.3zM212.1 197.3h15.2zM275.6 187.1v10.2zM275.6 197.3v10.1zM308.6 194.8v10.1zM80 217.6h15.2zM95.2 197.3v20.3z"/>
<path d="M123.2 217.6h15.2zM138.4 197.3v20.3zM168.9 217.6h15.2zM184.1 197.3v20.3zM212.1 217.6h15.2zM227.3 197.3v20.3zM275.6 207.4v10.2zM275.6 217.6v10.1zM308.6 210v10.1zM339 202.4v10.1zM166.3 243v20.3zM166.3 243h15.3z"/>
<path d="M283.2 244.3v30.4zM313.7 254.4v5.1zM313.7 249.3v5.1zM313.7 244.3v5zM313.7 244.3h86.3zM283.2 244.3h30.5zM400 254.4v5.1zM400 249.3v5.1zM400 244.3v5zM400 22.1v222.2zM20.3 274.7h262.9zM166.3 263.3h15.3z"/>
<path d="M181.6 243v20.3zM283.2 274.7h30.5zM313.7 274.7h86.3zM313.7 269.7v5zM313.7 264.6v5.1zM313.7 259.5v5.1zM400 268.4v6.3zM400 264.6v3.8zM400 259.5v5.1z"/>
</g>
<g fill="none" stroke="#000" stroke-width=".21">
<circle cx="119.1" cy="70.3" r=".99"/>
<circle cx="119.1" cy="77.9" r=".99"/>
<circle cx="119.1" cy="72.8" r=".99"/>
<circle cx="119.1" cy="67.8" r=".99"/>
<circle cx="119.1" cy="75.4" r=".99"/>
<circle cx="185.1" cy="72.8" r=".99"/>
<circle cx="185.1" cy="75.4" r=".99"/>
<circle cx="185.1" cy="77.9" r=".99"/>
<circle cx="185.1" cy="70.3" r=".99"/>
<circle cx="185.1" cy="67.8" r=".99"/>
<circle cx="99.3" cy="83" r=".99"/>
<circle cx="99.3" cy="85.5" r=".99"/>
<circle cx="119.1" cy="85.5" r=".99"/>
<circle cx="119.1" cy="80.5" r=".99"/>
<circle cx="119.1" cy="83" r=".99"/>
<circle cx="167.9" cy="93.2" r=".99"/>
<circle cx="167.9" cy="90.6" r=".99"/>
<circle cx="185.1" cy="80.5" r=".99"/>
<circle cx="185.1" cy="85.5" r=".99"/>
<circle cx="185.1" cy="83" r=".99"/>
<circle cx="223.8" cy="93.2" r="1"/>
<circle cx="279.6" cy="93.2" r="1"/>
<circle cx="279.6" cy="90.6" r="1"/>
<circle cx="348.2" cy="93.2" r="1"/>
<circle cx="348.2" cy="90.6" r="1"/>
<circle cx="167.9" cy="107.1" r=".99"/>
<circle cx="167.9" cy="122.4" r=".99"/>
<circle cx="79" cy="149" r=".99"/>
<circle cx="122.2" cy="149" r=".99"/>
<circle cx="167.9" cy="149" r=".99"/>
<circle cx="211.1" cy="149" r=".99"/>
<circle cx="79" cy="164.3" r=".99"/>
<circle cx="122.2" cy="164.3" r=".99"/>
<circle cx="167.9" cy="164.3" r=".99"/>
<circle cx="211.1" cy="164.3" r=".99"/>
<circle cx="79" cy="199.8" r=".99"/>
<circle cx="122.2" cy="199.8" r=".99"/>
<circle cx="167.9" cy="199.8" r=".99"/>
<circle cx="211.1" cy="199.8" r=".99"/>
<circle cx="79" cy="215" r=".99"/>
<circle cx="122.2" cy="215" r=".99"/>
<circle cx="167.9" cy="215" r=".99"/>
<circle cx="211.1" cy="215" r=".99"/>
<circle cx="165.4" cy="245.5" r=".99"/>
<circle cx="165.4" cy="260.8" r=".99"/>
</g>
<path d="M69.8 88.1a5.1 5.1 0 0 1 5.1 5.1 5.1 5.1 0 0 1-5.1 5M275.6 187.1a5.1 5.1 0 0 1 5 5.1 5.1 5.1 0 0 1-5 5.1 5.1 5.1 0 0 1 5 5.1 5.1 5.1 0 0 1-5 5 5.1 5.1 0 0 1 5 5.1 5.1 5.1 0 0 1-5 5.1 5.1 5.1 0 0 1 5 5.1 5.1 5.1 0 0 1-5 5M308.6 194.8a5.1 5.1 0 0 1 5.1 5 5.1 5.1 0 0 1-5.1 5.1M308.6 210a5.1 5.1 0 0 1 5.1 5 5.1 5.1 0 0 1-5.1 5.1M339 202.4a5.1 5.1 0 0 1 5.1 5 5.1 5.1 0 0 1-5.1 5.1" fill="none" stroke="#000" stroke-width=".61"/>
<g fill="#000" stroke="#000" stroke-width=".21">
<path d="M27.2 253.7h4v.5h-4zM27.2 254.7h4v.5h-4zM34.8 253.7h4.1v.5h-4.1zM34.8 254.7h4.1v.5h-4.1zM42.4 253.7h4.1v.5h-4.1zM42.4 254.7h4.1v.5h-4.1zM50 253.7h4.1v.5h-4.1zM50 254.7h4.1v.5h-4.1zM57.7 253.7h4v.5h-4zM57.7 254.7h4v.5h-4zM65.3 253.7h4v.5h-4zM65.3 254.7h4v.5h-4z"/>
<path d="M72.9 253.7h4.1v.5h-4.1zM72.9 254.7h4.1v.5h-4.1zM80.5 253.7h4.1v.5h-4.1zM80.5 254.7h4.1v.5h-4.1zM88.1 253.7h4.1v.5h-4.1zM88.1 254.7h4.1v.5h-4.1zM95.8 253.7h4v.5h-4zM95.8 254.7h4v.5h-4zM103.4 253.7h4v.5h-4zM103.4 254.7h4v.5h-4zM111 253.7h4.1v.5h-4.1zM111 254.7h4.1v.5h-4.1z"/>
<path d="M118.6 254.7h4.1v.5h-4.1zM118.6 253.7h4.1v.5h-4.1zM254 253.1h25.4v10.2h-25.4z"/>
</g>
<g fill="#000" stroke="#000" stroke-width=".42">
<path d="M308.6 110.9h8.9zM377.1 110.9h8.9zM308.6 110.9v22.9zM308.6 133.8h8.9zM317.5 110.9v22.9zM377.1 110.9v22.9zM377.1 133.8h8.9zM386 110.9v22.9zM278.1 146.5h8.9zM278.1 146.5v22.9zM278.1 169.4h8.9zM287 146.5v22.9z"/>
<path d="M223.5 253.1v10.2zM223.5 253.1h55.9zM223.5 263.3v7.6zM223.5 270.9h55.9zM223.5 263.3h55.9zM279.4 263.3v7.6zM279.4 253.1v10.2zM279.4 263.3v2.5z"/>
</g>
<g fill="none" stroke="#000" stroke-width=".42">
<circle cx="316.2" cy="118.6" r=".25"/>
<circle cx="316.2" cy="116" r=".25"/>
<circle cx="384.8" cy="118.6" r=".25"/>
<circle cx="384.8" cy="116" r=".25"/>
<circle cx="316.2" cy="131.3" r=".25"/>
<circle cx="316.2" cy="123.6" r=".25"/>
<circle cx="316.2" cy="128.7" r=".25"/>
<circle cx="316.2" cy="126.2" r=".25"/>
<circle cx="316.2" cy="121.1" r=".25"/>
<circle cx="384.8" cy="121.1" r=".25"/>
<circle cx="384.8" cy="131.3" r=".25"/>
<circle cx="384.8" cy="123.6" r=".25"/>
<circle cx="384.8" cy="128.7" r=".25"/>
<circle cx="384.8" cy="126.2" r=".25"/>
<circle cx="285.7" cy="154.1" r=".25"/>
<circle cx="285.7" cy="151.6" r=".25"/>
<circle cx="285.7" cy="159.2" r=".25"/>
<circle cx="285.7" cy="156.7" r=".25"/>
<circle cx="285.7" cy="161.7" r=".25"/>
<circle cx="285.7" cy="164.3" r=".25"/>
<circle cx="285.7" cy="166.8" r=".25"/>
</g>
<g fill="#000" stroke="#000" stroke-width=".76">
<path d="M44.4 37.3h5.1zM44.4 32.2h155zM199.4 32.2l5 5.1zM153.6 39.8h172.8zM49.5 37.3l5.1 5.1zM151.1 42.4l2.5-2.6zM326.4 39.8l2.5 2.6zM260.3 65.2v114.3zM54.6 42.4v50.8zM151.1 42.4v40.6zM204.4 37.3v45.7zM44.4 136.3h157.5z"/>
<path d="M52.1 136.3l5 5.1zM67.3 131.3h187.9zM260.3 126.2l-5.1 5.1zM57.1 141.4v40.7zM105.4 177h137.1zM242.5 177l2.6 2.5zM245.1 179.5v45.7zM245.1 179.5l2.5-2.5zM247.6 177h78.8zM328.9 174.4l-2.5 2.6zM328.9 42.4v132zM57.1 182.1l5.1 5z"/>
<path d="M62.2 187.1h139.7zM67.3 182.1h190.5zM257.8 182.1l2.5-2.6zM105.4 227.7h137.1zM245.1 225.2l-2.6 2.5z"/>
</g>
<use href="#words"/>
</svg>
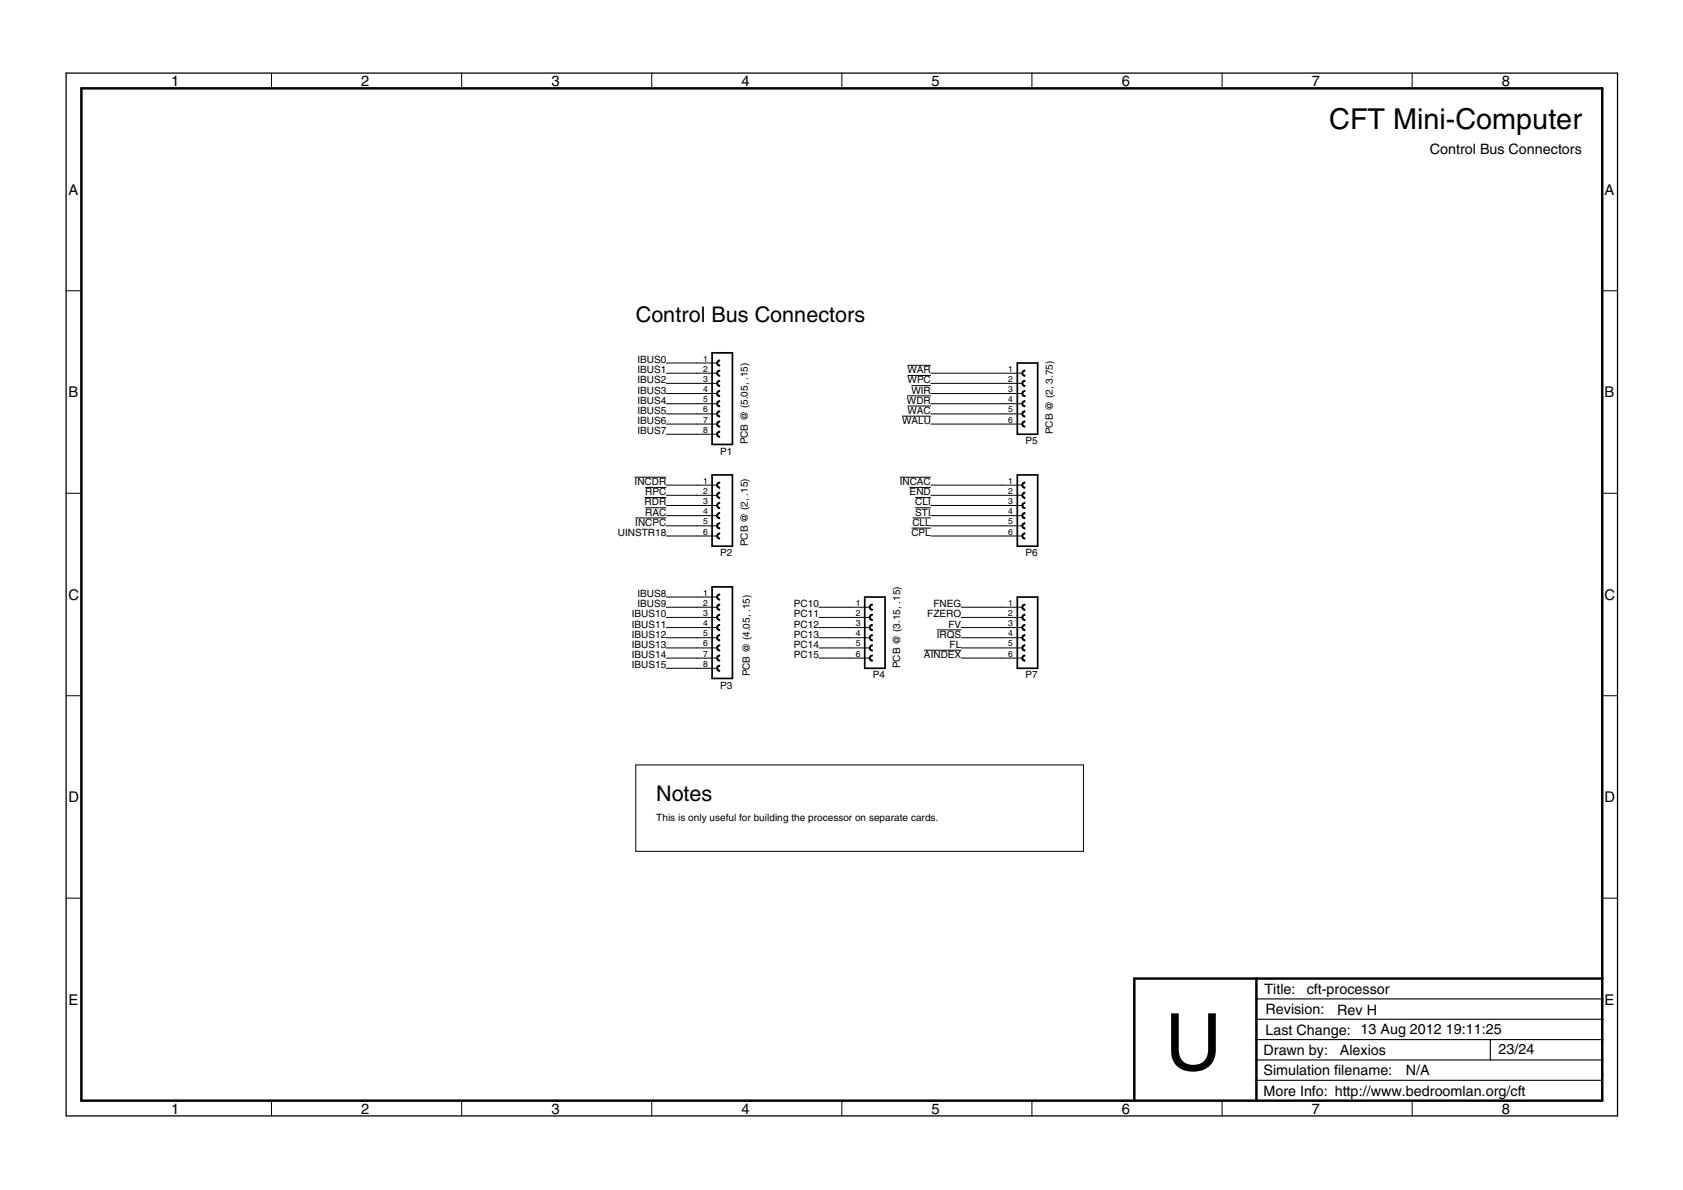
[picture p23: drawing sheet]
<svg xmlns="http://www.w3.org/2000/svg" width="420mm" height="297mm" viewBox="0 0 420 297" stroke-linecap="round" stroke-linejoin="round" font-family="sans-serif">
<defs><g id="words">
<text font-size="19.7" x="290.8" y="267.1">U</text>
<text font-size="7.2" x="331.8" y="32.2">CFT Mini-Computer</text>
<g font-size="5.4">
<text x="158.7" y="80.5">Control Bus Connectors</text>
<text x="163.8" y="199.8">Notes</text>
</g>
<g font-size="3.7">
<text x="42.7" y="21.5">1</text>
<text x="90.2" y="21.5">2</text>
<text x="137.7" y="21.5">3</text>
<text x="185.1" y="21.5">4</text>
<text x="232.6" y="21.5">5</text>
<text x="280" y="21.5">6</text>
<text x="327.5" y="21.5">7</text>
<text x="375" y="21.5">8</text>
<text x="17.1" y="48.6">A</text>
<text x="400.6" y="48.6">A</text>
<text x="17.1" y="99.2">B</text>
<text x="400.6" y="99.2">B</text>
<text x="17.1" y="149.7">C</text>
<text x="400.6" y="149.7">C</text>
<text x="17.1" y="200.2">D</text>
<text x="400.6" y="200.2">D</text>
<text x="17.1" y="250.8">E</text>
<text x="400.6" y="250.8">E</text>
<text x="42.7" y="277.9">1</text>
<text x="90.2" y="277.9">2</text>
<text x="137.7" y="277.9">3</text>
<text x="185.1" y="277.9">4</text>
<text x="232.6" y="277.9">5</text>
<text x="280" y="277.9">6</text>
<text x="327.5" y="277.9">7</text>
<text x="375" y="277.9">8</text>
</g>
<g font-size="3.6">
<text x="357" y="38.6">Control Bus Connectors</text>
<text x="315.7" y="248.1">Title:</text>
<text x="326.2" y="248.2">cft-processor</text>
<text x="315.9" y="253.2">Revision:</text>
<text x="333.8" y="253.3">Rev H</text>
<text x="315.4" y="263.3">Drawn by:</text>
<text x="315.9" y="258.2">Last Change: 13 Aug 2012</text>
<text x="334.5" y="263.3">Alexios</text>
<text x="361" y="258.1">19:11:25</text>
<text x="374.1" y="263.2">23/24</text>
<text x="315.4" y="268.4">Simulation filename:</text>
<text x="351" y="268.4">N/A</text>
<text x="315.4" y="273.5">More Info: http://www.bedroomlan.org/cft</text>
</g>
<g font-size="2.5">
<text x="159.1" y="90.6">IBUS0</text>
<text x="159.1" y="93.2">IBUS1</text>
<text x="159.1" y="95.7">IBUS2</text>
<text x="226.6" y="93.2">WAR</text>
<text x="226.6" y="95.7">WPC</text>
<text x="159.1" y="98.2">IBUS3</text>
<text x="159.1" y="100.8">IBUS4</text>
<text x="226.4" y="100.8">WDR</text>
<text x="227.5" y="98.2">WIR</text>
<text x="159.1" y="103.3">IBUS5</text>
<text x="159.1" y="105.9">IBUS6</text>
<text x="225.2" y="105.9">WALU</text>
<text x="226.6" y="103.3">WAC</text>
<text x="159.1" y="108.4">IBUS7</text>
<text x="179.8" y="113.5">P1</text>
<text x="186.7" y="110.9" transform="rotate(-90 186.7 110.9)">PCB @ (5.05, .15)</text>
<text x="256" y="110.9">P5</text>
<text x="262.9" y="108.4" transform="rotate(-90 262.9 108.4)">PCB @ (2, 3.75)</text>
<text x="158.4" y="121.1">INCDR</text>
<text x="161.1" y="123.6">RPC</text>
<text x="224.6" y="121.1">INCAC</text>
<text x="227.1" y="123.6">END</text>
<text x="158.6" y="131.3">INCPC</text>
<text x="160.9" y="126.2">RDR</text>
<text x="161.1" y="128.7">RAC</text>
<text x="227.8" y="131.3">CLL</text>
<text x="228.5" y="128.7">STI</text>
<text x="228.5" y="126.2">CLI</text>
<text x="154.3" y="133.8">UINSTR18</text>
<text x="186.7" y="136.3" transform="rotate(-90 186.7 136.3)">PCB @ (2, .15)</text>
<text x="227.5" y="133.8">CPL</text>
<text x="179.8" y="138.9">P2</text>
<text x="256" y="138.9">P6</text>
<text x="159.1" y="149">IBUS8</text>
<text x="157.7" y="154.1">IBUS10</text>
<text x="159.1" y="151.6">IBUS9</text>
<text x="198.2" y="151.6">PC10</text>
<text x="198.2" y="154.1">PC11</text>
<text x="231.5" y="154.1">FZERO</text>
<text x="233.1" y="151.6">FNEG</text>
<text x="157.7" y="161.7">IBUS13</text>
<text x="157.7" y="159.2">IBUS12</text>
<text x="157.7" y="156.6">IBUS11</text>
<text x="198.2" y="156.6">PC12</text>
<text x="198.2" y="159.2">PC13</text>
<text x="198.2" y="161.7">PC14</text>
<text x="233.9" y="159.2">IRQS</text>
<text x="236.8" y="156.6">FV</text>
<text x="237.1" y="161.7">FL</text>
<text x="157.7" y="166.8">IBUS15</text>
<text x="157.7" y="164.3">IBUS14</text>
<text x="198.2" y="164.3">PC15</text>
<text x="224.8" y="166.8" transform="rotate(-90 224.8 166.8)">PCB @ (3.15, .15)</text>
<text x="230.7" y="164.3">AINDEX</text>
<text x="179.8" y="171.9">P3</text>
<text x="187.2" y="168.8" transform="rotate(-90 187.2 168.8)">PCB @ (4.05, .15)</text>
<text x="217.9" y="169.3">P4</text>
<text x="256" y="169.3">P7</text>
<text x="163.8" y="204.9">This is only useful for building the processor on separate cards.</text>
</g>
<g font-size="2.1">
<text x="175.5" y="90.3">1</text>
<text x="175.5" y="92.8">2</text>
<text x="175.5" y="95.3">3</text>
<text x="251.7" y="92.8">1</text>
<text x="251.7" y="95.3">2</text>
<text x="175.5" y="97.9">4</text>
<text x="175.5" y="100.4">5</text>
<text x="251.7" y="97.9">3</text>
<text x="251.7" y="100.4">4</text>
<text x="175.5" y="103">6</text>
<text x="175.5" y="105.5">7</text>
<text x="251.7" y="103">5</text>
<text x="251.7" y="105.5">6</text>
<text x="175.5" y="108">8</text>
<text x="175.5" y="120.7">1</text>
<text x="175.5" y="123.3">2</text>
<text x="175.5" y="125.8">3</text>
<text x="251.7" y="120.7">1</text>
<text x="251.7" y="123.3">2</text>
<text x="251.7" y="125.8">3</text>
<text x="175.5" y="128.4">4</text>
<text x="175.5" y="130.9">5</text>
<text x="251.7" y="128.4">4</text>
<text x="251.7" y="130.9">5</text>
<text x="175.5" y="133.4">6</text>
<text x="251.7" y="133.4">6</text>
<text x="175.5" y="148.7">1</text>
<text x="175.5" y="151.2">2</text>
<text x="175.5" y="153.8">3</text>
<text x="213.6" y="151.2">1</text>
<text x="213.6" y="153.8">2</text>
<text x="251.7" y="151.2">1</text>
<text x="251.7" y="153.8">2</text>
<text x="175.5" y="156.3">4</text>
<text x="175.5" y="158.8">5</text>
<text x="175.5" y="161.4">6</text>
<text x="213.6" y="156.3">3</text>
<text x="213.6" y="158.8">4</text>
<text x="213.6" y="161.4">5</text>
<text x="251.7" y="156.3">3</text>
<text x="251.7" y="158.8">4</text>
<text x="251.7" y="161.4">5</text>
<text x="175.5" y="163.9">7</text>
<text x="175.5" y="166.5">8</text>
<text x="213.6" y="163.9">6</text>
<text x="251.7" y="163.9">6</text>
</g>
</g></defs>
<g fill="#000" stroke="#000" stroke-width=".25">
<path d="M67.8 18.2v3.9zM115.3 18.2v3.9zM162.7 18.2v3.9zM210.2 18.2v3.9zM257.6 18.2v3.9zM305.1 18.2v3.9zM352.5 18.2v3.9zM20.3 22.1v252.6zM20.3 22.1h379.7zM16.5 72.6h3.8zM400 72.6h3.8zM174 90.6h5z"/>
<path d="M174 93.2h5zM174 95.7h5zM174 98.2h5zM166.3 90.6h7.7zM166.3 93.2h7.7zM166.3 95.7h7.7zM166.3 98.2h7.7zM226.4 98.8h6zM226.6 91.2h5.8zM226.6 93.7h5.8zM227.5 96.3h4.9zM250.2 93.2h5z"/>
<path d="M250.2 95.7h5zM250.2 98.2h5zM232.4 93.2h17.8zM232.4 98.2h17.8zM232.4 95.7h17.8zM158.4 119.1h7.9zM174 100.8h5zM174 103.3h5zM174 105.9h5zM174 108.4h5zM166.3 100.8h7.7zM166.3 103.3h7.7z"/>
<path d="M166.3 105.9h7.7zM166.3 108.4h7.7zM224.6 119.1h7.8zM225.2 103.9h7.2zM226.6 101.3h5.8zM250.2 100.8h5zM250.2 103.3h5zM250.2 105.9h5zM232.4 100.8h17.8zM232.4 105.9h17.8zM232.4 103.3h17.8zM16.5 123.1h3.8z"/>
<path d="M158.6 129.3h7.7zM160.9 124.2h5.4zM161.1 126.7h5.2zM161.1 121.7h5.2zM166.3 121.1h7.7zM174 121.1h5zM174 123.6h5zM174 126.2h5zM174 128.7h5zM174 131.3h5zM174 133.8h5zM166.3 123.6h7.7z"/>
<path d="M166.3 126.2h7.7zM166.3 128.7h7.7zM166.3 131.3h7.7zM166.3 133.8h7.7zM227.1 121.7h5.3zM227.5 131.8h4.9zM227.8 129.3h4.6zM228.5 126.7h3.9zM228.5 124.2h3.9zM232.4 128.7h17.8zM232.4 133.8h17.8zM250.2 121.1h5z"/>
<path d="M250.2 123.6h5zM250.2 126.2h5zM250.2 128.7h5zM250.2 131.3h5zM250.2 133.8h5zM232.4 121.1h17.8zM232.4 126.2h17.8zM232.4 131.3h17.8zM232.4 123.6h17.8zM400 123.1h3.8zM166.3 159.2h7.7zM166.3 154.1h7.7z"/>
<path d="M166.3 151.6h7.7zM166.3 149h7.7zM174 149h5zM174 151.6h5zM174 154.1h5zM174 156.7h5zM174 159.2h5zM166.3 156.7h7.7zM212.1 151.6h5zM212.1 154.1h5zM212.1 156.7h5zM212.1 159.2h5z"/>
<path d="M204.4 151.6h7.7zM204.4 154.1h7.7zM204.4 156.7h7.7zM204.4 159.2h7.7zM233.9 157.2h6.1zM240 151.6h10.2zM250.2 151.6h5zM250.2 154.1h5zM250.2 156.7h5zM250.2 159.2h5zM240 159.2h10.2zM240 156.7h10.2z"/>
<path d="M240 154.1h10.2zM16.5 173.7h3.8zM166.3 166.8h7.7zM166.3 164.3h7.7zM166.3 161.7h7.7zM174 161.7h5zM174 164.3h5zM174 166.8h5zM212.1 161.7h5zM212.1 164.3h5zM204.4 161.7h7.7zM204.4 164.3h7.7z"/>
<path d="M230.7 162.3h9.3zM240 161.7h10.2zM250.2 161.7h5zM250.2 164.3h5zM240 164.3h10.2zM400 173.7h3.8zM158.7 190.9v21.6zM158.7 190.9h111.8zM158.7 212.5h111.8zM270.5 190.9v21.6zM16.5 224.2h3.8zM400 224.2h3.8z"/>
<path d="M20.3 274.7h379.7zM67.8 274.7v3.8zM115.3 274.7v3.8zM162.7 274.7v3.8zM210.2 274.7v3.8zM257.6 274.7v3.8zM305.1 274.7v3.8zM352.5 274.7v3.8zM400 264.5v.1zM400 268.4v6.2zM400 274.6h.1zM400 22.1v252.6z"/>
<path d="M179.1 95.1l.6-.2v.3a.51 .51 0 0 0-.5 .5 .51 .51 0 0 0 .5 .5v.3a.77 .77 0 0 1-.7-.5 .77 .77 0 0 1 .1-.9z" fill-rule="evenodd"/>
<path d="M179.1 92.6l.6-.2v.2a.51 .51 0 0 0-.5 .6 .51 .51 0 0 0 .5 .5v.2a.76 .76 0 0 1-.7-.4 .76 .76 0 0 1 .1-.9z" fill-rule="evenodd"/>
<path d="M179.1 90.1l.6-.2v.2a.51 .51 0 0 0-.5 .5 .51 .51 0 0 0 .5 .5v.3a.76 .76 0 0 1-.7-.5 .76 .76 0 0 1 .1-.8z" fill-rule="evenodd"/>
<path d="M179.1 97.7l.6-.2v.2a.51 .51 0 0 0-.5 .5 .51 .51 0 0 0 .5 .5v.3a.77 .77 0 0 1-.7-.5 .77 .77 0 0 1 .1-.8z" fill-rule="evenodd"/>
<path d="M255.3 97.7l.6-.2v.2a.51 .51 0 0 0-.5 .5 .51 .51 0 0 0 .5 .5v.3a.76 .76 0 0 1-.7-.5 .76 .76 0 0 1 .1-.8z" fill-rule="evenodd"/>
<path d="M255.3 95.1l.6-.2v.3a.51 .51 0 0 0-.5 .5 .51 .51 0 0 0 .5 .5v.3a.76 .76 0 0 1-.7-.5 .76 .76 0 0 1 .1-.9z" fill-rule="evenodd"/>
<path d="M255.3 92.6l.6-.2v.2a.51 .51 0 0 0-.5 .6 .51 .51 0 0 0 .5 .5v.2a.75 .75 0 0 1-.7-.4 .75 .75 0 0 1 .1-.9z" fill-rule="evenodd"/>
<path d="M179.1 100.2l.6-.2v.3a.51 .51 0 0 0-.5 .5 .51 .51 0 0 0 .5 .5v.2a.77 .77 0 0 1-.7-.4 .77 .77 0 0 1 .1-.9z" fill-rule="evenodd"/>
<path d="M179.1 107.8l.6-.2v.3a.51 .51 0 0 0-.5 .5 .51 .51 0 0 0 .5 .5v.3a.77 .77 0 0 1-.7-.5 .77 .77 0 0 1 .1-.9z" fill-rule="evenodd"/>
<path d="M179.1 105.3l.6-.2v.2a.51 .51 0 0 0-.5 .6 .51 .51 0 0 0 .5 .5v.2a.77 .77 0 0 1-.7-.5 .77 .77 0 0 1 .1-.8z" fill-rule="evenodd"/>
<path d="M179.1 102.8l.6-.2v.2a.51 .51 0 0 0-.5 .5 .51 .51 0 0 0 .5 .5v.3a.77 .77 0 0 1-.7-.5 .77 .77 0 0 1 .1-.8z" fill-rule="evenodd"/>
<path d="M255.3 102.8l.6-.2v.2a.51 .51 0 0 0-.5 .5 .51 .51 0 0 0 .5 .5v.3a.76 .76 0 0 1-.7-.5 .76 .76 0 0 1 .1-.8z" fill-rule="evenodd"/>
<path d="M255.3 100.2l.6-.2v.3a.51 .51 0 0 0-.5 .5 .51 .51 0 0 0 .5 .5v.2a.76 .76 0 0 1-.7-.4 .76 .76 0 0 1 .1-.9z" fill-rule="evenodd"/>
<path d="M255.3 105.3l.6-.2v.2a.51 .51 0 0 0-.5 .6 .51 .51 0 0 0 .5 .5v.2a.76 .76 0 0 1-.7-.5 .76 .76 0 0 1 .1-.8z" fill-rule="evenodd"/>
<path d="M179.1 125.6l.6-.2v.3a.51 .51 0 0 0-.5 .5 .51 .51 0 0 0 .5 .5v.2a.77 .77 0 0 1-.7-.4 .77 .77 0 0 1 .1-.9z" fill-rule="evenodd"/>
<path d="M179.1 123.1l.6-.2v.2a.51 .51 0 0 0-.5 .5 .51 .51 0 0 0 .5 .5v.3a.77 .77 0 0 1-.7-.5 .77 .77 0 0 1 .1-.8z" fill-rule="evenodd"/>
<path d="M179.1 120.5l.6-.2v.3a.51 .51 0 0 0-.5 .5 .51 .51 0 0 0 .5 .5v.3a.77 .77 0 0 1-.7-.5 .77 .77 0 0 1 .1-.9z" fill-rule="evenodd"/>
<path d="M179.1 130.7l.6-.2v.2a.51 .51 0 0 0-.5 .6 .51 .51 0 0 0 .5 .5v.2a.77 .77 0 0 1-.7-.5 .77 .77 0 0 1 .1-.8z" fill-rule="evenodd"/>
<path d="M179.1 128.2l.6-.2v.2a.51 .51 0 0 0-.5 .5 .51 .51 0 0 0 .5 .5v.3a.77 .77 0 0 1-.7-.5 .77 .77 0 0 1 .1-.8z" fill-rule="evenodd"/>
<path d="M179.1 133.2l.6-.2v.3a.51 .51 0 0 0-.5 .5 .51 .51 0 0 0 .5 .5v.3a.77 .77 0 0 1-.7-.5 .77 .77 0 0 1 .1-.9z" fill-rule="evenodd"/>
<path d="M255.3 125.6l.6-.2v.3a.51 .51 0 0 0-.5 .5 .51 .51 0 0 0 .5 .5v.2a.76 .76 0 0 1-.7-.4 .76 .76 0 0 1 .1-.9z" fill-rule="evenodd"/>
<path d="M255.3 123.1l.6-.2v.2a.51 .51 0 0 0-.5 .5 .51 .51 0 0 0 .5 .5v.3a.76 .76 0 0 1-.7-.5 .76 .76 0 0 1 .1-.8z" fill-rule="evenodd"/>
<path d="M255.3 120.5l.6-.2v.3a.51 .51 0 0 0-.5 .5 .51 .51 0 0 0 .5 .5v.3a.76 .76 0 0 1-.7-.5 .76 .76 0 0 1 .1-.9z" fill-rule="evenodd"/>
<path d="M255.3 130.7l.6-.2v.2a.51 .51 0 0 0-.5 .6 .51 .51 0 0 0 .5 .5v.2a.76 .76 0 0 1-.7-.5 .76 .76 0 0 1 .1-.8z" fill-rule="evenodd"/>
<path d="M255.3 128.2l.6-.2v.2a.51 .51 0 0 0-.5 .5 .51 .51 0 0 0 .5 .5v.3a.76 .76 0 0 1-.7-.5 .76 .76 0 0 1 .1-.8z" fill-rule="evenodd"/>
<path d="M255.3 133.2l.6-.2v.3a.51 .51 0 0 0-.5 .5 .51 .51 0 0 0 .5 .5v.3a.76 .76 0 0 1-.7-.5 .76 .76 0 0 1 .1-.9z" fill-rule="evenodd"/>
<path d="M179.1 153.6l.6-.3v.3a.51 .51 0 0 0-.5 .5 .51 .51 0 0 0 .5 .5v.3a.78 .78 0 0 1-.7-.5 .78 .78 0 0 1 .1-.8z" fill-rule="evenodd"/>
<path d="M179.1 151l.6-.2v.3a.51 .51 0 0 0-.5 .5 .51 .51 0 0 0 .5 .5v.2a.78 .78 0 0 1-.7-.4 .78 .78 0 0 1 .1-.9z" fill-rule="evenodd"/>
<path d="M179.1 148.5l.6-.2v.2a.51 .51 0 0 0-.5 .5 .51 .51 0 0 0 .5 .5v.3a.78 .78 0 0 1-.7-.5 .78 .78 0 0 1 .1-.8z" fill-rule="evenodd"/>
<path d="M179.1 158.6l.6-.2v.3a.51 .51 0 0 0-.5 .5 .51 .51 0 0 0 .5 .5v.3a.78 .78 0 0 1-.7-.5 .78 .78 0 0 1 .1-.9z" fill-rule="evenodd"/>
<path d="M179.1 156.1l.6-.2v.2a.51 .51 0 0 0-.5 .6 .51 .51 0 0 0 .5 .5v.2a.78 .78 0 0 1-.7-.5 .78 .78 0 0 1 .1-.8z" fill-rule="evenodd"/>
<path d="M217.2 156.1l.6-.2v.2a.51 .51 0 0 0-.5 .6 .51 .51 0 0 0 .5 .5v.2a.78 .78 0 0 1-.7-.5 .78 .78 0 0 1 .1-.8z" fill-rule="evenodd"/>
<path d="M217.2 153.6l.6-.3v.3a.51 .51 0 0 0-.5 .5 .51 .51 0 0 0 .5 .5v.3a.78 .78 0 0 1-.7-.5 .78 .78 0 0 1 .1-.8z" fill-rule="evenodd"/>
<path d="M217.2 151l.6-.2v.3a.51 .51 0 0 0-.5 .5 .51 .51 0 0 0 .5 .5v.2a.78 .78 0 0 1-.7-.4 .78 .78 0 0 1 .1-.9z" fill-rule="evenodd"/>
<path d="M217.2 158.6l.6-.2v.3a.51 .51 0 0 0-.5 .5 .51 .51 0 0 0 .5 .5v.3a.78 .78 0 0 1-.7-.5 .78 .78 0 0 1 .1-.9z" fill-rule="evenodd"/>
<path d="M255.3 156.1l.6-.2v.2a.51 .51 0 0 0-.5 .6 .51 .51 0 0 0 .5 .5v.2a.77 .77 0 0 1-.7-.5 .77 .77 0 0 1 .1-.8z" fill-rule="evenodd"/>
<path d="M255.3 153.6l.6-.3v.3a.51 .51 0 0 0-.5 .5 .51 .51 0 0 0 .5 .5v.3a.77 .77 0 0 1-.7-.5 .77 .77 0 0 1 .1-.8z" fill-rule="evenodd"/>
<path d="M255.3 151l.6-.2v.3a.51 .51 0 0 0-.5 .5 .51 .51 0 0 0 .5 .5v.2a.77 .77 0 0 1-.7-.4 .77 .77 0 0 1 .1-.9z" fill-rule="evenodd"/>
<path d="M255.3 158.6l.6-.2v.3a.51 .51 0 0 0-.5 .5 .51 .51 0 0 0 .5 .5v.3a.77 .77 0 0 1-.7-.5 .77 .77 0 0 1 .1-.9z" fill-rule="evenodd"/>
<path d="M179.1 166.3l.6-.3v.3a.51 .51 0 0 0-.5 .5 .51 .51 0 0 0 .5 .5v.3a.78 .78 0 0 1-.7-.5 .78 .78 0 0 1 .1-.8z" fill-rule="evenodd"/>
<path d="M179.1 163.7l.6-.2v.3a.51 .51 0 0 0-.5 .5 .51 .51 0 0 0 .5 .5v.2a.78 .78 0 0 1-.7-.4 .78 .78 0 0 1 .1-.9z" fill-rule="evenodd"/>
<path d="M179.1 161.2l.6-.2v.2a.51 .51 0 0 0-.5 .5 .51 .51 0 0 0 .5 .5v.3a.78 .78 0 0 1-.7-.5 .78 .78 0 0 1 .1-.8z" fill-rule="evenodd"/>
<path d="M217.2 161.2l.6-.2v.2a.51 .51 0 0 0-.5 .5 .51 .51 0 0 0 .5 .5v.3a.78 .78 0 0 1-.7-.5 .78 .78 0 0 1 .1-.8z" fill-rule="evenodd"/>
<path d="M217.2 163.7l.6-.2v.3a.51 .51 0 0 0-.5 .5 .51 .51 0 0 0 .5 .5v.2a.78 .78 0 0 1-.7-.4 .78 .78 0 0 1 .1-.9z" fill-rule="evenodd"/>
<path d="M255.3 161.2l.6-.2v.2a.51 .51 0 0 0-.5 .5 .51 .51 0 0 0 .5 .5v.3a.77 .77 0 0 1-.7-.5 .77 .77 0 0 1 .1-.8z" fill-rule="evenodd"/>
<path d="M255.3 163.7l.6-.2v.3a.51 .51 0 0 0-.5 .5 .51 .51 0 0 0 .5 .5v.2a.77 .77 0 0 1-.7-.4 .77 .77 0 0 1 .1-.9z" fill-rule="evenodd"/>
</g>
<g fill="#000" stroke="#000" stroke-width=".42">
<path d="M177.8 88.1h5.1zM177.8 88.1v22.8zM254 90.6h5.1zM254 90.6v17.8zM177.8 118.6h5.1zM177.8 118.6v17.7zM182.9 88.1v22.8zM177.8 110.9h5.1zM254 118.6h5.1zM254 118.6v17.7zM259.1 90.6v17.8zM254 108.4h5.1z"/>
<path d="M182.9 118.6v17.7zM177.8 136.3h5.1zM259.1 118.6v17.7zM254 136.3h5.1zM177.8 146.5h5.1zM177.8 146.5v22.9zM215.9 149h5.1zM215.9 149v17.8zM254 149h5.1zM254 149v17.8zM182.9 146.5v22.9zM177.8 169.4h5.1z"/>
<path d="M221 149v17.8zM215.9 166.8h5.1zM259.1 149v17.8zM254 166.8h5.1z"/>
</g>
<path d="M16.5 18.2v260.3zM16.5 18.2h387.3zM16.5 278.5h387.3zM403.8 18.2v260.3z" fill="#000" stroke="#000" stroke-width=".32"/>
<g fill="#000" stroke="#000" stroke-width=".61">
<path d="M20.3 22.1v252.6zM20.3 22.1h379.7zM283.2 244.3v30.4zM313.7 254.4v5.1zM313.7 249.3v5.1zM313.7 244.3v5zM313.7 244.3h86.3zM283.2 244.3h30.5zM400 254.4v5.1zM400 249.3v5.1zM400 244.3v5zM400 22.1v222.2z"/>
<path d="M20.3 274.7h262.9zM283.2 274.7h30.5zM313.7 274.7h86.3zM313.7 269.7v5zM313.7 264.6v5.1zM313.7 259.5v5.1zM400 268.4v6.3zM400 264.6v3.8zM400 259.5v5.1z"/>
</g>
<path d="M313.7 249.3h86.3zM313.7 254.4h86.3zM313.7 259.5h58.4zM372.1 259.5h27.9zM372.1 259.5v5.1zM313.7 264.6h58.4zM313.7 269.7h86.3zM372.1 264.6h27.9zM400 268.4v1.3z" fill="#000" stroke="#000" stroke-width=".28"/>
<use href="#words"/>
</svg>
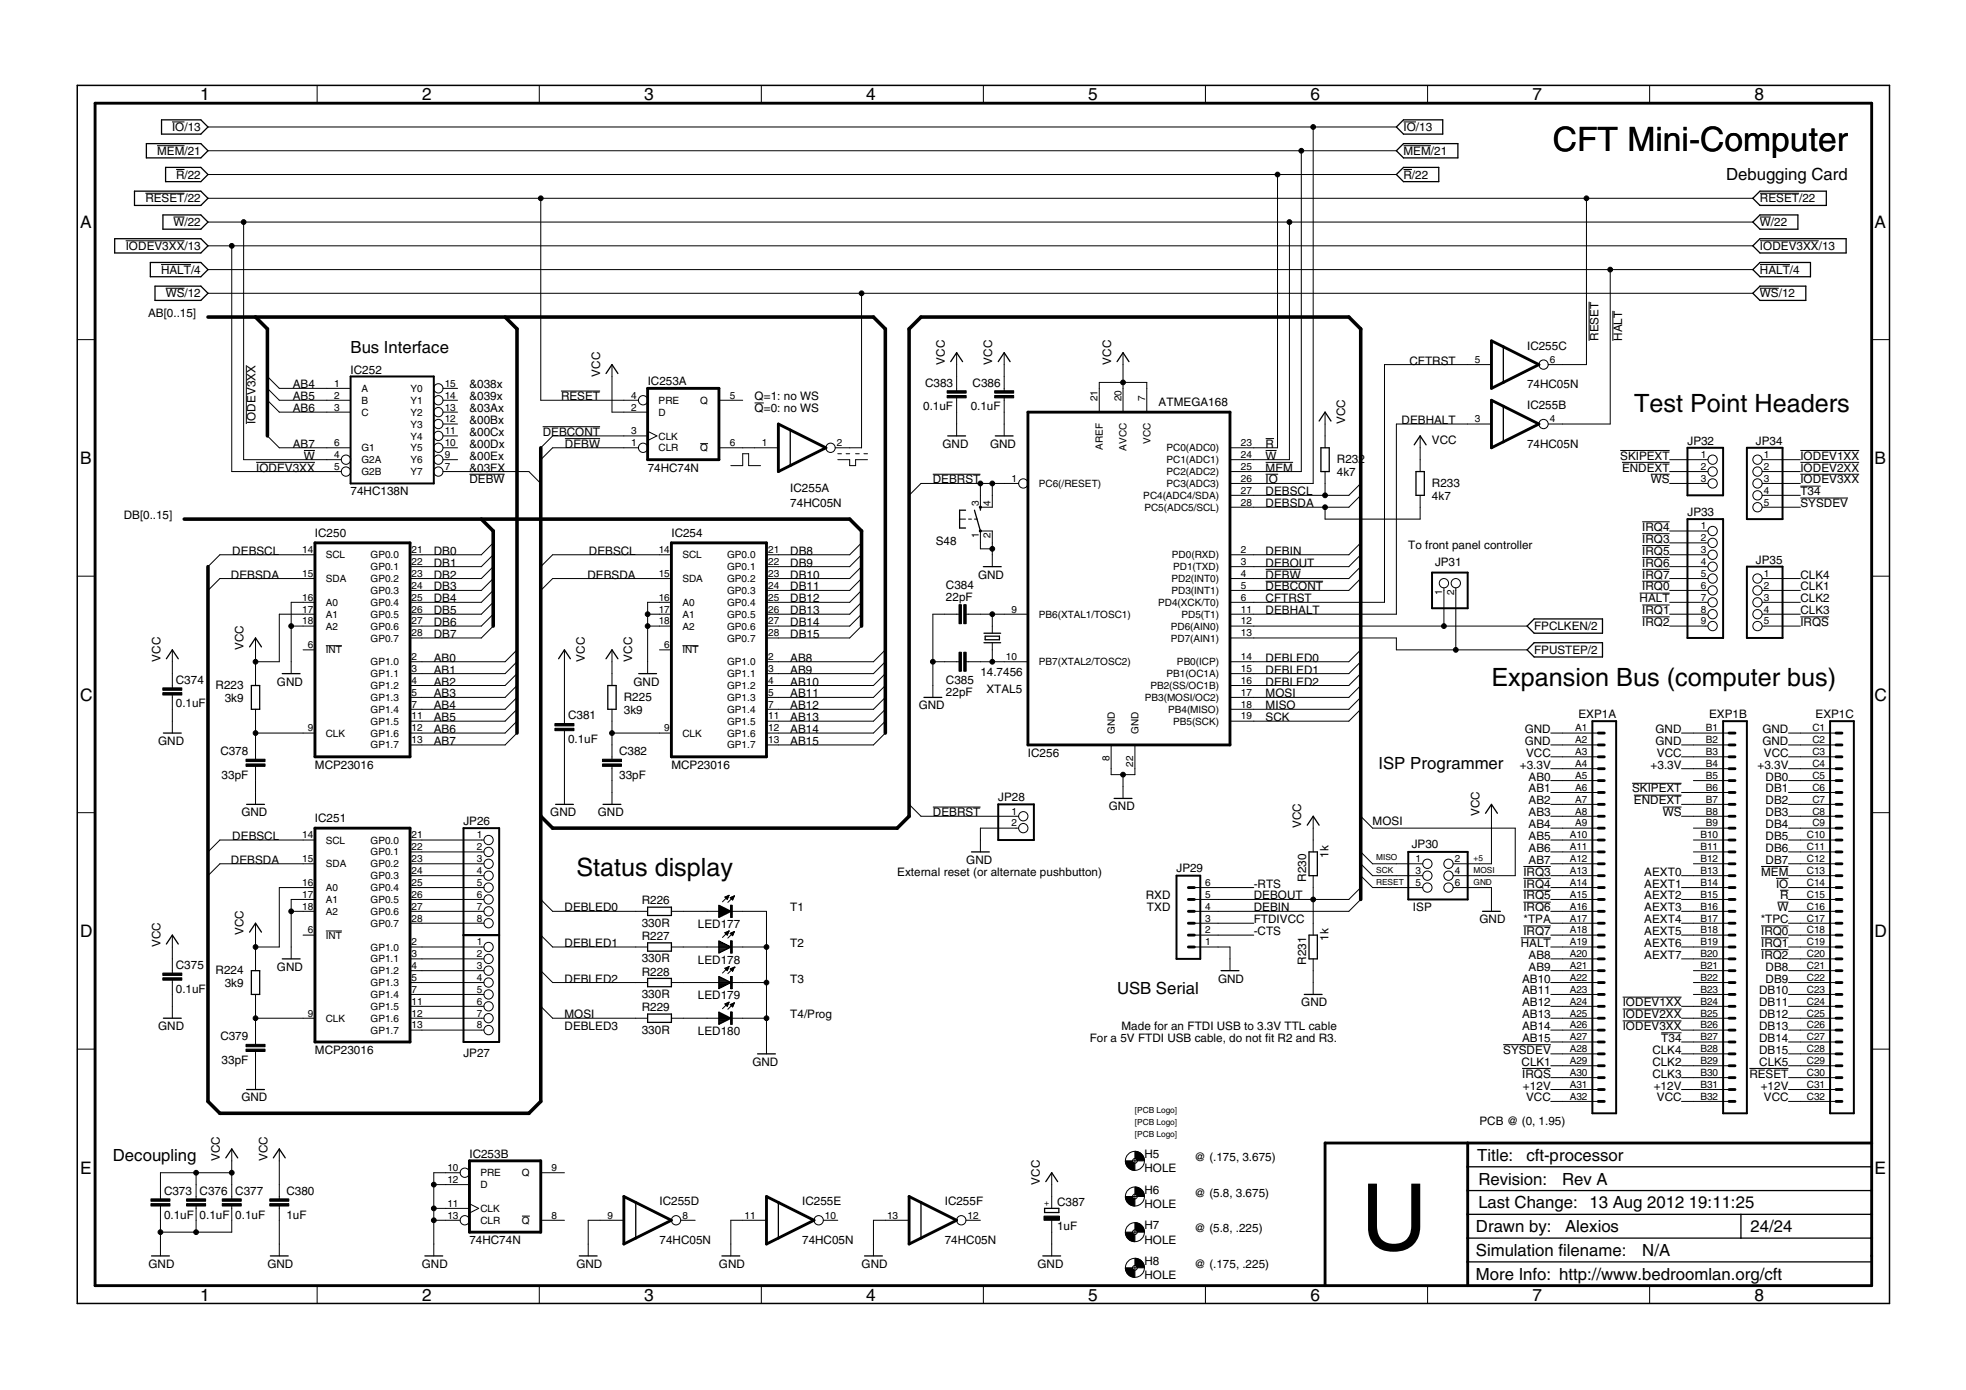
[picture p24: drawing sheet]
<svg xmlns="http://www.w3.org/2000/svg" width="420mm" height="297mm" viewBox="0 0 420 297" stroke-linecap="round" stroke-linejoin="round" font-family="sans-serif">
<defs><g id="words">
<text font-size="19.7" x="290.8" y="267.1">U</text>
<text font-size="7.2" x="331.8" y="32.2">CFT Mini-Computer</text>
<g font-size="5.4">
<text x="349.2" y="88.1">Test Point Headers</text>
<text x="318.7" y="146.5">Expansion Bus (computer bus)</text>
<text x="123.2" y="187.1">Status display</text>
</g>
<g font-size="3.7">
<text x="42.7" y="21.5">1</text>
<text x="90.2" y="21.5">2</text>
<text x="137.7" y="21.5">3</text>
<text x="185.1" y="21.5">4</text>
<text x="232.6" y="21.5">5</text>
<text x="280" y="21.5">6</text>
<text x="327.5" y="21.5">7</text>
<text x="375" y="21.5">8</text>
<text x="17.1" y="48.6">A</text>
<text x="400.6" y="48.6">A</text>
<text x="17.1" y="99.2">B</text>
<text x="400.6" y="99.2">B</text>
<text x="17.1" y="149.7">C</text>
<text x="400.6" y="149.7">C</text>
<text x="17.1" y="200.2">D</text>
<text x="400.6" y="200.2">D</text>
<text x="17.1" y="250.8">E</text>
<text x="400.6" y="250.8">E</text>
<text x="42.7" y="277.9">1</text>
<text x="90.2" y="277.9">2</text>
<text x="137.7" y="277.9">3</text>
<text x="185.1" y="277.9">4</text>
<text x="232.6" y="277.9">5</text>
<text x="280" y="277.9">6</text>
<text x="327.5" y="277.9">7</text>
<text x="375" y="277.9">8</text>
</g>
<g font-size="3.6">
<text x="368.9" y="38.6">Debugging Card</text>
<text x="74.9" y="75.4">Bus Interface</text>
<text x="294.6" y="164.3">ISP Programmer</text>
<text x="238.7" y="212.5">USB Serial</text>
<text x="24.1" y="248.1">Decoupling</text>
<text x="315.7" y="248.1">Title:</text>
<text x="326.2" y="248.2">cft-processor</text>
<text x="315.9" y="253.2">Revision:</text>
<text x="333.8" y="253.3">Rev A</text>
<text x="315.4" y="263.3">Drawn by:</text>
<text x="315.9" y="258.2">Last Change: 13 Aug 2012</text>
<text x="334.5" y="263.3">Alexios</text>
<text x="361" y="258.1">19:11:25</text>
<text x="374.1" y="263.2">24/24</text>
<text x="315.4" y="268.4">Simulation filename:</text>
<text x="351" y="268.4">N/A</text>
<text x="315.4" y="273.5">More Info: http://www.bedroomlan.org/cft</text>
</g>
<g font-size="2.5">
<text x="36.8" y="28">IO/13</text>
<text x="299.9" y="28">IO/13</text>
<text x="33.6" y="33.1">MEM/21</text>
<text x="299.9" y="33.1">MEM/21</text>
<text x="37.6" y="38.2">R/22</text>
<text x="299.9" y="38.2">R/22</text>
<text x="31.1" y="43.3">RESET/22</text>
<text x="376.1" y="43.3">RESET/22</text>
<text x="26.9" y="53.4">IODEV3XX/13</text>
<text x="37.1" y="48.3">W/22</text>
<text x="376.1" y="48.3">W/22</text>
<text x="376.1" y="53.4">IODEV3XX/13</text>
<text x="34.4" y="58.5">HALT/4</text>
<text x="376.1" y="58.5">HALT/4</text>
<text x="35.4" y="63.6">WS/12</text>
<text x="376.1" y="63.6">WS/12</text>
<text x="31.7" y="67.8">AB[0..15]</text>
<text x="201.9" y="77.9" transform="rotate(-90 201.9 77.9)">VCC</text>
<text x="212.1" y="77.9" transform="rotate(-90 212.1 77.9)">VCC</text>
<text x="237.5" y="77.9" transform="rotate(-90 237.5 77.9)">VCC</text>
<text x="301.2" y="77.9">CFTRST</text>
<text x="326.4" y="74.7">IC255C</text>
<text x="341.6" y="72.8" transform="rotate(-90 341.6 72.8)">RESET</text>
<text x="346.7" y="72.8" transform="rotate(-90 346.7 72.8)">HALT</text>
<text x="62.6" y="83">AB4</text>
<text x="74.9" y="79.8">IC252</text>
<text x="100.3" y="83">&amp;038x</text>
<text x="128.3" y="80.5" transform="rotate(-90 128.3 80.5)">VCC</text>
<text x="138.4" y="82.4">IC253A</text>
<text x="197.7" y="82.6">C383</text>
<text x="207.9" y="82.6">C386</text>
<text x="326.4" y="83">74HC05N</text>
<text x="62.6" y="88.1">AB6</text>
<text x="62.6" y="85.5">AB5</text>
<text x="100.3" y="85.5">&amp;039x</text>
<text x="100.3" y="88.1">&amp;03Ax</text>
<text x="119.9" y="85.5">RESET</text>
<text x="161.3" y="85.5">Q=1: no WS</text>
<text x="161.3" y="88.1">Q=0: no WS</text>
<text x="197.3" y="87.7">0.1uF</text>
<text x="207.5" y="87.7">0.1uF</text>
<text x="247.6" y="86.8">ATMEGA168</text>
<text x="326.4" y="87.4">IC255B</text>
<text x="54.6" y="90.6" transform="rotate(-90 54.6 90.6)">IODEV3XX</text>
<text x="62.6" y="95.7">AB7</text>
<text x="100.3" y="90.6">&amp;00Bx</text>
<text x="100.3" y="93.2">&amp;00Cx</text>
<text x="100.3" y="95.7">&amp;00Dx</text>
<text x="116" y="93.2">DEBCONT</text>
<text x="120.7" y="95.7">DEBW</text>
<text x="201.4" y="95.7">GND</text>
<text x="211.6" y="95.7">GND</text>
<text x="270.5" y="95.7">R</text>
<text x="287.5" y="90.6" transform="rotate(-90 287.5 90.6)">VCC</text>
<text x="299.5" y="90.6">DEBHALT</text>
<text x="306" y="94.9">VCC</text>
<text x="326.4" y="95.7">74HC05N</text>
<text x="360.6" y="95.1">JP32</text>
<text x="375.3" y="95.1">JP34</text>
<text x="54.7" y="100.8">IODEV3XX</text>
<text x="65" y="98.2">W</text>
<text x="100.3" y="98.2">&amp;00Ex</text>
<text x="100.3" y="100.8">&amp;03FX</text>
<text x="138.4" y="100.8">74HC74N</text>
<text x="270.5" y="100.8">MEM</text>
<text x="270.5" y="98.2">W</text>
<text x="285.7" y="101.8">4k7</text>
<text x="285.7" y="99">R232</text>
<text x="346.3" y="98.2">SKIPEXT</text>
<text x="346.6" y="100.8">ENDEXT</text>
<text x="384.8" y="100.8">IODEV2XX</text>
<text x="384.8" y="98.2">IODEV1XX</text>
<text x="74.9" y="105.9">74HC138N</text>
<text x="100.3" y="103.3">DEBW</text>
<text x="168.9" y="105.2">IC255A</text>
<text x="199.3" y="103.3">DEBRST</text>
<text x="270.5" y="103.3">IO</text>
<text x="270.5" y="105.9">DEBSCL</text>
<text x="306" y="106.9">4k7</text>
<text x="306" y="104.1">R233</text>
<text x="352.8" y="103.3">WS</text>
<text x="384.8" y="103.3">IODEV3XX</text>
<text x="384.8" y="105.9">T34</text>
<text x="26.4" y="110.9">DB[0..15]</text>
<text x="168.9" y="108.4">74HC05N</text>
<text x="270.5" y="108.4">DEBSDA</text>
<text x="351" y="113.5">IRQ4</text>
<text x="360.6" y="110.3">JP33</text>
<text x="384.8" y="108.4">SYSDEV</text>
<text x="49.7" y="118.6">DEBSCL</text>
<text x="67.3" y="114.7">IC250</text>
<text x="92.7" y="118.6">DB0</text>
<text x="125.8" y="118.6">DEBSCL</text>
<text x="143.5" y="114.7">IC254</text>
<text x="168.9" y="118.6">DB8</text>
<text x="200" y="116.5">S48</text>
<text x="270.5" y="118.6">DEBIN</text>
<text x="301" y="117.3">To front panel controller</text>
<text x="351" y="116">IRQ3</text>
<text x="351" y="118.6">IRQ5</text>
<text x="49.4" y="123.6">DEBSDA</text>
<text x="92.7" y="123.6">DB2</text>
<text x="92.7" y="121.1">DB1</text>
<text x="125.5" y="123.6">DEBSDA</text>
<text x="168.9" y="123.6">DB10</text>
<text x="168.9" y="121.1">DB9</text>
<text x="202.2" y="125.8">C384</text>
<text x="209" y="123.6">GND</text>
<text x="270.5" y="123.6">DEBW</text>
<text x="270.5" y="121.1">DEBOUT</text>
<text x="306.7" y="121">JP31</text>
<text x="351" y="123.6">IRQ7</text>
<text x="351" y="121.1">IRQ6</text>
<text x="375.3" y="120.5">JP35</text>
<text x="384.8" y="123.6">CLK4</text>
<text x="92.7" y="131.3">DB5</text>
<text x="92.7" y="128.7">DB4</text>
<text x="92.7" y="126.2">DB3</text>
<text x="168.9" y="131.3">DB13</text>
<text x="168.9" y="128.7">DB12</text>
<text x="168.9" y="126.2">DB11</text>
<text x="202.2" y="128.3">22pF</text>
<text x="270.5" y="126.2">DEBCONT</text>
<text x="270.5" y="128.7">CFTRST</text>
<text x="270.5" y="131.3">DEBHALT</text>
<text x="350.4" y="128.7">HALT</text>
<text x="351" y="126.2">IRQ0</text>
<text x="351" y="131.3">IRQ1</text>
<text x="384.8" y="128.7">CLK2</text>
<text x="384.8" y="131.3">CLK3</text>
<text x="384.8" y="126.2">CLK1</text>
<text x="92.7" y="136.3">DB7</text>
<text x="92.7" y="133.8">DB6</text>
<text x="168.9" y="136.3">DB15</text>
<text x="168.9" y="133.8">DB14</text>
<text x="327.9" y="134.7">FPCLKEN/2</text>
<text x="351" y="133.8">IRQ2</text>
<text x="384.8" y="133.8">IRQS</text>
<text x="34.3" y="141.4" transform="rotate(-90 34.3 141.4)">VCC</text>
<text x="52.1" y="138.9" transform="rotate(-90 52.1 138.9)">VCC</text>
<text x="92.7" y="144">AB1</text>
<text x="92.7" y="141.4">AB0</text>
<text x="125" y="141.4" transform="rotate(-90 125 141.4)">VCC</text>
<text x="135.1" y="141.4" transform="rotate(-90 135.1 141.4)">VCC</text>
<text x="168.9" y="144">AB9</text>
<text x="168.9" y="141.4">AB8</text>
<text x="270.5" y="141.4">DEBLED0</text>
<text x="270.5" y="144">DEBLED1</text>
<text x="327.9" y="139.8">FPUSTEP/2</text>
<text x="37.6" y="146.1">C374</text>
<text x="46.1" y="147.2">R223</text>
<text x="59.2" y="146.5">GND</text>
<text x="92.7" y="149">AB3</text>
<text x="92.7" y="146.5">AB2</text>
<text x="133.3" y="149.8">R225</text>
<text x="135.4" y="146.5">GND</text>
<text x="168.9" y="149">AB11</text>
<text x="168.9" y="146.5">AB10</text>
<text x="202.2" y="148.6">22pF</text>
<text x="202.2" y="146.1">C385</text>
<text x="209.5" y="144.5">14.7456</text>
<text x="210.8" y="148">XTAL5</text>
<text x="270.5" y="149">MOSI</text>
<text x="270.5" y="146.5">DEBLED2</text>
<text x="37.6" y="151.2">0.1uF</text>
<text x="48" y="150">3k9</text>
<text x="92.7" y="154.1">AB5</text>
<text x="92.7" y="151.6">AB4</text>
<text x="121.4" y="153.7">C381</text>
<text x="133.3" y="152.6">3k9</text>
<text x="168.9" y="154.1">AB13</text>
<text x="168.9" y="151.6">AB12</text>
<text x="196.3" y="151.6">GND</text>
<text x="270.5" y="151.6">MISO</text>
<text x="270.5" y="154.1">SCK</text>
<text x="337.3" y="153.3">EXP1A</text>
<text x="365.3" y="153.3">EXP1B</text>
<text x="388" y="153.3">EXP1C</text>
<text x="33.8" y="159.2">GND</text>
<text x="47.1" y="161.3">C378</text>
<text x="92.7" y="159.2">AB7</text>
<text x="92.7" y="156.6">AB6</text>
<text x="121.4" y="158.8">0.1uF</text>
<text x="132.3" y="161.3">C382</text>
<text x="168.9" y="159.2">AB15</text>
<text x="168.9" y="156.6">AB14</text>
<text x="219.7" y="161.7">IC256</text>
<text x="325.9" y="159.2">GND</text>
<text x="325.9" y="156.6">GND</text>
<text x="326.2" y="161.7">VCC</text>
<text x="353.8" y="159.2">GND</text>
<text x="353.8" y="156.6">GND</text>
<text x="354.1" y="161.7">VCC</text>
<text x="376.7" y="159.2">GND</text>
<text x="376.7" y="156.6">GND</text>
<text x="377" y="161.7">VCC</text>
<text x="47.4" y="166.4">33pF</text>
<text x="67.3" y="164.3">MCP23016</text>
<text x="132.3" y="166.4">33pF</text>
<text x="143.5" y="164.3">MCP23016</text>
<text x="324.8" y="164.3">+3.3V</text>
<text x="326.7" y="166.8">AB0</text>
<text x="352.7" y="164.3">+3.3V</text>
<text x="375.6" y="164.3">+3.3V</text>
<text x="377.3" y="166.8">DB0</text>
<text x="213.3" y="171.3">JP28</text>
<text x="237" y="173.2">GND</text>
<text x="326.7" y="171.9">AB2</text>
<text x="326.7" y="169.3">AB1</text>
<text x="348.8" y="169.3">SKIPEXT</text>
<text x="349.2" y="171.9">ENDEXT</text>
<text x="377.3" y="171.9">DB2</text>
<text x="377.3" y="169.3">DB1</text>
<text x="49.7" y="179.5">DEBSCL</text>
<text x="51.6" y="174.4">GND</text>
<text x="67.3" y="175.7">IC251</text>
<text x="99" y="176.3">JP26</text>
<text x="117.6" y="174.4">GND</text>
<text x="127.8" y="174.4">GND</text>
<text x="199.4" y="174.4">DEBRST</text>
<text x="278.1" y="177" transform="rotate(-90 278.1 177)">VCC</text>
<text x="293.3" y="176.2">MOSI</text>
<text x="316.2" y="174.4" transform="rotate(-90 316.2 174.4)">VCC</text>
<text x="326.7" y="179.5">AB5</text>
<text x="326.7" y="177">AB4</text>
<text x="326.7" y="174.4">AB3</text>
<text x="355.3" y="174.4">WS</text>
<text x="377.3" y="179.5">DB5</text>
<text x="377.3" y="177">DB4</text>
<text x="377.3" y="174.4">DB3</text>
<text x="49.4" y="184.6">DEBSDA</text>
<text x="206.5" y="184.6">GND</text>
<text x="283.9" y="183.3" transform="rotate(-90 283.9 183.3)">1k</text>
<text x="301.7" y="181.3">JP30</text>
<text x="326.7" y="184.6">AB7</text>
<text x="326.7" y="182">AB6</text>
<text x="377.3" y="184.6">DB7</text>
<text x="377.3" y="182">DB6</text>
<text x="191.7" y="187.1">External reset (or alternate pushbutton)</text>
<text x="251.4" y="186.4">JP29</text>
<text x="267.9" y="189.7">-RTS</text>
<text x="279.1" y="188.4" transform="rotate(-90 279.1 188.4)">R230</text>
<text x="325.6" y="187.1">IRQ3</text>
<text x="325.6" y="189.7">IRQ4</text>
<text x="351.4" y="189.7">AEXT1</text>
<text x="351.4" y="187.1">AEXT0</text>
<text x="376.4" y="187.1">MEM</text>
<text x="379.6" y="189.7">IO</text>
<text x="120.6" y="194.7">DEBLED0</text>
<text x="137.1" y="193.2">R226</text>
<text x="168.9" y="194.7">T1</text>
<text x="244.9" y="192.2">RXD</text>
<text x="245.1" y="194.7">TXD</text>
<text x="267.9" y="192.2">DEBOUT</text>
<text x="267.9" y="194.7">DEBIN</text>
<text x="267.9" y="197.3">FTDIVCC</text>
<text x="302" y="194.7">ISP</text>
<text x="316.2" y="197.3">GND</text>
<text x="325.6" y="192.2">IRQ5</text>
<text x="325.6" y="194.7">IRQ6</text>
<text x="325.6" y="197.3">*TPA</text>
<text x="351.4" y="197.3">AEXT4</text>
<text x="351.4" y="194.7">AEXT3</text>
<text x="351.4" y="192.2">AEXT2</text>
<text x="376.3" y="197.3">*TPC</text>
<text x="379.9" y="194.7">W</text>
<text x="380.4" y="192.2">R</text>
<text x="34.3" y="202.4" transform="rotate(-90 34.3 202.4)">VCC</text>
<text x="52.1" y="199.8" transform="rotate(-90 52.1 199.8)">VCC</text>
<text x="120.6" y="202.4">DEBLED1</text>
<text x="137.1" y="198">330R</text>
<text x="137.1" y="200.9">R227</text>
<text x="149.1" y="198.3">LED177</text>
<text x="168.9" y="202.4">T2</text>
<text x="267.9" y="199.8">-CTS</text>
<text x="283.9" y="201.1" transform="rotate(-90 283.9 201.1)">1k</text>
<text x="325" y="202.4">HALT</text>
<text x="325.6" y="199.8">IRQ7</text>
<text x="351.4" y="202.4">AEXT6</text>
<text x="351.4" y="199.8">AEXT5</text>
<text x="376.4" y="199.8">IRQ0</text>
<text x="376.4" y="202.4">IRQ1</text>
<text x="37.6" y="207.1">C375</text>
<text x="46.1" y="208.2">R224</text>
<text x="59.2" y="207.4">GND</text>
<text x="120.6" y="210">DEBLED2</text>
<text x="137.1" y="205.7">330R</text>
<text x="137.1" y="208.5">R228</text>
<text x="149.1" y="205.9">LED178</text>
<text x="168.9" y="210">T3</text>
<text x="260.3" y="210">GND</text>
<text x="279.1" y="206.2" transform="rotate(-90 279.1 206.2)">R231</text>
<text x="325.3" y="210">AB10</text>
<text x="326.7" y="207.4">AB9</text>
<text x="326.7" y="204.9">AB8</text>
<text x="351.4" y="204.9">AEXT7</text>
<text x="376.4" y="204.9">IRQ2</text>
<text x="377.3" y="210">DB9</text>
<text x="377.3" y="207.4">DB8</text>
<text x="37.6" y="212.1">0.1uF</text>
<text x="48" y="211">3k9</text>
<text x="137.1" y="213.3">330R</text>
<text x="149.1" y="213.5">LED179</text>
<text x="278.1" y="215.1">GND</text>
<text x="325.3" y="215.1">AB12</text>
<text x="325.3" y="212.5">AB11</text>
<text x="346.8" y="215.1">IODEV1XX</text>
<text x="375.9" y="215.1">DB11</text>
<text x="375.9" y="212.5">DB10</text>
<text x="33.8" y="220.1">GND</text>
<text x="120.6" y="217.6">MOSI</text>
<text x="120.6" y="220.1">DEBLED3</text>
<text x="137.1" y="220.9">330R</text>
<text x="137.1" y="216.1">R229</text>
<text x="149.1" y="221.2">LED180</text>
<text x="168.9" y="217.6">T4/Prog</text>
<text x="239.7" y="220.1">Made for an FTDI USB to 3.3V TTL cable</text>
<text x="325.3" y="220.1">AB14</text>
<text x="325.3" y="217.6">AB13</text>
<text x="346.8" y="220.1">IODEV3XX</text>
<text x="346.8" y="217.6">IODEV2XX</text>
<text x="375.9" y="220.1">DB13</text>
<text x="375.9" y="217.6">DB12</text>
<text x="47.1" y="222.3">C379</text>
<text x="47.4" y="227.4">33pF</text>
<text x="67.3" y="225.2">MCP23016</text>
<text x="99" y="225.9">JP27</text>
<text x="160.8" y="227.8">GND</text>
<text x="232.9" y="222.7">For a 5V FTDI USB cable, do not fit R2 and R3.</text>
<text x="321.2" y="225.2">SYSDEV</text>
<text x="325.2" y="227.8">CLK1</text>
<text x="325.3" y="222.7">AB15</text>
<text x="353.1" y="227.8">CLK2</text>
<text x="353.1" y="225.2">CLK4</text>
<text x="355" y="222.7">T34</text>
<text x="375.9" y="225.2">DB15</text>
<text x="375.9" y="222.7">DB14</text>
<text x="376" y="227.8">CLK5</text>
<text x="325.3" y="230.3">IRQS</text>
<text x="325.5" y="232.8">+12V</text>
<text x="353.1" y="230.3">CLK3</text>
<text x="353.4" y="232.8">+12V</text>
<text x="373.9" y="230.3">RESET</text>
<text x="376.3" y="232.8">+12V</text>
<text x="51.6" y="235.4">GND</text>
<text x="326.2" y="235.4">VCC</text>
<text x="354.1" y="235.4">VCC</text>
<text x="377" y="235.4">VCC</text>
<text x="316.2" y="240.5">PCB @ (0, 1.95)</text>
<text x="47" y="248.1" transform="rotate(-90 47 248.1)">VCC</text>
<text x="57.1" y="248.1" transform="rotate(-90 57.1 248.1)">VCC</text>
<text x="100.3" y="247.4">IC253B</text>
<text x="244.6" y="250.5">HOLE</text>
<text x="244.6" y="247.5">H5</text>
<text x="255.2" y="248.1">@ (.175, 3.675)</text>
<text x="35" y="255.3">C373</text>
<text x="42.7" y="255.3">C376</text>
<text x="50.3" y="255.3">C377</text>
<text x="61.2" y="255.3">C380</text>
<text x="141" y="257.6">IC255D</text>
<text x="171.4" y="257.6">IC255E</text>
<text x="201.9" y="257.6">IC255F</text>
<text x="222.2" y="253.2" transform="rotate(-90 222.2 253.2)">VCC</text>
<text x="225.9" y="257.7">C387</text>
<text x="244.6" y="255.1">H6</text>
<text x="255.2" y="255.7">@ (5.8, 3.675)</text>
<text x="35" y="260.4">0.1uF</text>
<text x="42.7" y="260.4">0.1uF</text>
<text x="50.3" y="260.4">0.1uF</text>
<text x="61.2" y="260.4">1uF</text>
<text x="225.9" y="262.8">1uF</text>
<text x="244.6" y="258.2">HOLE</text>
<text x="244.6" y="262.7">H7</text>
<text x="255.2" y="263.3">@ (5.8, .225)</text>
<text x="100.3" y="265.8">74HC74N</text>
<text x="141" y="265.8">74HC05N</text>
<text x="171.4" y="265.8">74HC05N</text>
<text x="201.9" y="265.8">74HC05N</text>
<text x="244.6" y="265.8">HOLE</text>
<text x="31.7" y="270.9">GND</text>
<text x="57.1" y="270.9">GND</text>
<text x="90.2" y="270.9">GND</text>
<text x="123.2" y="270.9">GND</text>
<text x="153.7" y="270.9">GND</text>
<text x="184.1" y="270.9">GND</text>
<text x="221.7" y="270.9">GND</text>
<text x="244.6" y="273.4">HOLE</text>
<text x="244.6" y="270.3">H8</text>
<text x="255.2" y="270.9">@ (.175, .225)</text>
</g>
<g font-size="2.1">
<text x="315.2" y="77.6">5</text>
<text x="331.2" y="77.6">6</text>
<text x="71.4" y="82.6">1</text>
<text x="77.3" y="83.8">A</text>
<text x="87.7" y="83.8">Y0</text>
<text x="95" y="82.6">15</text>
<text x="71.4" y="85.2">2</text>
<text x="71.4" y="87.7">3</text>
<text x="77.3" y="86.3">B</text>
<text x="77.3" y="88.8">C</text>
<text x="87.7" y="88.8">Y2</text>
<text x="87.7" y="86.3">Y1</text>
<text x="95" y="87.7">13</text>
<text x="95" y="85.2">14</text>
<text x="134.9" y="87.7">2</text>
<text x="134.9" y="85.2">4</text>
<text x="140.8" y="88.8">D</text>
<text x="140.8" y="86.3">PRE</text>
<text x="149.6" y="86.3">Q</text>
<text x="156" y="85.2">5</text>
<text x="234.6" y="85.7" transform="rotate(-90 234.6 85.7)">21</text>
<text x="239.6" y="85.7" transform="rotate(-90 239.6 85.7)">20</text>
<text x="244.7" y="85.7" transform="rotate(-90 244.7 85.7)">7</text>
<text x="71.4" y="95.3">6</text>
<text x="87.7" y="93.9">Y4</text>
<text x="87.7" y="91.4">Y3</text>
<text x="95" y="95.3">10</text>
<text x="95" y="92.8">11</text>
<text x="95" y="90.3">12</text>
<text x="134.9" y="95.3">1</text>
<text x="134.9" y="92.8">3</text>
<text x="140.8" y="93.9">CLK</text>
<text x="156" y="95.3">6</text>
<text x="162.8" y="95.3">1</text>
<text x="178.8" y="95.3">2</text>
<text x="245.8" y="94.9" transform="rotate(-90 245.8 94.9)">VCC</text>
<text x="265.2" y="95.3">23</text>
<text x="315.2" y="90.3">3</text>
<text x="331.2" y="90.3">4</text>
<text x="71.4" y="97.9">4</text>
<text x="71.4" y="100.4">5</text>
<text x="77.3" y="99">G2A</text>
<text x="77.3" y="101.5">G2B</text>
<text x="77.3" y="96.5">G1</text>
<text x="87.7" y="101.5">Y7</text>
<text x="87.7" y="99">Y6</text>
<text x="87.7" y="96.5">Y5</text>
<text x="95" y="100.4">7</text>
<text x="95" y="97.9">9</text>
<text x="140.8" y="96.5">CLR</text>
<text x="149.6" y="96.5">Q</text>
<text x="235.7" y="96.1" transform="rotate(-90 235.7 96.1)">AREF</text>
<text x="240.8" y="96.3" transform="rotate(-90 240.8 96.3)">AVCC</text>
<text x="249.3" y="101.5">PC2(ADC2)</text>
<text x="249.3" y="99">PC1(ADC1)</text>
<text x="249.3" y="96.5">PC0(ADC0)</text>
<text x="265.2" y="100.4">25</text>
<text x="265.2" y="97.9">24</text>
<text x="363.5" y="97.9">1</text>
<text x="363.5" y="100.4">2</text>
<text x="376.9" y="97.9">1</text>
<text x="376.9" y="100.4">2</text>
<text x="216.2" y="103">1</text>
<text x="222" y="104.1">PC6(/RESET)</text>
<text x="244.3" y="106.6">PC4(ADC4/SDA)</text>
<text x="249.3" y="104.1">PC3(ADC3)</text>
<text x="265.2" y="105.5">27</text>
<text x="265.2" y="103">26</text>
<text x="363.5" y="103">3</text>
<text x="376.9" y="103">3</text>
<text x="376.9" y="105.5">4</text>
<text x="209.2" y="108" transform="rotate(-90 209.2 108)">3</text>
<text x="211.7" y="108" transform="rotate(-90 211.7 108)">4</text>
<text x="244.6" y="109.2">PC5(ADC5/SCL)</text>
<text x="265.2" y="108">28</text>
<text x="363.5" y="113.1">1</text>
<text x="376.9" y="108">5</text>
<text x="64.6" y="118.2">14</text>
<text x="69.6" y="119.3">SCL</text>
<text x="79.2" y="119.3">GP0.0</text>
<text x="88" y="118.2">21</text>
<text x="140.8" y="118.2">14</text>
<text x="145.8" y="119.3">SCL</text>
<text x="155.4" y="119.3">GP0.0</text>
<text x="164.2" y="118.2">21</text>
<text x="209.2" y="115" transform="rotate(-90 209.2 115)">1</text>
<text x="211.7" y="115" transform="rotate(-90 211.7 115)">2</text>
<text x="250.4" y="119.3">PD0(RXD)</text>
<text x="265.2" y="118.2">2</text>
<text x="363.5" y="115.7">2</text>
<text x="363.5" y="118.2">3</text>
<text x="64.6" y="123.3">15</text>
<text x="69.6" y="124.4">SDA</text>
<text x="79.2" y="121.9">GP0.1</text>
<text x="79.2" y="124.4">GP0.2</text>
<text x="88" y="120.7">22</text>
<text x="88" y="123.3">23</text>
<text x="88" y="125.8">24</text>
<text x="140.8" y="123.3">15</text>
<text x="145.8" y="124.4">SDA</text>
<text x="155.4" y="121.9">GP0.1</text>
<text x="155.4" y="124.4">GP0.2</text>
<text x="164.2" y="120.7">22</text>
<text x="164.2" y="123.3">23</text>
<text x="164.2" y="125.8">24</text>
<text x="250.3" y="124.4">PD2(INT0)</text>
<text x="250.7" y="121.9">PD1(TXD)</text>
<text x="265.2" y="125.8">5</text>
<text x="265.2" y="123.3">4</text>
<text x="265.2" y="120.7">3</text>
<text x="363.5" y="120.7">4</text>
<text x="363.5" y="123.3">5</text>
<text x="363.5" y="125.8">6</text>
<text x="376.9" y="123.3">1</text>
<text x="376.9" y="125.8">2</text>
<text x="64.6" y="128.4">16</text>
<text x="64.6" y="130.9">17</text>
<text x="69.6" y="129.5">A0</text>
<text x="79.2" y="126.9">GP0.3</text>
<text x="79.2" y="129.5">GP0.4</text>
<text x="88" y="128.4">25</text>
<text x="88" y="130.9">26</text>
<text x="140.8" y="128.4">16</text>
<text x="140.8" y="130.9">17</text>
<text x="145.8" y="129.5">A0</text>
<text x="155.4" y="126.9">GP0.3</text>
<text x="155.4" y="129.5">GP0.4</text>
<text x="164.2" y="128.4">25</text>
<text x="164.2" y="130.9">26</text>
<text x="216.2" y="130.9">9</text>
<text x="247.5" y="129.5">PD4(XCK/T0)</text>
<text x="250.3" y="126.9">PD3(INT1)</text>
<text x="265.2" y="130.9">11</text>
<text x="265.2" y="128.4">6</text>
<text x="308.2" y="127.2" transform="rotate(-90 308.2 127.2)">1</text>
<text x="310.8" y="127.2" transform="rotate(-90 310.8 127.2)">2</text>
<text x="363.5" y="128.4">7</text>
<text x="363.5" y="130.9">8</text>
<text x="376.9" y="128.4">3</text>
<text x="376.9" y="130.9">4</text>
<text x="64.6" y="133.4">18</text>
<text x="69.6" y="132">A1</text>
<text x="69.6" y="134.6">A2</text>
<text x="79.2" y="132">GP0.5</text>
<text x="79.2" y="134.6">GP0.6</text>
<text x="79.2" y="137.1">GP0.7</text>
<text x="88" y="133.4">27</text>
<text x="88" y="136">28</text>
<text x="140.8" y="133.4">18</text>
<text x="145.8" y="132">A1</text>
<text x="145.8" y="134.6">A2</text>
<text x="155.4" y="132">GP0.5</text>
<text x="155.4" y="134.6">GP0.6</text>
<text x="155.4" y="137.1">GP0.7</text>
<text x="164.2" y="133.4">27</text>
<text x="164.2" y="136">28</text>
<text x="222" y="132">PB6(XTAL1/TOSC1)</text>
<text x="250.2" y="137.1">PD7(AIN1)</text>
<text x="250.2" y="134.6">PD6(AIN0)</text>
<text x="252.5" y="132">PD5(T1)</text>
<text x="265.2" y="136">13</text>
<text x="265.2" y="133.4">12</text>
<text x="363.5" y="133.4">9</text>
<text x="376.9" y="133.4">5</text>
<text x="65.8" y="138.5">6</text>
<text x="69.6" y="139.6">INT</text>
<text x="79.2" y="142.2">GP1.0</text>
<text x="88" y="141.1">2</text>
<text x="88" y="143.6">3</text>
<text x="142" y="138.5">6</text>
<text x="145.8" y="139.6">INT</text>
<text x="155.4" y="142.2">GP1.0</text>
<text x="164.2" y="141.1">2</text>
<text x="164.2" y="143.6">3</text>
<text x="215" y="141.1">10</text>
<text x="222" y="142.2">PB7(XTAL2/TOSC2)</text>
<text x="251.5" y="142.2">PB0(ICP)</text>
<text x="265.2" y="143.6">15</text>
<text x="265.2" y="141.1">14</text>
<text x="79.2" y="144.7">GP1.1</text>
<text x="79.2" y="147.3">GP1.2</text>
<text x="79.2" y="149.8">GP1.3</text>
<text x="88" y="146.1">4</text>
<text x="88" y="148.7">5</text>
<text x="155.4" y="144.7">GP1.1</text>
<text x="155.4" y="147.3">GP1.2</text>
<text x="155.4" y="149.8">GP1.3</text>
<text x="164.2" y="146.1">4</text>
<text x="164.2" y="148.7">5</text>
<text x="244.7" y="149.8">PB3(MOSI/OC2)</text>
<text x="245.9" y="147.3">PB2(SS/OC1B)</text>
<text x="249.3" y="144.7">PB1(OC1A)</text>
<text x="265.2" y="148.7">17</text>
<text x="265.2" y="146.1">16</text>
<text x="79.2" y="152.3">GP1.4</text>
<text x="79.2" y="154.9">GP1.5</text>
<text x="88" y="151.2">7</text>
<text x="88" y="153.8">11</text>
<text x="155.4" y="152.3">GP1.4</text>
<text x="155.4" y="154.9">GP1.5</text>
<text x="164.2" y="151.2">7</text>
<text x="164.2" y="153.8">11</text>
<text x="249.6" y="152.3">PB4(MISO)</text>
<text x="250.7" y="154.9">PB5(SCK)</text>
<text x="265.2" y="153.8">19</text>
<text x="265.2" y="151.2">18</text>
<text x="65.8" y="156.3">9</text>
<text x="69.6" y="157.4">CLK</text>
<text x="79.2" y="157.4">GP1.6</text>
<text x="79.2" y="160">GP1.7</text>
<text x="88" y="156.3">12</text>
<text x="88" y="158.8">13</text>
<text x="142" y="156.3">9</text>
<text x="145.8" y="157.4">CLK</text>
<text x="155.4" y="157.4">GP1.6</text>
<text x="155.4" y="160">GP1.7</text>
<text x="164.2" y="156.3">12</text>
<text x="164.2" y="158.8">13</text>
<text x="238.2" y="156.9" transform="rotate(-90 238.2 156.9)">GND</text>
<text x="243.3" y="156.9" transform="rotate(-90 243.3 156.9)">GND</text>
<text x="336.7" y="156.3">A1</text>
<text x="336.7" y="158.8">A2</text>
<text x="336.7" y="161.4">A3</text>
<text x="364.6" y="156.3">B1</text>
<text x="364.6" y="158.8">B2</text>
<text x="364.6" y="161.4">B3</text>
<text x="387.3" y="156.3">C1</text>
<text x="387.3" y="158.8">C2</text>
<text x="387.3" y="161.4">C3</text>
<text x="237.1" y="162.7" transform="rotate(-90 237.1 162.7)">8</text>
<text x="242.2" y="163.9" transform="rotate(-90 242.2 163.9)">22</text>
<text x="336.7" y="163.9">A4</text>
<text x="336.7" y="166.5">A5</text>
<text x="364.6" y="163.9">B4</text>
<text x="364.6" y="166.5">B5</text>
<text x="387.3" y="163.9">C4</text>
<text x="387.3" y="166.5">C5</text>
<text x="336.7" y="169">A6</text>
<text x="336.7" y="171.5">A7</text>
<text x="364.6" y="169">B6</text>
<text x="364.6" y="171.5">B7</text>
<text x="387.3" y="169">C6</text>
<text x="387.3" y="171.5">C7</text>
<text x="64.6" y="179.1">14</text>
<text x="88" y="179.1">21</text>
<text x="101.9" y="179.1">1</text>
<text x="216.2" y="174.1">1</text>
<text x="216.2" y="176.6">2</text>
<text x="335.5" y="179.1">A10</text>
<text x="336.7" y="174.1">A8</text>
<text x="336.7" y="176.6">A9</text>
<text x="363.4" y="179.1">B10</text>
<text x="364.6" y="174.1">B8</text>
<text x="364.6" y="176.6">B9</text>
<text x="386.2" y="179.1">C10</text>
<text x="387.3" y="174.1">C8</text>
<text x="387.3" y="176.6">C9</text>
<text x="64.6" y="184.2">15</text>
<text x="69.6" y="185.3">SDA</text>
<text x="69.6" y="180.3">SCL</text>
<text x="79.2" y="180.3">GP0.0</text>
<text x="79.2" y="182.8">GP0.1</text>
<text x="79.2" y="185.3">GP0.2</text>
<text x="88" y="181.7">22</text>
<text x="88" y="184.2">23</text>
<text x="101.9" y="181.7">2</text>
<text x="101.9" y="184.2">3</text>
<text x="302.5" y="184.2">1</text>
<text x="310.9" y="184.2">2</text>
<text x="335.5" y="181.7">A11</text>
<text x="335.5" y="184.2">A12</text>
<text x="363.4" y="181.7">B11</text>
<text x="363.4" y="184.2">B12</text>
<text x="386.2" y="181.7">C11</text>
<text x="386.2" y="184.2">C12</text>
<text x="64.6" y="189.3">16</text>
<text x="64.6" y="191.8">17</text>
<text x="69.6" y="190.4">A0</text>
<text x="79.2" y="187.9">GP0.3</text>
<text x="79.2" y="190.4">GP0.4</text>
<text x="88" y="186.8">24</text>
<text x="88" y="189.3">25</text>
<text x="88" y="191.8">26</text>
<text x="101.9" y="186.8">4</text>
<text x="101.9" y="189.3">5</text>
<text x="101.9" y="191.8">6</text>
<text x="257.6" y="191.8">5</text>
<text x="257.6" y="189.3">6</text>
<text x="302.5" y="186.8">3</text>
<text x="302.5" y="189.3">5</text>
<text x="310.9" y="186.8">4</text>
<text x="310.9" y="189.3">6</text>
<text x="335.5" y="186.8">A13</text>
<text x="335.5" y="189.3">A14</text>
<text x="335.5" y="191.8">A15</text>
<text x="363.4" y="186.8">B13</text>
<text x="363.4" y="189.3">B14</text>
<text x="363.4" y="191.8">B15</text>
<text x="386.2" y="186.8">C13</text>
<text x="386.2" y="189.3">C14</text>
<text x="386.2" y="191.8">C15</text>
<text x="64.6" y="194.4">18</text>
<text x="69.6" y="193">A1</text>
<text x="69.6" y="195.5">A2</text>
<text x="79.2" y="193">GP0.5</text>
<text x="79.2" y="195.5">GP0.6</text>
<text x="88" y="194.4">27</text>
<text x="88" y="196.9">28</text>
<text x="101.9" y="194.4">7</text>
<text x="101.9" y="196.9">8</text>
<text x="257.6" y="196.9">3</text>
<text x="257.6" y="194.4">4</text>
<text x="335.5" y="194.4">A16</text>
<text x="335.5" y="196.9">A17</text>
<text x="363.4" y="194.4">B16</text>
<text x="363.4" y="196.9">B17</text>
<text x="386.2" y="194.4">C16</text>
<text x="386.2" y="196.9">C17</text>
<text x="65.8" y="199.5">6</text>
<text x="69.6" y="200.6">INT</text>
<text x="79.2" y="203.1">GP1.0</text>
<text x="79.2" y="198">GP0.7</text>
<text x="88" y="202">2</text>
<text x="101.9" y="202">1</text>
<text x="257.6" y="202">1</text>
<text x="257.6" y="199.5">2</text>
<text x="335.5" y="199.5">A18</text>
<text x="335.5" y="202">A19</text>
<text x="363.4" y="199.5">B18</text>
<text x="363.4" y="202">B19</text>
<text x="386.2" y="199.5">C18</text>
<text x="386.2" y="202">C19</text>
<text x="79.2" y="205.7">GP1.1</text>
<text x="79.2" y="208.2">GP1.2</text>
<text x="88" y="204.5">3</text>
<text x="88" y="207.1">4</text>
<text x="88" y="209.6">5</text>
<text x="101.9" y="204.5">2</text>
<text x="101.9" y="207.1">3</text>
<text x="101.9" y="209.6">4</text>
<text x="335.5" y="204.5">A20</text>
<text x="335.5" y="207.1">A21</text>
<text x="335.5" y="209.6">A22</text>
<text x="363.4" y="204.5">B20</text>
<text x="363.4" y="207.1">B21</text>
<text x="363.4" y="209.6">B22</text>
<text x="386.2" y="204.5">C20</text>
<text x="386.2" y="207.1">C21</text>
<text x="386.2" y="209.6">C22</text>
<text x="79.2" y="210.7">GP1.3</text>
<text x="79.2" y="213.3">GP1.4</text>
<text x="79.2" y="215.8">GP1.5</text>
<text x="88" y="212.2">7</text>
<text x="88" y="214.7">11</text>
<text x="101.9" y="212.2">5</text>
<text x="101.9" y="214.7">6</text>
<text x="335.5" y="212.2">A23</text>
<text x="335.5" y="214.7">A24</text>
<text x="363.4" y="212.2">B23</text>
<text x="363.4" y="214.7">B24</text>
<text x="386.2" y="212.2">C23</text>
<text x="386.2" y="214.7">C24</text>
<text x="65.8" y="217.2">9</text>
<text x="69.6" y="218.4">CLK</text>
<text x="79.2" y="218.4">GP1.6</text>
<text x="79.2" y="220.9">GP1.7</text>
<text x="88" y="217.2">12</text>
<text x="88" y="219.8">13</text>
<text x="101.9" y="217.2">7</text>
<text x="101.9" y="219.8">8</text>
<text x="335.5" y="217.2">A25</text>
<text x="335.5" y="219.8">A26</text>
<text x="363.4" y="217.2">B25</text>
<text x="363.4" y="219.8">B26</text>
<text x="386.2" y="217.2">C25</text>
<text x="386.2" y="219.8">C26</text>
<text x="335.5" y="222.3">A27</text>
<text x="335.5" y="224.9">A28</text>
<text x="335.5" y="227.4">A29</text>
<text x="363.4" y="222.3">B27</text>
<text x="363.4" y="224.9">B28</text>
<text x="363.4" y="227.4">B29</text>
<text x="386.2" y="222.3">C27</text>
<text x="386.2" y="224.9">C28</text>
<text x="386.2" y="227.4">C29</text>
<text x="335.5" y="229.9">A30</text>
<text x="335.5" y="232.5">A31</text>
<text x="363.4" y="229.9">B30</text>
<text x="363.4" y="232.5">B31</text>
<text x="386.2" y="229.9">C30</text>
<text x="386.2" y="232.5">C31</text>
<text x="335.5" y="235">A32</text>
<text x="363.4" y="235">B32</text>
<text x="386.2" y="235">C32</text>
<text x="95.6" y="250.3">10</text>
<text x="102.7" y="251.4">PRE</text>
<text x="111.5" y="251.4">Q</text>
<text x="117.9" y="250.3">9</text>
<text x="95.6" y="252.8">12</text>
<text x="95.6" y="257.9">11</text>
<text x="102.7" y="253.9">D</text>
<text x="95.6" y="260.4">13</text>
<text x="102.7" y="261.5">CLR</text>
<text x="102.7" y="259">CLK</text>
<text x="111.5" y="261.5">Q</text>
<text x="117.9" y="260.4">8</text>
<text x="129.8" y="260.4">9</text>
<text x="145.8" y="260.4">8</text>
<text x="159.1" y="260.4">11</text>
<text x="176.3" y="260.4">10</text>
<text x="189.6" y="260.4">13</text>
<text x="206.8" y="260.4">12</text>
</g>
<g font-size="1.8">
<text x="294.1" y="183.8">MISO</text>
<text x="314.9" y="184.1">+5</text>
<text x="294.1" y="189.2">RESET</text>
<text x="294.1" y="186.6">SCK</text>
<text x="314.9" y="186.5">MOSI</text>
<text x="314.9" y="189.2">GND</text>
<text x="242.5" y="237.9">[PCB Logo]</text>
<text x="242.5" y="243">[PCB Logo]</text>
<text x="242.5" y="240.5">[PCB Logo]</text>
<text x="224.2" y="257.8" transform="rotate(-90 224.2 257.8)">+</text>
</g>
</g></defs>
<g fill="#000" stroke="#000" stroke-width=".21">
<path d="M67.8 18.2v3.9zM115.3 18.2v3.9zM162.7 18.2v3.9zM210.2 18.2v3.9zM257.6 18.2v3.9zM305.1 18.2v3.9zM352.5 18.2v3.9zM20.3 22.1v252.6zM33.6 31.1h5.8zM36.8 26.1h2.6zM37.6 36.2h1.8zM44.4 32.2h233.7z"/>
<path d="M44.4 37.3h228.6zM273 37.3v58.4zM273 37.3h25.4zM278.1 32.2h20.3zM44.4 27.1h236.2zM280.6 27.1h17.8zM299.9 31.1h5.9zM299.9 26.1h2.7zM299.9 36.2h1.8zM20.3 22.1h379.7zM26.9 51.5h12.5zM31.1 41.3h8.3z"/>
<path d="M34.4 56.5h6.4zM37.1 46.4h2.3zM44.4 47.5h7.7zM44.4 52.5h5.1zM49.5 52.5h325.1zM49.5 52.5v48.3zM52.1 47.5h223.5zM52.1 47.5v50.7zM44.4 42.4h71.2zM275.6 47.5h99zM115.6 42.4h223.4zM44.4 57.6h299.7z"/>
<path d="M344.1 57.6h30.5zM339 42.4h35.6zM376.1 46.4h2.4zM376.1 56.5h6.4zM376.1 41.3h8.4zM376.1 51.5h12.6zM16.5 72.6h3.8zM35.4 61.6h4zM44.4 62.7h139.7zM184.1 62.7h190.5zM204.4 75.4v2.5zM204.4 77.9v2.6z"/>
<path d="M214.6 75.4v2.5zM214.6 77.9v2.6zM240 75.4v2.5zM295.9 77.9h17.8zM313.7 77.9h5zM330.9 77.9h3.1zM334 77.9h5zM339 42.4v35.5zM339.6 64.5v8.3zM344.7 66.4v6.4zM376.1 61.6h4zM400 72.6h3.8z"/>
<path d="M52.6 78v12.6zM54.7 98.8h12.6zM57.1 85.5l2.6 2.6zM57.1 83l2.6 2.5zM57.1 80.5l2.6 2.5zM57.1 93.2l2.6 2.5zM59.7 88.1h10.1zM59.7 85.5h10.1zM59.7 83h10.1zM65 96.3h2.3zM69.8 83h5.1zM69.8 85.5h5.1z"/>
<path d="M69.8 88.1h5.1zM69.8 98.2h3.1zM69.8 95.7h5.1zM52.1 98.2h17.7zM59.7 95.7h10.1zM94.7 98.2h3.1zM94.7 95.7h3.1zM94.7 93.2h3.1zM94.7 90.6h3.1zM94.7 88.1h3.1zM94.7 85.5h3.1zM94.7 83h3.1z"/>
<path d="M115.6 42.4v43.1zM116 91.2h12.2zM118.1 93.2l-2.5 2.5zM118.1 95.7l-2.5 2.5zM119.9 83.6h8.3zM120.7 93.7h7.5zM130.8 77.9v2.6zM130.8 80.5v7.6zM130.8 88.1h2.5zM133.3 95.7h3.1zM133.3 88.1h5.1zM133.3 93.2h5.1z"/>
<path d="M133.3 85.5h3.1zM115.6 85.5h17.7zM118.1 93.2h15.2zM118.1 95.7h15.2zM138.4 92.2l2 1zM138.4 94.1l2-.9zM149.6 94.8h1.7zM156.2 99.5h2.5zM158.7 97v2.5zM158.7 97h1.3zM153.6 85.5h5.1zM153.6 95.7h5.1z"/>
<path d="M158.7 95.7h2.6zM160 97v2.5zM160 99.5h2.5zM161.3 86.1h1.9zM161.3 95.7h5zM179 98.2h2.6zM179 97h.8zM180.8 97h.8zM181.6 98.2v1.3zM181.6 99.5h1.3zM178.5 95.7h3.1zM181.6 95.7h2.5z"/>
<path d="M182.9 98.2v1.3zM182.9 98.2h2.5zM182.9 97h.7zM184.1 62.7v33zM184.6 97h.8zM204.4 85.5v2.6zM204.4 80.5v2.5zM204.4 85v.5zM204.4 83v.5zM204.4 90.6v2.6zM204.4 88.1v2.5zM214.6 85.5v2.6z"/>
<path d="M214.6 80.5v2.5zM214.6 85v.5zM214.6 83v.5zM214.6 90.6v2.6zM214.6 88.1v2.5zM234.9 83v5.1zM234.9 81.7v1.3zM234.9 81.7h5.1zM240 83v5.1zM240 81.7h5.1zM240 81.7v1.3zM240 77.9v3.8z"/>
<path d="M245.1 83v5.1zM245.1 81.7v1.3zM262.9 98.2h5zM262.9 95.7h5zM267.9 98.2h7.7zM270.5 98.8h5.8zM270.5 93.7h1.8zM270.5 96.3h2.3zM267.9 95.7h5.1zM275.6 47.5v50.7zM283.2 93.2v2.5zM283.2 88.1v2.5z"/>
<path d="M283.2 90.6v2.6zM298.4 90.6h15.3zM303.5 98.2v2.6zM303.5 93.2v2.5zM303.5 95.7v2.5zM313.7 90.6h5zM330.9 90.6h3.1zM334 90.6h10.1zM344.1 57.6v33zM346.3 96.3h10.5zM346.6 98.8h10.2zM364.4 98.2h.6z"/>
<path d="M356.8 98.2h7.6zM376.6 98.2h.5zM377.1 98.2h7.7zM384.8 98.8h12.5zM384.8 96.3h12.5zM47 118.6l-2.6 2.5zM49.5 100.8h20.3zM64.8 118.6h2.5zM47 118.6h17.8zM69.8 100.8h3.1zM87.6 118.6h2.6zM90.2 118.6h12.7z"/>
<path d="M94.7 100.8h3.1zM97.8 100.8h15.2zM100.3 101.3h7.5zM102.9 118.6l2.5-2.6zM113 100.8l2.6 2.5zM118.1 118.6l-2.5 2.5zM140.9 118.6h2.6zM118.1 118.6h22.8zM163.8 118.6h2.5zM166.3 118.6h15.3zM184.1 118.6l-2.5 2.5zM181.6 118.6l2.5-2.6z"/>
<path d="M196.8 103.3l-2.5 2.6zM199.3 101.3h10.2zM205.1 110.9h1.3zM207 110.9h.6zM208.3 110.9h.6zM209.5 113.5v2.5zM209.5 105.9v2.5zM209.5 116v1.3zM209.5 117.3h2.6zM196.8 103.3h12.7zM209.5 103.3v2.6zM212.1 105.9v2.5z"/>
<path d="M212.1 113.5v2.5zM209.5 108.4h2.6zM209.5 113.5h2.6zM212.1 118.6v2.5zM212.1 117.3v1.3zM212.1 116v1.3zM209.5 103.3h2.6zM212.1 103.3v2.6zM214.6 103.3h3.1zM212.1 103.3h2.5zM262.9 118.6h5zM262.9 108.4h5z"/>
<path d="M262.9 105.9h5zM262.9 103.3h5zM262.9 100.8h5zM267.9 100.8h10.2zM267.9 103.3h12.7zM267.9 105.9h15.3zM267.9 108.4h15.3zM267.9 118.6h20.4zM270.5 101.3h2.7zM278.1 32.2v68.6zM280.6 27.1v76.2zM283.2 100.8v2.5z"/>
<path d="M283.2 105.9h5.1zM283.2 103.3v2.6zM283.2 108.4h5.1zM283.2 108.4v2.5zM283.2 110.9h20.3zM288.3 105.9l2.5-2.6zM288.3 108.4l2.5-2.5zM288.3 118.6l2.5-2.6zM303.5 105.9v2.5zM303.5 108.4v2.5zM351 114h5.8zM351 111.5h5.8z"/>
<path d="M351 116.6h5.8zM351 119.1h5.8zM352.8 101.3h4zM364.4 100.8h.6zM364.4 103.3h.6zM364.4 113.5h.6zM364.4 116h.6zM364.4 118.6h.6zM356.8 116h7.6zM356.8 113.5h7.6zM356.8 118.6h7.6zM356.8 100.8h7.6z"/>
<path d="M356.8 103.3h7.6zM376.6 100.8h.5zM376.6 103.3h.5zM376.6 105.9h.5zM376.6 108.4h.5zM377.1 108.4h7.7zM377.1 103.3h7.7zM377.1 100.8h7.7zM384.8 106.4h10.1zM384.8 101.3h12.5zM384.8 103.9h4.3zM377.1 105.9h7.7z"/>
<path d="M16.5 123.1h3.8zM47 123.6l-2.6 2.6zM54.6 136.3v2.6zM54.6 138.9v2.5zM62.2 133.8v7.6zM62.2 128.7v5.1zM62.2 128.7h2.6zM64.8 123.6h2.5zM64.8 138.9h2.5zM64.8 128.7h2.5zM64.8 131.3h2.5zM64.8 133.8h2.5z"/>
<path d="M62.2 133.8h2.6zM59.7 131.3h5.1zM47 123.6h17.8zM69.6 138h3.5zM87.6 121.1h2.6zM87.6 123.6h2.6zM87.6 126.2h2.6zM87.6 128.7h2.6zM87.6 131.3h2.6zM87.6 133.8h2.6zM87.6 136.3h2.6zM90.2 136.3h12.7z"/>
<path d="M90.2 133.8h12.7zM90.2 131.3h12.7zM90.2 128.7h12.7zM90.2 126.2h12.7zM90.2 123.6h12.7zM90.2 121.1h12.7zM102.9 136.3l2.5-2.5zM102.9 133.8l2.5-2.5zM102.9 131.3l2.5-2.6zM102.9 128.7l2.5-2.5zM102.9 126.2l2.5-2.6zM102.9 123.6l2.5-2.5z"/>
<path d="M102.9 121.1l2.5-2.5zM118.1 123.6l-2.5 2.6zM138.4 128.7v2.6zM138.4 131.3v2.5zM138.4 133.8v7.6zM140.9 123.6h2.6zM140.9 138.9h2.6zM140.9 128.7h2.6zM140.9 131.3h2.6zM140.9 133.8h2.6zM138.4 128.7h2.5zM138.4 131.3h2.5z"/>
<path d="M138.4 133.8h2.5zM118.1 123.6h22.8zM145.8 138h3.5zM163.8 121.1h2.5zM163.8 123.6h2.5zM163.8 126.2h2.5zM163.8 128.7h2.5zM163.8 131.3h2.5zM163.8 133.8h2.5zM163.8 136.3h2.5zM166.3 136.3h15.3zM166.3 133.8h15.3z"/>
<path d="M166.3 131.3h15.3zM166.3 128.7h15.3zM166.3 126.2h15.3zM166.3 123.6h15.3zM166.3 121.1h15.3zM184.1 133.8l-2.5 2.5zM184.1 131.3l-2.5 2.5zM181.6 131.3l2.5-2.6zM184.1 126.2l-2.5 2.5zM181.6 126.2l2.5-2.6zM184.1 121.1l-2.5 2.5zM199.4 131.3v10.1z"/>
<path d="M201.9 131.3h2.5zM199.4 131.3h2.5zM204.4 131.3h.6zM206.5 131.3h.5zM207 131.3h2.5zM212.1 137.3v1.6zM212.1 133.8v1.5zM212.1 131.3v2.5zM209.5 131.3h2.6zM212.1 138.9v2.5zM214.6 131.3h5.1zM212.1 131.3h2.5z"/>
<path d="M262.9 136.3h5zM262.9 133.8h5zM262.9 131.3h5zM262.9 128.7h5zM262.9 126.2h5zM262.9 123.6h5zM262.9 121.1h5zM267.9 126.2h20.4zM267.9 123.6h20.4zM267.9 121.1h20.4zM267.9 128.7h28zM267.9 131.3h30.5z"/>
<path d="M267.9 133.8h40.7zM267.9 136.3h30.5zM270.5 124.2h12.3zM270.5 121.7h7.5zM288.3 126.2l2.5-2.6zM288.3 123.6l2.5-2.5zM288.3 121.1l2.5-2.5zM295.9 77.9v50.8zM298.4 90.6v40.7zM298.4 136.3v2.6zM298.4 138.9h12.7zM308.6 125.6v.6z"/>
<path d="M308.6 133.8h17.8zM308.6 126.2v7.6zM311.1 125.6v.6zM311.1 138.9h15.3zM311.1 126.2v12.7zM350.4 126.7h6.4zM351 124.2h5.8zM351 131.8h5.8zM351 129.3h5.8zM351 121.7h5.8zM364.4 121.1h.6zM364.4 123.6h.6z"/>
<path d="M364.4 126.2h.6zM364.4 128.7h.6zM364.4 131.3h.6zM364.4 133.8h.6zM356.8 128.7h7.6zM356.8 126.2h7.6zM356.8 133.8h7.6zM356.8 131.3h7.6zM356.8 123.6h7.6zM356.8 121.1h7.6zM376.6 123.6h.5zM376.6 126.2h.5z"/>
<path d="M376.6 128.7h.5zM376.6 131.3h.5zM376.6 133.8h.5zM377.1 131.3h7.7zM377.1 123.6h7.7zM377.1 126.2h7.7zM377.1 133.8h7.7zM384.8 131.8h6.1zM377.1 128.7h7.7zM400 123.1h3.8zM36.8 149v2.6zM36.8 144v2.5z"/>
<path d="M36.8 148.5v.5zM36.8 146.5v.5zM36.8 138.9v2.5zM36.8 154.1v2.6zM36.8 151.6v2.5zM36.8 141.4v2.6zM54.6 151.6v2.5zM54.6 144v2.5zM54.6 159.2v2.5zM54.6 141.4h5.1zM54.6 141.4v2.6zM54.6 154.1v2.6z"/>
<path d="M54.6 156.7v2.5zM59.7 131.3v10.1zM62.2 141.4v2.6zM64.8 156.7h2.5zM54.6 156.7h10.2zM87.6 141.4h2.6zM87.6 144h2.6zM87.6 146.5h2.6zM87.6 149h2.6zM87.6 151.6h2.6zM87.6 154.1h2.6zM87.6 156.7h2.6z"/>
<path d="M87.6 159.2h2.6zM90.2 159.2h17.7zM90.2 156.7h17.7zM90.2 154.1h17.7zM90.2 151.6h17.7zM90.2 149h17.7zM90.2 146.5h17.7zM90.2 144h17.7zM90.2 141.4h17.7zM107.9 159.2l2.6-2.5zM110.5 154.1l-2.6 2.6zM107.9 154.1l2.6-2.5z"/>
<path d="M107.9 151.6l2.6-2.6zM110.5 146.5l-2.6 2.5zM107.9 146.5l2.6-2.5zM107.9 144l2.6-2.6zM110.5 138.9l-2.6 2.5zM120.6 156.7v2.5zM120.6 151.6v2.5zM120.6 156.1v.6zM120.6 154.1v.5zM120.6 138.9v2.5zM120.6 141.4v10.2zM130.8 151.6v2.5z"/>
<path d="M130.8 144v2.5zM130.8 159.2v2.5zM130.8 138.9v2.5zM130.8 141.4v2.6zM130.8 154.1v2.6zM130.8 156.7v2.5zM138.4 141.4v2.6zM140.9 156.7h2.6zM130.8 156.7h10.1zM163.8 141.4h2.5zM163.8 144h2.5zM163.8 146.5h2.5z"/>
<path d="M163.8 149h2.5zM163.8 151.6h2.5zM163.8 154.1h2.5zM163.8 156.7h2.5zM163.8 159.2h2.5zM166.3 159.2h20.4zM166.3 156.7h20.4zM166.3 154.1h20.4zM166.3 151.6h20.4zM166.3 149h20.4zM166.3 146.5h20.4zM166.3 144h20.4z"/>
<path d="M166.3 141.4h20.4zM186.7 159.2l2.5-2.5zM189.2 154.1l-2.5 2.6zM186.7 154.1l2.5-2.5zM186.7 151.6l2.5-2.6zM189.2 146.5l-2.5 2.5zM186.7 146.5l2.5-2.5zM186.7 144l2.5-2.6zM189.2 138.9l-2.5 2.5zM199.4 146.5v2.5zM199.4 141.4v5.1zM201.9 141.4h2.5z"/>
<path d="M199.4 141.4h2.5zM204.4 141.4h.6zM206.5 141.4h.5zM207 141.4h2.5zM212.1 141.4h2.5zM209.5 141.4h2.6zM214.6 141.4h5.1zM262.9 154.1h5zM262.9 151.6h5zM262.9 149h5zM262.9 146.5h5zM262.9 144h5z"/>
<path d="M262.9 141.4h5zM267.9 151.6h20.4zM267.9 154.1h20.4zM267.9 149h20.4zM267.9 141.4h20.4zM267.9 144h20.4zM267.9 146.5h20.4zM288.3 151.6l2.5-2.6zM288.3 154.1l2.5-2.5zM288.3 149l2.5-2.5zM288.3 141.4l2.5-2.5zM288.3 144l2.5-2.6z"/>
<path d="M288.3 146.5l2.5-2.5zM334 156.7h7.6zM334 159.2h7.6zM331.4 159.2h2.6zM331.4 156.7h2.6zM361.9 156.7h7.6zM361.9 159.2h7.6zM359.4 159.2h2.5zM359.4 156.7h2.5zM384.8 156.7h7.6zM384.8 159.2h7.6zM382.2 159.2h2.6z"/>
<path d="M382.2 156.7h2.6zM16.5 173.7h3.8zM47 179.5l-2.6 2.6zM54.6 164.3v2.5zM54.6 161.7v.5zM54.6 163.8v.5zM54.6 169.4v2.5zM54.6 166.8v2.6zM64.8 179.5h2.5zM47 179.5h17.8zM87.6 179.5h2.6zM102.9 179.5h.5z"/>
<path d="M90.2 179.5h12.7zM120.6 169.4v2.5zM120.6 159.2v10.2zM130.8 164.3v2.5zM130.8 161.7v.5zM130.8 163.8v.5zM130.8 169.4v2.5zM130.8 166.8v2.6zM194.3 171.9l2.5 2.5zM199.4 172.5h10.1zM209.5 179.5v2.6zM209.5 177v2.5z"/>
<path d="M217.1 174.4h.6zM217.1 177h.6zM209.5 177h7.6zM196.8 174.4h20.3zM237.5 159.2v5.1zM237.5 164.3v1.2zM237.5 165.5h2.5zM240 168.1v2.5zM240 165.5h2.5zM240 165.5v2.6zM242.5 159.2v5.1zM242.5 164.3v1.2z"/>
<path d="M280.6 179.5v2.6zM280.6 174.4v2.6zM280.6 177v2.5zM290.8 174.4l2.5 2.6zM318.7 171.9v2.5zM293.3 177h30.5zM331.4 179.5h2.6zM331.4 177h2.6zM331.4 174.4h2.6zM331.4 171.9h2.6zM331.4 169.4h2.6zM331.4 166.8h2.6z"/>
<path d="M334 161.7h7.6zM334 164.3h7.6zM334 166.8h7.6zM334 169.4h7.6zM334 171.9h7.6zM334 174.4h7.6zM334 177h7.6zM334 179.5h7.6zM331.4 161.7h2.6zM331.4 164.3h2.6zM348.8 167.4h10.6zM349.2 169.9h10.2z"/>
<path d="M355.3 172.5h4.1zM361.9 161.7h7.6zM361.9 164.3h7.6zM361.9 166.8h7.6zM361.9 169.4h7.6zM361.9 171.9h7.6zM361.9 174.4h7.6zM361.9 177h7.6zM361.9 179.5h7.6zM359.4 161.7h2.5zM359.4 164.3h2.5zM359.4 169.4h2.5z"/>
<path d="M359.4 171.9h2.5zM359.4 174.4h2.5zM382.2 179.5h2.6zM382.2 177h2.6zM382.2 174.4h2.6zM382.2 171.9h2.6zM382.2 169.4h2.6zM382.2 166.8h2.6zM384.8 161.7h7.6zM384.8 164.3h7.6zM384.8 166.8h7.6zM384.8 169.4h7.6z"/>
<path d="M384.8 171.9h7.6zM384.8 174.4h7.6zM384.8 177h7.6zM384.8 179.5h7.6zM382.2 161.7h2.6zM382.2 164.3h2.6zM400 173.7h3.8zM44.4 187.1l2.6-2.5zM54.6 197.3v2.5zM54.6 199.8v2.6zM59.7 189.7h5.1zM62.2 192.2v2.6z"/>
<path d="M62.2 194.8v7.6zM64.8 184.6h2.5zM64.8 199.8h2.5zM64.8 189.7h2.5zM64.8 192.2h2.5zM64.8 194.8h2.5zM62.2 192.2h2.6zM62.2 194.8h2.6zM47 184.6h17.8zM69.6 198.9h3.5zM87.6 182.1h2.6zM87.6 184.6h2.6z"/>
<path d="M87.6 187.1h2.6zM87.6 189.7h2.6zM87.6 192.2h2.6zM87.6 194.8h2.6zM87.6 197.3h2.6zM102.9 182.1h.5zM102.9 184.6h.5zM102.9 187.1h.5zM102.9 189.7h.5zM102.9 192.2h.5zM102.9 194.8h.5zM102.9 197.3h.5z"/>
<path d="M90.2 182.1h12.7zM90.2 184.6h12.7zM90.2 187.1h12.7zM90.2 189.7h12.7zM90.2 192.2h12.7zM90.2 194.8h12.7zM90.2 197.3h12.7zM115.6 192.2l2.5 2.6zM118.1 194.8h17.8zM135.9 194.8h2.5zM143.5 194.8h2.5zM146 194.8h5.1z"/>
<path d="M151.1 194.8h2.5zM153.6 194.8h2.6zM154.4 192.7l1.4-1.4zM154.9 191.7l.5 .5zM154.9 199.3l.5 .5zM154.9 199.3h.7zM155 191.7h.6zM155.1 199.5h.5zM155.1 191.9h.5zM155.1 191.6h.6zM155.2 199.6h.3zM155.2 199.2h.5z"/>
<path d="M155.2 192h.3zM155.3 199.7h.2zM155.3 192.1h.2zM155.4 191.5h.3zM155.8 191.3l-.4 .9zM155.8 198.9l-.4 .9zM155.4 199.1h.3zM155.6 192.8l1.3-1.4zM154.9 191.7l.9-.4zM154.9 199.3l.9-.4zM156.1 191.8l.5 .5zM156.1 199.5l.5 .5z"/>
<path d="M156.1 199.5h.7zM156.1 191.9h.7zM156.2 199.6h.5zM156.2 192h.5zM156.3 191.7h.5zM156.3 199.7h.4zM156.3 192.1h.4zM156.3 199.3h.5zM156.4 199.8h.2zM156.5 192.2h.1zM156.9 191.4l-.3 .9zM156.6 191.6h.3z"/>
<path d="M156.9 199.1l-.3 .9zM156.6 199.2h.3zM156.1 191.8l.8-.4zM156.1 199.5l.8-.4zM156.2 194.8h2.5zM158.7 194.8h5.1zM163.8 194.8v7.6zM255.2 199.8h5.1zM255.2 197.3h5.1zM255.2 194.8h5.1zM255.2 192.2h5.1zM255.2 189.7h5.1z"/>
<path d="M260.3 199.8h7.6zM260.3 189.7h7.6zM260.3 192.2h20.3zM260.3 197.3h7.6zM280.6 187.1v2.6zM280.6 197.3v2.5zM280.6 192.2h7.7zM280.6 189.7v2.5zM280.6 192.2v5.1zM288.3 192.2l2.5-2.5zM260.3 194.8h28zM288.3 194.8l2.5-2.6z"/>
<path d="M290.8 182.1l2.5 2.5zM290.8 184.6l2.5 2.5zM290.8 187.1l2.5 2.6zM293.3 184.6h5.1zM293.3 187.1h5.1zM293.3 189.7h5.1zM298.4 184.6h5.7zM298.4 187.1h5.7zM298.4 189.7h5.7zM310.6 184.6h5.6zM310.6 187.1h5.6zM310.6 189.7h5.6z"/>
<path d="M316.2 189.7h2.5zM316.2 184.6h2.5zM316.2 187.1h7.6zM318.7 192.2v2.6zM318.7 189.7v2.5zM318.7 174.4v10.2zM323.8 177v10.1zM325.6 185.2h5.8zM325.6 187.7h5.8zM325.6 190.2h5.8zM325.6 197.9h5.8zM325.6 192.8h5.8z"/>
<path d="M331.4 184.6h2.6zM331.4 182.1h2.6zM334 182.1h7.6zM334 184.6h7.6zM334 187.1h7.6zM334 189.7h7.6zM334 192.2h7.6zM334 194.8h7.6zM334 197.3h7.6zM334 199.8h7.6zM331.4 197.3h2.6zM331.4 187.1h2.6z"/>
<path d="M331.4 189.7h2.6zM331.4 192.2h2.6zM331.4 199.8h2.6zM331.4 194.8h2.6zM359.4 199.8h2.5zM359.4 197.3h2.5zM359.4 194.8h2.5zM359.4 192.2h2.5zM359.4 189.7h2.5zM359.4 187.1h2.5zM361.9 182.1h7.6zM361.9 184.6h7.6z"/>
<path d="M361.9 187.1h7.6zM361.9 189.7h7.6zM361.9 192.2h7.6zM361.9 194.8h7.6zM361.9 197.3h7.6zM361.9 199.8h7.6zM376.4 185.2h5.8zM376.4 197.9h5.8zM379.6 187.7h2.6zM379.9 192.8h2.3zM380.4 190.2h1.8zM382.2 184.6h2.6z"/>
<path d="M382.2 182.1h2.6zM384.8 182.1h7.6zM384.8 184.6h7.6zM384.8 187.1h7.6zM384.8 189.7h7.6zM384.8 192.2h7.6zM384.8 194.8h7.6zM384.8 197.3h7.6zM384.8 199.8h7.6zM382.2 197.3h2.6zM382.2 187.1h2.6zM382.2 189.7h2.6z"/>
<path d="M382.2 192.2h2.6zM382.2 194.8h2.6zM382.2 199.8h2.6zM36.8 210v2.5zM36.8 204.9v2.5zM36.8 209.5v.5zM36.8 207.4v.5zM36.8 199.8v2.6zM36.8 215v2.6zM36.8 212.5v2.5zM36.8 202.4v2.5zM54.6 212.5v2.5z"/>
<path d="M54.6 204.9v2.5zM54.6 202.4h5.1zM54.6 202.4v2.5zM54.6 215v2.6zM54.6 217.6v2.5zM59.7 189.7v12.7zM62.2 202.4v2.5zM64.8 217.6h2.5zM54.6 217.6h10.2zM87.6 202.4h2.6zM87.6 204.9h2.6zM87.6 207.4h2.6z"/>
<path d="M87.6 210h2.6zM87.6 212.5h2.6zM87.6 215h2.6zM87.6 217.6h2.6zM102.9 202.4h.5zM102.9 204.9h.5zM102.9 207.4h.5zM102.9 210h.5zM102.9 212.5h.5zM102.9 215h.5zM102.9 217.6h.5zM90.2 202.4h12.7z"/>
<path d="M90.2 204.9h12.7zM90.2 207.4h12.7zM90.2 210h12.7zM90.2 212.5h12.7zM90.2 215h12.7zM90.2 217.6h12.7zM115.6 215l2.5 2.6zM115.6 199.8l2.5 2.6zM115.6 207.4l2.5 2.6zM135.9 202.4h2.5zM135.9 210h2.5zM135.9 217.6h2.5z"/>
<path d="M118.1 217.6h17.8zM118.1 202.4h17.8zM118.1 210h17.8zM143.5 202.4h2.5zM143.5 210h2.5zM143.5 217.6h2.5zM151.1 202.4h2.5zM151.1 210h2.5zM151.1 217.6h2.5zM146 202.4h5.1zM146 210h5.1zM146 217.6h5.1z"/>
<path d="M153.6 202.4h2.6zM153.6 210h2.6zM153.6 217.6h2.6zM154.4 200.3l1.4-1.4zM154.4 207.9l1.4-1.4zM154.4 215.6l1.4-1.4zM154.9 206.9l.5 .5zM154.9 214.5l.5 .5zM154.9 206.9h.8zM155 214.5h.7zM155 214.6h.6zM155 207h.6z"/>
<path d="M155.1 214.8h.5zM155.1 207.2h.5zM155.2 206.8h.5zM155.3 214.9h.2zM155.3 207.3h.2zM155.3 214.4h.4zM155.8 206.5l-.4 .9zM155.8 214.2l-.4 .8zM155.5 206.7h.3zM155.6 200.5l1.3-1.4zM155.6 208.1l1.3-1.4zM155.6 215.7l1.3-1.4z"/>
<path d="M155.6 214.3h.2zM154.9 206.9l.9-.4zM154.9 214.5l.9-.3zM156.1 207l.5 .6zM156.1 214.7l.5 .5zM156.1 207h.7zM156.1 214.8h.7zM156.1 214.6h.7zM156.2 207.2h.5zM156.3 214.9h.4zM156.3 207.3h.4zM156.4 206.9h.4z"/>
<path d="M156.4 215h.3zM156.4 207.4h.3zM156.4 214.5h.5zM156.9 206.7l-.3 .9zM156.9 214.3l-.3 .9zM156.7 206.8h.2zM156.7 214.4h.2zM156.1 207l.8-.3zM156.1 214.7l.8-.4zM156.2 202.4h2.5zM156.2 210h2.5zM156.2 217.6h2.5z"/>
<path d="M158.7 202.4h5.1zM158.7 210h5.1zM158.7 217.6h5.1zM163.8 202.4v7.6zM163.8 210v7.6zM163.8 217.6v5.1zM255.2 202.4h5.1zM260.3 202.4h2.6zM262.9 204.9v2.5zM262.9 202.4v2.5zM280.6 204.9v2.5zM280.6 210v2.5z"/>
<path d="M280.6 207.4v2.6zM325 200.4h6.4zM331.4 217.6h2.6zM331.4 215h2.6zM331.4 212.5h2.6zM331.4 210h2.6zM331.4 207.4h2.6zM331.4 204.9h2.6zM334 202.4h7.6zM334 204.9h7.6zM334 207.4h7.6zM334 210h7.6z"/>
<path d="M334 212.5h7.6zM334 215h7.6zM334 217.6h7.6zM331.4 202.4h2.6zM346.8 218.2h12.6zM346.8 215.6h12.6zM346.8 213.1h12.6zM359.4 204.9h2.5zM359.4 202.4h2.5zM361.9 202.4h7.6zM361.9 204.9h7.6zM361.9 207.4h7.6z"/>
<path d="M361.9 210h7.6zM361.9 212.5h7.6zM361.9 215h7.6zM361.9 217.6h7.6zM359.4 217.6h2.5zM359.4 215h2.5zM376.4 202.9h5.8zM376.4 200.4h5.8zM382.2 217.6h2.6zM382.2 215h2.6zM382.2 212.5h2.6zM382.2 210h2.6z"/>
<path d="M382.2 207.4h2.6zM384.8 202.4h7.6zM384.8 204.9h7.6zM384.8 207.4h7.6zM384.8 210h7.6zM384.8 212.5h7.6zM384.8 215h7.6zM384.8 217.6h7.6zM382.2 204.9h2.6zM382.2 202.4h2.6zM16.5 224.2h3.8zM54.6 220.1v2.6z"/>
<path d="M54.6 225.2v2.5zM54.6 222.7v.5zM54.6 224.7v.5zM54.6 230.3v2.5zM54.6 227.7v2.6zM87.6 220.1h2.6zM102.9 220.1h.5zM90.2 220.1h12.7zM163.8 222.7v2.5zM321.2 223.2h10.2zM325.3 228.3h6.1zM331.4 222.7h2.6z"/>
<path d="M331.4 220.1h2.6zM334 220.1h7.6zM334 222.7h7.6zM334 225.2h7.6zM334 227.7h7.6zM334 230.3h7.6zM334 232.8h7.6zM334 235.4h7.6zM331.4 235.4h2.6zM331.4 232.8h2.6zM331.4 225.2h2.6zM331.4 227.7h2.6z"/>
<path d="M331.4 230.3h2.6zM355 220.7h4.4zM359.4 227.7h2.5zM359.4 222.7h2.5zM361.9 220.1h7.6zM361.9 222.7h7.6zM361.9 225.2h7.6zM361.9 227.7h7.6zM361.9 230.3h7.6zM361.9 232.8h7.6zM361.9 235.4h7.6zM359.4 235.4h2.5z"/>
<path d="M359.4 232.8h2.5zM359.4 230.3h2.5zM359.4 225.2h2.5zM359.4 220.1h2.5zM373.9 228.3h8.3zM382.2 225.2h2.6zM382.2 222.7h2.6zM382.2 220.1h2.6zM382.2 227.7h2.6zM384.8 220.1h7.6zM384.8 222.7h7.6zM384.8 225.2h7.6z"/>
<path d="M384.8 227.7h7.6zM384.8 230.3h7.6zM384.8 232.8h7.6zM384.8 235.4h7.6zM382.2 235.4h2.6zM382.2 232.8h2.6zM382.2 230.3h2.6zM400 224.2h3.8zM34.3 253.1v2.6zM34.3 257.7v.5zM34.3 255.7v.5zM34.3 250.6v2.5z"/>
<path d="M41.9 253.1v2.6zM41.9 257.7v.5zM41.9 255.7v.5zM34.3 250.6h7.6zM41.9 250.6v2.5zM49.5 245.5v2.6zM49.5 253.1v2.6zM49.5 257.7v.5zM49.5 255.7v.5zM41.9 250.6h7.6zM49.5 248.1v2.5zM49.5 250.6v2.5z"/>
<path d="M59.7 245.5v2.6zM59.7 253.1v2.6zM59.7 255.7v.5zM59.7 257.7v.5zM59.7 248.1v5zM92.7 250.6v2.5zM92.7 253.1v5.1zM92.7 258.2v2.6zM95.2 253.1h5.1zM95.2 258.2h5.1zM95.2 250.6h3.1zM92.7 250.6h2.5z"/>
<path d="M92.7 253.1h2.5zM92.7 258.2h2.5zM100.3 257.2l2 1zM100.3 259.2l2-1zM111.5 259.9h1.7zM115.6 250.6h5zM224.8 255.7v2.5zM224.8 250.6v2.5zM224.8 253.1v2.6zM242 248.1h1.1zM242 255.7h1.1zM242.5 247.6v1z"/>
<path d="M242.5 255.2v1zM20.3 274.7h379.7zM34.3 265.8v2.6zM34.3 258.2v2.6zM34.3 263.3v2.5zM34.3 260.8v2.5zM41.9 258.2v2.6zM34.3 263.3h7.6zM41.9 260.8v2.5zM49.5 258.2v2.6zM41.9 263.3h7.6zM49.5 260.8v2.5z"/>
<path d="M59.7 258.2v2.6zM59.7 265.8v2.6zM59.7 260.8v5zM67.8 274.7v3.8zM92.7 265.8v2.6zM92.7 260.8v5zM95.2 260.8h3.1zM92.7 260.8h2.5zM115.3 274.7v3.8zM115.6 260.8h5zM125.7 265.8v2.6zM125.7 260.8v5z"/>
<path d="M125.7 260.8h2.5zM128.2 260.8h5.1zM145.5 260.8h3.1zM156.2 265.8v2.6zM156.2 260.8v5zM156.2 260.8h2.5zM158.7 260.8h5.1zM162.7 274.7v3.8zM176 260.8h3zM186.7 265.8v2.6zM186.7 260.8v5zM186.7 260.8h2.5z"/>
<path d="M189.2 260.8h5.1zM206.4 260.8h3.1zM210.2 274.7v3.8zM224.8 260.8v2.5zM224.8 265.8v2.6zM224.8 263.3v2.5zM242 263.3h1.1zM242 270.9h1.1zM242.5 262.8v1zM242.5 270.4v1zM257.6 274.7v3.8zM305.1 274.7v3.8z"/>
<path d="M352.5 274.7v3.8zM400 264.5v.1zM400 268.4v6.2zM400 274.6h.1zM400 22.1v252.6z"/>
<path d="M240.5 248.1h1.5l.1 .3 .4 .2v1.5a2 2 0 0 1-2-2z" fill-rule="evenodd"/>
<path d="M240.5 255.7h1.5l.2 .4 .3 .1v1.5a2 2 0 0 1-2-2z" fill-rule="evenodd"/>
<path d="M242.5 246a2.04 2.04 0 0 1 2.1 2.1h-1.5l-.2-.3-.4-.2z" fill-rule="evenodd"/>
<path d="M242.5 253.7a2.04 2.04 0 0 1 2.1 2h-1.5l-.2-.3-.4-.2z" fill-rule="evenodd"/>
<path d="M240.5 263.3h1.5l.2 .4 .3 .1v1.5a2 2 0 0 1-2-2z" fill-rule="evenodd"/>
<path d="M240.5 270.9h1.5l.1 .3 .4 .2v1.6a2 2 0 0 1-2-2.1z" fill-rule="evenodd"/>
<path d="M242.5 261.3a2.04 2.04 0 0 1 2.1 2h-1.5l-.2-.3-.4-.2z" fill-rule="evenodd"/>
<path d="M242.5 268.9a2 2 0 0 1 2.1 2h-1.5l-.2-.3-.4-.2z" fill-rule="evenodd"/>
<circle cx="273" cy="37.3" r=".51"/>
<circle cx="278.1" cy="32.2" r=".51"/>
<circle cx="280.6" cy="27.1" r=".51"/>
<circle cx="49.5" cy="52.5" r=".51"/>
<circle cx="52.1" cy="47.5" r=".51"/>
<circle cx="115.6" cy="42.4" r=".51"/>
<circle cx="275.6" cy="47.5" r=".51"/>
<circle cx="339" cy="42.4" r=".51"/>
<circle cx="344.1" cy="57.6" r=".51"/>
<circle cx="184.1" cy="62.7" r=".51"/>
<circle cx="240" cy="81.7" r=".51"/>
<circle cx="209.5" cy="103.3" r=".51"/>
<circle cx="212.1" cy="103.3" r=".51"/>
<circle cx="212.1" cy="117.3" r=".51"/>
<circle cx="283.2" cy="108.4" r=".51"/>
<circle cx="283.2" cy="105.9" r=".51"/>
<circle cx="62.2" cy="133.8" r=".51"/>
<circle cx="138.4" cy="133.8" r=".51"/>
<circle cx="138.4" cy="131.3" r=".51"/>
<circle cx="212.1" cy="131.3" r=".51"/>
<circle cx="308.6" cy="133.8" r=".51"/>
<circle cx="311.1" cy="138.9" r=".51"/>
<circle cx="54.6" cy="156.7" r=".51"/>
<circle cx="54.6" cy="141.4" r=".51"/>
<circle cx="130.8" cy="156.7" r=".51"/>
<circle cx="199.4" cy="141.4" r=".51"/>
<circle cx="212.1" cy="141.4" r=".51"/>
<circle cx="240" cy="165.5" r=".51"/>
<circle cx="62.2" cy="194.8" r=".51"/>
<circle cx="280.6" cy="192.2" r=".51"/>
<circle cx="54.6" cy="202.4" r=".51"/>
<circle cx="54.6" cy="217.6" r=".51"/>
<circle cx="163.8" cy="210" r=".51"/>
<circle cx="163.8" cy="202.4" r=".51"/>
<circle cx="163.8" cy="217.6" r=".51"/>
<circle cx="41.9" cy="250.6" r=".51"/>
<circle cx="49.5" cy="250.6" r=".51"/>
<circle cx="92.7" cy="258.2" r=".51"/>
<circle cx="92.7" cy="253.1" r=".51"/>
<circle cx="34.3" cy="263.3" r=".51"/>
<circle cx="41.9" cy="263.3" r=".51"/>
<circle cx="92.7" cy="260.8" r=".51"/>
</g>
<g fill="#000" stroke="#000" stroke-width=".28">
<path d="M31.3 30.7v3zM34.5 25.6v3.1zM35.4 35.8v3zM31.3 33.7h11.6zM31.3 30.7h11.6zM34.5 28.7h8.4zM34.5 25.6h8.4zM35.4 38.8h7.5zM35.4 35.8h7.5zM44.4 32.2l-1.5 1.5zM42.9 30.7l1.5 1.5zM44.4 27.1l-1.5 1.6z"/>
<path d="M42.9 25.6l1.5 1.5zM44.4 37.3l-1.5 1.5zM42.9 35.8l1.5 1.5zM298.4 32.2l1.5-1.5zM298.4 32.2l1.5 1.5zM299.9 25.6l-1.5 1.5zM298.4 27.1l1.5 1.6zM299.9 35.8l-1.5 1.5zM298.4 37.3l1.5 1.5zM299.9 30.7h11.7zM299.9 33.7h11.7zM299.9 25.6h8.4z"/>
<path d="M299.9 28.7h8.4zM299.9 35.8h7.6zM299.9 38.8h7.6zM307.5 35.8v3zM308.3 25.6v3.1zM311.6 30.7v3zM24.5 51v3.1zM28.7 40.9v3zM32.1 56.1v3zM34.8 45.9v3.1zM34.8 45.9h8.1zM34.8 49h8.1z"/>
<path d="M32.1 56.1h10.8zM32.1 59.1h10.8zM28.7 40.9h14.2zM28.7 43.9h14.2zM24.5 51h18.4zM24.5 54.1h18.4zM42.9 45.9l1.5 1.6zM44.4 47.5l-1.5 1.5zM42.9 56.1l1.5 1.5zM44.4 57.6l-1.5 1.5zM42.9 40.9l1.5 1.5zM44.4 42.4l-1.5 1.5z"/>
<path d="M42.9 51l1.5 1.5zM44.4 52.5l-1.5 1.6zM374.6 47.5l1.5-1.6zM374.6 47.5l1.5 1.5zM374.6 57.6l1.5-1.5zM374.6 57.6l1.5 1.5zM374.6 42.4l1.5-1.5zM374.6 42.4l1.5 1.5zM374.6 52.5l1.5-1.5zM374.6 52.5l1.5 1.6zM376.1 45.9h8.1zM376.1 49h8.1z"/>
<path d="M376.1 56.1h10.8zM376.1 59.1h10.8zM376.1 40.9h14.2zM376.1 43.9h14.2zM376.1 51h18.4zM376.1 54.1h18.4zM384.2 45.9v3.1zM386.9 56.1v3zM390.3 40.9v3zM394.5 51v3.1zM33.1 61.1v3.1zM33.1 64.2h9.8z"/>
<path d="M33.1 61.1h9.8zM42.9 64.2l1.5-1.5zM42.9 61.1l1.5 1.6zM130.8 77.9l-1.3 1.9zM130.8 77.9l1.3 1.9zM204.4 75.4l-1.2 1.9zM204.4 75.4l1.3 1.9zM214.6 75.4l-1.3 1.9zM214.6 75.4l1.3 1.9zM240 75.4l-1.3 1.9zM240 75.4l1.3 1.9zM321.3 74.1v7.6z"/>
<path d="M374.6 62.7l1.5-1.6zM374.6 62.7l1.5 1.5zM376.1 61.1h9.8zM376.1 64.2h9.8zM385.9 61.1v3.1zM168.9 91.9v7.6zM202.5 93.2h3.9zM212.7 93.2h3.8zM283.2 88.1l-1.3 1.9zM283.2 88.1l1.3 1.9zM284.1 95.7v5.1zM282.3 95.7h1.8z"/>
<path d="M303.5 93.2l-1.3 1.9zM303.5 93.2l1.3 1.9zM321.3 86.8v7.6zM205.1 109h1.3zM205.1 112.8h1.3zM205.1 109v1.9zM205.1 110.9v1.9zM209.5 108.4v.6zM208.3 109l1.2 4.5zM282.3 95.7v5.1zM282.3 100.8h1.8zM302.6 100.8v5.1z"/>
<path d="M304.4 100.8v5.1zM302.6 105.9h1.8zM302.6 100.8h1.8zM36.8 138.9l-1.2 1.9zM54.6 136.3l-1.3 1.9zM54.6 136.3l1.3 1.9zM120.6 138.9l1.3 1.9zM130.8 138.9l1.3 1.9zM210.5 136v.7zM210.5 136.7h3.1zM210.5 136h3.1zM213.6 136v.7z"/>
<path d="M210.3 137.3h3.5zM210.3 135.3h3.5zM210.2 121.1h3.8zM327.9 132.3l-1.5 1.5zM326.4 133.8l1.5 1.5zM327.9 137.3l-1.5 1.6zM326.4 138.9l1.5 1.5zM327.9 132.3h14.6zM327.9 135.3h14.6zM327.9 137.3h14.6zM342.5 132.3v3zM342.5 137.3v3.1z"/>
<path d="M36.8 138.9l1.3 1.9zM34.9 156.7h3.8zM53.7 146.5v5.1zM53.7 151.6h1.8zM53.7 146.5h1.8zM55.5 146.5v5.1zM60.3 144h3.8zM120.6 138.9l-1.2 1.9zM130.8 138.9l-1.3 1.9zM129.9 146.5v5.1zM131.7 146.5v5.1zM129.9 151.6h1.8z"/>
<path d="M129.9 146.5h1.8zM136.5 144h3.8zM197.5 149h3.8zM327.9 140.4h14.6zM52.7 171.9h3.8zM118.7 171.9h3.8zM128.9 171.9h3.8zM238.1 170.6h3.8zM280.6 174.4l-1.2 1.9zM280.6 174.4l1.3 1.9zM318.7 171.9l-1.2 1.9zM318.7 171.9l1.3 1.9z"/>
<path d="M36.8 199.8l-1.2 1.9zM54.6 197.3l-1.3 1.9zM54.6 197.3l1.3 1.9zM138.4 195.6h5.1zM138.4 193.9v1.7zM138.4 193.9h5.1zM143.5 193.9v1.7zM153.6 193.5v2.5zM153.6 196l2.6-1.2zM153.6 195.9h.3zM153.6 195.7h.7zM153.6 195.4h1.2z"/>
<path d="M153.6 195.2h1.6zM153.6 195h2.1zM153.6 194.8h2.5zM153.6 194.6h2.2zM153.6 194.3h1.8zM153.6 194.1h1.4zM153.6 193.9h.9zM153.6 193.7h.5zM156.2 193.5v1.3zM153.6 193.5l2.6 1.3zM156.2 193.5v2.5zM156.2 196h.2z"/>
<path d="M156.2 195.9h.2zM156.2 195.7h.2zM156.2 195.4h.2zM156.2 195.2h.2zM156.2 195h.2zM156.2 194.8h.2zM156.2 194.6h.2zM156.2 194.3h.2zM156.2 194.1h.2zM156.2 193.9h.2zM156.2 193.7h.2zM156.4 193.5v2.5z"/>
<path d="M156.2 193.5h.2zM207.6 182.1h3.8zM279.8 182.1v5zM279.8 199.8v5.1zM281.5 182.1v5zM279.8 182.1h1.7zM279.8 187.1h1.7zM279.8 199.8h1.7zM316.8 194.8h3.8zM36.8 199.8l1.3 1.9zM34.9 217.6h3.8zM53.7 207.4v5.1z"/>
<path d="M53.7 212.5h1.8zM53.7 207.4h1.8zM55.5 207.4v5.1zM60.3 204.9h3.8zM138.4 203.3h5.1zM138.4 201.5v1.8zM138.4 210.9h5.1zM138.4 209.1v1.8zM138.4 218.5h5.1zM138.4 216.7v1.8zM138.4 201.5h5.1zM143.5 201.5v1.8z"/>
<path d="M138.4 209.1h5.1zM143.5 209.1v1.8zM138.4 216.7h5.1zM143.5 216.7v1.8zM153.6 201.1v2.5zM153.6 203.6l2.6-1.2zM153.6 203.5h.4zM153.6 203.2h.9zM153.6 203h1.3zM153.6 202.8h1.7zM153.6 202.6h2.2zM153.6 202.3h2.6z"/>
<path d="M153.6 202.1h2.1zM153.6 201.9h1.7zM153.6 201.7h1.2zM153.6 201.5h.8zM153.6 201.2h.3zM153.6 208.7v2.5zM153.6 211.2l2.6-1.2zM153.6 211h.5zM153.6 210.8h1zM153.6 210.6h1.4zM153.6 210.4h1.9zM153.6 210.1h2.3z"/>
<path d="M153.6 209.9h2.4zM153.6 209.7h2zM153.6 209.5h1.5zM153.6 209.2h1.1zM153.6 209h.7zM153.6 208.8h.2zM153.6 216.3v2.6zM153.6 218.9l2.6-1.3zM153.6 218.8h.2zM153.6 218.6h.7zM153.6 218.4h1.1zM153.6 218.1h1.5z"/>
<path d="M153.6 217.9h2zM153.6 217.7h2.4zM153.6 217.5h2.3zM153.6 217.2h1.9zM153.6 217h1.4zM153.6 216.8h1zM153.6 216.6h.5zM156.2 201.1v1.3zM153.6 201.1l2.6 1.3zM156.2 201.1v2.5zM156.2 203.6h.2zM156.2 203.5h.2z"/>
<path d="M156.2 203.2h.2zM156.2 203h.2zM156.2 202.8h.2zM156.2 202.6h.2zM156.2 202.3h.2zM156.2 202.1h.2zM156.2 201.9h.2zM156.2 201.7h.2zM156.2 201.5h.2zM156.2 201.2h.2zM156.2 208.7v1.3zM153.6 208.7l2.6 1.3z"/>
<path d="M156.2 208.7v2.5zM156.2 211.2h.2zM156.2 211h.2zM156.2 210.8h.2zM156.2 210.6h.2zM156.2 210.4h.2zM156.2 210.1h.2zM156.2 209.9h.2zM156.2 209.7h.2zM156.2 209.5h.2zM156.2 209.2h.2zM156.2 209h.2z"/>
<path d="M156.2 208.8h.2zM156.2 216.3v1.3zM153.6 216.3l2.6 1.3zM156.2 216.3v2.6zM156.2 218.9h.2zM156.2 218.8h.2zM156.2 218.6h.2zM156.2 218.4h.2zM156.2 218.1h.2zM156.2 217.9h.2zM156.2 217.7h.2zM156.2 217.5h.2z"/>
<path d="M156.2 217.2h.2zM156.2 217h.2zM156.2 216.8h.2zM156.2 216.6h.2zM156.2 216.3h.2zM156.4 201.1v2.5zM156.2 201.1h.2zM156.4 208.7v2.5zM156.2 208.7h.2zM156.4 216.3v2.6zM261 207.4h3.8zM278.7 212.5h3.8z"/>
<path d="M281.5 199.8v5.1zM279.8 204.9h1.7zM52.7 232.8h3.8zM161.9 225.2h3.8zM49.5 245.5l-1.2 1.9zM49.5 245.5l1.3 1.9zM59.7 245.5l-1.3 1.9zM59.7 245.5l1.3 1.9zM135.9 257v7.6zM166.3 257v7.6zM196.8 257v7.6zM223.2 259.1h3.1z"/>
<path d="M223.2 258.2v.9zM223.2 258.2h3.1zM224.8 250.6l-1.3 1.9zM224.8 250.6l1.2 1.9zM226.3 258.2v.9zM313.7 249.3h86.3zM313.7 254.4h86.3zM313.7 259.5h58.4zM372.1 259.5h27.9zM372.1 259.5v5.1zM32.4 268.4h3.8zM57.8 268.4h3.8z"/>
<path d="M90.8 268.4h3.8zM123.8 268.4h3.8zM154.3 268.4h3.8zM184.8 268.4h3.8zM222.9 268.4h3.8zM313.7 264.6h58.4zM313.7 269.7h86.3zM372.1 264.6h27.9zM400 268.4v1.3z"/>
</g>
<g fill="#000" stroke="#000" stroke-width=".42">
<path d="M74.9 80.5v22.8zM74.9 80.5h17.8zM360.6 95.7v10.2zM360.6 95.7h7.7zM373.3 95.7h7.7zM381 95.7v15.2zM74.9 103.3h17.8zM92.7 80.5v22.8zM360.6 105.9h7.7zM360.6 110.9v25.4zM368.3 95.7v10.2zM360.6 110.9h7.7z"/>
<path d="M373.3 95.7v15.2zM373.3 110.9h7.7zM306 122.4v7.6zM306 130h7.7zM313.7 122.4v7.6zM306 122.4h7.7zM360.6 136.3h7.7zM368.3 110.9v25.4zM373.3 121.1v15.2zM373.3 121.1h7.7zM373.3 136.3h7.7zM381 121.1v15.2z"/>
<path d="M345.4 154.1v83.8zM340.3 154.1h5.1zM373.3 154.1v83.8zM368.3 154.1h5zM396.2 154.1v83.8zM391.1 154.1h5.1zM99.1 177v22.8zM99.1 177h7.6zM213.3 179.5h7.7zM213.3 171.9v7.6zM221 171.9v7.6zM213.3 171.9h7.7z"/>
<path d="M99.1 199.8h7.6zM99.1 199.8v22.9zM106.7 177v22.8zM251.4 187.1v17.8zM251.4 187.1h5.1zM301 192.2h12.7zM301 182.1v10.1zM313.7 182.1v10.1zM301 182.1h12.7zM251.4 204.9h5.1zM256.5 187.1v17.8zM99.1 222.7h7.6z"/>
<path d="M106.7 199.8v22.9zM340.3 237.9h5.1zM340.3 154.1v83.8zM368.3 237.9h5zM368.3 154.1v83.8zM391.1 237.9h5.1zM391.1 154.1v83.8z"/>
</g>
<g fill="#000" stroke="#000" stroke-width=".61">
<path d="M20.3 22.1v252.6zM20.3 22.1h379.7zM318.7 72.8l2.6 1.3zM321.3 74.1l7.6 3.8zM321.3 81.7l7.6-3.8zM138.4 98.2h15.2zM138.4 83v15.2zM153.6 83v15.2zM138.4 83h15.2zM166.3 90.6l2.6 1.3zM168.9 91.9l7.6 3.8zM166.3 100.8l2.6-1.3z"/>
<path d="M168.9 99.5l7.6-3.8zM219.7 88.1h43.2zM262.9 88.1v71.1zM318.7 85.5l2.6 1.3zM318.7 85.5v10.2zM318.7 72.8v10.2zM321.3 86.8l7.6 3.8zM318.7 95.7l2.6-1.3zM318.7 83l2.6-1.3zM321.3 94.4l7.6-3.8zM67.3 116h20.3zM87.6 116v45.7z"/>
<path d="M143.5 116h20.3zM163.8 116v45.7zM166.3 90.6v10.2zM219.7 88.1v71.1zM219.7 159.2h43.2zM341.6 159.2h1.3zM341.6 156.7h1.3zM369.5 159.2h1.3zM369.5 156.7h1.3zM392.4 159.2h1.3zM392.4 156.7h1.3zM67.3 116v45.7z"/>
<path d="M67.3 177h20.3zM67.3 161.7h20.3zM87.6 177v45.7zM143.5 116v45.7zM143.5 161.7h20.3zM341.6 179.5h1.3zM341.6 177h1.3zM341.6 174.4h1.3zM341.6 171.9h1.3zM341.6 169.4h1.3zM341.6 166.8h1.3zM341.6 164.3h1.3z"/>
<path d="M341.6 161.7h1.3zM369.5 179.5h1.3zM369.5 177h1.3zM369.5 174.4h1.3zM369.5 171.9h1.3zM369.5 169.4h1.3zM369.5 166.8h1.3zM369.5 164.3h1.3zM369.5 161.7h1.3zM392.4 179.5h1.3zM392.4 177h1.3zM392.4 174.4h1.3z"/>
<path d="M392.4 171.9h1.3zM392.4 169.4h1.3zM392.4 166.8h1.3zM392.4 164.3h1.3zM392.4 161.7h1.3zM254 197.3h1.2zM254 199.8h1.2zM254 192.2h1.2zM254 194.8h1.2zM254 189.7h1.2zM341.6 199.8h1.3zM341.6 197.3h1.3z"/>
<path d="M341.6 194.8h1.3zM341.6 192.2h1.3zM341.6 189.7h1.3zM341.6 187.1h1.3zM341.6 184.6h1.3zM341.6 182.1h1.3zM369.5 199.8h1.3zM369.5 197.3h1.3zM369.5 194.8h1.3zM369.5 192.2h1.3zM369.5 189.7h1.3zM369.5 187.1h1.3z"/>
<path d="M369.5 184.6h1.3zM369.5 182.1h1.3zM392.4 199.8h1.3zM392.4 197.3h1.3zM392.4 194.8h1.3zM392.4 192.2h1.3zM392.4 189.7h1.3zM392.4 187.1h1.3zM392.4 184.6h1.3zM392.4 182.1h1.3zM254 202.4h1.2zM341.6 217.6h1.3z"/>
<path d="M341.6 215h1.3zM341.6 212.5h1.3zM341.6 210h1.3zM341.6 207.4h1.3zM341.6 204.9h1.3zM341.6 202.4h1.3zM369.5 217.6h1.3zM369.5 215h1.3zM369.5 212.5h1.3zM369.5 210h1.3zM369.5 207.4h1.3zM369.5 204.9h1.3z"/>
<path d="M369.5 202.4h1.3zM392.4 217.6h1.3zM392.4 215h1.3zM392.4 212.5h1.3zM392.4 210h1.3zM392.4 207.4h1.3zM392.4 204.9h1.3zM392.4 202.4h1.3zM67.3 177v45.7zM67.3 222.7h20.3zM341.6 235.4h1.3zM341.6 232.8h1.3z"/>
<path d="M341.6 230.3h1.3zM341.6 227.7h1.3zM341.6 225.2h1.3zM341.6 222.7h1.3zM341.6 220.1h1.3zM369.5 235.4h1.3zM369.5 232.8h1.3zM369.5 230.3h1.3zM369.5 227.7h1.3zM369.5 225.2h1.3zM369.5 222.7h1.3zM369.5 220.1h1.3z"/>
<path d="M392.4 235.4h1.3zM392.4 232.8h1.3zM392.4 230.3h1.3zM392.4 227.7h1.3zM392.4 225.2h1.3zM392.4 222.7h1.3zM392.4 220.1h1.3zM100.3 248.1v15.2zM100.3 248.1h15.3zM133.3 255.7l2.6 1.3zM135.9 257l7.6 3.8zM163.8 255.7l2.5 1.3z"/>
<path d="M166.3 257l7.7 3.8zM194.3 255.7l2.5 1.3zM196.8 257l7.6 3.8zM283.2 244.3v30.4zM313.7 254.4v5.1zM313.7 249.3v5.1zM313.7 244.3v5zM313.7 244.3h86.3zM283.2 244.3h30.5zM400 254.4v5.1zM400 249.3v5.1zM400 244.3v5z"/>
<path d="M400 22.1v222.2zM20.3 274.7h262.9zM100.3 263.3h15.3zM115.6 248.1v15.2zM133.3 255.7v10.1zM133.3 265.8l2.6-1.2zM135.9 264.6l7.6-3.8zM163.8 255.7v10.1zM163.8 265.8l2.5-1.2zM166.3 264.6l7.7-3.8zM194.3 255.7v10.1zM194.3 265.8l2.5-1.2z"/>
<path d="M196.8 264.6l7.6-3.8zM283.2 274.7h30.5zM313.7 274.7h86.3zM313.7 269.7v5zM313.7 264.6v5.1zM313.7 259.5v5.1zM400 268.4v6.3zM400 264.6v3.8zM400 259.5v5.1z"/>
</g>
<g fill="none" stroke="#000" stroke-width=".21">
<circle cx="329.9" cy="77.9" r="1"/>
<circle cx="73.9" cy="98.2" r=".99"/>
<circle cx="93.7" cy="90.6" r=".99"/>
<circle cx="93.7" cy="98.2" r=".99"/>
<circle cx="93.7" cy="93.2" r=".99"/>
<circle cx="93.7" cy="95.7" r=".99"/>
<circle cx="93.7" cy="88.1" r=".99"/>
<circle cx="93.7" cy="85.5" r=".99"/>
<circle cx="93.7" cy="83" r=".99"/>
<circle cx="137.4" cy="95.7" r=".99"/>
<circle cx="137.4" cy="85.5" r=".99"/>
<circle cx="177.5" cy="95.7" r=".99"/>
<circle cx="329.9" cy="90.6" r="1"/>
<circle cx="366" cy="98.2" r="1"/>
<circle cx="375.6" cy="98.2" r="1"/>
<circle cx="73.9" cy="100.8" r=".99"/>
<circle cx="93.7" cy="100.8" r=".99"/>
<circle cx="218.7" cy="103.3" r="1"/>
<circle cx="366" cy="103.3" r="1"/>
<circle cx="366" cy="113.5" r="1"/>
<circle cx="366" cy="116" r="1"/>
<circle cx="366" cy="100.8" r="1"/>
<circle cx="366" cy="118.6" r="1"/>
<circle cx="375.6" cy="105.9" r="1"/>
<circle cx="375.6" cy="103.3" r="1"/>
<circle cx="375.6" cy="108.4" r="1"/>
<circle cx="375.6" cy="100.8" r="1"/>
<circle cx="308.6" cy="124.6" r="1"/>
<circle cx="311.1" cy="124.6" r="1"/>
<circle cx="366" cy="121.1" r="1"/>
<circle cx="366" cy="128.7" r="1"/>
<circle cx="366" cy="123.6" r="1"/>
<circle cx="366" cy="126.2" r="1"/>
<circle cx="366" cy="131.3" r="1"/>
<circle cx="366" cy="133.8" r="1"/>
<circle cx="375.6" cy="133.8" r="1"/>
<circle cx="375.6" cy="128.7" r="1"/>
<circle cx="375.6" cy="123.6" r="1"/>
<circle cx="375.6" cy="126.2" r="1"/>
<circle cx="375.6" cy="131.3" r="1"/>
<circle cx="104.4" cy="179.5" r=".99"/>
<circle cx="218.7" cy="177" r="1"/>
<circle cx="218.7" cy="174.4" r="1"/>
<circle cx="104.4" cy="194.8" r=".99"/>
<circle cx="104.4" cy="192.2" r=".99"/>
<circle cx="104.4" cy="187.1" r=".99"/>
<circle cx="104.4" cy="182.1" r=".99"/>
<circle cx="104.4" cy="189.7" r=".99"/>
<circle cx="104.4" cy="197.3" r=".99"/>
<circle cx="104.4" cy="184.6" r=".99"/>
<circle cx="305" cy="184.6" r="1"/>
<circle cx="305" cy="189.7" r="1"/>
<circle cx="305" cy="187.1" r="1"/>
<circle cx="309.6" cy="187.1" r="1"/>
<circle cx="309.6" cy="184.6" r="1"/>
<circle cx="309.6" cy="189.7" r="1"/>
<circle cx="104.4" cy="217.6" r=".99"/>
<circle cx="104.4" cy="212.5" r=".99"/>
<circle cx="104.4" cy="215" r=".99"/>
<circle cx="104.4" cy="204.9" r=".99"/>
<circle cx="104.4" cy="210" r=".99"/>
<circle cx="104.4" cy="202.4" r=".99"/>
<circle cx="104.4" cy="207.4" r=".99"/>
<circle cx="104.4" cy="220.1" r=".99"/>
<circle cx="99.3" cy="250.6" r=".99"/>
<circle cx="242.5" cy="255.7" r="2.03"/>
<circle cx="242.5" cy="248.1" r="2.03"/>
<circle cx="242.5" cy="248.1" r=".51"/>
<circle cx="242.5" cy="255.7" r=".51"/>
<circle cx="99.3" cy="260.8" r=".99"/>
<circle cx="144.5" cy="260.8" r=".99"/>
<circle cx="175" cy="260.8" r=".99"/>
<circle cx="205.4" cy="260.8" r=".99"/>
<circle cx="242.5" cy="270.9" r="2.03"/>
<circle cx="242.5" cy="263.3" r="2.03"/>
<circle cx="242.5" cy="263.3" r=".51"/>
<circle cx="242.5" cy="270.9" r=".51"/>
</g>
<path d="M16.5 18.2v260.3zM16.5 18.2h387.3zM16.5 278.5h387.3zM403.8 18.2v260.3z" fill="#000" stroke="#000" stroke-width=".32"/>
<g fill="#000" stroke="#000" stroke-width=".21">
<path d="M202.4 83.5h4.1v.5h-4.1zM202.4 84.5h4.1v.5h-4.1zM212.6 83.5h4v.5h-4zM212.6 84.5h4v.5h-4zM205 129.2h.5v4.1h-.5zM205 139.4h.5v4h-.5zM206 129.2h.5v4.1h-.5zM206 139.4h.5v4h-.5zM34.8 147h4.1v.5h-4.1zM34.8 148h4.1v.5h-4.1zM118.6 154.6h4.1v.5h-4.1zM118.6 155.6h4.1v.5h-4.1z"/>
<path d="M52.6 163.3h4v.5h-4zM52.6 162.2h4v.5h-4zM128.8 163.3h4v.5h-4zM128.8 162.2h4v.5h-4zM34.8 207.9h4.1v.5h-4.1zM34.8 209h4.1v.5h-4.1zM52.6 224.2h4v.5h-4zM52.6 223.2h4v.5h-4zM32.3 256.2h4v.5h-4zM32.3 257.2h4v.5h-4zM39.9 256.2h4v.5h-4zM39.9 257.2h4v.5h-4z"/>
<path d="M47.5 256.2h4.1v.5h-4.1zM47.5 257.2h4.1v.5h-4.1zM57.7 257.2h4v.5h-4zM57.7 256.2h4v.5h-4zM223.1 259.9h3.3v.9h-3.3z"/>
</g>
<g fill="none" stroke="#000" stroke-width=".42">
<circle cx="209.5" cy="113.5" r=".13"/>
<circle cx="209.5" cy="108.4" r=".13"/>
</g>
<g fill="#000" stroke="#000" stroke-width=".76">
<path d="M44.4 67.8h10.2zM54.6 67.8l2.5 2.5zM107.9 67.8l2.6 2.5zM54.6 67.8h132.1zM189.2 70.3v86.4zM186.7 67.8l2.5 2.5zM194.3 70.3l2.5-2.5zM194.3 70.3v104.1zM196.8 67.8h91.5zM288.3 67.8l2.5 2.5zM290.8 70.3v121.9zM57.1 70.3v22.9z"/>
<path d="M102.9 110.9l2.5 2.6zM39.4 110.9h142.2zM181.6 110.9l2.5 2.6zM44.4 121.1v114.3zM105.4 113.5v20.3zM184.1 113.5v20.3zM110.5 70.3v86.4zM115.6 95.7v78.7zM115.6 174.4l2.5 2.6zM118.1 177h73.6zM191.7 177l2.6-2.6zM44.4 235.4l2.6 2.5z"/>
<path d="M47 237.9h66zM113 237.9l2.6-2.5zM115.6 174.4v61z"/>
</g>
<use href="#words"/>
</svg>
